<?xml version="1.0" encoding="utf-8" standalone="no"?>
<device schemaVersion="1.1">
  <name>STM32F437xx</name>
  <version>1.0</version>
  <description>STM32F437AIH6,STM32F437IGH6,STM32F437IGT6,STM32F437IIH6,STM32F437IIH7,STM32F437IIT6,STM32F437IIT7,STM32F437VGT6,STM32F437VGT7,STM32F437VIT6,STM32F437VIT7,STM32F437ZGT6,STM32F437ZIT6,STM32F437ZIT7</description>
  <addressUnitBits>8</addressUnitBits>
  <width>32</width>
  <size>0x20</size>
  <resetValue>0</resetValue>
  <resetMask>0xFFFFFFFF</resetMask>
  <peripherals>
    <peripheral>
      <name>TIM2</name>
      <baseAddress>0x40000000</baseAddress>
      <register>
        <name>CR1</name>
        <addressOffset>0x0</addressOffset>
        <size>0x20</size>
        <fields>
          <field>
            <name>CEN</name>
            <bitOffset>0</bitOffset>
            <bitWidth>1</bitWidth>
          </field>
          <field>
            <name>UDIS</name>
            <bitOffset>1</bitOffset>
            <bitWidth>1</bitWidth>
          </field>
          <field>
            <name>URS</name>
            <bitOffset>2</bitOffset>
            <bitWidth>1</bitWidth>
          </field>
          <field>
            <name>OPM</name>
            <bitOffset>3</bitOffset>
            <bitWidth>1</bitWidth>
          </field>
          <field>
            <name>DIR</name>
            <bitOffset>4</bitOffset>
            <bitWidth>1</bitWidth>
          </field>
          <field>
            <name>CMS</name>
            <bitOffset>5</bitOffset>
            <bitWidth>2</bitWidth>
          </field>
          <field>
            <name>ARPE</name>
            <bitOffset>7</bitOffset>
            <bitWidth>1</bitWidth>
          </field>
          <field>
            <name>CKD</name>
            <bitOffset>8</bitOffset>
            <bitWidth>2</bitWidth>
          </field>
        </fields>
      </register>
      <register>
        <name>CR2</name>
        <addressOffset>0x4</addressOffset>
        <size>0x20</size>
        <fields>
          <field>
            <name>CCPC</name>
            <bitOffset>0</bitOffset>
            <bitWidth>1</bitWidth>
          </field>
          <field>
            <name>CCUS</name>
            <bitOffset>2</bitOffset>
            <bitWidth>1</bitWidth>
          </field>
          <field>
            <name>CCDS</name>
            <bitOffset>3</bitOffset>
            <bitWidth>1</bitWidth>
          </field>
          <field>
            <name>MMS</name>
            <bitOffset>4</bitOffset>
            <bitWidth>3</bitWidth>
          </field>
          <field>
            <name>TI1S</name>
            <bitOffset>7</bitOffset>
            <bitWidth>1</bitWidth>
          </field>
          <field>
            <name>OIS1</name>
            <bitOffset>8</bitOffset>
            <bitWidth>1</bitWidth>
          </field>
          <field>
            <name>OIS1N</name>
            <bitOffset>9</bitOffset>
            <bitWidth>1</bitWidth>
          </field>
          <field>
            <name>OIS2</name>
            <bitOffset>10</bitOffset>
            <bitWidth>1</bitWidth>
          </field>
          <field>
            <name>OIS2N</name>
            <bitOffset>11</bitOffset>
            <bitWidth>1</bitWidth>
          </field>
          <field>
            <name>OIS3</name>
            <bitOffset>12</bitOffset>
            <bitWidth>1</bitWidth>
          </field>
          <field>
            <name>OIS3N</name>
            <bitOffset>13</bitOffset>
            <bitWidth>1</bitWidth>
          </field>
          <field>
            <name>OIS4</name>
            <bitOffset>14</bitOffset>
            <bitWidth>1</bitWidth>
          </field>
        </fields>
      </register>
      <register>
        <name>SMCR</name>
        <addressOffset>0x8</addressOffset>
        <size>0x20</size>
        <fields>
          <field>
            <name>SMS</name>
            <bitOffset>0</bitOffset>
            <bitWidth>3</bitWidth>
          </field>
          <field>
            <name>TS</name>
            <bitOffset>4</bitOffset>
            <bitWidth>3</bitWidth>
          </field>
          <field>
            <name>MSM</name>
            <bitOffset>7</bitOffset>
            <bitWidth>1</bitWidth>
          </field>
          <field>
            <name>ETF</name>
            <bitOffset>8</bitOffset>
            <bitWidth>4</bitWidth>
          </field>
          <field>
            <name>ETPS</name>
            <bitOffset>12</bitOffset>
            <bitWidth>2</bitWidth>
          </field>
          <field>
            <name>ECE</name>
            <bitOffset>14</bitOffset>
            <bitWidth>1</bitWidth>
          </field>
          <field>
            <name>ETP</name>
            <bitOffset>15</bitOffset>
            <bitWidth>1</bitWidth>
          </field>
        </fields>
      </register>
      <register>
        <name>DIER</name>
        <addressOffset>0xc</addressOffset>
        <size>0x20</size>
        <fields>
          <field>
            <name>UIE</name>
            <bitOffset>0</bitOffset>
            <bitWidth>1</bitWidth>
          </field>
          <field>
            <name>CC1IE</name>
            <bitOffset>1</bitOffset>
            <bitWidth>1</bitWidth>
          </field>
          <field>
            <name>CC2IE</name>
            <bitOffset>2</bitOffset>
            <bitWidth>1</bitWidth>
          </field>
          <field>
            <name>CC3IE</name>
            <bitOffset>3</bitOffset>
            <bitWidth>1</bitWidth>
          </field>
          <field>
            <name>CC4IE</name>
            <bitOffset>4</bitOffset>
            <bitWidth>1</bitWidth>
          </field>
          <field>
            <name>COMIE</name>
            <bitOffset>5</bitOffset>
            <bitWidth>1</bitWidth>
          </field>
          <field>
            <name>TIE</name>
            <bitOffset>6</bitOffset>
            <bitWidth>1</bitWidth>
          </field>
          <field>
            <name>BIE</name>
            <bitOffset>7</bitOffset>
            <bitWidth>1</bitWidth>
          </field>
          <field>
            <name>UDE</name>
            <bitOffset>8</bitOffset>
            <bitWidth>1</bitWidth>
          </field>
          <field>
            <name>CC1DE</name>
            <bitOffset>9</bitOffset>
            <bitWidth>1</bitWidth>
          </field>
          <field>
            <name>CC2DE</name>
            <bitOffset>10</bitOffset>
            <bitWidth>1</bitWidth>
          </field>
          <field>
            <name>CC3DE</name>
            <bitOffset>11</bitOffset>
            <bitWidth>1</bitWidth>
          </field>
          <field>
            <name>CC4DE</name>
            <bitOffset>12</bitOffset>
            <bitWidth>1</bitWidth>
          </field>
          <field>
            <name>COMDE</name>
            <bitOffset>13</bitOffset>
            <bitWidth>1</bitWidth>
          </field>
          <field>
            <name>TDE</name>
            <bitOffset>14</bitOffset>
            <bitWidth>1</bitWidth>
          </field>
        </fields>
      </register>
      <register>
        <name>SR</name>
        <addressOffset>0x10</addressOffset>
        <size>0x20</size>
        <fields>
          <field>
            <name>UIF</name>
            <bitOffset>0</bitOffset>
            <bitWidth>1</bitWidth>
          </field>
          <field>
            <name>CC1IF</name>
            <bitOffset>1</bitOffset>
            <bitWidth>1</bitWidth>
          </field>
          <field>
            <name>CC2IF</name>
            <bitOffset>2</bitOffset>
            <bitWidth>1</bitWidth>
          </field>
          <field>
            <name>CC3IF</name>
            <bitOffset>3</bitOffset>
            <bitWidth>1</bitWidth>
          </field>
          <field>
            <name>CC4IF</name>
            <bitOffset>4</bitOffset>
            <bitWidth>1</bitWidth>
          </field>
          <field>
            <name>COMIF</name>
            <bitOffset>5</bitOffset>
            <bitWidth>1</bitWidth>
          </field>
          <field>
            <name>TIF</name>
            <bitOffset>6</bitOffset>
            <bitWidth>1</bitWidth>
          </field>
          <field>
            <name>BIF</name>
            <bitOffset>7</bitOffset>
            <bitWidth>1</bitWidth>
          </field>
          <field>
            <name>CC1OF</name>
            <bitOffset>9</bitOffset>
            <bitWidth>1</bitWidth>
          </field>
          <field>
            <name>CC2OF</name>
            <bitOffset>10</bitOffset>
            <bitWidth>1</bitWidth>
          </field>
          <field>
            <name>CC3OF</name>
            <bitOffset>11</bitOffset>
            <bitWidth>1</bitWidth>
          </field>
          <field>
            <name>CC4OF</name>
            <bitOffset>12</bitOffset>
            <bitWidth>1</bitWidth>
          </field>
        </fields>
      </register>
      <register>
        <name>EGR</name>
        <addressOffset>0x14</addressOffset>
        <size>0x20</size>
        <fields>
          <field>
            <name>UG</name>
            <bitOffset>0</bitOffset>
            <bitWidth>1</bitWidth>
          </field>
          <field>
            <name>CC1G</name>
            <bitOffset>1</bitOffset>
            <bitWidth>1</bitWidth>
          </field>
          <field>
            <name>CC2G</name>
            <bitOffset>2</bitOffset>
            <bitWidth>1</bitWidth>
          </field>
          <field>
            <name>CC3G</name>
            <bitOffset>3</bitOffset>
            <bitWidth>1</bitWidth>
          </field>
          <field>
            <name>CC4G</name>
            <bitOffset>4</bitOffset>
            <bitWidth>1</bitWidth>
          </field>
          <field>
            <name>COMG</name>
            <bitOffset>5</bitOffset>
            <bitWidth>1</bitWidth>
          </field>
          <field>
            <name>TG</name>
            <bitOffset>6</bitOffset>
            <bitWidth>1</bitWidth>
          </field>
          <field>
            <name>BG</name>
            <bitOffset>7</bitOffset>
            <bitWidth>1</bitWidth>
          </field>
        </fields>
      </register>
      <register>
        <name>CCMR1</name>
        <addressOffset>0x18</addressOffset>
        <size>0x20</size>
        <fields>
          <field>
            <name>CC1S</name>
            <bitOffset>0</bitOffset>
            <bitWidth>2</bitWidth>
          </field>
          <field>
            <name>OC1FE</name>
            <bitOffset>2</bitOffset>
            <bitWidth>1</bitWidth>
          </field>
          <field>
            <name>OC1PE</name>
            <bitOffset>3</bitOffset>
            <bitWidth>1</bitWidth>
          </field>
          <field>
            <name>OC1M</name>
            <bitOffset>4</bitOffset>
            <bitWidth>3</bitWidth>
          </field>
          <field>
            <name>OC1CE</name>
            <bitOffset>7</bitOffset>
            <bitWidth>1</bitWidth>
          </field>
          <field>
            <name>CC2S</name>
            <bitOffset>8</bitOffset>
            <bitWidth>2</bitWidth>
          </field>
          <field>
            <name>OC2FE</name>
            <bitOffset>10</bitOffset>
            <bitWidth>1</bitWidth>
          </field>
          <field>
            <name>OC2PE</name>
            <bitOffset>11</bitOffset>
            <bitWidth>1</bitWidth>
          </field>
          <field>
            <name>OC2M</name>
            <bitOffset>12</bitOffset>
            <bitWidth>3</bitWidth>
          </field>
          <field>
            <name>OC2CE</name>
            <bitOffset>15</bitOffset>
            <bitWidth>1</bitWidth>
          </field>
        </fields>
      </register>
      <register>
        <name>CCMR2</name>
        <addressOffset>0x1c</addressOffset>
        <size>0x20</size>
        <fields>
          <field>
            <name>CC3S</name>
            <bitOffset>0</bitOffset>
            <bitWidth>2</bitWidth>
          </field>
          <field>
            <name>OC3FE</name>
            <bitOffset>2</bitOffset>
            <bitWidth>1</bitWidth>
          </field>
          <field>
            <name>OC3PE</name>
            <bitOffset>3</bitOffset>
            <bitWidth>1</bitWidth>
          </field>
          <field>
            <name>OC3M</name>
            <bitOffset>4</bitOffset>
            <bitWidth>3</bitWidth>
          </field>
          <field>
            <name>OC3CE</name>
            <bitOffset>7</bitOffset>
            <bitWidth>1</bitWidth>
          </field>
          <field>
            <name>CC4S</name>
            <bitOffset>8</bitOffset>
            <bitWidth>2</bitWidth>
          </field>
          <field>
            <name>OC4FE</name>
            <bitOffset>10</bitOffset>
            <bitWidth>1</bitWidth>
          </field>
          <field>
            <name>OC4PE</name>
            <bitOffset>11</bitOffset>
            <bitWidth>1</bitWidth>
          </field>
          <field>
            <name>OC4M</name>
            <bitOffset>12</bitOffset>
            <bitWidth>3</bitWidth>
          </field>
          <field>
            <name>OC4CE</name>
            <bitOffset>15</bitOffset>
            <bitWidth>1</bitWidth>
          </field>
        </fields>
      </register>
      <register>
        <name>CCER</name>
        <addressOffset>0x20</addressOffset>
        <size>0x20</size>
        <fields>
          <field>
            <name>CC1E</name>
            <bitOffset>0</bitOffset>
            <bitWidth>1</bitWidth>
          </field>
          <field>
            <name>CC1P</name>
            <bitOffset>1</bitOffset>
            <bitWidth>1</bitWidth>
          </field>
          <field>
            <name>CC1NE</name>
            <bitOffset>2</bitOffset>
            <bitWidth>1</bitWidth>
          </field>
          <field>
            <name>CC1NP</name>
            <bitOffset>3</bitOffset>
            <bitWidth>1</bitWidth>
          </field>
          <field>
            <name>CC2E</name>
            <bitOffset>4</bitOffset>
            <bitWidth>1</bitWidth>
          </field>
          <field>
            <name>CC2P</name>
            <bitOffset>5</bitOffset>
            <bitWidth>1</bitWidth>
          </field>
          <field>
            <name>CC2NE</name>
            <bitOffset>6</bitOffset>
            <bitWidth>1</bitWidth>
          </field>
          <field>
            <name>CC2NP</name>
            <bitOffset>7</bitOffset>
            <bitWidth>1</bitWidth>
          </field>
          <field>
            <name>CC3E</name>
            <bitOffset>8</bitOffset>
            <bitWidth>1</bitWidth>
          </field>
          <field>
            <name>CC3P</name>
            <bitOffset>9</bitOffset>
            <bitWidth>1</bitWidth>
          </field>
          <field>
            <name>CC3NE</name>
            <bitOffset>10</bitOffset>
            <bitWidth>1</bitWidth>
          </field>
          <field>
            <name>CC3NP</name>
            <bitOffset>11</bitOffset>
            <bitWidth>1</bitWidth>
          </field>
          <field>
            <name>CC4E</name>
            <bitOffset>12</bitOffset>
            <bitWidth>1</bitWidth>
          </field>
          <field>
            <name>CC4P</name>
            <bitOffset>13</bitOffset>
            <bitWidth>1</bitWidth>
          </field>
          <field>
            <name>CC4NP</name>
            <bitOffset>15</bitOffset>
            <bitWidth>1</bitWidth>
          </field>
        </fields>
      </register>
      <register>
        <name>CNT</name>
        <addressOffset>0x24</addressOffset>
        <size>0x20</size>
        <fields>
          <field>
            <name>CNT</name>
            <bitOffset>0</bitOffset>
            <bitWidth>32</bitWidth>
          </field>
        </fields>
      </register>
      <register>
        <name>PSC</name>
        <addressOffset>0x28</addressOffset>
        <size>0x20</size>
        <fields>
          <field>
            <name>PSC</name>
            <bitOffset>0</bitOffset>
            <bitWidth>16</bitWidth>
          </field>
        </fields>
      </register>
      <register>
        <name>ARR</name>
        <addressOffset>0x2c</addressOffset>
        <size>0x20</size>
        <fields>
          <field>
            <name>ARR</name>
            <bitOffset>0</bitOffset>
            <bitWidth>32</bitWidth>
          </field>
        </fields>
      </register>
      <register>
        <name>RCR</name>
        <addressOffset>0x30</addressOffset>
        <size>0x20</size>
        <fields>
          <field>
            <name>REP</name>
            <bitOffset>0</bitOffset>
            <bitWidth>8</bitWidth>
          </field>
        </fields>
      </register>
      <register>
        <name>CCR1</name>
        <addressOffset>0x34</addressOffset>
        <size>0x20</size>
        <fields>
          <field>
            <name>CCR1</name>
            <bitOffset>0</bitOffset>
            <bitWidth>16</bitWidth>
          </field>
        </fields>
      </register>
      <register>
        <name>CCR2</name>
        <addressOffset>0x38</addressOffset>
        <size>0x20</size>
        <fields>
          <field>
            <name>CCR2</name>
            <bitOffset>0</bitOffset>
            <bitWidth>16</bitWidth>
          </field>
        </fields>
      </register>
      <register>
        <name>CCR3</name>
        <addressOffset>0x3c</addressOffset>
        <size>0x20</size>
        <fields>
          <field>
            <name>CCR3</name>
            <bitOffset>0</bitOffset>
            <bitWidth>16</bitWidth>
          </field>
        </fields>
      </register>
      <register>
        <name>CCR4</name>
        <addressOffset>0x40</addressOffset>
        <size>0x20</size>
        <fields>
          <field>
            <name>CCR4</name>
            <bitOffset>0</bitOffset>
            <bitWidth>16</bitWidth>
          </field>
        </fields>
      </register>
      <register>
        <name>BDTR</name>
        <addressOffset>0x44</addressOffset>
        <size>0x20</size>
        <fields>
          <field>
            <name>DTG</name>
            <bitOffset>0</bitOffset>
            <bitWidth>8</bitWidth>
          </field>
          <field>
            <name>LOCK</name>
            <bitOffset>8</bitOffset>
            <bitWidth>2</bitWidth>
          </field>
          <field>
            <name>OSSI</name>
            <bitOffset>10</bitOffset>
            <bitWidth>1</bitWidth>
          </field>
          <field>
            <name>OSSR</name>
            <bitOffset>11</bitOffset>
            <bitWidth>1</bitWidth>
          </field>
          <field>
            <name>BKE</name>
            <bitOffset>12</bitOffset>
            <bitWidth>1</bitWidth>
          </field>
          <field>
            <name>BKP</name>
            <bitOffset>13</bitOffset>
            <bitWidth>1</bitWidth>
          </field>
          <field>
            <name>AOE</name>
            <bitOffset>14</bitOffset>
            <bitWidth>1</bitWidth>
          </field>
          <field>
            <name>MOE</name>
            <bitOffset>15</bitOffset>
            <bitWidth>1</bitWidth>
          </field>
        </fields>
      </register>
      <register>
        <name>DCR</name>
        <addressOffset>0x48</addressOffset>
        <size>0x20</size>
        <fields>
          <field>
            <name>DBA</name>
            <bitOffset>0</bitOffset>
            <bitWidth>5</bitWidth>
          </field>
          <field>
            <name>DBL</name>
            <bitOffset>8</bitOffset>
            <bitWidth>5</bitWidth>
          </field>
        </fields>
      </register>
      <register>
        <name>DMAR</name>
        <addressOffset>0x4c</addressOffset>
        <size>0x20</size>
        <fields>
          <field>
            <name>DMAB</name>
            <bitOffset>0</bitOffset>
            <bitWidth>16</bitWidth>
          </field>
        </fields>
      </register>
      <register>
        <name>OR</name>
        <addressOffset>0x50</addressOffset>
        <size>0x20</size>
        <fields>
          <field>
            <name>TI1_RMP</name>
            <bitOffset>0</bitOffset>
            <bitWidth>2</bitWidth>
          </field>
          <field>
            <name>TI4_RMP</name>
            <bitOffset>6</bitOffset>
            <bitWidth>2</bitWidth>
          </field>
          <field>
            <name>ITR1_RMP</name>
            <bitOffset>10</bitOffset>
            <bitWidth>2</bitWidth>
          </field>
        </fields>
      </register>
    </peripheral>
    <peripheral>
      <name>TIM3</name>
      <baseAddress>0x40000400</baseAddress>
      <register>
        <name>CR1</name>
        <addressOffset>0x0</addressOffset>
        <size>0x20</size>
        <fields>
          <field>
            <name>CEN</name>
            <bitOffset>0</bitOffset>
            <bitWidth>1</bitWidth>
          </field>
          <field>
            <name>UDIS</name>
            <bitOffset>1</bitOffset>
            <bitWidth>1</bitWidth>
          </field>
          <field>
            <name>URS</name>
            <bitOffset>2</bitOffset>
            <bitWidth>1</bitWidth>
          </field>
          <field>
            <name>OPM</name>
            <bitOffset>3</bitOffset>
            <bitWidth>1</bitWidth>
          </field>
          <field>
            <name>DIR</name>
            <bitOffset>4</bitOffset>
            <bitWidth>1</bitWidth>
          </field>
          <field>
            <name>CMS</name>
            <bitOffset>5</bitOffset>
            <bitWidth>2</bitWidth>
          </field>
          <field>
            <name>ARPE</name>
            <bitOffset>7</bitOffset>
            <bitWidth>1</bitWidth>
          </field>
          <field>
            <name>CKD</name>
            <bitOffset>8</bitOffset>
            <bitWidth>2</bitWidth>
          </field>
        </fields>
      </register>
      <register>
        <name>CR2</name>
        <addressOffset>0x4</addressOffset>
        <size>0x20</size>
        <fields>
          <field>
            <name>CCPC</name>
            <bitOffset>0</bitOffset>
            <bitWidth>1</bitWidth>
          </field>
          <field>
            <name>CCUS</name>
            <bitOffset>2</bitOffset>
            <bitWidth>1</bitWidth>
          </field>
          <field>
            <name>CCDS</name>
            <bitOffset>3</bitOffset>
            <bitWidth>1</bitWidth>
          </field>
          <field>
            <name>MMS</name>
            <bitOffset>4</bitOffset>
            <bitWidth>3</bitWidth>
          </field>
          <field>
            <name>TI1S</name>
            <bitOffset>7</bitOffset>
            <bitWidth>1</bitWidth>
          </field>
          <field>
            <name>OIS1</name>
            <bitOffset>8</bitOffset>
            <bitWidth>1</bitWidth>
          </field>
          <field>
            <name>OIS1N</name>
            <bitOffset>9</bitOffset>
            <bitWidth>1</bitWidth>
          </field>
          <field>
            <name>OIS2</name>
            <bitOffset>10</bitOffset>
            <bitWidth>1</bitWidth>
          </field>
          <field>
            <name>OIS2N</name>
            <bitOffset>11</bitOffset>
            <bitWidth>1</bitWidth>
          </field>
          <field>
            <name>OIS3</name>
            <bitOffset>12</bitOffset>
            <bitWidth>1</bitWidth>
          </field>
          <field>
            <name>OIS3N</name>
            <bitOffset>13</bitOffset>
            <bitWidth>1</bitWidth>
          </field>
          <field>
            <name>OIS4</name>
            <bitOffset>14</bitOffset>
            <bitWidth>1</bitWidth>
          </field>
        </fields>
      </register>
      <register>
        <name>SMCR</name>
        <addressOffset>0x8</addressOffset>
        <size>0x20</size>
        <fields>
          <field>
            <name>SMS</name>
            <bitOffset>0</bitOffset>
            <bitWidth>3</bitWidth>
          </field>
          <field>
            <name>TS</name>
            <bitOffset>4</bitOffset>
            <bitWidth>3</bitWidth>
          </field>
          <field>
            <name>MSM</name>
            <bitOffset>7</bitOffset>
            <bitWidth>1</bitWidth>
          </field>
          <field>
            <name>ETF</name>
            <bitOffset>8</bitOffset>
            <bitWidth>4</bitWidth>
          </field>
          <field>
            <name>ETPS</name>
            <bitOffset>12</bitOffset>
            <bitWidth>2</bitWidth>
          </field>
          <field>
            <name>ECE</name>
            <bitOffset>14</bitOffset>
            <bitWidth>1</bitWidth>
          </field>
          <field>
            <name>ETP</name>
            <bitOffset>15</bitOffset>
            <bitWidth>1</bitWidth>
          </field>
        </fields>
      </register>
      <register>
        <name>DIER</name>
        <addressOffset>0xc</addressOffset>
        <size>0x20</size>
        <fields>
          <field>
            <name>UIE</name>
            <bitOffset>0</bitOffset>
            <bitWidth>1</bitWidth>
          </field>
          <field>
            <name>CC1IE</name>
            <bitOffset>1</bitOffset>
            <bitWidth>1</bitWidth>
          </field>
          <field>
            <name>CC2IE</name>
            <bitOffset>2</bitOffset>
            <bitWidth>1</bitWidth>
          </field>
          <field>
            <name>CC3IE</name>
            <bitOffset>3</bitOffset>
            <bitWidth>1</bitWidth>
          </field>
          <field>
            <name>CC4IE</name>
            <bitOffset>4</bitOffset>
            <bitWidth>1</bitWidth>
          </field>
          <field>
            <name>COMIE</name>
            <bitOffset>5</bitOffset>
            <bitWidth>1</bitWidth>
          </field>
          <field>
            <name>TIE</name>
            <bitOffset>6</bitOffset>
            <bitWidth>1</bitWidth>
          </field>
          <field>
            <name>BIE</name>
            <bitOffset>7</bitOffset>
            <bitWidth>1</bitWidth>
          </field>
          <field>
            <name>UDE</name>
            <bitOffset>8</bitOffset>
            <bitWidth>1</bitWidth>
          </field>
          <field>
            <name>CC1DE</name>
            <bitOffset>9</bitOffset>
            <bitWidth>1</bitWidth>
          </field>
          <field>
            <name>CC2DE</name>
            <bitOffset>10</bitOffset>
            <bitWidth>1</bitWidth>
          </field>
          <field>
            <name>CC3DE</name>
            <bitOffset>11</bitOffset>
            <bitWidth>1</bitWidth>
          </field>
          <field>
            <name>CC4DE</name>
            <bitOffset>12</bitOffset>
            <bitWidth>1</bitWidth>
          </field>
          <field>
            <name>COMDE</name>
            <bitOffset>13</bitOffset>
            <bitWidth>1</bitWidth>
          </field>
          <field>
            <name>TDE</name>
            <bitOffset>14</bitOffset>
            <bitWidth>1</bitWidth>
          </field>
        </fields>
      </register>
      <register>
        <name>SR</name>
        <addressOffset>0x10</addressOffset>
        <size>0x20</size>
        <fields>
          <field>
            <name>UIF</name>
            <bitOffset>0</bitOffset>
            <bitWidth>1</bitWidth>
          </field>
          <field>
            <name>CC1IF</name>
            <bitOffset>1</bitOffset>
            <bitWidth>1</bitWidth>
          </field>
          <field>
            <name>CC2IF</name>
            <bitOffset>2</bitOffset>
            <bitWidth>1</bitWidth>
          </field>
          <field>
            <name>CC3IF</name>
            <bitOffset>3</bitOffset>
            <bitWidth>1</bitWidth>
          </field>
          <field>
            <name>CC4IF</name>
            <bitOffset>4</bitOffset>
            <bitWidth>1</bitWidth>
          </field>
          <field>
            <name>COMIF</name>
            <bitOffset>5</bitOffset>
            <bitWidth>1</bitWidth>
          </field>
          <field>
            <name>TIF</name>
            <bitOffset>6</bitOffset>
            <bitWidth>1</bitWidth>
          </field>
          <field>
            <name>BIF</name>
            <bitOffset>7</bitOffset>
            <bitWidth>1</bitWidth>
          </field>
          <field>
            <name>CC1OF</name>
            <bitOffset>9</bitOffset>
            <bitWidth>1</bitWidth>
          </field>
          <field>
            <name>CC2OF</name>
            <bitOffset>10</bitOffset>
            <bitWidth>1</bitWidth>
          </field>
          <field>
            <name>CC3OF</name>
            <bitOffset>11</bitOffset>
            <bitWidth>1</bitWidth>
          </field>
          <field>
            <name>CC4OF</name>
            <bitOffset>12</bitOffset>
            <bitWidth>1</bitWidth>
          </field>
        </fields>
      </register>
      <register>
        <name>EGR</name>
        <addressOffset>0x14</addressOffset>
        <size>0x20</size>
        <fields>
          <field>
            <name>UG</name>
            <bitOffset>0</bitOffset>
            <bitWidth>1</bitWidth>
          </field>
          <field>
            <name>CC1G</name>
            <bitOffset>1</bitOffset>
            <bitWidth>1</bitWidth>
          </field>
          <field>
            <name>CC2G</name>
            <bitOffset>2</bitOffset>
            <bitWidth>1</bitWidth>
          </field>
          <field>
            <name>CC3G</name>
            <bitOffset>3</bitOffset>
            <bitWidth>1</bitWidth>
          </field>
          <field>
            <name>CC4G</name>
            <bitOffset>4</bitOffset>
            <bitWidth>1</bitWidth>
          </field>
          <field>
            <name>COMG</name>
            <bitOffset>5</bitOffset>
            <bitWidth>1</bitWidth>
          </field>
          <field>
            <name>TG</name>
            <bitOffset>6</bitOffset>
            <bitWidth>1</bitWidth>
          </field>
          <field>
            <name>BG</name>
            <bitOffset>7</bitOffset>
            <bitWidth>1</bitWidth>
          </field>
        </fields>
      </register>
      <register>
        <name>CCMR1</name>
        <addressOffset>0x18</addressOffset>
        <size>0x20</size>
        <fields>
          <field>
            <name>CC1S</name>
            <bitOffset>0</bitOffset>
            <bitWidth>2</bitWidth>
          </field>
          <field>
            <name>OC1FE</name>
            <bitOffset>2</bitOffset>
            <bitWidth>1</bitWidth>
          </field>
          <field>
            <name>OC1PE</name>
            <bitOffset>3</bitOffset>
            <bitWidth>1</bitWidth>
          </field>
          <field>
            <name>OC1M</name>
            <bitOffset>4</bitOffset>
            <bitWidth>3</bitWidth>
          </field>
          <field>
            <name>OC1CE</name>
            <bitOffset>7</bitOffset>
            <bitWidth>1</bitWidth>
          </field>
          <field>
            <name>CC2S</name>
            <bitOffset>8</bitOffset>
            <bitWidth>2</bitWidth>
          </field>
          <field>
            <name>OC2FE</name>
            <bitOffset>10</bitOffset>
            <bitWidth>1</bitWidth>
          </field>
          <field>
            <name>OC2PE</name>
            <bitOffset>11</bitOffset>
            <bitWidth>1</bitWidth>
          </field>
          <field>
            <name>OC2M</name>
            <bitOffset>12</bitOffset>
            <bitWidth>3</bitWidth>
          </field>
          <field>
            <name>OC2CE</name>
            <bitOffset>15</bitOffset>
            <bitWidth>1</bitWidth>
          </field>
        </fields>
      </register>
      <register>
        <name>CCMR2</name>
        <addressOffset>0x1c</addressOffset>
        <size>0x20</size>
        <fields>
          <field>
            <name>CC3S</name>
            <bitOffset>0</bitOffset>
            <bitWidth>2</bitWidth>
          </field>
          <field>
            <name>OC3FE</name>
            <bitOffset>2</bitOffset>
            <bitWidth>1</bitWidth>
          </field>
          <field>
            <name>OC3PE</name>
            <bitOffset>3</bitOffset>
            <bitWidth>1</bitWidth>
          </field>
          <field>
            <name>OC3M</name>
            <bitOffset>4</bitOffset>
            <bitWidth>3</bitWidth>
          </field>
          <field>
            <name>OC3CE</name>
            <bitOffset>7</bitOffset>
            <bitWidth>1</bitWidth>
          </field>
          <field>
            <name>CC4S</name>
            <bitOffset>8</bitOffset>
            <bitWidth>2</bitWidth>
          </field>
          <field>
            <name>OC4FE</name>
            <bitOffset>10</bitOffset>
            <bitWidth>1</bitWidth>
          </field>
          <field>
            <name>OC4PE</name>
            <bitOffset>11</bitOffset>
            <bitWidth>1</bitWidth>
          </field>
          <field>
            <name>OC4M</name>
            <bitOffset>12</bitOffset>
            <bitWidth>3</bitWidth>
          </field>
          <field>
            <name>OC4CE</name>
            <bitOffset>15</bitOffset>
            <bitWidth>1</bitWidth>
          </field>
        </fields>
      </register>
      <register>
        <name>CCER</name>
        <addressOffset>0x20</addressOffset>
        <size>0x20</size>
        <fields>
          <field>
            <name>CC1E</name>
            <bitOffset>0</bitOffset>
            <bitWidth>1</bitWidth>
          </field>
          <field>
            <name>CC1P</name>
            <bitOffset>1</bitOffset>
            <bitWidth>1</bitWidth>
          </field>
          <field>
            <name>CC1NE</name>
            <bitOffset>2</bitOffset>
            <bitWidth>1</bitWidth>
          </field>
          <field>
            <name>CC1NP</name>
            <bitOffset>3</bitOffset>
            <bitWidth>1</bitWidth>
          </field>
          <field>
            <name>CC2E</name>
            <bitOffset>4</bitOffset>
            <bitWidth>1</bitWidth>
          </field>
          <field>
            <name>CC2P</name>
            <bitOffset>5</bitOffset>
            <bitWidth>1</bitWidth>
          </field>
          <field>
            <name>CC2NE</name>
            <bitOffset>6</bitOffset>
            <bitWidth>1</bitWidth>
          </field>
          <field>
            <name>CC2NP</name>
            <bitOffset>7</bitOffset>
            <bitWidth>1</bitWidth>
          </field>
          <field>
            <name>CC3E</name>
            <bitOffset>8</bitOffset>
            <bitWidth>1</bitWidth>
          </field>
          <field>
            <name>CC3P</name>
            <bitOffset>9</bitOffset>
            <bitWidth>1</bitWidth>
          </field>
          <field>
            <name>CC3NE</name>
            <bitOffset>10</bitOffset>
            <bitWidth>1</bitWidth>
          </field>
          <field>
            <name>CC3NP</name>
            <bitOffset>11</bitOffset>
            <bitWidth>1</bitWidth>
          </field>
          <field>
            <name>CC4E</name>
            <bitOffset>12</bitOffset>
            <bitWidth>1</bitWidth>
          </field>
          <field>
            <name>CC4P</name>
            <bitOffset>13</bitOffset>
            <bitWidth>1</bitWidth>
          </field>
          <field>
            <name>CC4NP</name>
            <bitOffset>15</bitOffset>
            <bitWidth>1</bitWidth>
          </field>
        </fields>
      </register>
      <register>
        <name>CNT</name>
        <addressOffset>0x24</addressOffset>
        <size>0x20</size>
        <fields>
          <field>
            <name>CNT</name>
            <bitOffset>0</bitOffset>
            <bitWidth>32</bitWidth>
          </field>
        </fields>
      </register>
      <register>
        <name>PSC</name>
        <addressOffset>0x28</addressOffset>
        <size>0x20</size>
        <fields>
          <field>
            <name>PSC</name>
            <bitOffset>0</bitOffset>
            <bitWidth>16</bitWidth>
          </field>
        </fields>
      </register>
      <register>
        <name>ARR</name>
        <addressOffset>0x2c</addressOffset>
        <size>0x20</size>
        <fields>
          <field>
            <name>ARR</name>
            <bitOffset>0</bitOffset>
            <bitWidth>32</bitWidth>
          </field>
        </fields>
      </register>
      <register>
        <name>RCR</name>
        <addressOffset>0x30</addressOffset>
        <size>0x20</size>
        <fields>
          <field>
            <name>REP</name>
            <bitOffset>0</bitOffset>
            <bitWidth>8</bitWidth>
          </field>
        </fields>
      </register>
      <register>
        <name>CCR1</name>
        <addressOffset>0x34</addressOffset>
        <size>0x20</size>
        <fields>
          <field>
            <name>CCR1</name>
            <bitOffset>0</bitOffset>
            <bitWidth>16</bitWidth>
          </field>
        </fields>
      </register>
      <register>
        <name>CCR2</name>
        <addressOffset>0x38</addressOffset>
        <size>0x20</size>
        <fields>
          <field>
            <name>CCR2</name>
            <bitOffset>0</bitOffset>
            <bitWidth>16</bitWidth>
          </field>
        </fields>
      </register>
      <register>
        <name>CCR3</name>
        <addressOffset>0x3c</addressOffset>
        <size>0x20</size>
        <fields>
          <field>
            <name>CCR3</name>
            <bitOffset>0</bitOffset>
            <bitWidth>16</bitWidth>
          </field>
        </fields>
      </register>
      <register>
        <name>CCR4</name>
        <addressOffset>0x40</addressOffset>
        <size>0x20</size>
        <fields>
          <field>
            <name>CCR4</name>
            <bitOffset>0</bitOffset>
            <bitWidth>16</bitWidth>
          </field>
        </fields>
      </register>
      <register>
        <name>BDTR</name>
        <addressOffset>0x44</addressOffset>
        <size>0x20</size>
        <fields>
          <field>
            <name>DTG</name>
            <bitOffset>0</bitOffset>
            <bitWidth>8</bitWidth>
          </field>
          <field>
            <name>LOCK</name>
            <bitOffset>8</bitOffset>
            <bitWidth>2</bitWidth>
          </field>
          <field>
            <name>OSSI</name>
            <bitOffset>10</bitOffset>
            <bitWidth>1</bitWidth>
          </field>
          <field>
            <name>OSSR</name>
            <bitOffset>11</bitOffset>
            <bitWidth>1</bitWidth>
          </field>
          <field>
            <name>BKE</name>
            <bitOffset>12</bitOffset>
            <bitWidth>1</bitWidth>
          </field>
          <field>
            <name>BKP</name>
            <bitOffset>13</bitOffset>
            <bitWidth>1</bitWidth>
          </field>
          <field>
            <name>AOE</name>
            <bitOffset>14</bitOffset>
            <bitWidth>1</bitWidth>
          </field>
          <field>
            <name>MOE</name>
            <bitOffset>15</bitOffset>
            <bitWidth>1</bitWidth>
          </field>
        </fields>
      </register>
      <register>
        <name>DCR</name>
        <addressOffset>0x48</addressOffset>
        <size>0x20</size>
        <fields>
          <field>
            <name>DBA</name>
            <bitOffset>0</bitOffset>
            <bitWidth>5</bitWidth>
          </field>
          <field>
            <name>DBL</name>
            <bitOffset>8</bitOffset>
            <bitWidth>5</bitWidth>
          </field>
        </fields>
      </register>
      <register>
        <name>DMAR</name>
        <addressOffset>0x4c</addressOffset>
        <size>0x20</size>
        <fields>
          <field>
            <name>DMAB</name>
            <bitOffset>0</bitOffset>
            <bitWidth>16</bitWidth>
          </field>
        </fields>
      </register>
      <register>
        <name>OR</name>
        <addressOffset>0x50</addressOffset>
        <size>0x20</size>
        <fields>
          <field>
            <name>TI1_RMP</name>
            <bitOffset>0</bitOffset>
            <bitWidth>2</bitWidth>
          </field>
          <field>
            <name>TI4_RMP</name>
            <bitOffset>6</bitOffset>
            <bitWidth>2</bitWidth>
          </field>
          <field>
            <name>ITR1_RMP</name>
            <bitOffset>10</bitOffset>
            <bitWidth>2</bitWidth>
          </field>
        </fields>
      </register>
    </peripheral>
    <peripheral>
      <name>TIM4</name>
      <baseAddress>0x40000800</baseAddress>
      <register>
        <name>CR1</name>
        <addressOffset>0x0</addressOffset>
        <size>0x20</size>
        <fields>
          <field>
            <name>CEN</name>
            <bitOffset>0</bitOffset>
            <bitWidth>1</bitWidth>
          </field>
          <field>
            <name>UDIS</name>
            <bitOffset>1</bitOffset>
            <bitWidth>1</bitWidth>
          </field>
          <field>
            <name>URS</name>
            <bitOffset>2</bitOffset>
            <bitWidth>1</bitWidth>
          </field>
          <field>
            <name>OPM</name>
            <bitOffset>3</bitOffset>
            <bitWidth>1</bitWidth>
          </field>
          <field>
            <name>DIR</name>
            <bitOffset>4</bitOffset>
            <bitWidth>1</bitWidth>
          </field>
          <field>
            <name>CMS</name>
            <bitOffset>5</bitOffset>
            <bitWidth>2</bitWidth>
          </field>
          <field>
            <name>ARPE</name>
            <bitOffset>7</bitOffset>
            <bitWidth>1</bitWidth>
          </field>
          <field>
            <name>CKD</name>
            <bitOffset>8</bitOffset>
            <bitWidth>2</bitWidth>
          </field>
        </fields>
      </register>
      <register>
        <name>CR2</name>
        <addressOffset>0x4</addressOffset>
        <size>0x20</size>
        <fields>
          <field>
            <name>CCPC</name>
            <bitOffset>0</bitOffset>
            <bitWidth>1</bitWidth>
          </field>
          <field>
            <name>CCUS</name>
            <bitOffset>2</bitOffset>
            <bitWidth>1</bitWidth>
          </field>
          <field>
            <name>CCDS</name>
            <bitOffset>3</bitOffset>
            <bitWidth>1</bitWidth>
          </field>
          <field>
            <name>MMS</name>
            <bitOffset>4</bitOffset>
            <bitWidth>3</bitWidth>
          </field>
          <field>
            <name>TI1S</name>
            <bitOffset>7</bitOffset>
            <bitWidth>1</bitWidth>
          </field>
          <field>
            <name>OIS1</name>
            <bitOffset>8</bitOffset>
            <bitWidth>1</bitWidth>
          </field>
          <field>
            <name>OIS1N</name>
            <bitOffset>9</bitOffset>
            <bitWidth>1</bitWidth>
          </field>
          <field>
            <name>OIS2</name>
            <bitOffset>10</bitOffset>
            <bitWidth>1</bitWidth>
          </field>
          <field>
            <name>OIS2N</name>
            <bitOffset>11</bitOffset>
            <bitWidth>1</bitWidth>
          </field>
          <field>
            <name>OIS3</name>
            <bitOffset>12</bitOffset>
            <bitWidth>1</bitWidth>
          </field>
          <field>
            <name>OIS3N</name>
            <bitOffset>13</bitOffset>
            <bitWidth>1</bitWidth>
          </field>
          <field>
            <name>OIS4</name>
            <bitOffset>14</bitOffset>
            <bitWidth>1</bitWidth>
          </field>
        </fields>
      </register>
      <register>
        <name>SMCR</name>
        <addressOffset>0x8</addressOffset>
        <size>0x20</size>
        <fields>
          <field>
            <name>SMS</name>
            <bitOffset>0</bitOffset>
            <bitWidth>3</bitWidth>
          </field>
          <field>
            <name>TS</name>
            <bitOffset>4</bitOffset>
            <bitWidth>3</bitWidth>
          </field>
          <field>
            <name>MSM</name>
            <bitOffset>7</bitOffset>
            <bitWidth>1</bitWidth>
          </field>
          <field>
            <name>ETF</name>
            <bitOffset>8</bitOffset>
            <bitWidth>4</bitWidth>
          </field>
          <field>
            <name>ETPS</name>
            <bitOffset>12</bitOffset>
            <bitWidth>2</bitWidth>
          </field>
          <field>
            <name>ECE</name>
            <bitOffset>14</bitOffset>
            <bitWidth>1</bitWidth>
          </field>
          <field>
            <name>ETP</name>
            <bitOffset>15</bitOffset>
            <bitWidth>1</bitWidth>
          </field>
        </fields>
      </register>
      <register>
        <name>DIER</name>
        <addressOffset>0xc</addressOffset>
        <size>0x20</size>
        <fields>
          <field>
            <name>UIE</name>
            <bitOffset>0</bitOffset>
            <bitWidth>1</bitWidth>
          </field>
          <field>
            <name>CC1IE</name>
            <bitOffset>1</bitOffset>
            <bitWidth>1</bitWidth>
          </field>
          <field>
            <name>CC2IE</name>
            <bitOffset>2</bitOffset>
            <bitWidth>1</bitWidth>
          </field>
          <field>
            <name>CC3IE</name>
            <bitOffset>3</bitOffset>
            <bitWidth>1</bitWidth>
          </field>
          <field>
            <name>CC4IE</name>
            <bitOffset>4</bitOffset>
            <bitWidth>1</bitWidth>
          </field>
          <field>
            <name>COMIE</name>
            <bitOffset>5</bitOffset>
            <bitWidth>1</bitWidth>
          </field>
          <field>
            <name>TIE</name>
            <bitOffset>6</bitOffset>
            <bitWidth>1</bitWidth>
          </field>
          <field>
            <name>BIE</name>
            <bitOffset>7</bitOffset>
            <bitWidth>1</bitWidth>
          </field>
          <field>
            <name>UDE</name>
            <bitOffset>8</bitOffset>
            <bitWidth>1</bitWidth>
          </field>
          <field>
            <name>CC1DE</name>
            <bitOffset>9</bitOffset>
            <bitWidth>1</bitWidth>
          </field>
          <field>
            <name>CC2DE</name>
            <bitOffset>10</bitOffset>
            <bitWidth>1</bitWidth>
          </field>
          <field>
            <name>CC3DE</name>
            <bitOffset>11</bitOffset>
            <bitWidth>1</bitWidth>
          </field>
          <field>
            <name>CC4DE</name>
            <bitOffset>12</bitOffset>
            <bitWidth>1</bitWidth>
          </field>
          <field>
            <name>COMDE</name>
            <bitOffset>13</bitOffset>
            <bitWidth>1</bitWidth>
          </field>
          <field>
            <name>TDE</name>
            <bitOffset>14</bitOffset>
            <bitWidth>1</bitWidth>
          </field>
        </fields>
      </register>
      <register>
        <name>SR</name>
        <addressOffset>0x10</addressOffset>
        <size>0x20</size>
        <fields>
          <field>
            <name>UIF</name>
            <bitOffset>0</bitOffset>
            <bitWidth>1</bitWidth>
          </field>
          <field>
            <name>CC1IF</name>
            <bitOffset>1</bitOffset>
            <bitWidth>1</bitWidth>
          </field>
          <field>
            <name>CC2IF</name>
            <bitOffset>2</bitOffset>
            <bitWidth>1</bitWidth>
          </field>
          <field>
            <name>CC3IF</name>
            <bitOffset>3</bitOffset>
            <bitWidth>1</bitWidth>
          </field>
          <field>
            <name>CC4IF</name>
            <bitOffset>4</bitOffset>
            <bitWidth>1</bitWidth>
          </field>
          <field>
            <name>COMIF</name>
            <bitOffset>5</bitOffset>
            <bitWidth>1</bitWidth>
          </field>
          <field>
            <name>TIF</name>
            <bitOffset>6</bitOffset>
            <bitWidth>1</bitWidth>
          </field>
          <field>
            <name>BIF</name>
            <bitOffset>7</bitOffset>
            <bitWidth>1</bitWidth>
          </field>
          <field>
            <name>CC1OF</name>
            <bitOffset>9</bitOffset>
            <bitWidth>1</bitWidth>
          </field>
          <field>
            <name>CC2OF</name>
            <bitOffset>10</bitOffset>
            <bitWidth>1</bitWidth>
          </field>
          <field>
            <name>CC3OF</name>
            <bitOffset>11</bitOffset>
            <bitWidth>1</bitWidth>
          </field>
          <field>
            <name>CC4OF</name>
            <bitOffset>12</bitOffset>
            <bitWidth>1</bitWidth>
          </field>
        </fields>
      </register>
      <register>
        <name>EGR</name>
        <addressOffset>0x14</addressOffset>
        <size>0x20</size>
        <fields>
          <field>
            <name>UG</name>
            <bitOffset>0</bitOffset>
            <bitWidth>1</bitWidth>
          </field>
          <field>
            <name>CC1G</name>
            <bitOffset>1</bitOffset>
            <bitWidth>1</bitWidth>
          </field>
          <field>
            <name>CC2G</name>
            <bitOffset>2</bitOffset>
            <bitWidth>1</bitWidth>
          </field>
          <field>
            <name>CC3G</name>
            <bitOffset>3</bitOffset>
            <bitWidth>1</bitWidth>
          </field>
          <field>
            <name>CC4G</name>
            <bitOffset>4</bitOffset>
            <bitWidth>1</bitWidth>
          </field>
          <field>
            <name>COMG</name>
            <bitOffset>5</bitOffset>
            <bitWidth>1</bitWidth>
          </field>
          <field>
            <name>TG</name>
            <bitOffset>6</bitOffset>
            <bitWidth>1</bitWidth>
          </field>
          <field>
            <name>BG</name>
            <bitOffset>7</bitOffset>
            <bitWidth>1</bitWidth>
          </field>
        </fields>
      </register>
      <register>
        <name>CCMR1</name>
        <addressOffset>0x18</addressOffset>
        <size>0x20</size>
        <fields>
          <field>
            <name>CC1S</name>
            <bitOffset>0</bitOffset>
            <bitWidth>2</bitWidth>
          </field>
          <field>
            <name>OC1FE</name>
            <bitOffset>2</bitOffset>
            <bitWidth>1</bitWidth>
          </field>
          <field>
            <name>OC1PE</name>
            <bitOffset>3</bitOffset>
            <bitWidth>1</bitWidth>
          </field>
          <field>
            <name>OC1M</name>
            <bitOffset>4</bitOffset>
            <bitWidth>3</bitWidth>
          </field>
          <field>
            <name>OC1CE</name>
            <bitOffset>7</bitOffset>
            <bitWidth>1</bitWidth>
          </field>
          <field>
            <name>CC2S</name>
            <bitOffset>8</bitOffset>
            <bitWidth>2</bitWidth>
          </field>
          <field>
            <name>OC2FE</name>
            <bitOffset>10</bitOffset>
            <bitWidth>1</bitWidth>
          </field>
          <field>
            <name>OC2PE</name>
            <bitOffset>11</bitOffset>
            <bitWidth>1</bitWidth>
          </field>
          <field>
            <name>OC2M</name>
            <bitOffset>12</bitOffset>
            <bitWidth>3</bitWidth>
          </field>
          <field>
            <name>OC2CE</name>
            <bitOffset>15</bitOffset>
            <bitWidth>1</bitWidth>
          </field>
        </fields>
      </register>
      <register>
        <name>CCMR2</name>
        <addressOffset>0x1c</addressOffset>
        <size>0x20</size>
        <fields>
          <field>
            <name>CC3S</name>
            <bitOffset>0</bitOffset>
            <bitWidth>2</bitWidth>
          </field>
          <field>
            <name>OC3FE</name>
            <bitOffset>2</bitOffset>
            <bitWidth>1</bitWidth>
          </field>
          <field>
            <name>OC3PE</name>
            <bitOffset>3</bitOffset>
            <bitWidth>1</bitWidth>
          </field>
          <field>
            <name>OC3M</name>
            <bitOffset>4</bitOffset>
            <bitWidth>3</bitWidth>
          </field>
          <field>
            <name>OC3CE</name>
            <bitOffset>7</bitOffset>
            <bitWidth>1</bitWidth>
          </field>
          <field>
            <name>CC4S</name>
            <bitOffset>8</bitOffset>
            <bitWidth>2</bitWidth>
          </field>
          <field>
            <name>OC4FE</name>
            <bitOffset>10</bitOffset>
            <bitWidth>1</bitWidth>
          </field>
          <field>
            <name>OC4PE</name>
            <bitOffset>11</bitOffset>
            <bitWidth>1</bitWidth>
          </field>
          <field>
            <name>OC4M</name>
            <bitOffset>12</bitOffset>
            <bitWidth>3</bitWidth>
          </field>
          <field>
            <name>OC4CE</name>
            <bitOffset>15</bitOffset>
            <bitWidth>1</bitWidth>
          </field>
        </fields>
      </register>
      <register>
        <name>CCER</name>
        <addressOffset>0x20</addressOffset>
        <size>0x20</size>
        <fields>
          <field>
            <name>CC1E</name>
            <bitOffset>0</bitOffset>
            <bitWidth>1</bitWidth>
          </field>
          <field>
            <name>CC1P</name>
            <bitOffset>1</bitOffset>
            <bitWidth>1</bitWidth>
          </field>
          <field>
            <name>CC1NE</name>
            <bitOffset>2</bitOffset>
            <bitWidth>1</bitWidth>
          </field>
          <field>
            <name>CC1NP</name>
            <bitOffset>3</bitOffset>
            <bitWidth>1</bitWidth>
          </field>
          <field>
            <name>CC2E</name>
            <bitOffset>4</bitOffset>
            <bitWidth>1</bitWidth>
          </field>
          <field>
            <name>CC2P</name>
            <bitOffset>5</bitOffset>
            <bitWidth>1</bitWidth>
          </field>
          <field>
            <name>CC2NE</name>
            <bitOffset>6</bitOffset>
            <bitWidth>1</bitWidth>
          </field>
          <field>
            <name>CC2NP</name>
            <bitOffset>7</bitOffset>
            <bitWidth>1</bitWidth>
          </field>
          <field>
            <name>CC3E</name>
            <bitOffset>8</bitOffset>
            <bitWidth>1</bitWidth>
          </field>
          <field>
            <name>CC3P</name>
            <bitOffset>9</bitOffset>
            <bitWidth>1</bitWidth>
          </field>
          <field>
            <name>CC3NE</name>
            <bitOffset>10</bitOffset>
            <bitWidth>1</bitWidth>
          </field>
          <field>
            <name>CC3NP</name>
            <bitOffset>11</bitOffset>
            <bitWidth>1</bitWidth>
          </field>
          <field>
            <name>CC4E</name>
            <bitOffset>12</bitOffset>
            <bitWidth>1</bitWidth>
          </field>
          <field>
            <name>CC4P</name>
            <bitOffset>13</bitOffset>
            <bitWidth>1</bitWidth>
          </field>
          <field>
            <name>CC4NP</name>
            <bitOffset>15</bitOffset>
            <bitWidth>1</bitWidth>
          </field>
        </fields>
      </register>
      <register>
        <name>CNT</name>
        <addressOffset>0x24</addressOffset>
        <size>0x20</size>
        <fields>
          <field>
            <name>CNT</name>
            <bitOffset>0</bitOffset>
            <bitWidth>32</bitWidth>
          </field>
        </fields>
      </register>
      <register>
        <name>PSC</name>
        <addressOffset>0x28</addressOffset>
        <size>0x20</size>
        <fields>
          <field>
            <name>PSC</name>
            <bitOffset>0</bitOffset>
            <bitWidth>16</bitWidth>
          </field>
        </fields>
      </register>
      <register>
        <name>ARR</name>
        <addressOffset>0x2c</addressOffset>
        <size>0x20</size>
        <fields>
          <field>
            <name>ARR</name>
            <bitOffset>0</bitOffset>
            <bitWidth>32</bitWidth>
          </field>
        </fields>
      </register>
      <register>
        <name>RCR</name>
        <addressOffset>0x30</addressOffset>
        <size>0x20</size>
        <fields>
          <field>
            <name>REP</name>
            <bitOffset>0</bitOffset>
            <bitWidth>8</bitWidth>
          </field>
        </fields>
      </register>
      <register>
        <name>CCR1</name>
        <addressOffset>0x34</addressOffset>
        <size>0x20</size>
        <fields>
          <field>
            <name>CCR1</name>
            <bitOffset>0</bitOffset>
            <bitWidth>16</bitWidth>
          </field>
        </fields>
      </register>
      <register>
        <name>CCR2</name>
        <addressOffset>0x38</addressOffset>
        <size>0x20</size>
        <fields>
          <field>
            <name>CCR2</name>
            <bitOffset>0</bitOffset>
            <bitWidth>16</bitWidth>
          </field>
        </fields>
      </register>
      <register>
        <name>CCR3</name>
        <addressOffset>0x3c</addressOffset>
        <size>0x20</size>
        <fields>
          <field>
            <name>CCR3</name>
            <bitOffset>0</bitOffset>
            <bitWidth>16</bitWidth>
          </field>
        </fields>
      </register>
      <register>
        <name>CCR4</name>
        <addressOffset>0x40</addressOffset>
        <size>0x20</size>
        <fields>
          <field>
            <name>CCR4</name>
            <bitOffset>0</bitOffset>
            <bitWidth>16</bitWidth>
          </field>
        </fields>
      </register>
      <register>
        <name>BDTR</name>
        <addressOffset>0x44</addressOffset>
        <size>0x20</size>
        <fields>
          <field>
            <name>DTG</name>
            <bitOffset>0</bitOffset>
            <bitWidth>8</bitWidth>
          </field>
          <field>
            <name>LOCK</name>
            <bitOffset>8</bitOffset>
            <bitWidth>2</bitWidth>
          </field>
          <field>
            <name>OSSI</name>
            <bitOffset>10</bitOffset>
            <bitWidth>1</bitWidth>
          </field>
          <field>
            <name>OSSR</name>
            <bitOffset>11</bitOffset>
            <bitWidth>1</bitWidth>
          </field>
          <field>
            <name>BKE</name>
            <bitOffset>12</bitOffset>
            <bitWidth>1</bitWidth>
          </field>
          <field>
            <name>BKP</name>
            <bitOffset>13</bitOffset>
            <bitWidth>1</bitWidth>
          </field>
          <field>
            <name>AOE</name>
            <bitOffset>14</bitOffset>
            <bitWidth>1</bitWidth>
          </field>
          <field>
            <name>MOE</name>
            <bitOffset>15</bitOffset>
            <bitWidth>1</bitWidth>
          </field>
        </fields>
      </register>
      <register>
        <name>DCR</name>
        <addressOffset>0x48</addressOffset>
        <size>0x20</size>
        <fields>
          <field>
            <name>DBA</name>
            <bitOffset>0</bitOffset>
            <bitWidth>5</bitWidth>
          </field>
          <field>
            <name>DBL</name>
            <bitOffset>8</bitOffset>
            <bitWidth>5</bitWidth>
          </field>
        </fields>
      </register>
      <register>
        <name>DMAR</name>
        <addressOffset>0x4c</addressOffset>
        <size>0x20</size>
        <fields>
          <field>
            <name>DMAB</name>
            <bitOffset>0</bitOffset>
            <bitWidth>16</bitWidth>
          </field>
        </fields>
      </register>
      <register>
        <name>OR</name>
        <addressOffset>0x50</addressOffset>
        <size>0x20</size>
        <fields>
          <field>
            <name>TI1_RMP</name>
            <bitOffset>0</bitOffset>
            <bitWidth>2</bitWidth>
          </field>
          <field>
            <name>TI4_RMP</name>
            <bitOffset>6</bitOffset>
            <bitWidth>2</bitWidth>
          </field>
          <field>
            <name>ITR1_RMP</name>
            <bitOffset>10</bitOffset>
            <bitWidth>2</bitWidth>
          </field>
        </fields>
      </register>
    </peripheral>
    <peripheral>
      <name>TIM5</name>
      <baseAddress>0x40000c00</baseAddress>
      <register>
        <name>CR1</name>
        <addressOffset>0x0</addressOffset>
        <size>0x20</size>
        <fields>
          <field>
            <name>CEN</name>
            <bitOffset>0</bitOffset>
            <bitWidth>1</bitWidth>
          </field>
          <field>
            <name>UDIS</name>
            <bitOffset>1</bitOffset>
            <bitWidth>1</bitWidth>
          </field>
          <field>
            <name>URS</name>
            <bitOffset>2</bitOffset>
            <bitWidth>1</bitWidth>
          </field>
          <field>
            <name>OPM</name>
            <bitOffset>3</bitOffset>
            <bitWidth>1</bitWidth>
          </field>
          <field>
            <name>DIR</name>
            <bitOffset>4</bitOffset>
            <bitWidth>1</bitWidth>
          </field>
          <field>
            <name>CMS</name>
            <bitOffset>5</bitOffset>
            <bitWidth>2</bitWidth>
          </field>
          <field>
            <name>ARPE</name>
            <bitOffset>7</bitOffset>
            <bitWidth>1</bitWidth>
          </field>
          <field>
            <name>CKD</name>
            <bitOffset>8</bitOffset>
            <bitWidth>2</bitWidth>
          </field>
        </fields>
      </register>
      <register>
        <name>CR2</name>
        <addressOffset>0x4</addressOffset>
        <size>0x20</size>
        <fields>
          <field>
            <name>CCPC</name>
            <bitOffset>0</bitOffset>
            <bitWidth>1</bitWidth>
          </field>
          <field>
            <name>CCUS</name>
            <bitOffset>2</bitOffset>
            <bitWidth>1</bitWidth>
          </field>
          <field>
            <name>CCDS</name>
            <bitOffset>3</bitOffset>
            <bitWidth>1</bitWidth>
          </field>
          <field>
            <name>MMS</name>
            <bitOffset>4</bitOffset>
            <bitWidth>3</bitWidth>
          </field>
          <field>
            <name>TI1S</name>
            <bitOffset>7</bitOffset>
            <bitWidth>1</bitWidth>
          </field>
          <field>
            <name>OIS1</name>
            <bitOffset>8</bitOffset>
            <bitWidth>1</bitWidth>
          </field>
          <field>
            <name>OIS1N</name>
            <bitOffset>9</bitOffset>
            <bitWidth>1</bitWidth>
          </field>
          <field>
            <name>OIS2</name>
            <bitOffset>10</bitOffset>
            <bitWidth>1</bitWidth>
          </field>
          <field>
            <name>OIS2N</name>
            <bitOffset>11</bitOffset>
            <bitWidth>1</bitWidth>
          </field>
          <field>
            <name>OIS3</name>
            <bitOffset>12</bitOffset>
            <bitWidth>1</bitWidth>
          </field>
          <field>
            <name>OIS3N</name>
            <bitOffset>13</bitOffset>
            <bitWidth>1</bitWidth>
          </field>
          <field>
            <name>OIS4</name>
            <bitOffset>14</bitOffset>
            <bitWidth>1</bitWidth>
          </field>
        </fields>
      </register>
      <register>
        <name>SMCR</name>
        <addressOffset>0x8</addressOffset>
        <size>0x20</size>
        <fields>
          <field>
            <name>SMS</name>
            <bitOffset>0</bitOffset>
            <bitWidth>3</bitWidth>
          </field>
          <field>
            <name>TS</name>
            <bitOffset>4</bitOffset>
            <bitWidth>3</bitWidth>
          </field>
          <field>
            <name>MSM</name>
            <bitOffset>7</bitOffset>
            <bitWidth>1</bitWidth>
          </field>
          <field>
            <name>ETF</name>
            <bitOffset>8</bitOffset>
            <bitWidth>4</bitWidth>
          </field>
          <field>
            <name>ETPS</name>
            <bitOffset>12</bitOffset>
            <bitWidth>2</bitWidth>
          </field>
          <field>
            <name>ECE</name>
            <bitOffset>14</bitOffset>
            <bitWidth>1</bitWidth>
          </field>
          <field>
            <name>ETP</name>
            <bitOffset>15</bitOffset>
            <bitWidth>1</bitWidth>
          </field>
        </fields>
      </register>
      <register>
        <name>DIER</name>
        <addressOffset>0xc</addressOffset>
        <size>0x20</size>
        <fields>
          <field>
            <name>UIE</name>
            <bitOffset>0</bitOffset>
            <bitWidth>1</bitWidth>
          </field>
          <field>
            <name>CC1IE</name>
            <bitOffset>1</bitOffset>
            <bitWidth>1</bitWidth>
          </field>
          <field>
            <name>CC2IE</name>
            <bitOffset>2</bitOffset>
            <bitWidth>1</bitWidth>
          </field>
          <field>
            <name>CC3IE</name>
            <bitOffset>3</bitOffset>
            <bitWidth>1</bitWidth>
          </field>
          <field>
            <name>CC4IE</name>
            <bitOffset>4</bitOffset>
            <bitWidth>1</bitWidth>
          </field>
          <field>
            <name>COMIE</name>
            <bitOffset>5</bitOffset>
            <bitWidth>1</bitWidth>
          </field>
          <field>
            <name>TIE</name>
            <bitOffset>6</bitOffset>
            <bitWidth>1</bitWidth>
          </field>
          <field>
            <name>BIE</name>
            <bitOffset>7</bitOffset>
            <bitWidth>1</bitWidth>
          </field>
          <field>
            <name>UDE</name>
            <bitOffset>8</bitOffset>
            <bitWidth>1</bitWidth>
          </field>
          <field>
            <name>CC1DE</name>
            <bitOffset>9</bitOffset>
            <bitWidth>1</bitWidth>
          </field>
          <field>
            <name>CC2DE</name>
            <bitOffset>10</bitOffset>
            <bitWidth>1</bitWidth>
          </field>
          <field>
            <name>CC3DE</name>
            <bitOffset>11</bitOffset>
            <bitWidth>1</bitWidth>
          </field>
          <field>
            <name>CC4DE</name>
            <bitOffset>12</bitOffset>
            <bitWidth>1</bitWidth>
          </field>
          <field>
            <name>COMDE</name>
            <bitOffset>13</bitOffset>
            <bitWidth>1</bitWidth>
          </field>
          <field>
            <name>TDE</name>
            <bitOffset>14</bitOffset>
            <bitWidth>1</bitWidth>
          </field>
        </fields>
      </register>
      <register>
        <name>SR</name>
        <addressOffset>0x10</addressOffset>
        <size>0x20</size>
        <fields>
          <field>
            <name>UIF</name>
            <bitOffset>0</bitOffset>
            <bitWidth>1</bitWidth>
          </field>
          <field>
            <name>CC1IF</name>
            <bitOffset>1</bitOffset>
            <bitWidth>1</bitWidth>
          </field>
          <field>
            <name>CC2IF</name>
            <bitOffset>2</bitOffset>
            <bitWidth>1</bitWidth>
          </field>
          <field>
            <name>CC3IF</name>
            <bitOffset>3</bitOffset>
            <bitWidth>1</bitWidth>
          </field>
          <field>
            <name>CC4IF</name>
            <bitOffset>4</bitOffset>
            <bitWidth>1</bitWidth>
          </field>
          <field>
            <name>COMIF</name>
            <bitOffset>5</bitOffset>
            <bitWidth>1</bitWidth>
          </field>
          <field>
            <name>TIF</name>
            <bitOffset>6</bitOffset>
            <bitWidth>1</bitWidth>
          </field>
          <field>
            <name>BIF</name>
            <bitOffset>7</bitOffset>
            <bitWidth>1</bitWidth>
          </field>
          <field>
            <name>CC1OF</name>
            <bitOffset>9</bitOffset>
            <bitWidth>1</bitWidth>
          </field>
          <field>
            <name>CC2OF</name>
            <bitOffset>10</bitOffset>
            <bitWidth>1</bitWidth>
          </field>
          <field>
            <name>CC3OF</name>
            <bitOffset>11</bitOffset>
            <bitWidth>1</bitWidth>
          </field>
          <field>
            <name>CC4OF</name>
            <bitOffset>12</bitOffset>
            <bitWidth>1</bitWidth>
          </field>
        </fields>
      </register>
      <register>
        <name>EGR</name>
        <addressOffset>0x14</addressOffset>
        <size>0x20</size>
        <fields>
          <field>
            <name>UG</name>
            <bitOffset>0</bitOffset>
            <bitWidth>1</bitWidth>
          </field>
          <field>
            <name>CC1G</name>
            <bitOffset>1</bitOffset>
            <bitWidth>1</bitWidth>
          </field>
          <field>
            <name>CC2G</name>
            <bitOffset>2</bitOffset>
            <bitWidth>1</bitWidth>
          </field>
          <field>
            <name>CC3G</name>
            <bitOffset>3</bitOffset>
            <bitWidth>1</bitWidth>
          </field>
          <field>
            <name>CC4G</name>
            <bitOffset>4</bitOffset>
            <bitWidth>1</bitWidth>
          </field>
          <field>
            <name>COMG</name>
            <bitOffset>5</bitOffset>
            <bitWidth>1</bitWidth>
          </field>
          <field>
            <name>TG</name>
            <bitOffset>6</bitOffset>
            <bitWidth>1</bitWidth>
          </field>
          <field>
            <name>BG</name>
            <bitOffset>7</bitOffset>
            <bitWidth>1</bitWidth>
          </field>
        </fields>
      </register>
      <register>
        <name>CCMR1</name>
        <addressOffset>0x18</addressOffset>
        <size>0x20</size>
        <fields>
          <field>
            <name>CC1S</name>
            <bitOffset>0</bitOffset>
            <bitWidth>2</bitWidth>
          </field>
          <field>
            <name>OC1FE</name>
            <bitOffset>2</bitOffset>
            <bitWidth>1</bitWidth>
          </field>
          <field>
            <name>OC1PE</name>
            <bitOffset>3</bitOffset>
            <bitWidth>1</bitWidth>
          </field>
          <field>
            <name>OC1M</name>
            <bitOffset>4</bitOffset>
            <bitWidth>3</bitWidth>
          </field>
          <field>
            <name>OC1CE</name>
            <bitOffset>7</bitOffset>
            <bitWidth>1</bitWidth>
          </field>
          <field>
            <name>CC2S</name>
            <bitOffset>8</bitOffset>
            <bitWidth>2</bitWidth>
          </field>
          <field>
            <name>OC2FE</name>
            <bitOffset>10</bitOffset>
            <bitWidth>1</bitWidth>
          </field>
          <field>
            <name>OC2PE</name>
            <bitOffset>11</bitOffset>
            <bitWidth>1</bitWidth>
          </field>
          <field>
            <name>OC2M</name>
            <bitOffset>12</bitOffset>
            <bitWidth>3</bitWidth>
          </field>
          <field>
            <name>OC2CE</name>
            <bitOffset>15</bitOffset>
            <bitWidth>1</bitWidth>
          </field>
        </fields>
      </register>
      <register>
        <name>CCMR2</name>
        <addressOffset>0x1c</addressOffset>
        <size>0x20</size>
        <fields>
          <field>
            <name>CC3S</name>
            <bitOffset>0</bitOffset>
            <bitWidth>2</bitWidth>
          </field>
          <field>
            <name>OC3FE</name>
            <bitOffset>2</bitOffset>
            <bitWidth>1</bitWidth>
          </field>
          <field>
            <name>OC3PE</name>
            <bitOffset>3</bitOffset>
            <bitWidth>1</bitWidth>
          </field>
          <field>
            <name>OC3M</name>
            <bitOffset>4</bitOffset>
            <bitWidth>3</bitWidth>
          </field>
          <field>
            <name>OC3CE</name>
            <bitOffset>7</bitOffset>
            <bitWidth>1</bitWidth>
          </field>
          <field>
            <name>CC4S</name>
            <bitOffset>8</bitOffset>
            <bitWidth>2</bitWidth>
          </field>
          <field>
            <name>OC4FE</name>
            <bitOffset>10</bitOffset>
            <bitWidth>1</bitWidth>
          </field>
          <field>
            <name>OC4PE</name>
            <bitOffset>11</bitOffset>
            <bitWidth>1</bitWidth>
          </field>
          <field>
            <name>OC4M</name>
            <bitOffset>12</bitOffset>
            <bitWidth>3</bitWidth>
          </field>
          <field>
            <name>OC4CE</name>
            <bitOffset>15</bitOffset>
            <bitWidth>1</bitWidth>
          </field>
        </fields>
      </register>
      <register>
        <name>CCER</name>
        <addressOffset>0x20</addressOffset>
        <size>0x20</size>
        <fields>
          <field>
            <name>CC1E</name>
            <bitOffset>0</bitOffset>
            <bitWidth>1</bitWidth>
          </field>
          <field>
            <name>CC1P</name>
            <bitOffset>1</bitOffset>
            <bitWidth>1</bitWidth>
          </field>
          <field>
            <name>CC1NE</name>
            <bitOffset>2</bitOffset>
            <bitWidth>1</bitWidth>
          </field>
          <field>
            <name>CC1NP</name>
            <bitOffset>3</bitOffset>
            <bitWidth>1</bitWidth>
          </field>
          <field>
            <name>CC2E</name>
            <bitOffset>4</bitOffset>
            <bitWidth>1</bitWidth>
          </field>
          <field>
            <name>CC2P</name>
            <bitOffset>5</bitOffset>
            <bitWidth>1</bitWidth>
          </field>
          <field>
            <name>CC2NE</name>
            <bitOffset>6</bitOffset>
            <bitWidth>1</bitWidth>
          </field>
          <field>
            <name>CC2NP</name>
            <bitOffset>7</bitOffset>
            <bitWidth>1</bitWidth>
          </field>
          <field>
            <name>CC3E</name>
            <bitOffset>8</bitOffset>
            <bitWidth>1</bitWidth>
          </field>
          <field>
            <name>CC3P</name>
            <bitOffset>9</bitOffset>
            <bitWidth>1</bitWidth>
          </field>
          <field>
            <name>CC3NE</name>
            <bitOffset>10</bitOffset>
            <bitWidth>1</bitWidth>
          </field>
          <field>
            <name>CC3NP</name>
            <bitOffset>11</bitOffset>
            <bitWidth>1</bitWidth>
          </field>
          <field>
            <name>CC4E</name>
            <bitOffset>12</bitOffset>
            <bitWidth>1</bitWidth>
          </field>
          <field>
            <name>CC4P</name>
            <bitOffset>13</bitOffset>
            <bitWidth>1</bitWidth>
          </field>
          <field>
            <name>CC4NP</name>
            <bitOffset>15</bitOffset>
            <bitWidth>1</bitWidth>
          </field>
        </fields>
      </register>
      <register>
        <name>CNT</name>
        <addressOffset>0x24</addressOffset>
        <size>0x20</size>
        <fields>
          <field>
            <name>CNT</name>
            <bitOffset>0</bitOffset>
            <bitWidth>32</bitWidth>
          </field>
        </fields>
      </register>
      <register>
        <name>PSC</name>
        <addressOffset>0x28</addressOffset>
        <size>0x20</size>
        <fields>
          <field>
            <name>PSC</name>
            <bitOffset>0</bitOffset>
            <bitWidth>16</bitWidth>
          </field>
        </fields>
      </register>
      <register>
        <name>ARR</name>
        <addressOffset>0x2c</addressOffset>
        <size>0x20</size>
        <fields>
          <field>
            <name>ARR</name>
            <bitOffset>0</bitOffset>
            <bitWidth>32</bitWidth>
          </field>
        </fields>
      </register>
      <register>
        <name>RCR</name>
        <addressOffset>0x30</addressOffset>
        <size>0x20</size>
        <fields>
          <field>
            <name>REP</name>
            <bitOffset>0</bitOffset>
            <bitWidth>8</bitWidth>
          </field>
        </fields>
      </register>
      <register>
        <name>CCR1</name>
        <addressOffset>0x34</addressOffset>
        <size>0x20</size>
        <fields>
          <field>
            <name>CCR1</name>
            <bitOffset>0</bitOffset>
            <bitWidth>16</bitWidth>
          </field>
        </fields>
      </register>
      <register>
        <name>CCR2</name>
        <addressOffset>0x38</addressOffset>
        <size>0x20</size>
        <fields>
          <field>
            <name>CCR2</name>
            <bitOffset>0</bitOffset>
            <bitWidth>16</bitWidth>
          </field>
        </fields>
      </register>
      <register>
        <name>CCR3</name>
        <addressOffset>0x3c</addressOffset>
        <size>0x20</size>
        <fields>
          <field>
            <name>CCR3</name>
            <bitOffset>0</bitOffset>
            <bitWidth>16</bitWidth>
          </field>
        </fields>
      </register>
      <register>
        <name>CCR4</name>
        <addressOffset>0x40</addressOffset>
        <size>0x20</size>
        <fields>
          <field>
            <name>CCR4</name>
            <bitOffset>0</bitOffset>
            <bitWidth>16</bitWidth>
          </field>
        </fields>
      </register>
      <register>
        <name>BDTR</name>
        <addressOffset>0x44</addressOffset>
        <size>0x20</size>
        <fields>
          <field>
            <name>DTG</name>
            <bitOffset>0</bitOffset>
            <bitWidth>8</bitWidth>
          </field>
          <field>
            <name>LOCK</name>
            <bitOffset>8</bitOffset>
            <bitWidth>2</bitWidth>
          </field>
          <field>
            <name>OSSI</name>
            <bitOffset>10</bitOffset>
            <bitWidth>1</bitWidth>
          </field>
          <field>
            <name>OSSR</name>
            <bitOffset>11</bitOffset>
            <bitWidth>1</bitWidth>
          </field>
          <field>
            <name>BKE</name>
            <bitOffset>12</bitOffset>
            <bitWidth>1</bitWidth>
          </field>
          <field>
            <name>BKP</name>
            <bitOffset>13</bitOffset>
            <bitWidth>1</bitWidth>
          </field>
          <field>
            <name>AOE</name>
            <bitOffset>14</bitOffset>
            <bitWidth>1</bitWidth>
          </field>
          <field>
            <name>MOE</name>
            <bitOffset>15</bitOffset>
            <bitWidth>1</bitWidth>
          </field>
        </fields>
      </register>
      <register>
        <name>DCR</name>
        <addressOffset>0x48</addressOffset>
        <size>0x20</size>
        <fields>
          <field>
            <name>DBA</name>
            <bitOffset>0</bitOffset>
            <bitWidth>5</bitWidth>
          </field>
          <field>
            <name>DBL</name>
            <bitOffset>8</bitOffset>
            <bitWidth>5</bitWidth>
          </field>
        </fields>
      </register>
      <register>
        <name>DMAR</name>
        <addressOffset>0x4c</addressOffset>
        <size>0x20</size>
        <fields>
          <field>
            <name>DMAB</name>
            <bitOffset>0</bitOffset>
            <bitWidth>16</bitWidth>
          </field>
        </fields>
      </register>
      <register>
        <name>OR</name>
        <addressOffset>0x50</addressOffset>
        <size>0x20</size>
        <fields>
          <field>
            <name>TI1_RMP</name>
            <bitOffset>0</bitOffset>
            <bitWidth>2</bitWidth>
          </field>
          <field>
            <name>TI4_RMP</name>
            <bitOffset>6</bitOffset>
            <bitWidth>2</bitWidth>
          </field>
          <field>
            <name>ITR1_RMP</name>
            <bitOffset>10</bitOffset>
            <bitWidth>2</bitWidth>
          </field>
        </fields>
      </register>
    </peripheral>
    <peripheral>
      <name>TIM6</name>
      <baseAddress>0x40001000</baseAddress>
      <register>
        <name>CR1</name>
        <addressOffset>0x0</addressOffset>
        <size>0x20</size>
        <fields>
          <field>
            <name>CEN</name>
            <bitOffset>0</bitOffset>
            <bitWidth>1</bitWidth>
          </field>
          <field>
            <name>UDIS</name>
            <bitOffset>1</bitOffset>
            <bitWidth>1</bitWidth>
          </field>
          <field>
            <name>URS</name>
            <bitOffset>2</bitOffset>
            <bitWidth>1</bitWidth>
          </field>
          <field>
            <name>OPM</name>
            <bitOffset>3</bitOffset>
            <bitWidth>1</bitWidth>
          </field>
          <field>
            <name>DIR</name>
            <bitOffset>4</bitOffset>
            <bitWidth>1</bitWidth>
          </field>
          <field>
            <name>CMS</name>
            <bitOffset>5</bitOffset>
            <bitWidth>2</bitWidth>
          </field>
          <field>
            <name>ARPE</name>
            <bitOffset>7</bitOffset>
            <bitWidth>1</bitWidth>
          </field>
          <field>
            <name>CKD</name>
            <bitOffset>8</bitOffset>
            <bitWidth>2</bitWidth>
          </field>
        </fields>
      </register>
      <register>
        <name>CR2</name>
        <addressOffset>0x4</addressOffset>
        <size>0x20</size>
        <fields>
          <field>
            <name>CCPC</name>
            <bitOffset>0</bitOffset>
            <bitWidth>1</bitWidth>
          </field>
          <field>
            <name>CCUS</name>
            <bitOffset>2</bitOffset>
            <bitWidth>1</bitWidth>
          </field>
          <field>
            <name>CCDS</name>
            <bitOffset>3</bitOffset>
            <bitWidth>1</bitWidth>
          </field>
          <field>
            <name>MMS</name>
            <bitOffset>4</bitOffset>
            <bitWidth>3</bitWidth>
          </field>
          <field>
            <name>TI1S</name>
            <bitOffset>7</bitOffset>
            <bitWidth>1</bitWidth>
          </field>
          <field>
            <name>OIS1</name>
            <bitOffset>8</bitOffset>
            <bitWidth>1</bitWidth>
          </field>
          <field>
            <name>OIS1N</name>
            <bitOffset>9</bitOffset>
            <bitWidth>1</bitWidth>
          </field>
          <field>
            <name>OIS2</name>
            <bitOffset>10</bitOffset>
            <bitWidth>1</bitWidth>
          </field>
          <field>
            <name>OIS2N</name>
            <bitOffset>11</bitOffset>
            <bitWidth>1</bitWidth>
          </field>
          <field>
            <name>OIS3</name>
            <bitOffset>12</bitOffset>
            <bitWidth>1</bitWidth>
          </field>
          <field>
            <name>OIS3N</name>
            <bitOffset>13</bitOffset>
            <bitWidth>1</bitWidth>
          </field>
          <field>
            <name>OIS4</name>
            <bitOffset>14</bitOffset>
            <bitWidth>1</bitWidth>
          </field>
        </fields>
      </register>
      <register>
        <name>SMCR</name>
        <addressOffset>0x8</addressOffset>
        <size>0x20</size>
        <fields>
          <field>
            <name>SMS</name>
            <bitOffset>0</bitOffset>
            <bitWidth>3</bitWidth>
          </field>
          <field>
            <name>TS</name>
            <bitOffset>4</bitOffset>
            <bitWidth>3</bitWidth>
          </field>
          <field>
            <name>MSM</name>
            <bitOffset>7</bitOffset>
            <bitWidth>1</bitWidth>
          </field>
          <field>
            <name>ETF</name>
            <bitOffset>8</bitOffset>
            <bitWidth>4</bitWidth>
          </field>
          <field>
            <name>ETPS</name>
            <bitOffset>12</bitOffset>
            <bitWidth>2</bitWidth>
          </field>
          <field>
            <name>ECE</name>
            <bitOffset>14</bitOffset>
            <bitWidth>1</bitWidth>
          </field>
          <field>
            <name>ETP</name>
            <bitOffset>15</bitOffset>
            <bitWidth>1</bitWidth>
          </field>
        </fields>
      </register>
      <register>
        <name>DIER</name>
        <addressOffset>0xc</addressOffset>
        <size>0x20</size>
        <fields>
          <field>
            <name>UIE</name>
            <bitOffset>0</bitOffset>
            <bitWidth>1</bitWidth>
          </field>
          <field>
            <name>CC1IE</name>
            <bitOffset>1</bitOffset>
            <bitWidth>1</bitWidth>
          </field>
          <field>
            <name>CC2IE</name>
            <bitOffset>2</bitOffset>
            <bitWidth>1</bitWidth>
          </field>
          <field>
            <name>CC3IE</name>
            <bitOffset>3</bitOffset>
            <bitWidth>1</bitWidth>
          </field>
          <field>
            <name>CC4IE</name>
            <bitOffset>4</bitOffset>
            <bitWidth>1</bitWidth>
          </field>
          <field>
            <name>COMIE</name>
            <bitOffset>5</bitOffset>
            <bitWidth>1</bitWidth>
          </field>
          <field>
            <name>TIE</name>
            <bitOffset>6</bitOffset>
            <bitWidth>1</bitWidth>
          </field>
          <field>
            <name>BIE</name>
            <bitOffset>7</bitOffset>
            <bitWidth>1</bitWidth>
          </field>
          <field>
            <name>UDE</name>
            <bitOffset>8</bitOffset>
            <bitWidth>1</bitWidth>
          </field>
          <field>
            <name>CC1DE</name>
            <bitOffset>9</bitOffset>
            <bitWidth>1</bitWidth>
          </field>
          <field>
            <name>CC2DE</name>
            <bitOffset>10</bitOffset>
            <bitWidth>1</bitWidth>
          </field>
          <field>
            <name>CC3DE</name>
            <bitOffset>11</bitOffset>
            <bitWidth>1</bitWidth>
          </field>
          <field>
            <name>CC4DE</name>
            <bitOffset>12</bitOffset>
            <bitWidth>1</bitWidth>
          </field>
          <field>
            <name>COMDE</name>
            <bitOffset>13</bitOffset>
            <bitWidth>1</bitWidth>
          </field>
          <field>
            <name>TDE</name>
            <bitOffset>14</bitOffset>
            <bitWidth>1</bitWidth>
          </field>
        </fields>
      </register>
      <register>
        <name>SR</name>
        <addressOffset>0x10</addressOffset>
        <size>0x20</size>
        <fields>
          <field>
            <name>UIF</name>
            <bitOffset>0</bitOffset>
            <bitWidth>1</bitWidth>
          </field>
          <field>
            <name>CC1IF</name>
            <bitOffset>1</bitOffset>
            <bitWidth>1</bitWidth>
          </field>
          <field>
            <name>CC2IF</name>
            <bitOffset>2</bitOffset>
            <bitWidth>1</bitWidth>
          </field>
          <field>
            <name>CC3IF</name>
            <bitOffset>3</bitOffset>
            <bitWidth>1</bitWidth>
          </field>
          <field>
            <name>CC4IF</name>
            <bitOffset>4</bitOffset>
            <bitWidth>1</bitWidth>
          </field>
          <field>
            <name>COMIF</name>
            <bitOffset>5</bitOffset>
            <bitWidth>1</bitWidth>
          </field>
          <field>
            <name>TIF</name>
            <bitOffset>6</bitOffset>
            <bitWidth>1</bitWidth>
          </field>
          <field>
            <name>BIF</name>
            <bitOffset>7</bitOffset>
            <bitWidth>1</bitWidth>
          </field>
          <field>
            <name>CC1OF</name>
            <bitOffset>9</bitOffset>
            <bitWidth>1</bitWidth>
          </field>
          <field>
            <name>CC2OF</name>
            <bitOffset>10</bitOffset>
            <bitWidth>1</bitWidth>
          </field>
          <field>
            <name>CC3OF</name>
            <bitOffset>11</bitOffset>
            <bitWidth>1</bitWidth>
          </field>
          <field>
            <name>CC4OF</name>
            <bitOffset>12</bitOffset>
            <bitWidth>1</bitWidth>
          </field>
        </fields>
      </register>
      <register>
        <name>EGR</name>
        <addressOffset>0x14</addressOffset>
        <size>0x20</size>
        <fields>
          <field>
            <name>UG</name>
            <bitOffset>0</bitOffset>
            <bitWidth>1</bitWidth>
          </field>
          <field>
            <name>CC1G</name>
            <bitOffset>1</bitOffset>
            <bitWidth>1</bitWidth>
          </field>
          <field>
            <name>CC2G</name>
            <bitOffset>2</bitOffset>
            <bitWidth>1</bitWidth>
          </field>
          <field>
            <name>CC3G</name>
            <bitOffset>3</bitOffset>
            <bitWidth>1</bitWidth>
          </field>
          <field>
            <name>CC4G</name>
            <bitOffset>4</bitOffset>
            <bitWidth>1</bitWidth>
          </field>
          <field>
            <name>COMG</name>
            <bitOffset>5</bitOffset>
            <bitWidth>1</bitWidth>
          </field>
          <field>
            <name>TG</name>
            <bitOffset>6</bitOffset>
            <bitWidth>1</bitWidth>
          </field>
          <field>
            <name>BG</name>
            <bitOffset>7</bitOffset>
            <bitWidth>1</bitWidth>
          </field>
        </fields>
      </register>
      <register>
        <name>CCMR1</name>
        <addressOffset>0x18</addressOffset>
        <size>0x20</size>
        <fields>
          <field>
            <name>CC1S</name>
            <bitOffset>0</bitOffset>
            <bitWidth>2</bitWidth>
          </field>
          <field>
            <name>OC1FE</name>
            <bitOffset>2</bitOffset>
            <bitWidth>1</bitWidth>
          </field>
          <field>
            <name>OC1PE</name>
            <bitOffset>3</bitOffset>
            <bitWidth>1</bitWidth>
          </field>
          <field>
            <name>OC1M</name>
            <bitOffset>4</bitOffset>
            <bitWidth>3</bitWidth>
          </field>
          <field>
            <name>OC1CE</name>
            <bitOffset>7</bitOffset>
            <bitWidth>1</bitWidth>
          </field>
          <field>
            <name>CC2S</name>
            <bitOffset>8</bitOffset>
            <bitWidth>2</bitWidth>
          </field>
          <field>
            <name>OC2FE</name>
            <bitOffset>10</bitOffset>
            <bitWidth>1</bitWidth>
          </field>
          <field>
            <name>OC2PE</name>
            <bitOffset>11</bitOffset>
            <bitWidth>1</bitWidth>
          </field>
          <field>
            <name>OC2M</name>
            <bitOffset>12</bitOffset>
            <bitWidth>3</bitWidth>
          </field>
          <field>
            <name>OC2CE</name>
            <bitOffset>15</bitOffset>
            <bitWidth>1</bitWidth>
          </field>
        </fields>
      </register>
      <register>
        <name>CCMR2</name>
        <addressOffset>0x1c</addressOffset>
        <size>0x20</size>
        <fields>
          <field>
            <name>CC3S</name>
            <bitOffset>0</bitOffset>
            <bitWidth>2</bitWidth>
          </field>
          <field>
            <name>OC3FE</name>
            <bitOffset>2</bitOffset>
            <bitWidth>1</bitWidth>
          </field>
          <field>
            <name>OC3PE</name>
            <bitOffset>3</bitOffset>
            <bitWidth>1</bitWidth>
          </field>
          <field>
            <name>OC3M</name>
            <bitOffset>4</bitOffset>
            <bitWidth>3</bitWidth>
          </field>
          <field>
            <name>OC3CE</name>
            <bitOffset>7</bitOffset>
            <bitWidth>1</bitWidth>
          </field>
          <field>
            <name>CC4S</name>
            <bitOffset>8</bitOffset>
            <bitWidth>2</bitWidth>
          </field>
          <field>
            <name>OC4FE</name>
            <bitOffset>10</bitOffset>
            <bitWidth>1</bitWidth>
          </field>
          <field>
            <name>OC4PE</name>
            <bitOffset>11</bitOffset>
            <bitWidth>1</bitWidth>
          </field>
          <field>
            <name>OC4M</name>
            <bitOffset>12</bitOffset>
            <bitWidth>3</bitWidth>
          </field>
          <field>
            <name>OC4CE</name>
            <bitOffset>15</bitOffset>
            <bitWidth>1</bitWidth>
          </field>
        </fields>
      </register>
      <register>
        <name>CCER</name>
        <addressOffset>0x20</addressOffset>
        <size>0x20</size>
        <fields>
          <field>
            <name>CC1E</name>
            <bitOffset>0</bitOffset>
            <bitWidth>1</bitWidth>
          </field>
          <field>
            <name>CC1P</name>
            <bitOffset>1</bitOffset>
            <bitWidth>1</bitWidth>
          </field>
          <field>
            <name>CC1NE</name>
            <bitOffset>2</bitOffset>
            <bitWidth>1</bitWidth>
          </field>
          <field>
            <name>CC1NP</name>
            <bitOffset>3</bitOffset>
            <bitWidth>1</bitWidth>
          </field>
          <field>
            <name>CC2E</name>
            <bitOffset>4</bitOffset>
            <bitWidth>1</bitWidth>
          </field>
          <field>
            <name>CC2P</name>
            <bitOffset>5</bitOffset>
            <bitWidth>1</bitWidth>
          </field>
          <field>
            <name>CC2NE</name>
            <bitOffset>6</bitOffset>
            <bitWidth>1</bitWidth>
          </field>
          <field>
            <name>CC2NP</name>
            <bitOffset>7</bitOffset>
            <bitWidth>1</bitWidth>
          </field>
          <field>
            <name>CC3E</name>
            <bitOffset>8</bitOffset>
            <bitWidth>1</bitWidth>
          </field>
          <field>
            <name>CC3P</name>
            <bitOffset>9</bitOffset>
            <bitWidth>1</bitWidth>
          </field>
          <field>
            <name>CC3NE</name>
            <bitOffset>10</bitOffset>
            <bitWidth>1</bitWidth>
          </field>
          <field>
            <name>CC3NP</name>
            <bitOffset>11</bitOffset>
            <bitWidth>1</bitWidth>
          </field>
          <field>
            <name>CC4E</name>
            <bitOffset>12</bitOffset>
            <bitWidth>1</bitWidth>
          </field>
          <field>
            <name>CC4P</name>
            <bitOffset>13</bitOffset>
            <bitWidth>1</bitWidth>
          </field>
          <field>
            <name>CC4NP</name>
            <bitOffset>15</bitOffset>
            <bitWidth>1</bitWidth>
          </field>
        </fields>
      </register>
      <register>
        <name>CNT</name>
        <addressOffset>0x24</addressOffset>
        <size>0x20</size>
        <fields>
          <field>
            <name>CNT</name>
            <bitOffset>0</bitOffset>
            <bitWidth>32</bitWidth>
          </field>
        </fields>
      </register>
      <register>
        <name>PSC</name>
        <addressOffset>0x28</addressOffset>
        <size>0x20</size>
        <fields>
          <field>
            <name>PSC</name>
            <bitOffset>0</bitOffset>
            <bitWidth>16</bitWidth>
          </field>
        </fields>
      </register>
      <register>
        <name>ARR</name>
        <addressOffset>0x2c</addressOffset>
        <size>0x20</size>
        <fields>
          <field>
            <name>ARR</name>
            <bitOffset>0</bitOffset>
            <bitWidth>32</bitWidth>
          </field>
        </fields>
      </register>
      <register>
        <name>RCR</name>
        <addressOffset>0x30</addressOffset>
        <size>0x20</size>
        <fields>
          <field>
            <name>REP</name>
            <bitOffset>0</bitOffset>
            <bitWidth>8</bitWidth>
          </field>
        </fields>
      </register>
      <register>
        <name>CCR1</name>
        <addressOffset>0x34</addressOffset>
        <size>0x20</size>
        <fields>
          <field>
            <name>CCR1</name>
            <bitOffset>0</bitOffset>
            <bitWidth>16</bitWidth>
          </field>
        </fields>
      </register>
      <register>
        <name>CCR2</name>
        <addressOffset>0x38</addressOffset>
        <size>0x20</size>
        <fields>
          <field>
            <name>CCR2</name>
            <bitOffset>0</bitOffset>
            <bitWidth>16</bitWidth>
          </field>
        </fields>
      </register>
      <register>
        <name>CCR3</name>
        <addressOffset>0x3c</addressOffset>
        <size>0x20</size>
        <fields>
          <field>
            <name>CCR3</name>
            <bitOffset>0</bitOffset>
            <bitWidth>16</bitWidth>
          </field>
        </fields>
      </register>
      <register>
        <name>CCR4</name>
        <addressOffset>0x40</addressOffset>
        <size>0x20</size>
        <fields>
          <field>
            <name>CCR4</name>
            <bitOffset>0</bitOffset>
            <bitWidth>16</bitWidth>
          </field>
        </fields>
      </register>
      <register>
        <name>BDTR</name>
        <addressOffset>0x44</addressOffset>
        <size>0x20</size>
        <fields>
          <field>
            <name>DTG</name>
            <bitOffset>0</bitOffset>
            <bitWidth>8</bitWidth>
          </field>
          <field>
            <name>LOCK</name>
            <bitOffset>8</bitOffset>
            <bitWidth>2</bitWidth>
          </field>
          <field>
            <name>OSSI</name>
            <bitOffset>10</bitOffset>
            <bitWidth>1</bitWidth>
          </field>
          <field>
            <name>OSSR</name>
            <bitOffset>11</bitOffset>
            <bitWidth>1</bitWidth>
          </field>
          <field>
            <name>BKE</name>
            <bitOffset>12</bitOffset>
            <bitWidth>1</bitWidth>
          </field>
          <field>
            <name>BKP</name>
            <bitOffset>13</bitOffset>
            <bitWidth>1</bitWidth>
          </field>
          <field>
            <name>AOE</name>
            <bitOffset>14</bitOffset>
            <bitWidth>1</bitWidth>
          </field>
          <field>
            <name>MOE</name>
            <bitOffset>15</bitOffset>
            <bitWidth>1</bitWidth>
          </field>
        </fields>
      </register>
      <register>
        <name>DCR</name>
        <addressOffset>0x48</addressOffset>
        <size>0x20</size>
        <fields>
          <field>
            <name>DBA</name>
            <bitOffset>0</bitOffset>
            <bitWidth>5</bitWidth>
          </field>
          <field>
            <name>DBL</name>
            <bitOffset>8</bitOffset>
            <bitWidth>5</bitWidth>
          </field>
        </fields>
      </register>
      <register>
        <name>DMAR</name>
        <addressOffset>0x4c</addressOffset>
        <size>0x20</size>
        <fields>
          <field>
            <name>DMAB</name>
            <bitOffset>0</bitOffset>
            <bitWidth>16</bitWidth>
          </field>
        </fields>
      </register>
      <register>
        <name>OR</name>
        <addressOffset>0x50</addressOffset>
        <size>0x20</size>
        <fields>
          <field>
            <name>TI1_RMP</name>
            <bitOffset>0</bitOffset>
            <bitWidth>2</bitWidth>
          </field>
          <field>
            <name>TI4_RMP</name>
            <bitOffset>6</bitOffset>
            <bitWidth>2</bitWidth>
          </field>
          <field>
            <name>ITR1_RMP</name>
            <bitOffset>10</bitOffset>
            <bitWidth>2</bitWidth>
          </field>
        </fields>
      </register>
    </peripheral>
    <peripheral>
      <name>TIM7</name>
      <baseAddress>0x40001400</baseAddress>
      <register>
        <name>CR1</name>
        <addressOffset>0x0</addressOffset>
        <size>0x20</size>
        <fields>
          <field>
            <name>CEN</name>
            <bitOffset>0</bitOffset>
            <bitWidth>1</bitWidth>
          </field>
          <field>
            <name>UDIS</name>
            <bitOffset>1</bitOffset>
            <bitWidth>1</bitWidth>
          </field>
          <field>
            <name>URS</name>
            <bitOffset>2</bitOffset>
            <bitWidth>1</bitWidth>
          </field>
          <field>
            <name>OPM</name>
            <bitOffset>3</bitOffset>
            <bitWidth>1</bitWidth>
          </field>
          <field>
            <name>DIR</name>
            <bitOffset>4</bitOffset>
            <bitWidth>1</bitWidth>
          </field>
          <field>
            <name>CMS</name>
            <bitOffset>5</bitOffset>
            <bitWidth>2</bitWidth>
          </field>
          <field>
            <name>ARPE</name>
            <bitOffset>7</bitOffset>
            <bitWidth>1</bitWidth>
          </field>
          <field>
            <name>CKD</name>
            <bitOffset>8</bitOffset>
            <bitWidth>2</bitWidth>
          </field>
        </fields>
      </register>
      <register>
        <name>CR2</name>
        <addressOffset>0x4</addressOffset>
        <size>0x20</size>
        <fields>
          <field>
            <name>CCPC</name>
            <bitOffset>0</bitOffset>
            <bitWidth>1</bitWidth>
          </field>
          <field>
            <name>CCUS</name>
            <bitOffset>2</bitOffset>
            <bitWidth>1</bitWidth>
          </field>
          <field>
            <name>CCDS</name>
            <bitOffset>3</bitOffset>
            <bitWidth>1</bitWidth>
          </field>
          <field>
            <name>MMS</name>
            <bitOffset>4</bitOffset>
            <bitWidth>3</bitWidth>
          </field>
          <field>
            <name>TI1S</name>
            <bitOffset>7</bitOffset>
            <bitWidth>1</bitWidth>
          </field>
          <field>
            <name>OIS1</name>
            <bitOffset>8</bitOffset>
            <bitWidth>1</bitWidth>
          </field>
          <field>
            <name>OIS1N</name>
            <bitOffset>9</bitOffset>
            <bitWidth>1</bitWidth>
          </field>
          <field>
            <name>OIS2</name>
            <bitOffset>10</bitOffset>
            <bitWidth>1</bitWidth>
          </field>
          <field>
            <name>OIS2N</name>
            <bitOffset>11</bitOffset>
            <bitWidth>1</bitWidth>
          </field>
          <field>
            <name>OIS3</name>
            <bitOffset>12</bitOffset>
            <bitWidth>1</bitWidth>
          </field>
          <field>
            <name>OIS3N</name>
            <bitOffset>13</bitOffset>
            <bitWidth>1</bitWidth>
          </field>
          <field>
            <name>OIS4</name>
            <bitOffset>14</bitOffset>
            <bitWidth>1</bitWidth>
          </field>
        </fields>
      </register>
      <register>
        <name>SMCR</name>
        <addressOffset>0x8</addressOffset>
        <size>0x20</size>
        <fields>
          <field>
            <name>SMS</name>
            <bitOffset>0</bitOffset>
            <bitWidth>3</bitWidth>
          </field>
          <field>
            <name>TS</name>
            <bitOffset>4</bitOffset>
            <bitWidth>3</bitWidth>
          </field>
          <field>
            <name>MSM</name>
            <bitOffset>7</bitOffset>
            <bitWidth>1</bitWidth>
          </field>
          <field>
            <name>ETF</name>
            <bitOffset>8</bitOffset>
            <bitWidth>4</bitWidth>
          </field>
          <field>
            <name>ETPS</name>
            <bitOffset>12</bitOffset>
            <bitWidth>2</bitWidth>
          </field>
          <field>
            <name>ECE</name>
            <bitOffset>14</bitOffset>
            <bitWidth>1</bitWidth>
          </field>
          <field>
            <name>ETP</name>
            <bitOffset>15</bitOffset>
            <bitWidth>1</bitWidth>
          </field>
        </fields>
      </register>
      <register>
        <name>DIER</name>
        <addressOffset>0xc</addressOffset>
        <size>0x20</size>
        <fields>
          <field>
            <name>UIE</name>
            <bitOffset>0</bitOffset>
            <bitWidth>1</bitWidth>
          </field>
          <field>
            <name>CC1IE</name>
            <bitOffset>1</bitOffset>
            <bitWidth>1</bitWidth>
          </field>
          <field>
            <name>CC2IE</name>
            <bitOffset>2</bitOffset>
            <bitWidth>1</bitWidth>
          </field>
          <field>
            <name>CC3IE</name>
            <bitOffset>3</bitOffset>
            <bitWidth>1</bitWidth>
          </field>
          <field>
            <name>CC4IE</name>
            <bitOffset>4</bitOffset>
            <bitWidth>1</bitWidth>
          </field>
          <field>
            <name>COMIE</name>
            <bitOffset>5</bitOffset>
            <bitWidth>1</bitWidth>
          </field>
          <field>
            <name>TIE</name>
            <bitOffset>6</bitOffset>
            <bitWidth>1</bitWidth>
          </field>
          <field>
            <name>BIE</name>
            <bitOffset>7</bitOffset>
            <bitWidth>1</bitWidth>
          </field>
          <field>
            <name>UDE</name>
            <bitOffset>8</bitOffset>
            <bitWidth>1</bitWidth>
          </field>
          <field>
            <name>CC1DE</name>
            <bitOffset>9</bitOffset>
            <bitWidth>1</bitWidth>
          </field>
          <field>
            <name>CC2DE</name>
            <bitOffset>10</bitOffset>
            <bitWidth>1</bitWidth>
          </field>
          <field>
            <name>CC3DE</name>
            <bitOffset>11</bitOffset>
            <bitWidth>1</bitWidth>
          </field>
          <field>
            <name>CC4DE</name>
            <bitOffset>12</bitOffset>
            <bitWidth>1</bitWidth>
          </field>
          <field>
            <name>COMDE</name>
            <bitOffset>13</bitOffset>
            <bitWidth>1</bitWidth>
          </field>
          <field>
            <name>TDE</name>
            <bitOffset>14</bitOffset>
            <bitWidth>1</bitWidth>
          </field>
        </fields>
      </register>
      <register>
        <name>SR</name>
        <addressOffset>0x10</addressOffset>
        <size>0x20</size>
        <fields>
          <field>
            <name>UIF</name>
            <bitOffset>0</bitOffset>
            <bitWidth>1</bitWidth>
          </field>
          <field>
            <name>CC1IF</name>
            <bitOffset>1</bitOffset>
            <bitWidth>1</bitWidth>
          </field>
          <field>
            <name>CC2IF</name>
            <bitOffset>2</bitOffset>
            <bitWidth>1</bitWidth>
          </field>
          <field>
            <name>CC3IF</name>
            <bitOffset>3</bitOffset>
            <bitWidth>1</bitWidth>
          </field>
          <field>
            <name>CC4IF</name>
            <bitOffset>4</bitOffset>
            <bitWidth>1</bitWidth>
          </field>
          <field>
            <name>COMIF</name>
            <bitOffset>5</bitOffset>
            <bitWidth>1</bitWidth>
          </field>
          <field>
            <name>TIF</name>
            <bitOffset>6</bitOffset>
            <bitWidth>1</bitWidth>
          </field>
          <field>
            <name>BIF</name>
            <bitOffset>7</bitOffset>
            <bitWidth>1</bitWidth>
          </field>
          <field>
            <name>CC1OF</name>
            <bitOffset>9</bitOffset>
            <bitWidth>1</bitWidth>
          </field>
          <field>
            <name>CC2OF</name>
            <bitOffset>10</bitOffset>
            <bitWidth>1</bitWidth>
          </field>
          <field>
            <name>CC3OF</name>
            <bitOffset>11</bitOffset>
            <bitWidth>1</bitWidth>
          </field>
          <field>
            <name>CC4OF</name>
            <bitOffset>12</bitOffset>
            <bitWidth>1</bitWidth>
          </field>
        </fields>
      </register>
      <register>
        <name>EGR</name>
        <addressOffset>0x14</addressOffset>
        <size>0x20</size>
        <fields>
          <field>
            <name>UG</name>
            <bitOffset>0</bitOffset>
            <bitWidth>1</bitWidth>
          </field>
          <field>
            <name>CC1G</name>
            <bitOffset>1</bitOffset>
            <bitWidth>1</bitWidth>
          </field>
          <field>
            <name>CC2G</name>
            <bitOffset>2</bitOffset>
            <bitWidth>1</bitWidth>
          </field>
          <field>
            <name>CC3G</name>
            <bitOffset>3</bitOffset>
            <bitWidth>1</bitWidth>
          </field>
          <field>
            <name>CC4G</name>
            <bitOffset>4</bitOffset>
            <bitWidth>1</bitWidth>
          </field>
          <field>
            <name>COMG</name>
            <bitOffset>5</bitOffset>
            <bitWidth>1</bitWidth>
          </field>
          <field>
            <name>TG</name>
            <bitOffset>6</bitOffset>
            <bitWidth>1</bitWidth>
          </field>
          <field>
            <name>BG</name>
            <bitOffset>7</bitOffset>
            <bitWidth>1</bitWidth>
          </field>
        </fields>
      </register>
      <register>
        <name>CCMR1</name>
        <addressOffset>0x18</addressOffset>
        <size>0x20</size>
        <fields>
          <field>
            <name>CC1S</name>
            <bitOffset>0</bitOffset>
            <bitWidth>2</bitWidth>
          </field>
          <field>
            <name>OC1FE</name>
            <bitOffset>2</bitOffset>
            <bitWidth>1</bitWidth>
          </field>
          <field>
            <name>OC1PE</name>
            <bitOffset>3</bitOffset>
            <bitWidth>1</bitWidth>
          </field>
          <field>
            <name>OC1M</name>
            <bitOffset>4</bitOffset>
            <bitWidth>3</bitWidth>
          </field>
          <field>
            <name>OC1CE</name>
            <bitOffset>7</bitOffset>
            <bitWidth>1</bitWidth>
          </field>
          <field>
            <name>CC2S</name>
            <bitOffset>8</bitOffset>
            <bitWidth>2</bitWidth>
          </field>
          <field>
            <name>OC2FE</name>
            <bitOffset>10</bitOffset>
            <bitWidth>1</bitWidth>
          </field>
          <field>
            <name>OC2PE</name>
            <bitOffset>11</bitOffset>
            <bitWidth>1</bitWidth>
          </field>
          <field>
            <name>OC2M</name>
            <bitOffset>12</bitOffset>
            <bitWidth>3</bitWidth>
          </field>
          <field>
            <name>OC2CE</name>
            <bitOffset>15</bitOffset>
            <bitWidth>1</bitWidth>
          </field>
        </fields>
      </register>
      <register>
        <name>CCMR2</name>
        <addressOffset>0x1c</addressOffset>
        <size>0x20</size>
        <fields>
          <field>
            <name>CC3S</name>
            <bitOffset>0</bitOffset>
            <bitWidth>2</bitWidth>
          </field>
          <field>
            <name>OC3FE</name>
            <bitOffset>2</bitOffset>
            <bitWidth>1</bitWidth>
          </field>
          <field>
            <name>OC3PE</name>
            <bitOffset>3</bitOffset>
            <bitWidth>1</bitWidth>
          </field>
          <field>
            <name>OC3M</name>
            <bitOffset>4</bitOffset>
            <bitWidth>3</bitWidth>
          </field>
          <field>
            <name>OC3CE</name>
            <bitOffset>7</bitOffset>
            <bitWidth>1</bitWidth>
          </field>
          <field>
            <name>CC4S</name>
            <bitOffset>8</bitOffset>
            <bitWidth>2</bitWidth>
          </field>
          <field>
            <name>OC4FE</name>
            <bitOffset>10</bitOffset>
            <bitWidth>1</bitWidth>
          </field>
          <field>
            <name>OC4PE</name>
            <bitOffset>11</bitOffset>
            <bitWidth>1</bitWidth>
          </field>
          <field>
            <name>OC4M</name>
            <bitOffset>12</bitOffset>
            <bitWidth>3</bitWidth>
          </field>
          <field>
            <name>OC4CE</name>
            <bitOffset>15</bitOffset>
            <bitWidth>1</bitWidth>
          </field>
        </fields>
      </register>
      <register>
        <name>CCER</name>
        <addressOffset>0x20</addressOffset>
        <size>0x20</size>
        <fields>
          <field>
            <name>CC1E</name>
            <bitOffset>0</bitOffset>
            <bitWidth>1</bitWidth>
          </field>
          <field>
            <name>CC1P</name>
            <bitOffset>1</bitOffset>
            <bitWidth>1</bitWidth>
          </field>
          <field>
            <name>CC1NE</name>
            <bitOffset>2</bitOffset>
            <bitWidth>1</bitWidth>
          </field>
          <field>
            <name>CC1NP</name>
            <bitOffset>3</bitOffset>
            <bitWidth>1</bitWidth>
          </field>
          <field>
            <name>CC2E</name>
            <bitOffset>4</bitOffset>
            <bitWidth>1</bitWidth>
          </field>
          <field>
            <name>CC2P</name>
            <bitOffset>5</bitOffset>
            <bitWidth>1</bitWidth>
          </field>
          <field>
            <name>CC2NE</name>
            <bitOffset>6</bitOffset>
            <bitWidth>1</bitWidth>
          </field>
          <field>
            <name>CC2NP</name>
            <bitOffset>7</bitOffset>
            <bitWidth>1</bitWidth>
          </field>
          <field>
            <name>CC3E</name>
            <bitOffset>8</bitOffset>
            <bitWidth>1</bitWidth>
          </field>
          <field>
            <name>CC3P</name>
            <bitOffset>9</bitOffset>
            <bitWidth>1</bitWidth>
          </field>
          <field>
            <name>CC3NE</name>
            <bitOffset>10</bitOffset>
            <bitWidth>1</bitWidth>
          </field>
          <field>
            <name>CC3NP</name>
            <bitOffset>11</bitOffset>
            <bitWidth>1</bitWidth>
          </field>
          <field>
            <name>CC4E</name>
            <bitOffset>12</bitOffset>
            <bitWidth>1</bitWidth>
          </field>
          <field>
            <name>CC4P</name>
            <bitOffset>13</bitOffset>
            <bitWidth>1</bitWidth>
          </field>
          <field>
            <name>CC4NP</name>
            <bitOffset>15</bitOffset>
            <bitWidth>1</bitWidth>
          </field>
        </fields>
      </register>
      <register>
        <name>CNT</name>
        <addressOffset>0x24</addressOffset>
        <size>0x20</size>
        <fields>
          <field>
            <name>CNT</name>
            <bitOffset>0</bitOffset>
            <bitWidth>32</bitWidth>
          </field>
        </fields>
      </register>
      <register>
        <name>PSC</name>
        <addressOffset>0x28</addressOffset>
        <size>0x20</size>
        <fields>
          <field>
            <name>PSC</name>
            <bitOffset>0</bitOffset>
            <bitWidth>16</bitWidth>
          </field>
        </fields>
      </register>
      <register>
        <name>ARR</name>
        <addressOffset>0x2c</addressOffset>
        <size>0x20</size>
        <fields>
          <field>
            <name>ARR</name>
            <bitOffset>0</bitOffset>
            <bitWidth>32</bitWidth>
          </field>
        </fields>
      </register>
      <register>
        <name>RCR</name>
        <addressOffset>0x30</addressOffset>
        <size>0x20</size>
        <fields>
          <field>
            <name>REP</name>
            <bitOffset>0</bitOffset>
            <bitWidth>8</bitWidth>
          </field>
        </fields>
      </register>
      <register>
        <name>CCR1</name>
        <addressOffset>0x34</addressOffset>
        <size>0x20</size>
        <fields>
          <field>
            <name>CCR1</name>
            <bitOffset>0</bitOffset>
            <bitWidth>16</bitWidth>
          </field>
        </fields>
      </register>
      <register>
        <name>CCR2</name>
        <addressOffset>0x38</addressOffset>
        <size>0x20</size>
        <fields>
          <field>
            <name>CCR2</name>
            <bitOffset>0</bitOffset>
            <bitWidth>16</bitWidth>
          </field>
        </fields>
      </register>
      <register>
        <name>CCR3</name>
        <addressOffset>0x3c</addressOffset>
        <size>0x20</size>
        <fields>
          <field>
            <name>CCR3</name>
            <bitOffset>0</bitOffset>
            <bitWidth>16</bitWidth>
          </field>
        </fields>
      </register>
      <register>
        <name>CCR4</name>
        <addressOffset>0x40</addressOffset>
        <size>0x20</size>
        <fields>
          <field>
            <name>CCR4</name>
            <bitOffset>0</bitOffset>
            <bitWidth>16</bitWidth>
          </field>
        </fields>
      </register>
      <register>
        <name>BDTR</name>
        <addressOffset>0x44</addressOffset>
        <size>0x20</size>
        <fields>
          <field>
            <name>DTG</name>
            <bitOffset>0</bitOffset>
            <bitWidth>8</bitWidth>
          </field>
          <field>
            <name>LOCK</name>
            <bitOffset>8</bitOffset>
            <bitWidth>2</bitWidth>
          </field>
          <field>
            <name>OSSI</name>
            <bitOffset>10</bitOffset>
            <bitWidth>1</bitWidth>
          </field>
          <field>
            <name>OSSR</name>
            <bitOffset>11</bitOffset>
            <bitWidth>1</bitWidth>
          </field>
          <field>
            <name>BKE</name>
            <bitOffset>12</bitOffset>
            <bitWidth>1</bitWidth>
          </field>
          <field>
            <name>BKP</name>
            <bitOffset>13</bitOffset>
            <bitWidth>1</bitWidth>
          </field>
          <field>
            <name>AOE</name>
            <bitOffset>14</bitOffset>
            <bitWidth>1</bitWidth>
          </field>
          <field>
            <name>MOE</name>
            <bitOffset>15</bitOffset>
            <bitWidth>1</bitWidth>
          </field>
        </fields>
      </register>
      <register>
        <name>DCR</name>
        <addressOffset>0x48</addressOffset>
        <size>0x20</size>
        <fields>
          <field>
            <name>DBA</name>
            <bitOffset>0</bitOffset>
            <bitWidth>5</bitWidth>
          </field>
          <field>
            <name>DBL</name>
            <bitOffset>8</bitOffset>
            <bitWidth>5</bitWidth>
          </field>
        </fields>
      </register>
      <register>
        <name>DMAR</name>
        <addressOffset>0x4c</addressOffset>
        <size>0x20</size>
        <fields>
          <field>
            <name>DMAB</name>
            <bitOffset>0</bitOffset>
            <bitWidth>16</bitWidth>
          </field>
        </fields>
      </register>
      <register>
        <name>OR</name>
        <addressOffset>0x50</addressOffset>
        <size>0x20</size>
        <fields>
          <field>
            <name>TI1_RMP</name>
            <bitOffset>0</bitOffset>
            <bitWidth>2</bitWidth>
          </field>
          <field>
            <name>TI4_RMP</name>
            <bitOffset>6</bitOffset>
            <bitWidth>2</bitWidth>
          </field>
          <field>
            <name>ITR1_RMP</name>
            <bitOffset>10</bitOffset>
            <bitWidth>2</bitWidth>
          </field>
        </fields>
      </register>
    </peripheral>
    <peripheral>
      <name>TIM12</name>
      <baseAddress>0x40001800</baseAddress>
      <register>
        <name>CR1</name>
        <addressOffset>0x0</addressOffset>
        <size>0x20</size>
        <fields>
          <field>
            <name>CEN</name>
            <bitOffset>0</bitOffset>
            <bitWidth>1</bitWidth>
          </field>
          <field>
            <name>UDIS</name>
            <bitOffset>1</bitOffset>
            <bitWidth>1</bitWidth>
          </field>
          <field>
            <name>URS</name>
            <bitOffset>2</bitOffset>
            <bitWidth>1</bitWidth>
          </field>
          <field>
            <name>OPM</name>
            <bitOffset>3</bitOffset>
            <bitWidth>1</bitWidth>
          </field>
          <field>
            <name>DIR</name>
            <bitOffset>4</bitOffset>
            <bitWidth>1</bitWidth>
          </field>
          <field>
            <name>CMS</name>
            <bitOffset>5</bitOffset>
            <bitWidth>2</bitWidth>
          </field>
          <field>
            <name>ARPE</name>
            <bitOffset>7</bitOffset>
            <bitWidth>1</bitWidth>
          </field>
          <field>
            <name>CKD</name>
            <bitOffset>8</bitOffset>
            <bitWidth>2</bitWidth>
          </field>
        </fields>
      </register>
      <register>
        <name>CR2</name>
        <addressOffset>0x4</addressOffset>
        <size>0x20</size>
        <fields>
          <field>
            <name>CCPC</name>
            <bitOffset>0</bitOffset>
            <bitWidth>1</bitWidth>
          </field>
          <field>
            <name>CCUS</name>
            <bitOffset>2</bitOffset>
            <bitWidth>1</bitWidth>
          </field>
          <field>
            <name>CCDS</name>
            <bitOffset>3</bitOffset>
            <bitWidth>1</bitWidth>
          </field>
          <field>
            <name>MMS</name>
            <bitOffset>4</bitOffset>
            <bitWidth>3</bitWidth>
          </field>
          <field>
            <name>TI1S</name>
            <bitOffset>7</bitOffset>
            <bitWidth>1</bitWidth>
          </field>
          <field>
            <name>OIS1</name>
            <bitOffset>8</bitOffset>
            <bitWidth>1</bitWidth>
          </field>
          <field>
            <name>OIS1N</name>
            <bitOffset>9</bitOffset>
            <bitWidth>1</bitWidth>
          </field>
          <field>
            <name>OIS2</name>
            <bitOffset>10</bitOffset>
            <bitWidth>1</bitWidth>
          </field>
          <field>
            <name>OIS2N</name>
            <bitOffset>11</bitOffset>
            <bitWidth>1</bitWidth>
          </field>
          <field>
            <name>OIS3</name>
            <bitOffset>12</bitOffset>
            <bitWidth>1</bitWidth>
          </field>
          <field>
            <name>OIS3N</name>
            <bitOffset>13</bitOffset>
            <bitWidth>1</bitWidth>
          </field>
          <field>
            <name>OIS4</name>
            <bitOffset>14</bitOffset>
            <bitWidth>1</bitWidth>
          </field>
        </fields>
      </register>
      <register>
        <name>SMCR</name>
        <addressOffset>0x8</addressOffset>
        <size>0x20</size>
        <fields>
          <field>
            <name>SMS</name>
            <bitOffset>0</bitOffset>
            <bitWidth>3</bitWidth>
          </field>
          <field>
            <name>TS</name>
            <bitOffset>4</bitOffset>
            <bitWidth>3</bitWidth>
          </field>
          <field>
            <name>MSM</name>
            <bitOffset>7</bitOffset>
            <bitWidth>1</bitWidth>
          </field>
          <field>
            <name>ETF</name>
            <bitOffset>8</bitOffset>
            <bitWidth>4</bitWidth>
          </field>
          <field>
            <name>ETPS</name>
            <bitOffset>12</bitOffset>
            <bitWidth>2</bitWidth>
          </field>
          <field>
            <name>ECE</name>
            <bitOffset>14</bitOffset>
            <bitWidth>1</bitWidth>
          </field>
          <field>
            <name>ETP</name>
            <bitOffset>15</bitOffset>
            <bitWidth>1</bitWidth>
          </field>
        </fields>
      </register>
      <register>
        <name>DIER</name>
        <addressOffset>0xc</addressOffset>
        <size>0x20</size>
        <fields>
          <field>
            <name>UIE</name>
            <bitOffset>0</bitOffset>
            <bitWidth>1</bitWidth>
          </field>
          <field>
            <name>CC1IE</name>
            <bitOffset>1</bitOffset>
            <bitWidth>1</bitWidth>
          </field>
          <field>
            <name>CC2IE</name>
            <bitOffset>2</bitOffset>
            <bitWidth>1</bitWidth>
          </field>
          <field>
            <name>CC3IE</name>
            <bitOffset>3</bitOffset>
            <bitWidth>1</bitWidth>
          </field>
          <field>
            <name>CC4IE</name>
            <bitOffset>4</bitOffset>
            <bitWidth>1</bitWidth>
          </field>
          <field>
            <name>COMIE</name>
            <bitOffset>5</bitOffset>
            <bitWidth>1</bitWidth>
          </field>
          <field>
            <name>TIE</name>
            <bitOffset>6</bitOffset>
            <bitWidth>1</bitWidth>
          </field>
          <field>
            <name>BIE</name>
            <bitOffset>7</bitOffset>
            <bitWidth>1</bitWidth>
          </field>
          <field>
            <name>UDE</name>
            <bitOffset>8</bitOffset>
            <bitWidth>1</bitWidth>
          </field>
          <field>
            <name>CC1DE</name>
            <bitOffset>9</bitOffset>
            <bitWidth>1</bitWidth>
          </field>
          <field>
            <name>CC2DE</name>
            <bitOffset>10</bitOffset>
            <bitWidth>1</bitWidth>
          </field>
          <field>
            <name>CC3DE</name>
            <bitOffset>11</bitOffset>
            <bitWidth>1</bitWidth>
          </field>
          <field>
            <name>CC4DE</name>
            <bitOffset>12</bitOffset>
            <bitWidth>1</bitWidth>
          </field>
          <field>
            <name>COMDE</name>
            <bitOffset>13</bitOffset>
            <bitWidth>1</bitWidth>
          </field>
          <field>
            <name>TDE</name>
            <bitOffset>14</bitOffset>
            <bitWidth>1</bitWidth>
          </field>
        </fields>
      </register>
      <register>
        <name>SR</name>
        <addressOffset>0x10</addressOffset>
        <size>0x20</size>
        <fields>
          <field>
            <name>UIF</name>
            <bitOffset>0</bitOffset>
            <bitWidth>1</bitWidth>
          </field>
          <field>
            <name>CC1IF</name>
            <bitOffset>1</bitOffset>
            <bitWidth>1</bitWidth>
          </field>
          <field>
            <name>CC2IF</name>
            <bitOffset>2</bitOffset>
            <bitWidth>1</bitWidth>
          </field>
          <field>
            <name>CC3IF</name>
            <bitOffset>3</bitOffset>
            <bitWidth>1</bitWidth>
          </field>
          <field>
            <name>CC4IF</name>
            <bitOffset>4</bitOffset>
            <bitWidth>1</bitWidth>
          </field>
          <field>
            <name>COMIF</name>
            <bitOffset>5</bitOffset>
            <bitWidth>1</bitWidth>
          </field>
          <field>
            <name>TIF</name>
            <bitOffset>6</bitOffset>
            <bitWidth>1</bitWidth>
          </field>
          <field>
            <name>BIF</name>
            <bitOffset>7</bitOffset>
            <bitWidth>1</bitWidth>
          </field>
          <field>
            <name>CC1OF</name>
            <bitOffset>9</bitOffset>
            <bitWidth>1</bitWidth>
          </field>
          <field>
            <name>CC2OF</name>
            <bitOffset>10</bitOffset>
            <bitWidth>1</bitWidth>
          </field>
          <field>
            <name>CC3OF</name>
            <bitOffset>11</bitOffset>
            <bitWidth>1</bitWidth>
          </field>
          <field>
            <name>CC4OF</name>
            <bitOffset>12</bitOffset>
            <bitWidth>1</bitWidth>
          </field>
        </fields>
      </register>
      <register>
        <name>EGR</name>
        <addressOffset>0x14</addressOffset>
        <size>0x20</size>
        <fields>
          <field>
            <name>UG</name>
            <bitOffset>0</bitOffset>
            <bitWidth>1</bitWidth>
          </field>
          <field>
            <name>CC1G</name>
            <bitOffset>1</bitOffset>
            <bitWidth>1</bitWidth>
          </field>
          <field>
            <name>CC2G</name>
            <bitOffset>2</bitOffset>
            <bitWidth>1</bitWidth>
          </field>
          <field>
            <name>CC3G</name>
            <bitOffset>3</bitOffset>
            <bitWidth>1</bitWidth>
          </field>
          <field>
            <name>CC4G</name>
            <bitOffset>4</bitOffset>
            <bitWidth>1</bitWidth>
          </field>
          <field>
            <name>COMG</name>
            <bitOffset>5</bitOffset>
            <bitWidth>1</bitWidth>
          </field>
          <field>
            <name>TG</name>
            <bitOffset>6</bitOffset>
            <bitWidth>1</bitWidth>
          </field>
          <field>
            <name>BG</name>
            <bitOffset>7</bitOffset>
            <bitWidth>1</bitWidth>
          </field>
        </fields>
      </register>
      <register>
        <name>CCMR1</name>
        <addressOffset>0x18</addressOffset>
        <size>0x20</size>
        <fields>
          <field>
            <name>CC1S</name>
            <bitOffset>0</bitOffset>
            <bitWidth>2</bitWidth>
          </field>
          <field>
            <name>OC1FE</name>
            <bitOffset>2</bitOffset>
            <bitWidth>1</bitWidth>
          </field>
          <field>
            <name>OC1PE</name>
            <bitOffset>3</bitOffset>
            <bitWidth>1</bitWidth>
          </field>
          <field>
            <name>OC1M</name>
            <bitOffset>4</bitOffset>
            <bitWidth>3</bitWidth>
          </field>
          <field>
            <name>OC1CE</name>
            <bitOffset>7</bitOffset>
            <bitWidth>1</bitWidth>
          </field>
          <field>
            <name>CC2S</name>
            <bitOffset>8</bitOffset>
            <bitWidth>2</bitWidth>
          </field>
          <field>
            <name>OC2FE</name>
            <bitOffset>10</bitOffset>
            <bitWidth>1</bitWidth>
          </field>
          <field>
            <name>OC2PE</name>
            <bitOffset>11</bitOffset>
            <bitWidth>1</bitWidth>
          </field>
          <field>
            <name>OC2M</name>
            <bitOffset>12</bitOffset>
            <bitWidth>3</bitWidth>
          </field>
          <field>
            <name>OC2CE</name>
            <bitOffset>15</bitOffset>
            <bitWidth>1</bitWidth>
          </field>
        </fields>
      </register>
      <register>
        <name>CCMR2</name>
        <addressOffset>0x1c</addressOffset>
        <size>0x20</size>
        <fields>
          <field>
            <name>CC3S</name>
            <bitOffset>0</bitOffset>
            <bitWidth>2</bitWidth>
          </field>
          <field>
            <name>OC3FE</name>
            <bitOffset>2</bitOffset>
            <bitWidth>1</bitWidth>
          </field>
          <field>
            <name>OC3PE</name>
            <bitOffset>3</bitOffset>
            <bitWidth>1</bitWidth>
          </field>
          <field>
            <name>OC3M</name>
            <bitOffset>4</bitOffset>
            <bitWidth>3</bitWidth>
          </field>
          <field>
            <name>OC3CE</name>
            <bitOffset>7</bitOffset>
            <bitWidth>1</bitWidth>
          </field>
          <field>
            <name>CC4S</name>
            <bitOffset>8</bitOffset>
            <bitWidth>2</bitWidth>
          </field>
          <field>
            <name>OC4FE</name>
            <bitOffset>10</bitOffset>
            <bitWidth>1</bitWidth>
          </field>
          <field>
            <name>OC4PE</name>
            <bitOffset>11</bitOffset>
            <bitWidth>1</bitWidth>
          </field>
          <field>
            <name>OC4M</name>
            <bitOffset>12</bitOffset>
            <bitWidth>3</bitWidth>
          </field>
          <field>
            <name>OC4CE</name>
            <bitOffset>15</bitOffset>
            <bitWidth>1</bitWidth>
          </field>
        </fields>
      </register>
      <register>
        <name>CCER</name>
        <addressOffset>0x20</addressOffset>
        <size>0x20</size>
        <fields>
          <field>
            <name>CC1E</name>
            <bitOffset>0</bitOffset>
            <bitWidth>1</bitWidth>
          </field>
          <field>
            <name>CC1P</name>
            <bitOffset>1</bitOffset>
            <bitWidth>1</bitWidth>
          </field>
          <field>
            <name>CC1NE</name>
            <bitOffset>2</bitOffset>
            <bitWidth>1</bitWidth>
          </field>
          <field>
            <name>CC1NP</name>
            <bitOffset>3</bitOffset>
            <bitWidth>1</bitWidth>
          </field>
          <field>
            <name>CC2E</name>
            <bitOffset>4</bitOffset>
            <bitWidth>1</bitWidth>
          </field>
          <field>
            <name>CC2P</name>
            <bitOffset>5</bitOffset>
            <bitWidth>1</bitWidth>
          </field>
          <field>
            <name>CC2NE</name>
            <bitOffset>6</bitOffset>
            <bitWidth>1</bitWidth>
          </field>
          <field>
            <name>CC2NP</name>
            <bitOffset>7</bitOffset>
            <bitWidth>1</bitWidth>
          </field>
          <field>
            <name>CC3E</name>
            <bitOffset>8</bitOffset>
            <bitWidth>1</bitWidth>
          </field>
          <field>
            <name>CC3P</name>
            <bitOffset>9</bitOffset>
            <bitWidth>1</bitWidth>
          </field>
          <field>
            <name>CC3NE</name>
            <bitOffset>10</bitOffset>
            <bitWidth>1</bitWidth>
          </field>
          <field>
            <name>CC3NP</name>
            <bitOffset>11</bitOffset>
            <bitWidth>1</bitWidth>
          </field>
          <field>
            <name>CC4E</name>
            <bitOffset>12</bitOffset>
            <bitWidth>1</bitWidth>
          </field>
          <field>
            <name>CC4P</name>
            <bitOffset>13</bitOffset>
            <bitWidth>1</bitWidth>
          </field>
          <field>
            <name>CC4NP</name>
            <bitOffset>15</bitOffset>
            <bitWidth>1</bitWidth>
          </field>
        </fields>
      </register>
      <register>
        <name>CNT</name>
        <addressOffset>0x24</addressOffset>
        <size>0x20</size>
        <fields>
          <field>
            <name>CNT</name>
            <bitOffset>0</bitOffset>
            <bitWidth>32</bitWidth>
          </field>
        </fields>
      </register>
      <register>
        <name>PSC</name>
        <addressOffset>0x28</addressOffset>
        <size>0x20</size>
        <fields>
          <field>
            <name>PSC</name>
            <bitOffset>0</bitOffset>
            <bitWidth>16</bitWidth>
          </field>
        </fields>
      </register>
      <register>
        <name>ARR</name>
        <addressOffset>0x2c</addressOffset>
        <size>0x20</size>
        <fields>
          <field>
            <name>ARR</name>
            <bitOffset>0</bitOffset>
            <bitWidth>32</bitWidth>
          </field>
        </fields>
      </register>
      <register>
        <name>RCR</name>
        <addressOffset>0x30</addressOffset>
        <size>0x20</size>
        <fields>
          <field>
            <name>REP</name>
            <bitOffset>0</bitOffset>
            <bitWidth>8</bitWidth>
          </field>
        </fields>
      </register>
      <register>
        <name>CCR1</name>
        <addressOffset>0x34</addressOffset>
        <size>0x20</size>
        <fields>
          <field>
            <name>CCR1</name>
            <bitOffset>0</bitOffset>
            <bitWidth>16</bitWidth>
          </field>
        </fields>
      </register>
      <register>
        <name>CCR2</name>
        <addressOffset>0x38</addressOffset>
        <size>0x20</size>
        <fields>
          <field>
            <name>CCR2</name>
            <bitOffset>0</bitOffset>
            <bitWidth>16</bitWidth>
          </field>
        </fields>
      </register>
      <register>
        <name>CCR3</name>
        <addressOffset>0x3c</addressOffset>
        <size>0x20</size>
        <fields>
          <field>
            <name>CCR3</name>
            <bitOffset>0</bitOffset>
            <bitWidth>16</bitWidth>
          </field>
        </fields>
      </register>
      <register>
        <name>CCR4</name>
        <addressOffset>0x40</addressOffset>
        <size>0x20</size>
        <fields>
          <field>
            <name>CCR4</name>
            <bitOffset>0</bitOffset>
            <bitWidth>16</bitWidth>
          </field>
        </fields>
      </register>
      <register>
        <name>BDTR</name>
        <addressOffset>0x44</addressOffset>
        <size>0x20</size>
        <fields>
          <field>
            <name>DTG</name>
            <bitOffset>0</bitOffset>
            <bitWidth>8</bitWidth>
          </field>
          <field>
            <name>LOCK</name>
            <bitOffset>8</bitOffset>
            <bitWidth>2</bitWidth>
          </field>
          <field>
            <name>OSSI</name>
            <bitOffset>10</bitOffset>
            <bitWidth>1</bitWidth>
          </field>
          <field>
            <name>OSSR</name>
            <bitOffset>11</bitOffset>
            <bitWidth>1</bitWidth>
          </field>
          <field>
            <name>BKE</name>
            <bitOffset>12</bitOffset>
            <bitWidth>1</bitWidth>
          </field>
          <field>
            <name>BKP</name>
            <bitOffset>13</bitOffset>
            <bitWidth>1</bitWidth>
          </field>
          <field>
            <name>AOE</name>
            <bitOffset>14</bitOffset>
            <bitWidth>1</bitWidth>
          </field>
          <field>
            <name>MOE</name>
            <bitOffset>15</bitOffset>
            <bitWidth>1</bitWidth>
          </field>
        </fields>
      </register>
      <register>
        <name>DCR</name>
        <addressOffset>0x48</addressOffset>
        <size>0x20</size>
        <fields>
          <field>
            <name>DBA</name>
            <bitOffset>0</bitOffset>
            <bitWidth>5</bitWidth>
          </field>
          <field>
            <name>DBL</name>
            <bitOffset>8</bitOffset>
            <bitWidth>5</bitWidth>
          </field>
        </fields>
      </register>
      <register>
        <name>DMAR</name>
        <addressOffset>0x4c</addressOffset>
        <size>0x20</size>
        <fields>
          <field>
            <name>DMAB</name>
            <bitOffset>0</bitOffset>
            <bitWidth>16</bitWidth>
          </field>
        </fields>
      </register>
      <register>
        <name>OR</name>
        <addressOffset>0x50</addressOffset>
        <size>0x20</size>
        <fields>
          <field>
            <name>TI1_RMP</name>
            <bitOffset>0</bitOffset>
            <bitWidth>2</bitWidth>
          </field>
          <field>
            <name>TI4_RMP</name>
            <bitOffset>6</bitOffset>
            <bitWidth>2</bitWidth>
          </field>
          <field>
            <name>ITR1_RMP</name>
            <bitOffset>10</bitOffset>
            <bitWidth>2</bitWidth>
          </field>
        </fields>
      </register>
    </peripheral>
    <peripheral>
      <name>TIM13</name>
      <baseAddress>0x40001c00</baseAddress>
      <register>
        <name>CR1</name>
        <addressOffset>0x0</addressOffset>
        <size>0x20</size>
        <fields>
          <field>
            <name>CEN</name>
            <bitOffset>0</bitOffset>
            <bitWidth>1</bitWidth>
          </field>
          <field>
            <name>UDIS</name>
            <bitOffset>1</bitOffset>
            <bitWidth>1</bitWidth>
          </field>
          <field>
            <name>URS</name>
            <bitOffset>2</bitOffset>
            <bitWidth>1</bitWidth>
          </field>
          <field>
            <name>OPM</name>
            <bitOffset>3</bitOffset>
            <bitWidth>1</bitWidth>
          </field>
          <field>
            <name>DIR</name>
            <bitOffset>4</bitOffset>
            <bitWidth>1</bitWidth>
          </field>
          <field>
            <name>CMS</name>
            <bitOffset>5</bitOffset>
            <bitWidth>2</bitWidth>
          </field>
          <field>
            <name>ARPE</name>
            <bitOffset>7</bitOffset>
            <bitWidth>1</bitWidth>
          </field>
          <field>
            <name>CKD</name>
            <bitOffset>8</bitOffset>
            <bitWidth>2</bitWidth>
          </field>
        </fields>
      </register>
      <register>
        <name>CR2</name>
        <addressOffset>0x4</addressOffset>
        <size>0x20</size>
        <fields>
          <field>
            <name>CCPC</name>
            <bitOffset>0</bitOffset>
            <bitWidth>1</bitWidth>
          </field>
          <field>
            <name>CCUS</name>
            <bitOffset>2</bitOffset>
            <bitWidth>1</bitWidth>
          </field>
          <field>
            <name>CCDS</name>
            <bitOffset>3</bitOffset>
            <bitWidth>1</bitWidth>
          </field>
          <field>
            <name>MMS</name>
            <bitOffset>4</bitOffset>
            <bitWidth>3</bitWidth>
          </field>
          <field>
            <name>TI1S</name>
            <bitOffset>7</bitOffset>
            <bitWidth>1</bitWidth>
          </field>
          <field>
            <name>OIS1</name>
            <bitOffset>8</bitOffset>
            <bitWidth>1</bitWidth>
          </field>
          <field>
            <name>OIS1N</name>
            <bitOffset>9</bitOffset>
            <bitWidth>1</bitWidth>
          </field>
          <field>
            <name>OIS2</name>
            <bitOffset>10</bitOffset>
            <bitWidth>1</bitWidth>
          </field>
          <field>
            <name>OIS2N</name>
            <bitOffset>11</bitOffset>
            <bitWidth>1</bitWidth>
          </field>
          <field>
            <name>OIS3</name>
            <bitOffset>12</bitOffset>
            <bitWidth>1</bitWidth>
          </field>
          <field>
            <name>OIS3N</name>
            <bitOffset>13</bitOffset>
            <bitWidth>1</bitWidth>
          </field>
          <field>
            <name>OIS4</name>
            <bitOffset>14</bitOffset>
            <bitWidth>1</bitWidth>
          </field>
        </fields>
      </register>
      <register>
        <name>SMCR</name>
        <addressOffset>0x8</addressOffset>
        <size>0x20</size>
        <fields>
          <field>
            <name>SMS</name>
            <bitOffset>0</bitOffset>
            <bitWidth>3</bitWidth>
          </field>
          <field>
            <name>TS</name>
            <bitOffset>4</bitOffset>
            <bitWidth>3</bitWidth>
          </field>
          <field>
            <name>MSM</name>
            <bitOffset>7</bitOffset>
            <bitWidth>1</bitWidth>
          </field>
          <field>
            <name>ETF</name>
            <bitOffset>8</bitOffset>
            <bitWidth>4</bitWidth>
          </field>
          <field>
            <name>ETPS</name>
            <bitOffset>12</bitOffset>
            <bitWidth>2</bitWidth>
          </field>
          <field>
            <name>ECE</name>
            <bitOffset>14</bitOffset>
            <bitWidth>1</bitWidth>
          </field>
          <field>
            <name>ETP</name>
            <bitOffset>15</bitOffset>
            <bitWidth>1</bitWidth>
          </field>
        </fields>
      </register>
      <register>
        <name>DIER</name>
        <addressOffset>0xc</addressOffset>
        <size>0x20</size>
        <fields>
          <field>
            <name>UIE</name>
            <bitOffset>0</bitOffset>
            <bitWidth>1</bitWidth>
          </field>
          <field>
            <name>CC1IE</name>
            <bitOffset>1</bitOffset>
            <bitWidth>1</bitWidth>
          </field>
          <field>
            <name>CC2IE</name>
            <bitOffset>2</bitOffset>
            <bitWidth>1</bitWidth>
          </field>
          <field>
            <name>CC3IE</name>
            <bitOffset>3</bitOffset>
            <bitWidth>1</bitWidth>
          </field>
          <field>
            <name>CC4IE</name>
            <bitOffset>4</bitOffset>
            <bitWidth>1</bitWidth>
          </field>
          <field>
            <name>COMIE</name>
            <bitOffset>5</bitOffset>
            <bitWidth>1</bitWidth>
          </field>
          <field>
            <name>TIE</name>
            <bitOffset>6</bitOffset>
            <bitWidth>1</bitWidth>
          </field>
          <field>
            <name>BIE</name>
            <bitOffset>7</bitOffset>
            <bitWidth>1</bitWidth>
          </field>
          <field>
            <name>UDE</name>
            <bitOffset>8</bitOffset>
            <bitWidth>1</bitWidth>
          </field>
          <field>
            <name>CC1DE</name>
            <bitOffset>9</bitOffset>
            <bitWidth>1</bitWidth>
          </field>
          <field>
            <name>CC2DE</name>
            <bitOffset>10</bitOffset>
            <bitWidth>1</bitWidth>
          </field>
          <field>
            <name>CC3DE</name>
            <bitOffset>11</bitOffset>
            <bitWidth>1</bitWidth>
          </field>
          <field>
            <name>CC4DE</name>
            <bitOffset>12</bitOffset>
            <bitWidth>1</bitWidth>
          </field>
          <field>
            <name>COMDE</name>
            <bitOffset>13</bitOffset>
            <bitWidth>1</bitWidth>
          </field>
          <field>
            <name>TDE</name>
            <bitOffset>14</bitOffset>
            <bitWidth>1</bitWidth>
          </field>
        </fields>
      </register>
      <register>
        <name>SR</name>
        <addressOffset>0x10</addressOffset>
        <size>0x20</size>
        <fields>
          <field>
            <name>UIF</name>
            <bitOffset>0</bitOffset>
            <bitWidth>1</bitWidth>
          </field>
          <field>
            <name>CC1IF</name>
            <bitOffset>1</bitOffset>
            <bitWidth>1</bitWidth>
          </field>
          <field>
            <name>CC2IF</name>
            <bitOffset>2</bitOffset>
            <bitWidth>1</bitWidth>
          </field>
          <field>
            <name>CC3IF</name>
            <bitOffset>3</bitOffset>
            <bitWidth>1</bitWidth>
          </field>
          <field>
            <name>CC4IF</name>
            <bitOffset>4</bitOffset>
            <bitWidth>1</bitWidth>
          </field>
          <field>
            <name>COMIF</name>
            <bitOffset>5</bitOffset>
            <bitWidth>1</bitWidth>
          </field>
          <field>
            <name>TIF</name>
            <bitOffset>6</bitOffset>
            <bitWidth>1</bitWidth>
          </field>
          <field>
            <name>BIF</name>
            <bitOffset>7</bitOffset>
            <bitWidth>1</bitWidth>
          </field>
          <field>
            <name>CC1OF</name>
            <bitOffset>9</bitOffset>
            <bitWidth>1</bitWidth>
          </field>
          <field>
            <name>CC2OF</name>
            <bitOffset>10</bitOffset>
            <bitWidth>1</bitWidth>
          </field>
          <field>
            <name>CC3OF</name>
            <bitOffset>11</bitOffset>
            <bitWidth>1</bitWidth>
          </field>
          <field>
            <name>CC4OF</name>
            <bitOffset>12</bitOffset>
            <bitWidth>1</bitWidth>
          </field>
        </fields>
      </register>
      <register>
        <name>EGR</name>
        <addressOffset>0x14</addressOffset>
        <size>0x20</size>
        <fields>
          <field>
            <name>UG</name>
            <bitOffset>0</bitOffset>
            <bitWidth>1</bitWidth>
          </field>
          <field>
            <name>CC1G</name>
            <bitOffset>1</bitOffset>
            <bitWidth>1</bitWidth>
          </field>
          <field>
            <name>CC2G</name>
            <bitOffset>2</bitOffset>
            <bitWidth>1</bitWidth>
          </field>
          <field>
            <name>CC3G</name>
            <bitOffset>3</bitOffset>
            <bitWidth>1</bitWidth>
          </field>
          <field>
            <name>CC4G</name>
            <bitOffset>4</bitOffset>
            <bitWidth>1</bitWidth>
          </field>
          <field>
            <name>COMG</name>
            <bitOffset>5</bitOffset>
            <bitWidth>1</bitWidth>
          </field>
          <field>
            <name>TG</name>
            <bitOffset>6</bitOffset>
            <bitWidth>1</bitWidth>
          </field>
          <field>
            <name>BG</name>
            <bitOffset>7</bitOffset>
            <bitWidth>1</bitWidth>
          </field>
        </fields>
      </register>
      <register>
        <name>CCMR1</name>
        <addressOffset>0x18</addressOffset>
        <size>0x20</size>
        <fields>
          <field>
            <name>CC1S</name>
            <bitOffset>0</bitOffset>
            <bitWidth>2</bitWidth>
          </field>
          <field>
            <name>OC1FE</name>
            <bitOffset>2</bitOffset>
            <bitWidth>1</bitWidth>
          </field>
          <field>
            <name>OC1PE</name>
            <bitOffset>3</bitOffset>
            <bitWidth>1</bitWidth>
          </field>
          <field>
            <name>OC1M</name>
            <bitOffset>4</bitOffset>
            <bitWidth>3</bitWidth>
          </field>
          <field>
            <name>OC1CE</name>
            <bitOffset>7</bitOffset>
            <bitWidth>1</bitWidth>
          </field>
          <field>
            <name>CC2S</name>
            <bitOffset>8</bitOffset>
            <bitWidth>2</bitWidth>
          </field>
          <field>
            <name>OC2FE</name>
            <bitOffset>10</bitOffset>
            <bitWidth>1</bitWidth>
          </field>
          <field>
            <name>OC2PE</name>
            <bitOffset>11</bitOffset>
            <bitWidth>1</bitWidth>
          </field>
          <field>
            <name>OC2M</name>
            <bitOffset>12</bitOffset>
            <bitWidth>3</bitWidth>
          </field>
          <field>
            <name>OC2CE</name>
            <bitOffset>15</bitOffset>
            <bitWidth>1</bitWidth>
          </field>
        </fields>
      </register>
      <register>
        <name>CCMR2</name>
        <addressOffset>0x1c</addressOffset>
        <size>0x20</size>
        <fields>
          <field>
            <name>CC3S</name>
            <bitOffset>0</bitOffset>
            <bitWidth>2</bitWidth>
          </field>
          <field>
            <name>OC3FE</name>
            <bitOffset>2</bitOffset>
            <bitWidth>1</bitWidth>
          </field>
          <field>
            <name>OC3PE</name>
            <bitOffset>3</bitOffset>
            <bitWidth>1</bitWidth>
          </field>
          <field>
            <name>OC3M</name>
            <bitOffset>4</bitOffset>
            <bitWidth>3</bitWidth>
          </field>
          <field>
            <name>OC3CE</name>
            <bitOffset>7</bitOffset>
            <bitWidth>1</bitWidth>
          </field>
          <field>
            <name>CC4S</name>
            <bitOffset>8</bitOffset>
            <bitWidth>2</bitWidth>
          </field>
          <field>
            <name>OC4FE</name>
            <bitOffset>10</bitOffset>
            <bitWidth>1</bitWidth>
          </field>
          <field>
            <name>OC4PE</name>
            <bitOffset>11</bitOffset>
            <bitWidth>1</bitWidth>
          </field>
          <field>
            <name>OC4M</name>
            <bitOffset>12</bitOffset>
            <bitWidth>3</bitWidth>
          </field>
          <field>
            <name>OC4CE</name>
            <bitOffset>15</bitOffset>
            <bitWidth>1</bitWidth>
          </field>
        </fields>
      </register>
      <register>
        <name>CCER</name>
        <addressOffset>0x20</addressOffset>
        <size>0x20</size>
        <fields>
          <field>
            <name>CC1E</name>
            <bitOffset>0</bitOffset>
            <bitWidth>1</bitWidth>
          </field>
          <field>
            <name>CC1P</name>
            <bitOffset>1</bitOffset>
            <bitWidth>1</bitWidth>
          </field>
          <field>
            <name>CC1NE</name>
            <bitOffset>2</bitOffset>
            <bitWidth>1</bitWidth>
          </field>
          <field>
            <name>CC1NP</name>
            <bitOffset>3</bitOffset>
            <bitWidth>1</bitWidth>
          </field>
          <field>
            <name>CC2E</name>
            <bitOffset>4</bitOffset>
            <bitWidth>1</bitWidth>
          </field>
          <field>
            <name>CC2P</name>
            <bitOffset>5</bitOffset>
            <bitWidth>1</bitWidth>
          </field>
          <field>
            <name>CC2NE</name>
            <bitOffset>6</bitOffset>
            <bitWidth>1</bitWidth>
          </field>
          <field>
            <name>CC2NP</name>
            <bitOffset>7</bitOffset>
            <bitWidth>1</bitWidth>
          </field>
          <field>
            <name>CC3E</name>
            <bitOffset>8</bitOffset>
            <bitWidth>1</bitWidth>
          </field>
          <field>
            <name>CC3P</name>
            <bitOffset>9</bitOffset>
            <bitWidth>1</bitWidth>
          </field>
          <field>
            <name>CC3NE</name>
            <bitOffset>10</bitOffset>
            <bitWidth>1</bitWidth>
          </field>
          <field>
            <name>CC3NP</name>
            <bitOffset>11</bitOffset>
            <bitWidth>1</bitWidth>
          </field>
          <field>
            <name>CC4E</name>
            <bitOffset>12</bitOffset>
            <bitWidth>1</bitWidth>
          </field>
          <field>
            <name>CC4P</name>
            <bitOffset>13</bitOffset>
            <bitWidth>1</bitWidth>
          </field>
          <field>
            <name>CC4NP</name>
            <bitOffset>15</bitOffset>
            <bitWidth>1</bitWidth>
          </field>
        </fields>
      </register>
      <register>
        <name>CNT</name>
        <addressOffset>0x24</addressOffset>
        <size>0x20</size>
        <fields>
          <field>
            <name>CNT</name>
            <bitOffset>0</bitOffset>
            <bitWidth>32</bitWidth>
          </field>
        </fields>
      </register>
      <register>
        <name>PSC</name>
        <addressOffset>0x28</addressOffset>
        <size>0x20</size>
        <fields>
          <field>
            <name>PSC</name>
            <bitOffset>0</bitOffset>
            <bitWidth>16</bitWidth>
          </field>
        </fields>
      </register>
      <register>
        <name>ARR</name>
        <addressOffset>0x2c</addressOffset>
        <size>0x20</size>
        <fields>
          <field>
            <name>ARR</name>
            <bitOffset>0</bitOffset>
            <bitWidth>32</bitWidth>
          </field>
        </fields>
      </register>
      <register>
        <name>RCR</name>
        <addressOffset>0x30</addressOffset>
        <size>0x20</size>
        <fields>
          <field>
            <name>REP</name>
            <bitOffset>0</bitOffset>
            <bitWidth>8</bitWidth>
          </field>
        </fields>
      </register>
      <register>
        <name>CCR1</name>
        <addressOffset>0x34</addressOffset>
        <size>0x20</size>
        <fields>
          <field>
            <name>CCR1</name>
            <bitOffset>0</bitOffset>
            <bitWidth>16</bitWidth>
          </field>
        </fields>
      </register>
      <register>
        <name>CCR2</name>
        <addressOffset>0x38</addressOffset>
        <size>0x20</size>
        <fields>
          <field>
            <name>CCR2</name>
            <bitOffset>0</bitOffset>
            <bitWidth>16</bitWidth>
          </field>
        </fields>
      </register>
      <register>
        <name>CCR3</name>
        <addressOffset>0x3c</addressOffset>
        <size>0x20</size>
        <fields>
          <field>
            <name>CCR3</name>
            <bitOffset>0</bitOffset>
            <bitWidth>16</bitWidth>
          </field>
        </fields>
      </register>
      <register>
        <name>CCR4</name>
        <addressOffset>0x40</addressOffset>
        <size>0x20</size>
        <fields>
          <field>
            <name>CCR4</name>
            <bitOffset>0</bitOffset>
            <bitWidth>16</bitWidth>
          </field>
        </fields>
      </register>
      <register>
        <name>BDTR</name>
        <addressOffset>0x44</addressOffset>
        <size>0x20</size>
        <fields>
          <field>
            <name>DTG</name>
            <bitOffset>0</bitOffset>
            <bitWidth>8</bitWidth>
          </field>
          <field>
            <name>LOCK</name>
            <bitOffset>8</bitOffset>
            <bitWidth>2</bitWidth>
          </field>
          <field>
            <name>OSSI</name>
            <bitOffset>10</bitOffset>
            <bitWidth>1</bitWidth>
          </field>
          <field>
            <name>OSSR</name>
            <bitOffset>11</bitOffset>
            <bitWidth>1</bitWidth>
          </field>
          <field>
            <name>BKE</name>
            <bitOffset>12</bitOffset>
            <bitWidth>1</bitWidth>
          </field>
          <field>
            <name>BKP</name>
            <bitOffset>13</bitOffset>
            <bitWidth>1</bitWidth>
          </field>
          <field>
            <name>AOE</name>
            <bitOffset>14</bitOffset>
            <bitWidth>1</bitWidth>
          </field>
          <field>
            <name>MOE</name>
            <bitOffset>15</bitOffset>
            <bitWidth>1</bitWidth>
          </field>
        </fields>
      </register>
      <register>
        <name>DCR</name>
        <addressOffset>0x48</addressOffset>
        <size>0x20</size>
        <fields>
          <field>
            <name>DBA</name>
            <bitOffset>0</bitOffset>
            <bitWidth>5</bitWidth>
          </field>
          <field>
            <name>DBL</name>
            <bitOffset>8</bitOffset>
            <bitWidth>5</bitWidth>
          </field>
        </fields>
      </register>
      <register>
        <name>DMAR</name>
        <addressOffset>0x4c</addressOffset>
        <size>0x20</size>
        <fields>
          <field>
            <name>DMAB</name>
            <bitOffset>0</bitOffset>
            <bitWidth>16</bitWidth>
          </field>
        </fields>
      </register>
      <register>
        <name>OR</name>
        <addressOffset>0x50</addressOffset>
        <size>0x20</size>
        <fields>
          <field>
            <name>TI1_RMP</name>
            <bitOffset>0</bitOffset>
            <bitWidth>2</bitWidth>
          </field>
          <field>
            <name>TI4_RMP</name>
            <bitOffset>6</bitOffset>
            <bitWidth>2</bitWidth>
          </field>
          <field>
            <name>ITR1_RMP</name>
            <bitOffset>10</bitOffset>
            <bitWidth>2</bitWidth>
          </field>
        </fields>
      </register>
    </peripheral>
    <peripheral>
      <name>TIM14</name>
      <baseAddress>0x40002000</baseAddress>
      <register>
        <name>CR1</name>
        <addressOffset>0x0</addressOffset>
        <size>0x20</size>
        <fields>
          <field>
            <name>CEN</name>
            <bitOffset>0</bitOffset>
            <bitWidth>1</bitWidth>
          </field>
          <field>
            <name>UDIS</name>
            <bitOffset>1</bitOffset>
            <bitWidth>1</bitWidth>
          </field>
          <field>
            <name>URS</name>
            <bitOffset>2</bitOffset>
            <bitWidth>1</bitWidth>
          </field>
          <field>
            <name>OPM</name>
            <bitOffset>3</bitOffset>
            <bitWidth>1</bitWidth>
          </field>
          <field>
            <name>DIR</name>
            <bitOffset>4</bitOffset>
            <bitWidth>1</bitWidth>
          </field>
          <field>
            <name>CMS</name>
            <bitOffset>5</bitOffset>
            <bitWidth>2</bitWidth>
          </field>
          <field>
            <name>ARPE</name>
            <bitOffset>7</bitOffset>
            <bitWidth>1</bitWidth>
          </field>
          <field>
            <name>CKD</name>
            <bitOffset>8</bitOffset>
            <bitWidth>2</bitWidth>
          </field>
        </fields>
      </register>
      <register>
        <name>CR2</name>
        <addressOffset>0x4</addressOffset>
        <size>0x20</size>
        <fields>
          <field>
            <name>CCPC</name>
            <bitOffset>0</bitOffset>
            <bitWidth>1</bitWidth>
          </field>
          <field>
            <name>CCUS</name>
            <bitOffset>2</bitOffset>
            <bitWidth>1</bitWidth>
          </field>
          <field>
            <name>CCDS</name>
            <bitOffset>3</bitOffset>
            <bitWidth>1</bitWidth>
          </field>
          <field>
            <name>MMS</name>
            <bitOffset>4</bitOffset>
            <bitWidth>3</bitWidth>
          </field>
          <field>
            <name>TI1S</name>
            <bitOffset>7</bitOffset>
            <bitWidth>1</bitWidth>
          </field>
          <field>
            <name>OIS1</name>
            <bitOffset>8</bitOffset>
            <bitWidth>1</bitWidth>
          </field>
          <field>
            <name>OIS1N</name>
            <bitOffset>9</bitOffset>
            <bitWidth>1</bitWidth>
          </field>
          <field>
            <name>OIS2</name>
            <bitOffset>10</bitOffset>
            <bitWidth>1</bitWidth>
          </field>
          <field>
            <name>OIS2N</name>
            <bitOffset>11</bitOffset>
            <bitWidth>1</bitWidth>
          </field>
          <field>
            <name>OIS3</name>
            <bitOffset>12</bitOffset>
            <bitWidth>1</bitWidth>
          </field>
          <field>
            <name>OIS3N</name>
            <bitOffset>13</bitOffset>
            <bitWidth>1</bitWidth>
          </field>
          <field>
            <name>OIS4</name>
            <bitOffset>14</bitOffset>
            <bitWidth>1</bitWidth>
          </field>
        </fields>
      </register>
      <register>
        <name>SMCR</name>
        <addressOffset>0x8</addressOffset>
        <size>0x20</size>
        <fields>
          <field>
            <name>SMS</name>
            <bitOffset>0</bitOffset>
            <bitWidth>3</bitWidth>
          </field>
          <field>
            <name>TS</name>
            <bitOffset>4</bitOffset>
            <bitWidth>3</bitWidth>
          </field>
          <field>
            <name>MSM</name>
            <bitOffset>7</bitOffset>
            <bitWidth>1</bitWidth>
          </field>
          <field>
            <name>ETF</name>
            <bitOffset>8</bitOffset>
            <bitWidth>4</bitWidth>
          </field>
          <field>
            <name>ETPS</name>
            <bitOffset>12</bitOffset>
            <bitWidth>2</bitWidth>
          </field>
          <field>
            <name>ECE</name>
            <bitOffset>14</bitOffset>
            <bitWidth>1</bitWidth>
          </field>
          <field>
            <name>ETP</name>
            <bitOffset>15</bitOffset>
            <bitWidth>1</bitWidth>
          </field>
        </fields>
      </register>
      <register>
        <name>DIER</name>
        <addressOffset>0xc</addressOffset>
        <size>0x20</size>
        <fields>
          <field>
            <name>UIE</name>
            <bitOffset>0</bitOffset>
            <bitWidth>1</bitWidth>
          </field>
          <field>
            <name>CC1IE</name>
            <bitOffset>1</bitOffset>
            <bitWidth>1</bitWidth>
          </field>
          <field>
            <name>CC2IE</name>
            <bitOffset>2</bitOffset>
            <bitWidth>1</bitWidth>
          </field>
          <field>
            <name>CC3IE</name>
            <bitOffset>3</bitOffset>
            <bitWidth>1</bitWidth>
          </field>
          <field>
            <name>CC4IE</name>
            <bitOffset>4</bitOffset>
            <bitWidth>1</bitWidth>
          </field>
          <field>
            <name>COMIE</name>
            <bitOffset>5</bitOffset>
            <bitWidth>1</bitWidth>
          </field>
          <field>
            <name>TIE</name>
            <bitOffset>6</bitOffset>
            <bitWidth>1</bitWidth>
          </field>
          <field>
            <name>BIE</name>
            <bitOffset>7</bitOffset>
            <bitWidth>1</bitWidth>
          </field>
          <field>
            <name>UDE</name>
            <bitOffset>8</bitOffset>
            <bitWidth>1</bitWidth>
          </field>
          <field>
            <name>CC1DE</name>
            <bitOffset>9</bitOffset>
            <bitWidth>1</bitWidth>
          </field>
          <field>
            <name>CC2DE</name>
            <bitOffset>10</bitOffset>
            <bitWidth>1</bitWidth>
          </field>
          <field>
            <name>CC3DE</name>
            <bitOffset>11</bitOffset>
            <bitWidth>1</bitWidth>
          </field>
          <field>
            <name>CC4DE</name>
            <bitOffset>12</bitOffset>
            <bitWidth>1</bitWidth>
          </field>
          <field>
            <name>COMDE</name>
            <bitOffset>13</bitOffset>
            <bitWidth>1</bitWidth>
          </field>
          <field>
            <name>TDE</name>
            <bitOffset>14</bitOffset>
            <bitWidth>1</bitWidth>
          </field>
        </fields>
      </register>
      <register>
        <name>SR</name>
        <addressOffset>0x10</addressOffset>
        <size>0x20</size>
        <fields>
          <field>
            <name>UIF</name>
            <bitOffset>0</bitOffset>
            <bitWidth>1</bitWidth>
          </field>
          <field>
            <name>CC1IF</name>
            <bitOffset>1</bitOffset>
            <bitWidth>1</bitWidth>
          </field>
          <field>
            <name>CC2IF</name>
            <bitOffset>2</bitOffset>
            <bitWidth>1</bitWidth>
          </field>
          <field>
            <name>CC3IF</name>
            <bitOffset>3</bitOffset>
            <bitWidth>1</bitWidth>
          </field>
          <field>
            <name>CC4IF</name>
            <bitOffset>4</bitOffset>
            <bitWidth>1</bitWidth>
          </field>
          <field>
            <name>COMIF</name>
            <bitOffset>5</bitOffset>
            <bitWidth>1</bitWidth>
          </field>
          <field>
            <name>TIF</name>
            <bitOffset>6</bitOffset>
            <bitWidth>1</bitWidth>
          </field>
          <field>
            <name>BIF</name>
            <bitOffset>7</bitOffset>
            <bitWidth>1</bitWidth>
          </field>
          <field>
            <name>CC1OF</name>
            <bitOffset>9</bitOffset>
            <bitWidth>1</bitWidth>
          </field>
          <field>
            <name>CC2OF</name>
            <bitOffset>10</bitOffset>
            <bitWidth>1</bitWidth>
          </field>
          <field>
            <name>CC3OF</name>
            <bitOffset>11</bitOffset>
            <bitWidth>1</bitWidth>
          </field>
          <field>
            <name>CC4OF</name>
            <bitOffset>12</bitOffset>
            <bitWidth>1</bitWidth>
          </field>
        </fields>
      </register>
      <register>
        <name>EGR</name>
        <addressOffset>0x14</addressOffset>
        <size>0x20</size>
        <fields>
          <field>
            <name>UG</name>
            <bitOffset>0</bitOffset>
            <bitWidth>1</bitWidth>
          </field>
          <field>
            <name>CC1G</name>
            <bitOffset>1</bitOffset>
            <bitWidth>1</bitWidth>
          </field>
          <field>
            <name>CC2G</name>
            <bitOffset>2</bitOffset>
            <bitWidth>1</bitWidth>
          </field>
          <field>
            <name>CC3G</name>
            <bitOffset>3</bitOffset>
            <bitWidth>1</bitWidth>
          </field>
          <field>
            <name>CC4G</name>
            <bitOffset>4</bitOffset>
            <bitWidth>1</bitWidth>
          </field>
          <field>
            <name>COMG</name>
            <bitOffset>5</bitOffset>
            <bitWidth>1</bitWidth>
          </field>
          <field>
            <name>TG</name>
            <bitOffset>6</bitOffset>
            <bitWidth>1</bitWidth>
          </field>
          <field>
            <name>BG</name>
            <bitOffset>7</bitOffset>
            <bitWidth>1</bitWidth>
          </field>
        </fields>
      </register>
      <register>
        <name>CCMR1</name>
        <addressOffset>0x18</addressOffset>
        <size>0x20</size>
        <fields>
          <field>
            <name>CC1S</name>
            <bitOffset>0</bitOffset>
            <bitWidth>2</bitWidth>
          </field>
          <field>
            <name>OC1FE</name>
            <bitOffset>2</bitOffset>
            <bitWidth>1</bitWidth>
          </field>
          <field>
            <name>OC1PE</name>
            <bitOffset>3</bitOffset>
            <bitWidth>1</bitWidth>
          </field>
          <field>
            <name>OC1M</name>
            <bitOffset>4</bitOffset>
            <bitWidth>3</bitWidth>
          </field>
          <field>
            <name>OC1CE</name>
            <bitOffset>7</bitOffset>
            <bitWidth>1</bitWidth>
          </field>
          <field>
            <name>CC2S</name>
            <bitOffset>8</bitOffset>
            <bitWidth>2</bitWidth>
          </field>
          <field>
            <name>OC2FE</name>
            <bitOffset>10</bitOffset>
            <bitWidth>1</bitWidth>
          </field>
          <field>
            <name>OC2PE</name>
            <bitOffset>11</bitOffset>
            <bitWidth>1</bitWidth>
          </field>
          <field>
            <name>OC2M</name>
            <bitOffset>12</bitOffset>
            <bitWidth>3</bitWidth>
          </field>
          <field>
            <name>OC2CE</name>
            <bitOffset>15</bitOffset>
            <bitWidth>1</bitWidth>
          </field>
        </fields>
      </register>
      <register>
        <name>CCMR2</name>
        <addressOffset>0x1c</addressOffset>
        <size>0x20</size>
        <fields>
          <field>
            <name>CC3S</name>
            <bitOffset>0</bitOffset>
            <bitWidth>2</bitWidth>
          </field>
          <field>
            <name>OC3FE</name>
            <bitOffset>2</bitOffset>
            <bitWidth>1</bitWidth>
          </field>
          <field>
            <name>OC3PE</name>
            <bitOffset>3</bitOffset>
            <bitWidth>1</bitWidth>
          </field>
          <field>
            <name>OC3M</name>
            <bitOffset>4</bitOffset>
            <bitWidth>3</bitWidth>
          </field>
          <field>
            <name>OC3CE</name>
            <bitOffset>7</bitOffset>
            <bitWidth>1</bitWidth>
          </field>
          <field>
            <name>CC4S</name>
            <bitOffset>8</bitOffset>
            <bitWidth>2</bitWidth>
          </field>
          <field>
            <name>OC4FE</name>
            <bitOffset>10</bitOffset>
            <bitWidth>1</bitWidth>
          </field>
          <field>
            <name>OC4PE</name>
            <bitOffset>11</bitOffset>
            <bitWidth>1</bitWidth>
          </field>
          <field>
            <name>OC4M</name>
            <bitOffset>12</bitOffset>
            <bitWidth>3</bitWidth>
          </field>
          <field>
            <name>OC4CE</name>
            <bitOffset>15</bitOffset>
            <bitWidth>1</bitWidth>
          </field>
        </fields>
      </register>
      <register>
        <name>CCER</name>
        <addressOffset>0x20</addressOffset>
        <size>0x20</size>
        <fields>
          <field>
            <name>CC1E</name>
            <bitOffset>0</bitOffset>
            <bitWidth>1</bitWidth>
          </field>
          <field>
            <name>CC1P</name>
            <bitOffset>1</bitOffset>
            <bitWidth>1</bitWidth>
          </field>
          <field>
            <name>CC1NE</name>
            <bitOffset>2</bitOffset>
            <bitWidth>1</bitWidth>
          </field>
          <field>
            <name>CC1NP</name>
            <bitOffset>3</bitOffset>
            <bitWidth>1</bitWidth>
          </field>
          <field>
            <name>CC2E</name>
            <bitOffset>4</bitOffset>
            <bitWidth>1</bitWidth>
          </field>
          <field>
            <name>CC2P</name>
            <bitOffset>5</bitOffset>
            <bitWidth>1</bitWidth>
          </field>
          <field>
            <name>CC2NE</name>
            <bitOffset>6</bitOffset>
            <bitWidth>1</bitWidth>
          </field>
          <field>
            <name>CC2NP</name>
            <bitOffset>7</bitOffset>
            <bitWidth>1</bitWidth>
          </field>
          <field>
            <name>CC3E</name>
            <bitOffset>8</bitOffset>
            <bitWidth>1</bitWidth>
          </field>
          <field>
            <name>CC3P</name>
            <bitOffset>9</bitOffset>
            <bitWidth>1</bitWidth>
          </field>
          <field>
            <name>CC3NE</name>
            <bitOffset>10</bitOffset>
            <bitWidth>1</bitWidth>
          </field>
          <field>
            <name>CC3NP</name>
            <bitOffset>11</bitOffset>
            <bitWidth>1</bitWidth>
          </field>
          <field>
            <name>CC4E</name>
            <bitOffset>12</bitOffset>
            <bitWidth>1</bitWidth>
          </field>
          <field>
            <name>CC4P</name>
            <bitOffset>13</bitOffset>
            <bitWidth>1</bitWidth>
          </field>
          <field>
            <name>CC4NP</name>
            <bitOffset>15</bitOffset>
            <bitWidth>1</bitWidth>
          </field>
        </fields>
      </register>
      <register>
        <name>CNT</name>
        <addressOffset>0x24</addressOffset>
        <size>0x20</size>
        <fields>
          <field>
            <name>CNT</name>
            <bitOffset>0</bitOffset>
            <bitWidth>32</bitWidth>
          </field>
        </fields>
      </register>
      <register>
        <name>PSC</name>
        <addressOffset>0x28</addressOffset>
        <size>0x20</size>
        <fields>
          <field>
            <name>PSC</name>
            <bitOffset>0</bitOffset>
            <bitWidth>16</bitWidth>
          </field>
        </fields>
      </register>
      <register>
        <name>ARR</name>
        <addressOffset>0x2c</addressOffset>
        <size>0x20</size>
        <fields>
          <field>
            <name>ARR</name>
            <bitOffset>0</bitOffset>
            <bitWidth>32</bitWidth>
          </field>
        </fields>
      </register>
      <register>
        <name>RCR</name>
        <addressOffset>0x30</addressOffset>
        <size>0x20</size>
        <fields>
          <field>
            <name>REP</name>
            <bitOffset>0</bitOffset>
            <bitWidth>8</bitWidth>
          </field>
        </fields>
      </register>
      <register>
        <name>CCR1</name>
        <addressOffset>0x34</addressOffset>
        <size>0x20</size>
        <fields>
          <field>
            <name>CCR1</name>
            <bitOffset>0</bitOffset>
            <bitWidth>16</bitWidth>
          </field>
        </fields>
      </register>
      <register>
        <name>CCR2</name>
        <addressOffset>0x38</addressOffset>
        <size>0x20</size>
        <fields>
          <field>
            <name>CCR2</name>
            <bitOffset>0</bitOffset>
            <bitWidth>16</bitWidth>
          </field>
        </fields>
      </register>
      <register>
        <name>CCR3</name>
        <addressOffset>0x3c</addressOffset>
        <size>0x20</size>
        <fields>
          <field>
            <name>CCR3</name>
            <bitOffset>0</bitOffset>
            <bitWidth>16</bitWidth>
          </field>
        </fields>
      </register>
      <register>
        <name>CCR4</name>
        <addressOffset>0x40</addressOffset>
        <size>0x20</size>
        <fields>
          <field>
            <name>CCR4</name>
            <bitOffset>0</bitOffset>
            <bitWidth>16</bitWidth>
          </field>
        </fields>
      </register>
      <register>
        <name>BDTR</name>
        <addressOffset>0x44</addressOffset>
        <size>0x20</size>
        <fields>
          <field>
            <name>DTG</name>
            <bitOffset>0</bitOffset>
            <bitWidth>8</bitWidth>
          </field>
          <field>
            <name>LOCK</name>
            <bitOffset>8</bitOffset>
            <bitWidth>2</bitWidth>
          </field>
          <field>
            <name>OSSI</name>
            <bitOffset>10</bitOffset>
            <bitWidth>1</bitWidth>
          </field>
          <field>
            <name>OSSR</name>
            <bitOffset>11</bitOffset>
            <bitWidth>1</bitWidth>
          </field>
          <field>
            <name>BKE</name>
            <bitOffset>12</bitOffset>
            <bitWidth>1</bitWidth>
          </field>
          <field>
            <name>BKP</name>
            <bitOffset>13</bitOffset>
            <bitWidth>1</bitWidth>
          </field>
          <field>
            <name>AOE</name>
            <bitOffset>14</bitOffset>
            <bitWidth>1</bitWidth>
          </field>
          <field>
            <name>MOE</name>
            <bitOffset>15</bitOffset>
            <bitWidth>1</bitWidth>
          </field>
        </fields>
      </register>
      <register>
        <name>DCR</name>
        <addressOffset>0x48</addressOffset>
        <size>0x20</size>
        <fields>
          <field>
            <name>DBA</name>
            <bitOffset>0</bitOffset>
            <bitWidth>5</bitWidth>
          </field>
          <field>
            <name>DBL</name>
            <bitOffset>8</bitOffset>
            <bitWidth>5</bitWidth>
          </field>
        </fields>
      </register>
      <register>
        <name>DMAR</name>
        <addressOffset>0x4c</addressOffset>
        <size>0x20</size>
        <fields>
          <field>
            <name>DMAB</name>
            <bitOffset>0</bitOffset>
            <bitWidth>16</bitWidth>
          </field>
        </fields>
      </register>
      <register>
        <name>OR</name>
        <addressOffset>0x50</addressOffset>
        <size>0x20</size>
        <fields>
          <field>
            <name>TI1_RMP</name>
            <bitOffset>0</bitOffset>
            <bitWidth>2</bitWidth>
          </field>
          <field>
            <name>TI4_RMP</name>
            <bitOffset>6</bitOffset>
            <bitWidth>2</bitWidth>
          </field>
          <field>
            <name>ITR1_RMP</name>
            <bitOffset>10</bitOffset>
            <bitWidth>2</bitWidth>
          </field>
        </fields>
      </register>
    </peripheral>
    <peripheral>
      <name>RTC</name>
      <baseAddress>0x40002800</baseAddress>
      <register>
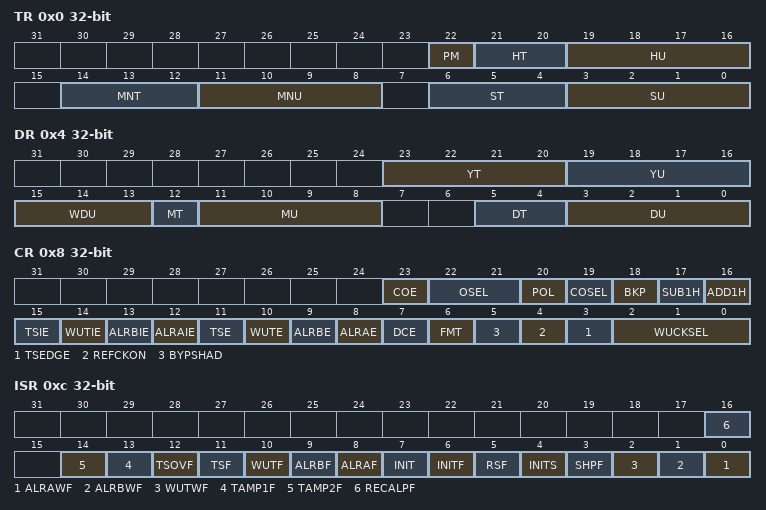
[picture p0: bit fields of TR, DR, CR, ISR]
        <name>TR</name>
        <addressOffset>0x0</addressOffset>
        <size>0x20</size>
        <fields>
          <field>
            <name>SU</name>
            <bitOffset>0</bitOffset>
            <bitWidth>4</bitWidth>
          </field>
          <field>
            <name>ST</name>
            <bitOffset>4</bitOffset>
            <bitWidth>3</bitWidth>
          </field>
          <field>
            <name>MNU</name>
            <bitOffset>8</bitOffset>
            <bitWidth>4</bitWidth>
          </field>
          <field>
            <name>MNT</name>
            <bitOffset>12</bitOffset>
            <bitWidth>3</bitWidth>
          </field>
          <field>
            <name>HU</name>
            <bitOffset>16</bitOffset>
            <bitWidth>4</bitWidth>
          </field>
          <field>
            <name>HT</name>
            <bitOffset>20</bitOffset>
            <bitWidth>2</bitWidth>
          </field>
          <field>
            <name>PM</name>
            <bitOffset>22</bitOffset>
            <bitWidth>1</bitWidth>
          </field>
        </fields>
      </register>
      <register>
        <name>DR</name>
        <addressOffset>0x4</addressOffset>
        <size>0x20</size>
        <fields>
          <field>
            <name>DU</name>
            <bitOffset>0</bitOffset>
            <bitWidth>4</bitWidth>
          </field>
          <field>
            <name>DT</name>
            <bitOffset>4</bitOffset>
            <bitWidth>2</bitWidth>
          </field>
          <field>
            <name>MU</name>
            <bitOffset>8</bitOffset>
            <bitWidth>4</bitWidth>
          </field>
          <field>
            <name>MT</name>
            <bitOffset>12</bitOffset>
            <bitWidth>1</bitWidth>
          </field>
          <field>
            <name>WDU</name>
            <bitOffset>13</bitOffset>
            <bitWidth>3</bitWidth>
          </field>
          <field>
            <name>YU</name>
            <bitOffset>16</bitOffset>
            <bitWidth>4</bitWidth>
          </field>
          <field>
            <name>YT</name>
            <bitOffset>20</bitOffset>
            <bitWidth>4</bitWidth>
          </field>
        </fields>
      </register>
      <register>
        <name>CR</name>
        <addressOffset>0x8</addressOffset>
        <size>0x20</size>
        <fields>
          <field>
            <name>WUCKSEL</name>
            <bitOffset>0</bitOffset>
            <bitWidth>3</bitWidth>
          </field>
          <field>
            <name>TSEDGE</name>
            <bitOffset>3</bitOffset>
            <bitWidth>1</bitWidth>
          </field>
          <field>
            <name>REFCKON</name>
            <bitOffset>4</bitOffset>
            <bitWidth>1</bitWidth>
          </field>
          <field>
            <name>BYPSHAD</name>
            <bitOffset>5</bitOffset>
            <bitWidth>1</bitWidth>
          </field>
          <field>
            <name>FMT</name>
            <bitOffset>6</bitOffset>
            <bitWidth>1</bitWidth>
          </field>
          <field>
            <name>DCE</name>
            <bitOffset>7</bitOffset>
            <bitWidth>1</bitWidth>
          </field>
          <field>
            <name>ALRAE</name>
            <bitOffset>8</bitOffset>
            <bitWidth>1</bitWidth>
          </field>
          <field>
            <name>ALRBE</name>
            <bitOffset>9</bitOffset>
            <bitWidth>1</bitWidth>
          </field>
          <field>
            <name>WUTE</name>
            <bitOffset>10</bitOffset>
            <bitWidth>1</bitWidth>
          </field>
          <field>
            <name>TSE</name>
            <bitOffset>11</bitOffset>
            <bitWidth>1</bitWidth>
          </field>
          <field>
            <name>ALRAIE</name>
            <bitOffset>12</bitOffset>
            <bitWidth>1</bitWidth>
          </field>
          <field>
            <name>ALRBIE</name>
            <bitOffset>13</bitOffset>
            <bitWidth>1</bitWidth>
          </field>
          <field>
            <name>WUTIE</name>
            <bitOffset>14</bitOffset>
            <bitWidth>1</bitWidth>
          </field>
          <field>
            <name>TSIE</name>
            <bitOffset>15</bitOffset>
            <bitWidth>1</bitWidth>
          </field>
          <field>
            <name>ADD1H</name>
            <bitOffset>16</bitOffset>
            <bitWidth>1</bitWidth>
          </field>
          <field>
            <name>SUB1H</name>
            <bitOffset>17</bitOffset>
            <bitWidth>1</bitWidth>
          </field>
          <field>
            <name>BKP</name>
            <bitOffset>18</bitOffset>
            <bitWidth>1</bitWidth>
          </field>
          <field>
            <name>COSEL</name>
            <bitOffset>19</bitOffset>
            <bitWidth>1</bitWidth>
          </field>
          <field>
            <name>POL</name>
            <bitOffset>20</bitOffset>
            <bitWidth>1</bitWidth>
          </field>
          <field>
            <name>OSEL</name>
            <bitOffset>21</bitOffset>
            <bitWidth>2</bitWidth>
          </field>
          <field>
            <name>COE</name>
            <bitOffset>23</bitOffset>
            <bitWidth>1</bitWidth>
          </field>
        </fields>
      </register>
      <register>
        <name>ISR</name>
        <addressOffset>0xc</addressOffset>
        <size>0x20</size>
        <fields>
          <field>
            <name>ALRAWF</name>
            <bitOffset>0</bitOffset>
            <bitWidth>1</bitWidth>
          </field>
          <field>
            <name>ALRBWF</name>
            <bitOffset>1</bitOffset>
            <bitWidth>1</bitWidth>
          </field>
          <field>
            <name>WUTWF</name>
            <bitOffset>2</bitOffset>
            <bitWidth>1</bitWidth>
          </field>
          <field>
            <name>SHPF</name>
            <bitOffset>3</bitOffset>
            <bitWidth>1</bitWidth>
          </field>
          <field>
            <name>INITS</name>
            <bitOffset>4</bitOffset>
            <bitWidth>1</bitWidth>
          </field>
          <field>
            <name>RSF</name>
            <bitOffset>5</bitOffset>
            <bitWidth>1</bitWidth>
          </field>
          <field>
            <name>INITF</name>
            <bitOffset>6</bitOffset>
            <bitWidth>1</bitWidth>
          </field>
          <field>
            <name>INIT</name>
            <bitOffset>7</bitOffset>
            <bitWidth>1</bitWidth>
          </field>
          <field>
            <name>ALRAF</name>
            <bitOffset>8</bitOffset>
            <bitWidth>1</bitWidth>
          </field>
          <field>
            <name>ALRBF</name>
            <bitOffset>9</bitOffset>
            <bitWidth>1</bitWidth>
          </field>
          <field>
            <name>WUTF</name>
            <bitOffset>10</bitOffset>
            <bitWidth>1</bitWidth>
          </field>
          <field>
            <name>TSF</name>
            <bitOffset>11</bitOffset>
            <bitWidth>1</bitWidth>
          </field>
          <field>
            <name>TSOVF</name>
            <bitOffset>12</bitOffset>
            <bitWidth>1</bitWidth>
          </field>
          <field>
            <name>TAMP1F</name>
            <bitOffset>13</bitOffset>
            <bitWidth>1</bitWidth>
          </field>
          <field>
            <name>TAMP2F</name>
            <bitOffset>14</bitOffset>
            <bitWidth>1</bitWidth>
          </field>
          <field>
            <name>RECALPF</name>
            <bitOffset>16</bitOffset>
            <bitWidth>1</bitWidth>
          </field>
        </fields>
      </register>
      <register>
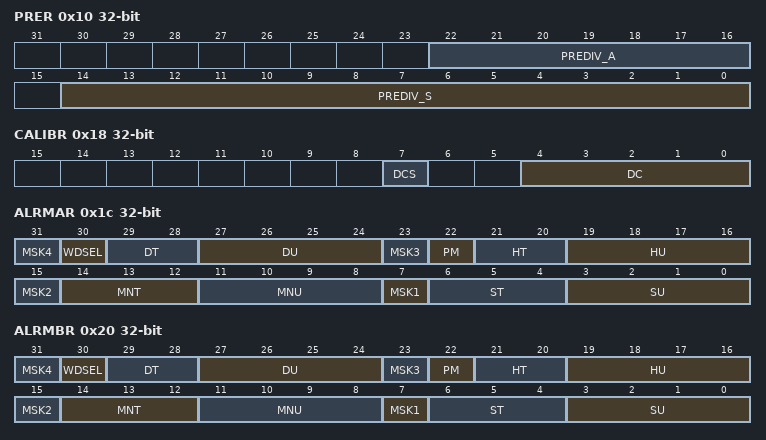
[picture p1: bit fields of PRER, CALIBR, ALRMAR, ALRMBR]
        <name>PRER</name>
        <addressOffset>0x10</addressOffset>
        <size>0x20</size>
        <fields>
          <field>
            <name>PREDIV_S</name>
            <bitOffset>0</bitOffset>
            <bitWidth>15</bitWidth>
          </field>
          <field>
            <name>PREDIV_A</name>
            <bitOffset>16</bitOffset>
            <bitWidth>7</bitWidth>
          </field>
        </fields>
      </register>
      <register>
        <name>WUTR</name>
        <addressOffset>0x14</addressOffset>
        <size>0x20</size>
        <fields>
          <field>
            <name>WUT</name>
            <bitOffset>0</bitOffset>
            <bitWidth>16</bitWidth>
          </field>
        </fields>
      </register>
      <register>
        <name>CALIBR</name>
        <addressOffset>0x18</addressOffset>
        <size>0x20</size>
        <fields>
          <field>
            <name>DC</name>
            <bitOffset>0</bitOffset>
            <bitWidth>5</bitWidth>
          </field>
          <field>
            <name>DCS</name>
            <bitOffset>7</bitOffset>
            <bitWidth>1</bitWidth>
          </field>
        </fields>
      </register>
      <register>
        <name>ALRMAR</name>
        <addressOffset>0x1c</addressOffset>
        <size>0x20</size>
        <fields>
          <field>
            <name>SU</name>
            <bitOffset>0</bitOffset>
            <bitWidth>4</bitWidth>
          </field>
          <field>
            <name>ST</name>
            <bitOffset>4</bitOffset>
            <bitWidth>3</bitWidth>
          </field>
          <field>
            <name>MSK1</name>
            <bitOffset>7</bitOffset>
            <bitWidth>1</bitWidth>
          </field>
          <field>
            <name>MNU</name>
            <bitOffset>8</bitOffset>
            <bitWidth>4</bitWidth>
          </field>
          <field>
            <name>MNT</name>
            <bitOffset>12</bitOffset>
            <bitWidth>3</bitWidth>
          </field>
          <field>
            <name>MSK2</name>
            <bitOffset>15</bitOffset>
            <bitWidth>1</bitWidth>
          </field>
          <field>
            <name>HU</name>
            <bitOffset>16</bitOffset>
            <bitWidth>4</bitWidth>
          </field>
          <field>
            <name>HT</name>
            <bitOffset>20</bitOffset>
            <bitWidth>2</bitWidth>
          </field>
          <field>
            <name>PM</name>
            <bitOffset>22</bitOffset>
            <bitWidth>1</bitWidth>
          </field>
          <field>
            <name>MSK3</name>
            <bitOffset>23</bitOffset>
            <bitWidth>1</bitWidth>
          </field>
          <field>
            <name>DU</name>
            <bitOffset>24</bitOffset>
            <bitWidth>4</bitWidth>
          </field>
          <field>
            <name>DT</name>
            <bitOffset>28</bitOffset>
            <bitWidth>2</bitWidth>
          </field>
          <field>
            <name>WDSEL</name>
            <bitOffset>30</bitOffset>
            <bitWidth>1</bitWidth>
          </field>
          <field>
            <name>MSK4</name>
            <bitOffset>31</bitOffset>
            <bitWidth>1</bitWidth>
          </field>
        </fields>
      </register>
      <register>
        <name>ALRMBR</name>
        <addressOffset>0x20</addressOffset>
        <size>0x20</size>
        <fields>
          <field>
            <name>SU</name>
            <bitOffset>0</bitOffset>
            <bitWidth>4</bitWidth>
          </field>
          <field>
            <name>ST</name>
            <bitOffset>4</bitOffset>
            <bitWidth>3</bitWidth>
          </field>
          <field>
            <name>MSK1</name>
            <bitOffset>7</bitOffset>
            <bitWidth>1</bitWidth>
          </field>
          <field>
            <name>MNU</name>
            <bitOffset>8</bitOffset>
            <bitWidth>4</bitWidth>
          </field>
          <field>
            <name>MNT</name>
            <bitOffset>12</bitOffset>
            <bitWidth>3</bitWidth>
          </field>
          <field>
            <name>MSK2</name>
            <bitOffset>15</bitOffset>
            <bitWidth>1</bitWidth>
          </field>
          <field>
            <name>HU</name>
            <bitOffset>16</bitOffset>
            <bitWidth>4</bitWidth>
          </field>
          <field>
            <name>HT</name>
            <bitOffset>20</bitOffset>
            <bitWidth>2</bitWidth>
          </field>
          <field>
            <name>PM</name>
            <bitOffset>22</bitOffset>
            <bitWidth>1</bitWidth>
          </field>
          <field>
            <name>MSK3</name>
            <bitOffset>23</bitOffset>
            <bitWidth>1</bitWidth>
          </field>
          <field>
            <name>DU</name>
            <bitOffset>24</bitOffset>
            <bitWidth>4</bitWidth>
          </field>
          <field>
            <name>DT</name>
            <bitOffset>28</bitOffset>
            <bitWidth>2</bitWidth>
          </field>
          <field>
            <name>WDSEL</name>
            <bitOffset>30</bitOffset>
            <bitWidth>1</bitWidth>
          </field>
          <field>
            <name>MSK4</name>
            <bitOffset>31</bitOffset>
            <bitWidth>1</bitWidth>
          </field>
        </fields>
      </register>
      <register>
        <name>WPR</name>
        <addressOffset>0x24</addressOffset>
        <size>0x20</size>
        <fields>
          <field>
            <name>KEY</name>
            <bitOffset>0</bitOffset>
            <bitWidth>8</bitWidth>
          </field>
        </fields>
      </register>
      <register>
        <name>SSR</name>
        <addressOffset>0x28</addressOffset>
        <size>0x20</size>
        <fields>
          <field>
            <name>SS</name>
            <bitOffset>0</bitOffset>
            <bitWidth>16</bitWidth>
          </field>
        </fields>
      </register>
      <register>
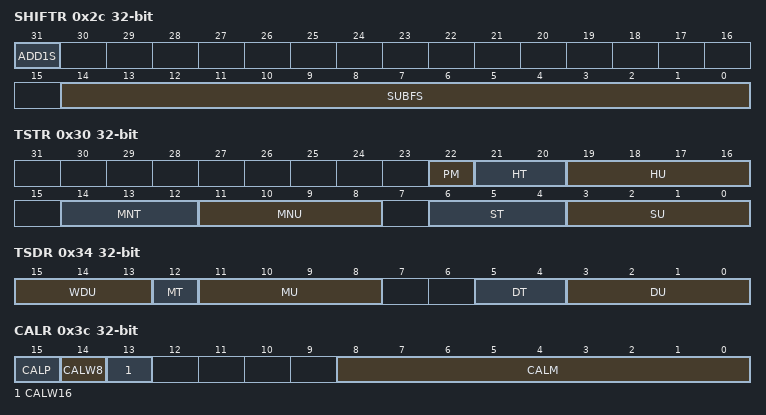
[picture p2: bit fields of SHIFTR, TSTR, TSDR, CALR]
        <name>SHIFTR</name>
        <addressOffset>0x2c</addressOffset>
        <size>0x20</size>
        <fields>
          <field>
            <name>SUBFS</name>
            <bitOffset>0</bitOffset>
            <bitWidth>15</bitWidth>
          </field>
          <field>
            <name>ADD1S</name>
            <bitOffset>31</bitOffset>
            <bitWidth>1</bitWidth>
          </field>
        </fields>
      </register>
      <register>
        <name>TSTR</name>
        <addressOffset>0x30</addressOffset>
        <size>0x20</size>
        <fields>
          <field>
            <name>SU</name>
            <bitOffset>0</bitOffset>
            <bitWidth>4</bitWidth>
          </field>
          <field>
            <name>ST</name>
            <bitOffset>4</bitOffset>
            <bitWidth>3</bitWidth>
          </field>
          <field>
            <name>MNU</name>
            <bitOffset>8</bitOffset>
            <bitWidth>4</bitWidth>
          </field>
          <field>
            <name>MNT</name>
            <bitOffset>12</bitOffset>
            <bitWidth>3</bitWidth>
          </field>
          <field>
            <name>HU</name>
            <bitOffset>16</bitOffset>
            <bitWidth>4</bitWidth>
          </field>
          <field>
            <name>HT</name>
            <bitOffset>20</bitOffset>
            <bitWidth>2</bitWidth>
          </field>
          <field>
            <name>PM</name>
            <bitOffset>22</bitOffset>
            <bitWidth>1</bitWidth>
          </field>
        </fields>
      </register>
      <register>
        <name>TSDR</name>
        <addressOffset>0x34</addressOffset>
        <size>0x20</size>
        <fields>
          <field>
            <name>DU</name>
            <bitOffset>0</bitOffset>
            <bitWidth>4</bitWidth>
          </field>
          <field>
            <name>DT</name>
            <bitOffset>4</bitOffset>
            <bitWidth>2</bitWidth>
          </field>
          <field>
            <name>MU</name>
            <bitOffset>8</bitOffset>
            <bitWidth>4</bitWidth>
          </field>
          <field>
            <name>MT</name>
            <bitOffset>12</bitOffset>
            <bitWidth>1</bitWidth>
          </field>
          <field>
            <name>WDU</name>
            <bitOffset>13</bitOffset>
            <bitWidth>3</bitWidth>
          </field>
        </fields>
      </register>
      <register>
        <name>TSSSR</name>
        <addressOffset>0x38</addressOffset>
        <size>0x20</size>
        <fields>
          <field>
            <name>SS</name>
            <bitOffset>0</bitOffset>
            <bitWidth>16</bitWidth>
          </field>
        </fields>
      </register>
      <register>
        <name>CALR</name>
        <addressOffset>0x3c</addressOffset>
        <size>0x20</size>
        <fields>
          <field>
            <name>CALM</name>
            <bitOffset>0</bitOffset>
            <bitWidth>9</bitWidth>
          </field>
          <field>
            <name>CALW16</name>
            <bitOffset>13</bitOffset>
            <bitWidth>1</bitWidth>
          </field>
          <field>
            <name>CALW8</name>
            <bitOffset>14</bitOffset>
            <bitWidth>1</bitWidth>
          </field>
          <field>
            <name>CALP</name>
            <bitOffset>15</bitOffset>
            <bitWidth>1</bitWidth>
          </field>
        </fields>
      </register>
      <register>
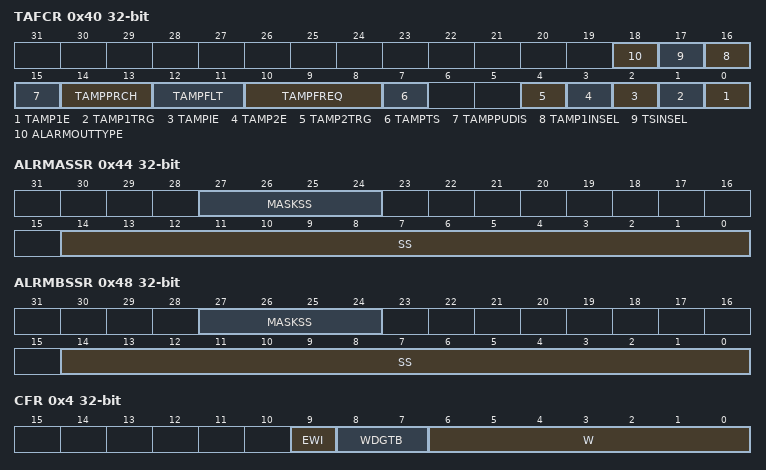
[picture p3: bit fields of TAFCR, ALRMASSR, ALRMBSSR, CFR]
        <name>TAFCR</name>
        <addressOffset>0x40</addressOffset>
        <size>0x20</size>
        <fields>
          <field>
            <name>TAMP1E</name>
            <bitOffset>0</bitOffset>
            <bitWidth>1</bitWidth>
          </field>
          <field>
            <name>TAMP1TRG</name>
            <bitOffset>1</bitOffset>
            <bitWidth>1</bitWidth>
          </field>
          <field>
            <name>TAMPIE</name>
            <bitOffset>2</bitOffset>
            <bitWidth>1</bitWidth>
          </field>
          <field>
            <name>TAMP2E</name>
            <bitOffset>3</bitOffset>
            <bitWidth>1</bitWidth>
          </field>
          <field>
            <name>TAMP2TRG</name>
            <bitOffset>4</bitOffset>
            <bitWidth>1</bitWidth>
          </field>
          <field>
            <name>TAMPTS</name>
            <bitOffset>7</bitOffset>
            <bitWidth>1</bitWidth>
          </field>
          <field>
            <name>TAMPFREQ</name>
            <bitOffset>8</bitOffset>
            <bitWidth>3</bitWidth>
          </field>
          <field>
            <name>TAMPFLT</name>
            <bitOffset>11</bitOffset>
            <bitWidth>2</bitWidth>
          </field>
          <field>
            <name>TAMPPRCH</name>
            <bitOffset>13</bitOffset>
            <bitWidth>2</bitWidth>
          </field>
          <field>
            <name>TAMPPUDIS</name>
            <bitOffset>15</bitOffset>
            <bitWidth>1</bitWidth>
          </field>
          <field>
            <name>TAMP1INSEL</name>
            <bitOffset>16</bitOffset>
            <bitWidth>1</bitWidth>
          </field>
          <field>
            <name>TSINSEL</name>
            <bitOffset>17</bitOffset>
            <bitWidth>1</bitWidth>
          </field>
          <field>
            <name>ALARMOUTTYPE</name>
            <bitOffset>18</bitOffset>
            <bitWidth>1</bitWidth>
          </field>
        </fields>
      </register>
      <register>
        <name>ALRMASSR</name>
        <addressOffset>0x44</addressOffset>
        <size>0x20</size>
        <fields>
          <field>
            <name>SS</name>
            <bitOffset>0</bitOffset>
            <bitWidth>15</bitWidth>
          </field>
          <field>
            <name>MASKSS</name>
            <bitOffset>24</bitOffset>
            <bitWidth>4</bitWidth>
          </field>
        </fields>
      </register>
      <register>
        <name>ALRMBSSR</name>
        <addressOffset>0x48</addressOffset>
        <size>0x20</size>
        <fields>
          <field>
            <name>SS</name>
            <bitOffset>0</bitOffset>
            <bitWidth>15</bitWidth>
          </field>
          <field>
            <name>MASKSS</name>
            <bitOffset>24</bitOffset>
            <bitWidth>4</bitWidth>
          </field>
        </fields>
      </register>
      <register>
        <name>BKP0R</name>
        <addressOffset>0x50</addressOffset>
        <size>0x20</size>
      </register>
      <register>
        <name>BKP1R</name>
        <addressOffset>0x54</addressOffset>
        <size>0x20</size>
      </register>
      <register>
        <name>BKP2R</name>
        <addressOffset>0x58</addressOffset>
        <size>0x20</size>
      </register>
      <register>
        <name>BKP3R</name>
        <addressOffset>0x5c</addressOffset>
        <size>0x20</size>
      </register>
      <register>
        <name>BKP4R</name>
        <addressOffset>0x60</addressOffset>
        <size>0x20</size>
      </register>
      <register>
        <name>BKP5R</name>
        <addressOffset>0x64</addressOffset>
        <size>0x20</size>
      </register>
      <register>
        <name>BKP6R</name>
        <addressOffset>0x68</addressOffset>
        <size>0x20</size>
      </register>
      <register>
        <name>BKP7R</name>
        <addressOffset>0x6c</addressOffset>
        <size>0x20</size>
      </register>
      <register>
        <name>BKP8R</name>
        <addressOffset>0x70</addressOffset>
        <size>0x20</size>
      </register>
      <register>
        <name>BKP9R</name>
        <addressOffset>0x74</addressOffset>
        <size>0x20</size>
      </register>
      <register>
        <name>BKP10R</name>
        <addressOffset>0x78</addressOffset>
        <size>0x20</size>
      </register>
      <register>
        <name>BKP11R</name>
        <addressOffset>0x7c</addressOffset>
        <size>0x20</size>
      </register>
      <register>
        <name>BKP12R</name>
        <addressOffset>0x80</addressOffset>
        <size>0x20</size>
      </register>
      <register>
        <name>BKP13R</name>
        <addressOffset>0x84</addressOffset>
        <size>0x20</size>
      </register>
      <register>
        <name>BKP14R</name>
        <addressOffset>0x88</addressOffset>
        <size>0x20</size>
      </register>
      <register>
        <name>BKP15R</name>
        <addressOffset>0x8c</addressOffset>
        <size>0x20</size>
      </register>
      <register>
        <name>BKP16R</name>
        <addressOffset>0x90</addressOffset>
        <size>0x20</size>
      </register>
      <register>
        <name>BKP17R</name>
        <addressOffset>0x94</addressOffset>
        <size>0x20</size>
      </register>
      <register>
        <name>BKP18R</name>
        <addressOffset>0x98</addressOffset>
        <size>0x20</size>
      </register>
      <register>
        <name>BKP19R</name>
        <addressOffset>0x9c</addressOffset>
        <size>0x20</size>
      </register>
    </peripheral>
    <peripheral>
      <name>WWDG</name>
      <baseAddress>0x40002c00</baseAddress>
      <register>
        <name>CR</name>
        <addressOffset>0x0</addressOffset>
        <size>0x20</size>
        <fields>
          <field>
            <name>T</name>
            <bitOffset>0</bitOffset>
            <bitWidth>7</bitWidth>
          </field>
          <field>
            <name>WDGA</name>
            <bitOffset>7</bitOffset>
            <bitWidth>1</bitWidth>
          </field>
        </fields>
      </register>
      <register>
        <name>CFR</name>
        <addressOffset>0x4</addressOffset>
        <size>0x20</size>
        <fields>
          <field>
            <name>W</name>
            <bitOffset>0</bitOffset>
            <bitWidth>7</bitWidth>
          </field>
          <field>
            <name>WDGTB</name>
            <bitOffset>7</bitOffset>
            <bitWidth>2</bitWidth>
          </field>
          <field>
            <name>EWI</name>
            <bitOffset>9</bitOffset>
            <bitWidth>1</bitWidth>
          </field>
        </fields>
      </register>
      <register>
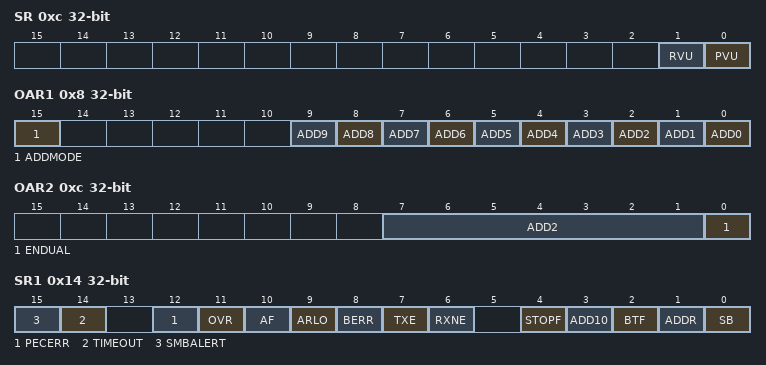
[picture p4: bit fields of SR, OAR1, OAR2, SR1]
        <name>SR</name>
        <addressOffset>0x8</addressOffset>
        <size>0x20</size>
        <fields>
          <field>
            <name>EWIF</name>
            <bitOffset>0</bitOffset>
            <bitWidth>1</bitWidth>
          </field>
        </fields>
      </register>
    </peripheral>
    <peripheral>
      <name>IWDG</name>
      <baseAddress>0x40003000</baseAddress>
      <register>
        <name>KR</name>
        <addressOffset>0x0</addressOffset>
        <size>0x20</size>
        <fields>
          <field>
            <name>KEY</name>
            <bitOffset>0</bitOffset>
            <bitWidth>16</bitWidth>
          </field>
        </fields>
      </register>
      <register>
        <name>PR</name>
        <addressOffset>0x4</addressOffset>
        <size>0x20</size>
        <fields>
          <field>
            <name>PR</name>
            <bitOffset>0</bitOffset>
            <bitWidth>3</bitWidth>
          </field>
        </fields>
      </register>
      <register>
        <name>RLR</name>
        <addressOffset>0x8</addressOffset>
        <size>0x20</size>
        <fields>
          <field>
            <name>RL</name>
            <bitOffset>0</bitOffset>
            <bitWidth>12</bitWidth>
          </field>
        </fields>
      </register>
      <register>
        <name>SR</name>
        <addressOffset>0xc</addressOffset>
        <size>0x20</size>
        <fields>
          <field>
            <name>PVU</name>
            <bitOffset>0</bitOffset>
            <bitWidth>1</bitWidth>
          </field>
          <field>
            <name>RVU</name>
            <bitOffset>1</bitOffset>
            <bitWidth>1</bitWidth>
          </field>
        </fields>
      </register>
    </peripheral>
    <peripheral>
      <name>I2S2ext</name>
      <baseAddress>0x40003400</baseAddress>
      <register>
        <name>CR1</name>
        <addressOffset>0x0</addressOffset>
        <size>0x20</size>
        <fields>
          <field>
            <name>CPHA</name>
            <bitOffset>0</bitOffset>
            <bitWidth>1</bitWidth>
          </field>
          <field>
            <name>CPOL</name>
            <bitOffset>1</bitOffset>
            <bitWidth>1</bitWidth>
          </field>
          <field>
            <name>MSTR</name>
            <bitOffset>2</bitOffset>
            <bitWidth>1</bitWidth>
          </field>
          <field>
            <name>BR</name>
            <bitOffset>3</bitOffset>
            <bitWidth>3</bitWidth>
          </field>
          <field>
            <name>SPE</name>
            <bitOffset>6</bitOffset>
            <bitWidth>1</bitWidth>
          </field>
          <field>
            <name>LSBFIRST</name>
            <bitOffset>7</bitOffset>
            <bitWidth>1</bitWidth>
          </field>
          <field>
            <name>SSI</name>
            <bitOffset>8</bitOffset>
            <bitWidth>1</bitWidth>
          </field>
          <field>
            <name>SSM</name>
            <bitOffset>9</bitOffset>
            <bitWidth>1</bitWidth>
          </field>
          <field>
            <name>RXONLY</name>
            <bitOffset>10</bitOffset>
            <bitWidth>1</bitWidth>
          </field>
          <field>
            <name>DFF</name>
            <bitOffset>11</bitOffset>
            <bitWidth>1</bitWidth>
          </field>
          <field>
            <name>CRCNEXT</name>
            <bitOffset>12</bitOffset>
            <bitWidth>1</bitWidth>
          </field>
          <field>
            <name>CRCEN</name>
            <bitOffset>13</bitOffset>
            <bitWidth>1</bitWidth>
          </field>
          <field>
            <name>BIDIOE</name>
            <bitOffset>14</bitOffset>
            <bitWidth>1</bitWidth>
          </field>
          <field>
            <name>BIDIMODE</name>
            <bitOffset>15</bitOffset>
            <bitWidth>1</bitWidth>
          </field>
        </fields>
      </register>
      <register>
        <name>CR2</name>
        <addressOffset>0x4</addressOffset>
        <size>0x20</size>
        <fields>
          <field>
            <name>RXDMAEN</name>
            <bitOffset>0</bitOffset>
            <bitWidth>1</bitWidth>
          </field>
          <field>
            <name>TXDMAEN</name>
            <bitOffset>1</bitOffset>
            <bitWidth>1</bitWidth>
          </field>
          <field>
            <name>SSOE</name>
            <bitOffset>2</bitOffset>
            <bitWidth>1</bitWidth>
          </field>
          <field>
            <name>FRF</name>
            <bitOffset>4</bitOffset>
            <bitWidth>1</bitWidth>
          </field>
          <field>
            <name>ERRIE</name>
            <bitOffset>5</bitOffset>
            <bitWidth>1</bitWidth>
          </field>
          <field>
            <name>RXNEIE</name>
            <bitOffset>6</bitOffset>
            <bitWidth>1</bitWidth>
          </field>
          <field>
            <name>TXEIE</name>
            <bitOffset>7</bitOffset>
            <bitWidth>1</bitWidth>
          </field>
        </fields>
      </register>
      <register>
        <name>SR</name>
        <addressOffset>0x8</addressOffset>
        <size>0x20</size>
        <fields>
          <field>
            <name>RXNE</name>
            <bitOffset>0</bitOffset>
            <bitWidth>1</bitWidth>
          </field>
          <field>
            <name>TXE</name>
            <bitOffset>1</bitOffset>
            <bitWidth>1</bitWidth>
          </field>
          <field>
            <name>CHSIDE</name>
            <bitOffset>2</bitOffset>
            <bitWidth>1</bitWidth>
          </field>
          <field>
            <name>UDR</name>
            <bitOffset>3</bitOffset>
            <bitWidth>1</bitWidth>
          </field>
          <field>
            <name>CRCERR</name>
            <bitOffset>4</bitOffset>
            <bitWidth>1</bitWidth>
          </field>
          <field>
            <name>MODF</name>
            <bitOffset>5</bitOffset>
            <bitWidth>1</bitWidth>
          </field>
          <field>
            <name>OVR</name>
            <bitOffset>6</bitOffset>
            <bitWidth>1</bitWidth>
          </field>
          <field>
            <name>BSY</name>
            <bitOffset>7</bitOffset>
            <bitWidth>1</bitWidth>
          </field>
          <field>
            <name>FRE</name>
            <bitOffset>8</bitOffset>
            <bitWidth>1</bitWidth>
          </field>
        </fields>
      </register>
      <register>
        <name>DR</name>
        <addressOffset>0xc</addressOffset>
        <size>0x20</size>
        <fields>
          <field>
            <name>DR</name>
            <bitOffset>0</bitOffset>
            <bitWidth>16</bitWidth>
          </field>
        </fields>
      </register>
      <register>
        <name>CRCPR</name>
        <addressOffset>0x10</addressOffset>
        <size>0x20</size>
        <fields>
          <field>
            <name>CRCPOLY</name>
            <bitOffset>0</bitOffset>
            <bitWidth>16</bitWidth>
          </field>
        </fields>
      </register>
      <register>
        <name>RXCRCR</name>
        <addressOffset>0x14</addressOffset>
        <size>0x20</size>
        <fields>
          <field>
            <name>RXCRC</name>
            <bitOffset>0</bitOffset>
            <bitWidth>16</bitWidth>
          </field>
        </fields>
      </register>
      <register>
        <name>TXCRCR</name>
        <addressOffset>0x18</addressOffset>
        <size>0x20</size>
        <fields>
          <field>
            <name>TXCRC</name>
            <bitOffset>0</bitOffset>
            <bitWidth>16</bitWidth>
          </field>
        </fields>
      </register>
      <register>
        <name>I2SCFGR</name>
        <addressOffset>0x1c</addressOffset>
        <size>0x20</size>
        <fields>
          <field>
            <name>CHLEN</name>
            <bitOffset>0</bitOffset>
            <bitWidth>1</bitWidth>
          </field>
          <field>
            <name>DATLEN</name>
            <bitOffset>1</bitOffset>
            <bitWidth>2</bitWidth>
          </field>
          <field>
            <name>CKPOL</name>
            <bitOffset>3</bitOffset>
            <bitWidth>1</bitWidth>
          </field>
          <field>
            <name>I2SSTD</name>
            <bitOffset>4</bitOffset>
            <bitWidth>2</bitWidth>
          </field>
          <field>
            <name>PCMSYNC</name>
            <bitOffset>7</bitOffset>
            <bitWidth>1</bitWidth>
          </field>
          <field>
            <name>I2SCFG</name>
            <bitOffset>8</bitOffset>
            <bitWidth>2</bitWidth>
          </field>
          <field>
            <name>I2SE</name>
            <bitOffset>10</bitOffset>
            <bitWidth>1</bitWidth>
          </field>
          <field>
            <name>I2SMOD</name>
            <bitOffset>11</bitOffset>
            <bitWidth>1</bitWidth>
          </field>
        </fields>
      </register>
      <register>
        <name>I2SPR</name>
        <addressOffset>0x20</addressOffset>
        <size>0x20</size>
        <fields>
          <field>
            <name>I2SDIV</name>
            <bitOffset>0</bitOffset>
            <bitWidth>8</bitWidth>
          </field>
          <field>
            <name>ODD</name>
            <bitOffset>8</bitOffset>
            <bitWidth>1</bitWidth>
          </field>
          <field>
            <name>MCKOE</name>
            <bitOffset>9</bitOffset>
            <bitWidth>1</bitWidth>
          </field>
        </fields>
      </register>
    </peripheral>
    <peripheral>
      <name>SPI2</name>
      <baseAddress>0x40003800</baseAddress>
      <register>
        <name>CR1</name>
        <addressOffset>0x0</addressOffset>
        <size>0x20</size>
        <fields>
          <field>
            <name>CPHA</name>
            <bitOffset>0</bitOffset>
            <bitWidth>1</bitWidth>
          </field>
          <field>
            <name>CPOL</name>
            <bitOffset>1</bitOffset>
            <bitWidth>1</bitWidth>
          </field>
          <field>
            <name>MSTR</name>
            <bitOffset>2</bitOffset>
            <bitWidth>1</bitWidth>
          </field>
          <field>
            <name>BR</name>
            <bitOffset>3</bitOffset>
            <bitWidth>3</bitWidth>
          </field>
          <field>
            <name>SPE</name>
            <bitOffset>6</bitOffset>
            <bitWidth>1</bitWidth>
          </field>
          <field>
            <name>LSBFIRST</name>
            <bitOffset>7</bitOffset>
            <bitWidth>1</bitWidth>
          </field>
          <field>
            <name>SSI</name>
            <bitOffset>8</bitOffset>
            <bitWidth>1</bitWidth>
          </field>
          <field>
            <name>SSM</name>
            <bitOffset>9</bitOffset>
            <bitWidth>1</bitWidth>
          </field>
          <field>
            <name>RXONLY</name>
            <bitOffset>10</bitOffset>
            <bitWidth>1</bitWidth>
          </field>
          <field>
            <name>DFF</name>
            <bitOffset>11</bitOffset>
            <bitWidth>1</bitWidth>
          </field>
          <field>
            <name>CRCNEXT</name>
            <bitOffset>12</bitOffset>
            <bitWidth>1</bitWidth>
          </field>
          <field>
            <name>CRCEN</name>
            <bitOffset>13</bitOffset>
            <bitWidth>1</bitWidth>
          </field>
          <field>
            <name>BIDIOE</name>
            <bitOffset>14</bitOffset>
            <bitWidth>1</bitWidth>
          </field>
          <field>
            <name>BIDIMODE</name>
            <bitOffset>15</bitOffset>
            <bitWidth>1</bitWidth>
          </field>
        </fields>
      </register>
      <register>
        <name>CR2</name>
        <addressOffset>0x4</addressOffset>
        <size>0x20</size>
        <fields>
          <field>
            <name>RXDMAEN</name>
            <bitOffset>0</bitOffset>
            <bitWidth>1</bitWidth>
          </field>
          <field>
            <name>TXDMAEN</name>
            <bitOffset>1</bitOffset>
            <bitWidth>1</bitWidth>
          </field>
          <field>
            <name>SSOE</name>
            <bitOffset>2</bitOffset>
            <bitWidth>1</bitWidth>
          </field>
          <field>
            <name>FRF</name>
            <bitOffset>4</bitOffset>
            <bitWidth>1</bitWidth>
          </field>
          <field>
            <name>ERRIE</name>
            <bitOffset>5</bitOffset>
            <bitWidth>1</bitWidth>
          </field>
          <field>
            <name>RXNEIE</name>
            <bitOffset>6</bitOffset>
            <bitWidth>1</bitWidth>
          </field>
          <field>
            <name>TXEIE</name>
            <bitOffset>7</bitOffset>
            <bitWidth>1</bitWidth>
          </field>
        </fields>
      </register>
      <register>
        <name>SR</name>
        <addressOffset>0x8</addressOffset>
        <size>0x20</size>
        <fields>
          <field>
            <name>RXNE</name>
            <bitOffset>0</bitOffset>
            <bitWidth>1</bitWidth>
          </field>
          <field>
            <name>TXE</name>
            <bitOffset>1</bitOffset>
            <bitWidth>1</bitWidth>
          </field>
          <field>
            <name>CHSIDE</name>
            <bitOffset>2</bitOffset>
            <bitWidth>1</bitWidth>
          </field>
          <field>
            <name>UDR</name>
            <bitOffset>3</bitOffset>
            <bitWidth>1</bitWidth>
          </field>
          <field>
            <name>CRCERR</name>
            <bitOffset>4</bitOffset>
            <bitWidth>1</bitWidth>
          </field>
          <field>
            <name>MODF</name>
            <bitOffset>5</bitOffset>
            <bitWidth>1</bitWidth>
          </field>
          <field>
            <name>OVR</name>
            <bitOffset>6</bitOffset>
            <bitWidth>1</bitWidth>
          </field>
          <field>
            <name>BSY</name>
            <bitOffset>7</bitOffset>
            <bitWidth>1</bitWidth>
          </field>
          <field>
            <name>FRE</name>
            <bitOffset>8</bitOffset>
            <bitWidth>1</bitWidth>
          </field>
        </fields>
      </register>
      <register>
        <name>DR</name>
        <addressOffset>0xc</addressOffset>
        <size>0x20</size>
        <fields>
          <field>
            <name>DR</name>
            <bitOffset>0</bitOffset>
            <bitWidth>16</bitWidth>
          </field>
        </fields>
      </register>
      <register>
        <name>CRCPR</name>
        <addressOffset>0x10</addressOffset>
        <size>0x20</size>
        <fields>
          <field>
            <name>CRCPOLY</name>
            <bitOffset>0</bitOffset>
            <bitWidth>16</bitWidth>
          </field>
        </fields>
      </register>
      <register>
        <name>RXCRCR</name>
        <addressOffset>0x14</addressOffset>
        <size>0x20</size>
        <fields>
          <field>
            <name>RXCRC</name>
            <bitOffset>0</bitOffset>
            <bitWidth>16</bitWidth>
          </field>
        </fields>
      </register>
      <register>
        <name>TXCRCR</name>
        <addressOffset>0x18</addressOffset>
        <size>0x20</size>
        <fields>
          <field>
            <name>TXCRC</name>
            <bitOffset>0</bitOffset>
            <bitWidth>16</bitWidth>
          </field>
        </fields>
      </register>
      <register>
        <name>I2SCFGR</name>
        <addressOffset>0x1c</addressOffset>
        <size>0x20</size>
        <fields>
          <field>
            <name>CHLEN</name>
            <bitOffset>0</bitOffset>
            <bitWidth>1</bitWidth>
          </field>
          <field>
            <name>DATLEN</name>
            <bitOffset>1</bitOffset>
            <bitWidth>2</bitWidth>
          </field>
          <field>
            <name>CKPOL</name>
            <bitOffset>3</bitOffset>
            <bitWidth>1</bitWidth>
          </field>
          <field>
            <name>I2SSTD</name>
            <bitOffset>4</bitOffset>
            <bitWidth>2</bitWidth>
          </field>
          <field>
            <name>PCMSYNC</name>
            <bitOffset>7</bitOffset>
            <bitWidth>1</bitWidth>
          </field>
          <field>
            <name>I2SCFG</name>
            <bitOffset>8</bitOffset>
            <bitWidth>2</bitWidth>
          </field>
          <field>
            <name>I2SE</name>
            <bitOffset>10</bitOffset>
            <bitWidth>1</bitWidth>
          </field>
          <field>
            <name>I2SMOD</name>
            <bitOffset>11</bitOffset>
            <bitWidth>1</bitWidth>
          </field>
        </fields>
      </register>
      <register>
        <name>I2SPR</name>
        <addressOffset>0x20</addressOffset>
        <size>0x20</size>
        <fields>
          <field>
            <name>I2SDIV</name>
            <bitOffset>0</bitOffset>
            <bitWidth>8</bitWidth>
          </field>
          <field>
            <name>ODD</name>
            <bitOffset>8</bitOffset>
            <bitWidth>1</bitWidth>
          </field>
          <field>
            <name>MCKOE</name>
            <bitOffset>9</bitOffset>
            <bitWidth>1</bitWidth>
          </field>
        </fields>
      </register>
    </peripheral>
    <peripheral>
      <name>SPI3</name>
      <baseAddress>0x40003c00</baseAddress>
      <register>
        <name>CR1</name>
        <addressOffset>0x0</addressOffset>
        <size>0x20</size>
        <fields>
          <field>
            <name>CPHA</name>
            <bitOffset>0</bitOffset>
            <bitWidth>1</bitWidth>
          </field>
          <field>
            <name>CPOL</name>
            <bitOffset>1</bitOffset>
            <bitWidth>1</bitWidth>
          </field>
          <field>
            <name>MSTR</name>
            <bitOffset>2</bitOffset>
            <bitWidth>1</bitWidth>
          </field>
          <field>
            <name>BR</name>
            <bitOffset>3</bitOffset>
            <bitWidth>3</bitWidth>
          </field>
          <field>
            <name>SPE</name>
            <bitOffset>6</bitOffset>
            <bitWidth>1</bitWidth>
          </field>
          <field>
            <name>LSBFIRST</name>
            <bitOffset>7</bitOffset>
            <bitWidth>1</bitWidth>
          </field>
          <field>
            <name>SSI</name>
            <bitOffset>8</bitOffset>
            <bitWidth>1</bitWidth>
          </field>
          <field>
            <name>SSM</name>
            <bitOffset>9</bitOffset>
            <bitWidth>1</bitWidth>
          </field>
          <field>
            <name>RXONLY</name>
            <bitOffset>10</bitOffset>
            <bitWidth>1</bitWidth>
          </field>
          <field>
            <name>DFF</name>
            <bitOffset>11</bitOffset>
            <bitWidth>1</bitWidth>
          </field>
          <field>
            <name>CRCNEXT</name>
            <bitOffset>12</bitOffset>
            <bitWidth>1</bitWidth>
          </field>
          <field>
            <name>CRCEN</name>
            <bitOffset>13</bitOffset>
            <bitWidth>1</bitWidth>
          </field>
          <field>
            <name>BIDIOE</name>
            <bitOffset>14</bitOffset>
            <bitWidth>1</bitWidth>
          </field>
          <field>
            <name>BIDIMODE</name>
            <bitOffset>15</bitOffset>
            <bitWidth>1</bitWidth>
          </field>
        </fields>
      </register>
      <register>
        <name>CR2</name>
        <addressOffset>0x4</addressOffset>
        <size>0x20</size>
        <fields>
          <field>
            <name>RXDMAEN</name>
            <bitOffset>0</bitOffset>
            <bitWidth>1</bitWidth>
          </field>
          <field>
            <name>TXDMAEN</name>
            <bitOffset>1</bitOffset>
            <bitWidth>1</bitWidth>
          </field>
          <field>
            <name>SSOE</name>
            <bitOffset>2</bitOffset>
            <bitWidth>1</bitWidth>
          </field>
          <field>
            <name>FRF</name>
            <bitOffset>4</bitOffset>
            <bitWidth>1</bitWidth>
          </field>
          <field>
            <name>ERRIE</name>
            <bitOffset>5</bitOffset>
            <bitWidth>1</bitWidth>
          </field>
          <field>
            <name>RXNEIE</name>
            <bitOffset>6</bitOffset>
            <bitWidth>1</bitWidth>
          </field>
          <field>
            <name>TXEIE</name>
            <bitOffset>7</bitOffset>
            <bitWidth>1</bitWidth>
          </field>
        </fields>
      </register>
      <register>
        <name>SR</name>
        <addressOffset>0x8</addressOffset>
        <size>0x20</size>
        <fields>
          <field>
            <name>RXNE</name>
            <bitOffset>0</bitOffset>
            <bitWidth>1</bitWidth>
          </field>
          <field>
            <name>TXE</name>
            <bitOffset>1</bitOffset>
            <bitWidth>1</bitWidth>
          </field>
          <field>
            <name>CHSIDE</name>
            <bitOffset>2</bitOffset>
            <bitWidth>1</bitWidth>
          </field>
          <field>
            <name>UDR</name>
            <bitOffset>3</bitOffset>
            <bitWidth>1</bitWidth>
          </field>
          <field>
            <name>CRCERR</name>
            <bitOffset>4</bitOffset>
            <bitWidth>1</bitWidth>
          </field>
          <field>
            <name>MODF</name>
            <bitOffset>5</bitOffset>
            <bitWidth>1</bitWidth>
          </field>
          <field>
            <name>OVR</name>
            <bitOffset>6</bitOffset>
            <bitWidth>1</bitWidth>
          </field>
          <field>
            <name>BSY</name>
            <bitOffset>7</bitOffset>
            <bitWidth>1</bitWidth>
          </field>
          <field>
            <name>FRE</name>
            <bitOffset>8</bitOffset>
            <bitWidth>1</bitWidth>
          </field>
        </fields>
      </register>
      <register>
        <name>DR</name>
        <addressOffset>0xc</addressOffset>
        <size>0x20</size>
        <fields>
          <field>
            <name>DR</name>
            <bitOffset>0</bitOffset>
            <bitWidth>16</bitWidth>
          </field>
        </fields>
      </register>
      <register>
        <name>CRCPR</name>
        <addressOffset>0x10</addressOffset>
        <size>0x20</size>
        <fields>
          <field>
            <name>CRCPOLY</name>
            <bitOffset>0</bitOffset>
            <bitWidth>16</bitWidth>
          </field>
        </fields>
      </register>
      <register>
        <name>RXCRCR</name>
        <addressOffset>0x14</addressOffset>
        <size>0x20</size>
        <fields>
          <field>
            <name>RXCRC</name>
            <bitOffset>0</bitOffset>
            <bitWidth>16</bitWidth>
          </field>
        </fields>
      </register>
      <register>
        <name>TXCRCR</name>
        <addressOffset>0x18</addressOffset>
        <size>0x20</size>
        <fields>
          <field>
            <name>TXCRC</name>
            <bitOffset>0</bitOffset>
            <bitWidth>16</bitWidth>
          </field>
        </fields>
      </register>
      <register>
        <name>I2SCFGR</name>
        <addressOffset>0x1c</addressOffset>
        <size>0x20</size>
        <fields>
          <field>
            <name>CHLEN</name>
            <bitOffset>0</bitOffset>
            <bitWidth>1</bitWidth>
          </field>
          <field>
            <name>DATLEN</name>
            <bitOffset>1</bitOffset>
            <bitWidth>2</bitWidth>
          </field>
          <field>
            <name>CKPOL</name>
            <bitOffset>3</bitOffset>
            <bitWidth>1</bitWidth>
          </field>
          <field>
            <name>I2SSTD</name>
            <bitOffset>4</bitOffset>
            <bitWidth>2</bitWidth>
          </field>
          <field>
            <name>PCMSYNC</name>
            <bitOffset>7</bitOffset>
            <bitWidth>1</bitWidth>
          </field>
          <field>
            <name>I2SCFG</name>
            <bitOffset>8</bitOffset>
            <bitWidth>2</bitWidth>
          </field>
          <field>
            <name>I2SE</name>
            <bitOffset>10</bitOffset>
            <bitWidth>1</bitWidth>
          </field>
          <field>
            <name>I2SMOD</name>
            <bitOffset>11</bitOffset>
            <bitWidth>1</bitWidth>
          </field>
        </fields>
      </register>
      <register>
        <name>I2SPR</name>
        <addressOffset>0x20</addressOffset>
        <size>0x20</size>
        <fields>
          <field>
            <name>I2SDIV</name>
            <bitOffset>0</bitOffset>
            <bitWidth>8</bitWidth>
          </field>
          <field>
            <name>ODD</name>
            <bitOffset>8</bitOffset>
            <bitWidth>1</bitWidth>
          </field>
          <field>
            <name>MCKOE</name>
            <bitOffset>9</bitOffset>
            <bitWidth>1</bitWidth>
          </field>
        </fields>
      </register>
    </peripheral>
    <peripheral>
      <name>I2S3ext</name>
      <baseAddress>0x40004000</baseAddress>
      <register>
        <name>CR1</name>
        <addressOffset>0x0</addressOffset>
        <size>0x20</size>
        <fields>
          <field>
            <name>CPHA</name>
            <bitOffset>0</bitOffset>
            <bitWidth>1</bitWidth>
          </field>
          <field>
            <name>CPOL</name>
            <bitOffset>1</bitOffset>
            <bitWidth>1</bitWidth>
          </field>
          <field>
            <name>MSTR</name>
            <bitOffset>2</bitOffset>
            <bitWidth>1</bitWidth>
          </field>
          <field>
            <name>BR</name>
            <bitOffset>3</bitOffset>
            <bitWidth>3</bitWidth>
          </field>
          <field>
            <name>SPE</name>
            <bitOffset>6</bitOffset>
            <bitWidth>1</bitWidth>
          </field>
          <field>
            <name>LSBFIRST</name>
            <bitOffset>7</bitOffset>
            <bitWidth>1</bitWidth>
          </field>
          <field>
            <name>SSI</name>
            <bitOffset>8</bitOffset>
            <bitWidth>1</bitWidth>
          </field>
          <field>
            <name>SSM</name>
            <bitOffset>9</bitOffset>
            <bitWidth>1</bitWidth>
          </field>
          <field>
            <name>RXONLY</name>
            <bitOffset>10</bitOffset>
            <bitWidth>1</bitWidth>
          </field>
          <field>
            <name>DFF</name>
            <bitOffset>11</bitOffset>
            <bitWidth>1</bitWidth>
          </field>
          <field>
            <name>CRCNEXT</name>
            <bitOffset>12</bitOffset>
            <bitWidth>1</bitWidth>
          </field>
          <field>
            <name>CRCEN</name>
            <bitOffset>13</bitOffset>
            <bitWidth>1</bitWidth>
          </field>
          <field>
            <name>BIDIOE</name>
            <bitOffset>14</bitOffset>
            <bitWidth>1</bitWidth>
          </field>
          <field>
            <name>BIDIMODE</name>
            <bitOffset>15</bitOffset>
            <bitWidth>1</bitWidth>
          </field>
        </fields>
      </register>
      <register>
        <name>CR2</name>
        <addressOffset>0x4</addressOffset>
        <size>0x20</size>
        <fields>
          <field>
            <name>RXDMAEN</name>
            <bitOffset>0</bitOffset>
            <bitWidth>1</bitWidth>
          </field>
          <field>
            <name>TXDMAEN</name>
            <bitOffset>1</bitOffset>
            <bitWidth>1</bitWidth>
          </field>
          <field>
            <name>SSOE</name>
            <bitOffset>2</bitOffset>
            <bitWidth>1</bitWidth>
          </field>
          <field>
            <name>FRF</name>
            <bitOffset>4</bitOffset>
            <bitWidth>1</bitWidth>
          </field>
          <field>
            <name>ERRIE</name>
            <bitOffset>5</bitOffset>
            <bitWidth>1</bitWidth>
          </field>
          <field>
            <name>RXNEIE</name>
            <bitOffset>6</bitOffset>
            <bitWidth>1</bitWidth>
          </field>
          <field>
            <name>TXEIE</name>
            <bitOffset>7</bitOffset>
            <bitWidth>1</bitWidth>
          </field>
        </fields>
      </register>
      <register>
        <name>SR</name>
        <addressOffset>0x8</addressOffset>
        <size>0x20</size>
        <fields>
          <field>
            <name>RXNE</name>
            <bitOffset>0</bitOffset>
            <bitWidth>1</bitWidth>
          </field>
          <field>
            <name>TXE</name>
            <bitOffset>1</bitOffset>
            <bitWidth>1</bitWidth>
          </field>
          <field>
            <name>CHSIDE</name>
            <bitOffset>2</bitOffset>
            <bitWidth>1</bitWidth>
          </field>
          <field>
            <name>UDR</name>
            <bitOffset>3</bitOffset>
            <bitWidth>1</bitWidth>
          </field>
          <field>
            <name>CRCERR</name>
            <bitOffset>4</bitOffset>
            <bitWidth>1</bitWidth>
          </field>
          <field>
            <name>MODF</name>
            <bitOffset>5</bitOffset>
            <bitWidth>1</bitWidth>
          </field>
          <field>
            <name>OVR</name>
            <bitOffset>6</bitOffset>
            <bitWidth>1</bitWidth>
          </field>
          <field>
            <name>BSY</name>
            <bitOffset>7</bitOffset>
            <bitWidth>1</bitWidth>
          </field>
          <field>
            <name>FRE</name>
            <bitOffset>8</bitOffset>
            <bitWidth>1</bitWidth>
          </field>
        </fields>
      </register>
      <register>
        <name>DR</name>
        <addressOffset>0xc</addressOffset>
        <size>0x20</size>
        <fields>
          <field>
            <name>DR</name>
            <bitOffset>0</bitOffset>
            <bitWidth>16</bitWidth>
          </field>
        </fields>
      </register>
      <register>
        <name>CRCPR</name>
        <addressOffset>0x10</addressOffset>
        <size>0x20</size>
        <fields>
          <field>
            <name>CRCPOLY</name>
            <bitOffset>0</bitOffset>
            <bitWidth>16</bitWidth>
          </field>
        </fields>
      </register>
      <register>
        <name>RXCRCR</name>
        <addressOffset>0x14</addressOffset>
        <size>0x20</size>
        <fields>
          <field>
            <name>RXCRC</name>
            <bitOffset>0</bitOffset>
            <bitWidth>16</bitWidth>
          </field>
        </fields>
      </register>
      <register>
        <name>TXCRCR</name>
        <addressOffset>0x18</addressOffset>
        <size>0x20</size>
        <fields>
          <field>
            <name>TXCRC</name>
            <bitOffset>0</bitOffset>
            <bitWidth>16</bitWidth>
          </field>
        </fields>
      </register>
      <register>
        <name>I2SCFGR</name>
        <addressOffset>0x1c</addressOffset>
        <size>0x20</size>
        <fields>
          <field>
            <name>CHLEN</name>
            <bitOffset>0</bitOffset>
            <bitWidth>1</bitWidth>
          </field>
          <field>
            <name>DATLEN</name>
            <bitOffset>1</bitOffset>
            <bitWidth>2</bitWidth>
          </field>
          <field>
            <name>CKPOL</name>
            <bitOffset>3</bitOffset>
            <bitWidth>1</bitWidth>
          </field>
          <field>
            <name>I2SSTD</name>
            <bitOffset>4</bitOffset>
            <bitWidth>2</bitWidth>
          </field>
          <field>
            <name>PCMSYNC</name>
            <bitOffset>7</bitOffset>
            <bitWidth>1</bitWidth>
          </field>
          <field>
            <name>I2SCFG</name>
            <bitOffset>8</bitOffset>
            <bitWidth>2</bitWidth>
          </field>
          <field>
            <name>I2SE</name>
            <bitOffset>10</bitOffset>
            <bitWidth>1</bitWidth>
          </field>
          <field>
            <name>I2SMOD</name>
            <bitOffset>11</bitOffset>
            <bitWidth>1</bitWidth>
          </field>
        </fields>
      </register>
      <register>
        <name>I2SPR</name>
        <addressOffset>0x20</addressOffset>
        <size>0x20</size>
        <fields>
          <field>
            <name>I2SDIV</name>
            <bitOffset>0</bitOffset>
            <bitWidth>8</bitWidth>
          </field>
          <field>
            <name>ODD</name>
            <bitOffset>8</bitOffset>
            <bitWidth>1</bitWidth>
          </field>
          <field>
            <name>MCKOE</name>
            <bitOffset>9</bitOffset>
            <bitWidth>1</bitWidth>
          </field>
        </fields>
      </register>
    </peripheral>
    <peripheral>
      <name>USART2</name>
      <baseAddress>0x40004400</baseAddress>
      <register>
        <name>SR</name>
        <addressOffset>0x0</addressOffset>
        <size>0x20</size>
        <fields>
          <field>
            <name>PE</name>
            <bitOffset>0</bitOffset>
            <bitWidth>1</bitWidth>
          </field>
          <field>
            <name>FE</name>
            <bitOffset>1</bitOffset>
            <bitWidth>1</bitWidth>
          </field>
          <field>
            <name>NE</name>
            <bitOffset>2</bitOffset>
            <bitWidth>1</bitWidth>
          </field>
          <field>
            <name>ORE</name>
            <bitOffset>3</bitOffset>
            <bitWidth>1</bitWidth>
          </field>
          <field>
            <name>IDLE</name>
            <bitOffset>4</bitOffset>
            <bitWidth>1</bitWidth>
          </field>
          <field>
            <name>RXNE</name>
            <bitOffset>5</bitOffset>
            <bitWidth>1</bitWidth>
          </field>
          <field>
            <name>TC</name>
            <bitOffset>6</bitOffset>
            <bitWidth>1</bitWidth>
          </field>
          <field>
            <name>TXE</name>
            <bitOffset>7</bitOffset>
            <bitWidth>1</bitWidth>
          </field>
          <field>
            <name>LBD</name>
            <bitOffset>8</bitOffset>
            <bitWidth>1</bitWidth>
          </field>
          <field>
            <name>CTS</name>
            <bitOffset>9</bitOffset>
            <bitWidth>1</bitWidth>
          </field>
        </fields>
      </register>
      <register>
        <name>DR</name>
        <addressOffset>0x4</addressOffset>
        <size>0x20</size>
        <fields>
          <field>
            <name>DR</name>
            <bitOffset>0</bitOffset>
            <bitWidth>9</bitWidth>
          </field>
        </fields>
      </register>
      <register>
        <name>BRR</name>
        <addressOffset>0x8</addressOffset>
        <size>0x20</size>
        <fields>
          <field>
            <name>DIV_Fraction</name>
            <bitOffset>0</bitOffset>
            <bitWidth>4</bitWidth>
          </field>
          <field>
            <name>DIV_Mantissa</name>
            <bitOffset>4</bitOffset>
            <bitWidth>12</bitWidth>
          </field>
        </fields>
      </register>
      <register>
        <name>CR1</name>
        <addressOffset>0xc</addressOffset>
        <size>0x20</size>
        <fields>
          <field>
            <name>SBK</name>
            <bitOffset>0</bitOffset>
            <bitWidth>1</bitWidth>
          </field>
          <field>
            <name>RWU</name>
            <bitOffset>1</bitOffset>
            <bitWidth>1</bitWidth>
          </field>
          <field>
            <name>RE</name>
            <bitOffset>2</bitOffset>
            <bitWidth>1</bitWidth>
          </field>
          <field>
            <name>TE</name>
            <bitOffset>3</bitOffset>
            <bitWidth>1</bitWidth>
          </field>
          <field>
            <name>IDLEIE</name>
            <bitOffset>4</bitOffset>
            <bitWidth>1</bitWidth>
          </field>
          <field>
            <name>RXNEIE</name>
            <bitOffset>5</bitOffset>
            <bitWidth>1</bitWidth>
          </field>
          <field>
            <name>TCIE</name>
            <bitOffset>6</bitOffset>
            <bitWidth>1</bitWidth>
          </field>
          <field>
            <name>TXEIE</name>
            <bitOffset>7</bitOffset>
            <bitWidth>1</bitWidth>
          </field>
          <field>
            <name>PEIE</name>
            <bitOffset>8</bitOffset>
            <bitWidth>1</bitWidth>
          </field>
          <field>
            <name>PS</name>
            <bitOffset>9</bitOffset>
            <bitWidth>1</bitWidth>
          </field>
          <field>
            <name>PCE</name>
            <bitOffset>10</bitOffset>
            <bitWidth>1</bitWidth>
          </field>
          <field>
            <name>WAKE</name>
            <bitOffset>11</bitOffset>
            <bitWidth>1</bitWidth>
          </field>
          <field>
            <name>M</name>
            <bitOffset>12</bitOffset>
            <bitWidth>1</bitWidth>
          </field>
          <field>
            <name>UE</name>
            <bitOffset>13</bitOffset>
            <bitWidth>1</bitWidth>
          </field>
          <field>
            <name>OVER8</name>
            <bitOffset>15</bitOffset>
            <bitWidth>1</bitWidth>
          </field>
        </fields>
      </register>
      <register>
        <name>CR2</name>
        <addressOffset>0x10</addressOffset>
        <size>0x20</size>
        <fields>
          <field>
            <name>ADD</name>
            <bitOffset>0</bitOffset>
            <bitWidth>4</bitWidth>
          </field>
          <field>
            <name>LBDL</name>
            <bitOffset>5</bitOffset>
            <bitWidth>1</bitWidth>
          </field>
          <field>
            <name>LBDIE</name>
            <bitOffset>6</bitOffset>
            <bitWidth>1</bitWidth>
          </field>
          <field>
            <name>LBCL</name>
            <bitOffset>8</bitOffset>
            <bitWidth>1</bitWidth>
          </field>
          <field>
            <name>CPHA</name>
            <bitOffset>9</bitOffset>
            <bitWidth>1</bitWidth>
          </field>
          <field>
            <name>CPOL</name>
            <bitOffset>10</bitOffset>
            <bitWidth>1</bitWidth>
          </field>
          <field>
            <name>CLKEN</name>
            <bitOffset>11</bitOffset>
            <bitWidth>1</bitWidth>
          </field>
          <field>
            <name>STOP</name>
            <bitOffset>12</bitOffset>
            <bitWidth>2</bitWidth>
          </field>
          <field>
            <name>LINEN</name>
            <bitOffset>14</bitOffset>
            <bitWidth>1</bitWidth>
          </field>
        </fields>
      </register>
      <register>
        <name>CR3</name>
        <addressOffset>0x14</addressOffset>
        <size>0x20</size>
        <fields>
          <field>
            <name>EIE</name>
            <bitOffset>0</bitOffset>
            <bitWidth>1</bitWidth>
          </field>
          <field>
            <name>IREN</name>
            <bitOffset>1</bitOffset>
            <bitWidth>1</bitWidth>
          </field>
          <field>
            <name>IRLP</name>
            <bitOffset>2</bitOffset>
            <bitWidth>1</bitWidth>
          </field>
          <field>
            <name>HDSEL</name>
            <bitOffset>3</bitOffset>
            <bitWidth>1</bitWidth>
          </field>
          <field>
            <name>NACK</name>
            <bitOffset>4</bitOffset>
            <bitWidth>1</bitWidth>
          </field>
          <field>
            <name>SCEN</name>
            <bitOffset>5</bitOffset>
            <bitWidth>1</bitWidth>
          </field>
          <field>
            <name>DMAR</name>
            <bitOffset>6</bitOffset>
            <bitWidth>1</bitWidth>
          </field>
          <field>
            <name>DMAT</name>
            <bitOffset>7</bitOffset>
            <bitWidth>1</bitWidth>
          </field>
          <field>
            <name>RTSE</name>
            <bitOffset>8</bitOffset>
            <bitWidth>1</bitWidth>
          </field>
          <field>
            <name>CTSE</name>
            <bitOffset>9</bitOffset>
            <bitWidth>1</bitWidth>
          </field>
          <field>
            <name>CTSIE</name>
            <bitOffset>10</bitOffset>
            <bitWidth>1</bitWidth>
          </field>
          <field>
            <name>ONEBIT</name>
            <bitOffset>11</bitOffset>
            <bitWidth>1</bitWidth>
          </field>
        </fields>
      </register>
      <register>
        <name>GTPR</name>
        <addressOffset>0x18</addressOffset>
        <size>0x20</size>
        <fields>
          <field>
            <name>PSC</name>
            <bitOffset>0</bitOffset>
            <bitWidth>8</bitWidth>
          </field>
          <field>
            <name>GT</name>
            <bitOffset>8</bitOffset>
            <bitWidth>8</bitWidth>
          </field>
        </fields>
      </register>
    </peripheral>
    <peripheral>
      <name>USART3</name>
      <baseAddress>0x40004800</baseAddress>
      <register>
        <name>SR</name>
        <addressOffset>0x0</addressOffset>
        <size>0x20</size>
        <fields>
          <field>
            <name>PE</name>
            <bitOffset>0</bitOffset>
            <bitWidth>1</bitWidth>
          </field>
          <field>
            <name>FE</name>
            <bitOffset>1</bitOffset>
            <bitWidth>1</bitWidth>
          </field>
          <field>
            <name>NE</name>
            <bitOffset>2</bitOffset>
            <bitWidth>1</bitWidth>
          </field>
          <field>
            <name>ORE</name>
            <bitOffset>3</bitOffset>
            <bitWidth>1</bitWidth>
          </field>
          <field>
            <name>IDLE</name>
            <bitOffset>4</bitOffset>
            <bitWidth>1</bitWidth>
          </field>
          <field>
            <name>RXNE</name>
            <bitOffset>5</bitOffset>
            <bitWidth>1</bitWidth>
          </field>
          <field>
            <name>TC</name>
            <bitOffset>6</bitOffset>
            <bitWidth>1</bitWidth>
          </field>
          <field>
            <name>TXE</name>
            <bitOffset>7</bitOffset>
            <bitWidth>1</bitWidth>
          </field>
          <field>
            <name>LBD</name>
            <bitOffset>8</bitOffset>
            <bitWidth>1</bitWidth>
          </field>
          <field>
            <name>CTS</name>
            <bitOffset>9</bitOffset>
            <bitWidth>1</bitWidth>
          </field>
        </fields>
      </register>
      <register>
        <name>DR</name>
        <addressOffset>0x4</addressOffset>
        <size>0x20</size>
        <fields>
          <field>
            <name>DR</name>
            <bitOffset>0</bitOffset>
            <bitWidth>9</bitWidth>
          </field>
        </fields>
      </register>
      <register>
        <name>BRR</name>
        <addressOffset>0x8</addressOffset>
        <size>0x20</size>
        <fields>
          <field>
            <name>DIV_Fraction</name>
            <bitOffset>0</bitOffset>
            <bitWidth>4</bitWidth>
          </field>
          <field>
            <name>DIV_Mantissa</name>
            <bitOffset>4</bitOffset>
            <bitWidth>12</bitWidth>
          </field>
        </fields>
      </register>
      <register>
        <name>CR1</name>
        <addressOffset>0xc</addressOffset>
        <size>0x20</size>
        <fields>
          <field>
            <name>SBK</name>
            <bitOffset>0</bitOffset>
            <bitWidth>1</bitWidth>
          </field>
          <field>
            <name>RWU</name>
            <bitOffset>1</bitOffset>
            <bitWidth>1</bitWidth>
          </field>
          <field>
            <name>RE</name>
            <bitOffset>2</bitOffset>
            <bitWidth>1</bitWidth>
          </field>
          <field>
            <name>TE</name>
            <bitOffset>3</bitOffset>
            <bitWidth>1</bitWidth>
          </field>
          <field>
            <name>IDLEIE</name>
            <bitOffset>4</bitOffset>
            <bitWidth>1</bitWidth>
          </field>
          <field>
            <name>RXNEIE</name>
            <bitOffset>5</bitOffset>
            <bitWidth>1</bitWidth>
          </field>
          <field>
            <name>TCIE</name>
            <bitOffset>6</bitOffset>
            <bitWidth>1</bitWidth>
          </field>
          <field>
            <name>TXEIE</name>
            <bitOffset>7</bitOffset>
            <bitWidth>1</bitWidth>
          </field>
          <field>
            <name>PEIE</name>
            <bitOffset>8</bitOffset>
            <bitWidth>1</bitWidth>
          </field>
          <field>
            <name>PS</name>
            <bitOffset>9</bitOffset>
            <bitWidth>1</bitWidth>
          </field>
          <field>
            <name>PCE</name>
            <bitOffset>10</bitOffset>
            <bitWidth>1</bitWidth>
          </field>
          <field>
            <name>WAKE</name>
            <bitOffset>11</bitOffset>
            <bitWidth>1</bitWidth>
          </field>
          <field>
            <name>M</name>
            <bitOffset>12</bitOffset>
            <bitWidth>1</bitWidth>
          </field>
          <field>
            <name>UE</name>
            <bitOffset>13</bitOffset>
            <bitWidth>1</bitWidth>
          </field>
          <field>
            <name>OVER8</name>
            <bitOffset>15</bitOffset>
            <bitWidth>1</bitWidth>
          </field>
        </fields>
      </register>
      <register>
        <name>CR2</name>
        <addressOffset>0x10</addressOffset>
        <size>0x20</size>
        <fields>
          <field>
            <name>ADD</name>
            <bitOffset>0</bitOffset>
            <bitWidth>4</bitWidth>
          </field>
          <field>
            <name>LBDL</name>
            <bitOffset>5</bitOffset>
            <bitWidth>1</bitWidth>
          </field>
          <field>
            <name>LBDIE</name>
            <bitOffset>6</bitOffset>
            <bitWidth>1</bitWidth>
          </field>
          <field>
            <name>LBCL</name>
            <bitOffset>8</bitOffset>
            <bitWidth>1</bitWidth>
          </field>
          <field>
            <name>CPHA</name>
            <bitOffset>9</bitOffset>
            <bitWidth>1</bitWidth>
          </field>
          <field>
            <name>CPOL</name>
            <bitOffset>10</bitOffset>
            <bitWidth>1</bitWidth>
          </field>
          <field>
            <name>CLKEN</name>
            <bitOffset>11</bitOffset>
            <bitWidth>1</bitWidth>
          </field>
          <field>
            <name>STOP</name>
            <bitOffset>12</bitOffset>
            <bitWidth>2</bitWidth>
          </field>
          <field>
            <name>LINEN</name>
            <bitOffset>14</bitOffset>
            <bitWidth>1</bitWidth>
          </field>
        </fields>
      </register>
      <register>
        <name>CR3</name>
        <addressOffset>0x14</addressOffset>
        <size>0x20</size>
        <fields>
          <field>
            <name>EIE</name>
            <bitOffset>0</bitOffset>
            <bitWidth>1</bitWidth>
          </field>
          <field>
            <name>IREN</name>
            <bitOffset>1</bitOffset>
            <bitWidth>1</bitWidth>
          </field>
          <field>
            <name>IRLP</name>
            <bitOffset>2</bitOffset>
            <bitWidth>1</bitWidth>
          </field>
          <field>
            <name>HDSEL</name>
            <bitOffset>3</bitOffset>
            <bitWidth>1</bitWidth>
          </field>
          <field>
            <name>NACK</name>
            <bitOffset>4</bitOffset>
            <bitWidth>1</bitWidth>
          </field>
          <field>
            <name>SCEN</name>
            <bitOffset>5</bitOffset>
            <bitWidth>1</bitWidth>
          </field>
          <field>
            <name>DMAR</name>
            <bitOffset>6</bitOffset>
            <bitWidth>1</bitWidth>
          </field>
          <field>
            <name>DMAT</name>
            <bitOffset>7</bitOffset>
            <bitWidth>1</bitWidth>
          </field>
          <field>
            <name>RTSE</name>
            <bitOffset>8</bitOffset>
            <bitWidth>1</bitWidth>
          </field>
          <field>
            <name>CTSE</name>
            <bitOffset>9</bitOffset>
            <bitWidth>1</bitWidth>
          </field>
          <field>
            <name>CTSIE</name>
            <bitOffset>10</bitOffset>
            <bitWidth>1</bitWidth>
          </field>
          <field>
            <name>ONEBIT</name>
            <bitOffset>11</bitOffset>
            <bitWidth>1</bitWidth>
          </field>
        </fields>
      </register>
      <register>
        <name>GTPR</name>
        <addressOffset>0x18</addressOffset>
        <size>0x20</size>
        <fields>
          <field>
            <name>PSC</name>
            <bitOffset>0</bitOffset>
            <bitWidth>8</bitWidth>
          </field>
          <field>
            <name>GT</name>
            <bitOffset>8</bitOffset>
            <bitWidth>8</bitWidth>
          </field>
        </fields>
      </register>
    </peripheral>
    <peripheral>
      <name>UART4</name>
      <baseAddress>0x40004c00</baseAddress>
      <register>
        <name>SR</name>
        <addressOffset>0x0</addressOffset>
        <size>0x20</size>
        <fields>
          <field>
            <name>PE</name>
            <bitOffset>0</bitOffset>
            <bitWidth>1</bitWidth>
          </field>
          <field>
            <name>FE</name>
            <bitOffset>1</bitOffset>
            <bitWidth>1</bitWidth>
          </field>
          <field>
            <name>NE</name>
            <bitOffset>2</bitOffset>
            <bitWidth>1</bitWidth>
          </field>
          <field>
            <name>ORE</name>
            <bitOffset>3</bitOffset>
            <bitWidth>1</bitWidth>
          </field>
          <field>
            <name>IDLE</name>
            <bitOffset>4</bitOffset>
            <bitWidth>1</bitWidth>
          </field>
          <field>
            <name>RXNE</name>
            <bitOffset>5</bitOffset>
            <bitWidth>1</bitWidth>
          </field>
          <field>
            <name>TC</name>
            <bitOffset>6</bitOffset>
            <bitWidth>1</bitWidth>
          </field>
          <field>
            <name>TXE</name>
            <bitOffset>7</bitOffset>
            <bitWidth>1</bitWidth>
          </field>
          <field>
            <name>LBD</name>
            <bitOffset>8</bitOffset>
            <bitWidth>1</bitWidth>
          </field>
          <field>
            <name>CTS</name>
            <bitOffset>9</bitOffset>
            <bitWidth>1</bitWidth>
          </field>
        </fields>
      </register>
      <register>
        <name>DR</name>
        <addressOffset>0x4</addressOffset>
        <size>0x20</size>
        <fields>
          <field>
            <name>DR</name>
            <bitOffset>0</bitOffset>
            <bitWidth>9</bitWidth>
          </field>
        </fields>
      </register>
      <register>
        <name>BRR</name>
        <addressOffset>0x8</addressOffset>
        <size>0x20</size>
        <fields>
          <field>
            <name>DIV_Fraction</name>
            <bitOffset>0</bitOffset>
            <bitWidth>4</bitWidth>
          </field>
          <field>
            <name>DIV_Mantissa</name>
            <bitOffset>4</bitOffset>
            <bitWidth>12</bitWidth>
          </field>
        </fields>
      </register>
      <register>
        <name>CR1</name>
        <addressOffset>0xc</addressOffset>
        <size>0x20</size>
        <fields>
          <field>
            <name>SBK</name>
            <bitOffset>0</bitOffset>
            <bitWidth>1</bitWidth>
          </field>
          <field>
            <name>RWU</name>
            <bitOffset>1</bitOffset>
            <bitWidth>1</bitWidth>
          </field>
          <field>
            <name>RE</name>
            <bitOffset>2</bitOffset>
            <bitWidth>1</bitWidth>
          </field>
          <field>
            <name>TE</name>
            <bitOffset>3</bitOffset>
            <bitWidth>1</bitWidth>
          </field>
          <field>
            <name>IDLEIE</name>
            <bitOffset>4</bitOffset>
            <bitWidth>1</bitWidth>
          </field>
          <field>
            <name>RXNEIE</name>
            <bitOffset>5</bitOffset>
            <bitWidth>1</bitWidth>
          </field>
          <field>
            <name>TCIE</name>
            <bitOffset>6</bitOffset>
            <bitWidth>1</bitWidth>
          </field>
          <field>
            <name>TXEIE</name>
            <bitOffset>7</bitOffset>
            <bitWidth>1</bitWidth>
          </field>
          <field>
            <name>PEIE</name>
            <bitOffset>8</bitOffset>
            <bitWidth>1</bitWidth>
          </field>
          <field>
            <name>PS</name>
            <bitOffset>9</bitOffset>
            <bitWidth>1</bitWidth>
          </field>
          <field>
            <name>PCE</name>
            <bitOffset>10</bitOffset>
            <bitWidth>1</bitWidth>
          </field>
          <field>
            <name>WAKE</name>
            <bitOffset>11</bitOffset>
            <bitWidth>1</bitWidth>
          </field>
          <field>
            <name>M</name>
            <bitOffset>12</bitOffset>
            <bitWidth>1</bitWidth>
          </field>
          <field>
            <name>UE</name>
            <bitOffset>13</bitOffset>
            <bitWidth>1</bitWidth>
          </field>
          <field>
            <name>OVER8</name>
            <bitOffset>15</bitOffset>
            <bitWidth>1</bitWidth>
          </field>
        </fields>
      </register>
      <register>
        <name>CR2</name>
        <addressOffset>0x10</addressOffset>
        <size>0x20</size>
        <fields>
          <field>
            <name>ADD</name>
            <bitOffset>0</bitOffset>
            <bitWidth>4</bitWidth>
          </field>
          <field>
            <name>LBDL</name>
            <bitOffset>5</bitOffset>
            <bitWidth>1</bitWidth>
          </field>
          <field>
            <name>LBDIE</name>
            <bitOffset>6</bitOffset>
            <bitWidth>1</bitWidth>
          </field>
          <field>
            <name>LBCL</name>
            <bitOffset>8</bitOffset>
            <bitWidth>1</bitWidth>
          </field>
          <field>
            <name>CPHA</name>
            <bitOffset>9</bitOffset>
            <bitWidth>1</bitWidth>
          </field>
          <field>
            <name>CPOL</name>
            <bitOffset>10</bitOffset>
            <bitWidth>1</bitWidth>
          </field>
          <field>
            <name>CLKEN</name>
            <bitOffset>11</bitOffset>
            <bitWidth>1</bitWidth>
          </field>
          <field>
            <name>STOP</name>
            <bitOffset>12</bitOffset>
            <bitWidth>2</bitWidth>
          </field>
          <field>
            <name>LINEN</name>
            <bitOffset>14</bitOffset>
            <bitWidth>1</bitWidth>
          </field>
        </fields>
      </register>
      <register>
        <name>CR3</name>
        <addressOffset>0x14</addressOffset>
        <size>0x20</size>
        <fields>
          <field>
            <name>EIE</name>
            <bitOffset>0</bitOffset>
            <bitWidth>1</bitWidth>
          </field>
          <field>
            <name>IREN</name>
            <bitOffset>1</bitOffset>
            <bitWidth>1</bitWidth>
          </field>
          <field>
            <name>IRLP</name>
            <bitOffset>2</bitOffset>
            <bitWidth>1</bitWidth>
          </field>
          <field>
            <name>HDSEL</name>
            <bitOffset>3</bitOffset>
            <bitWidth>1</bitWidth>
          </field>
          <field>
            <name>NACK</name>
            <bitOffset>4</bitOffset>
            <bitWidth>1</bitWidth>
          </field>
          <field>
            <name>SCEN</name>
            <bitOffset>5</bitOffset>
            <bitWidth>1</bitWidth>
          </field>
          <field>
            <name>DMAR</name>
            <bitOffset>6</bitOffset>
            <bitWidth>1</bitWidth>
          </field>
          <field>
            <name>DMAT</name>
            <bitOffset>7</bitOffset>
            <bitWidth>1</bitWidth>
          </field>
          <field>
            <name>RTSE</name>
            <bitOffset>8</bitOffset>
            <bitWidth>1</bitWidth>
          </field>
          <field>
            <name>CTSE</name>
            <bitOffset>9</bitOffset>
            <bitWidth>1</bitWidth>
          </field>
          <field>
            <name>CTSIE</name>
            <bitOffset>10</bitOffset>
            <bitWidth>1</bitWidth>
          </field>
          <field>
            <name>ONEBIT</name>
            <bitOffset>11</bitOffset>
            <bitWidth>1</bitWidth>
          </field>
        </fields>
      </register>
      <register>
        <name>GTPR</name>
        <addressOffset>0x18</addressOffset>
        <size>0x20</size>
        <fields>
          <field>
            <name>PSC</name>
            <bitOffset>0</bitOffset>
            <bitWidth>8</bitWidth>
          </field>
          <field>
            <name>GT</name>
            <bitOffset>8</bitOffset>
            <bitWidth>8</bitWidth>
          </field>
        </fields>
      </register>
    </peripheral>
    <peripheral>
      <name>UART5</name>
      <baseAddress>0x40005000</baseAddress>
      <register>
        <name>SR</name>
        <addressOffset>0x0</addressOffset>
        <size>0x20</size>
        <fields>
          <field>
            <name>PE</name>
            <bitOffset>0</bitOffset>
            <bitWidth>1</bitWidth>
          </field>
          <field>
            <name>FE</name>
            <bitOffset>1</bitOffset>
            <bitWidth>1</bitWidth>
          </field>
          <field>
            <name>NE</name>
            <bitOffset>2</bitOffset>
            <bitWidth>1</bitWidth>
          </field>
          <field>
            <name>ORE</name>
            <bitOffset>3</bitOffset>
            <bitWidth>1</bitWidth>
          </field>
          <field>
            <name>IDLE</name>
            <bitOffset>4</bitOffset>
            <bitWidth>1</bitWidth>
          </field>
          <field>
            <name>RXNE</name>
            <bitOffset>5</bitOffset>
            <bitWidth>1</bitWidth>
          </field>
          <field>
            <name>TC</name>
            <bitOffset>6</bitOffset>
            <bitWidth>1</bitWidth>
          </field>
          <field>
            <name>TXE</name>
            <bitOffset>7</bitOffset>
            <bitWidth>1</bitWidth>
          </field>
          <field>
            <name>LBD</name>
            <bitOffset>8</bitOffset>
            <bitWidth>1</bitWidth>
          </field>
          <field>
            <name>CTS</name>
            <bitOffset>9</bitOffset>
            <bitWidth>1</bitWidth>
          </field>
        </fields>
      </register>
      <register>
        <name>DR</name>
        <addressOffset>0x4</addressOffset>
        <size>0x20</size>
        <fields>
          <field>
            <name>DR</name>
            <bitOffset>0</bitOffset>
            <bitWidth>9</bitWidth>
          </field>
        </fields>
      </register>
      <register>
        <name>BRR</name>
        <addressOffset>0x8</addressOffset>
        <size>0x20</size>
        <fields>
          <field>
            <name>DIV_Fraction</name>
            <bitOffset>0</bitOffset>
            <bitWidth>4</bitWidth>
          </field>
          <field>
            <name>DIV_Mantissa</name>
            <bitOffset>4</bitOffset>
            <bitWidth>12</bitWidth>
          </field>
        </fields>
      </register>
      <register>
        <name>CR1</name>
        <addressOffset>0xc</addressOffset>
        <size>0x20</size>
        <fields>
          <field>
            <name>SBK</name>
            <bitOffset>0</bitOffset>
            <bitWidth>1</bitWidth>
          </field>
          <field>
            <name>RWU</name>
            <bitOffset>1</bitOffset>
            <bitWidth>1</bitWidth>
          </field>
          <field>
            <name>RE</name>
            <bitOffset>2</bitOffset>
            <bitWidth>1</bitWidth>
          </field>
          <field>
            <name>TE</name>
            <bitOffset>3</bitOffset>
            <bitWidth>1</bitWidth>
          </field>
          <field>
            <name>IDLEIE</name>
            <bitOffset>4</bitOffset>
            <bitWidth>1</bitWidth>
          </field>
          <field>
            <name>RXNEIE</name>
            <bitOffset>5</bitOffset>
            <bitWidth>1</bitWidth>
          </field>
          <field>
            <name>TCIE</name>
            <bitOffset>6</bitOffset>
            <bitWidth>1</bitWidth>
          </field>
          <field>
            <name>TXEIE</name>
            <bitOffset>7</bitOffset>
            <bitWidth>1</bitWidth>
          </field>
          <field>
            <name>PEIE</name>
            <bitOffset>8</bitOffset>
            <bitWidth>1</bitWidth>
          </field>
          <field>
            <name>PS</name>
            <bitOffset>9</bitOffset>
            <bitWidth>1</bitWidth>
          </field>
          <field>
            <name>PCE</name>
            <bitOffset>10</bitOffset>
            <bitWidth>1</bitWidth>
          </field>
          <field>
            <name>WAKE</name>
            <bitOffset>11</bitOffset>
            <bitWidth>1</bitWidth>
          </field>
          <field>
            <name>M</name>
            <bitOffset>12</bitOffset>
            <bitWidth>1</bitWidth>
          </field>
          <field>
            <name>UE</name>
            <bitOffset>13</bitOffset>
            <bitWidth>1</bitWidth>
          </field>
          <field>
            <name>OVER8</name>
            <bitOffset>15</bitOffset>
            <bitWidth>1</bitWidth>
          </field>
        </fields>
      </register>
      <register>
        <name>CR2</name>
        <addressOffset>0x10</addressOffset>
        <size>0x20</size>
        <fields>
          <field>
            <name>ADD</name>
            <bitOffset>0</bitOffset>
            <bitWidth>4</bitWidth>
          </field>
          <field>
            <name>LBDL</name>
            <bitOffset>5</bitOffset>
            <bitWidth>1</bitWidth>
          </field>
          <field>
            <name>LBDIE</name>
            <bitOffset>6</bitOffset>
            <bitWidth>1</bitWidth>
          </field>
          <field>
            <name>LBCL</name>
            <bitOffset>8</bitOffset>
            <bitWidth>1</bitWidth>
          </field>
          <field>
            <name>CPHA</name>
            <bitOffset>9</bitOffset>
            <bitWidth>1</bitWidth>
          </field>
          <field>
            <name>CPOL</name>
            <bitOffset>10</bitOffset>
            <bitWidth>1</bitWidth>
          </field>
          <field>
            <name>CLKEN</name>
            <bitOffset>11</bitOffset>
            <bitWidth>1</bitWidth>
          </field>
          <field>
            <name>STOP</name>
            <bitOffset>12</bitOffset>
            <bitWidth>2</bitWidth>
          </field>
          <field>
            <name>LINEN</name>
            <bitOffset>14</bitOffset>
            <bitWidth>1</bitWidth>
          </field>
        </fields>
      </register>
      <register>
        <name>CR3</name>
        <addressOffset>0x14</addressOffset>
        <size>0x20</size>
        <fields>
          <field>
            <name>EIE</name>
            <bitOffset>0</bitOffset>
            <bitWidth>1</bitWidth>
          </field>
          <field>
            <name>IREN</name>
            <bitOffset>1</bitOffset>
            <bitWidth>1</bitWidth>
          </field>
          <field>
            <name>IRLP</name>
            <bitOffset>2</bitOffset>
            <bitWidth>1</bitWidth>
          </field>
          <field>
            <name>HDSEL</name>
            <bitOffset>3</bitOffset>
            <bitWidth>1</bitWidth>
          </field>
          <field>
            <name>NACK</name>
            <bitOffset>4</bitOffset>
            <bitWidth>1</bitWidth>
          </field>
          <field>
            <name>SCEN</name>
            <bitOffset>5</bitOffset>
            <bitWidth>1</bitWidth>
          </field>
          <field>
            <name>DMAR</name>
            <bitOffset>6</bitOffset>
            <bitWidth>1</bitWidth>
          </field>
          <field>
            <name>DMAT</name>
            <bitOffset>7</bitOffset>
            <bitWidth>1</bitWidth>
          </field>
          <field>
            <name>RTSE</name>
            <bitOffset>8</bitOffset>
            <bitWidth>1</bitWidth>
          </field>
          <field>
            <name>CTSE</name>
            <bitOffset>9</bitOffset>
            <bitWidth>1</bitWidth>
          </field>
          <field>
            <name>CTSIE</name>
            <bitOffset>10</bitOffset>
            <bitWidth>1</bitWidth>
          </field>
          <field>
            <name>ONEBIT</name>
            <bitOffset>11</bitOffset>
            <bitWidth>1</bitWidth>
          </field>
        </fields>
      </register>
      <register>
        <name>GTPR</name>
        <addressOffset>0x18</addressOffset>
        <size>0x20</size>
        <fields>
          <field>
            <name>PSC</name>
            <bitOffset>0</bitOffset>
            <bitWidth>8</bitWidth>
          </field>
          <field>
            <name>GT</name>
            <bitOffset>8</bitOffset>
            <bitWidth>8</bitWidth>
          </field>
        </fields>
      </register>
    </peripheral>
    <peripheral>
      <name>I2C1</name>
      <baseAddress>0x40005400</baseAddress>
      <register>
        <name>CR1</name>
        <addressOffset>0x0</addressOffset>
        <size>0x20</size>
        <fields>
          <field>
            <name>PE</name>
            <bitOffset>0</bitOffset>
            <bitWidth>1</bitWidth>
          </field>
          <field>
            <name>SMBUS</name>
            <bitOffset>1</bitOffset>
            <bitWidth>1</bitWidth>
          </field>
          <field>
            <name>SMBTYPE</name>
            <bitOffset>3</bitOffset>
            <bitWidth>1</bitWidth>
          </field>
          <field>
            <name>ENARP</name>
            <bitOffset>4</bitOffset>
            <bitWidth>1</bitWidth>
          </field>
          <field>
            <name>ENPEC</name>
            <bitOffset>5</bitOffset>
            <bitWidth>1</bitWidth>
          </field>
          <field>
            <name>ENGC</name>
            <bitOffset>6</bitOffset>
            <bitWidth>1</bitWidth>
          </field>
          <field>
            <name>NOSTRETCH</name>
            <bitOffset>7</bitOffset>
            <bitWidth>1</bitWidth>
          </field>
          <field>
            <name>START</name>
            <bitOffset>8</bitOffset>
            <bitWidth>1</bitWidth>
          </field>
          <field>
            <name>STOP</name>
            <bitOffset>9</bitOffset>
            <bitWidth>1</bitWidth>
          </field>
          <field>
            <name>ACK</name>
            <bitOffset>10</bitOffset>
            <bitWidth>1</bitWidth>
          </field>
          <field>
            <name>POS</name>
            <bitOffset>11</bitOffset>
            <bitWidth>1</bitWidth>
          </field>
          <field>
            <name>PEC</name>
            <bitOffset>12</bitOffset>
            <bitWidth>1</bitWidth>
          </field>
          <field>
            <name>ALERT</name>
            <bitOffset>13</bitOffset>
            <bitWidth>1</bitWidth>
          </field>
          <field>
            <name>SWRST</name>
            <bitOffset>15</bitOffset>
            <bitWidth>1</bitWidth>
          </field>
        </fields>
      </register>
      <register>
        <name>CR2</name>
        <addressOffset>0x4</addressOffset>
        <size>0x20</size>
        <fields>
          <field>
            <name>FREQ</name>
            <bitOffset>0</bitOffset>
            <bitWidth>6</bitWidth>
          </field>
          <field>
            <name>ITERREN</name>
            <bitOffset>8</bitOffset>
            <bitWidth>1</bitWidth>
          </field>
          <field>
            <name>ITEVTEN</name>
            <bitOffset>9</bitOffset>
            <bitWidth>1</bitWidth>
          </field>
          <field>
            <name>ITBUFEN</name>
            <bitOffset>10</bitOffset>
            <bitWidth>1</bitWidth>
          </field>
          <field>
            <name>DMAEN</name>
            <bitOffset>11</bitOffset>
            <bitWidth>1</bitWidth>
          </field>
          <field>
            <name>LAST</name>
            <bitOffset>12</bitOffset>
            <bitWidth>1</bitWidth>
          </field>
        </fields>
      </register>
      <register>
        <name>OAR1</name>
        <addressOffset>0x8</addressOffset>
        <size>0x20</size>
        <fields>
          <field>
            <name>ADD0</name>
            <bitOffset>0</bitOffset>
            <bitWidth>1</bitWidth>
          </field>
          <field>
            <name>ADD1</name>
            <bitOffset>1</bitOffset>
            <bitWidth>1</bitWidth>
          </field>
          <field>
            <name>ADD2</name>
            <bitOffset>2</bitOffset>
            <bitWidth>1</bitWidth>
          </field>
          <field>
            <name>ADD3</name>
            <bitOffset>3</bitOffset>
            <bitWidth>1</bitWidth>
          </field>
          <field>
            <name>ADD4</name>
            <bitOffset>4</bitOffset>
            <bitWidth>1</bitWidth>
          </field>
          <field>
            <name>ADD5</name>
            <bitOffset>5</bitOffset>
            <bitWidth>1</bitWidth>
          </field>
          <field>
            <name>ADD6</name>
            <bitOffset>6</bitOffset>
            <bitWidth>1</bitWidth>
          </field>
          <field>
            <name>ADD7</name>
            <bitOffset>7</bitOffset>
            <bitWidth>1</bitWidth>
          </field>
          <field>
            <name>ADD8</name>
            <bitOffset>8</bitOffset>
            <bitWidth>1</bitWidth>
          </field>
          <field>
            <name>ADD9</name>
            <bitOffset>9</bitOffset>
            <bitWidth>1</bitWidth>
          </field>
          <field>
            <name>ADDMODE</name>
            <bitOffset>15</bitOffset>
            <bitWidth>1</bitWidth>
          </field>
        </fields>
      </register>
      <register>
        <name>OAR2</name>
        <addressOffset>0xc</addressOffset>
        <size>0x20</size>
        <fields>
          <field>
            <name>ENDUAL</name>
            <bitOffset>0</bitOffset>
            <bitWidth>1</bitWidth>
          </field>
          <field>
            <name>ADD2</name>
            <bitOffset>1</bitOffset>
            <bitWidth>7</bitWidth>
          </field>
        </fields>
      </register>
      <register>
        <name>DR</name>
        <addressOffset>0x10</addressOffset>
        <size>0x20</size>
        <fields>
          <field>
            <name>DR</name>
            <bitOffset>0</bitOffset>
            <bitWidth>8</bitWidth>
          </field>
        </fields>
      </register>
      <register>
        <name>SR1</name>
        <addressOffset>0x14</addressOffset>
        <size>0x20</size>
        <fields>
          <field>
            <name>SB</name>
            <bitOffset>0</bitOffset>
            <bitWidth>1</bitWidth>
          </field>
          <field>
            <name>ADDR</name>
            <bitOffset>1</bitOffset>
            <bitWidth>1</bitWidth>
          </field>
          <field>
            <name>BTF</name>
            <bitOffset>2</bitOffset>
            <bitWidth>1</bitWidth>
          </field>
          <field>
            <name>ADD10</name>
            <bitOffset>3</bitOffset>
            <bitWidth>1</bitWidth>
          </field>
          <field>
            <name>STOPF</name>
            <bitOffset>4</bitOffset>
            <bitWidth>1</bitWidth>
          </field>
          <field>
            <name>RXNE</name>
            <bitOffset>6</bitOffset>
            <bitWidth>1</bitWidth>
          </field>
          <field>
            <name>TXE</name>
            <bitOffset>7</bitOffset>
            <bitWidth>1</bitWidth>
          </field>
          <field>
            <name>BERR</name>
            <bitOffset>8</bitOffset>
            <bitWidth>1</bitWidth>
          </field>
          <field>
            <name>ARLO</name>
            <bitOffset>9</bitOffset>
            <bitWidth>1</bitWidth>
          </field>
          <field>
            <name>AF</name>
            <bitOffset>10</bitOffset>
            <bitWidth>1</bitWidth>
          </field>
          <field>
            <name>OVR</name>
            <bitOffset>11</bitOffset>
            <bitWidth>1</bitWidth>
          </field>
          <field>
            <name>PECERR</name>
            <bitOffset>12</bitOffset>
            <bitWidth>1</bitWidth>
          </field>
          <field>
            <name>TIMEOUT</name>
            <bitOffset>14</bitOffset>
            <bitWidth>1</bitWidth>
          </field>
          <field>
            <name>SMBALERT</name>
            <bitOffset>15</bitOffset>
            <bitWidth>1</bitWidth>
          </field>
        </fields>
      </register>
      <register>
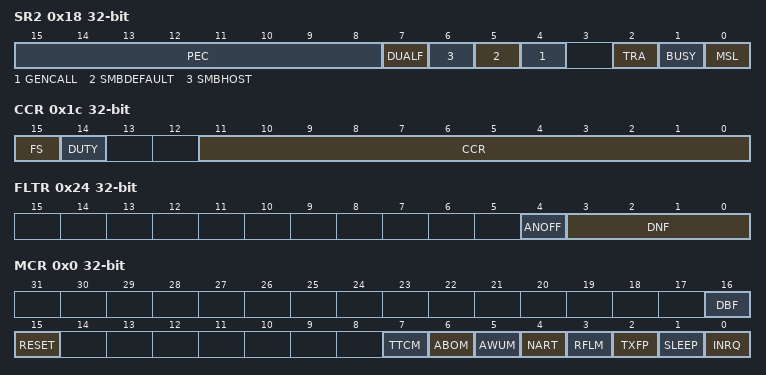
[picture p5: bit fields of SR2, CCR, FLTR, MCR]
        <name>SR2</name>
        <addressOffset>0x18</addressOffset>
        <size>0x20</size>
        <fields>
          <field>
            <name>MSL</name>
            <bitOffset>0</bitOffset>
            <bitWidth>1</bitWidth>
          </field>
          <field>
            <name>BUSY</name>
            <bitOffset>1</bitOffset>
            <bitWidth>1</bitWidth>
          </field>
          <field>
            <name>TRA</name>
            <bitOffset>2</bitOffset>
            <bitWidth>1</bitWidth>
          </field>
          <field>
            <name>GENCALL</name>
            <bitOffset>4</bitOffset>
            <bitWidth>1</bitWidth>
          </field>
          <field>
            <name>SMBDEFAULT</name>
            <bitOffset>5</bitOffset>
            <bitWidth>1</bitWidth>
          </field>
          <field>
            <name>SMBHOST</name>
            <bitOffset>6</bitOffset>
            <bitWidth>1</bitWidth>
          </field>
          <field>
            <name>DUALF</name>
            <bitOffset>7</bitOffset>
            <bitWidth>1</bitWidth>
          </field>
          <field>
            <name>PEC</name>
            <bitOffset>8</bitOffset>
            <bitWidth>8</bitWidth>
          </field>
        </fields>
      </register>
      <register>
        <name>CCR</name>
        <addressOffset>0x1c</addressOffset>
        <size>0x20</size>
        <fields>
          <field>
            <name>CCR</name>
            <bitOffset>0</bitOffset>
            <bitWidth>12</bitWidth>
          </field>
          <field>
            <name>DUTY</name>
            <bitOffset>14</bitOffset>
            <bitWidth>1</bitWidth>
          </field>
          <field>
            <name>FS</name>
            <bitOffset>15</bitOffset>
            <bitWidth>1</bitWidth>
          </field>
        </fields>
      </register>
      <register>
        <name>TRISE</name>
        <addressOffset>0x20</addressOffset>
        <size>0x20</size>
        <fields>
          <field>
            <name>TRISE</name>
            <bitOffset>0</bitOffset>
            <bitWidth>6</bitWidth>
          </field>
        </fields>
      </register>
      <register>
        <name>FLTR</name>
        <addressOffset>0x24</addressOffset>
        <size>0x20</size>
        <fields>
          <field>
            <name>DNF</name>
            <bitOffset>0</bitOffset>
            <bitWidth>4</bitWidth>
          </field>
          <field>
            <name>ANOFF</name>
            <bitOffset>4</bitOffset>
            <bitWidth>1</bitWidth>
          </field>
        </fields>
      </register>
    </peripheral>
    <peripheral>
      <name>I2C2</name>
      <baseAddress>0x40005800</baseAddress>
      <register>
        <name>CR1</name>
        <addressOffset>0x0</addressOffset>
        <size>0x20</size>
        <fields>
          <field>
            <name>PE</name>
            <bitOffset>0</bitOffset>
            <bitWidth>1</bitWidth>
          </field>
          <field>
            <name>SMBUS</name>
            <bitOffset>1</bitOffset>
            <bitWidth>1</bitWidth>
          </field>
          <field>
            <name>SMBTYPE</name>
            <bitOffset>3</bitOffset>
            <bitWidth>1</bitWidth>
          </field>
          <field>
            <name>ENARP</name>
            <bitOffset>4</bitOffset>
            <bitWidth>1</bitWidth>
          </field>
          <field>
            <name>ENPEC</name>
            <bitOffset>5</bitOffset>
            <bitWidth>1</bitWidth>
          </field>
          <field>
            <name>ENGC</name>
            <bitOffset>6</bitOffset>
            <bitWidth>1</bitWidth>
          </field>
          <field>
            <name>NOSTRETCH</name>
            <bitOffset>7</bitOffset>
            <bitWidth>1</bitWidth>
          </field>
          <field>
            <name>START</name>
            <bitOffset>8</bitOffset>
            <bitWidth>1</bitWidth>
          </field>
          <field>
            <name>STOP</name>
            <bitOffset>9</bitOffset>
            <bitWidth>1</bitWidth>
          </field>
          <field>
            <name>ACK</name>
            <bitOffset>10</bitOffset>
            <bitWidth>1</bitWidth>
          </field>
          <field>
            <name>POS</name>
            <bitOffset>11</bitOffset>
            <bitWidth>1</bitWidth>
          </field>
          <field>
            <name>PEC</name>
            <bitOffset>12</bitOffset>
            <bitWidth>1</bitWidth>
          </field>
          <field>
            <name>ALERT</name>
            <bitOffset>13</bitOffset>
            <bitWidth>1</bitWidth>
          </field>
          <field>
            <name>SWRST</name>
            <bitOffset>15</bitOffset>
            <bitWidth>1</bitWidth>
          </field>
        </fields>
      </register>
      <register>
        <name>CR2</name>
        <addressOffset>0x4</addressOffset>
        <size>0x20</size>
        <fields>
          <field>
            <name>FREQ</name>
            <bitOffset>0</bitOffset>
            <bitWidth>6</bitWidth>
          </field>
          <field>
            <name>ITERREN</name>
            <bitOffset>8</bitOffset>
            <bitWidth>1</bitWidth>
          </field>
          <field>
            <name>ITEVTEN</name>
            <bitOffset>9</bitOffset>
            <bitWidth>1</bitWidth>
          </field>
          <field>
            <name>ITBUFEN</name>
            <bitOffset>10</bitOffset>
            <bitWidth>1</bitWidth>
          </field>
          <field>
            <name>DMAEN</name>
            <bitOffset>11</bitOffset>
            <bitWidth>1</bitWidth>
          </field>
          <field>
            <name>LAST</name>
            <bitOffset>12</bitOffset>
            <bitWidth>1</bitWidth>
          </field>
        </fields>
      </register>
      <register>
        <name>OAR1</name>
        <addressOffset>0x8</addressOffset>
        <size>0x20</size>
        <fields>
          <field>
            <name>ADD0</name>
            <bitOffset>0</bitOffset>
            <bitWidth>1</bitWidth>
          </field>
          <field>
            <name>ADD1</name>
            <bitOffset>1</bitOffset>
            <bitWidth>1</bitWidth>
          </field>
          <field>
            <name>ADD2</name>
            <bitOffset>2</bitOffset>
            <bitWidth>1</bitWidth>
          </field>
          <field>
            <name>ADD3</name>
            <bitOffset>3</bitOffset>
            <bitWidth>1</bitWidth>
          </field>
          <field>
            <name>ADD4</name>
            <bitOffset>4</bitOffset>
            <bitWidth>1</bitWidth>
          </field>
          <field>
            <name>ADD5</name>
            <bitOffset>5</bitOffset>
            <bitWidth>1</bitWidth>
          </field>
          <field>
            <name>ADD6</name>
            <bitOffset>6</bitOffset>
            <bitWidth>1</bitWidth>
          </field>
          <field>
            <name>ADD7</name>
            <bitOffset>7</bitOffset>
            <bitWidth>1</bitWidth>
          </field>
          <field>
            <name>ADD8</name>
            <bitOffset>8</bitOffset>
            <bitWidth>1</bitWidth>
          </field>
          <field>
            <name>ADD9</name>
            <bitOffset>9</bitOffset>
            <bitWidth>1</bitWidth>
          </field>
          <field>
            <name>ADDMODE</name>
            <bitOffset>15</bitOffset>
            <bitWidth>1</bitWidth>
          </field>
        </fields>
      </register>
      <register>
        <name>OAR2</name>
        <addressOffset>0xc</addressOffset>
        <size>0x20</size>
        <fields>
          <field>
            <name>ENDUAL</name>
            <bitOffset>0</bitOffset>
            <bitWidth>1</bitWidth>
          </field>
          <field>
            <name>ADD2</name>
            <bitOffset>1</bitOffset>
            <bitWidth>7</bitWidth>
          </field>
        </fields>
      </register>
      <register>
        <name>DR</name>
        <addressOffset>0x10</addressOffset>
        <size>0x20</size>
        <fields>
          <field>
            <name>DR</name>
            <bitOffset>0</bitOffset>
            <bitWidth>8</bitWidth>
          </field>
        </fields>
      </register>
      <register>
        <name>SR1</name>
        <addressOffset>0x14</addressOffset>
        <size>0x20</size>
        <fields>
          <field>
            <name>SB</name>
            <bitOffset>0</bitOffset>
            <bitWidth>1</bitWidth>
          </field>
          <field>
            <name>ADDR</name>
            <bitOffset>1</bitOffset>
            <bitWidth>1</bitWidth>
          </field>
          <field>
            <name>BTF</name>
            <bitOffset>2</bitOffset>
            <bitWidth>1</bitWidth>
          </field>
          <field>
            <name>ADD10</name>
            <bitOffset>3</bitOffset>
            <bitWidth>1</bitWidth>
          </field>
          <field>
            <name>STOPF</name>
            <bitOffset>4</bitOffset>
            <bitWidth>1</bitWidth>
          </field>
          <field>
            <name>RXNE</name>
            <bitOffset>6</bitOffset>
            <bitWidth>1</bitWidth>
          </field>
          <field>
            <name>TXE</name>
            <bitOffset>7</bitOffset>
            <bitWidth>1</bitWidth>
          </field>
          <field>
            <name>BERR</name>
            <bitOffset>8</bitOffset>
            <bitWidth>1</bitWidth>
          </field>
          <field>
            <name>ARLO</name>
            <bitOffset>9</bitOffset>
            <bitWidth>1</bitWidth>
          </field>
          <field>
            <name>AF</name>
            <bitOffset>10</bitOffset>
            <bitWidth>1</bitWidth>
          </field>
          <field>
            <name>OVR</name>
            <bitOffset>11</bitOffset>
            <bitWidth>1</bitWidth>
          </field>
          <field>
            <name>PECERR</name>
            <bitOffset>12</bitOffset>
            <bitWidth>1</bitWidth>
          </field>
          <field>
            <name>TIMEOUT</name>
            <bitOffset>14</bitOffset>
            <bitWidth>1</bitWidth>
          </field>
          <field>
            <name>SMBALERT</name>
            <bitOffset>15</bitOffset>
            <bitWidth>1</bitWidth>
          </field>
        </fields>
      </register>
      <register>
        <name>SR2</name>
        <addressOffset>0x18</addressOffset>
        <size>0x20</size>
        <fields>
          <field>
            <name>MSL</name>
            <bitOffset>0</bitOffset>
            <bitWidth>1</bitWidth>
          </field>
          <field>
            <name>BUSY</name>
            <bitOffset>1</bitOffset>
            <bitWidth>1</bitWidth>
          </field>
          <field>
            <name>TRA</name>
            <bitOffset>2</bitOffset>
            <bitWidth>1</bitWidth>
          </field>
          <field>
            <name>GENCALL</name>
            <bitOffset>4</bitOffset>
            <bitWidth>1</bitWidth>
          </field>
          <field>
            <name>SMBDEFAULT</name>
            <bitOffset>5</bitOffset>
            <bitWidth>1</bitWidth>
          </field>
          <field>
            <name>SMBHOST</name>
            <bitOffset>6</bitOffset>
            <bitWidth>1</bitWidth>
          </field>
          <field>
            <name>DUALF</name>
            <bitOffset>7</bitOffset>
            <bitWidth>1</bitWidth>
          </field>
          <field>
            <name>PEC</name>
            <bitOffset>8</bitOffset>
            <bitWidth>8</bitWidth>
          </field>
        </fields>
      </register>
      <register>
        <name>CCR</name>
        <addressOffset>0x1c</addressOffset>
        <size>0x20</size>
        <fields>
          <field>
            <name>CCR</name>
            <bitOffset>0</bitOffset>
            <bitWidth>12</bitWidth>
          </field>
          <field>
            <name>DUTY</name>
            <bitOffset>14</bitOffset>
            <bitWidth>1</bitWidth>
          </field>
          <field>
            <name>FS</name>
            <bitOffset>15</bitOffset>
            <bitWidth>1</bitWidth>
          </field>
        </fields>
      </register>
      <register>
        <name>TRISE</name>
        <addressOffset>0x20</addressOffset>
        <size>0x20</size>
        <fields>
          <field>
            <name>TRISE</name>
            <bitOffset>0</bitOffset>
            <bitWidth>6</bitWidth>
          </field>
        </fields>
      </register>
      <register>
        <name>FLTR</name>
        <addressOffset>0x24</addressOffset>
        <size>0x20</size>
        <fields>
          <field>
            <name>DNF</name>
            <bitOffset>0</bitOffset>
            <bitWidth>4</bitWidth>
          </field>
          <field>
            <name>ANOFF</name>
            <bitOffset>4</bitOffset>
            <bitWidth>1</bitWidth>
          </field>
        </fields>
      </register>
    </peripheral>
    <peripheral>
      <name>I2C3</name>
      <baseAddress>0x40005c00</baseAddress>
      <register>
        <name>CR1</name>
        <addressOffset>0x0</addressOffset>
        <size>0x20</size>
        <fields>
          <field>
            <name>PE</name>
            <bitOffset>0</bitOffset>
            <bitWidth>1</bitWidth>
          </field>
          <field>
            <name>SMBUS</name>
            <bitOffset>1</bitOffset>
            <bitWidth>1</bitWidth>
          </field>
          <field>
            <name>SMBTYPE</name>
            <bitOffset>3</bitOffset>
            <bitWidth>1</bitWidth>
          </field>
          <field>
            <name>ENARP</name>
            <bitOffset>4</bitOffset>
            <bitWidth>1</bitWidth>
          </field>
          <field>
            <name>ENPEC</name>
            <bitOffset>5</bitOffset>
            <bitWidth>1</bitWidth>
          </field>
          <field>
            <name>ENGC</name>
            <bitOffset>6</bitOffset>
            <bitWidth>1</bitWidth>
          </field>
          <field>
            <name>NOSTRETCH</name>
            <bitOffset>7</bitOffset>
            <bitWidth>1</bitWidth>
          </field>
          <field>
            <name>START</name>
            <bitOffset>8</bitOffset>
            <bitWidth>1</bitWidth>
          </field>
          <field>
            <name>STOP</name>
            <bitOffset>9</bitOffset>
            <bitWidth>1</bitWidth>
          </field>
          <field>
            <name>ACK</name>
            <bitOffset>10</bitOffset>
            <bitWidth>1</bitWidth>
          </field>
          <field>
            <name>POS</name>
            <bitOffset>11</bitOffset>
            <bitWidth>1</bitWidth>
          </field>
          <field>
            <name>PEC</name>
            <bitOffset>12</bitOffset>
            <bitWidth>1</bitWidth>
          </field>
          <field>
            <name>ALERT</name>
            <bitOffset>13</bitOffset>
            <bitWidth>1</bitWidth>
          </field>
          <field>
            <name>SWRST</name>
            <bitOffset>15</bitOffset>
            <bitWidth>1</bitWidth>
          </field>
        </fields>
      </register>
      <register>
        <name>CR2</name>
        <addressOffset>0x4</addressOffset>
        <size>0x20</size>
        <fields>
          <field>
            <name>FREQ</name>
            <bitOffset>0</bitOffset>
            <bitWidth>6</bitWidth>
          </field>
          <field>
            <name>ITERREN</name>
            <bitOffset>8</bitOffset>
            <bitWidth>1</bitWidth>
          </field>
          <field>
            <name>ITEVTEN</name>
            <bitOffset>9</bitOffset>
            <bitWidth>1</bitWidth>
          </field>
          <field>
            <name>ITBUFEN</name>
            <bitOffset>10</bitOffset>
            <bitWidth>1</bitWidth>
          </field>
          <field>
            <name>DMAEN</name>
            <bitOffset>11</bitOffset>
            <bitWidth>1</bitWidth>
          </field>
          <field>
            <name>LAST</name>
            <bitOffset>12</bitOffset>
            <bitWidth>1</bitWidth>
          </field>
        </fields>
      </register>
      <register>
        <name>OAR1</name>
        <addressOffset>0x8</addressOffset>
        <size>0x20</size>
        <fields>
          <field>
            <name>ADD0</name>
            <bitOffset>0</bitOffset>
            <bitWidth>1</bitWidth>
          </field>
          <field>
            <name>ADD1</name>
            <bitOffset>1</bitOffset>
            <bitWidth>1</bitWidth>
          </field>
          <field>
            <name>ADD2</name>
            <bitOffset>2</bitOffset>
            <bitWidth>1</bitWidth>
          </field>
          <field>
            <name>ADD3</name>
            <bitOffset>3</bitOffset>
            <bitWidth>1</bitWidth>
          </field>
          <field>
            <name>ADD4</name>
            <bitOffset>4</bitOffset>
            <bitWidth>1</bitWidth>
          </field>
          <field>
            <name>ADD5</name>
            <bitOffset>5</bitOffset>
            <bitWidth>1</bitWidth>
          </field>
          <field>
            <name>ADD6</name>
            <bitOffset>6</bitOffset>
            <bitWidth>1</bitWidth>
          </field>
          <field>
            <name>ADD7</name>
            <bitOffset>7</bitOffset>
            <bitWidth>1</bitWidth>
          </field>
          <field>
            <name>ADD8</name>
            <bitOffset>8</bitOffset>
            <bitWidth>1</bitWidth>
          </field>
          <field>
            <name>ADD9</name>
            <bitOffset>9</bitOffset>
            <bitWidth>1</bitWidth>
          </field>
          <field>
            <name>ADDMODE</name>
            <bitOffset>15</bitOffset>
            <bitWidth>1</bitWidth>
          </field>
        </fields>
      </register>
      <register>
        <name>OAR2</name>
        <addressOffset>0xc</addressOffset>
        <size>0x20</size>
        <fields>
          <field>
            <name>ENDUAL</name>
            <bitOffset>0</bitOffset>
            <bitWidth>1</bitWidth>
          </field>
          <field>
            <name>ADD2</name>
            <bitOffset>1</bitOffset>
            <bitWidth>7</bitWidth>
          </field>
        </fields>
      </register>
      <register>
        <name>DR</name>
        <addressOffset>0x10</addressOffset>
        <size>0x20</size>
        <fields>
          <field>
            <name>DR</name>
            <bitOffset>0</bitOffset>
            <bitWidth>8</bitWidth>
          </field>
        </fields>
      </register>
      <register>
        <name>SR1</name>
        <addressOffset>0x14</addressOffset>
        <size>0x20</size>
        <fields>
          <field>
            <name>SB</name>
            <bitOffset>0</bitOffset>
            <bitWidth>1</bitWidth>
          </field>
          <field>
            <name>ADDR</name>
            <bitOffset>1</bitOffset>
            <bitWidth>1</bitWidth>
          </field>
          <field>
            <name>BTF</name>
            <bitOffset>2</bitOffset>
            <bitWidth>1</bitWidth>
          </field>
          <field>
            <name>ADD10</name>
            <bitOffset>3</bitOffset>
            <bitWidth>1</bitWidth>
          </field>
          <field>
            <name>STOPF</name>
            <bitOffset>4</bitOffset>
            <bitWidth>1</bitWidth>
          </field>
          <field>
            <name>RXNE</name>
            <bitOffset>6</bitOffset>
            <bitWidth>1</bitWidth>
          </field>
          <field>
            <name>TXE</name>
            <bitOffset>7</bitOffset>
            <bitWidth>1</bitWidth>
          </field>
          <field>
            <name>BERR</name>
            <bitOffset>8</bitOffset>
            <bitWidth>1</bitWidth>
          </field>
          <field>
            <name>ARLO</name>
            <bitOffset>9</bitOffset>
            <bitWidth>1</bitWidth>
          </field>
          <field>
            <name>AF</name>
            <bitOffset>10</bitOffset>
            <bitWidth>1</bitWidth>
          </field>
          <field>
            <name>OVR</name>
            <bitOffset>11</bitOffset>
            <bitWidth>1</bitWidth>
          </field>
          <field>
            <name>PECERR</name>
            <bitOffset>12</bitOffset>
            <bitWidth>1</bitWidth>
          </field>
          <field>
            <name>TIMEOUT</name>
            <bitOffset>14</bitOffset>
            <bitWidth>1</bitWidth>
          </field>
          <field>
            <name>SMBALERT</name>
            <bitOffset>15</bitOffset>
            <bitWidth>1</bitWidth>
          </field>
        </fields>
      </register>
      <register>
        <name>SR2</name>
        <addressOffset>0x18</addressOffset>
        <size>0x20</size>
        <fields>
          <field>
            <name>MSL</name>
            <bitOffset>0</bitOffset>
            <bitWidth>1</bitWidth>
          </field>
          <field>
            <name>BUSY</name>
            <bitOffset>1</bitOffset>
            <bitWidth>1</bitWidth>
          </field>
          <field>
            <name>TRA</name>
            <bitOffset>2</bitOffset>
            <bitWidth>1</bitWidth>
          </field>
          <field>
            <name>GENCALL</name>
            <bitOffset>4</bitOffset>
            <bitWidth>1</bitWidth>
          </field>
          <field>
            <name>SMBDEFAULT</name>
            <bitOffset>5</bitOffset>
            <bitWidth>1</bitWidth>
          </field>
          <field>
            <name>SMBHOST</name>
            <bitOffset>6</bitOffset>
            <bitWidth>1</bitWidth>
          </field>
          <field>
            <name>DUALF</name>
            <bitOffset>7</bitOffset>
            <bitWidth>1</bitWidth>
          </field>
          <field>
            <name>PEC</name>
            <bitOffset>8</bitOffset>
            <bitWidth>8</bitWidth>
          </field>
        </fields>
      </register>
      <register>
        <name>CCR</name>
        <addressOffset>0x1c</addressOffset>
        <size>0x20</size>
        <fields>
          <field>
            <name>CCR</name>
            <bitOffset>0</bitOffset>
            <bitWidth>12</bitWidth>
          </field>
          <field>
            <name>DUTY</name>
            <bitOffset>14</bitOffset>
            <bitWidth>1</bitWidth>
          </field>
          <field>
            <name>FS</name>
            <bitOffset>15</bitOffset>
            <bitWidth>1</bitWidth>
          </field>
        </fields>
      </register>
      <register>
        <name>TRISE</name>
        <addressOffset>0x20</addressOffset>
        <size>0x20</size>
        <fields>
          <field>
            <name>TRISE</name>
            <bitOffset>0</bitOffset>
            <bitWidth>6</bitWidth>
          </field>
        </fields>
      </register>
      <register>
        <name>FLTR</name>
        <addressOffset>0x24</addressOffset>
        <size>0x20</size>
        <fields>
          <field>
            <name>DNF</name>
            <bitOffset>0</bitOffset>
            <bitWidth>4</bitWidth>
          </field>
          <field>
            <name>ANOFF</name>
            <bitOffset>4</bitOffset>
            <bitWidth>1</bitWidth>
          </field>
        </fields>
      </register>
    </peripheral>
    <peripheral>
      <name>CAN1</name>
      <baseAddress>0x40006400</baseAddress>
      <register>
        <name>MCR</name>
        <addressOffset>0x0</addressOffset>
        <size>0x20</size>
        <fields>
          <field>
            <name>INRQ</name>
            <bitOffset>0</bitOffset>
            <bitWidth>1</bitWidth>
          </field>
          <field>
            <name>SLEEP</name>
            <bitOffset>1</bitOffset>
            <bitWidth>1</bitWidth>
          </field>
          <field>
            <name>TXFP</name>
            <bitOffset>2</bitOffset>
            <bitWidth>1</bitWidth>
          </field>
          <field>
            <name>RFLM</name>
            <bitOffset>3</bitOffset>
            <bitWidth>1</bitWidth>
          </field>
          <field>
            <name>NART</name>
            <bitOffset>4</bitOffset>
            <bitWidth>1</bitWidth>
          </field>
          <field>
            <name>AWUM</name>
            <bitOffset>5</bitOffset>
            <bitWidth>1</bitWidth>
          </field>
          <field>
            <name>ABOM</name>
            <bitOffset>6</bitOffset>
            <bitWidth>1</bitWidth>
          </field>
          <field>
            <name>TTCM</name>
            <bitOffset>7</bitOffset>
            <bitWidth>1</bitWidth>
          </field>
          <field>
            <name>RESET</name>
            <bitOffset>15</bitOffset>
            <bitWidth>1</bitWidth>
          </field>
          <field>
            <name>DBF</name>
            <bitOffset>16</bitOffset>
            <bitWidth>1</bitWidth>
          </field>
        </fields>
      </register>
      <register>
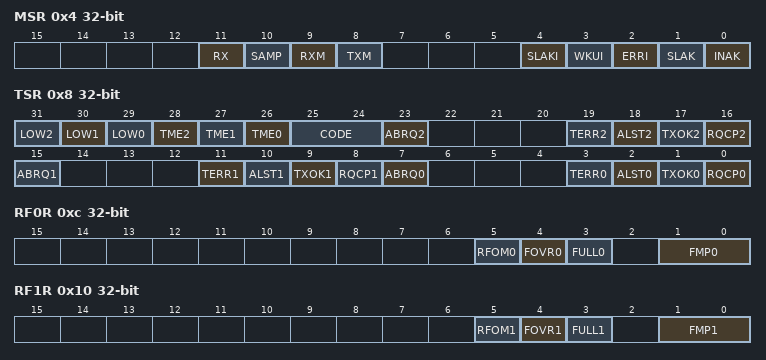
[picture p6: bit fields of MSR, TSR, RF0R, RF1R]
        <name>MSR</name>
        <addressOffset>0x4</addressOffset>
        <size>0x20</size>
        <fields>
          <field>
            <name>INAK</name>
            <bitOffset>0</bitOffset>
            <bitWidth>1</bitWidth>
          </field>
          <field>
            <name>SLAK</name>
            <bitOffset>1</bitOffset>
            <bitWidth>1</bitWidth>
          </field>
          <field>
            <name>ERRI</name>
            <bitOffset>2</bitOffset>
            <bitWidth>1</bitWidth>
          </field>
          <field>
            <name>WKUI</name>
            <bitOffset>3</bitOffset>
            <bitWidth>1</bitWidth>
          </field>
          <field>
            <name>SLAKI</name>
            <bitOffset>4</bitOffset>
            <bitWidth>1</bitWidth>
          </field>
          <field>
            <name>TXM</name>
            <bitOffset>8</bitOffset>
            <bitWidth>1</bitWidth>
          </field>
          <field>
            <name>RXM</name>
            <bitOffset>9</bitOffset>
            <bitWidth>1</bitWidth>
          </field>
          <field>
            <name>SAMP</name>
            <bitOffset>10</bitOffset>
            <bitWidth>1</bitWidth>
          </field>
          <field>
            <name>RX</name>
            <bitOffset>11</bitOffset>
            <bitWidth>1</bitWidth>
          </field>
        </fields>
      </register>
      <register>
        <name>TSR</name>
        <addressOffset>0x8</addressOffset>
        <size>0x20</size>
        <fields>
          <field>
            <name>RQCP0</name>
            <bitOffset>0</bitOffset>
            <bitWidth>1</bitWidth>
          </field>
          <field>
            <name>TXOK0</name>
            <bitOffset>1</bitOffset>
            <bitWidth>1</bitWidth>
          </field>
          <field>
            <name>ALST0</name>
            <bitOffset>2</bitOffset>
            <bitWidth>1</bitWidth>
          </field>
          <field>
            <name>TERR0</name>
            <bitOffset>3</bitOffset>
            <bitWidth>1</bitWidth>
          </field>
          <field>
            <name>ABRQ0</name>
            <bitOffset>7</bitOffset>
            <bitWidth>1</bitWidth>
          </field>
          <field>
            <name>RQCP1</name>
            <bitOffset>8</bitOffset>
            <bitWidth>1</bitWidth>
          </field>
          <field>
            <name>TXOK1</name>
            <bitOffset>9</bitOffset>
            <bitWidth>1</bitWidth>
          </field>
          <field>
            <name>ALST1</name>
            <bitOffset>10</bitOffset>
            <bitWidth>1</bitWidth>
          </field>
          <field>
            <name>TERR1</name>
            <bitOffset>11</bitOffset>
            <bitWidth>1</bitWidth>
          </field>
          <field>
            <name>ABRQ1</name>
            <bitOffset>15</bitOffset>
            <bitWidth>1</bitWidth>
          </field>
          <field>
            <name>RQCP2</name>
            <bitOffset>16</bitOffset>
            <bitWidth>1</bitWidth>
          </field>
          <field>
            <name>TXOK2</name>
            <bitOffset>17</bitOffset>
            <bitWidth>1</bitWidth>
          </field>
          <field>
            <name>ALST2</name>
            <bitOffset>18</bitOffset>
            <bitWidth>1</bitWidth>
          </field>
          <field>
            <name>TERR2</name>
            <bitOffset>19</bitOffset>
            <bitWidth>1</bitWidth>
          </field>
          <field>
            <name>ABRQ2</name>
            <bitOffset>23</bitOffset>
            <bitWidth>1</bitWidth>
          </field>
          <field>
            <name>CODE</name>
            <bitOffset>24</bitOffset>
            <bitWidth>2</bitWidth>
          </field>
          <field>
            <name>TME0</name>
            <bitOffset>26</bitOffset>
            <bitWidth>1</bitWidth>
          </field>
          <field>
            <name>TME1</name>
            <bitOffset>27</bitOffset>
            <bitWidth>1</bitWidth>
          </field>
          <field>
            <name>TME2</name>
            <bitOffset>28</bitOffset>
            <bitWidth>1</bitWidth>
          </field>
          <field>
            <name>LOW0</name>
            <bitOffset>29</bitOffset>
            <bitWidth>1</bitWidth>
          </field>
          <field>
            <name>LOW1</name>
            <bitOffset>30</bitOffset>
            <bitWidth>1</bitWidth>
          </field>
          <field>
            <name>LOW2</name>
            <bitOffset>31</bitOffset>
            <bitWidth>1</bitWidth>
          </field>
        </fields>
      </register>
      <register>
        <name>RF0R</name>
        <addressOffset>0xc</addressOffset>
        <size>0x20</size>
        <fields>
          <field>
            <name>FMP0</name>
            <bitOffset>0</bitOffset>
            <bitWidth>2</bitWidth>
          </field>
          <field>
            <name>FULL0</name>
            <bitOffset>3</bitOffset>
            <bitWidth>1</bitWidth>
          </field>
          <field>
            <name>FOVR0</name>
            <bitOffset>4</bitOffset>
            <bitWidth>1</bitWidth>
          </field>
          <field>
            <name>RFOM0</name>
            <bitOffset>5</bitOffset>
            <bitWidth>1</bitWidth>
          </field>
        </fields>
      </register>
      <register>
        <name>RF1R</name>
        <addressOffset>0x10</addressOffset>
        <size>0x20</size>
        <fields>
          <field>
            <name>FMP1</name>
            <bitOffset>0</bitOffset>
            <bitWidth>2</bitWidth>
          </field>
          <field>
            <name>FULL1</name>
            <bitOffset>3</bitOffset>
            <bitWidth>1</bitWidth>
          </field>
          <field>
            <name>FOVR1</name>
            <bitOffset>4</bitOffset>
            <bitWidth>1</bitWidth>
          </field>
          <field>
            <name>RFOM1</name>
            <bitOffset>5</bitOffset>
            <bitWidth>1</bitWidth>
          </field>
        </fields>
      </register>
      <register>
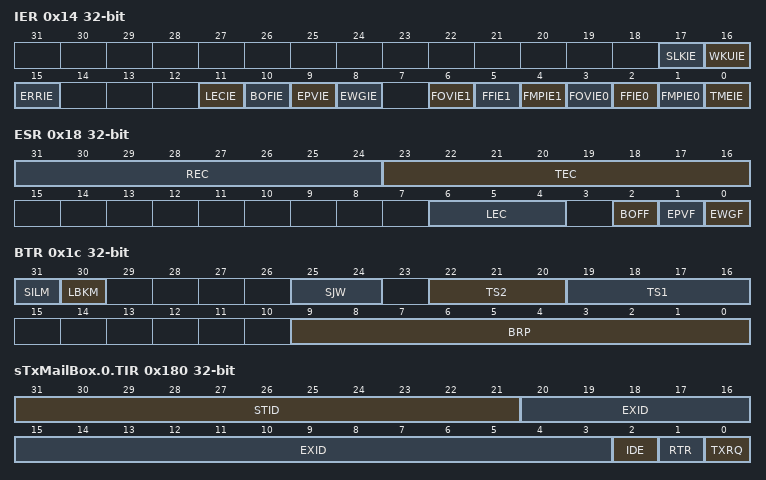
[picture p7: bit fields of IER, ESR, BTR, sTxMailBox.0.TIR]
        <name>IER</name>
        <addressOffset>0x14</addressOffset>
        <size>0x20</size>
        <fields>
          <field>
            <name>TMEIE</name>
            <bitOffset>0</bitOffset>
            <bitWidth>1</bitWidth>
          </field>
          <field>
            <name>FMPIE0</name>
            <bitOffset>1</bitOffset>
            <bitWidth>1</bitWidth>
          </field>
          <field>
            <name>FFIE0</name>
            <bitOffset>2</bitOffset>
            <bitWidth>1</bitWidth>
          </field>
          <field>
            <name>FOVIE0</name>
            <bitOffset>3</bitOffset>
            <bitWidth>1</bitWidth>
          </field>
          <field>
            <name>FMPIE1</name>
            <bitOffset>4</bitOffset>
            <bitWidth>1</bitWidth>
          </field>
          <field>
            <name>FFIE1</name>
            <bitOffset>5</bitOffset>
            <bitWidth>1</bitWidth>
          </field>
          <field>
            <name>FOVIE1</name>
            <bitOffset>6</bitOffset>
            <bitWidth>1</bitWidth>
          </field>
          <field>
            <name>EWGIE</name>
            <bitOffset>8</bitOffset>
            <bitWidth>1</bitWidth>
          </field>
          <field>
            <name>EPVIE</name>
            <bitOffset>9</bitOffset>
            <bitWidth>1</bitWidth>
          </field>
          <field>
            <name>BOFIE</name>
            <bitOffset>10</bitOffset>
            <bitWidth>1</bitWidth>
          </field>
          <field>
            <name>LECIE</name>
            <bitOffset>11</bitOffset>
            <bitWidth>1</bitWidth>
          </field>
          <field>
            <name>ERRIE</name>
            <bitOffset>15</bitOffset>
            <bitWidth>1</bitWidth>
          </field>
          <field>
            <name>WKUIE</name>
            <bitOffset>16</bitOffset>
            <bitWidth>1</bitWidth>
          </field>
          <field>
            <name>SLKIE</name>
            <bitOffset>17</bitOffset>
            <bitWidth>1</bitWidth>
          </field>
        </fields>
      </register>
      <register>
        <name>ESR</name>
        <addressOffset>0x18</addressOffset>
        <size>0x20</size>
        <fields>
          <field>
            <name>EWGF</name>
            <bitOffset>0</bitOffset>
            <bitWidth>1</bitWidth>
          </field>
          <field>
            <name>EPVF</name>
            <bitOffset>1</bitOffset>
            <bitWidth>1</bitWidth>
          </field>
          <field>
            <name>BOFF</name>
            <bitOffset>2</bitOffset>
            <bitWidth>1</bitWidth>
          </field>
          <field>
            <name>LEC</name>
            <bitOffset>4</bitOffset>
            <bitWidth>3</bitWidth>
          </field>
          <field>
            <name>TEC</name>
            <bitOffset>16</bitOffset>
            <bitWidth>8</bitWidth>
          </field>
          <field>
            <name>REC</name>
            <bitOffset>24</bitOffset>
            <bitWidth>8</bitWidth>
          </field>
        </fields>
      </register>
      <register>
        <name>BTR</name>
        <addressOffset>0x1c</addressOffset>
        <size>0x20</size>
        <fields>
          <field>
            <name>BRP</name>
            <bitOffset>0</bitOffset>
            <bitWidth>10</bitWidth>
          </field>
          <field>
            <name>TS1</name>
            <bitOffset>16</bitOffset>
            <bitWidth>4</bitWidth>
          </field>
          <field>
            <name>TS2</name>
            <bitOffset>20</bitOffset>
            <bitWidth>3</bitWidth>
          </field>
          <field>
            <name>SJW</name>
            <bitOffset>24</bitOffset>
            <bitWidth>2</bitWidth>
          </field>
          <field>
            <name>LBKM</name>
            <bitOffset>30</bitOffset>
            <bitWidth>1</bitWidth>
          </field>
          <field>
            <name>SILM</name>
            <bitOffset>31</bitOffset>
            <bitWidth>1</bitWidth>
          </field>
        </fields>
      </register>
      <register>
        <name>sTxMailBox.0.TIR</name>
        <addressOffset>0x180</addressOffset>
        <size>0x20</size>
        <fields>
          <field>
            <name>TXRQ</name>
            <bitOffset>0</bitOffset>
            <bitWidth>1</bitWidth>
          </field>
          <field>
            <name>RTR</name>
            <bitOffset>1</bitOffset>
            <bitWidth>1</bitWidth>
          </field>
          <field>
            <name>IDE</name>
            <bitOffset>2</bitOffset>
            <bitWidth>1</bitWidth>
          </field>
          <field>
            <name>EXID</name>
            <bitOffset>3</bitOffset>
            <bitWidth>18</bitWidth>
          </field>
          <field>
            <name>STID</name>
            <bitOffset>21</bitOffset>
            <bitWidth>11</bitWidth>
          </field>
        </fields>
      </register>
      <register>
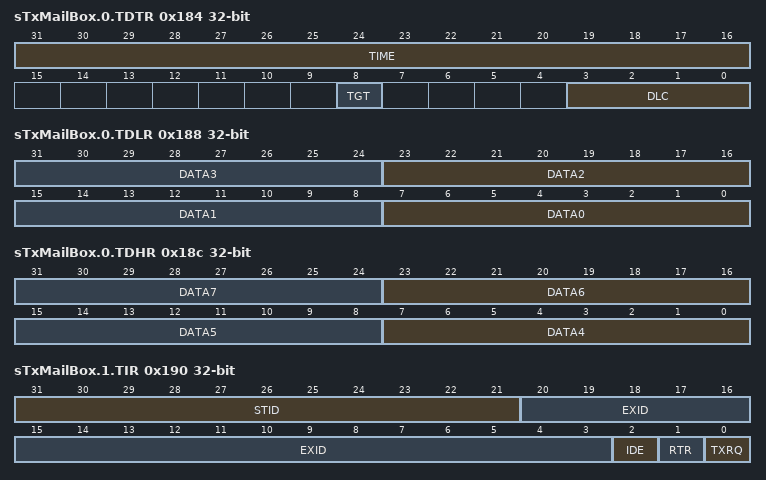
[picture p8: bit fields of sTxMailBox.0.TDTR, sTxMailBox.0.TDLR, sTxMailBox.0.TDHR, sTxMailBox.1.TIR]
        <name>sTxMailBox.0.TDTR</name>
        <addressOffset>0x184</addressOffset>
        <size>0x20</size>
        <fields>
          <field>
            <name>DLC</name>
            <bitOffset>0</bitOffset>
            <bitWidth>4</bitWidth>
          </field>
          <field>
            <name>TGT</name>
            <bitOffset>8</bitOffset>
            <bitWidth>1</bitWidth>
          </field>
          <field>
            <name>TIME</name>
            <bitOffset>16</bitOffset>
            <bitWidth>16</bitWidth>
          </field>
        </fields>
      </register>
      <register>
        <name>sTxMailBox.0.TDLR</name>
        <addressOffset>0x188</addressOffset>
        <size>0x20</size>
        <fields>
          <field>
            <name>DATA0</name>
            <bitOffset>0</bitOffset>
            <bitWidth>8</bitWidth>
          </field>
          <field>
            <name>DATA1</name>
            <bitOffset>8</bitOffset>
            <bitWidth>8</bitWidth>
          </field>
          <field>
            <name>DATA2</name>
            <bitOffset>16</bitOffset>
            <bitWidth>8</bitWidth>
          </field>
          <field>
            <name>DATA3</name>
            <bitOffset>24</bitOffset>
            <bitWidth>8</bitWidth>
          </field>
        </fields>
      </register>
      <register>
        <name>sTxMailBox.0.TDHR</name>
        <addressOffset>0x18c</addressOffset>
        <size>0x20</size>
        <fields>
          <field>
            <name>DATA4</name>
            <bitOffset>0</bitOffset>
            <bitWidth>8</bitWidth>
          </field>
          <field>
            <name>DATA5</name>
            <bitOffset>8</bitOffset>
            <bitWidth>8</bitWidth>
          </field>
          <field>
            <name>DATA6</name>
            <bitOffset>16</bitOffset>
            <bitWidth>8</bitWidth>
          </field>
          <field>
            <name>DATA7</name>
            <bitOffset>24</bitOffset>
            <bitWidth>8</bitWidth>
          </field>
        </fields>
      </register>
      <register>
        <name>sTxMailBox.1.TIR</name>
        <addressOffset>0x190</addressOffset>
        <size>0x20</size>
        <fields>
          <field>
            <name>TXRQ</name>
            <bitOffset>0</bitOffset>
            <bitWidth>1</bitWidth>
          </field>
          <field>
            <name>RTR</name>
            <bitOffset>1</bitOffset>
            <bitWidth>1</bitWidth>
          </field>
          <field>
            <name>IDE</name>
            <bitOffset>2</bitOffset>
            <bitWidth>1</bitWidth>
          </field>
          <field>
            <name>EXID</name>
            <bitOffset>3</bitOffset>
            <bitWidth>18</bitWidth>
          </field>
          <field>
            <name>STID</name>
            <bitOffset>21</bitOffset>
            <bitWidth>11</bitWidth>
          </field>
        </fields>
      </register>
      <register>
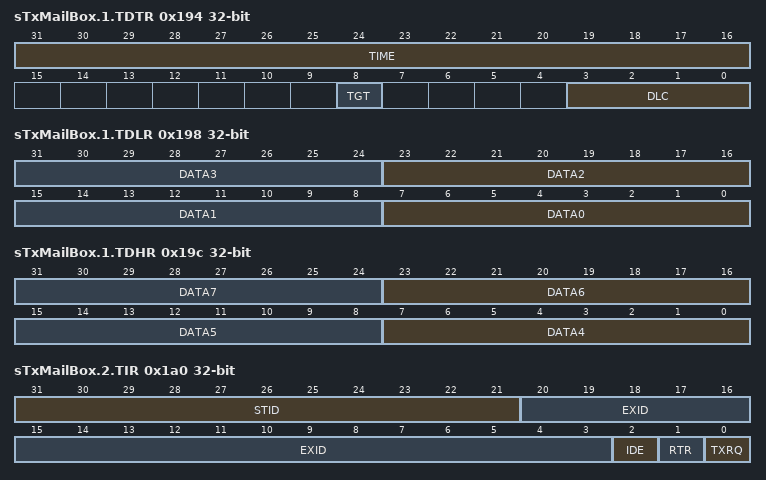
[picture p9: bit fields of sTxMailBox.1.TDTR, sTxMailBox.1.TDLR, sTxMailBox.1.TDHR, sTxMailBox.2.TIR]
        <name>sTxMailBox.1.TDTR</name>
        <addressOffset>0x194</addressOffset>
        <size>0x20</size>
        <fields>
          <field>
            <name>DLC</name>
            <bitOffset>0</bitOffset>
            <bitWidth>4</bitWidth>
          </field>
          <field>
            <name>TGT</name>
            <bitOffset>8</bitOffset>
            <bitWidth>1</bitWidth>
          </field>
          <field>
            <name>TIME</name>
            <bitOffset>16</bitOffset>
            <bitWidth>16</bitWidth>
          </field>
        </fields>
      </register>
      <register>
        <name>sTxMailBox.1.TDLR</name>
        <addressOffset>0x198</addressOffset>
        <size>0x20</size>
        <fields>
          <field>
            <name>DATA0</name>
            <bitOffset>0</bitOffset>
            <bitWidth>8</bitWidth>
          </field>
          <field>
            <name>DATA1</name>
            <bitOffset>8</bitOffset>
            <bitWidth>8</bitWidth>
          </field>
          <field>
            <name>DATA2</name>
            <bitOffset>16</bitOffset>
            <bitWidth>8</bitWidth>
          </field>
          <field>
            <name>DATA3</name>
            <bitOffset>24</bitOffset>
            <bitWidth>8</bitWidth>
          </field>
        </fields>
      </register>
      <register>
        <name>sTxMailBox.1.TDHR</name>
        <addressOffset>0x19c</addressOffset>
        <size>0x20</size>
        <fields>
          <field>
            <name>DATA4</name>
            <bitOffset>0</bitOffset>
            <bitWidth>8</bitWidth>
          </field>
          <field>
            <name>DATA5</name>
            <bitOffset>8</bitOffset>
            <bitWidth>8</bitWidth>
          </field>
          <field>
            <name>DATA6</name>
            <bitOffset>16</bitOffset>
            <bitWidth>8</bitWidth>
          </field>
          <field>
            <name>DATA7</name>
            <bitOffset>24</bitOffset>
            <bitWidth>8</bitWidth>
          </field>
        </fields>
      </register>
      <register>
        <name>sTxMailBox.2.TIR</name>
        <addressOffset>0x1a0</addressOffset>
        <size>0x20</size>
        <fields>
          <field>
            <name>TXRQ</name>
            <bitOffset>0</bitOffset>
            <bitWidth>1</bitWidth>
          </field>
          <field>
            <name>RTR</name>
            <bitOffset>1</bitOffset>
            <bitWidth>1</bitWidth>
          </field>
          <field>
            <name>IDE</name>
            <bitOffset>2</bitOffset>
            <bitWidth>1</bitWidth>
          </field>
          <field>
            <name>EXID</name>
            <bitOffset>3</bitOffset>
            <bitWidth>18</bitWidth>
          </field>
          <field>
            <name>STID</name>
            <bitOffset>21</bitOffset>
            <bitWidth>11</bitWidth>
          </field>
        </fields>
      </register>
      <register>
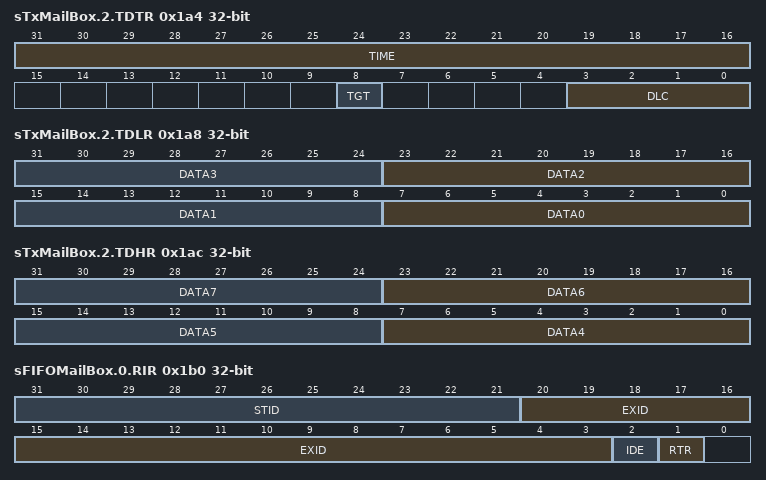
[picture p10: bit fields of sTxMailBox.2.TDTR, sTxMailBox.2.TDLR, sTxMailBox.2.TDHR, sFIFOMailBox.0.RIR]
        <name>sTxMailBox.2.TDTR</name>
        <addressOffset>0x1a4</addressOffset>
        <size>0x20</size>
        <fields>
          <field>
            <name>DLC</name>
            <bitOffset>0</bitOffset>
            <bitWidth>4</bitWidth>
          </field>
          <field>
            <name>TGT</name>
            <bitOffset>8</bitOffset>
            <bitWidth>1</bitWidth>
          </field>
          <field>
            <name>TIME</name>
            <bitOffset>16</bitOffset>
            <bitWidth>16</bitWidth>
          </field>
        </fields>
      </register>
      <register>
        <name>sTxMailBox.2.TDLR</name>
        <addressOffset>0x1a8</addressOffset>
        <size>0x20</size>
        <fields>
          <field>
            <name>DATA0</name>
            <bitOffset>0</bitOffset>
            <bitWidth>8</bitWidth>
          </field>
          <field>
            <name>DATA1</name>
            <bitOffset>8</bitOffset>
            <bitWidth>8</bitWidth>
          </field>
          <field>
            <name>DATA2</name>
            <bitOffset>16</bitOffset>
            <bitWidth>8</bitWidth>
          </field>
          <field>
            <name>DATA3</name>
            <bitOffset>24</bitOffset>
            <bitWidth>8</bitWidth>
          </field>
        </fields>
      </register>
      <register>
        <name>sTxMailBox.2.TDHR</name>
        <addressOffset>0x1ac</addressOffset>
        <size>0x20</size>
        <fields>
          <field>
            <name>DATA4</name>
            <bitOffset>0</bitOffset>
            <bitWidth>8</bitWidth>
          </field>
          <field>
            <name>DATA5</name>
            <bitOffset>8</bitOffset>
            <bitWidth>8</bitWidth>
          </field>
          <field>
            <name>DATA6</name>
            <bitOffset>16</bitOffset>
            <bitWidth>8</bitWidth>
          </field>
          <field>
            <name>DATA7</name>
            <bitOffset>24</bitOffset>
            <bitWidth>8</bitWidth>
          </field>
        </fields>
      </register>
      <register>
        <name>sFIFOMailBox.0.RIR</name>
        <addressOffset>0x1b0</addressOffset>
        <size>0x20</size>
        <fields>
          <field>
            <name>RTR</name>
            <bitOffset>1</bitOffset>
            <bitWidth>1</bitWidth>
          </field>
          <field>
            <name>IDE</name>
            <bitOffset>2</bitOffset>
            <bitWidth>1</bitWidth>
          </field>
          <field>
            <name>EXID</name>
            <bitOffset>3</bitOffset>
            <bitWidth>18</bitWidth>
          </field>
          <field>
            <name>STID</name>
            <bitOffset>21</bitOffset>
            <bitWidth>11</bitWidth>
          </field>
        </fields>
      </register>
      <register>
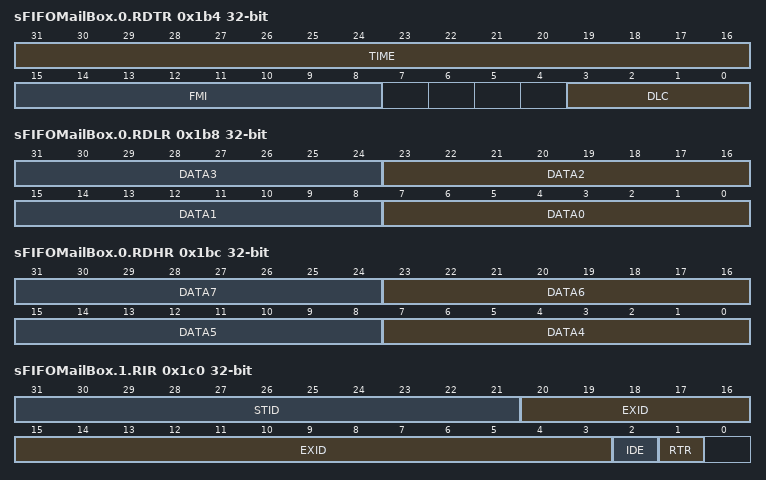
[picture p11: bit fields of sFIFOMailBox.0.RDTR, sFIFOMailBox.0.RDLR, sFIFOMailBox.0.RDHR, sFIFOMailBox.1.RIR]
        <name>sFIFOMailBox.0.RDTR</name>
        <addressOffset>0x1b4</addressOffset>
        <size>0x20</size>
        <fields>
          <field>
            <name>DLC</name>
            <bitOffset>0</bitOffset>
            <bitWidth>4</bitWidth>
          </field>
          <field>
            <name>FMI</name>
            <bitOffset>8</bitOffset>
            <bitWidth>8</bitWidth>
          </field>
          <field>
            <name>TIME</name>
            <bitOffset>16</bitOffset>
            <bitWidth>16</bitWidth>
          </field>
        </fields>
      </register>
      <register>
        <name>sFIFOMailBox.0.RDLR</name>
        <addressOffset>0x1b8</addressOffset>
        <size>0x20</size>
        <fields>
          <field>
            <name>DATA0</name>
            <bitOffset>0</bitOffset>
            <bitWidth>8</bitWidth>
          </field>
          <field>
            <name>DATA1</name>
            <bitOffset>8</bitOffset>
            <bitWidth>8</bitWidth>
          </field>
          <field>
            <name>DATA2</name>
            <bitOffset>16</bitOffset>
            <bitWidth>8</bitWidth>
          </field>
          <field>
            <name>DATA3</name>
            <bitOffset>24</bitOffset>
            <bitWidth>8</bitWidth>
          </field>
        </fields>
      </register>
      <register>
        <name>sFIFOMailBox.0.RDHR</name>
        <addressOffset>0x1bc</addressOffset>
        <size>0x20</size>
        <fields>
          <field>
            <name>DATA4</name>
            <bitOffset>0</bitOffset>
            <bitWidth>8</bitWidth>
          </field>
          <field>
            <name>DATA5</name>
            <bitOffset>8</bitOffset>
            <bitWidth>8</bitWidth>
          </field>
          <field>
            <name>DATA6</name>
            <bitOffset>16</bitOffset>
            <bitWidth>8</bitWidth>
          </field>
          <field>
            <name>DATA7</name>
            <bitOffset>24</bitOffset>
            <bitWidth>8</bitWidth>
          </field>
        </fields>
      </register>
      <register>
        <name>sFIFOMailBox.1.RIR</name>
        <addressOffset>0x1c0</addressOffset>
        <size>0x20</size>
        <fields>
          <field>
            <name>RTR</name>
            <bitOffset>1</bitOffset>
            <bitWidth>1</bitWidth>
          </field>
          <field>
            <name>IDE</name>
            <bitOffset>2</bitOffset>
            <bitWidth>1</bitWidth>
          </field>
          <field>
            <name>EXID</name>
            <bitOffset>3</bitOffset>
            <bitWidth>18</bitWidth>
          </field>
          <field>
            <name>STID</name>
            <bitOffset>21</bitOffset>
            <bitWidth>11</bitWidth>
          </field>
        </fields>
      </register>
      <register>
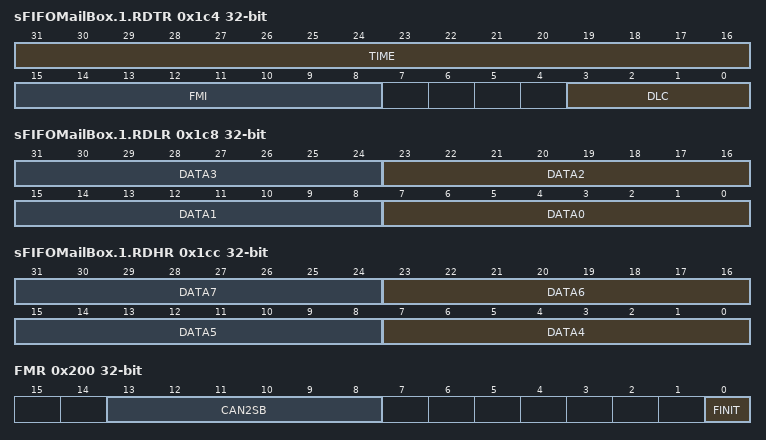
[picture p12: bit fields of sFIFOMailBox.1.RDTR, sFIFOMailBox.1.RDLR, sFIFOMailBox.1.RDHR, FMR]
        <name>sFIFOMailBox.1.RDTR</name>
        <addressOffset>0x1c4</addressOffset>
        <size>0x20</size>
        <fields>
          <field>
            <name>DLC</name>
            <bitOffset>0</bitOffset>
            <bitWidth>4</bitWidth>
          </field>
          <field>
            <name>FMI</name>
            <bitOffset>8</bitOffset>
            <bitWidth>8</bitWidth>
          </field>
          <field>
            <name>TIME</name>
            <bitOffset>16</bitOffset>
            <bitWidth>16</bitWidth>
          </field>
        </fields>
      </register>
      <register>
        <name>sFIFOMailBox.1.RDLR</name>
        <addressOffset>0x1c8</addressOffset>
        <size>0x20</size>
        <fields>
          <field>
            <name>DATA0</name>
            <bitOffset>0</bitOffset>
            <bitWidth>8</bitWidth>
          </field>
          <field>
            <name>DATA1</name>
            <bitOffset>8</bitOffset>
            <bitWidth>8</bitWidth>
          </field>
          <field>
            <name>DATA2</name>
            <bitOffset>16</bitOffset>
            <bitWidth>8</bitWidth>
          </field>
          <field>
            <name>DATA3</name>
            <bitOffset>24</bitOffset>
            <bitWidth>8</bitWidth>
          </field>
        </fields>
      </register>
      <register>
        <name>sFIFOMailBox.1.RDHR</name>
        <addressOffset>0x1cc</addressOffset>
        <size>0x20</size>
        <fields>
          <field>
            <name>DATA4</name>
            <bitOffset>0</bitOffset>
            <bitWidth>8</bitWidth>
          </field>
          <field>
            <name>DATA5</name>
            <bitOffset>8</bitOffset>
            <bitWidth>8</bitWidth>
          </field>
          <field>
            <name>DATA6</name>
            <bitOffset>16</bitOffset>
            <bitWidth>8</bitWidth>
          </field>
          <field>
            <name>DATA7</name>
            <bitOffset>24</bitOffset>
            <bitWidth>8</bitWidth>
          </field>
        </fields>
      </register>
      <register>
        <name>FMR</name>
        <addressOffset>0x200</addressOffset>
        <size>0x20</size>
        <fields>
          <field>
            <name>FINIT</name>
            <bitOffset>0</bitOffset>
            <bitWidth>1</bitWidth>
          </field>
          <field>
            <name>CAN2SB</name>
            <bitOffset>8</bitOffset>
            <bitWidth>6</bitWidth>
          </field>
        </fields>
      </register>
      <register>
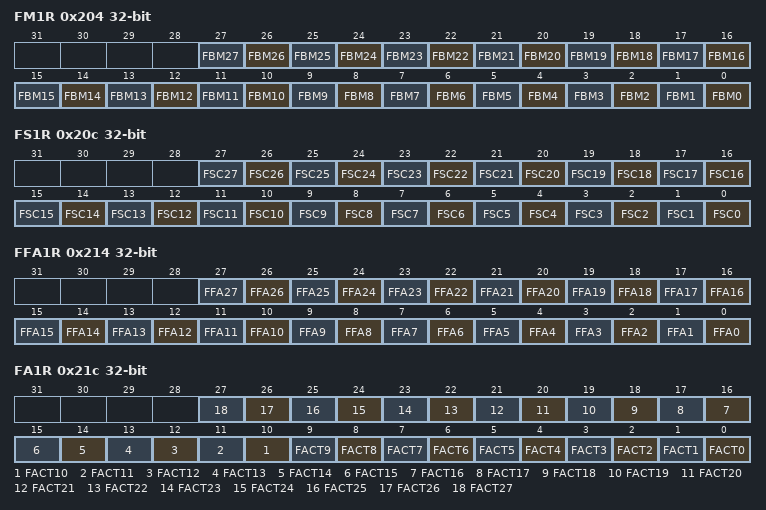
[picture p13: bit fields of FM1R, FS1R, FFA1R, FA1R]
        <name>FM1R</name>
        <addressOffset>0x204</addressOffset>
        <size>0x20</size>
        <fields>
          <field>
            <name>FBM0</name>
            <bitOffset>0</bitOffset>
            <bitWidth>1</bitWidth>
          </field>
          <field>
            <name>FBM1</name>
            <bitOffset>1</bitOffset>
            <bitWidth>1</bitWidth>
          </field>
          <field>
            <name>FBM2</name>
            <bitOffset>2</bitOffset>
            <bitWidth>1</bitWidth>
          </field>
          <field>
            <name>FBM3</name>
            <bitOffset>3</bitOffset>
            <bitWidth>1</bitWidth>
          </field>
          <field>
            <name>FBM4</name>
            <bitOffset>4</bitOffset>
            <bitWidth>1</bitWidth>
          </field>
          <field>
            <name>FBM5</name>
            <bitOffset>5</bitOffset>
            <bitWidth>1</bitWidth>
          </field>
          <field>
            <name>FBM6</name>
            <bitOffset>6</bitOffset>
            <bitWidth>1</bitWidth>
          </field>
          <field>
            <name>FBM7</name>
            <bitOffset>7</bitOffset>
            <bitWidth>1</bitWidth>
          </field>
          <field>
            <name>FBM8</name>
            <bitOffset>8</bitOffset>
            <bitWidth>1</bitWidth>
          </field>
          <field>
            <name>FBM9</name>
            <bitOffset>9</bitOffset>
            <bitWidth>1</bitWidth>
          </field>
          <field>
            <name>FBM10</name>
            <bitOffset>10</bitOffset>
            <bitWidth>1</bitWidth>
          </field>
          <field>
            <name>FBM11</name>
            <bitOffset>11</bitOffset>
            <bitWidth>1</bitWidth>
          </field>
          <field>
            <name>FBM12</name>
            <bitOffset>12</bitOffset>
            <bitWidth>1</bitWidth>
          </field>
          <field>
            <name>FBM13</name>
            <bitOffset>13</bitOffset>
            <bitWidth>1</bitWidth>
          </field>
          <field>
            <name>FBM14</name>
            <bitOffset>14</bitOffset>
            <bitWidth>1</bitWidth>
          </field>
          <field>
            <name>FBM15</name>
            <bitOffset>15</bitOffset>
            <bitWidth>1</bitWidth>
          </field>
          <field>
            <name>FBM16</name>
            <bitOffset>16</bitOffset>
            <bitWidth>1</bitWidth>
          </field>
          <field>
            <name>FBM17</name>
            <bitOffset>17</bitOffset>
            <bitWidth>1</bitWidth>
          </field>
          <field>
            <name>FBM18</name>
            <bitOffset>18</bitOffset>
            <bitWidth>1</bitWidth>
          </field>
          <field>
            <name>FBM19</name>
            <bitOffset>19</bitOffset>
            <bitWidth>1</bitWidth>
          </field>
          <field>
            <name>FBM20</name>
            <bitOffset>20</bitOffset>
            <bitWidth>1</bitWidth>
          </field>
          <field>
            <name>FBM21</name>
            <bitOffset>21</bitOffset>
            <bitWidth>1</bitWidth>
          </field>
          <field>
            <name>FBM22</name>
            <bitOffset>22</bitOffset>
            <bitWidth>1</bitWidth>
          </field>
          <field>
            <name>FBM23</name>
            <bitOffset>23</bitOffset>
            <bitWidth>1</bitWidth>
          </field>
          <field>
            <name>FBM24</name>
            <bitOffset>24</bitOffset>
            <bitWidth>1</bitWidth>
          </field>
          <field>
            <name>FBM25</name>
            <bitOffset>25</bitOffset>
            <bitWidth>1</bitWidth>
          </field>
          <field>
            <name>FBM26</name>
            <bitOffset>26</bitOffset>
            <bitWidth>1</bitWidth>
          </field>
          <field>
            <name>FBM27</name>
            <bitOffset>27</bitOffset>
            <bitWidth>1</bitWidth>
          </field>
        </fields>
      </register>
      <register>
        <name>FS1R</name>
        <addressOffset>0x20c</addressOffset>
        <size>0x20</size>
        <fields>
          <field>
            <name>FSC0</name>
            <bitOffset>0</bitOffset>
            <bitWidth>1</bitWidth>
          </field>
          <field>
            <name>FSC1</name>
            <bitOffset>1</bitOffset>
            <bitWidth>1</bitWidth>
          </field>
          <field>
            <name>FSC2</name>
            <bitOffset>2</bitOffset>
            <bitWidth>1</bitWidth>
          </field>
          <field>
            <name>FSC3</name>
            <bitOffset>3</bitOffset>
            <bitWidth>1</bitWidth>
          </field>
          <field>
            <name>FSC4</name>
            <bitOffset>4</bitOffset>
            <bitWidth>1</bitWidth>
          </field>
          <field>
            <name>FSC5</name>
            <bitOffset>5</bitOffset>
            <bitWidth>1</bitWidth>
          </field>
          <field>
            <name>FSC6</name>
            <bitOffset>6</bitOffset>
            <bitWidth>1</bitWidth>
          </field>
          <field>
            <name>FSC7</name>
            <bitOffset>7</bitOffset>
            <bitWidth>1</bitWidth>
          </field>
          <field>
            <name>FSC8</name>
            <bitOffset>8</bitOffset>
            <bitWidth>1</bitWidth>
          </field>
          <field>
            <name>FSC9</name>
            <bitOffset>9</bitOffset>
            <bitWidth>1</bitWidth>
          </field>
          <field>
            <name>FSC10</name>
            <bitOffset>10</bitOffset>
            <bitWidth>1</bitWidth>
          </field>
          <field>
            <name>FSC11</name>
            <bitOffset>11</bitOffset>
            <bitWidth>1</bitWidth>
          </field>
          <field>
            <name>FSC12</name>
            <bitOffset>12</bitOffset>
            <bitWidth>1</bitWidth>
          </field>
          <field>
            <name>FSC13</name>
            <bitOffset>13</bitOffset>
            <bitWidth>1</bitWidth>
          </field>
          <field>
            <name>FSC14</name>
            <bitOffset>14</bitOffset>
            <bitWidth>1</bitWidth>
          </field>
          <field>
            <name>FSC15</name>
            <bitOffset>15</bitOffset>
            <bitWidth>1</bitWidth>
          </field>
          <field>
            <name>FSC16</name>
            <bitOffset>16</bitOffset>
            <bitWidth>1</bitWidth>
          </field>
          <field>
            <name>FSC17</name>
            <bitOffset>17</bitOffset>
            <bitWidth>1</bitWidth>
          </field>
          <field>
            <name>FSC18</name>
            <bitOffset>18</bitOffset>
            <bitWidth>1</bitWidth>
          </field>
          <field>
            <name>FSC19</name>
            <bitOffset>19</bitOffset>
            <bitWidth>1</bitWidth>
          </field>
          <field>
            <name>FSC20</name>
            <bitOffset>20</bitOffset>
            <bitWidth>1</bitWidth>
          </field>
          <field>
            <name>FSC21</name>
            <bitOffset>21</bitOffset>
            <bitWidth>1</bitWidth>
          </field>
          <field>
            <name>FSC22</name>
            <bitOffset>22</bitOffset>
            <bitWidth>1</bitWidth>
          </field>
          <field>
            <name>FSC23</name>
            <bitOffset>23</bitOffset>
            <bitWidth>1</bitWidth>
          </field>
          <field>
            <name>FSC24</name>
            <bitOffset>24</bitOffset>
            <bitWidth>1</bitWidth>
          </field>
          <field>
            <name>FSC25</name>
            <bitOffset>25</bitOffset>
            <bitWidth>1</bitWidth>
          </field>
          <field>
            <name>FSC26</name>
            <bitOffset>26</bitOffset>
            <bitWidth>1</bitWidth>
          </field>
          <field>
            <name>FSC27</name>
            <bitOffset>27</bitOffset>
            <bitWidth>1</bitWidth>
          </field>
        </fields>
      </register>
      <register>
        <name>FFA1R</name>
        <addressOffset>0x214</addressOffset>
        <size>0x20</size>
        <fields>
          <field>
            <name>FFA0</name>
            <bitOffset>0</bitOffset>
            <bitWidth>1</bitWidth>
          </field>
          <field>
            <name>FFA1</name>
            <bitOffset>1</bitOffset>
            <bitWidth>1</bitWidth>
          </field>
          <field>
            <name>FFA2</name>
            <bitOffset>2</bitOffset>
            <bitWidth>1</bitWidth>
          </field>
          <field>
            <name>FFA3</name>
            <bitOffset>3</bitOffset>
            <bitWidth>1</bitWidth>
          </field>
          <field>
            <name>FFA4</name>
            <bitOffset>4</bitOffset>
            <bitWidth>1</bitWidth>
          </field>
          <field>
            <name>FFA5</name>
            <bitOffset>5</bitOffset>
            <bitWidth>1</bitWidth>
          </field>
          <field>
            <name>FFA6</name>
            <bitOffset>6</bitOffset>
            <bitWidth>1</bitWidth>
          </field>
          <field>
            <name>FFA7</name>
            <bitOffset>7</bitOffset>
            <bitWidth>1</bitWidth>
          </field>
          <field>
            <name>FFA8</name>
            <bitOffset>8</bitOffset>
            <bitWidth>1</bitWidth>
          </field>
          <field>
            <name>FFA9</name>
            <bitOffset>9</bitOffset>
            <bitWidth>1</bitWidth>
          </field>
          <field>
            <name>FFA10</name>
            <bitOffset>10</bitOffset>
            <bitWidth>1</bitWidth>
          </field>
          <field>
            <name>FFA11</name>
            <bitOffset>11</bitOffset>
            <bitWidth>1</bitWidth>
          </field>
          <field>
            <name>FFA12</name>
            <bitOffset>12</bitOffset>
            <bitWidth>1</bitWidth>
          </field>
          <field>
            <name>FFA13</name>
            <bitOffset>13</bitOffset>
            <bitWidth>1</bitWidth>
          </field>
          <field>
            <name>FFA14</name>
            <bitOffset>14</bitOffset>
            <bitWidth>1</bitWidth>
          </field>
          <field>
            <name>FFA15</name>
            <bitOffset>15</bitOffset>
            <bitWidth>1</bitWidth>
          </field>
          <field>
            <name>FFA16</name>
            <bitOffset>16</bitOffset>
            <bitWidth>1</bitWidth>
          </field>
          <field>
            <name>FFA17</name>
            <bitOffset>17</bitOffset>
            <bitWidth>1</bitWidth>
          </field>
          <field>
            <name>FFA18</name>
            <bitOffset>18</bitOffset>
            <bitWidth>1</bitWidth>
          </field>
          <field>
            <name>FFA19</name>
            <bitOffset>19</bitOffset>
            <bitWidth>1</bitWidth>
          </field>
          <field>
            <name>FFA20</name>
            <bitOffset>20</bitOffset>
            <bitWidth>1</bitWidth>
          </field>
          <field>
            <name>FFA21</name>
            <bitOffset>21</bitOffset>
            <bitWidth>1</bitWidth>
          </field>
          <field>
            <name>FFA22</name>
            <bitOffset>22</bitOffset>
            <bitWidth>1</bitWidth>
          </field>
          <field>
            <name>FFA23</name>
            <bitOffset>23</bitOffset>
            <bitWidth>1</bitWidth>
          </field>
          <field>
            <name>FFA24</name>
            <bitOffset>24</bitOffset>
            <bitWidth>1</bitWidth>
          </field>
          <field>
            <name>FFA25</name>
            <bitOffset>25</bitOffset>
            <bitWidth>1</bitWidth>
          </field>
          <field>
            <name>FFA26</name>
            <bitOffset>26</bitOffset>
            <bitWidth>1</bitWidth>
          </field>
          <field>
            <name>FFA27</name>
            <bitOffset>27</bitOffset>
            <bitWidth>1</bitWidth>
          </field>
        </fields>
      </register>
      <register>
        <name>FA1R</name>
        <addressOffset>0x21c</addressOffset>
        <size>0x20</size>
        <fields>
          <field>
            <name>FACT0</name>
            <bitOffset>0</bitOffset>
            <bitWidth>1</bitWidth>
          </field>
          <field>
            <name>FACT1</name>
            <bitOffset>1</bitOffset>
            <bitWidth>1</bitWidth>
          </field>
          <field>
            <name>FACT2</name>
            <bitOffset>2</bitOffset>
            <bitWidth>1</bitWidth>
          </field>
          <field>
            <name>FACT3</name>
            <bitOffset>3</bitOffset>
            <bitWidth>1</bitWidth>
          </field>
          <field>
            <name>FACT4</name>
            <bitOffset>4</bitOffset>
            <bitWidth>1</bitWidth>
          </field>
          <field>
            <name>FACT5</name>
            <bitOffset>5</bitOffset>
            <bitWidth>1</bitWidth>
          </field>
          <field>
            <name>FACT6</name>
            <bitOffset>6</bitOffset>
            <bitWidth>1</bitWidth>
          </field>
          <field>
            <name>FACT7</name>
            <bitOffset>7</bitOffset>
            <bitWidth>1</bitWidth>
          </field>
          <field>
            <name>FACT8</name>
            <bitOffset>8</bitOffset>
            <bitWidth>1</bitWidth>
          </field>
          <field>
            <name>FACT9</name>
            <bitOffset>9</bitOffset>
            <bitWidth>1</bitWidth>
          </field>
          <field>
            <name>FACT10</name>
            <bitOffset>10</bitOffset>
            <bitWidth>1</bitWidth>
          </field>
          <field>
            <name>FACT11</name>
            <bitOffset>11</bitOffset>
            <bitWidth>1</bitWidth>
          </field>
          <field>
            <name>FACT12</name>
            <bitOffset>12</bitOffset>
            <bitWidth>1</bitWidth>
          </field>
          <field>
            <name>FACT13</name>
            <bitOffset>13</bitOffset>
            <bitWidth>1</bitWidth>
          </field>
          <field>
            <name>FACT14</name>
            <bitOffset>14</bitOffset>
            <bitWidth>1</bitWidth>
          </field>
          <field>
            <name>FACT15</name>
            <bitOffset>15</bitOffset>
            <bitWidth>1</bitWidth>
          </field>
          <field>
            <name>FACT16</name>
            <bitOffset>16</bitOffset>
            <bitWidth>1</bitWidth>
          </field>
          <field>
            <name>FACT17</name>
            <bitOffset>17</bitOffset>
            <bitWidth>1</bitWidth>
          </field>
          <field>
            <name>FACT18</name>
            <bitOffset>18</bitOffset>
            <bitWidth>1</bitWidth>
          </field>
          <field>
            <name>FACT19</name>
            <bitOffset>19</bitOffset>
            <bitWidth>1</bitWidth>
          </field>
          <field>
            <name>FACT20</name>
            <bitOffset>20</bitOffset>
            <bitWidth>1</bitWidth>
          </field>
          <field>
            <name>FACT21</name>
            <bitOffset>21</bitOffset>
            <bitWidth>1</bitWidth>
          </field>
          <field>
            <name>FACT22</name>
            <bitOffset>22</bitOffset>
            <bitWidth>1</bitWidth>
          </field>
          <field>
            <name>FACT23</name>
            <bitOffset>23</bitOffset>
            <bitWidth>1</bitWidth>
          </field>
          <field>
            <name>FACT24</name>
            <bitOffset>24</bitOffset>
            <bitWidth>1</bitWidth>
          </field>
          <field>
            <name>FACT25</name>
            <bitOffset>25</bitOffset>
            <bitWidth>1</bitWidth>
          </field>
          <field>
            <name>FACT26</name>
            <bitOffset>26</bitOffset>
            <bitWidth>1</bitWidth>
          </field>
          <field>
            <name>FACT27</name>
            <bitOffset>27</bitOffset>
            <bitWidth>1</bitWidth>
          </field>
        </fields>
      </register>
      <register>
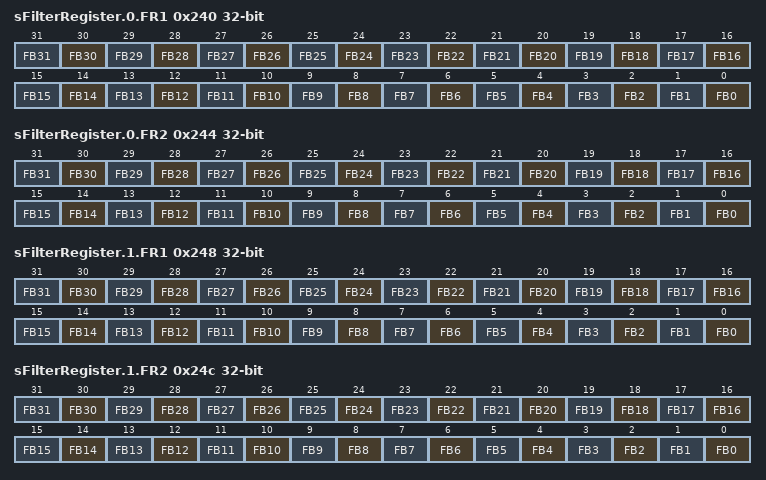
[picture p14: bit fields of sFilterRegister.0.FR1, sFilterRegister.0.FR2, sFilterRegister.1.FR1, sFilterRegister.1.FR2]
        <name>sFilterRegister.0.FR1</name>
        <addressOffset>0x240</addressOffset>
        <size>0x20</size>
        <fields>
          <field>
            <name>FB0</name>
            <bitOffset>0</bitOffset>
            <bitWidth>1</bitWidth>
          </field>
          <field>
            <name>FB1</name>
            <bitOffset>1</bitOffset>
            <bitWidth>1</bitWidth>
          </field>
          <field>
            <name>FB2</name>
            <bitOffset>2</bitOffset>
            <bitWidth>1</bitWidth>
          </field>
          <field>
            <name>FB3</name>
            <bitOffset>3</bitOffset>
            <bitWidth>1</bitWidth>
          </field>
          <field>
            <name>FB4</name>
            <bitOffset>4</bitOffset>
            <bitWidth>1</bitWidth>
          </field>
          <field>
            <name>FB5</name>
            <bitOffset>5</bitOffset>
            <bitWidth>1</bitWidth>
          </field>
          <field>
            <name>FB6</name>
            <bitOffset>6</bitOffset>
            <bitWidth>1</bitWidth>
          </field>
          <field>
            <name>FB7</name>
            <bitOffset>7</bitOffset>
            <bitWidth>1</bitWidth>
          </field>
          <field>
            <name>FB8</name>
            <bitOffset>8</bitOffset>
            <bitWidth>1</bitWidth>
          </field>
          <field>
            <name>FB9</name>
            <bitOffset>9</bitOffset>
            <bitWidth>1</bitWidth>
          </field>
          <field>
            <name>FB10</name>
            <bitOffset>10</bitOffset>
            <bitWidth>1</bitWidth>
          </field>
          <field>
            <name>FB11</name>
            <bitOffset>11</bitOffset>
            <bitWidth>1</bitWidth>
          </field>
          <field>
            <name>FB12</name>
            <bitOffset>12</bitOffset>
            <bitWidth>1</bitWidth>
          </field>
          <field>
            <name>FB13</name>
            <bitOffset>13</bitOffset>
            <bitWidth>1</bitWidth>
          </field>
          <field>
            <name>FB14</name>
            <bitOffset>14</bitOffset>
            <bitWidth>1</bitWidth>
          </field>
          <field>
            <name>FB15</name>
            <bitOffset>15</bitOffset>
            <bitWidth>1</bitWidth>
          </field>
          <field>
            <name>FB16</name>
            <bitOffset>16</bitOffset>
            <bitWidth>1</bitWidth>
          </field>
          <field>
            <name>FB17</name>
            <bitOffset>17</bitOffset>
            <bitWidth>1</bitWidth>
          </field>
          <field>
            <name>FB18</name>
            <bitOffset>18</bitOffset>
            <bitWidth>1</bitWidth>
          </field>
          <field>
            <name>FB19</name>
            <bitOffset>19</bitOffset>
            <bitWidth>1</bitWidth>
          </field>
          <field>
            <name>FB20</name>
            <bitOffset>20</bitOffset>
            <bitWidth>1</bitWidth>
          </field>
          <field>
            <name>FB21</name>
            <bitOffset>21</bitOffset>
            <bitWidth>1</bitWidth>
          </field>
          <field>
            <name>FB22</name>
            <bitOffset>22</bitOffset>
            <bitWidth>1</bitWidth>
          </field>
          <field>
            <name>FB23</name>
            <bitOffset>23</bitOffset>
            <bitWidth>1</bitWidth>
          </field>
          <field>
            <name>FB24</name>
            <bitOffset>24</bitOffset>
            <bitWidth>1</bitWidth>
          </field>
          <field>
            <name>FB25</name>
            <bitOffset>25</bitOffset>
            <bitWidth>1</bitWidth>
          </field>
          <field>
            <name>FB26</name>
            <bitOffset>26</bitOffset>
            <bitWidth>1</bitWidth>
          </field>
          <field>
            <name>FB27</name>
            <bitOffset>27</bitOffset>
            <bitWidth>1</bitWidth>
          </field>
          <field>
            <name>FB28</name>
            <bitOffset>28</bitOffset>
            <bitWidth>1</bitWidth>
          </field>
          <field>
            <name>FB29</name>
            <bitOffset>29</bitOffset>
            <bitWidth>1</bitWidth>
          </field>
          <field>
            <name>FB30</name>
            <bitOffset>30</bitOffset>
            <bitWidth>1</bitWidth>
          </field>
          <field>
            <name>FB31</name>
            <bitOffset>31</bitOffset>
            <bitWidth>1</bitWidth>
          </field>
        </fields>
      </register>
      <register>
        <name>sFilterRegister.0.FR2</name>
        <addressOffset>0x244</addressOffset>
        <size>0x20</size>
        <fields>
          <field>
            <name>FB0</name>
            <bitOffset>0</bitOffset>
            <bitWidth>1</bitWidth>
          </field>
          <field>
            <name>FB1</name>
            <bitOffset>1</bitOffset>
            <bitWidth>1</bitWidth>
          </field>
          <field>
            <name>FB2</name>
            <bitOffset>2</bitOffset>
            <bitWidth>1</bitWidth>
          </field>
          <field>
            <name>FB3</name>
            <bitOffset>3</bitOffset>
            <bitWidth>1</bitWidth>
          </field>
          <field>
            <name>FB4</name>
            <bitOffset>4</bitOffset>
            <bitWidth>1</bitWidth>
          </field>
          <field>
            <name>FB5</name>
            <bitOffset>5</bitOffset>
            <bitWidth>1</bitWidth>
          </field>
          <field>
            <name>FB6</name>
            <bitOffset>6</bitOffset>
            <bitWidth>1</bitWidth>
          </field>
          <field>
            <name>FB7</name>
            <bitOffset>7</bitOffset>
            <bitWidth>1</bitWidth>
          </field>
          <field>
            <name>FB8</name>
            <bitOffset>8</bitOffset>
            <bitWidth>1</bitWidth>
          </field>
          <field>
            <name>FB9</name>
            <bitOffset>9</bitOffset>
            <bitWidth>1</bitWidth>
          </field>
          <field>
            <name>FB10</name>
            <bitOffset>10</bitOffset>
            <bitWidth>1</bitWidth>
          </field>
          <field>
            <name>FB11</name>
            <bitOffset>11</bitOffset>
            <bitWidth>1</bitWidth>
          </field>
          <field>
            <name>FB12</name>
            <bitOffset>12</bitOffset>
            <bitWidth>1</bitWidth>
          </field>
          <field>
            <name>FB13</name>
            <bitOffset>13</bitOffset>
            <bitWidth>1</bitWidth>
          </field>
          <field>
            <name>FB14</name>
            <bitOffset>14</bitOffset>
            <bitWidth>1</bitWidth>
          </field>
          <field>
            <name>FB15</name>
            <bitOffset>15</bitOffset>
            <bitWidth>1</bitWidth>
          </field>
          <field>
            <name>FB16</name>
            <bitOffset>16</bitOffset>
            <bitWidth>1</bitWidth>
          </field>
          <field>
            <name>FB17</name>
            <bitOffset>17</bitOffset>
            <bitWidth>1</bitWidth>
          </field>
          <field>
            <name>FB18</name>
            <bitOffset>18</bitOffset>
            <bitWidth>1</bitWidth>
          </field>
          <field>
            <name>FB19</name>
            <bitOffset>19</bitOffset>
            <bitWidth>1</bitWidth>
          </field>
          <field>
            <name>FB20</name>
            <bitOffset>20</bitOffset>
            <bitWidth>1</bitWidth>
          </field>
          <field>
            <name>FB21</name>
            <bitOffset>21</bitOffset>
            <bitWidth>1</bitWidth>
          </field>
          <field>
            <name>FB22</name>
            <bitOffset>22</bitOffset>
            <bitWidth>1</bitWidth>
          </field>
          <field>
            <name>FB23</name>
            <bitOffset>23</bitOffset>
            <bitWidth>1</bitWidth>
          </field>
          <field>
            <name>FB24</name>
            <bitOffset>24</bitOffset>
            <bitWidth>1</bitWidth>
          </field>
          <field>
            <name>FB25</name>
            <bitOffset>25</bitOffset>
            <bitWidth>1</bitWidth>
          </field>
          <field>
            <name>FB26</name>
            <bitOffset>26</bitOffset>
            <bitWidth>1</bitWidth>
          </field>
          <field>
            <name>FB27</name>
            <bitOffset>27</bitOffset>
            <bitWidth>1</bitWidth>
          </field>
          <field>
            <name>FB28</name>
            <bitOffset>28</bitOffset>
            <bitWidth>1</bitWidth>
          </field>
          <field>
            <name>FB29</name>
            <bitOffset>29</bitOffset>
            <bitWidth>1</bitWidth>
          </field>
          <field>
            <name>FB30</name>
            <bitOffset>30</bitOffset>
            <bitWidth>1</bitWidth>
          </field>
          <field>
            <name>FB31</name>
            <bitOffset>31</bitOffset>
            <bitWidth>1</bitWidth>
          </field>
        </fields>
      </register>
      <register>
        <name>sFilterRegister.1.FR1</name>
        <addressOffset>0x248</addressOffset>
        <size>0x20</size>
        <fields>
          <field>
            <name>FB0</name>
            <bitOffset>0</bitOffset>
            <bitWidth>1</bitWidth>
          </field>
          <field>
            <name>FB1</name>
            <bitOffset>1</bitOffset>
            <bitWidth>1</bitWidth>
          </field>
          <field>
            <name>FB2</name>
            <bitOffset>2</bitOffset>
            <bitWidth>1</bitWidth>
          </field>
          <field>
            <name>FB3</name>
            <bitOffset>3</bitOffset>
            <bitWidth>1</bitWidth>
          </field>
          <field>
            <name>FB4</name>
            <bitOffset>4</bitOffset>
            <bitWidth>1</bitWidth>
          </field>
          <field>
            <name>FB5</name>
            <bitOffset>5</bitOffset>
            <bitWidth>1</bitWidth>
          </field>
          <field>
            <name>FB6</name>
            <bitOffset>6</bitOffset>
            <bitWidth>1</bitWidth>
          </field>
          <field>
            <name>FB7</name>
            <bitOffset>7</bitOffset>
            <bitWidth>1</bitWidth>
          </field>
          <field>
            <name>FB8</name>
            <bitOffset>8</bitOffset>
            <bitWidth>1</bitWidth>
          </field>
          <field>
            <name>FB9</name>
            <bitOffset>9</bitOffset>
            <bitWidth>1</bitWidth>
          </field>
          <field>
            <name>FB10</name>
            <bitOffset>10</bitOffset>
            <bitWidth>1</bitWidth>
          </field>
          <field>
            <name>FB11</name>
            <bitOffset>11</bitOffset>
            <bitWidth>1</bitWidth>
          </field>
          <field>
            <name>FB12</name>
            <bitOffset>12</bitOffset>
            <bitWidth>1</bitWidth>
          </field>
          <field>
            <name>FB13</name>
            <bitOffset>13</bitOffset>
            <bitWidth>1</bitWidth>
          </field>
          <field>
            <name>FB14</name>
            <bitOffset>14</bitOffset>
            <bitWidth>1</bitWidth>
          </field>
          <field>
            <name>FB15</name>
            <bitOffset>15</bitOffset>
            <bitWidth>1</bitWidth>
          </field>
          <field>
            <name>FB16</name>
            <bitOffset>16</bitOffset>
            <bitWidth>1</bitWidth>
          </field>
          <field>
            <name>FB17</name>
            <bitOffset>17</bitOffset>
            <bitWidth>1</bitWidth>
          </field>
          <field>
            <name>FB18</name>
            <bitOffset>18</bitOffset>
            <bitWidth>1</bitWidth>
          </field>
          <field>
            <name>FB19</name>
            <bitOffset>19</bitOffset>
            <bitWidth>1</bitWidth>
          </field>
          <field>
            <name>FB20</name>
            <bitOffset>20</bitOffset>
            <bitWidth>1</bitWidth>
          </field>
          <field>
            <name>FB21</name>
            <bitOffset>21</bitOffset>
            <bitWidth>1</bitWidth>
          </field>
          <field>
            <name>FB22</name>
            <bitOffset>22</bitOffset>
            <bitWidth>1</bitWidth>
          </field>
          <field>
            <name>FB23</name>
            <bitOffset>23</bitOffset>
            <bitWidth>1</bitWidth>
          </field>
          <field>
            <name>FB24</name>
            <bitOffset>24</bitOffset>
            <bitWidth>1</bitWidth>
          </field>
          <field>
            <name>FB25</name>
            <bitOffset>25</bitOffset>
            <bitWidth>1</bitWidth>
          </field>
          <field>
            <name>FB26</name>
            <bitOffset>26</bitOffset>
            <bitWidth>1</bitWidth>
          </field>
          <field>
            <name>FB27</name>
            <bitOffset>27</bitOffset>
            <bitWidth>1</bitWidth>
          </field>
          <field>
            <name>FB28</name>
            <bitOffset>28</bitOffset>
            <bitWidth>1</bitWidth>
          </field>
          <field>
            <name>FB29</name>
            <bitOffset>29</bitOffset>
            <bitWidth>1</bitWidth>
          </field>
          <field>
            <name>FB30</name>
            <bitOffset>30</bitOffset>
            <bitWidth>1</bitWidth>
          </field>
          <field>
            <name>FB31</name>
            <bitOffset>31</bitOffset>
            <bitWidth>1</bitWidth>
          </field>
        </fields>
      </register>
      <register>
        <name>sFilterRegister.1.FR2</name>
        <addressOffset>0x24c</addressOffset>
        <size>0x20</size>
        <fields>
          <field>
            <name>FB0</name>
            <bitOffset>0</bitOffset>
            <bitWidth>1</bitWidth>
          </field>
          <field>
            <name>FB1</name>
            <bitOffset>1</bitOffset>
            <bitWidth>1</bitWidth>
          </field>
          <field>
            <name>FB2</name>
            <bitOffset>2</bitOffset>
            <bitWidth>1</bitWidth>
          </field>
          <field>
            <name>FB3</name>
            <bitOffset>3</bitOffset>
            <bitWidth>1</bitWidth>
          </field>
          <field>
            <name>FB4</name>
            <bitOffset>4</bitOffset>
            <bitWidth>1</bitWidth>
          </field>
          <field>
            <name>FB5</name>
            <bitOffset>5</bitOffset>
            <bitWidth>1</bitWidth>
          </field>
          <field>
            <name>FB6</name>
            <bitOffset>6</bitOffset>
            <bitWidth>1</bitWidth>
          </field>
          <field>
            <name>FB7</name>
            <bitOffset>7</bitOffset>
            <bitWidth>1</bitWidth>
          </field>
          <field>
            <name>FB8</name>
            <bitOffset>8</bitOffset>
            <bitWidth>1</bitWidth>
          </field>
          <field>
            <name>FB9</name>
            <bitOffset>9</bitOffset>
            <bitWidth>1</bitWidth>
          </field>
          <field>
            <name>FB10</name>
            <bitOffset>10</bitOffset>
            <bitWidth>1</bitWidth>
          </field>
          <field>
            <name>FB11</name>
            <bitOffset>11</bitOffset>
            <bitWidth>1</bitWidth>
          </field>
          <field>
            <name>FB12</name>
            <bitOffset>12</bitOffset>
            <bitWidth>1</bitWidth>
          </field>
          <field>
            <name>FB13</name>
            <bitOffset>13</bitOffset>
            <bitWidth>1</bitWidth>
          </field>
          <field>
            <name>FB14</name>
            <bitOffset>14</bitOffset>
            <bitWidth>1</bitWidth>
          </field>
          <field>
            <name>FB15</name>
            <bitOffset>15</bitOffset>
            <bitWidth>1</bitWidth>
          </field>
          <field>
            <name>FB16</name>
            <bitOffset>16</bitOffset>
            <bitWidth>1</bitWidth>
          </field>
          <field>
            <name>FB17</name>
            <bitOffset>17</bitOffset>
            <bitWidth>1</bitWidth>
          </field>
          <field>
            <name>FB18</name>
            <bitOffset>18</bitOffset>
            <bitWidth>1</bitWidth>
          </field>
          <field>
            <name>FB19</name>
            <bitOffset>19</bitOffset>
            <bitWidth>1</bitWidth>
          </field>
          <field>
            <name>FB20</name>
            <bitOffset>20</bitOffset>
            <bitWidth>1</bitWidth>
          </field>
          <field>
            <name>FB21</name>
            <bitOffset>21</bitOffset>
            <bitWidth>1</bitWidth>
          </field>
          <field>
            <name>FB22</name>
            <bitOffset>22</bitOffset>
            <bitWidth>1</bitWidth>
          </field>
          <field>
            <name>FB23</name>
            <bitOffset>23</bitOffset>
            <bitWidth>1</bitWidth>
          </field>
          <field>
            <name>FB24</name>
            <bitOffset>24</bitOffset>
            <bitWidth>1</bitWidth>
          </field>
          <field>
            <name>FB25</name>
            <bitOffset>25</bitOffset>
            <bitWidth>1</bitWidth>
          </field>
          <field>
            <name>FB26</name>
            <bitOffset>26</bitOffset>
            <bitWidth>1</bitWidth>
          </field>
          <field>
            <name>FB27</name>
            <bitOffset>27</bitOffset>
            <bitWidth>1</bitWidth>
          </field>
          <field>
            <name>FB28</name>
            <bitOffset>28</bitOffset>
            <bitWidth>1</bitWidth>
          </field>
          <field>
            <name>FB29</name>
            <bitOffset>29</bitOffset>
            <bitWidth>1</bitWidth>
          </field>
          <field>
            <name>FB30</name>
            <bitOffset>30</bitOffset>
            <bitWidth>1</bitWidth>
          </field>
          <field>
            <name>FB31</name>
            <bitOffset>31</bitOffset>
            <bitWidth>1</bitWidth>
          </field>
        </fields>
      </register>
      <register>
        <name>sFilterRegister.2.FR1</name>
        <addressOffset>0x250</addressOffset>
        <size>0x20</size>
        <fields>
          <field>
            <name>FB0</name>
            <bitOffset>0</bitOffset>
            <bitWidth>1</bitWidth>
          </field>
          <field>
            <name>FB1</name>
            <bitOffset>1</bitOffset>
            <bitWidth>1</bitWidth>
          </field>
          <field>
            <name>FB2</name>
            <bitOffset>2</bitOffset>
            <bitWidth>1</bitWidth>
          </field>
          <field>
            <name>FB3</name>
            <bitOffset>3</bitOffset>
            <bitWidth>1</bitWidth>
          </field>
          <field>
            <name>FB4</name>
            <bitOffset>4</bitOffset>
            <bitWidth>1</bitWidth>
          </field>
          <field>
            <name>FB5</name>
            <bitOffset>5</bitOffset>
            <bitWidth>1</bitWidth>
          </field>
          <field>
            <name>FB6</name>
            <bitOffset>6</bitOffset>
            <bitWidth>1</bitWidth>
          </field>
          <field>
            <name>FB7</name>
            <bitOffset>7</bitOffset>
            <bitWidth>1</bitWidth>
          </field>
          <field>
            <name>FB8</name>
            <bitOffset>8</bitOffset>
            <bitWidth>1</bitWidth>
          </field>
          <field>
            <name>FB9</name>
            <bitOffset>9</bitOffset>
            <bitWidth>1</bitWidth>
          </field>
          <field>
            <name>FB10</name>
            <bitOffset>10</bitOffset>
            <bitWidth>1</bitWidth>
          </field>
          <field>
            <name>FB11</name>
            <bitOffset>11</bitOffset>
            <bitWidth>1</bitWidth>
          </field>
          <field>
            <name>FB12</name>
            <bitOffset>12</bitOffset>
            <bitWidth>1</bitWidth>
          </field>
          <field>
            <name>FB13</name>
            <bitOffset>13</bitOffset>
            <bitWidth>1</bitWidth>
          </field>
          <field>
            <name>FB14</name>
            <bitOffset>14</bitOffset>
            <bitWidth>1</bitWidth>
          </field>
          <field>
            <name>FB15</name>
            <bitOffset>15</bitOffset>
            <bitWidth>1</bitWidth>
          </field>
          <field>
            <name>FB16</name>
            <bitOffset>16</bitOffset>
            <bitWidth>1</bitWidth>
          </field>
          <field>
            <name>FB17</name>
            <bitOffset>17</bitOffset>
            <bitWidth>1</bitWidth>
          </field>
          <field>
            <name>FB18</name>
            <bitOffset>18</bitOffset>
            <bitWidth>1</bitWidth>
          </field>
          <field>
            <name>FB19</name>
            <bitOffset>19</bitOffset>
            <bitWidth>1</bitWidth>
          </field>
          <field>
            <name>FB20</name>
            <bitOffset>20</bitOffset>
            <bitWidth>1</bitWidth>
          </field>
          <field>
            <name>FB21</name>
            <bitOffset>21</bitOffset>
            <bitWidth>1</bitWidth>
          </field>
          <field>
            <name>FB22</name>
            <bitOffset>22</bitOffset>
            <bitWidth>1</bitWidth>
          </field>
          <field>
            <name>FB23</name>
            <bitOffset>23</bitOffset>
            <bitWidth>1</bitWidth>
          </field>
          <field>
            <name>FB24</name>
            <bitOffset>24</bitOffset>
            <bitWidth>1</bitWidth>
          </field>
          <field>
            <name>FB25</name>
            <bitOffset>25</bitOffset>
            <bitWidth>1</bitWidth>
          </field>
          <field>
            <name>FB26</name>
            <bitOffset>26</bitOffset>
            <bitWidth>1</bitWidth>
          </field>
          <field>
            <name>FB27</name>
            <bitOffset>27</bitOffset>
            <bitWidth>1</bitWidth>
          </field>
          <field>
            <name>FB28</name>
            <bitOffset>28</bitOffset>
            <bitWidth>1</bitWidth>
          </field>
          <field>
            <name>FB29</name>
            <bitOffset>29</bitOffset>
            <bitWidth>1</bitWidth>
          </field>
          <field>
            <name>FB30</name>
            <bitOffset>30</bitOffset>
            <bitWidth>1</bitWidth>
          </field>
          <field>
            <name>FB31</name>
            <bitOffset>31</bitOffset>
            <bitWidth>1</bitWidth>
          </field>
        </fields>
      </register>
      <register>
        <name>sFilterRegister.2.FR2</name>
        <addressOffset>0x254</addressOffset>
        <size>0x20</size>
        <fields>
          <field>
            <name>FB0</name>
            <bitOffset>0</bitOffset>
            <bitWidth>1</bitWidth>
          </field>
          <field>
            <name>FB1</name>
            <bitOffset>1</bitOffset>
            <bitWidth>1</bitWidth>
          </field>
          <field>
            <name>FB2</name>
            <bitOffset>2</bitOffset>
            <bitWidth>1</bitWidth>
          </field>
          <field>
            <name>FB3</name>
            <bitOffset>3</bitOffset>
            <bitWidth>1</bitWidth>
          </field>
          <field>
            <name>FB4</name>
            <bitOffset>4</bitOffset>
            <bitWidth>1</bitWidth>
          </field>
          <field>
            <name>FB5</name>
            <bitOffset>5</bitOffset>
            <bitWidth>1</bitWidth>
          </field>
          <field>
            <name>FB6</name>
            <bitOffset>6</bitOffset>
            <bitWidth>1</bitWidth>
          </field>
          <field>
            <name>FB7</name>
            <bitOffset>7</bitOffset>
            <bitWidth>1</bitWidth>
          </field>
          <field>
            <name>FB8</name>
            <bitOffset>8</bitOffset>
            <bitWidth>1</bitWidth>
          </field>
          <field>
            <name>FB9</name>
            <bitOffset>9</bitOffset>
            <bitWidth>1</bitWidth>
          </field>
          <field>
            <name>FB10</name>
            <bitOffset>10</bitOffset>
            <bitWidth>1</bitWidth>
          </field>
          <field>
            <name>FB11</name>
            <bitOffset>11</bitOffset>
            <bitWidth>1</bitWidth>
          </field>
          <field>
            <name>FB12</name>
            <bitOffset>12</bitOffset>
            <bitWidth>1</bitWidth>
          </field>
          <field>
            <name>FB13</name>
            <bitOffset>13</bitOffset>
            <bitWidth>1</bitWidth>
          </field>
          <field>
            <name>FB14</name>
            <bitOffset>14</bitOffset>
            <bitWidth>1</bitWidth>
          </field>
          <field>
            <name>FB15</name>
            <bitOffset>15</bitOffset>
            <bitWidth>1</bitWidth>
          </field>
          <field>
            <name>FB16</name>
            <bitOffset>16</bitOffset>
            <bitWidth>1</bitWidth>
          </field>
          <field>
            <name>FB17</name>
            <bitOffset>17</bitOffset>
            <bitWidth>1</bitWidth>
          </field>
          <field>
            <name>FB18</name>
            <bitOffset>18</bitOffset>
            <bitWidth>1</bitWidth>
          </field>
          <field>
            <name>FB19</name>
            <bitOffset>19</bitOffset>
            <bitWidth>1</bitWidth>
          </field>
          <field>
            <name>FB20</name>
            <bitOffset>20</bitOffset>
            <bitWidth>1</bitWidth>
          </field>
          <field>
            <name>FB21</name>
            <bitOffset>21</bitOffset>
            <bitWidth>1</bitWidth>
          </field>
          <field>
            <name>FB22</name>
            <bitOffset>22</bitOffset>
            <bitWidth>1</bitWidth>
          </field>
          <field>
            <name>FB23</name>
            <bitOffset>23</bitOffset>
            <bitWidth>1</bitWidth>
          </field>
          <field>
            <name>FB24</name>
            <bitOffset>24</bitOffset>
            <bitWidth>1</bitWidth>
          </field>
          <field>
            <name>FB25</name>
            <bitOffset>25</bitOffset>
            <bitWidth>1</bitWidth>
          </field>
          <field>
            <name>FB26</name>
            <bitOffset>26</bitOffset>
            <bitWidth>1</bitWidth>
          </field>
          <field>
            <name>FB27</name>
            <bitOffset>27</bitOffset>
            <bitWidth>1</bitWidth>
          </field>
          <field>
            <name>FB28</name>
            <bitOffset>28</bitOffset>
            <bitWidth>1</bitWidth>
          </field>
          <field>
            <name>FB29</name>
            <bitOffset>29</bitOffset>
            <bitWidth>1</bitWidth>
          </field>
          <field>
            <name>FB30</name>
            <bitOffset>30</bitOffset>
            <bitWidth>1</bitWidth>
          </field>
          <field>
            <name>FB31</name>
            <bitOffset>31</bitOffset>
            <bitWidth>1</bitWidth>
          </field>
        </fields>
      </register>
      <register>
        <name>sFilterRegister.3.FR1</name>
        <addressOffset>0x258</addressOffset>
        <size>0x20</size>
        <fields>
          <field>
            <name>FB0</name>
            <bitOffset>0</bitOffset>
            <bitWidth>1</bitWidth>
          </field>
          <field>
            <name>FB1</name>
            <bitOffset>1</bitOffset>
            <bitWidth>1</bitWidth>
          </field>
          <field>
            <name>FB2</name>
            <bitOffset>2</bitOffset>
            <bitWidth>1</bitWidth>
          </field>
          <field>
            <name>FB3</name>
            <bitOffset>3</bitOffset>
            <bitWidth>1</bitWidth>
          </field>
          <field>
            <name>FB4</name>
            <bitOffset>4</bitOffset>
            <bitWidth>1</bitWidth>
          </field>
          <field>
            <name>FB5</name>
            <bitOffset>5</bitOffset>
            <bitWidth>1</bitWidth>
          </field>
          <field>
            <name>FB6</name>
            <bitOffset>6</bitOffset>
            <bitWidth>1</bitWidth>
          </field>
          <field>
            <name>FB7</name>
            <bitOffset>7</bitOffset>
            <bitWidth>1</bitWidth>
          </field>
          <field>
            <name>FB8</name>
            <bitOffset>8</bitOffset>
            <bitWidth>1</bitWidth>
          </field>
          <field>
            <name>FB9</name>
            <bitOffset>9</bitOffset>
            <bitWidth>1</bitWidth>
          </field>
          <field>
            <name>FB10</name>
            <bitOffset>10</bitOffset>
            <bitWidth>1</bitWidth>
          </field>
          <field>
            <name>FB11</name>
            <bitOffset>11</bitOffset>
            <bitWidth>1</bitWidth>
          </field>
          <field>
            <name>FB12</name>
            <bitOffset>12</bitOffset>
            <bitWidth>1</bitWidth>
          </field>
          <field>
            <name>FB13</name>
            <bitOffset>13</bitOffset>
            <bitWidth>1</bitWidth>
          </field>
          <field>
            <name>FB14</name>
            <bitOffset>14</bitOffset>
            <bitWidth>1</bitWidth>
          </field>
          <field>
            <name>FB15</name>
            <bitOffset>15</bitOffset>
            <bitWidth>1</bitWidth>
          </field>
          <field>
            <name>FB16</name>
            <bitOffset>16</bitOffset>
            <bitWidth>1</bitWidth>
          </field>
          <field>
            <name>FB17</name>
            <bitOffset>17</bitOffset>
            <bitWidth>1</bitWidth>
          </field>
          <field>
            <name>FB18</name>
            <bitOffset>18</bitOffset>
            <bitWidth>1</bitWidth>
          </field>
          <field>
            <name>FB19</name>
            <bitOffset>19</bitOffset>
            <bitWidth>1</bitWidth>
          </field>
          <field>
            <name>FB20</name>
            <bitOffset>20</bitOffset>
            <bitWidth>1</bitWidth>
          </field>
          <field>
            <name>FB21</name>
            <bitOffset>21</bitOffset>
            <bitWidth>1</bitWidth>
          </field>
          <field>
            <name>FB22</name>
            <bitOffset>22</bitOffset>
            <bitWidth>1</bitWidth>
          </field>
          <field>
            <name>FB23</name>
            <bitOffset>23</bitOffset>
            <bitWidth>1</bitWidth>
          </field>
          <field>
            <name>FB24</name>
            <bitOffset>24</bitOffset>
            <bitWidth>1</bitWidth>
          </field>
          <field>
            <name>FB25</name>
            <bitOffset>25</bitOffset>
            <bitWidth>1</bitWidth>
          </field>
          <field>
            <name>FB26</name>
            <bitOffset>26</bitOffset>
            <bitWidth>1</bitWidth>
          </field>
          <field>
            <name>FB27</name>
            <bitOffset>27</bitOffset>
            <bitWidth>1</bitWidth>
          </field>
          <field>
            <name>FB28</name>
            <bitOffset>28</bitOffset>
            <bitWidth>1</bitWidth>
          </field>
          <field>
            <name>FB29</name>
            <bitOffset>29</bitOffset>
            <bitWidth>1</bitWidth>
          </field>
          <field>
            <name>FB30</name>
            <bitOffset>30</bitOffset>
            <bitWidth>1</bitWidth>
          </field>
          <field>
            <name>FB31</name>
            <bitOffset>31</bitOffset>
            <bitWidth>1</bitWidth>
          </field>
        </fields>
      </register>
      <register>
        <name>sFilterRegister.3.FR2</name>
        <addressOffset>0x25c</addressOffset>
        <size>0x20</size>
        <fields>
          <field>
            <name>FB0</name>
            <bitOffset>0</bitOffset>
            <bitWidth>1</bitWidth>
          </field>
          <field>
            <name>FB1</name>
            <bitOffset>1</bitOffset>
            <bitWidth>1</bitWidth>
          </field>
          <field>
            <name>FB2</name>
            <bitOffset>2</bitOffset>
            <bitWidth>1</bitWidth>
          </field>
          <field>
            <name>FB3</name>
            <bitOffset>3</bitOffset>
            <bitWidth>1</bitWidth>
          </field>
          <field>
            <name>FB4</name>
            <bitOffset>4</bitOffset>
            <bitWidth>1</bitWidth>
          </field>
          <field>
            <name>FB5</name>
            <bitOffset>5</bitOffset>
            <bitWidth>1</bitWidth>
          </field>
          <field>
            <name>FB6</name>
            <bitOffset>6</bitOffset>
            <bitWidth>1</bitWidth>
          </field>
          <field>
            <name>FB7</name>
            <bitOffset>7</bitOffset>
            <bitWidth>1</bitWidth>
          </field>
          <field>
            <name>FB8</name>
            <bitOffset>8</bitOffset>
            <bitWidth>1</bitWidth>
          </field>
          <field>
            <name>FB9</name>
            <bitOffset>9</bitOffset>
            <bitWidth>1</bitWidth>
          </field>
          <field>
            <name>FB10</name>
            <bitOffset>10</bitOffset>
            <bitWidth>1</bitWidth>
          </field>
          <field>
            <name>FB11</name>
            <bitOffset>11</bitOffset>
            <bitWidth>1</bitWidth>
          </field>
          <field>
            <name>FB12</name>
            <bitOffset>12</bitOffset>
            <bitWidth>1</bitWidth>
          </field>
          <field>
            <name>FB13</name>
            <bitOffset>13</bitOffset>
            <bitWidth>1</bitWidth>
          </field>
          <field>
            <name>FB14</name>
            <bitOffset>14</bitOffset>
            <bitWidth>1</bitWidth>
          </field>
          <field>
            <name>FB15</name>
            <bitOffset>15</bitOffset>
            <bitWidth>1</bitWidth>
          </field>
          <field>
            <name>FB16</name>
            <bitOffset>16</bitOffset>
            <bitWidth>1</bitWidth>
          </field>
          <field>
            <name>FB17</name>
            <bitOffset>17</bitOffset>
            <bitWidth>1</bitWidth>
          </field>
          <field>
            <name>FB18</name>
            <bitOffset>18</bitOffset>
            <bitWidth>1</bitWidth>
          </field>
          <field>
            <name>FB19</name>
            <bitOffset>19</bitOffset>
            <bitWidth>1</bitWidth>
          </field>
          <field>
            <name>FB20</name>
            <bitOffset>20</bitOffset>
            <bitWidth>1</bitWidth>
          </field>
          <field>
            <name>FB21</name>
            <bitOffset>21</bitOffset>
            <bitWidth>1</bitWidth>
          </field>
          <field>
            <name>FB22</name>
            <bitOffset>22</bitOffset>
            <bitWidth>1</bitWidth>
          </field>
          <field>
            <name>FB23</name>
            <bitOffset>23</bitOffset>
            <bitWidth>1</bitWidth>
          </field>
          <field>
            <name>FB24</name>
            <bitOffset>24</bitOffset>
            <bitWidth>1</bitWidth>
          </field>
          <field>
            <name>FB25</name>
            <bitOffset>25</bitOffset>
            <bitWidth>1</bitWidth>
          </field>
          <field>
            <name>FB26</name>
            <bitOffset>26</bitOffset>
            <bitWidth>1</bitWidth>
          </field>
          <field>
            <name>FB27</name>
            <bitOffset>27</bitOffset>
            <bitWidth>1</bitWidth>
          </field>
          <field>
            <name>FB28</name>
            <bitOffset>28</bitOffset>
            <bitWidth>1</bitWidth>
          </field>
          <field>
            <name>FB29</name>
            <bitOffset>29</bitOffset>
            <bitWidth>1</bitWidth>
          </field>
          <field>
            <name>FB30</name>
            <bitOffset>30</bitOffset>
            <bitWidth>1</bitWidth>
          </field>
          <field>
            <name>FB31</name>
            <bitOffset>31</bitOffset>
            <bitWidth>1</bitWidth>
          </field>
        </fields>
      </register>
      <register>
        <name>sFilterRegister.4.FR1</name>
        <addressOffset>0x260</addressOffset>
        <size>0x20</size>
        <fields>
          <field>
            <name>FB0</name>
            <bitOffset>0</bitOffset>
            <bitWidth>1</bitWidth>
          </field>
          <field>
            <name>FB1</name>
            <bitOffset>1</bitOffset>
            <bitWidth>1</bitWidth>
          </field>
          <field>
            <name>FB2</name>
            <bitOffset>2</bitOffset>
            <bitWidth>1</bitWidth>
          </field>
          <field>
            <name>FB3</name>
            <bitOffset>3</bitOffset>
            <bitWidth>1</bitWidth>
          </field>
          <field>
            <name>FB4</name>
            <bitOffset>4</bitOffset>
            <bitWidth>1</bitWidth>
          </field>
          <field>
            <name>FB5</name>
            <bitOffset>5</bitOffset>
            <bitWidth>1</bitWidth>
          </field>
          <field>
            <name>FB6</name>
            <bitOffset>6</bitOffset>
            <bitWidth>1</bitWidth>
          </field>
          <field>
            <name>FB7</name>
            <bitOffset>7</bitOffset>
            <bitWidth>1</bitWidth>
          </field>
          <field>
            <name>FB8</name>
            <bitOffset>8</bitOffset>
            <bitWidth>1</bitWidth>
          </field>
          <field>
            <name>FB9</name>
            <bitOffset>9</bitOffset>
            <bitWidth>1</bitWidth>
          </field>
          <field>
            <name>FB10</name>
            <bitOffset>10</bitOffset>
            <bitWidth>1</bitWidth>
          </field>
          <field>
            <name>FB11</name>
            <bitOffset>11</bitOffset>
            <bitWidth>1</bitWidth>
          </field>
          <field>
            <name>FB12</name>
            <bitOffset>12</bitOffset>
            <bitWidth>1</bitWidth>
          </field>
          <field>
            <name>FB13</name>
            <bitOffset>13</bitOffset>
            <bitWidth>1</bitWidth>
          </field>
          <field>
            <name>FB14</name>
            <bitOffset>14</bitOffset>
            <bitWidth>1</bitWidth>
          </field>
          <field>
            <name>FB15</name>
            <bitOffset>15</bitOffset>
            <bitWidth>1</bitWidth>
          </field>
          <field>
            <name>FB16</name>
            <bitOffset>16</bitOffset>
            <bitWidth>1</bitWidth>
          </field>
          <field>
            <name>FB17</name>
            <bitOffset>17</bitOffset>
            <bitWidth>1</bitWidth>
          </field>
          <field>
            <name>FB18</name>
            <bitOffset>18</bitOffset>
            <bitWidth>1</bitWidth>
          </field>
          <field>
            <name>FB19</name>
            <bitOffset>19</bitOffset>
            <bitWidth>1</bitWidth>
          </field>
          <field>
            <name>FB20</name>
            <bitOffset>20</bitOffset>
            <bitWidth>1</bitWidth>
          </field>
          <field>
            <name>FB21</name>
            <bitOffset>21</bitOffset>
            <bitWidth>1</bitWidth>
          </field>
          <field>
            <name>FB22</name>
            <bitOffset>22</bitOffset>
            <bitWidth>1</bitWidth>
          </field>
          <field>
            <name>FB23</name>
            <bitOffset>23</bitOffset>
            <bitWidth>1</bitWidth>
          </field>
          <field>
            <name>FB24</name>
            <bitOffset>24</bitOffset>
            <bitWidth>1</bitWidth>
          </field>
          <field>
            <name>FB25</name>
            <bitOffset>25</bitOffset>
            <bitWidth>1</bitWidth>
          </field>
          <field>
            <name>FB26</name>
            <bitOffset>26</bitOffset>
            <bitWidth>1</bitWidth>
          </field>
          <field>
            <name>FB27</name>
            <bitOffset>27</bitOffset>
            <bitWidth>1</bitWidth>
          </field>
          <field>
            <name>FB28</name>
            <bitOffset>28</bitOffset>
            <bitWidth>1</bitWidth>
          </field>
          <field>
            <name>FB29</name>
            <bitOffset>29</bitOffset>
            <bitWidth>1</bitWidth>
          </field>
          <field>
            <name>FB30</name>
            <bitOffset>30</bitOffset>
            <bitWidth>1</bitWidth>
          </field>
          <field>
            <name>FB31</name>
            <bitOffset>31</bitOffset>
            <bitWidth>1</bitWidth>
          </field>
        </fields>
      </register>
      <register>
        <name>sFilterRegister.4.FR2</name>
        <addressOffset>0x264</addressOffset>
        <size>0x20</size>
        <fields>
          <field>
            <name>FB0</name>
            <bitOffset>0</bitOffset>
            <bitWidth>1</bitWidth>
          </field>
          <field>
            <name>FB1</name>
            <bitOffset>1</bitOffset>
            <bitWidth>1</bitWidth>
          </field>
          <field>
            <name>FB2</name>
            <bitOffset>2</bitOffset>
            <bitWidth>1</bitWidth>
          </field>
          <field>
            <name>FB3</name>
            <bitOffset>3</bitOffset>
            <bitWidth>1</bitWidth>
          </field>
          <field>
            <name>FB4</name>
            <bitOffset>4</bitOffset>
            <bitWidth>1</bitWidth>
          </field>
          <field>
            <name>FB5</name>
            <bitOffset>5</bitOffset>
            <bitWidth>1</bitWidth>
          </field>
          <field>
            <name>FB6</name>
            <bitOffset>6</bitOffset>
            <bitWidth>1</bitWidth>
          </field>
          <field>
            <name>FB7</name>
            <bitOffset>7</bitOffset>
            <bitWidth>1</bitWidth>
          </field>
          <field>
            <name>FB8</name>
            <bitOffset>8</bitOffset>
            <bitWidth>1</bitWidth>
          </field>
          <field>
            <name>FB9</name>
            <bitOffset>9</bitOffset>
            <bitWidth>1</bitWidth>
          </field>
          <field>
            <name>FB10</name>
            <bitOffset>10</bitOffset>
            <bitWidth>1</bitWidth>
          </field>
          <field>
            <name>FB11</name>
            <bitOffset>11</bitOffset>
            <bitWidth>1</bitWidth>
          </field>
          <field>
            <name>FB12</name>
            <bitOffset>12</bitOffset>
            <bitWidth>1</bitWidth>
          </field>
          <field>
            <name>FB13</name>
            <bitOffset>13</bitOffset>
            <bitWidth>1</bitWidth>
          </field>
          <field>
            <name>FB14</name>
            <bitOffset>14</bitOffset>
            <bitWidth>1</bitWidth>
          </field>
          <field>
            <name>FB15</name>
            <bitOffset>15</bitOffset>
            <bitWidth>1</bitWidth>
          </field>
          <field>
            <name>FB16</name>
            <bitOffset>16</bitOffset>
            <bitWidth>1</bitWidth>
          </field>
          <field>
            <name>FB17</name>
            <bitOffset>17</bitOffset>
            <bitWidth>1</bitWidth>
          </field>
          <field>
            <name>FB18</name>
            <bitOffset>18</bitOffset>
            <bitWidth>1</bitWidth>
          </field>
          <field>
            <name>FB19</name>
            <bitOffset>19</bitOffset>
            <bitWidth>1</bitWidth>
          </field>
          <field>
            <name>FB20</name>
            <bitOffset>20</bitOffset>
            <bitWidth>1</bitWidth>
          </field>
          <field>
            <name>FB21</name>
            <bitOffset>21</bitOffset>
            <bitWidth>1</bitWidth>
          </field>
          <field>
            <name>FB22</name>
            <bitOffset>22</bitOffset>
            <bitWidth>1</bitWidth>
          </field>
          <field>
            <name>FB23</name>
            <bitOffset>23</bitOffset>
            <bitWidth>1</bitWidth>
          </field>
          <field>
            <name>FB24</name>
            <bitOffset>24</bitOffset>
            <bitWidth>1</bitWidth>
          </field>
          <field>
            <name>FB25</name>
            <bitOffset>25</bitOffset>
            <bitWidth>1</bitWidth>
          </field>
          <field>
            <name>FB26</name>
            <bitOffset>26</bitOffset>
            <bitWidth>1</bitWidth>
          </field>
          <field>
            <name>FB27</name>
            <bitOffset>27</bitOffset>
            <bitWidth>1</bitWidth>
          </field>
          <field>
            <name>FB28</name>
            <bitOffset>28</bitOffset>
            <bitWidth>1</bitWidth>
          </field>
          <field>
            <name>FB29</name>
            <bitOffset>29</bitOffset>
            <bitWidth>1</bitWidth>
          </field>
          <field>
            <name>FB30</name>
            <bitOffset>30</bitOffset>
            <bitWidth>1</bitWidth>
          </field>
          <field>
            <name>FB31</name>
            <bitOffset>31</bitOffset>
            <bitWidth>1</bitWidth>
          </field>
        </fields>
      </register>
      <register>
        <name>sFilterRegister.5.FR1</name>
        <addressOffset>0x268</addressOffset>
        <size>0x20</size>
        <fields>
          <field>
            <name>FB0</name>
            <bitOffset>0</bitOffset>
            <bitWidth>1</bitWidth>
          </field>
          <field>
            <name>FB1</name>
            <bitOffset>1</bitOffset>
            <bitWidth>1</bitWidth>
          </field>
          <field>
            <name>FB2</name>
            <bitOffset>2</bitOffset>
            <bitWidth>1</bitWidth>
          </field>
          <field>
            <name>FB3</name>
            <bitOffset>3</bitOffset>
            <bitWidth>1</bitWidth>
          </field>
          <field>
            <name>FB4</name>
            <bitOffset>4</bitOffset>
            <bitWidth>1</bitWidth>
          </field>
          <field>
            <name>FB5</name>
            <bitOffset>5</bitOffset>
            <bitWidth>1</bitWidth>
          </field>
          <field>
            <name>FB6</name>
            <bitOffset>6</bitOffset>
            <bitWidth>1</bitWidth>
          </field>
          <field>
            <name>FB7</name>
            <bitOffset>7</bitOffset>
            <bitWidth>1</bitWidth>
          </field>
          <field>
            <name>FB8</name>
            <bitOffset>8</bitOffset>
            <bitWidth>1</bitWidth>
          </field>
          <field>
            <name>FB9</name>
            <bitOffset>9</bitOffset>
            <bitWidth>1</bitWidth>
          </field>
          <field>
            <name>FB10</name>
            <bitOffset>10</bitOffset>
            <bitWidth>1</bitWidth>
          </field>
          <field>
            <name>FB11</name>
            <bitOffset>11</bitOffset>
            <bitWidth>1</bitWidth>
          </field>
          <field>
            <name>FB12</name>
            <bitOffset>12</bitOffset>
            <bitWidth>1</bitWidth>
          </field>
          <field>
            <name>FB13</name>
            <bitOffset>13</bitOffset>
            <bitWidth>1</bitWidth>
          </field>
          <field>
            <name>FB14</name>
            <bitOffset>14</bitOffset>
            <bitWidth>1</bitWidth>
          </field>
          <field>
            <name>FB15</name>
            <bitOffset>15</bitOffset>
            <bitWidth>1</bitWidth>
          </field>
          <field>
            <name>FB16</name>
            <bitOffset>16</bitOffset>
            <bitWidth>1</bitWidth>
          </field>
          <field>
            <name>FB17</name>
            <bitOffset>17</bitOffset>
            <bitWidth>1</bitWidth>
          </field>
          <field>
            <name>FB18</name>
            <bitOffset>18</bitOffset>
            <bitWidth>1</bitWidth>
          </field>
          <field>
            <name>FB19</name>
            <bitOffset>19</bitOffset>
            <bitWidth>1</bitWidth>
          </field>
          <field>
            <name>FB20</name>
            <bitOffset>20</bitOffset>
            <bitWidth>1</bitWidth>
          </field>
          <field>
            <name>FB21</name>
            <bitOffset>21</bitOffset>
            <bitWidth>1</bitWidth>
          </field>
          <field>
            <name>FB22</name>
            <bitOffset>22</bitOffset>
            <bitWidth>1</bitWidth>
          </field>
          <field>
            <name>FB23</name>
            <bitOffset>23</bitOffset>
            <bitWidth>1</bitWidth>
          </field>
          <field>
            <name>FB24</name>
            <bitOffset>24</bitOffset>
            <bitWidth>1</bitWidth>
          </field>
          <field>
            <name>FB25</name>
            <bitOffset>25</bitOffset>
            <bitWidth>1</bitWidth>
          </field>
          <field>
            <name>FB26</name>
            <bitOffset>26</bitOffset>
            <bitWidth>1</bitWidth>
          </field>
          <field>
            <name>FB27</name>
            <bitOffset>27</bitOffset>
            <bitWidth>1</bitWidth>
          </field>
          <field>
            <name>FB28</name>
            <bitOffset>28</bitOffset>
            <bitWidth>1</bitWidth>
          </field>
          <field>
            <name>FB29</name>
            <bitOffset>29</bitOffset>
            <bitWidth>1</bitWidth>
          </field>
          <field>
            <name>FB30</name>
            <bitOffset>30</bitOffset>
            <bitWidth>1</bitWidth>
          </field>
          <field>
            <name>FB31</name>
            <bitOffset>31</bitOffset>
            <bitWidth>1</bitWidth>
          </field>
        </fields>
      </register>
      <register>
        <name>sFilterRegister.5.FR2</name>
        <addressOffset>0x26c</addressOffset>
        <size>0x20</size>
        <fields>
          <field>
            <name>FB0</name>
            <bitOffset>0</bitOffset>
            <bitWidth>1</bitWidth>
          </field>
          <field>
            <name>FB1</name>
            <bitOffset>1</bitOffset>
            <bitWidth>1</bitWidth>
          </field>
          <field>
            <name>FB2</name>
            <bitOffset>2</bitOffset>
            <bitWidth>1</bitWidth>
          </field>
          <field>
            <name>FB3</name>
            <bitOffset>3</bitOffset>
            <bitWidth>1</bitWidth>
          </field>
          <field>
            <name>FB4</name>
            <bitOffset>4</bitOffset>
            <bitWidth>1</bitWidth>
          </field>
          <field>
            <name>FB5</name>
            <bitOffset>5</bitOffset>
            <bitWidth>1</bitWidth>
          </field>
          <field>
            <name>FB6</name>
            <bitOffset>6</bitOffset>
            <bitWidth>1</bitWidth>
          </field>
          <field>
            <name>FB7</name>
            <bitOffset>7</bitOffset>
            <bitWidth>1</bitWidth>
          </field>
          <field>
            <name>FB8</name>
            <bitOffset>8</bitOffset>
            <bitWidth>1</bitWidth>
          </field>
          <field>
            <name>FB9</name>
            <bitOffset>9</bitOffset>
            <bitWidth>1</bitWidth>
          </field>
          <field>
            <name>FB10</name>
            <bitOffset>10</bitOffset>
            <bitWidth>1</bitWidth>
          </field>
          <field>
            <name>FB11</name>
            <bitOffset>11</bitOffset>
            <bitWidth>1</bitWidth>
          </field>
          <field>
            <name>FB12</name>
            <bitOffset>12</bitOffset>
            <bitWidth>1</bitWidth>
          </field>
          <field>
            <name>FB13</name>
            <bitOffset>13</bitOffset>
            <bitWidth>1</bitWidth>
          </field>
          <field>
            <name>FB14</name>
            <bitOffset>14</bitOffset>
            <bitWidth>1</bitWidth>
          </field>
          <field>
            <name>FB15</name>
            <bitOffset>15</bitOffset>
            <bitWidth>1</bitWidth>
          </field>
          <field>
            <name>FB16</name>
            <bitOffset>16</bitOffset>
            <bitWidth>1</bitWidth>
          </field>
          <field>
            <name>FB17</name>
            <bitOffset>17</bitOffset>
            <bitWidth>1</bitWidth>
          </field>
          <field>
            <name>FB18</name>
            <bitOffset>18</bitOffset>
            <bitWidth>1</bitWidth>
          </field>
          <field>
            <name>FB19</name>
            <bitOffset>19</bitOffset>
            <bitWidth>1</bitWidth>
          </field>
          <field>
            <name>FB20</name>
            <bitOffset>20</bitOffset>
            <bitWidth>1</bitWidth>
          </field>
          <field>
            <name>FB21</name>
            <bitOffset>21</bitOffset>
            <bitWidth>1</bitWidth>
          </field>
          <field>
            <name>FB22</name>
            <bitOffset>22</bitOffset>
            <bitWidth>1</bitWidth>
          </field>
          <field>
            <name>FB23</name>
            <bitOffset>23</bitOffset>
            <bitWidth>1</bitWidth>
          </field>
          <field>
            <name>FB24</name>
            <bitOffset>24</bitOffset>
            <bitWidth>1</bitWidth>
          </field>
          <field>
            <name>FB25</name>
            <bitOffset>25</bitOffset>
            <bitWidth>1</bitWidth>
          </field>
          <field>
            <name>FB26</name>
            <bitOffset>26</bitOffset>
            <bitWidth>1</bitWidth>
          </field>
          <field>
            <name>FB27</name>
            <bitOffset>27</bitOffset>
            <bitWidth>1</bitWidth>
          </field>
          <field>
            <name>FB28</name>
            <bitOffset>28</bitOffset>
            <bitWidth>1</bitWidth>
          </field>
          <field>
            <name>FB29</name>
            <bitOffset>29</bitOffset>
            <bitWidth>1</bitWidth>
          </field>
          <field>
            <name>FB30</name>
            <bitOffset>30</bitOffset>
            <bitWidth>1</bitWidth>
          </field>
          <field>
            <name>FB31</name>
            <bitOffset>31</bitOffset>
            <bitWidth>1</bitWidth>
          </field>
        </fields>
      </register>
      <register>
        <name>sFilterRegister.6.FR1</name>
        <addressOffset>0x270</addressOffset>
        <size>0x20</size>
        <fields>
          <field>
            <name>FB0</name>
            <bitOffset>0</bitOffset>
            <bitWidth>1</bitWidth>
          </field>
          <field>
            <name>FB1</name>
            <bitOffset>1</bitOffset>
            <bitWidth>1</bitWidth>
          </field>
          <field>
            <name>FB2</name>
            <bitOffset>2</bitOffset>
            <bitWidth>1</bitWidth>
          </field>
          <field>
            <name>FB3</name>
            <bitOffset>3</bitOffset>
            <bitWidth>1</bitWidth>
          </field>
          <field>
            <name>FB4</name>
            <bitOffset>4</bitOffset>
            <bitWidth>1</bitWidth>
          </field>
          <field>
            <name>FB5</name>
            <bitOffset>5</bitOffset>
            <bitWidth>1</bitWidth>
          </field>
          <field>
            <name>FB6</name>
            <bitOffset>6</bitOffset>
            <bitWidth>1</bitWidth>
          </field>
          <field>
            <name>FB7</name>
            <bitOffset>7</bitOffset>
            <bitWidth>1</bitWidth>
          </field>
          <field>
            <name>FB8</name>
            <bitOffset>8</bitOffset>
            <bitWidth>1</bitWidth>
          </field>
          <field>
            <name>FB9</name>
            <bitOffset>9</bitOffset>
            <bitWidth>1</bitWidth>
          </field>
          <field>
            <name>FB10</name>
            <bitOffset>10</bitOffset>
            <bitWidth>1</bitWidth>
          </field>
          <field>
            <name>FB11</name>
            <bitOffset>11</bitOffset>
            <bitWidth>1</bitWidth>
          </field>
          <field>
            <name>FB12</name>
            <bitOffset>12</bitOffset>
            <bitWidth>1</bitWidth>
          </field>
          <field>
            <name>FB13</name>
            <bitOffset>13</bitOffset>
            <bitWidth>1</bitWidth>
          </field>
          <field>
            <name>FB14</name>
            <bitOffset>14</bitOffset>
            <bitWidth>1</bitWidth>
          </field>
          <field>
            <name>FB15</name>
            <bitOffset>15</bitOffset>
            <bitWidth>1</bitWidth>
          </field>
          <field>
            <name>FB16</name>
            <bitOffset>16</bitOffset>
            <bitWidth>1</bitWidth>
          </field>
          <field>
            <name>FB17</name>
            <bitOffset>17</bitOffset>
            <bitWidth>1</bitWidth>
          </field>
          <field>
            <name>FB18</name>
            <bitOffset>18</bitOffset>
            <bitWidth>1</bitWidth>
          </field>
          <field>
            <name>FB19</name>
            <bitOffset>19</bitOffset>
            <bitWidth>1</bitWidth>
          </field>
          <field>
            <name>FB20</name>
            <bitOffset>20</bitOffset>
            <bitWidth>1</bitWidth>
          </field>
          <field>
            <name>FB21</name>
            <bitOffset>21</bitOffset>
            <bitWidth>1</bitWidth>
          </field>
          <field>
            <name>FB22</name>
            <bitOffset>22</bitOffset>
            <bitWidth>1</bitWidth>
          </field>
          <field>
            <name>FB23</name>
            <bitOffset>23</bitOffset>
            <bitWidth>1</bitWidth>
          </field>
          <field>
            <name>FB24</name>
            <bitOffset>24</bitOffset>
            <bitWidth>1</bitWidth>
          </field>
          <field>
            <name>FB25</name>
            <bitOffset>25</bitOffset>
            <bitWidth>1</bitWidth>
          </field>
          <field>
            <name>FB26</name>
            <bitOffset>26</bitOffset>
            <bitWidth>1</bitWidth>
          </field>
          <field>
            <name>FB27</name>
            <bitOffset>27</bitOffset>
            <bitWidth>1</bitWidth>
          </field>
          <field>
            <name>FB28</name>
            <bitOffset>28</bitOffset>
            <bitWidth>1</bitWidth>
          </field>
          <field>
            <name>FB29</name>
            <bitOffset>29</bitOffset>
            <bitWidth>1</bitWidth>
          </field>
          <field>
            <name>FB30</name>
            <bitOffset>30</bitOffset>
            <bitWidth>1</bitWidth>
          </field>
          <field>
            <name>FB31</name>
            <bitOffset>31</bitOffset>
            <bitWidth>1</bitWidth>
          </field>
        </fields>
      </register>
      <register>
        <name>sFilterRegister.6.FR2</name>
        <addressOffset>0x274</addressOffset>
        <size>0x20</size>
        <fields>
          <field>
            <name>FB0</name>
            <bitOffset>0</bitOffset>
            <bitWidth>1</bitWidth>
          </field>
          <field>
            <name>FB1</name>
            <bitOffset>1</bitOffset>
            <bitWidth>1</bitWidth>
          </field>
          <field>
            <name>FB2</name>
            <bitOffset>2</bitOffset>
            <bitWidth>1</bitWidth>
          </field>
          <field>
            <name>FB3</name>
            <bitOffset>3</bitOffset>
            <bitWidth>1</bitWidth>
          </field>
          <field>
            <name>FB4</name>
            <bitOffset>4</bitOffset>
            <bitWidth>1</bitWidth>
          </field>
          <field>
            <name>FB5</name>
            <bitOffset>5</bitOffset>
            <bitWidth>1</bitWidth>
          </field>
          <field>
            <name>FB6</name>
            <bitOffset>6</bitOffset>
            <bitWidth>1</bitWidth>
          </field>
          <field>
            <name>FB7</name>
            <bitOffset>7</bitOffset>
            <bitWidth>1</bitWidth>
          </field>
          <field>
            <name>FB8</name>
            <bitOffset>8</bitOffset>
            <bitWidth>1</bitWidth>
          </field>
          <field>
            <name>FB9</name>
            <bitOffset>9</bitOffset>
            <bitWidth>1</bitWidth>
          </field>
          <field>
            <name>FB10</name>
            <bitOffset>10</bitOffset>
            <bitWidth>1</bitWidth>
          </field>
          <field>
            <name>FB11</name>
            <bitOffset>11</bitOffset>
            <bitWidth>1</bitWidth>
          </field>
          <field>
            <name>FB12</name>
            <bitOffset>12</bitOffset>
            <bitWidth>1</bitWidth>
          </field>
          <field>
            <name>FB13</name>
            <bitOffset>13</bitOffset>
            <bitWidth>1</bitWidth>
          </field>
          <field>
            <name>FB14</name>
            <bitOffset>14</bitOffset>
            <bitWidth>1</bitWidth>
          </field>
          <field>
            <name>FB15</name>
            <bitOffset>15</bitOffset>
            <bitWidth>1</bitWidth>
          </field>
          <field>
            <name>FB16</name>
            <bitOffset>16</bitOffset>
            <bitWidth>1</bitWidth>
          </field>
          <field>
            <name>FB17</name>
            <bitOffset>17</bitOffset>
            <bitWidth>1</bitWidth>
          </field>
          <field>
            <name>FB18</name>
            <bitOffset>18</bitOffset>
            <bitWidth>1</bitWidth>
          </field>
          <field>
            <name>FB19</name>
            <bitOffset>19</bitOffset>
            <bitWidth>1</bitWidth>
          </field>
          <field>
            <name>FB20</name>
            <bitOffset>20</bitOffset>
            <bitWidth>1</bitWidth>
          </field>
          <field>
            <name>FB21</name>
            <bitOffset>21</bitOffset>
            <bitWidth>1</bitWidth>
          </field>
          <field>
            <name>FB22</name>
            <bitOffset>22</bitOffset>
            <bitWidth>1</bitWidth>
          </field>
          <field>
            <name>FB23</name>
            <bitOffset>23</bitOffset>
            <bitWidth>1</bitWidth>
          </field>
          <field>
            <name>FB24</name>
            <bitOffset>24</bitOffset>
            <bitWidth>1</bitWidth>
          </field>
          <field>
            <name>FB25</name>
            <bitOffset>25</bitOffset>
            <bitWidth>1</bitWidth>
          </field>
          <field>
            <name>FB26</name>
            <bitOffset>26</bitOffset>
            <bitWidth>1</bitWidth>
          </field>
          <field>
            <name>FB27</name>
            <bitOffset>27</bitOffset>
            <bitWidth>1</bitWidth>
          </field>
          <field>
            <name>FB28</name>
            <bitOffset>28</bitOffset>
            <bitWidth>1</bitWidth>
          </field>
          <field>
            <name>FB29</name>
            <bitOffset>29</bitOffset>
            <bitWidth>1</bitWidth>
          </field>
          <field>
            <name>FB30</name>
            <bitOffset>30</bitOffset>
            <bitWidth>1</bitWidth>
          </field>
          <field>
            <name>FB31</name>
            <bitOffset>31</bitOffset>
            <bitWidth>1</bitWidth>
          </field>
        </fields>
      </register>
      <register>
        <name>sFilterRegister.7.FR1</name>
        <addressOffset>0x278</addressOffset>
        <size>0x20</size>
        <fields>
          <field>
            <name>FB0</name>
            <bitOffset>0</bitOffset>
            <bitWidth>1</bitWidth>
          </field>
          <field>
            <name>FB1</name>
            <bitOffset>1</bitOffset>
            <bitWidth>1</bitWidth>
          </field>
          <field>
            <name>FB2</name>
            <bitOffset>2</bitOffset>
            <bitWidth>1</bitWidth>
          </field>
          <field>
            <name>FB3</name>
            <bitOffset>3</bitOffset>
            <bitWidth>1</bitWidth>
          </field>
          <field>
            <name>FB4</name>
            <bitOffset>4</bitOffset>
            <bitWidth>1</bitWidth>
          </field>
          <field>
            <name>FB5</name>
            <bitOffset>5</bitOffset>
            <bitWidth>1</bitWidth>
          </field>
          <field>
            <name>FB6</name>
            <bitOffset>6</bitOffset>
            <bitWidth>1</bitWidth>
          </field>
          <field>
            <name>FB7</name>
            <bitOffset>7</bitOffset>
            <bitWidth>1</bitWidth>
          </field>
          <field>
            <name>FB8</name>
            <bitOffset>8</bitOffset>
            <bitWidth>1</bitWidth>
          </field>
          <field>
            <name>FB9</name>
            <bitOffset>9</bitOffset>
            <bitWidth>1</bitWidth>
          </field>
          <field>
            <name>FB10</name>
            <bitOffset>10</bitOffset>
            <bitWidth>1</bitWidth>
          </field>
          <field>
            <name>FB11</name>
            <bitOffset>11</bitOffset>
            <bitWidth>1</bitWidth>
          </field>
          <field>
            <name>FB12</name>
            <bitOffset>12</bitOffset>
            <bitWidth>1</bitWidth>
          </field>
          <field>
            <name>FB13</name>
            <bitOffset>13</bitOffset>
            <bitWidth>1</bitWidth>
          </field>
          <field>
            <name>FB14</name>
            <bitOffset>14</bitOffset>
            <bitWidth>1</bitWidth>
          </field>
          <field>
            <name>FB15</name>
            <bitOffset>15</bitOffset>
            <bitWidth>1</bitWidth>
          </field>
          <field>
            <name>FB16</name>
            <bitOffset>16</bitOffset>
            <bitWidth>1</bitWidth>
          </field>
          <field>
            <name>FB17</name>
            <bitOffset>17</bitOffset>
            <bitWidth>1</bitWidth>
          </field>
          <field>
            <name>FB18</name>
            <bitOffset>18</bitOffset>
            <bitWidth>1</bitWidth>
          </field>
          <field>
            <name>FB19</name>
            <bitOffset>19</bitOffset>
            <bitWidth>1</bitWidth>
          </field>
          <field>
            <name>FB20</name>
            <bitOffset>20</bitOffset>
            <bitWidth>1</bitWidth>
          </field>
          <field>
            <name>FB21</name>
            <bitOffset>21</bitOffset>
            <bitWidth>1</bitWidth>
          </field>
          <field>
            <name>FB22</name>
            <bitOffset>22</bitOffset>
            <bitWidth>1</bitWidth>
          </field>
          <field>
            <name>FB23</name>
            <bitOffset>23</bitOffset>
            <bitWidth>1</bitWidth>
          </field>
          <field>
            <name>FB24</name>
            <bitOffset>24</bitOffset>
            <bitWidth>1</bitWidth>
          </field>
          <field>
            <name>FB25</name>
            <bitOffset>25</bitOffset>
            <bitWidth>1</bitWidth>
          </field>
          <field>
            <name>FB26</name>
            <bitOffset>26</bitOffset>
            <bitWidth>1</bitWidth>
          </field>
          <field>
            <name>FB27</name>
            <bitOffset>27</bitOffset>
            <bitWidth>1</bitWidth>
          </field>
          <field>
            <name>FB28</name>
            <bitOffset>28</bitOffset>
            <bitWidth>1</bitWidth>
          </field>
          <field>
            <name>FB29</name>
            <bitOffset>29</bitOffset>
            <bitWidth>1</bitWidth>
          </field>
          <field>
            <name>FB30</name>
            <bitOffset>30</bitOffset>
            <bitWidth>1</bitWidth>
          </field>
          <field>
            <name>FB31</name>
            <bitOffset>31</bitOffset>
            <bitWidth>1</bitWidth>
          </field>
        </fields>
      </register>
      <register>
        <name>sFilterRegister.7.FR2</name>
        <addressOffset>0x27c</addressOffset>
        <size>0x20</size>
        <fields>
          <field>
            <name>FB0</name>
            <bitOffset>0</bitOffset>
            <bitWidth>1</bitWidth>
          </field>
          <field>
            <name>FB1</name>
            <bitOffset>1</bitOffset>
            <bitWidth>1</bitWidth>
          </field>
          <field>
            <name>FB2</name>
            <bitOffset>2</bitOffset>
            <bitWidth>1</bitWidth>
          </field>
          <field>
            <name>FB3</name>
            <bitOffset>3</bitOffset>
            <bitWidth>1</bitWidth>
          </field>
          <field>
            <name>FB4</name>
            <bitOffset>4</bitOffset>
            <bitWidth>1</bitWidth>
          </field>
          <field>
            <name>FB5</name>
            <bitOffset>5</bitOffset>
            <bitWidth>1</bitWidth>
          </field>
          <field>
            <name>FB6</name>
            <bitOffset>6</bitOffset>
            <bitWidth>1</bitWidth>
          </field>
          <field>
            <name>FB7</name>
            <bitOffset>7</bitOffset>
            <bitWidth>1</bitWidth>
          </field>
          <field>
            <name>FB8</name>
            <bitOffset>8</bitOffset>
            <bitWidth>1</bitWidth>
          </field>
          <field>
            <name>FB9</name>
            <bitOffset>9</bitOffset>
            <bitWidth>1</bitWidth>
          </field>
          <field>
            <name>FB10</name>
            <bitOffset>10</bitOffset>
            <bitWidth>1</bitWidth>
          </field>
          <field>
            <name>FB11</name>
            <bitOffset>11</bitOffset>
            <bitWidth>1</bitWidth>
          </field>
          <field>
            <name>FB12</name>
            <bitOffset>12</bitOffset>
            <bitWidth>1</bitWidth>
          </field>
          <field>
            <name>FB13</name>
            <bitOffset>13</bitOffset>
            <bitWidth>1</bitWidth>
          </field>
          <field>
            <name>FB14</name>
            <bitOffset>14</bitOffset>
            <bitWidth>1</bitWidth>
          </field>
          <field>
            <name>FB15</name>
            <bitOffset>15</bitOffset>
            <bitWidth>1</bitWidth>
          </field>
          <field>
            <name>FB16</name>
            <bitOffset>16</bitOffset>
            <bitWidth>1</bitWidth>
          </field>
          <field>
            <name>FB17</name>
            <bitOffset>17</bitOffset>
            <bitWidth>1</bitWidth>
          </field>
          <field>
            <name>FB18</name>
            <bitOffset>18</bitOffset>
            <bitWidth>1</bitWidth>
          </field>
          <field>
            <name>FB19</name>
            <bitOffset>19</bitOffset>
            <bitWidth>1</bitWidth>
          </field>
          <field>
            <name>FB20</name>
            <bitOffset>20</bitOffset>
            <bitWidth>1</bitWidth>
          </field>
          <field>
            <name>FB21</name>
            <bitOffset>21</bitOffset>
            <bitWidth>1</bitWidth>
          </field>
          <field>
            <name>FB22</name>
            <bitOffset>22</bitOffset>
            <bitWidth>1</bitWidth>
          </field>
          <field>
            <name>FB23</name>
            <bitOffset>23</bitOffset>
            <bitWidth>1</bitWidth>
          </field>
          <field>
            <name>FB24</name>
            <bitOffset>24</bitOffset>
            <bitWidth>1</bitWidth>
          </field>
          <field>
            <name>FB25</name>
            <bitOffset>25</bitOffset>
            <bitWidth>1</bitWidth>
          </field>
          <field>
            <name>FB26</name>
            <bitOffset>26</bitOffset>
            <bitWidth>1</bitWidth>
          </field>
          <field>
            <name>FB27</name>
            <bitOffset>27</bitOffset>
            <bitWidth>1</bitWidth>
          </field>
          <field>
            <name>FB28</name>
            <bitOffset>28</bitOffset>
            <bitWidth>1</bitWidth>
          </field>
          <field>
            <name>FB29</name>
            <bitOffset>29</bitOffset>
            <bitWidth>1</bitWidth>
          </field>
          <field>
            <name>FB30</name>
            <bitOffset>30</bitOffset>
            <bitWidth>1</bitWidth>
          </field>
          <field>
            <name>FB31</name>
            <bitOffset>31</bitOffset>
            <bitWidth>1</bitWidth>
          </field>
        </fields>
      </register>
      <register>
        <name>sFilterRegister.8.FR1</name>
        <addressOffset>0x280</addressOffset>
        <size>0x20</size>
        <fields>
          <field>
            <name>FB0</name>
            <bitOffset>0</bitOffset>
            <bitWidth>1</bitWidth>
          </field>
          <field>
            <name>FB1</name>
            <bitOffset>1</bitOffset>
            <bitWidth>1</bitWidth>
          </field>
          <field>
            <name>FB2</name>
            <bitOffset>2</bitOffset>
            <bitWidth>1</bitWidth>
          </field>
          <field>
            <name>FB3</name>
            <bitOffset>3</bitOffset>
            <bitWidth>1</bitWidth>
          </field>
          <field>
            <name>FB4</name>
            <bitOffset>4</bitOffset>
            <bitWidth>1</bitWidth>
          </field>
          <field>
            <name>FB5</name>
            <bitOffset>5</bitOffset>
            <bitWidth>1</bitWidth>
          </field>
          <field>
            <name>FB6</name>
            <bitOffset>6</bitOffset>
            <bitWidth>1</bitWidth>
          </field>
          <field>
            <name>FB7</name>
            <bitOffset>7</bitOffset>
            <bitWidth>1</bitWidth>
          </field>
          <field>
            <name>FB8</name>
            <bitOffset>8</bitOffset>
            <bitWidth>1</bitWidth>
          </field>
          <field>
            <name>FB9</name>
            <bitOffset>9</bitOffset>
            <bitWidth>1</bitWidth>
          </field>
          <field>
            <name>FB10</name>
            <bitOffset>10</bitOffset>
            <bitWidth>1</bitWidth>
          </field>
          <field>
            <name>FB11</name>
            <bitOffset>11</bitOffset>
            <bitWidth>1</bitWidth>
          </field>
          <field>
            <name>FB12</name>
            <bitOffset>12</bitOffset>
            <bitWidth>1</bitWidth>
          </field>
          <field>
            <name>FB13</name>
            <bitOffset>13</bitOffset>
            <bitWidth>1</bitWidth>
          </field>
          <field>
            <name>FB14</name>
            <bitOffset>14</bitOffset>
            <bitWidth>1</bitWidth>
          </field>
          <field>
            <name>FB15</name>
            <bitOffset>15</bitOffset>
            <bitWidth>1</bitWidth>
          </field>
          <field>
            <name>FB16</name>
            <bitOffset>16</bitOffset>
            <bitWidth>1</bitWidth>
          </field>
          <field>
            <name>FB17</name>
            <bitOffset>17</bitOffset>
            <bitWidth>1</bitWidth>
          </field>
          <field>
            <name>FB18</name>
            <bitOffset>18</bitOffset>
            <bitWidth>1</bitWidth>
          </field>
          <field>
            <name>FB19</name>
            <bitOffset>19</bitOffset>
            <bitWidth>1</bitWidth>
          </field>
          <field>
            <name>FB20</name>
            <bitOffset>20</bitOffset>
            <bitWidth>1</bitWidth>
          </field>
          <field>
            <name>FB21</name>
            <bitOffset>21</bitOffset>
            <bitWidth>1</bitWidth>
          </field>
          <field>
            <name>FB22</name>
            <bitOffset>22</bitOffset>
            <bitWidth>1</bitWidth>
          </field>
          <field>
            <name>FB23</name>
            <bitOffset>23</bitOffset>
            <bitWidth>1</bitWidth>
          </field>
          <field>
            <name>FB24</name>
            <bitOffset>24</bitOffset>
            <bitWidth>1</bitWidth>
          </field>
          <field>
            <name>FB25</name>
            <bitOffset>25</bitOffset>
            <bitWidth>1</bitWidth>
          </field>
          <field>
            <name>FB26</name>
            <bitOffset>26</bitOffset>
            <bitWidth>1</bitWidth>
          </field>
          <field>
            <name>FB27</name>
            <bitOffset>27</bitOffset>
            <bitWidth>1</bitWidth>
          </field>
          <field>
            <name>FB28</name>
            <bitOffset>28</bitOffset>
            <bitWidth>1</bitWidth>
          </field>
          <field>
            <name>FB29</name>
            <bitOffset>29</bitOffset>
            <bitWidth>1</bitWidth>
          </field>
          <field>
            <name>FB30</name>
            <bitOffset>30</bitOffset>
            <bitWidth>1</bitWidth>
          </field>
          <field>
            <name>FB31</name>
            <bitOffset>31</bitOffset>
            <bitWidth>1</bitWidth>
          </field>
        </fields>
      </register>
      <register>
        <name>sFilterRegister.8.FR2</name>
        <addressOffset>0x284</addressOffset>
        <size>0x20</size>
        <fields>
          <field>
            <name>FB0</name>
            <bitOffset>0</bitOffset>
            <bitWidth>1</bitWidth>
          </field>
          <field>
            <name>FB1</name>
            <bitOffset>1</bitOffset>
            <bitWidth>1</bitWidth>
          </field>
          <field>
            <name>FB2</name>
            <bitOffset>2</bitOffset>
            <bitWidth>1</bitWidth>
          </field>
          <field>
            <name>FB3</name>
            <bitOffset>3</bitOffset>
            <bitWidth>1</bitWidth>
          </field>
          <field>
            <name>FB4</name>
            <bitOffset>4</bitOffset>
            <bitWidth>1</bitWidth>
          </field>
          <field>
            <name>FB5</name>
            <bitOffset>5</bitOffset>
            <bitWidth>1</bitWidth>
          </field>
          <field>
            <name>FB6</name>
            <bitOffset>6</bitOffset>
            <bitWidth>1</bitWidth>
          </field>
          <field>
            <name>FB7</name>
            <bitOffset>7</bitOffset>
            <bitWidth>1</bitWidth>
          </field>
          <field>
            <name>FB8</name>
            <bitOffset>8</bitOffset>
            <bitWidth>1</bitWidth>
          </field>
          <field>
            <name>FB9</name>
            <bitOffset>9</bitOffset>
            <bitWidth>1</bitWidth>
          </field>
          <field>
            <name>FB10</name>
            <bitOffset>10</bitOffset>
            <bitWidth>1</bitWidth>
          </field>
          <field>
            <name>FB11</name>
            <bitOffset>11</bitOffset>
            <bitWidth>1</bitWidth>
          </field>
          <field>
            <name>FB12</name>
            <bitOffset>12</bitOffset>
            <bitWidth>1</bitWidth>
          </field>
          <field>
            <name>FB13</name>
            <bitOffset>13</bitOffset>
            <bitWidth>1</bitWidth>
          </field>
          <field>
            <name>FB14</name>
            <bitOffset>14</bitOffset>
            <bitWidth>1</bitWidth>
          </field>
          <field>
            <name>FB15</name>
            <bitOffset>15</bitOffset>
            <bitWidth>1</bitWidth>
          </field>
          <field>
            <name>FB16</name>
            <bitOffset>16</bitOffset>
            <bitWidth>1</bitWidth>
          </field>
          <field>
            <name>FB17</name>
            <bitOffset>17</bitOffset>
            <bitWidth>1</bitWidth>
          </field>
          <field>
            <name>FB18</name>
            <bitOffset>18</bitOffset>
            <bitWidth>1</bitWidth>
          </field>
          <field>
            <name>FB19</name>
            <bitOffset>19</bitOffset>
            <bitWidth>1</bitWidth>
          </field>
          <field>
            <name>FB20</name>
            <bitOffset>20</bitOffset>
            <bitWidth>1</bitWidth>
          </field>
          <field>
            <name>FB21</name>
            <bitOffset>21</bitOffset>
            <bitWidth>1</bitWidth>
          </field>
          <field>
            <name>FB22</name>
            <bitOffset>22</bitOffset>
            <bitWidth>1</bitWidth>
          </field>
          <field>
            <name>FB23</name>
            <bitOffset>23</bitOffset>
            <bitWidth>1</bitWidth>
          </field>
          <field>
            <name>FB24</name>
            <bitOffset>24</bitOffset>
            <bitWidth>1</bitWidth>
          </field>
          <field>
            <name>FB25</name>
            <bitOffset>25</bitOffset>
            <bitWidth>1</bitWidth>
          </field>
          <field>
            <name>FB26</name>
            <bitOffset>26</bitOffset>
            <bitWidth>1</bitWidth>
          </field>
          <field>
            <name>FB27</name>
            <bitOffset>27</bitOffset>
            <bitWidth>1</bitWidth>
          </field>
          <field>
            <name>FB28</name>
            <bitOffset>28</bitOffset>
            <bitWidth>1</bitWidth>
          </field>
          <field>
            <name>FB29</name>
            <bitOffset>29</bitOffset>
            <bitWidth>1</bitWidth>
          </field>
          <field>
            <name>FB30</name>
            <bitOffset>30</bitOffset>
            <bitWidth>1</bitWidth>
          </field>
          <field>
            <name>FB31</name>
            <bitOffset>31</bitOffset>
            <bitWidth>1</bitWidth>
          </field>
        </fields>
      </register>
      <register>
        <name>sFilterRegister.9.FR1</name>
        <addressOffset>0x288</addressOffset>
        <size>0x20</size>
        <fields>
          <field>
            <name>FB0</name>
            <bitOffset>0</bitOffset>
            <bitWidth>1</bitWidth>
          </field>
          <field>
            <name>FB1</name>
            <bitOffset>1</bitOffset>
            <bitWidth>1</bitWidth>
          </field>
          <field>
            <name>FB2</name>
            <bitOffset>2</bitOffset>
            <bitWidth>1</bitWidth>
          </field>
          <field>
            <name>FB3</name>
            <bitOffset>3</bitOffset>
            <bitWidth>1</bitWidth>
          </field>
          <field>
            <name>FB4</name>
            <bitOffset>4</bitOffset>
            <bitWidth>1</bitWidth>
          </field>
          <field>
            <name>FB5</name>
            <bitOffset>5</bitOffset>
            <bitWidth>1</bitWidth>
          </field>
          <field>
            <name>FB6</name>
            <bitOffset>6</bitOffset>
            <bitWidth>1</bitWidth>
          </field>
          <field>
            <name>FB7</name>
            <bitOffset>7</bitOffset>
            <bitWidth>1</bitWidth>
          </field>
          <field>
            <name>FB8</name>
            <bitOffset>8</bitOffset>
            <bitWidth>1</bitWidth>
          </field>
          <field>
            <name>FB9</name>
            <bitOffset>9</bitOffset>
            <bitWidth>1</bitWidth>
          </field>
          <field>
            <name>FB10</name>
            <bitOffset>10</bitOffset>
            <bitWidth>1</bitWidth>
          </field>
          <field>
            <name>FB11</name>
            <bitOffset>11</bitOffset>
            <bitWidth>1</bitWidth>
          </field>
          <field>
            <name>FB12</name>
            <bitOffset>12</bitOffset>
            <bitWidth>1</bitWidth>
          </field>
          <field>
            <name>FB13</name>
            <bitOffset>13</bitOffset>
            <bitWidth>1</bitWidth>
          </field>
          <field>
            <name>FB14</name>
            <bitOffset>14</bitOffset>
            <bitWidth>1</bitWidth>
          </field>
          <field>
            <name>FB15</name>
            <bitOffset>15</bitOffset>
            <bitWidth>1</bitWidth>
          </field>
          <field>
            <name>FB16</name>
            <bitOffset>16</bitOffset>
            <bitWidth>1</bitWidth>
          </field>
          <field>
            <name>FB17</name>
            <bitOffset>17</bitOffset>
            <bitWidth>1</bitWidth>
          </field>
          <field>
            <name>FB18</name>
            <bitOffset>18</bitOffset>
            <bitWidth>1</bitWidth>
          </field>
          <field>
            <name>FB19</name>
            <bitOffset>19</bitOffset>
            <bitWidth>1</bitWidth>
          </field>
          <field>
            <name>FB20</name>
            <bitOffset>20</bitOffset>
            <bitWidth>1</bitWidth>
          </field>
          <field>
            <name>FB21</name>
            <bitOffset>21</bitOffset>
            <bitWidth>1</bitWidth>
          </field>
          <field>
            <name>FB22</name>
            <bitOffset>22</bitOffset>
            <bitWidth>1</bitWidth>
          </field>
          <field>
            <name>FB23</name>
            <bitOffset>23</bitOffset>
            <bitWidth>1</bitWidth>
          </field>
          <field>
            <name>FB24</name>
            <bitOffset>24</bitOffset>
            <bitWidth>1</bitWidth>
          </field>
          <field>
            <name>FB25</name>
            <bitOffset>25</bitOffset>
            <bitWidth>1</bitWidth>
          </field>
          <field>
            <name>FB26</name>
            <bitOffset>26</bitOffset>
            <bitWidth>1</bitWidth>
          </field>
          <field>
            <name>FB27</name>
            <bitOffset>27</bitOffset>
            <bitWidth>1</bitWidth>
          </field>
          <field>
            <name>FB28</name>
            <bitOffset>28</bitOffset>
            <bitWidth>1</bitWidth>
          </field>
          <field>
            <name>FB29</name>
            <bitOffset>29</bitOffset>
            <bitWidth>1</bitWidth>
          </field>
          <field>
            <name>FB30</name>
            <bitOffset>30</bitOffset>
            <bitWidth>1</bitWidth>
          </field>
          <field>
            <name>FB31</name>
            <bitOffset>31</bitOffset>
            <bitWidth>1</bitWidth>
          </field>
        </fields>
      </register>
      <register>
        <name>sFilterRegister.9.FR2</name>
        <addressOffset>0x28c</addressOffset>
        <size>0x20</size>
        <fields>
          <field>
            <name>FB0</name>
            <bitOffset>0</bitOffset>
            <bitWidth>1</bitWidth>
          </field>
          <field>
            <name>FB1</name>
            <bitOffset>1</bitOffset>
            <bitWidth>1</bitWidth>
          </field>
          <field>
            <name>FB2</name>
            <bitOffset>2</bitOffset>
            <bitWidth>1</bitWidth>
          </field>
          <field>
            <name>FB3</name>
            <bitOffset>3</bitOffset>
            <bitWidth>1</bitWidth>
          </field>
          <field>
            <name>FB4</name>
            <bitOffset>4</bitOffset>
            <bitWidth>1</bitWidth>
          </field>
          <field>
            <name>FB5</name>
            <bitOffset>5</bitOffset>
            <bitWidth>1</bitWidth>
          </field>
          <field>
            <name>FB6</name>
            <bitOffset>6</bitOffset>
            <bitWidth>1</bitWidth>
          </field>
          <field>
            <name>FB7</name>
            <bitOffset>7</bitOffset>
            <bitWidth>1</bitWidth>
          </field>
          <field>
            <name>FB8</name>
            <bitOffset>8</bitOffset>
            <bitWidth>1</bitWidth>
          </field>
          <field>
            <name>FB9</name>
            <bitOffset>9</bitOffset>
            <bitWidth>1</bitWidth>
          </field>
          <field>
            <name>FB10</name>
            <bitOffset>10</bitOffset>
            <bitWidth>1</bitWidth>
          </field>
          <field>
            <name>FB11</name>
            <bitOffset>11</bitOffset>
            <bitWidth>1</bitWidth>
          </field>
          <field>
            <name>FB12</name>
            <bitOffset>12</bitOffset>
            <bitWidth>1</bitWidth>
          </field>
          <field>
            <name>FB13</name>
            <bitOffset>13</bitOffset>
            <bitWidth>1</bitWidth>
          </field>
          <field>
            <name>FB14</name>
            <bitOffset>14</bitOffset>
            <bitWidth>1</bitWidth>
          </field>
          <field>
            <name>FB15</name>
            <bitOffset>15</bitOffset>
            <bitWidth>1</bitWidth>
          </field>
          <field>
            <name>FB16</name>
            <bitOffset>16</bitOffset>
            <bitWidth>1</bitWidth>
          </field>
          <field>
            <name>FB17</name>
            <bitOffset>17</bitOffset>
            <bitWidth>1</bitWidth>
          </field>
          <field>
            <name>FB18</name>
            <bitOffset>18</bitOffset>
            <bitWidth>1</bitWidth>
          </field>
          <field>
            <name>FB19</name>
            <bitOffset>19</bitOffset>
            <bitWidth>1</bitWidth>
          </field>
          <field>
            <name>FB20</name>
            <bitOffset>20</bitOffset>
            <bitWidth>1</bitWidth>
          </field>
          <field>
            <name>FB21</name>
            <bitOffset>21</bitOffset>
            <bitWidth>1</bitWidth>
          </field>
          <field>
            <name>FB22</name>
            <bitOffset>22</bitOffset>
            <bitWidth>1</bitWidth>
          </field>
          <field>
            <name>FB23</name>
            <bitOffset>23</bitOffset>
            <bitWidth>1</bitWidth>
          </field>
          <field>
            <name>FB24</name>
            <bitOffset>24</bitOffset>
            <bitWidth>1</bitWidth>
          </field>
          <field>
            <name>FB25</name>
            <bitOffset>25</bitOffset>
            <bitWidth>1</bitWidth>
          </field>
          <field>
            <name>FB26</name>
            <bitOffset>26</bitOffset>
            <bitWidth>1</bitWidth>
          </field>
          <field>
            <name>FB27</name>
            <bitOffset>27</bitOffset>
            <bitWidth>1</bitWidth>
          </field>
          <field>
            <name>FB28</name>
            <bitOffset>28</bitOffset>
            <bitWidth>1</bitWidth>
          </field>
          <field>
            <name>FB29</name>
            <bitOffset>29</bitOffset>
            <bitWidth>1</bitWidth>
          </field>
          <field>
            <name>FB30</name>
            <bitOffset>30</bitOffset>
            <bitWidth>1</bitWidth>
          </field>
          <field>
            <name>FB31</name>
            <bitOffset>31</bitOffset>
            <bitWidth>1</bitWidth>
          </field>
        </fields>
      </register>
      <register>
        <name>sFilterRegister.10.FR1</name>
        <addressOffset>0x290</addressOffset>
        <size>0x20</size>
        <fields>
          <field>
            <name>FB0</name>
            <bitOffset>0</bitOffset>
            <bitWidth>1</bitWidth>
          </field>
          <field>
            <name>FB1</name>
            <bitOffset>1</bitOffset>
            <bitWidth>1</bitWidth>
          </field>
          <field>
            <name>FB2</name>
            <bitOffset>2</bitOffset>
            <bitWidth>1</bitWidth>
          </field>
          <field>
            <name>FB3</name>
            <bitOffset>3</bitOffset>
            <bitWidth>1</bitWidth>
          </field>
          <field>
            <name>FB4</name>
            <bitOffset>4</bitOffset>
            <bitWidth>1</bitWidth>
          </field>
          <field>
            <name>FB5</name>
            <bitOffset>5</bitOffset>
            <bitWidth>1</bitWidth>
          </field>
          <field>
            <name>FB6</name>
            <bitOffset>6</bitOffset>
            <bitWidth>1</bitWidth>
          </field>
          <field>
            <name>FB7</name>
            <bitOffset>7</bitOffset>
            <bitWidth>1</bitWidth>
          </field>
          <field>
            <name>FB8</name>
            <bitOffset>8</bitOffset>
            <bitWidth>1</bitWidth>
          </field>
          <field>
            <name>FB9</name>
            <bitOffset>9</bitOffset>
            <bitWidth>1</bitWidth>
          </field>
          <field>
            <name>FB10</name>
            <bitOffset>10</bitOffset>
            <bitWidth>1</bitWidth>
          </field>
          <field>
            <name>FB11</name>
            <bitOffset>11</bitOffset>
            <bitWidth>1</bitWidth>
          </field>
          <field>
            <name>FB12</name>
            <bitOffset>12</bitOffset>
            <bitWidth>1</bitWidth>
          </field>
          <field>
            <name>FB13</name>
            <bitOffset>13</bitOffset>
            <bitWidth>1</bitWidth>
          </field>
          <field>
            <name>FB14</name>
            <bitOffset>14</bitOffset>
            <bitWidth>1</bitWidth>
          </field>
          <field>
            <name>FB15</name>
            <bitOffset>15</bitOffset>
            <bitWidth>1</bitWidth>
          </field>
          <field>
            <name>FB16</name>
            <bitOffset>16</bitOffset>
            <bitWidth>1</bitWidth>
          </field>
          <field>
            <name>FB17</name>
            <bitOffset>17</bitOffset>
            <bitWidth>1</bitWidth>
          </field>
          <field>
            <name>FB18</name>
            <bitOffset>18</bitOffset>
            <bitWidth>1</bitWidth>
          </field>
          <field>
            <name>FB19</name>
            <bitOffset>19</bitOffset>
            <bitWidth>1</bitWidth>
          </field>
          <field>
            <name>FB20</name>
            <bitOffset>20</bitOffset>
            <bitWidth>1</bitWidth>
          </field>
          <field>
            <name>FB21</name>
            <bitOffset>21</bitOffset>
            <bitWidth>1</bitWidth>
          </field>
          <field>
            <name>FB22</name>
            <bitOffset>22</bitOffset>
            <bitWidth>1</bitWidth>
          </field>
          <field>
            <name>FB23</name>
            <bitOffset>23</bitOffset>
            <bitWidth>1</bitWidth>
          </field>
          <field>
            <name>FB24</name>
            <bitOffset>24</bitOffset>
            <bitWidth>1</bitWidth>
          </field>
          <field>
            <name>FB25</name>
            <bitOffset>25</bitOffset>
            <bitWidth>1</bitWidth>
          </field>
          <field>
            <name>FB26</name>
            <bitOffset>26</bitOffset>
            <bitWidth>1</bitWidth>
          </field>
          <field>
            <name>FB27</name>
            <bitOffset>27</bitOffset>
            <bitWidth>1</bitWidth>
          </field>
          <field>
            <name>FB28</name>
            <bitOffset>28</bitOffset>
            <bitWidth>1</bitWidth>
          </field>
          <field>
            <name>FB29</name>
            <bitOffset>29</bitOffset>
            <bitWidth>1</bitWidth>
          </field>
          <field>
            <name>FB30</name>
            <bitOffset>30</bitOffset>
            <bitWidth>1</bitWidth>
          </field>
          <field>
            <name>FB31</name>
            <bitOffset>31</bitOffset>
            <bitWidth>1</bitWidth>
          </field>
        </fields>
      </register>
      <register>
        <name>sFilterRegister.10.FR2</name>
        <addressOffset>0x294</addressOffset>
        <size>0x20</size>
        <fields>
          <field>
            <name>FB0</name>
            <bitOffset>0</bitOffset>
            <bitWidth>1</bitWidth>
          </field>
          <field>
            <name>FB1</name>
            <bitOffset>1</bitOffset>
            <bitWidth>1</bitWidth>
          </field>
          <field>
            <name>FB2</name>
            <bitOffset>2</bitOffset>
            <bitWidth>1</bitWidth>
          </field>
          <field>
            <name>FB3</name>
            <bitOffset>3</bitOffset>
            <bitWidth>1</bitWidth>
          </field>
          <field>
            <name>FB4</name>
            <bitOffset>4</bitOffset>
            <bitWidth>1</bitWidth>
          </field>
          <field>
            <name>FB5</name>
            <bitOffset>5</bitOffset>
            <bitWidth>1</bitWidth>
          </field>
          <field>
            <name>FB6</name>
            <bitOffset>6</bitOffset>
            <bitWidth>1</bitWidth>
          </field>
          <field>
            <name>FB7</name>
            <bitOffset>7</bitOffset>
            <bitWidth>1</bitWidth>
          </field>
          <field>
            <name>FB8</name>
            <bitOffset>8</bitOffset>
            <bitWidth>1</bitWidth>
          </field>
          <field>
            <name>FB9</name>
            <bitOffset>9</bitOffset>
            <bitWidth>1</bitWidth>
          </field>
          <field>
            <name>FB10</name>
            <bitOffset>10</bitOffset>
            <bitWidth>1</bitWidth>
          </field>
          <field>
            <name>FB11</name>
            <bitOffset>11</bitOffset>
            <bitWidth>1</bitWidth>
          </field>
          <field>
            <name>FB12</name>
            <bitOffset>12</bitOffset>
            <bitWidth>1</bitWidth>
          </field>
          <field>
            <name>FB13</name>
            <bitOffset>13</bitOffset>
            <bitWidth>1</bitWidth>
          </field>
          <field>
            <name>FB14</name>
            <bitOffset>14</bitOffset>
            <bitWidth>1</bitWidth>
          </field>
          <field>
            <name>FB15</name>
            <bitOffset>15</bitOffset>
            <bitWidth>1</bitWidth>
          </field>
          <field>
            <name>FB16</name>
            <bitOffset>16</bitOffset>
            <bitWidth>1</bitWidth>
          </field>
          <field>
            <name>FB17</name>
            <bitOffset>17</bitOffset>
            <bitWidth>1</bitWidth>
          </field>
          <field>
            <name>FB18</name>
            <bitOffset>18</bitOffset>
            <bitWidth>1</bitWidth>
          </field>
          <field>
            <name>FB19</name>
            <bitOffset>19</bitOffset>
            <bitWidth>1</bitWidth>
          </field>
          <field>
            <name>FB20</name>
            <bitOffset>20</bitOffset>
            <bitWidth>1</bitWidth>
          </field>
          <field>
            <name>FB21</name>
            <bitOffset>21</bitOffset>
            <bitWidth>1</bitWidth>
          </field>
          <field>
            <name>FB22</name>
            <bitOffset>22</bitOffset>
            <bitWidth>1</bitWidth>
          </field>
          <field>
            <name>FB23</name>
            <bitOffset>23</bitOffset>
            <bitWidth>1</bitWidth>
          </field>
          <field>
            <name>FB24</name>
            <bitOffset>24</bitOffset>
            <bitWidth>1</bitWidth>
          </field>
          <field>
            <name>FB25</name>
            <bitOffset>25</bitOffset>
            <bitWidth>1</bitWidth>
          </field>
          <field>
            <name>FB26</name>
            <bitOffset>26</bitOffset>
            <bitWidth>1</bitWidth>
          </field>
          <field>
            <name>FB27</name>
            <bitOffset>27</bitOffset>
            <bitWidth>1</bitWidth>
          </field>
          <field>
            <name>FB28</name>
            <bitOffset>28</bitOffset>
            <bitWidth>1</bitWidth>
          </field>
          <field>
            <name>FB29</name>
            <bitOffset>29</bitOffset>
            <bitWidth>1</bitWidth>
          </field>
          <field>
            <name>FB30</name>
            <bitOffset>30</bitOffset>
            <bitWidth>1</bitWidth>
          </field>
          <field>
            <name>FB31</name>
            <bitOffset>31</bitOffset>
            <bitWidth>1</bitWidth>
          </field>
        </fields>
      </register>
      <register>
        <name>sFilterRegister.11.FR1</name>
        <addressOffset>0x298</addressOffset>
        <size>0x20</size>
        <fields>
          <field>
            <name>FB0</name>
            <bitOffset>0</bitOffset>
            <bitWidth>1</bitWidth>
          </field>
          <field>
            <name>FB1</name>
            <bitOffset>1</bitOffset>
            <bitWidth>1</bitWidth>
          </field>
          <field>
            <name>FB2</name>
            <bitOffset>2</bitOffset>
            <bitWidth>1</bitWidth>
          </field>
          <field>
            <name>FB3</name>
            <bitOffset>3</bitOffset>
            <bitWidth>1</bitWidth>
          </field>
          <field>
            <name>FB4</name>
            <bitOffset>4</bitOffset>
            <bitWidth>1</bitWidth>
          </field>
          <field>
            <name>FB5</name>
            <bitOffset>5</bitOffset>
            <bitWidth>1</bitWidth>
          </field>
          <field>
            <name>FB6</name>
            <bitOffset>6</bitOffset>
            <bitWidth>1</bitWidth>
          </field>
          <field>
            <name>FB7</name>
            <bitOffset>7</bitOffset>
            <bitWidth>1</bitWidth>
          </field>
          <field>
            <name>FB8</name>
            <bitOffset>8</bitOffset>
            <bitWidth>1</bitWidth>
          </field>
          <field>
            <name>FB9</name>
            <bitOffset>9</bitOffset>
            <bitWidth>1</bitWidth>
          </field>
          <field>
            <name>FB10</name>
            <bitOffset>10</bitOffset>
            <bitWidth>1</bitWidth>
          </field>
          <field>
            <name>FB11</name>
            <bitOffset>11</bitOffset>
            <bitWidth>1</bitWidth>
          </field>
          <field>
            <name>FB12</name>
            <bitOffset>12</bitOffset>
            <bitWidth>1</bitWidth>
          </field>
          <field>
            <name>FB13</name>
            <bitOffset>13</bitOffset>
            <bitWidth>1</bitWidth>
          </field>
          <field>
            <name>FB14</name>
            <bitOffset>14</bitOffset>
            <bitWidth>1</bitWidth>
          </field>
          <field>
            <name>FB15</name>
            <bitOffset>15</bitOffset>
            <bitWidth>1</bitWidth>
          </field>
          <field>
            <name>FB16</name>
            <bitOffset>16</bitOffset>
            <bitWidth>1</bitWidth>
          </field>
          <field>
            <name>FB17</name>
            <bitOffset>17</bitOffset>
            <bitWidth>1</bitWidth>
          </field>
          <field>
            <name>FB18</name>
            <bitOffset>18</bitOffset>
            <bitWidth>1</bitWidth>
          </field>
          <field>
            <name>FB19</name>
            <bitOffset>19</bitOffset>
            <bitWidth>1</bitWidth>
          </field>
          <field>
            <name>FB20</name>
            <bitOffset>20</bitOffset>
            <bitWidth>1</bitWidth>
          </field>
          <field>
            <name>FB21</name>
            <bitOffset>21</bitOffset>
            <bitWidth>1</bitWidth>
          </field>
          <field>
            <name>FB22</name>
            <bitOffset>22</bitOffset>
            <bitWidth>1</bitWidth>
          </field>
          <field>
            <name>FB23</name>
            <bitOffset>23</bitOffset>
            <bitWidth>1</bitWidth>
          </field>
          <field>
            <name>FB24</name>
            <bitOffset>24</bitOffset>
            <bitWidth>1</bitWidth>
          </field>
          <field>
            <name>FB25</name>
            <bitOffset>25</bitOffset>
            <bitWidth>1</bitWidth>
          </field>
          <field>
            <name>FB26</name>
            <bitOffset>26</bitOffset>
            <bitWidth>1</bitWidth>
          </field>
          <field>
            <name>FB27</name>
            <bitOffset>27</bitOffset>
            <bitWidth>1</bitWidth>
          </field>
          <field>
            <name>FB28</name>
            <bitOffset>28</bitOffset>
            <bitWidth>1</bitWidth>
          </field>
          <field>
            <name>FB29</name>
            <bitOffset>29</bitOffset>
            <bitWidth>1</bitWidth>
          </field>
          <field>
            <name>FB30</name>
            <bitOffset>30</bitOffset>
            <bitWidth>1</bitWidth>
          </field>
          <field>
            <name>FB31</name>
            <bitOffset>31</bitOffset>
            <bitWidth>1</bitWidth>
          </field>
        </fields>
      </register>
      <register>
        <name>sFilterRegister.11.FR2</name>
        <addressOffset>0x29c</addressOffset>
        <size>0x20</size>
        <fields>
          <field>
            <name>FB0</name>
            <bitOffset>0</bitOffset>
            <bitWidth>1</bitWidth>
          </field>
          <field>
            <name>FB1</name>
            <bitOffset>1</bitOffset>
            <bitWidth>1</bitWidth>
          </field>
          <field>
            <name>FB2</name>
            <bitOffset>2</bitOffset>
            <bitWidth>1</bitWidth>
          </field>
          <field>
            <name>FB3</name>
            <bitOffset>3</bitOffset>
            <bitWidth>1</bitWidth>
          </field>
          <field>
            <name>FB4</name>
            <bitOffset>4</bitOffset>
            <bitWidth>1</bitWidth>
          </field>
          <field>
            <name>FB5</name>
            <bitOffset>5</bitOffset>
            <bitWidth>1</bitWidth>
          </field>
          <field>
            <name>FB6</name>
            <bitOffset>6</bitOffset>
            <bitWidth>1</bitWidth>
          </field>
          <field>
            <name>FB7</name>
            <bitOffset>7</bitOffset>
            <bitWidth>1</bitWidth>
          </field>
          <field>
            <name>FB8</name>
            <bitOffset>8</bitOffset>
            <bitWidth>1</bitWidth>
          </field>
          <field>
            <name>FB9</name>
            <bitOffset>9</bitOffset>
            <bitWidth>1</bitWidth>
          </field>
          <field>
            <name>FB10</name>
            <bitOffset>10</bitOffset>
            <bitWidth>1</bitWidth>
          </field>
          <field>
            <name>FB11</name>
            <bitOffset>11</bitOffset>
            <bitWidth>1</bitWidth>
          </field>
          <field>
            <name>FB12</name>
            <bitOffset>12</bitOffset>
            <bitWidth>1</bitWidth>
          </field>
          <field>
            <name>FB13</name>
            <bitOffset>13</bitOffset>
            <bitWidth>1</bitWidth>
          </field>
          <field>
            <name>FB14</name>
            <bitOffset>14</bitOffset>
            <bitWidth>1</bitWidth>
          </field>
          <field>
            <name>FB15</name>
            <bitOffset>15</bitOffset>
            <bitWidth>1</bitWidth>
          </field>
          <field>
            <name>FB16</name>
            <bitOffset>16</bitOffset>
            <bitWidth>1</bitWidth>
          </field>
          <field>
            <name>FB17</name>
            <bitOffset>17</bitOffset>
            <bitWidth>1</bitWidth>
          </field>
          <field>
            <name>FB18</name>
            <bitOffset>18</bitOffset>
            <bitWidth>1</bitWidth>
          </field>
          <field>
            <name>FB19</name>
            <bitOffset>19</bitOffset>
            <bitWidth>1</bitWidth>
          </field>
          <field>
            <name>FB20</name>
            <bitOffset>20</bitOffset>
            <bitWidth>1</bitWidth>
          </field>
          <field>
            <name>FB21</name>
            <bitOffset>21</bitOffset>
            <bitWidth>1</bitWidth>
          </field>
          <field>
            <name>FB22</name>
            <bitOffset>22</bitOffset>
            <bitWidth>1</bitWidth>
          </field>
          <field>
            <name>FB23</name>
            <bitOffset>23</bitOffset>
            <bitWidth>1</bitWidth>
          </field>
          <field>
            <name>FB24</name>
            <bitOffset>24</bitOffset>
            <bitWidth>1</bitWidth>
          </field>
          <field>
            <name>FB25</name>
            <bitOffset>25</bitOffset>
            <bitWidth>1</bitWidth>
          </field>
          <field>
            <name>FB26</name>
            <bitOffset>26</bitOffset>
            <bitWidth>1</bitWidth>
          </field>
          <field>
            <name>FB27</name>
            <bitOffset>27</bitOffset>
            <bitWidth>1</bitWidth>
          </field>
          <field>
            <name>FB28</name>
            <bitOffset>28</bitOffset>
            <bitWidth>1</bitWidth>
          </field>
          <field>
            <name>FB29</name>
            <bitOffset>29</bitOffset>
            <bitWidth>1</bitWidth>
          </field>
          <field>
            <name>FB30</name>
            <bitOffset>30</bitOffset>
            <bitWidth>1</bitWidth>
          </field>
          <field>
            <name>FB31</name>
            <bitOffset>31</bitOffset>
            <bitWidth>1</bitWidth>
          </field>
        </fields>
      </register>
      <register>
        <name>sFilterRegister.12.FR1</name>
        <addressOffset>0x2a0</addressOffset>
        <size>0x20</size>
        <fields>
          <field>
            <name>FB0</name>
            <bitOffset>0</bitOffset>
            <bitWidth>1</bitWidth>
          </field>
          <field>
            <name>FB1</name>
            <bitOffset>1</bitOffset>
            <bitWidth>1</bitWidth>
          </field>
          <field>
            <name>FB2</name>
            <bitOffset>2</bitOffset>
            <bitWidth>1</bitWidth>
          </field>
          <field>
            <name>FB3</name>
            <bitOffset>3</bitOffset>
            <bitWidth>1</bitWidth>
          </field>
          <field>
            <name>FB4</name>
            <bitOffset>4</bitOffset>
            <bitWidth>1</bitWidth>
          </field>
          <field>
            <name>FB5</name>
            <bitOffset>5</bitOffset>
            <bitWidth>1</bitWidth>
          </field>
          <field>
            <name>FB6</name>
            <bitOffset>6</bitOffset>
            <bitWidth>1</bitWidth>
          </field>
          <field>
            <name>FB7</name>
            <bitOffset>7</bitOffset>
            <bitWidth>1</bitWidth>
          </field>
          <field>
            <name>FB8</name>
            <bitOffset>8</bitOffset>
            <bitWidth>1</bitWidth>
          </field>
          <field>
            <name>FB9</name>
            <bitOffset>9</bitOffset>
            <bitWidth>1</bitWidth>
          </field>
          <field>
            <name>FB10</name>
            <bitOffset>10</bitOffset>
            <bitWidth>1</bitWidth>
          </field>
          <field>
            <name>FB11</name>
            <bitOffset>11</bitOffset>
            <bitWidth>1</bitWidth>
          </field>
          <field>
            <name>FB12</name>
            <bitOffset>12</bitOffset>
            <bitWidth>1</bitWidth>
          </field>
          <field>
            <name>FB13</name>
            <bitOffset>13</bitOffset>
            <bitWidth>1</bitWidth>
          </field>
          <field>
            <name>FB14</name>
            <bitOffset>14</bitOffset>
            <bitWidth>1</bitWidth>
          </field>
          <field>
            <name>FB15</name>
            <bitOffset>15</bitOffset>
            <bitWidth>1</bitWidth>
          </field>
          <field>
            <name>FB16</name>
            <bitOffset>16</bitOffset>
            <bitWidth>1</bitWidth>
          </field>
          <field>
            <name>FB17</name>
            <bitOffset>17</bitOffset>
            <bitWidth>1</bitWidth>
          </field>
          <field>
            <name>FB18</name>
            <bitOffset>18</bitOffset>
            <bitWidth>1</bitWidth>
          </field>
          <field>
            <name>FB19</name>
            <bitOffset>19</bitOffset>
            <bitWidth>1</bitWidth>
          </field>
          <field>
            <name>FB20</name>
            <bitOffset>20</bitOffset>
            <bitWidth>1</bitWidth>
          </field>
          <field>
            <name>FB21</name>
            <bitOffset>21</bitOffset>
            <bitWidth>1</bitWidth>
          </field>
          <field>
            <name>FB22</name>
            <bitOffset>22</bitOffset>
            <bitWidth>1</bitWidth>
          </field>
          <field>
            <name>FB23</name>
            <bitOffset>23</bitOffset>
            <bitWidth>1</bitWidth>
          </field>
          <field>
            <name>FB24</name>
            <bitOffset>24</bitOffset>
            <bitWidth>1</bitWidth>
          </field>
          <field>
            <name>FB25</name>
            <bitOffset>25</bitOffset>
            <bitWidth>1</bitWidth>
          </field>
          <field>
            <name>FB26</name>
            <bitOffset>26</bitOffset>
            <bitWidth>1</bitWidth>
          </field>
          <field>
            <name>FB27</name>
            <bitOffset>27</bitOffset>
            <bitWidth>1</bitWidth>
          </field>
          <field>
            <name>FB28</name>
            <bitOffset>28</bitOffset>
            <bitWidth>1</bitWidth>
          </field>
          <field>
            <name>FB29</name>
            <bitOffset>29</bitOffset>
            <bitWidth>1</bitWidth>
          </field>
          <field>
            <name>FB30</name>
            <bitOffset>30</bitOffset>
            <bitWidth>1</bitWidth>
          </field>
          <field>
            <name>FB31</name>
            <bitOffset>31</bitOffset>
            <bitWidth>1</bitWidth>
          </field>
        </fields>
      </register>
      <register>
        <name>sFilterRegister.12.FR2</name>
        <addressOffset>0x2a4</addressOffset>
        <size>0x20</size>
        <fields>
          <field>
            <name>FB0</name>
            <bitOffset>0</bitOffset>
            <bitWidth>1</bitWidth>
          </field>
          <field>
            <name>FB1</name>
            <bitOffset>1</bitOffset>
            <bitWidth>1</bitWidth>
          </field>
          <field>
            <name>FB2</name>
            <bitOffset>2</bitOffset>
            <bitWidth>1</bitWidth>
          </field>
          <field>
            <name>FB3</name>
            <bitOffset>3</bitOffset>
            <bitWidth>1</bitWidth>
          </field>
          <field>
            <name>FB4</name>
            <bitOffset>4</bitOffset>
            <bitWidth>1</bitWidth>
          </field>
          <field>
            <name>FB5</name>
            <bitOffset>5</bitOffset>
            <bitWidth>1</bitWidth>
          </field>
          <field>
            <name>FB6</name>
            <bitOffset>6</bitOffset>
            <bitWidth>1</bitWidth>
          </field>
          <field>
            <name>FB7</name>
            <bitOffset>7</bitOffset>
            <bitWidth>1</bitWidth>
          </field>
          <field>
            <name>FB8</name>
            <bitOffset>8</bitOffset>
            <bitWidth>1</bitWidth>
          </field>
          <field>
            <name>FB9</name>
            <bitOffset>9</bitOffset>
            <bitWidth>1</bitWidth>
          </field>
          <field>
            <name>FB10</name>
            <bitOffset>10</bitOffset>
            <bitWidth>1</bitWidth>
          </field>
          <field>
            <name>FB11</name>
            <bitOffset>11</bitOffset>
            <bitWidth>1</bitWidth>
          </field>
          <field>
            <name>FB12</name>
            <bitOffset>12</bitOffset>
            <bitWidth>1</bitWidth>
          </field>
          <field>
            <name>FB13</name>
            <bitOffset>13</bitOffset>
            <bitWidth>1</bitWidth>
          </field>
          <field>
            <name>FB14</name>
            <bitOffset>14</bitOffset>
            <bitWidth>1</bitWidth>
          </field>
          <field>
            <name>FB15</name>
            <bitOffset>15</bitOffset>
            <bitWidth>1</bitWidth>
          </field>
          <field>
            <name>FB16</name>
            <bitOffset>16</bitOffset>
            <bitWidth>1</bitWidth>
          </field>
          <field>
            <name>FB17</name>
            <bitOffset>17</bitOffset>
            <bitWidth>1</bitWidth>
          </field>
          <field>
            <name>FB18</name>
            <bitOffset>18</bitOffset>
            <bitWidth>1</bitWidth>
          </field>
          <field>
            <name>FB19</name>
            <bitOffset>19</bitOffset>
            <bitWidth>1</bitWidth>
          </field>
          <field>
            <name>FB20</name>
            <bitOffset>20</bitOffset>
            <bitWidth>1</bitWidth>
          </field>
          <field>
            <name>FB21</name>
            <bitOffset>21</bitOffset>
            <bitWidth>1</bitWidth>
          </field>
          <field>
            <name>FB22</name>
            <bitOffset>22</bitOffset>
            <bitWidth>1</bitWidth>
          </field>
          <field>
            <name>FB23</name>
            <bitOffset>23</bitOffset>
            <bitWidth>1</bitWidth>
          </field>
          <field>
            <name>FB24</name>
            <bitOffset>24</bitOffset>
            <bitWidth>1</bitWidth>
          </field>
          <field>
            <name>FB25</name>
            <bitOffset>25</bitOffset>
            <bitWidth>1</bitWidth>
          </field>
          <field>
            <name>FB26</name>
            <bitOffset>26</bitOffset>
            <bitWidth>1</bitWidth>
          </field>
          <field>
            <name>FB27</name>
            <bitOffset>27</bitOffset>
            <bitWidth>1</bitWidth>
          </field>
          <field>
            <name>FB28</name>
            <bitOffset>28</bitOffset>
            <bitWidth>1</bitWidth>
          </field>
          <field>
            <name>FB29</name>
            <bitOffset>29</bitOffset>
            <bitWidth>1</bitWidth>
          </field>
          <field>
            <name>FB30</name>
            <bitOffset>30</bitOffset>
            <bitWidth>1</bitWidth>
          </field>
          <field>
            <name>FB31</name>
            <bitOffset>31</bitOffset>
            <bitWidth>1</bitWidth>
          </field>
        </fields>
      </register>
      <register>
        <name>sFilterRegister.13.FR1</name>
        <addressOffset>0x2a8</addressOffset>
        <size>0x20</size>
        <fields>
          <field>
            <name>FB0</name>
            <bitOffset>0</bitOffset>
            <bitWidth>1</bitWidth>
          </field>
          <field>
            <name>FB1</name>
            <bitOffset>1</bitOffset>
            <bitWidth>1</bitWidth>
          </field>
          <field>
            <name>FB2</name>
            <bitOffset>2</bitOffset>
            <bitWidth>1</bitWidth>
          </field>
          <field>
            <name>FB3</name>
            <bitOffset>3</bitOffset>
            <bitWidth>1</bitWidth>
          </field>
          <field>
            <name>FB4</name>
            <bitOffset>4</bitOffset>
            <bitWidth>1</bitWidth>
          </field>
          <field>
            <name>FB5</name>
            <bitOffset>5</bitOffset>
            <bitWidth>1</bitWidth>
          </field>
          <field>
            <name>FB6</name>
            <bitOffset>6</bitOffset>
            <bitWidth>1</bitWidth>
          </field>
          <field>
            <name>FB7</name>
            <bitOffset>7</bitOffset>
            <bitWidth>1</bitWidth>
          </field>
          <field>
            <name>FB8</name>
            <bitOffset>8</bitOffset>
            <bitWidth>1</bitWidth>
          </field>
          <field>
            <name>FB9</name>
            <bitOffset>9</bitOffset>
            <bitWidth>1</bitWidth>
          </field>
          <field>
            <name>FB10</name>
            <bitOffset>10</bitOffset>
            <bitWidth>1</bitWidth>
          </field>
          <field>
            <name>FB11</name>
            <bitOffset>11</bitOffset>
            <bitWidth>1</bitWidth>
          </field>
          <field>
            <name>FB12</name>
            <bitOffset>12</bitOffset>
            <bitWidth>1</bitWidth>
          </field>
          <field>
            <name>FB13</name>
            <bitOffset>13</bitOffset>
            <bitWidth>1</bitWidth>
          </field>
          <field>
            <name>FB14</name>
            <bitOffset>14</bitOffset>
            <bitWidth>1</bitWidth>
          </field>
          <field>
            <name>FB15</name>
            <bitOffset>15</bitOffset>
            <bitWidth>1</bitWidth>
          </field>
          <field>
            <name>FB16</name>
            <bitOffset>16</bitOffset>
            <bitWidth>1</bitWidth>
          </field>
          <field>
            <name>FB17</name>
            <bitOffset>17</bitOffset>
            <bitWidth>1</bitWidth>
          </field>
          <field>
            <name>FB18</name>
            <bitOffset>18</bitOffset>
            <bitWidth>1</bitWidth>
          </field>
          <field>
            <name>FB19</name>
            <bitOffset>19</bitOffset>
            <bitWidth>1</bitWidth>
          </field>
          <field>
            <name>FB20</name>
            <bitOffset>20</bitOffset>
            <bitWidth>1</bitWidth>
          </field>
          <field>
            <name>FB21</name>
            <bitOffset>21</bitOffset>
            <bitWidth>1</bitWidth>
          </field>
          <field>
            <name>FB22</name>
            <bitOffset>22</bitOffset>
            <bitWidth>1</bitWidth>
          </field>
          <field>
            <name>FB23</name>
            <bitOffset>23</bitOffset>
            <bitWidth>1</bitWidth>
          </field>
          <field>
            <name>FB24</name>
            <bitOffset>24</bitOffset>
            <bitWidth>1</bitWidth>
          </field>
          <field>
            <name>FB25</name>
            <bitOffset>25</bitOffset>
            <bitWidth>1</bitWidth>
          </field>
          <field>
            <name>FB26</name>
            <bitOffset>26</bitOffset>
            <bitWidth>1</bitWidth>
          </field>
          <field>
            <name>FB27</name>
            <bitOffset>27</bitOffset>
            <bitWidth>1</bitWidth>
          </field>
          <field>
            <name>FB28</name>
            <bitOffset>28</bitOffset>
            <bitWidth>1</bitWidth>
          </field>
          <field>
            <name>FB29</name>
            <bitOffset>29</bitOffset>
            <bitWidth>1</bitWidth>
          </field>
          <field>
            <name>FB30</name>
            <bitOffset>30</bitOffset>
            <bitWidth>1</bitWidth>
          </field>
          <field>
            <name>FB31</name>
            <bitOffset>31</bitOffset>
            <bitWidth>1</bitWidth>
          </field>
        </fields>
      </register>
      <register>
        <name>sFilterRegister.13.FR2</name>
        <addressOffset>0x2ac</addressOffset>
        <size>0x20</size>
        <fields>
          <field>
            <name>FB0</name>
            <bitOffset>0</bitOffset>
            <bitWidth>1</bitWidth>
          </field>
          <field>
            <name>FB1</name>
            <bitOffset>1</bitOffset>
            <bitWidth>1</bitWidth>
          </field>
          <field>
            <name>FB2</name>
            <bitOffset>2</bitOffset>
            <bitWidth>1</bitWidth>
          </field>
          <field>
            <name>FB3</name>
            <bitOffset>3</bitOffset>
            <bitWidth>1</bitWidth>
          </field>
          <field>
            <name>FB4</name>
            <bitOffset>4</bitOffset>
            <bitWidth>1</bitWidth>
          </field>
          <field>
            <name>FB5</name>
            <bitOffset>5</bitOffset>
            <bitWidth>1</bitWidth>
          </field>
          <field>
            <name>FB6</name>
            <bitOffset>6</bitOffset>
            <bitWidth>1</bitWidth>
          </field>
          <field>
            <name>FB7</name>
            <bitOffset>7</bitOffset>
            <bitWidth>1</bitWidth>
          </field>
          <field>
            <name>FB8</name>
            <bitOffset>8</bitOffset>
            <bitWidth>1</bitWidth>
          </field>
          <field>
            <name>FB9</name>
            <bitOffset>9</bitOffset>
            <bitWidth>1</bitWidth>
          </field>
          <field>
            <name>FB10</name>
            <bitOffset>10</bitOffset>
            <bitWidth>1</bitWidth>
          </field>
          <field>
            <name>FB11</name>
            <bitOffset>11</bitOffset>
            <bitWidth>1</bitWidth>
          </field>
          <field>
            <name>FB12</name>
            <bitOffset>12</bitOffset>
            <bitWidth>1</bitWidth>
          </field>
          <field>
            <name>FB13</name>
            <bitOffset>13</bitOffset>
            <bitWidth>1</bitWidth>
          </field>
          <field>
            <name>FB14</name>
            <bitOffset>14</bitOffset>
            <bitWidth>1</bitWidth>
          </field>
          <field>
            <name>FB15</name>
            <bitOffset>15</bitOffset>
            <bitWidth>1</bitWidth>
          </field>
          <field>
            <name>FB16</name>
            <bitOffset>16</bitOffset>
            <bitWidth>1</bitWidth>
          </field>
          <field>
            <name>FB17</name>
            <bitOffset>17</bitOffset>
            <bitWidth>1</bitWidth>
          </field>
          <field>
            <name>FB18</name>
            <bitOffset>18</bitOffset>
            <bitWidth>1</bitWidth>
          </field>
          <field>
            <name>FB19</name>
            <bitOffset>19</bitOffset>
            <bitWidth>1</bitWidth>
          </field>
          <field>
            <name>FB20</name>
            <bitOffset>20</bitOffset>
            <bitWidth>1</bitWidth>
          </field>
          <field>
            <name>FB21</name>
            <bitOffset>21</bitOffset>
            <bitWidth>1</bitWidth>
          </field>
          <field>
            <name>FB22</name>
            <bitOffset>22</bitOffset>
            <bitWidth>1</bitWidth>
          </field>
          <field>
            <name>FB23</name>
            <bitOffset>23</bitOffset>
            <bitWidth>1</bitWidth>
          </field>
          <field>
            <name>FB24</name>
            <bitOffset>24</bitOffset>
            <bitWidth>1</bitWidth>
          </field>
          <field>
            <name>FB25</name>
            <bitOffset>25</bitOffset>
            <bitWidth>1</bitWidth>
          </field>
          <field>
            <name>FB26</name>
            <bitOffset>26</bitOffset>
            <bitWidth>1</bitWidth>
          </field>
          <field>
            <name>FB27</name>
            <bitOffset>27</bitOffset>
            <bitWidth>1</bitWidth>
          </field>
          <field>
            <name>FB28</name>
            <bitOffset>28</bitOffset>
            <bitWidth>1</bitWidth>
          </field>
          <field>
            <name>FB29</name>
            <bitOffset>29</bitOffset>
            <bitWidth>1</bitWidth>
          </field>
          <field>
            <name>FB30</name>
            <bitOffset>30</bitOffset>
            <bitWidth>1</bitWidth>
          </field>
          <field>
            <name>FB31</name>
            <bitOffset>31</bitOffset>
            <bitWidth>1</bitWidth>
          </field>
        </fields>
      </register>
      <register>
        <name>sFilterRegister.14.FR1</name>
        <addressOffset>0x2b0</addressOffset>
        <size>0x20</size>
      </register>
      <register>
        <name>sFilterRegister.14.FR2</name>
        <addressOffset>0x2b4</addressOffset>
        <size>0x20</size>
      </register>
      <register>
        <name>sFilterRegister.15.FR1</name>
        <addressOffset>0x2b8</addressOffset>
        <size>0x20</size>
      </register>
      <register>
        <name>sFilterRegister.15.FR2</name>
        <addressOffset>0x2bc</addressOffset>
        <size>0x20</size>
      </register>
      <register>
        <name>sFilterRegister.16.FR1</name>
        <addressOffset>0x2c0</addressOffset>
        <size>0x20</size>
      </register>
      <register>
        <name>sFilterRegister.16.FR2</name>
        <addressOffset>0x2c4</addressOffset>
        <size>0x20</size>
      </register>
      <register>
        <name>sFilterRegister.17.FR1</name>
        <addressOffset>0x2c8</addressOffset>
        <size>0x20</size>
      </register>
      <register>
        <name>sFilterRegister.17.FR2</name>
        <addressOffset>0x2cc</addressOffset>
        <size>0x20</size>
      </register>
      <register>
        <name>sFilterRegister.18.FR1</name>
        <addressOffset>0x2d0</addressOffset>
        <size>0x20</size>
      </register>
      <register>
        <name>sFilterRegister.18.FR2</name>
        <addressOffset>0x2d4</addressOffset>
        <size>0x20</size>
      </register>
      <register>
        <name>sFilterRegister.19.FR1</name>
        <addressOffset>0x2d8</addressOffset>
        <size>0x20</size>
      </register>
      <register>
        <name>sFilterRegister.19.FR2</name>
        <addressOffset>0x2dc</addressOffset>
        <size>0x20</size>
      </register>
      <register>
        <name>sFilterRegister.20.FR1</name>
        <addressOffset>0x2e0</addressOffset>
        <size>0x20</size>
      </register>
      <register>
        <name>sFilterRegister.20.FR2</name>
        <addressOffset>0x2e4</addressOffset>
        <size>0x20</size>
      </register>
      <register>
        <name>sFilterRegister.21.FR1</name>
        <addressOffset>0x2e8</addressOffset>
        <size>0x20</size>
      </register>
      <register>
        <name>sFilterRegister.21.FR2</name>
        <addressOffset>0x2ec</addressOffset>
        <size>0x20</size>
      </register>
      <register>
        <name>sFilterRegister.22.FR1</name>
        <addressOffset>0x2f0</addressOffset>
        <size>0x20</size>
      </register>
      <register>
        <name>sFilterRegister.22.FR2</name>
        <addressOffset>0x2f4</addressOffset>
        <size>0x20</size>
      </register>
      <register>
        <name>sFilterRegister.23.FR1</name>
        <addressOffset>0x2f8</addressOffset>
        <size>0x20</size>
      </register>
      <register>
        <name>sFilterRegister.23.FR2</name>
        <addressOffset>0x2fc</addressOffset>
        <size>0x20</size>
      </register>
      <register>
        <name>sFilterRegister.24.FR1</name>
        <addressOffset>0x300</addressOffset>
        <size>0x20</size>
      </register>
      <register>
        <name>sFilterRegister.24.FR2</name>
        <addressOffset>0x304</addressOffset>
        <size>0x20</size>
      </register>
      <register>
        <name>sFilterRegister.25.FR1</name>
        <addressOffset>0x308</addressOffset>
        <size>0x20</size>
      </register>
      <register>
        <name>sFilterRegister.25.FR2</name>
        <addressOffset>0x30c</addressOffset>
        <size>0x20</size>
      </register>
      <register>
        <name>sFilterRegister.26.FR1</name>
        <addressOffset>0x310</addressOffset>
        <size>0x20</size>
      </register>
      <register>
        <name>sFilterRegister.26.FR2</name>
        <addressOffset>0x314</addressOffset>
        <size>0x20</size>
      </register>
      <register>
        <name>sFilterRegister.27.FR1</name>
        <addressOffset>0x318</addressOffset>
        <size>0x20</size>
      </register>
      <register>
        <name>sFilterRegister.27.FR2</name>
        <addressOffset>0x31c</addressOffset>
        <size>0x20</size>
      </register>
    </peripheral>
    <peripheral>
      <name>CAN2</name>
      <baseAddress>0x40006800</baseAddress>
      <register>
        <name>MCR</name>
        <addressOffset>0x0</addressOffset>
        <size>0x20</size>
        <fields>
          <field>
            <name>INRQ</name>
            <bitOffset>0</bitOffset>
            <bitWidth>1</bitWidth>
          </field>
          <field>
            <name>SLEEP</name>
            <bitOffset>1</bitOffset>
            <bitWidth>1</bitWidth>
          </field>
          <field>
            <name>TXFP</name>
            <bitOffset>2</bitOffset>
            <bitWidth>1</bitWidth>
          </field>
          <field>
            <name>RFLM</name>
            <bitOffset>3</bitOffset>
            <bitWidth>1</bitWidth>
          </field>
          <field>
            <name>NART</name>
            <bitOffset>4</bitOffset>
            <bitWidth>1</bitWidth>
          </field>
          <field>
            <name>AWUM</name>
            <bitOffset>5</bitOffset>
            <bitWidth>1</bitWidth>
          </field>
          <field>
            <name>ABOM</name>
            <bitOffset>6</bitOffset>
            <bitWidth>1</bitWidth>
          </field>
          <field>
            <name>TTCM</name>
            <bitOffset>7</bitOffset>
            <bitWidth>1</bitWidth>
          </field>
          <field>
            <name>RESET</name>
            <bitOffset>15</bitOffset>
            <bitWidth>1</bitWidth>
          </field>
          <field>
            <name>DBF</name>
            <bitOffset>16</bitOffset>
            <bitWidth>1</bitWidth>
          </field>
        </fields>
      </register>
      <register>
        <name>MSR</name>
        <addressOffset>0x4</addressOffset>
        <size>0x20</size>
        <fields>
          <field>
            <name>INAK</name>
            <bitOffset>0</bitOffset>
            <bitWidth>1</bitWidth>
          </field>
          <field>
            <name>SLAK</name>
            <bitOffset>1</bitOffset>
            <bitWidth>1</bitWidth>
          </field>
          <field>
            <name>ERRI</name>
            <bitOffset>2</bitOffset>
            <bitWidth>1</bitWidth>
          </field>
          <field>
            <name>WKUI</name>
            <bitOffset>3</bitOffset>
            <bitWidth>1</bitWidth>
          </field>
          <field>
            <name>SLAKI</name>
            <bitOffset>4</bitOffset>
            <bitWidth>1</bitWidth>
          </field>
          <field>
            <name>TXM</name>
            <bitOffset>8</bitOffset>
            <bitWidth>1</bitWidth>
          </field>
          <field>
            <name>RXM</name>
            <bitOffset>9</bitOffset>
            <bitWidth>1</bitWidth>
          </field>
          <field>
            <name>SAMP</name>
            <bitOffset>10</bitOffset>
            <bitWidth>1</bitWidth>
          </field>
          <field>
            <name>RX</name>
            <bitOffset>11</bitOffset>
            <bitWidth>1</bitWidth>
          </field>
        </fields>
      </register>
      <register>
        <name>TSR</name>
        <addressOffset>0x8</addressOffset>
        <size>0x20</size>
        <fields>
          <field>
            <name>RQCP0</name>
            <bitOffset>0</bitOffset>
            <bitWidth>1</bitWidth>
          </field>
          <field>
            <name>TXOK0</name>
            <bitOffset>1</bitOffset>
            <bitWidth>1</bitWidth>
          </field>
          <field>
            <name>ALST0</name>
            <bitOffset>2</bitOffset>
            <bitWidth>1</bitWidth>
          </field>
          <field>
            <name>TERR0</name>
            <bitOffset>3</bitOffset>
            <bitWidth>1</bitWidth>
          </field>
          <field>
            <name>ABRQ0</name>
            <bitOffset>7</bitOffset>
            <bitWidth>1</bitWidth>
          </field>
          <field>
            <name>RQCP1</name>
            <bitOffset>8</bitOffset>
            <bitWidth>1</bitWidth>
          </field>
          <field>
            <name>TXOK1</name>
            <bitOffset>9</bitOffset>
            <bitWidth>1</bitWidth>
          </field>
          <field>
            <name>ALST1</name>
            <bitOffset>10</bitOffset>
            <bitWidth>1</bitWidth>
          </field>
          <field>
            <name>TERR1</name>
            <bitOffset>11</bitOffset>
            <bitWidth>1</bitWidth>
          </field>
          <field>
            <name>ABRQ1</name>
            <bitOffset>15</bitOffset>
            <bitWidth>1</bitWidth>
          </field>
          <field>
            <name>RQCP2</name>
            <bitOffset>16</bitOffset>
            <bitWidth>1</bitWidth>
          </field>
          <field>
            <name>TXOK2</name>
            <bitOffset>17</bitOffset>
            <bitWidth>1</bitWidth>
          </field>
          <field>
            <name>ALST2</name>
            <bitOffset>18</bitOffset>
            <bitWidth>1</bitWidth>
          </field>
          <field>
            <name>TERR2</name>
            <bitOffset>19</bitOffset>
            <bitWidth>1</bitWidth>
          </field>
          <field>
            <name>ABRQ2</name>
            <bitOffset>23</bitOffset>
            <bitWidth>1</bitWidth>
          </field>
          <field>
            <name>CODE</name>
            <bitOffset>24</bitOffset>
            <bitWidth>2</bitWidth>
          </field>
          <field>
            <name>TME0</name>
            <bitOffset>26</bitOffset>
            <bitWidth>1</bitWidth>
          </field>
          <field>
            <name>TME1</name>
            <bitOffset>27</bitOffset>
            <bitWidth>1</bitWidth>
          </field>
          <field>
            <name>TME2</name>
            <bitOffset>28</bitOffset>
            <bitWidth>1</bitWidth>
          </field>
          <field>
            <name>LOW0</name>
            <bitOffset>29</bitOffset>
            <bitWidth>1</bitWidth>
          </field>
          <field>
            <name>LOW1</name>
            <bitOffset>30</bitOffset>
            <bitWidth>1</bitWidth>
          </field>
          <field>
            <name>LOW2</name>
            <bitOffset>31</bitOffset>
            <bitWidth>1</bitWidth>
          </field>
        </fields>
      </register>
      <register>
        <name>RF0R</name>
        <addressOffset>0xc</addressOffset>
        <size>0x20</size>
        <fields>
          <field>
            <name>FMP0</name>
            <bitOffset>0</bitOffset>
            <bitWidth>2</bitWidth>
          </field>
          <field>
            <name>FULL0</name>
            <bitOffset>3</bitOffset>
            <bitWidth>1</bitWidth>
          </field>
          <field>
            <name>FOVR0</name>
            <bitOffset>4</bitOffset>
            <bitWidth>1</bitWidth>
          </field>
          <field>
            <name>RFOM0</name>
            <bitOffset>5</bitOffset>
            <bitWidth>1</bitWidth>
          </field>
        </fields>
      </register>
      <register>
        <name>RF1R</name>
        <addressOffset>0x10</addressOffset>
        <size>0x20</size>
        <fields>
          <field>
            <name>FMP1</name>
            <bitOffset>0</bitOffset>
            <bitWidth>2</bitWidth>
          </field>
          <field>
            <name>FULL1</name>
            <bitOffset>3</bitOffset>
            <bitWidth>1</bitWidth>
          </field>
          <field>
            <name>FOVR1</name>
            <bitOffset>4</bitOffset>
            <bitWidth>1</bitWidth>
          </field>
          <field>
            <name>RFOM1</name>
            <bitOffset>5</bitOffset>
            <bitWidth>1</bitWidth>
          </field>
        </fields>
      </register>
      <register>
        <name>IER</name>
        <addressOffset>0x14</addressOffset>
        <size>0x20</size>
        <fields>
          <field>
            <name>TMEIE</name>
            <bitOffset>0</bitOffset>
            <bitWidth>1</bitWidth>
          </field>
          <field>
            <name>FMPIE0</name>
            <bitOffset>1</bitOffset>
            <bitWidth>1</bitWidth>
          </field>
          <field>
            <name>FFIE0</name>
            <bitOffset>2</bitOffset>
            <bitWidth>1</bitWidth>
          </field>
          <field>
            <name>FOVIE0</name>
            <bitOffset>3</bitOffset>
            <bitWidth>1</bitWidth>
          </field>
          <field>
            <name>FMPIE1</name>
            <bitOffset>4</bitOffset>
            <bitWidth>1</bitWidth>
          </field>
          <field>
            <name>FFIE1</name>
            <bitOffset>5</bitOffset>
            <bitWidth>1</bitWidth>
          </field>
          <field>
            <name>FOVIE1</name>
            <bitOffset>6</bitOffset>
            <bitWidth>1</bitWidth>
          </field>
          <field>
            <name>EWGIE</name>
            <bitOffset>8</bitOffset>
            <bitWidth>1</bitWidth>
          </field>
          <field>
            <name>EPVIE</name>
            <bitOffset>9</bitOffset>
            <bitWidth>1</bitWidth>
          </field>
          <field>
            <name>BOFIE</name>
            <bitOffset>10</bitOffset>
            <bitWidth>1</bitWidth>
          </field>
          <field>
            <name>LECIE</name>
            <bitOffset>11</bitOffset>
            <bitWidth>1</bitWidth>
          </field>
          <field>
            <name>ERRIE</name>
            <bitOffset>15</bitOffset>
            <bitWidth>1</bitWidth>
          </field>
          <field>
            <name>WKUIE</name>
            <bitOffset>16</bitOffset>
            <bitWidth>1</bitWidth>
          </field>
          <field>
            <name>SLKIE</name>
            <bitOffset>17</bitOffset>
            <bitWidth>1</bitWidth>
          </field>
        </fields>
      </register>
      <register>
        <name>ESR</name>
        <addressOffset>0x18</addressOffset>
        <size>0x20</size>
        <fields>
          <field>
            <name>EWGF</name>
            <bitOffset>0</bitOffset>
            <bitWidth>1</bitWidth>
          </field>
          <field>
            <name>EPVF</name>
            <bitOffset>1</bitOffset>
            <bitWidth>1</bitWidth>
          </field>
          <field>
            <name>BOFF</name>
            <bitOffset>2</bitOffset>
            <bitWidth>1</bitWidth>
          </field>
          <field>
            <name>LEC</name>
            <bitOffset>4</bitOffset>
            <bitWidth>3</bitWidth>
          </field>
          <field>
            <name>TEC</name>
            <bitOffset>16</bitOffset>
            <bitWidth>8</bitWidth>
          </field>
          <field>
            <name>REC</name>
            <bitOffset>24</bitOffset>
            <bitWidth>8</bitWidth>
          </field>
        </fields>
      </register>
      <register>
        <name>BTR</name>
        <addressOffset>0x1c</addressOffset>
        <size>0x20</size>
        <fields>
          <field>
            <name>BRP</name>
            <bitOffset>0</bitOffset>
            <bitWidth>10</bitWidth>
          </field>
          <field>
            <name>TS1</name>
            <bitOffset>16</bitOffset>
            <bitWidth>4</bitWidth>
          </field>
          <field>
            <name>TS2</name>
            <bitOffset>20</bitOffset>
            <bitWidth>3</bitWidth>
          </field>
          <field>
            <name>SJW</name>
            <bitOffset>24</bitOffset>
            <bitWidth>2</bitWidth>
          </field>
          <field>
            <name>LBKM</name>
            <bitOffset>30</bitOffset>
            <bitWidth>1</bitWidth>
          </field>
          <field>
            <name>SILM</name>
            <bitOffset>31</bitOffset>
            <bitWidth>1</bitWidth>
          </field>
        </fields>
      </register>
      <register>
        <name>sTxMailBox.0.TIR</name>
        <addressOffset>0x180</addressOffset>
        <size>0x20</size>
        <fields>
          <field>
            <name>TXRQ</name>
            <bitOffset>0</bitOffset>
            <bitWidth>1</bitWidth>
          </field>
          <field>
            <name>RTR</name>
            <bitOffset>1</bitOffset>
            <bitWidth>1</bitWidth>
          </field>
          <field>
            <name>IDE</name>
            <bitOffset>2</bitOffset>
            <bitWidth>1</bitWidth>
          </field>
          <field>
            <name>EXID</name>
            <bitOffset>3</bitOffset>
            <bitWidth>18</bitWidth>
          </field>
          <field>
            <name>STID</name>
            <bitOffset>21</bitOffset>
            <bitWidth>11</bitWidth>
          </field>
        </fields>
      </register>
      <register>
        <name>sTxMailBox.0.TDTR</name>
        <addressOffset>0x184</addressOffset>
        <size>0x20</size>
        <fields>
          <field>
            <name>DLC</name>
            <bitOffset>0</bitOffset>
            <bitWidth>4</bitWidth>
          </field>
          <field>
            <name>TGT</name>
            <bitOffset>8</bitOffset>
            <bitWidth>1</bitWidth>
          </field>
          <field>
            <name>TIME</name>
            <bitOffset>16</bitOffset>
            <bitWidth>16</bitWidth>
          </field>
        </fields>
      </register>
      <register>
        <name>sTxMailBox.0.TDLR</name>
        <addressOffset>0x188</addressOffset>
        <size>0x20</size>
        <fields>
          <field>
            <name>DATA0</name>
            <bitOffset>0</bitOffset>
            <bitWidth>8</bitWidth>
          </field>
          <field>
            <name>DATA1</name>
            <bitOffset>8</bitOffset>
            <bitWidth>8</bitWidth>
          </field>
          <field>
            <name>DATA2</name>
            <bitOffset>16</bitOffset>
            <bitWidth>8</bitWidth>
          </field>
          <field>
            <name>DATA3</name>
            <bitOffset>24</bitOffset>
            <bitWidth>8</bitWidth>
          </field>
        </fields>
      </register>
      <register>
        <name>sTxMailBox.0.TDHR</name>
        <addressOffset>0x18c</addressOffset>
        <size>0x20</size>
        <fields>
          <field>
            <name>DATA4</name>
            <bitOffset>0</bitOffset>
            <bitWidth>8</bitWidth>
          </field>
          <field>
            <name>DATA5</name>
            <bitOffset>8</bitOffset>
            <bitWidth>8</bitWidth>
          </field>
          <field>
            <name>DATA6</name>
            <bitOffset>16</bitOffset>
            <bitWidth>8</bitWidth>
          </field>
          <field>
            <name>DATA7</name>
            <bitOffset>24</bitOffset>
            <bitWidth>8</bitWidth>
          </field>
        </fields>
      </register>
      <register>
        <name>sTxMailBox.1.TIR</name>
        <addressOffset>0x190</addressOffset>
        <size>0x20</size>
        <fields>
          <field>
            <name>TXRQ</name>
            <bitOffset>0</bitOffset>
            <bitWidth>1</bitWidth>
          </field>
          <field>
            <name>RTR</name>
            <bitOffset>1</bitOffset>
            <bitWidth>1</bitWidth>
          </field>
          <field>
            <name>IDE</name>
            <bitOffset>2</bitOffset>
            <bitWidth>1</bitWidth>
          </field>
          <field>
            <name>EXID</name>
            <bitOffset>3</bitOffset>
            <bitWidth>18</bitWidth>
          </field>
          <field>
            <name>STID</name>
            <bitOffset>21</bitOffset>
            <bitWidth>11</bitWidth>
          </field>
        </fields>
      </register>
      <register>
        <name>sTxMailBox.1.TDTR</name>
        <addressOffset>0x194</addressOffset>
        <size>0x20</size>
        <fields>
          <field>
            <name>DLC</name>
            <bitOffset>0</bitOffset>
            <bitWidth>4</bitWidth>
          </field>
          <field>
            <name>TGT</name>
            <bitOffset>8</bitOffset>
            <bitWidth>1</bitWidth>
          </field>
          <field>
            <name>TIME</name>
            <bitOffset>16</bitOffset>
            <bitWidth>16</bitWidth>
          </field>
        </fields>
      </register>
      <register>
        <name>sTxMailBox.1.TDLR</name>
        <addressOffset>0x198</addressOffset>
        <size>0x20</size>
        <fields>
          <field>
            <name>DATA0</name>
            <bitOffset>0</bitOffset>
            <bitWidth>8</bitWidth>
          </field>
          <field>
            <name>DATA1</name>
            <bitOffset>8</bitOffset>
            <bitWidth>8</bitWidth>
          </field>
          <field>
            <name>DATA2</name>
            <bitOffset>16</bitOffset>
            <bitWidth>8</bitWidth>
          </field>
          <field>
            <name>DATA3</name>
            <bitOffset>24</bitOffset>
            <bitWidth>8</bitWidth>
          </field>
        </fields>
      </register>
      <register>
        <name>sTxMailBox.1.TDHR</name>
        <addressOffset>0x19c</addressOffset>
        <size>0x20</size>
        <fields>
          <field>
            <name>DATA4</name>
            <bitOffset>0</bitOffset>
            <bitWidth>8</bitWidth>
          </field>
          <field>
            <name>DATA5</name>
            <bitOffset>8</bitOffset>
            <bitWidth>8</bitWidth>
          </field>
          <field>
            <name>DATA6</name>
            <bitOffset>16</bitOffset>
            <bitWidth>8</bitWidth>
          </field>
          <field>
            <name>DATA7</name>
            <bitOffset>24</bitOffset>
            <bitWidth>8</bitWidth>
          </field>
        </fields>
      </register>
      <register>
        <name>sTxMailBox.2.TIR</name>
        <addressOffset>0x1a0</addressOffset>
        <size>0x20</size>
        <fields>
          <field>
            <name>TXRQ</name>
            <bitOffset>0</bitOffset>
            <bitWidth>1</bitWidth>
          </field>
          <field>
            <name>RTR</name>
            <bitOffset>1</bitOffset>
            <bitWidth>1</bitWidth>
          </field>
          <field>
            <name>IDE</name>
            <bitOffset>2</bitOffset>
            <bitWidth>1</bitWidth>
          </field>
          <field>
            <name>EXID</name>
            <bitOffset>3</bitOffset>
            <bitWidth>18</bitWidth>
          </field>
          <field>
            <name>STID</name>
            <bitOffset>21</bitOffset>
            <bitWidth>11</bitWidth>
          </field>
        </fields>
      </register>
      <register>
        <name>sTxMailBox.2.TDTR</name>
        <addressOffset>0x1a4</addressOffset>
        <size>0x20</size>
        <fields>
          <field>
            <name>DLC</name>
            <bitOffset>0</bitOffset>
            <bitWidth>4</bitWidth>
          </field>
          <field>
            <name>TGT</name>
            <bitOffset>8</bitOffset>
            <bitWidth>1</bitWidth>
          </field>
          <field>
            <name>TIME</name>
            <bitOffset>16</bitOffset>
            <bitWidth>16</bitWidth>
          </field>
        </fields>
      </register>
      <register>
        <name>sTxMailBox.2.TDLR</name>
        <addressOffset>0x1a8</addressOffset>
        <size>0x20</size>
        <fields>
          <field>
            <name>DATA0</name>
            <bitOffset>0</bitOffset>
            <bitWidth>8</bitWidth>
          </field>
          <field>
            <name>DATA1</name>
            <bitOffset>8</bitOffset>
            <bitWidth>8</bitWidth>
          </field>
          <field>
            <name>DATA2</name>
            <bitOffset>16</bitOffset>
            <bitWidth>8</bitWidth>
          </field>
          <field>
            <name>DATA3</name>
            <bitOffset>24</bitOffset>
            <bitWidth>8</bitWidth>
          </field>
        </fields>
      </register>
      <register>
        <name>sTxMailBox.2.TDHR</name>
        <addressOffset>0x1ac</addressOffset>
        <size>0x20</size>
        <fields>
          <field>
            <name>DATA4</name>
            <bitOffset>0</bitOffset>
            <bitWidth>8</bitWidth>
          </field>
          <field>
            <name>DATA5</name>
            <bitOffset>8</bitOffset>
            <bitWidth>8</bitWidth>
          </field>
          <field>
            <name>DATA6</name>
            <bitOffset>16</bitOffset>
            <bitWidth>8</bitWidth>
          </field>
          <field>
            <name>DATA7</name>
            <bitOffset>24</bitOffset>
            <bitWidth>8</bitWidth>
          </field>
        </fields>
      </register>
      <register>
        <name>sFIFOMailBox.0.RIR</name>
        <addressOffset>0x1b0</addressOffset>
        <size>0x20</size>
        <fields>
          <field>
            <name>RTR</name>
            <bitOffset>1</bitOffset>
            <bitWidth>1</bitWidth>
          </field>
          <field>
            <name>IDE</name>
            <bitOffset>2</bitOffset>
            <bitWidth>1</bitWidth>
          </field>
          <field>
            <name>EXID</name>
            <bitOffset>3</bitOffset>
            <bitWidth>18</bitWidth>
          </field>
          <field>
            <name>STID</name>
            <bitOffset>21</bitOffset>
            <bitWidth>11</bitWidth>
          </field>
        </fields>
      </register>
      <register>
        <name>sFIFOMailBox.0.RDTR</name>
        <addressOffset>0x1b4</addressOffset>
        <size>0x20</size>
        <fields>
          <field>
            <name>DLC</name>
            <bitOffset>0</bitOffset>
            <bitWidth>4</bitWidth>
          </field>
          <field>
            <name>FMI</name>
            <bitOffset>8</bitOffset>
            <bitWidth>8</bitWidth>
          </field>
          <field>
            <name>TIME</name>
            <bitOffset>16</bitOffset>
            <bitWidth>16</bitWidth>
          </field>
        </fields>
      </register>
      <register>
        <name>sFIFOMailBox.0.RDLR</name>
        <addressOffset>0x1b8</addressOffset>
        <size>0x20</size>
        <fields>
          <field>
            <name>DATA0</name>
            <bitOffset>0</bitOffset>
            <bitWidth>8</bitWidth>
          </field>
          <field>
            <name>DATA1</name>
            <bitOffset>8</bitOffset>
            <bitWidth>8</bitWidth>
          </field>
          <field>
            <name>DATA2</name>
            <bitOffset>16</bitOffset>
            <bitWidth>8</bitWidth>
          </field>
          <field>
            <name>DATA3</name>
            <bitOffset>24</bitOffset>
            <bitWidth>8</bitWidth>
          </field>
        </fields>
      </register>
      <register>
        <name>sFIFOMailBox.0.RDHR</name>
        <addressOffset>0x1bc</addressOffset>
        <size>0x20</size>
        <fields>
          <field>
            <name>DATA4</name>
            <bitOffset>0</bitOffset>
            <bitWidth>8</bitWidth>
          </field>
          <field>
            <name>DATA5</name>
            <bitOffset>8</bitOffset>
            <bitWidth>8</bitWidth>
          </field>
          <field>
            <name>DATA6</name>
            <bitOffset>16</bitOffset>
            <bitWidth>8</bitWidth>
          </field>
          <field>
            <name>DATA7</name>
            <bitOffset>24</bitOffset>
            <bitWidth>8</bitWidth>
          </field>
        </fields>
      </register>
      <register>
        <name>sFIFOMailBox.1.RIR</name>
        <addressOffset>0x1c0</addressOffset>
        <size>0x20</size>
        <fields>
          <field>
            <name>RTR</name>
            <bitOffset>1</bitOffset>
            <bitWidth>1</bitWidth>
          </field>
          <field>
            <name>IDE</name>
            <bitOffset>2</bitOffset>
            <bitWidth>1</bitWidth>
          </field>
          <field>
            <name>EXID</name>
            <bitOffset>3</bitOffset>
            <bitWidth>18</bitWidth>
          </field>
          <field>
            <name>STID</name>
            <bitOffset>21</bitOffset>
            <bitWidth>11</bitWidth>
          </field>
        </fields>
      </register>
      <register>
        <name>sFIFOMailBox.1.RDTR</name>
        <addressOffset>0x1c4</addressOffset>
        <size>0x20</size>
        <fields>
          <field>
            <name>DLC</name>
            <bitOffset>0</bitOffset>
            <bitWidth>4</bitWidth>
          </field>
          <field>
            <name>FMI</name>
            <bitOffset>8</bitOffset>
            <bitWidth>8</bitWidth>
          </field>
          <field>
            <name>TIME</name>
            <bitOffset>16</bitOffset>
            <bitWidth>16</bitWidth>
          </field>
        </fields>
      </register>
      <register>
        <name>sFIFOMailBox.1.RDLR</name>
        <addressOffset>0x1c8</addressOffset>
        <size>0x20</size>
        <fields>
          <field>
            <name>DATA0</name>
            <bitOffset>0</bitOffset>
            <bitWidth>8</bitWidth>
          </field>
          <field>
            <name>DATA1</name>
            <bitOffset>8</bitOffset>
            <bitWidth>8</bitWidth>
          </field>
          <field>
            <name>DATA2</name>
            <bitOffset>16</bitOffset>
            <bitWidth>8</bitWidth>
          </field>
          <field>
            <name>DATA3</name>
            <bitOffset>24</bitOffset>
            <bitWidth>8</bitWidth>
          </field>
        </fields>
      </register>
      <register>
        <name>sFIFOMailBox.1.RDHR</name>
        <addressOffset>0x1cc</addressOffset>
        <size>0x20</size>
        <fields>
          <field>
            <name>DATA4</name>
            <bitOffset>0</bitOffset>
            <bitWidth>8</bitWidth>
          </field>
          <field>
            <name>DATA5</name>
            <bitOffset>8</bitOffset>
            <bitWidth>8</bitWidth>
          </field>
          <field>
            <name>DATA6</name>
            <bitOffset>16</bitOffset>
            <bitWidth>8</bitWidth>
          </field>
          <field>
            <name>DATA7</name>
            <bitOffset>24</bitOffset>
            <bitWidth>8</bitWidth>
          </field>
        </fields>
      </register>
      <register>
        <name>FMR</name>
        <addressOffset>0x200</addressOffset>
        <size>0x20</size>
        <fields>
          <field>
            <name>FINIT</name>
            <bitOffset>0</bitOffset>
            <bitWidth>1</bitWidth>
          </field>
          <field>
            <name>CAN2SB</name>
            <bitOffset>8</bitOffset>
            <bitWidth>6</bitWidth>
          </field>
        </fields>
      </register>
      <register>
        <name>FM1R</name>
        <addressOffset>0x204</addressOffset>
        <size>0x20</size>
        <fields>
          <field>
            <name>FBM0</name>
            <bitOffset>0</bitOffset>
            <bitWidth>1</bitWidth>
          </field>
          <field>
            <name>FBM1</name>
            <bitOffset>1</bitOffset>
            <bitWidth>1</bitWidth>
          </field>
          <field>
            <name>FBM2</name>
            <bitOffset>2</bitOffset>
            <bitWidth>1</bitWidth>
          </field>
          <field>
            <name>FBM3</name>
            <bitOffset>3</bitOffset>
            <bitWidth>1</bitWidth>
          </field>
          <field>
            <name>FBM4</name>
            <bitOffset>4</bitOffset>
            <bitWidth>1</bitWidth>
          </field>
          <field>
            <name>FBM5</name>
            <bitOffset>5</bitOffset>
            <bitWidth>1</bitWidth>
          </field>
          <field>
            <name>FBM6</name>
            <bitOffset>6</bitOffset>
            <bitWidth>1</bitWidth>
          </field>
          <field>
            <name>FBM7</name>
            <bitOffset>7</bitOffset>
            <bitWidth>1</bitWidth>
          </field>
          <field>
            <name>FBM8</name>
            <bitOffset>8</bitOffset>
            <bitWidth>1</bitWidth>
          </field>
          <field>
            <name>FBM9</name>
            <bitOffset>9</bitOffset>
            <bitWidth>1</bitWidth>
          </field>
          <field>
            <name>FBM10</name>
            <bitOffset>10</bitOffset>
            <bitWidth>1</bitWidth>
          </field>
          <field>
            <name>FBM11</name>
            <bitOffset>11</bitOffset>
            <bitWidth>1</bitWidth>
          </field>
          <field>
            <name>FBM12</name>
            <bitOffset>12</bitOffset>
            <bitWidth>1</bitWidth>
          </field>
          <field>
            <name>FBM13</name>
            <bitOffset>13</bitOffset>
            <bitWidth>1</bitWidth>
          </field>
          <field>
            <name>FBM14</name>
            <bitOffset>14</bitOffset>
            <bitWidth>1</bitWidth>
          </field>
          <field>
            <name>FBM15</name>
            <bitOffset>15</bitOffset>
            <bitWidth>1</bitWidth>
          </field>
          <field>
            <name>FBM16</name>
            <bitOffset>16</bitOffset>
            <bitWidth>1</bitWidth>
          </field>
          <field>
            <name>FBM17</name>
            <bitOffset>17</bitOffset>
            <bitWidth>1</bitWidth>
          </field>
          <field>
            <name>FBM18</name>
            <bitOffset>18</bitOffset>
            <bitWidth>1</bitWidth>
          </field>
          <field>
            <name>FBM19</name>
            <bitOffset>19</bitOffset>
            <bitWidth>1</bitWidth>
          </field>
          <field>
            <name>FBM20</name>
            <bitOffset>20</bitOffset>
            <bitWidth>1</bitWidth>
          </field>
          <field>
            <name>FBM21</name>
            <bitOffset>21</bitOffset>
            <bitWidth>1</bitWidth>
          </field>
          <field>
            <name>FBM22</name>
            <bitOffset>22</bitOffset>
            <bitWidth>1</bitWidth>
          </field>
          <field>
            <name>FBM23</name>
            <bitOffset>23</bitOffset>
            <bitWidth>1</bitWidth>
          </field>
          <field>
            <name>FBM24</name>
            <bitOffset>24</bitOffset>
            <bitWidth>1</bitWidth>
          </field>
          <field>
            <name>FBM25</name>
            <bitOffset>25</bitOffset>
            <bitWidth>1</bitWidth>
          </field>
          <field>
            <name>FBM26</name>
            <bitOffset>26</bitOffset>
            <bitWidth>1</bitWidth>
          </field>
          <field>
            <name>FBM27</name>
            <bitOffset>27</bitOffset>
            <bitWidth>1</bitWidth>
          </field>
        </fields>
      </register>
      <register>
        <name>FS1R</name>
        <addressOffset>0x20c</addressOffset>
        <size>0x20</size>
        <fields>
          <field>
            <name>FSC0</name>
            <bitOffset>0</bitOffset>
            <bitWidth>1</bitWidth>
          </field>
          <field>
            <name>FSC1</name>
            <bitOffset>1</bitOffset>
            <bitWidth>1</bitWidth>
          </field>
          <field>
            <name>FSC2</name>
            <bitOffset>2</bitOffset>
            <bitWidth>1</bitWidth>
          </field>
          <field>
            <name>FSC3</name>
            <bitOffset>3</bitOffset>
            <bitWidth>1</bitWidth>
          </field>
          <field>
            <name>FSC4</name>
            <bitOffset>4</bitOffset>
            <bitWidth>1</bitWidth>
          </field>
          <field>
            <name>FSC5</name>
            <bitOffset>5</bitOffset>
            <bitWidth>1</bitWidth>
          </field>
          <field>
            <name>FSC6</name>
            <bitOffset>6</bitOffset>
            <bitWidth>1</bitWidth>
          </field>
          <field>
            <name>FSC7</name>
            <bitOffset>7</bitOffset>
            <bitWidth>1</bitWidth>
          </field>
          <field>
            <name>FSC8</name>
            <bitOffset>8</bitOffset>
            <bitWidth>1</bitWidth>
          </field>
          <field>
            <name>FSC9</name>
            <bitOffset>9</bitOffset>
            <bitWidth>1</bitWidth>
          </field>
          <field>
            <name>FSC10</name>
            <bitOffset>10</bitOffset>
            <bitWidth>1</bitWidth>
          </field>
          <field>
            <name>FSC11</name>
            <bitOffset>11</bitOffset>
            <bitWidth>1</bitWidth>
          </field>
          <field>
            <name>FSC12</name>
            <bitOffset>12</bitOffset>
            <bitWidth>1</bitWidth>
          </field>
          <field>
            <name>FSC13</name>
            <bitOffset>13</bitOffset>
            <bitWidth>1</bitWidth>
          </field>
          <field>
            <name>FSC14</name>
            <bitOffset>14</bitOffset>
            <bitWidth>1</bitWidth>
          </field>
          <field>
            <name>FSC15</name>
            <bitOffset>15</bitOffset>
            <bitWidth>1</bitWidth>
          </field>
          <field>
            <name>FSC16</name>
            <bitOffset>16</bitOffset>
            <bitWidth>1</bitWidth>
          </field>
          <field>
            <name>FSC17</name>
            <bitOffset>17</bitOffset>
            <bitWidth>1</bitWidth>
          </field>
          <field>
            <name>FSC18</name>
            <bitOffset>18</bitOffset>
            <bitWidth>1</bitWidth>
          </field>
          <field>
            <name>FSC19</name>
            <bitOffset>19</bitOffset>
            <bitWidth>1</bitWidth>
          </field>
          <field>
            <name>FSC20</name>
            <bitOffset>20</bitOffset>
            <bitWidth>1</bitWidth>
          </field>
          <field>
            <name>FSC21</name>
            <bitOffset>21</bitOffset>
            <bitWidth>1</bitWidth>
          </field>
          <field>
            <name>FSC22</name>
            <bitOffset>22</bitOffset>
            <bitWidth>1</bitWidth>
          </field>
          <field>
            <name>FSC23</name>
            <bitOffset>23</bitOffset>
            <bitWidth>1</bitWidth>
          </field>
          <field>
            <name>FSC24</name>
            <bitOffset>24</bitOffset>
            <bitWidth>1</bitWidth>
          </field>
          <field>
            <name>FSC25</name>
            <bitOffset>25</bitOffset>
            <bitWidth>1</bitWidth>
          </field>
          <field>
            <name>FSC26</name>
            <bitOffset>26</bitOffset>
            <bitWidth>1</bitWidth>
          </field>
          <field>
            <name>FSC27</name>
            <bitOffset>27</bitOffset>
            <bitWidth>1</bitWidth>
          </field>
        </fields>
      </register>
      <register>
        <name>FFA1R</name>
        <addressOffset>0x214</addressOffset>
        <size>0x20</size>
        <fields>
          <field>
            <name>FFA0</name>
            <bitOffset>0</bitOffset>
            <bitWidth>1</bitWidth>
          </field>
          <field>
            <name>FFA1</name>
            <bitOffset>1</bitOffset>
            <bitWidth>1</bitWidth>
          </field>
          <field>
            <name>FFA2</name>
            <bitOffset>2</bitOffset>
            <bitWidth>1</bitWidth>
          </field>
          <field>
            <name>FFA3</name>
            <bitOffset>3</bitOffset>
            <bitWidth>1</bitWidth>
          </field>
          <field>
            <name>FFA4</name>
            <bitOffset>4</bitOffset>
            <bitWidth>1</bitWidth>
          </field>
          <field>
            <name>FFA5</name>
            <bitOffset>5</bitOffset>
            <bitWidth>1</bitWidth>
          </field>
          <field>
            <name>FFA6</name>
            <bitOffset>6</bitOffset>
            <bitWidth>1</bitWidth>
          </field>
          <field>
            <name>FFA7</name>
            <bitOffset>7</bitOffset>
            <bitWidth>1</bitWidth>
          </field>
          <field>
            <name>FFA8</name>
            <bitOffset>8</bitOffset>
            <bitWidth>1</bitWidth>
          </field>
          <field>
            <name>FFA9</name>
            <bitOffset>9</bitOffset>
            <bitWidth>1</bitWidth>
          </field>
          <field>
            <name>FFA10</name>
            <bitOffset>10</bitOffset>
            <bitWidth>1</bitWidth>
          </field>
          <field>
            <name>FFA11</name>
            <bitOffset>11</bitOffset>
            <bitWidth>1</bitWidth>
          </field>
          <field>
            <name>FFA12</name>
            <bitOffset>12</bitOffset>
            <bitWidth>1</bitWidth>
          </field>
          <field>
            <name>FFA13</name>
            <bitOffset>13</bitOffset>
            <bitWidth>1</bitWidth>
          </field>
          <field>
            <name>FFA14</name>
            <bitOffset>14</bitOffset>
            <bitWidth>1</bitWidth>
          </field>
          <field>
            <name>FFA15</name>
            <bitOffset>15</bitOffset>
            <bitWidth>1</bitWidth>
          </field>
          <field>
            <name>FFA16</name>
            <bitOffset>16</bitOffset>
            <bitWidth>1</bitWidth>
          </field>
          <field>
            <name>FFA17</name>
            <bitOffset>17</bitOffset>
            <bitWidth>1</bitWidth>
          </field>
          <field>
            <name>FFA18</name>
            <bitOffset>18</bitOffset>
            <bitWidth>1</bitWidth>
          </field>
          <field>
            <name>FFA19</name>
            <bitOffset>19</bitOffset>
            <bitWidth>1</bitWidth>
          </field>
          <field>
            <name>FFA20</name>
            <bitOffset>20</bitOffset>
            <bitWidth>1</bitWidth>
          </field>
          <field>
            <name>FFA21</name>
            <bitOffset>21</bitOffset>
            <bitWidth>1</bitWidth>
          </field>
          <field>
            <name>FFA22</name>
            <bitOffset>22</bitOffset>
            <bitWidth>1</bitWidth>
          </field>
          <field>
            <name>FFA23</name>
            <bitOffset>23</bitOffset>
            <bitWidth>1</bitWidth>
          </field>
          <field>
            <name>FFA24</name>
            <bitOffset>24</bitOffset>
            <bitWidth>1</bitWidth>
          </field>
          <field>
            <name>FFA25</name>
            <bitOffset>25</bitOffset>
            <bitWidth>1</bitWidth>
          </field>
          <field>
            <name>FFA26</name>
            <bitOffset>26</bitOffset>
            <bitWidth>1</bitWidth>
          </field>
          <field>
            <name>FFA27</name>
            <bitOffset>27</bitOffset>
            <bitWidth>1</bitWidth>
          </field>
        </fields>
      </register>
      <register>
        <name>FA1R</name>
        <addressOffset>0x21c</addressOffset>
        <size>0x20</size>
        <fields>
          <field>
            <name>FACT0</name>
            <bitOffset>0</bitOffset>
            <bitWidth>1</bitWidth>
          </field>
          <field>
            <name>FACT1</name>
            <bitOffset>1</bitOffset>
            <bitWidth>1</bitWidth>
          </field>
          <field>
            <name>FACT2</name>
            <bitOffset>2</bitOffset>
            <bitWidth>1</bitWidth>
          </field>
          <field>
            <name>FACT3</name>
            <bitOffset>3</bitOffset>
            <bitWidth>1</bitWidth>
          </field>
          <field>
            <name>FACT4</name>
            <bitOffset>4</bitOffset>
            <bitWidth>1</bitWidth>
          </field>
          <field>
            <name>FACT5</name>
            <bitOffset>5</bitOffset>
            <bitWidth>1</bitWidth>
          </field>
          <field>
            <name>FACT6</name>
            <bitOffset>6</bitOffset>
            <bitWidth>1</bitWidth>
          </field>
          <field>
            <name>FACT7</name>
            <bitOffset>7</bitOffset>
            <bitWidth>1</bitWidth>
          </field>
          <field>
            <name>FACT8</name>
            <bitOffset>8</bitOffset>
            <bitWidth>1</bitWidth>
          </field>
          <field>
            <name>FACT9</name>
            <bitOffset>9</bitOffset>
            <bitWidth>1</bitWidth>
          </field>
          <field>
            <name>FACT10</name>
            <bitOffset>10</bitOffset>
            <bitWidth>1</bitWidth>
          </field>
          <field>
            <name>FACT11</name>
            <bitOffset>11</bitOffset>
            <bitWidth>1</bitWidth>
          </field>
          <field>
            <name>FACT12</name>
            <bitOffset>12</bitOffset>
            <bitWidth>1</bitWidth>
          </field>
          <field>
            <name>FACT13</name>
            <bitOffset>13</bitOffset>
            <bitWidth>1</bitWidth>
          </field>
          <field>
            <name>FACT14</name>
            <bitOffset>14</bitOffset>
            <bitWidth>1</bitWidth>
          </field>
          <field>
            <name>FACT15</name>
            <bitOffset>15</bitOffset>
            <bitWidth>1</bitWidth>
          </field>
          <field>
            <name>FACT16</name>
            <bitOffset>16</bitOffset>
            <bitWidth>1</bitWidth>
          </field>
          <field>
            <name>FACT17</name>
            <bitOffset>17</bitOffset>
            <bitWidth>1</bitWidth>
          </field>
          <field>
            <name>FACT18</name>
            <bitOffset>18</bitOffset>
            <bitWidth>1</bitWidth>
          </field>
          <field>
            <name>FACT19</name>
            <bitOffset>19</bitOffset>
            <bitWidth>1</bitWidth>
          </field>
          <field>
            <name>FACT20</name>
            <bitOffset>20</bitOffset>
            <bitWidth>1</bitWidth>
          </field>
          <field>
            <name>FACT21</name>
            <bitOffset>21</bitOffset>
            <bitWidth>1</bitWidth>
          </field>
          <field>
            <name>FACT22</name>
            <bitOffset>22</bitOffset>
            <bitWidth>1</bitWidth>
          </field>
          <field>
            <name>FACT23</name>
            <bitOffset>23</bitOffset>
            <bitWidth>1</bitWidth>
          </field>
          <field>
            <name>FACT24</name>
            <bitOffset>24</bitOffset>
            <bitWidth>1</bitWidth>
          </field>
          <field>
            <name>FACT25</name>
            <bitOffset>25</bitOffset>
            <bitWidth>1</bitWidth>
          </field>
          <field>
            <name>FACT26</name>
            <bitOffset>26</bitOffset>
            <bitWidth>1</bitWidth>
          </field>
          <field>
            <name>FACT27</name>
            <bitOffset>27</bitOffset>
            <bitWidth>1</bitWidth>
          </field>
        </fields>
      </register>
      <register>
        <name>sFilterRegister.0.FR1</name>
        <addressOffset>0x240</addressOffset>
        <size>0x20</size>
        <fields>
          <field>
            <name>FB0</name>
            <bitOffset>0</bitOffset>
            <bitWidth>1</bitWidth>
          </field>
          <field>
            <name>FB1</name>
            <bitOffset>1</bitOffset>
            <bitWidth>1</bitWidth>
          </field>
          <field>
            <name>FB2</name>
            <bitOffset>2</bitOffset>
            <bitWidth>1</bitWidth>
          </field>
          <field>
            <name>FB3</name>
            <bitOffset>3</bitOffset>
            <bitWidth>1</bitWidth>
          </field>
          <field>
            <name>FB4</name>
            <bitOffset>4</bitOffset>
            <bitWidth>1</bitWidth>
          </field>
          <field>
            <name>FB5</name>
            <bitOffset>5</bitOffset>
            <bitWidth>1</bitWidth>
          </field>
          <field>
            <name>FB6</name>
            <bitOffset>6</bitOffset>
            <bitWidth>1</bitWidth>
          </field>
          <field>
            <name>FB7</name>
            <bitOffset>7</bitOffset>
            <bitWidth>1</bitWidth>
          </field>
          <field>
            <name>FB8</name>
            <bitOffset>8</bitOffset>
            <bitWidth>1</bitWidth>
          </field>
          <field>
            <name>FB9</name>
            <bitOffset>9</bitOffset>
            <bitWidth>1</bitWidth>
          </field>
          <field>
            <name>FB10</name>
            <bitOffset>10</bitOffset>
            <bitWidth>1</bitWidth>
          </field>
          <field>
            <name>FB11</name>
            <bitOffset>11</bitOffset>
            <bitWidth>1</bitWidth>
          </field>
          <field>
            <name>FB12</name>
            <bitOffset>12</bitOffset>
            <bitWidth>1</bitWidth>
          </field>
          <field>
            <name>FB13</name>
            <bitOffset>13</bitOffset>
            <bitWidth>1</bitWidth>
          </field>
          <field>
            <name>FB14</name>
            <bitOffset>14</bitOffset>
            <bitWidth>1</bitWidth>
          </field>
          <field>
            <name>FB15</name>
            <bitOffset>15</bitOffset>
            <bitWidth>1</bitWidth>
          </field>
          <field>
            <name>FB16</name>
            <bitOffset>16</bitOffset>
            <bitWidth>1</bitWidth>
          </field>
          <field>
            <name>FB17</name>
            <bitOffset>17</bitOffset>
            <bitWidth>1</bitWidth>
          </field>
          <field>
            <name>FB18</name>
            <bitOffset>18</bitOffset>
            <bitWidth>1</bitWidth>
          </field>
          <field>
            <name>FB19</name>
            <bitOffset>19</bitOffset>
            <bitWidth>1</bitWidth>
          </field>
          <field>
            <name>FB20</name>
            <bitOffset>20</bitOffset>
            <bitWidth>1</bitWidth>
          </field>
          <field>
            <name>FB21</name>
            <bitOffset>21</bitOffset>
            <bitWidth>1</bitWidth>
          </field>
          <field>
            <name>FB22</name>
            <bitOffset>22</bitOffset>
            <bitWidth>1</bitWidth>
          </field>
          <field>
            <name>FB23</name>
            <bitOffset>23</bitOffset>
            <bitWidth>1</bitWidth>
          </field>
          <field>
            <name>FB24</name>
            <bitOffset>24</bitOffset>
            <bitWidth>1</bitWidth>
          </field>
          <field>
            <name>FB25</name>
            <bitOffset>25</bitOffset>
            <bitWidth>1</bitWidth>
          </field>
          <field>
            <name>FB26</name>
            <bitOffset>26</bitOffset>
            <bitWidth>1</bitWidth>
          </field>
          <field>
            <name>FB27</name>
            <bitOffset>27</bitOffset>
            <bitWidth>1</bitWidth>
          </field>
          <field>
            <name>FB28</name>
            <bitOffset>28</bitOffset>
            <bitWidth>1</bitWidth>
          </field>
          <field>
            <name>FB29</name>
            <bitOffset>29</bitOffset>
            <bitWidth>1</bitWidth>
          </field>
          <field>
            <name>FB30</name>
            <bitOffset>30</bitOffset>
            <bitWidth>1</bitWidth>
          </field>
          <field>
            <name>FB31</name>
            <bitOffset>31</bitOffset>
            <bitWidth>1</bitWidth>
          </field>
        </fields>
      </register>
      <register>
        <name>sFilterRegister.0.FR2</name>
        <addressOffset>0x244</addressOffset>
        <size>0x20</size>
        <fields>
          <field>
            <name>FB0</name>
            <bitOffset>0</bitOffset>
            <bitWidth>1</bitWidth>
          </field>
          <field>
            <name>FB1</name>
            <bitOffset>1</bitOffset>
            <bitWidth>1</bitWidth>
          </field>
          <field>
            <name>FB2</name>
            <bitOffset>2</bitOffset>
            <bitWidth>1</bitWidth>
          </field>
          <field>
            <name>FB3</name>
            <bitOffset>3</bitOffset>
            <bitWidth>1</bitWidth>
          </field>
          <field>
            <name>FB4</name>
            <bitOffset>4</bitOffset>
            <bitWidth>1</bitWidth>
          </field>
          <field>
            <name>FB5</name>
            <bitOffset>5</bitOffset>
            <bitWidth>1</bitWidth>
          </field>
          <field>
            <name>FB6</name>
            <bitOffset>6</bitOffset>
            <bitWidth>1</bitWidth>
          </field>
          <field>
            <name>FB7</name>
            <bitOffset>7</bitOffset>
            <bitWidth>1</bitWidth>
          </field>
          <field>
            <name>FB8</name>
            <bitOffset>8</bitOffset>
            <bitWidth>1</bitWidth>
          </field>
          <field>
            <name>FB9</name>
            <bitOffset>9</bitOffset>
            <bitWidth>1</bitWidth>
          </field>
          <field>
            <name>FB10</name>
            <bitOffset>10</bitOffset>
            <bitWidth>1</bitWidth>
          </field>
          <field>
            <name>FB11</name>
            <bitOffset>11</bitOffset>
            <bitWidth>1</bitWidth>
          </field>
          <field>
            <name>FB12</name>
            <bitOffset>12</bitOffset>
            <bitWidth>1</bitWidth>
          </field>
          <field>
            <name>FB13</name>
            <bitOffset>13</bitOffset>
            <bitWidth>1</bitWidth>
          </field>
          <field>
            <name>FB14</name>
            <bitOffset>14</bitOffset>
            <bitWidth>1</bitWidth>
          </field>
          <field>
            <name>FB15</name>
            <bitOffset>15</bitOffset>
            <bitWidth>1</bitWidth>
          </field>
          <field>
            <name>FB16</name>
            <bitOffset>16</bitOffset>
            <bitWidth>1</bitWidth>
          </field>
          <field>
            <name>FB17</name>
            <bitOffset>17</bitOffset>
            <bitWidth>1</bitWidth>
          </field>
          <field>
            <name>FB18</name>
            <bitOffset>18</bitOffset>
            <bitWidth>1</bitWidth>
          </field>
          <field>
            <name>FB19</name>
            <bitOffset>19</bitOffset>
            <bitWidth>1</bitWidth>
          </field>
          <field>
            <name>FB20</name>
            <bitOffset>20</bitOffset>
            <bitWidth>1</bitWidth>
          </field>
          <field>
            <name>FB21</name>
            <bitOffset>21</bitOffset>
            <bitWidth>1</bitWidth>
          </field>
          <field>
            <name>FB22</name>
            <bitOffset>22</bitOffset>
            <bitWidth>1</bitWidth>
          </field>
          <field>
            <name>FB23</name>
            <bitOffset>23</bitOffset>
            <bitWidth>1</bitWidth>
          </field>
          <field>
            <name>FB24</name>
            <bitOffset>24</bitOffset>
            <bitWidth>1</bitWidth>
          </field>
          <field>
            <name>FB25</name>
            <bitOffset>25</bitOffset>
            <bitWidth>1</bitWidth>
          </field>
          <field>
            <name>FB26</name>
            <bitOffset>26</bitOffset>
            <bitWidth>1</bitWidth>
          </field>
          <field>
            <name>FB27</name>
            <bitOffset>27</bitOffset>
            <bitWidth>1</bitWidth>
          </field>
          <field>
            <name>FB28</name>
            <bitOffset>28</bitOffset>
            <bitWidth>1</bitWidth>
          </field>
          <field>
            <name>FB29</name>
            <bitOffset>29</bitOffset>
            <bitWidth>1</bitWidth>
          </field>
          <field>
            <name>FB30</name>
            <bitOffset>30</bitOffset>
            <bitWidth>1</bitWidth>
          </field>
          <field>
            <name>FB31</name>
            <bitOffset>31</bitOffset>
            <bitWidth>1</bitWidth>
          </field>
        </fields>
      </register>
      <register>
        <name>sFilterRegister.1.FR1</name>
        <addressOffset>0x248</addressOffset>
        <size>0x20</size>
        <fields>
          <field>
            <name>FB0</name>
            <bitOffset>0</bitOffset>
            <bitWidth>1</bitWidth>
          </field>
          <field>
            <name>FB1</name>
            <bitOffset>1</bitOffset>
            <bitWidth>1</bitWidth>
          </field>
          <field>
            <name>FB2</name>
            <bitOffset>2</bitOffset>
            <bitWidth>1</bitWidth>
          </field>
          <field>
            <name>FB3</name>
            <bitOffset>3</bitOffset>
            <bitWidth>1</bitWidth>
          </field>
          <field>
            <name>FB4</name>
            <bitOffset>4</bitOffset>
            <bitWidth>1</bitWidth>
          </field>
          <field>
            <name>FB5</name>
            <bitOffset>5</bitOffset>
            <bitWidth>1</bitWidth>
          </field>
          <field>
            <name>FB6</name>
            <bitOffset>6</bitOffset>
            <bitWidth>1</bitWidth>
          </field>
          <field>
            <name>FB7</name>
            <bitOffset>7</bitOffset>
            <bitWidth>1</bitWidth>
          </field>
          <field>
            <name>FB8</name>
            <bitOffset>8</bitOffset>
            <bitWidth>1</bitWidth>
          </field>
          <field>
            <name>FB9</name>
            <bitOffset>9</bitOffset>
            <bitWidth>1</bitWidth>
          </field>
          <field>
            <name>FB10</name>
            <bitOffset>10</bitOffset>
            <bitWidth>1</bitWidth>
          </field>
          <field>
            <name>FB11</name>
            <bitOffset>11</bitOffset>
            <bitWidth>1</bitWidth>
          </field>
          <field>
            <name>FB12</name>
            <bitOffset>12</bitOffset>
            <bitWidth>1</bitWidth>
          </field>
          <field>
            <name>FB13</name>
            <bitOffset>13</bitOffset>
            <bitWidth>1</bitWidth>
          </field>
          <field>
            <name>FB14</name>
            <bitOffset>14</bitOffset>
            <bitWidth>1</bitWidth>
          </field>
          <field>
            <name>FB15</name>
            <bitOffset>15</bitOffset>
            <bitWidth>1</bitWidth>
          </field>
          <field>
            <name>FB16</name>
            <bitOffset>16</bitOffset>
            <bitWidth>1</bitWidth>
          </field>
          <field>
            <name>FB17</name>
            <bitOffset>17</bitOffset>
            <bitWidth>1</bitWidth>
          </field>
          <field>
            <name>FB18</name>
            <bitOffset>18</bitOffset>
            <bitWidth>1</bitWidth>
          </field>
          <field>
            <name>FB19</name>
            <bitOffset>19</bitOffset>
            <bitWidth>1</bitWidth>
          </field>
          <field>
            <name>FB20</name>
            <bitOffset>20</bitOffset>
            <bitWidth>1</bitWidth>
          </field>
          <field>
            <name>FB21</name>
            <bitOffset>21</bitOffset>
            <bitWidth>1</bitWidth>
          </field>
          <field>
            <name>FB22</name>
            <bitOffset>22</bitOffset>
            <bitWidth>1</bitWidth>
          </field>
          <field>
            <name>FB23</name>
            <bitOffset>23</bitOffset>
            <bitWidth>1</bitWidth>
          </field>
          <field>
            <name>FB24</name>
            <bitOffset>24</bitOffset>
            <bitWidth>1</bitWidth>
          </field>
          <field>
            <name>FB25</name>
            <bitOffset>25</bitOffset>
            <bitWidth>1</bitWidth>
          </field>
          <field>
            <name>FB26</name>
            <bitOffset>26</bitOffset>
            <bitWidth>1</bitWidth>
          </field>
          <field>
            <name>FB27</name>
            <bitOffset>27</bitOffset>
            <bitWidth>1</bitWidth>
          </field>
          <field>
            <name>FB28</name>
            <bitOffset>28</bitOffset>
            <bitWidth>1</bitWidth>
          </field>
          <field>
            <name>FB29</name>
            <bitOffset>29</bitOffset>
            <bitWidth>1</bitWidth>
          </field>
          <field>
            <name>FB30</name>
            <bitOffset>30</bitOffset>
            <bitWidth>1</bitWidth>
          </field>
          <field>
            <name>FB31</name>
            <bitOffset>31</bitOffset>
            <bitWidth>1</bitWidth>
          </field>
        </fields>
      </register>
      <register>
        <name>sFilterRegister.1.FR2</name>
        <addressOffset>0x24c</addressOffset>
        <size>0x20</size>
        <fields>
          <field>
            <name>FB0</name>
            <bitOffset>0</bitOffset>
            <bitWidth>1</bitWidth>
          </field>
          <field>
            <name>FB1</name>
            <bitOffset>1</bitOffset>
            <bitWidth>1</bitWidth>
          </field>
          <field>
            <name>FB2</name>
            <bitOffset>2</bitOffset>
            <bitWidth>1</bitWidth>
          </field>
          <field>
            <name>FB3</name>
            <bitOffset>3</bitOffset>
            <bitWidth>1</bitWidth>
          </field>
          <field>
            <name>FB4</name>
            <bitOffset>4</bitOffset>
            <bitWidth>1</bitWidth>
          </field>
          <field>
            <name>FB5</name>
            <bitOffset>5</bitOffset>
            <bitWidth>1</bitWidth>
          </field>
          <field>
            <name>FB6</name>
            <bitOffset>6</bitOffset>
            <bitWidth>1</bitWidth>
          </field>
          <field>
            <name>FB7</name>
            <bitOffset>7</bitOffset>
            <bitWidth>1</bitWidth>
          </field>
          <field>
            <name>FB8</name>
            <bitOffset>8</bitOffset>
            <bitWidth>1</bitWidth>
          </field>
          <field>
            <name>FB9</name>
            <bitOffset>9</bitOffset>
            <bitWidth>1</bitWidth>
          </field>
          <field>
            <name>FB10</name>
            <bitOffset>10</bitOffset>
            <bitWidth>1</bitWidth>
          </field>
          <field>
            <name>FB11</name>
            <bitOffset>11</bitOffset>
            <bitWidth>1</bitWidth>
          </field>
          <field>
            <name>FB12</name>
            <bitOffset>12</bitOffset>
            <bitWidth>1</bitWidth>
          </field>
          <field>
            <name>FB13</name>
            <bitOffset>13</bitOffset>
            <bitWidth>1</bitWidth>
          </field>
          <field>
            <name>FB14</name>
            <bitOffset>14</bitOffset>
            <bitWidth>1</bitWidth>
          </field>
          <field>
            <name>FB15</name>
            <bitOffset>15</bitOffset>
            <bitWidth>1</bitWidth>
          </field>
          <field>
            <name>FB16</name>
            <bitOffset>16</bitOffset>
            <bitWidth>1</bitWidth>
          </field>
          <field>
            <name>FB17</name>
            <bitOffset>17</bitOffset>
            <bitWidth>1</bitWidth>
          </field>
          <field>
            <name>FB18</name>
            <bitOffset>18</bitOffset>
            <bitWidth>1</bitWidth>
          </field>
          <field>
            <name>FB19</name>
            <bitOffset>19</bitOffset>
            <bitWidth>1</bitWidth>
          </field>
          <field>
            <name>FB20</name>
            <bitOffset>20</bitOffset>
            <bitWidth>1</bitWidth>
          </field>
          <field>
            <name>FB21</name>
            <bitOffset>21</bitOffset>
            <bitWidth>1</bitWidth>
          </field>
          <field>
            <name>FB22</name>
            <bitOffset>22</bitOffset>
            <bitWidth>1</bitWidth>
          </field>
          <field>
            <name>FB23</name>
            <bitOffset>23</bitOffset>
            <bitWidth>1</bitWidth>
          </field>
          <field>
            <name>FB24</name>
            <bitOffset>24</bitOffset>
            <bitWidth>1</bitWidth>
          </field>
          <field>
            <name>FB25</name>
            <bitOffset>25</bitOffset>
            <bitWidth>1</bitWidth>
          </field>
          <field>
            <name>FB26</name>
            <bitOffset>26</bitOffset>
            <bitWidth>1</bitWidth>
          </field>
          <field>
            <name>FB27</name>
            <bitOffset>27</bitOffset>
            <bitWidth>1</bitWidth>
          </field>
          <field>
            <name>FB28</name>
            <bitOffset>28</bitOffset>
            <bitWidth>1</bitWidth>
          </field>
          <field>
            <name>FB29</name>
            <bitOffset>29</bitOffset>
            <bitWidth>1</bitWidth>
          </field>
          <field>
            <name>FB30</name>
            <bitOffset>30</bitOffset>
            <bitWidth>1</bitWidth>
          </field>
          <field>
            <name>FB31</name>
            <bitOffset>31</bitOffset>
            <bitWidth>1</bitWidth>
          </field>
        </fields>
      </register>
      <register>
        <name>sFilterRegister.2.FR1</name>
        <addressOffset>0x250</addressOffset>
        <size>0x20</size>
        <fields>
          <field>
            <name>FB0</name>
            <bitOffset>0</bitOffset>
            <bitWidth>1</bitWidth>
          </field>
          <field>
            <name>FB1</name>
            <bitOffset>1</bitOffset>
            <bitWidth>1</bitWidth>
          </field>
          <field>
            <name>FB2</name>
            <bitOffset>2</bitOffset>
            <bitWidth>1</bitWidth>
          </field>
          <field>
            <name>FB3</name>
            <bitOffset>3</bitOffset>
            <bitWidth>1</bitWidth>
          </field>
          <field>
            <name>FB4</name>
            <bitOffset>4</bitOffset>
            <bitWidth>1</bitWidth>
          </field>
          <field>
            <name>FB5</name>
            <bitOffset>5</bitOffset>
            <bitWidth>1</bitWidth>
          </field>
          <field>
            <name>FB6</name>
            <bitOffset>6</bitOffset>
            <bitWidth>1</bitWidth>
          </field>
          <field>
            <name>FB7</name>
            <bitOffset>7</bitOffset>
            <bitWidth>1</bitWidth>
          </field>
          <field>
            <name>FB8</name>
            <bitOffset>8</bitOffset>
            <bitWidth>1</bitWidth>
          </field>
          <field>
            <name>FB9</name>
            <bitOffset>9</bitOffset>
            <bitWidth>1</bitWidth>
          </field>
          <field>
            <name>FB10</name>
            <bitOffset>10</bitOffset>
            <bitWidth>1</bitWidth>
          </field>
          <field>
            <name>FB11</name>
            <bitOffset>11</bitOffset>
            <bitWidth>1</bitWidth>
          </field>
          <field>
            <name>FB12</name>
            <bitOffset>12</bitOffset>
            <bitWidth>1</bitWidth>
          </field>
          <field>
            <name>FB13</name>
            <bitOffset>13</bitOffset>
            <bitWidth>1</bitWidth>
          </field>
          <field>
            <name>FB14</name>
            <bitOffset>14</bitOffset>
            <bitWidth>1</bitWidth>
          </field>
          <field>
            <name>FB15</name>
            <bitOffset>15</bitOffset>
            <bitWidth>1</bitWidth>
          </field>
          <field>
            <name>FB16</name>
            <bitOffset>16</bitOffset>
            <bitWidth>1</bitWidth>
          </field>
          <field>
            <name>FB17</name>
            <bitOffset>17</bitOffset>
            <bitWidth>1</bitWidth>
          </field>
          <field>
            <name>FB18</name>
            <bitOffset>18</bitOffset>
            <bitWidth>1</bitWidth>
          </field>
          <field>
            <name>FB19</name>
            <bitOffset>19</bitOffset>
            <bitWidth>1</bitWidth>
          </field>
          <field>
            <name>FB20</name>
            <bitOffset>20</bitOffset>
            <bitWidth>1</bitWidth>
          </field>
          <field>
            <name>FB21</name>
            <bitOffset>21</bitOffset>
            <bitWidth>1</bitWidth>
          </field>
          <field>
            <name>FB22</name>
            <bitOffset>22</bitOffset>
            <bitWidth>1</bitWidth>
          </field>
          <field>
            <name>FB23</name>
            <bitOffset>23</bitOffset>
            <bitWidth>1</bitWidth>
          </field>
          <field>
            <name>FB24</name>
            <bitOffset>24</bitOffset>
            <bitWidth>1</bitWidth>
          </field>
          <field>
            <name>FB25</name>
            <bitOffset>25</bitOffset>
            <bitWidth>1</bitWidth>
          </field>
          <field>
            <name>FB26</name>
            <bitOffset>26</bitOffset>
            <bitWidth>1</bitWidth>
          </field>
          <field>
            <name>FB27</name>
            <bitOffset>27</bitOffset>
            <bitWidth>1</bitWidth>
          </field>
          <field>
            <name>FB28</name>
            <bitOffset>28</bitOffset>
            <bitWidth>1</bitWidth>
          </field>
          <field>
            <name>FB29</name>
            <bitOffset>29</bitOffset>
            <bitWidth>1</bitWidth>
          </field>
          <field>
            <name>FB30</name>
            <bitOffset>30</bitOffset>
            <bitWidth>1</bitWidth>
          </field>
          <field>
            <name>FB31</name>
            <bitOffset>31</bitOffset>
            <bitWidth>1</bitWidth>
          </field>
        </fields>
      </register>
      <register>
        <name>sFilterRegister.2.FR2</name>
        <addressOffset>0x254</addressOffset>
        <size>0x20</size>
        <fields>
          <field>
            <name>FB0</name>
            <bitOffset>0</bitOffset>
            <bitWidth>1</bitWidth>
          </field>
          <field>
            <name>FB1</name>
            <bitOffset>1</bitOffset>
            <bitWidth>1</bitWidth>
          </field>
          <field>
            <name>FB2</name>
            <bitOffset>2</bitOffset>
            <bitWidth>1</bitWidth>
          </field>
          <field>
            <name>FB3</name>
            <bitOffset>3</bitOffset>
            <bitWidth>1</bitWidth>
          </field>
          <field>
            <name>FB4</name>
            <bitOffset>4</bitOffset>
            <bitWidth>1</bitWidth>
          </field>
          <field>
            <name>FB5</name>
            <bitOffset>5</bitOffset>
            <bitWidth>1</bitWidth>
          </field>
          <field>
            <name>FB6</name>
            <bitOffset>6</bitOffset>
            <bitWidth>1</bitWidth>
          </field>
          <field>
            <name>FB7</name>
            <bitOffset>7</bitOffset>
            <bitWidth>1</bitWidth>
          </field>
          <field>
            <name>FB8</name>
            <bitOffset>8</bitOffset>
            <bitWidth>1</bitWidth>
          </field>
          <field>
            <name>FB9</name>
            <bitOffset>9</bitOffset>
            <bitWidth>1</bitWidth>
          </field>
          <field>
            <name>FB10</name>
            <bitOffset>10</bitOffset>
            <bitWidth>1</bitWidth>
          </field>
          <field>
            <name>FB11</name>
            <bitOffset>11</bitOffset>
            <bitWidth>1</bitWidth>
          </field>
          <field>
            <name>FB12</name>
            <bitOffset>12</bitOffset>
            <bitWidth>1</bitWidth>
          </field>
          <field>
            <name>FB13</name>
            <bitOffset>13</bitOffset>
            <bitWidth>1</bitWidth>
          </field>
          <field>
            <name>FB14</name>
            <bitOffset>14</bitOffset>
            <bitWidth>1</bitWidth>
          </field>
          <field>
            <name>FB15</name>
            <bitOffset>15</bitOffset>
            <bitWidth>1</bitWidth>
          </field>
          <field>
            <name>FB16</name>
            <bitOffset>16</bitOffset>
            <bitWidth>1</bitWidth>
          </field>
          <field>
            <name>FB17</name>
            <bitOffset>17</bitOffset>
            <bitWidth>1</bitWidth>
          </field>
          <field>
            <name>FB18</name>
            <bitOffset>18</bitOffset>
            <bitWidth>1</bitWidth>
          </field>
          <field>
            <name>FB19</name>
            <bitOffset>19</bitOffset>
            <bitWidth>1</bitWidth>
          </field>
          <field>
            <name>FB20</name>
            <bitOffset>20</bitOffset>
            <bitWidth>1</bitWidth>
          </field>
          <field>
            <name>FB21</name>
            <bitOffset>21</bitOffset>
            <bitWidth>1</bitWidth>
          </field>
          <field>
            <name>FB22</name>
            <bitOffset>22</bitOffset>
            <bitWidth>1</bitWidth>
          </field>
          <field>
            <name>FB23</name>
            <bitOffset>23</bitOffset>
            <bitWidth>1</bitWidth>
          </field>
          <field>
            <name>FB24</name>
            <bitOffset>24</bitOffset>
            <bitWidth>1</bitWidth>
          </field>
          <field>
            <name>FB25</name>
            <bitOffset>25</bitOffset>
            <bitWidth>1</bitWidth>
          </field>
          <field>
            <name>FB26</name>
            <bitOffset>26</bitOffset>
            <bitWidth>1</bitWidth>
          </field>
          <field>
            <name>FB27</name>
            <bitOffset>27</bitOffset>
            <bitWidth>1</bitWidth>
          </field>
          <field>
            <name>FB28</name>
            <bitOffset>28</bitOffset>
            <bitWidth>1</bitWidth>
          </field>
          <field>
            <name>FB29</name>
            <bitOffset>29</bitOffset>
            <bitWidth>1</bitWidth>
          </field>
          <field>
            <name>FB30</name>
            <bitOffset>30</bitOffset>
            <bitWidth>1</bitWidth>
          </field>
          <field>
            <name>FB31</name>
            <bitOffset>31</bitOffset>
            <bitWidth>1</bitWidth>
          </field>
        </fields>
      </register>
      <register>
        <name>sFilterRegister.3.FR1</name>
        <addressOffset>0x258</addressOffset>
        <size>0x20</size>
        <fields>
          <field>
            <name>FB0</name>
            <bitOffset>0</bitOffset>
            <bitWidth>1</bitWidth>
          </field>
          <field>
            <name>FB1</name>
            <bitOffset>1</bitOffset>
            <bitWidth>1</bitWidth>
          </field>
          <field>
            <name>FB2</name>
            <bitOffset>2</bitOffset>
            <bitWidth>1</bitWidth>
          </field>
          <field>
            <name>FB3</name>
            <bitOffset>3</bitOffset>
            <bitWidth>1</bitWidth>
          </field>
          <field>
            <name>FB4</name>
            <bitOffset>4</bitOffset>
            <bitWidth>1</bitWidth>
          </field>
          <field>
            <name>FB5</name>
            <bitOffset>5</bitOffset>
            <bitWidth>1</bitWidth>
          </field>
          <field>
            <name>FB6</name>
            <bitOffset>6</bitOffset>
            <bitWidth>1</bitWidth>
          </field>
          <field>
            <name>FB7</name>
            <bitOffset>7</bitOffset>
            <bitWidth>1</bitWidth>
          </field>
          <field>
            <name>FB8</name>
            <bitOffset>8</bitOffset>
            <bitWidth>1</bitWidth>
          </field>
          <field>
            <name>FB9</name>
            <bitOffset>9</bitOffset>
            <bitWidth>1</bitWidth>
          </field>
          <field>
            <name>FB10</name>
            <bitOffset>10</bitOffset>
            <bitWidth>1</bitWidth>
          </field>
          <field>
            <name>FB11</name>
            <bitOffset>11</bitOffset>
            <bitWidth>1</bitWidth>
          </field>
          <field>
            <name>FB12</name>
            <bitOffset>12</bitOffset>
            <bitWidth>1</bitWidth>
          </field>
          <field>
            <name>FB13</name>
            <bitOffset>13</bitOffset>
            <bitWidth>1</bitWidth>
          </field>
          <field>
            <name>FB14</name>
            <bitOffset>14</bitOffset>
            <bitWidth>1</bitWidth>
          </field>
          <field>
            <name>FB15</name>
            <bitOffset>15</bitOffset>
            <bitWidth>1</bitWidth>
          </field>
          <field>
            <name>FB16</name>
            <bitOffset>16</bitOffset>
            <bitWidth>1</bitWidth>
          </field>
          <field>
            <name>FB17</name>
            <bitOffset>17</bitOffset>
            <bitWidth>1</bitWidth>
          </field>
          <field>
            <name>FB18</name>
            <bitOffset>18</bitOffset>
            <bitWidth>1</bitWidth>
          </field>
          <field>
            <name>FB19</name>
            <bitOffset>19</bitOffset>
            <bitWidth>1</bitWidth>
          </field>
          <field>
            <name>FB20</name>
            <bitOffset>20</bitOffset>
            <bitWidth>1</bitWidth>
          </field>
          <field>
            <name>FB21</name>
            <bitOffset>21</bitOffset>
            <bitWidth>1</bitWidth>
          </field>
          <field>
            <name>FB22</name>
            <bitOffset>22</bitOffset>
            <bitWidth>1</bitWidth>
          </field>
          <field>
            <name>FB23</name>
            <bitOffset>23</bitOffset>
            <bitWidth>1</bitWidth>
          </field>
          <field>
            <name>FB24</name>
            <bitOffset>24</bitOffset>
            <bitWidth>1</bitWidth>
          </field>
          <field>
            <name>FB25</name>
            <bitOffset>25</bitOffset>
            <bitWidth>1</bitWidth>
          </field>
          <field>
            <name>FB26</name>
            <bitOffset>26</bitOffset>
            <bitWidth>1</bitWidth>
          </field>
          <field>
            <name>FB27</name>
            <bitOffset>27</bitOffset>
            <bitWidth>1</bitWidth>
          </field>
          <field>
            <name>FB28</name>
            <bitOffset>28</bitOffset>
            <bitWidth>1</bitWidth>
          </field>
          <field>
            <name>FB29</name>
            <bitOffset>29</bitOffset>
            <bitWidth>1</bitWidth>
          </field>
          <field>
            <name>FB30</name>
            <bitOffset>30</bitOffset>
            <bitWidth>1</bitWidth>
          </field>
          <field>
            <name>FB31</name>
            <bitOffset>31</bitOffset>
            <bitWidth>1</bitWidth>
          </field>
        </fields>
      </register>
      <register>
        <name>sFilterRegister.3.FR2</name>
        <addressOffset>0x25c</addressOffset>
        <size>0x20</size>
        <fields>
          <field>
            <name>FB0</name>
            <bitOffset>0</bitOffset>
            <bitWidth>1</bitWidth>
          </field>
          <field>
            <name>FB1</name>
            <bitOffset>1</bitOffset>
            <bitWidth>1</bitWidth>
          </field>
          <field>
            <name>FB2</name>
            <bitOffset>2</bitOffset>
            <bitWidth>1</bitWidth>
          </field>
          <field>
            <name>FB3</name>
            <bitOffset>3</bitOffset>
            <bitWidth>1</bitWidth>
          </field>
          <field>
            <name>FB4</name>
            <bitOffset>4</bitOffset>
            <bitWidth>1</bitWidth>
          </field>
          <field>
            <name>FB5</name>
            <bitOffset>5</bitOffset>
            <bitWidth>1</bitWidth>
          </field>
          <field>
            <name>FB6</name>
            <bitOffset>6</bitOffset>
            <bitWidth>1</bitWidth>
          </field>
          <field>
            <name>FB7</name>
            <bitOffset>7</bitOffset>
            <bitWidth>1</bitWidth>
          </field>
          <field>
            <name>FB8</name>
            <bitOffset>8</bitOffset>
            <bitWidth>1</bitWidth>
          </field>
          <field>
            <name>FB9</name>
            <bitOffset>9</bitOffset>
            <bitWidth>1</bitWidth>
          </field>
          <field>
            <name>FB10</name>
            <bitOffset>10</bitOffset>
            <bitWidth>1</bitWidth>
          </field>
          <field>
            <name>FB11</name>
            <bitOffset>11</bitOffset>
            <bitWidth>1</bitWidth>
          </field>
          <field>
            <name>FB12</name>
            <bitOffset>12</bitOffset>
            <bitWidth>1</bitWidth>
          </field>
          <field>
            <name>FB13</name>
            <bitOffset>13</bitOffset>
            <bitWidth>1</bitWidth>
          </field>
          <field>
            <name>FB14</name>
            <bitOffset>14</bitOffset>
            <bitWidth>1</bitWidth>
          </field>
          <field>
            <name>FB15</name>
            <bitOffset>15</bitOffset>
            <bitWidth>1</bitWidth>
          </field>
          <field>
            <name>FB16</name>
            <bitOffset>16</bitOffset>
            <bitWidth>1</bitWidth>
          </field>
          <field>
            <name>FB17</name>
            <bitOffset>17</bitOffset>
            <bitWidth>1</bitWidth>
          </field>
          <field>
            <name>FB18</name>
            <bitOffset>18</bitOffset>
            <bitWidth>1</bitWidth>
          </field>
          <field>
            <name>FB19</name>
            <bitOffset>19</bitOffset>
            <bitWidth>1</bitWidth>
          </field>
          <field>
            <name>FB20</name>
            <bitOffset>20</bitOffset>
            <bitWidth>1</bitWidth>
          </field>
          <field>
            <name>FB21</name>
            <bitOffset>21</bitOffset>
            <bitWidth>1</bitWidth>
          </field>
          <field>
            <name>FB22</name>
            <bitOffset>22</bitOffset>
            <bitWidth>1</bitWidth>
          </field>
          <field>
            <name>FB23</name>
            <bitOffset>23</bitOffset>
            <bitWidth>1</bitWidth>
          </field>
          <field>
            <name>FB24</name>
            <bitOffset>24</bitOffset>
            <bitWidth>1</bitWidth>
          </field>
          <field>
            <name>FB25</name>
            <bitOffset>25</bitOffset>
            <bitWidth>1</bitWidth>
          </field>
          <field>
            <name>FB26</name>
            <bitOffset>26</bitOffset>
            <bitWidth>1</bitWidth>
          </field>
          <field>
            <name>FB27</name>
            <bitOffset>27</bitOffset>
            <bitWidth>1</bitWidth>
          </field>
          <field>
            <name>FB28</name>
            <bitOffset>28</bitOffset>
            <bitWidth>1</bitWidth>
          </field>
          <field>
            <name>FB29</name>
            <bitOffset>29</bitOffset>
            <bitWidth>1</bitWidth>
          </field>
          <field>
            <name>FB30</name>
            <bitOffset>30</bitOffset>
            <bitWidth>1</bitWidth>
          </field>
          <field>
            <name>FB31</name>
            <bitOffset>31</bitOffset>
            <bitWidth>1</bitWidth>
          </field>
        </fields>
      </register>
      <register>
        <name>sFilterRegister.4.FR1</name>
        <addressOffset>0x260</addressOffset>
        <size>0x20</size>
        <fields>
          <field>
            <name>FB0</name>
            <bitOffset>0</bitOffset>
            <bitWidth>1</bitWidth>
          </field>
          <field>
            <name>FB1</name>
            <bitOffset>1</bitOffset>
            <bitWidth>1</bitWidth>
          </field>
          <field>
            <name>FB2</name>
            <bitOffset>2</bitOffset>
            <bitWidth>1</bitWidth>
          </field>
          <field>
            <name>FB3</name>
            <bitOffset>3</bitOffset>
            <bitWidth>1</bitWidth>
          </field>
          <field>
            <name>FB4</name>
            <bitOffset>4</bitOffset>
            <bitWidth>1</bitWidth>
          </field>
          <field>
            <name>FB5</name>
            <bitOffset>5</bitOffset>
            <bitWidth>1</bitWidth>
          </field>
          <field>
            <name>FB6</name>
            <bitOffset>6</bitOffset>
            <bitWidth>1</bitWidth>
          </field>
          <field>
            <name>FB7</name>
            <bitOffset>7</bitOffset>
            <bitWidth>1</bitWidth>
          </field>
          <field>
            <name>FB8</name>
            <bitOffset>8</bitOffset>
            <bitWidth>1</bitWidth>
          </field>
          <field>
            <name>FB9</name>
            <bitOffset>9</bitOffset>
            <bitWidth>1</bitWidth>
          </field>
          <field>
            <name>FB10</name>
            <bitOffset>10</bitOffset>
            <bitWidth>1</bitWidth>
          </field>
          <field>
            <name>FB11</name>
            <bitOffset>11</bitOffset>
            <bitWidth>1</bitWidth>
          </field>
          <field>
            <name>FB12</name>
            <bitOffset>12</bitOffset>
            <bitWidth>1</bitWidth>
          </field>
          <field>
            <name>FB13</name>
            <bitOffset>13</bitOffset>
            <bitWidth>1</bitWidth>
          </field>
          <field>
            <name>FB14</name>
            <bitOffset>14</bitOffset>
            <bitWidth>1</bitWidth>
          </field>
          <field>
            <name>FB15</name>
            <bitOffset>15</bitOffset>
            <bitWidth>1</bitWidth>
          </field>
          <field>
            <name>FB16</name>
            <bitOffset>16</bitOffset>
            <bitWidth>1</bitWidth>
          </field>
          <field>
            <name>FB17</name>
            <bitOffset>17</bitOffset>
            <bitWidth>1</bitWidth>
          </field>
          <field>
            <name>FB18</name>
            <bitOffset>18</bitOffset>
            <bitWidth>1</bitWidth>
          </field>
          <field>
            <name>FB19</name>
            <bitOffset>19</bitOffset>
            <bitWidth>1</bitWidth>
          </field>
          <field>
            <name>FB20</name>
            <bitOffset>20</bitOffset>
            <bitWidth>1</bitWidth>
          </field>
          <field>
            <name>FB21</name>
            <bitOffset>21</bitOffset>
            <bitWidth>1</bitWidth>
          </field>
          <field>
            <name>FB22</name>
            <bitOffset>22</bitOffset>
            <bitWidth>1</bitWidth>
          </field>
          <field>
            <name>FB23</name>
            <bitOffset>23</bitOffset>
            <bitWidth>1</bitWidth>
          </field>
          <field>
            <name>FB24</name>
            <bitOffset>24</bitOffset>
            <bitWidth>1</bitWidth>
          </field>
          <field>
            <name>FB25</name>
            <bitOffset>25</bitOffset>
            <bitWidth>1</bitWidth>
          </field>
          <field>
            <name>FB26</name>
            <bitOffset>26</bitOffset>
            <bitWidth>1</bitWidth>
          </field>
          <field>
            <name>FB27</name>
            <bitOffset>27</bitOffset>
            <bitWidth>1</bitWidth>
          </field>
          <field>
            <name>FB28</name>
            <bitOffset>28</bitOffset>
            <bitWidth>1</bitWidth>
          </field>
          <field>
            <name>FB29</name>
            <bitOffset>29</bitOffset>
            <bitWidth>1</bitWidth>
          </field>
          <field>
            <name>FB30</name>
            <bitOffset>30</bitOffset>
            <bitWidth>1</bitWidth>
          </field>
          <field>
            <name>FB31</name>
            <bitOffset>31</bitOffset>
            <bitWidth>1</bitWidth>
          </field>
        </fields>
      </register>
      <register>
        <name>sFilterRegister.4.FR2</name>
        <addressOffset>0x264</addressOffset>
        <size>0x20</size>
        <fields>
          <field>
            <name>FB0</name>
            <bitOffset>0</bitOffset>
            <bitWidth>1</bitWidth>
          </field>
          <field>
            <name>FB1</name>
            <bitOffset>1</bitOffset>
            <bitWidth>1</bitWidth>
          </field>
          <field>
            <name>FB2</name>
            <bitOffset>2</bitOffset>
            <bitWidth>1</bitWidth>
          </field>
          <field>
            <name>FB3</name>
            <bitOffset>3</bitOffset>
            <bitWidth>1</bitWidth>
          </field>
          <field>
            <name>FB4</name>
            <bitOffset>4</bitOffset>
            <bitWidth>1</bitWidth>
          </field>
          <field>
            <name>FB5</name>
            <bitOffset>5</bitOffset>
            <bitWidth>1</bitWidth>
          </field>
          <field>
            <name>FB6</name>
            <bitOffset>6</bitOffset>
            <bitWidth>1</bitWidth>
          </field>
          <field>
            <name>FB7</name>
            <bitOffset>7</bitOffset>
            <bitWidth>1</bitWidth>
          </field>
          <field>
            <name>FB8</name>
            <bitOffset>8</bitOffset>
            <bitWidth>1</bitWidth>
          </field>
          <field>
            <name>FB9</name>
            <bitOffset>9</bitOffset>
            <bitWidth>1</bitWidth>
          </field>
          <field>
            <name>FB10</name>
            <bitOffset>10</bitOffset>
            <bitWidth>1</bitWidth>
          </field>
          <field>
            <name>FB11</name>
            <bitOffset>11</bitOffset>
            <bitWidth>1</bitWidth>
          </field>
          <field>
            <name>FB12</name>
            <bitOffset>12</bitOffset>
            <bitWidth>1</bitWidth>
          </field>
          <field>
            <name>FB13</name>
            <bitOffset>13</bitOffset>
            <bitWidth>1</bitWidth>
          </field>
          <field>
            <name>FB14</name>
            <bitOffset>14</bitOffset>
            <bitWidth>1</bitWidth>
          </field>
          <field>
            <name>FB15</name>
            <bitOffset>15</bitOffset>
            <bitWidth>1</bitWidth>
          </field>
          <field>
            <name>FB16</name>
            <bitOffset>16</bitOffset>
            <bitWidth>1</bitWidth>
          </field>
          <field>
            <name>FB17</name>
            <bitOffset>17</bitOffset>
            <bitWidth>1</bitWidth>
          </field>
          <field>
            <name>FB18</name>
            <bitOffset>18</bitOffset>
            <bitWidth>1</bitWidth>
          </field>
          <field>
            <name>FB19</name>
            <bitOffset>19</bitOffset>
            <bitWidth>1</bitWidth>
          </field>
          <field>
            <name>FB20</name>
            <bitOffset>20</bitOffset>
            <bitWidth>1</bitWidth>
          </field>
          <field>
            <name>FB21</name>
            <bitOffset>21</bitOffset>
            <bitWidth>1</bitWidth>
          </field>
          <field>
            <name>FB22</name>
            <bitOffset>22</bitOffset>
            <bitWidth>1</bitWidth>
          </field>
          <field>
            <name>FB23</name>
            <bitOffset>23</bitOffset>
            <bitWidth>1</bitWidth>
          </field>
          <field>
            <name>FB24</name>
            <bitOffset>24</bitOffset>
            <bitWidth>1</bitWidth>
          </field>
          <field>
            <name>FB25</name>
            <bitOffset>25</bitOffset>
            <bitWidth>1</bitWidth>
          </field>
          <field>
            <name>FB26</name>
            <bitOffset>26</bitOffset>
            <bitWidth>1</bitWidth>
          </field>
          <field>
            <name>FB27</name>
            <bitOffset>27</bitOffset>
            <bitWidth>1</bitWidth>
          </field>
          <field>
            <name>FB28</name>
            <bitOffset>28</bitOffset>
            <bitWidth>1</bitWidth>
          </field>
          <field>
            <name>FB29</name>
            <bitOffset>29</bitOffset>
            <bitWidth>1</bitWidth>
          </field>
          <field>
            <name>FB30</name>
            <bitOffset>30</bitOffset>
            <bitWidth>1</bitWidth>
          </field>
          <field>
            <name>FB31</name>
            <bitOffset>31</bitOffset>
            <bitWidth>1</bitWidth>
          </field>
        </fields>
      </register>
      <register>
        <name>sFilterRegister.5.FR1</name>
        <addressOffset>0x268</addressOffset>
        <size>0x20</size>
        <fields>
          <field>
            <name>FB0</name>
            <bitOffset>0</bitOffset>
            <bitWidth>1</bitWidth>
          </field>
          <field>
            <name>FB1</name>
            <bitOffset>1</bitOffset>
            <bitWidth>1</bitWidth>
          </field>
          <field>
            <name>FB2</name>
            <bitOffset>2</bitOffset>
            <bitWidth>1</bitWidth>
          </field>
          <field>
            <name>FB3</name>
            <bitOffset>3</bitOffset>
            <bitWidth>1</bitWidth>
          </field>
          <field>
            <name>FB4</name>
            <bitOffset>4</bitOffset>
            <bitWidth>1</bitWidth>
          </field>
          <field>
            <name>FB5</name>
            <bitOffset>5</bitOffset>
            <bitWidth>1</bitWidth>
          </field>
          <field>
            <name>FB6</name>
            <bitOffset>6</bitOffset>
            <bitWidth>1</bitWidth>
          </field>
          <field>
            <name>FB7</name>
            <bitOffset>7</bitOffset>
            <bitWidth>1</bitWidth>
          </field>
          <field>
            <name>FB8</name>
            <bitOffset>8</bitOffset>
            <bitWidth>1</bitWidth>
          </field>
          <field>
            <name>FB9</name>
            <bitOffset>9</bitOffset>
            <bitWidth>1</bitWidth>
          </field>
          <field>
            <name>FB10</name>
            <bitOffset>10</bitOffset>
            <bitWidth>1</bitWidth>
          </field>
          <field>
            <name>FB11</name>
            <bitOffset>11</bitOffset>
            <bitWidth>1</bitWidth>
          </field>
          <field>
            <name>FB12</name>
            <bitOffset>12</bitOffset>
            <bitWidth>1</bitWidth>
          </field>
          <field>
            <name>FB13</name>
            <bitOffset>13</bitOffset>
            <bitWidth>1</bitWidth>
          </field>
          <field>
            <name>FB14</name>
            <bitOffset>14</bitOffset>
            <bitWidth>1</bitWidth>
          </field>
          <field>
            <name>FB15</name>
            <bitOffset>15</bitOffset>
            <bitWidth>1</bitWidth>
          </field>
          <field>
            <name>FB16</name>
            <bitOffset>16</bitOffset>
            <bitWidth>1</bitWidth>
          </field>
          <field>
            <name>FB17</name>
            <bitOffset>17</bitOffset>
            <bitWidth>1</bitWidth>
          </field>
          <field>
            <name>FB18</name>
            <bitOffset>18</bitOffset>
            <bitWidth>1</bitWidth>
          </field>
          <field>
            <name>FB19</name>
            <bitOffset>19</bitOffset>
            <bitWidth>1</bitWidth>
          </field>
          <field>
            <name>FB20</name>
            <bitOffset>20</bitOffset>
            <bitWidth>1</bitWidth>
          </field>
          <field>
            <name>FB21</name>
            <bitOffset>21</bitOffset>
            <bitWidth>1</bitWidth>
          </field>
          <field>
            <name>FB22</name>
            <bitOffset>22</bitOffset>
            <bitWidth>1</bitWidth>
          </field>
          <field>
            <name>FB23</name>
            <bitOffset>23</bitOffset>
            <bitWidth>1</bitWidth>
          </field>
          <field>
            <name>FB24</name>
            <bitOffset>24</bitOffset>
            <bitWidth>1</bitWidth>
          </field>
          <field>
            <name>FB25</name>
            <bitOffset>25</bitOffset>
            <bitWidth>1</bitWidth>
          </field>
          <field>
            <name>FB26</name>
            <bitOffset>26</bitOffset>
            <bitWidth>1</bitWidth>
          </field>
          <field>
            <name>FB27</name>
            <bitOffset>27</bitOffset>
            <bitWidth>1</bitWidth>
          </field>
          <field>
            <name>FB28</name>
            <bitOffset>28</bitOffset>
            <bitWidth>1</bitWidth>
          </field>
          <field>
            <name>FB29</name>
            <bitOffset>29</bitOffset>
            <bitWidth>1</bitWidth>
          </field>
          <field>
            <name>FB30</name>
            <bitOffset>30</bitOffset>
            <bitWidth>1</bitWidth>
          </field>
          <field>
            <name>FB31</name>
            <bitOffset>31</bitOffset>
            <bitWidth>1</bitWidth>
          </field>
        </fields>
      </register>
      <register>
        <name>sFilterRegister.5.FR2</name>
        <addressOffset>0x26c</addressOffset>
        <size>0x20</size>
        <fields>
          <field>
            <name>FB0</name>
            <bitOffset>0</bitOffset>
            <bitWidth>1</bitWidth>
          </field>
          <field>
            <name>FB1</name>
            <bitOffset>1</bitOffset>
            <bitWidth>1</bitWidth>
          </field>
          <field>
            <name>FB2</name>
            <bitOffset>2</bitOffset>
            <bitWidth>1</bitWidth>
          </field>
          <field>
            <name>FB3</name>
            <bitOffset>3</bitOffset>
            <bitWidth>1</bitWidth>
          </field>
          <field>
            <name>FB4</name>
            <bitOffset>4</bitOffset>
            <bitWidth>1</bitWidth>
          </field>
          <field>
            <name>FB5</name>
            <bitOffset>5</bitOffset>
            <bitWidth>1</bitWidth>
          </field>
          <field>
            <name>FB6</name>
            <bitOffset>6</bitOffset>
            <bitWidth>1</bitWidth>
          </field>
          <field>
            <name>FB7</name>
            <bitOffset>7</bitOffset>
            <bitWidth>1</bitWidth>
          </field>
          <field>
            <name>FB8</name>
            <bitOffset>8</bitOffset>
            <bitWidth>1</bitWidth>
          </field>
          <field>
            <name>FB9</name>
            <bitOffset>9</bitOffset>
            <bitWidth>1</bitWidth>
          </field>
          <field>
            <name>FB10</name>
            <bitOffset>10</bitOffset>
            <bitWidth>1</bitWidth>
          </field>
          <field>
            <name>FB11</name>
            <bitOffset>11</bitOffset>
            <bitWidth>1</bitWidth>
          </field>
          <field>
            <name>FB12</name>
            <bitOffset>12</bitOffset>
            <bitWidth>1</bitWidth>
          </field>
          <field>
            <name>FB13</name>
            <bitOffset>13</bitOffset>
            <bitWidth>1</bitWidth>
          </field>
          <field>
            <name>FB14</name>
            <bitOffset>14</bitOffset>
            <bitWidth>1</bitWidth>
          </field>
          <field>
            <name>FB15</name>
            <bitOffset>15</bitOffset>
            <bitWidth>1</bitWidth>
          </field>
          <field>
            <name>FB16</name>
            <bitOffset>16</bitOffset>
            <bitWidth>1</bitWidth>
          </field>
          <field>
            <name>FB17</name>
            <bitOffset>17</bitOffset>
            <bitWidth>1</bitWidth>
          </field>
          <field>
            <name>FB18</name>
            <bitOffset>18</bitOffset>
            <bitWidth>1</bitWidth>
          </field>
          <field>
            <name>FB19</name>
            <bitOffset>19</bitOffset>
            <bitWidth>1</bitWidth>
          </field>
          <field>
            <name>FB20</name>
            <bitOffset>20</bitOffset>
            <bitWidth>1</bitWidth>
          </field>
          <field>
            <name>FB21</name>
            <bitOffset>21</bitOffset>
            <bitWidth>1</bitWidth>
          </field>
          <field>
            <name>FB22</name>
            <bitOffset>22</bitOffset>
            <bitWidth>1</bitWidth>
          </field>
          <field>
            <name>FB23</name>
            <bitOffset>23</bitOffset>
            <bitWidth>1</bitWidth>
          </field>
          <field>
            <name>FB24</name>
            <bitOffset>24</bitOffset>
            <bitWidth>1</bitWidth>
          </field>
          <field>
            <name>FB25</name>
            <bitOffset>25</bitOffset>
            <bitWidth>1</bitWidth>
          </field>
          <field>
            <name>FB26</name>
            <bitOffset>26</bitOffset>
            <bitWidth>1</bitWidth>
          </field>
          <field>
            <name>FB27</name>
            <bitOffset>27</bitOffset>
            <bitWidth>1</bitWidth>
          </field>
          <field>
            <name>FB28</name>
            <bitOffset>28</bitOffset>
            <bitWidth>1</bitWidth>
          </field>
          <field>
            <name>FB29</name>
            <bitOffset>29</bitOffset>
            <bitWidth>1</bitWidth>
          </field>
          <field>
            <name>FB30</name>
            <bitOffset>30</bitOffset>
            <bitWidth>1</bitWidth>
          </field>
          <field>
            <name>FB31</name>
            <bitOffset>31</bitOffset>
            <bitWidth>1</bitWidth>
          </field>
        </fields>
      </register>
      <register>
        <name>sFilterRegister.6.FR1</name>
        <addressOffset>0x270</addressOffset>
        <size>0x20</size>
        <fields>
          <field>
            <name>FB0</name>
            <bitOffset>0</bitOffset>
            <bitWidth>1</bitWidth>
          </field>
          <field>
            <name>FB1</name>
            <bitOffset>1</bitOffset>
            <bitWidth>1</bitWidth>
          </field>
          <field>
            <name>FB2</name>
            <bitOffset>2</bitOffset>
            <bitWidth>1</bitWidth>
          </field>
          <field>
            <name>FB3</name>
            <bitOffset>3</bitOffset>
            <bitWidth>1</bitWidth>
          </field>
          <field>
            <name>FB4</name>
            <bitOffset>4</bitOffset>
            <bitWidth>1</bitWidth>
          </field>
          <field>
            <name>FB5</name>
            <bitOffset>5</bitOffset>
            <bitWidth>1</bitWidth>
          </field>
          <field>
            <name>FB6</name>
            <bitOffset>6</bitOffset>
            <bitWidth>1</bitWidth>
          </field>
          <field>
            <name>FB7</name>
            <bitOffset>7</bitOffset>
            <bitWidth>1</bitWidth>
          </field>
          <field>
            <name>FB8</name>
            <bitOffset>8</bitOffset>
            <bitWidth>1</bitWidth>
          </field>
          <field>
            <name>FB9</name>
            <bitOffset>9</bitOffset>
            <bitWidth>1</bitWidth>
          </field>
          <field>
            <name>FB10</name>
            <bitOffset>10</bitOffset>
            <bitWidth>1</bitWidth>
          </field>
          <field>
            <name>FB11</name>
            <bitOffset>11</bitOffset>
            <bitWidth>1</bitWidth>
          </field>
          <field>
            <name>FB12</name>
            <bitOffset>12</bitOffset>
            <bitWidth>1</bitWidth>
          </field>
          <field>
            <name>FB13</name>
            <bitOffset>13</bitOffset>
            <bitWidth>1</bitWidth>
          </field>
          <field>
            <name>FB14</name>
            <bitOffset>14</bitOffset>
            <bitWidth>1</bitWidth>
          </field>
          <field>
            <name>FB15</name>
            <bitOffset>15</bitOffset>
            <bitWidth>1</bitWidth>
          </field>
          <field>
            <name>FB16</name>
            <bitOffset>16</bitOffset>
            <bitWidth>1</bitWidth>
          </field>
          <field>
            <name>FB17</name>
            <bitOffset>17</bitOffset>
            <bitWidth>1</bitWidth>
          </field>
          <field>
            <name>FB18</name>
            <bitOffset>18</bitOffset>
            <bitWidth>1</bitWidth>
          </field>
          <field>
            <name>FB19</name>
            <bitOffset>19</bitOffset>
            <bitWidth>1</bitWidth>
          </field>
          <field>
            <name>FB20</name>
            <bitOffset>20</bitOffset>
            <bitWidth>1</bitWidth>
          </field>
          <field>
            <name>FB21</name>
            <bitOffset>21</bitOffset>
            <bitWidth>1</bitWidth>
          </field>
          <field>
            <name>FB22</name>
            <bitOffset>22</bitOffset>
            <bitWidth>1</bitWidth>
          </field>
          <field>
            <name>FB23</name>
            <bitOffset>23</bitOffset>
            <bitWidth>1</bitWidth>
          </field>
          <field>
            <name>FB24</name>
            <bitOffset>24</bitOffset>
            <bitWidth>1</bitWidth>
          </field>
          <field>
            <name>FB25</name>
            <bitOffset>25</bitOffset>
            <bitWidth>1</bitWidth>
          </field>
          <field>
            <name>FB26</name>
            <bitOffset>26</bitOffset>
            <bitWidth>1</bitWidth>
          </field>
          <field>
            <name>FB27</name>
            <bitOffset>27</bitOffset>
            <bitWidth>1</bitWidth>
          </field>
          <field>
            <name>FB28</name>
            <bitOffset>28</bitOffset>
            <bitWidth>1</bitWidth>
          </field>
          <field>
            <name>FB29</name>
            <bitOffset>29</bitOffset>
            <bitWidth>1</bitWidth>
          </field>
          <field>
            <name>FB30</name>
            <bitOffset>30</bitOffset>
            <bitWidth>1</bitWidth>
          </field>
          <field>
            <name>FB31</name>
            <bitOffset>31</bitOffset>
            <bitWidth>1</bitWidth>
          </field>
        </fields>
      </register>
      <register>
        <name>sFilterRegister.6.FR2</name>
        <addressOffset>0x274</addressOffset>
        <size>0x20</size>
        <fields>
          <field>
            <name>FB0</name>
            <bitOffset>0</bitOffset>
            <bitWidth>1</bitWidth>
          </field>
          <field>
            <name>FB1</name>
            <bitOffset>1</bitOffset>
            <bitWidth>1</bitWidth>
          </field>
          <field>
            <name>FB2</name>
            <bitOffset>2</bitOffset>
            <bitWidth>1</bitWidth>
          </field>
          <field>
            <name>FB3</name>
            <bitOffset>3</bitOffset>
            <bitWidth>1</bitWidth>
          </field>
          <field>
            <name>FB4</name>
            <bitOffset>4</bitOffset>
            <bitWidth>1</bitWidth>
          </field>
          <field>
            <name>FB5</name>
            <bitOffset>5</bitOffset>
            <bitWidth>1</bitWidth>
          </field>
          <field>
            <name>FB6</name>
            <bitOffset>6</bitOffset>
            <bitWidth>1</bitWidth>
          </field>
          <field>
            <name>FB7</name>
            <bitOffset>7</bitOffset>
            <bitWidth>1</bitWidth>
          </field>
          <field>
            <name>FB8</name>
            <bitOffset>8</bitOffset>
            <bitWidth>1</bitWidth>
          </field>
          <field>
            <name>FB9</name>
            <bitOffset>9</bitOffset>
            <bitWidth>1</bitWidth>
          </field>
          <field>
            <name>FB10</name>
            <bitOffset>10</bitOffset>
            <bitWidth>1</bitWidth>
          </field>
          <field>
            <name>FB11</name>
            <bitOffset>11</bitOffset>
            <bitWidth>1</bitWidth>
          </field>
          <field>
            <name>FB12</name>
            <bitOffset>12</bitOffset>
            <bitWidth>1</bitWidth>
          </field>
          <field>
            <name>FB13</name>
            <bitOffset>13</bitOffset>
            <bitWidth>1</bitWidth>
          </field>
          <field>
            <name>FB14</name>
            <bitOffset>14</bitOffset>
            <bitWidth>1</bitWidth>
          </field>
          <field>
            <name>FB15</name>
            <bitOffset>15</bitOffset>
            <bitWidth>1</bitWidth>
          </field>
          <field>
            <name>FB16</name>
            <bitOffset>16</bitOffset>
            <bitWidth>1</bitWidth>
          </field>
          <field>
            <name>FB17</name>
            <bitOffset>17</bitOffset>
            <bitWidth>1</bitWidth>
          </field>
          <field>
            <name>FB18</name>
            <bitOffset>18</bitOffset>
            <bitWidth>1</bitWidth>
          </field>
          <field>
            <name>FB19</name>
            <bitOffset>19</bitOffset>
            <bitWidth>1</bitWidth>
          </field>
          <field>
            <name>FB20</name>
            <bitOffset>20</bitOffset>
            <bitWidth>1</bitWidth>
          </field>
          <field>
            <name>FB21</name>
            <bitOffset>21</bitOffset>
            <bitWidth>1</bitWidth>
          </field>
          <field>
            <name>FB22</name>
            <bitOffset>22</bitOffset>
            <bitWidth>1</bitWidth>
          </field>
          <field>
            <name>FB23</name>
            <bitOffset>23</bitOffset>
            <bitWidth>1</bitWidth>
          </field>
          <field>
            <name>FB24</name>
            <bitOffset>24</bitOffset>
            <bitWidth>1</bitWidth>
          </field>
          <field>
            <name>FB25</name>
            <bitOffset>25</bitOffset>
            <bitWidth>1</bitWidth>
          </field>
          <field>
            <name>FB26</name>
            <bitOffset>26</bitOffset>
            <bitWidth>1</bitWidth>
          </field>
          <field>
            <name>FB27</name>
            <bitOffset>27</bitOffset>
            <bitWidth>1</bitWidth>
          </field>
          <field>
            <name>FB28</name>
            <bitOffset>28</bitOffset>
            <bitWidth>1</bitWidth>
          </field>
          <field>
            <name>FB29</name>
            <bitOffset>29</bitOffset>
            <bitWidth>1</bitWidth>
          </field>
          <field>
            <name>FB30</name>
            <bitOffset>30</bitOffset>
            <bitWidth>1</bitWidth>
          </field>
          <field>
            <name>FB31</name>
            <bitOffset>31</bitOffset>
            <bitWidth>1</bitWidth>
          </field>
        </fields>
      </register>
      <register>
        <name>sFilterRegister.7.FR1</name>
        <addressOffset>0x278</addressOffset>
        <size>0x20</size>
        <fields>
          <field>
            <name>FB0</name>
            <bitOffset>0</bitOffset>
            <bitWidth>1</bitWidth>
          </field>
          <field>
            <name>FB1</name>
            <bitOffset>1</bitOffset>
            <bitWidth>1</bitWidth>
          </field>
          <field>
            <name>FB2</name>
            <bitOffset>2</bitOffset>
            <bitWidth>1</bitWidth>
          </field>
          <field>
            <name>FB3</name>
            <bitOffset>3</bitOffset>
            <bitWidth>1</bitWidth>
          </field>
          <field>
            <name>FB4</name>
            <bitOffset>4</bitOffset>
            <bitWidth>1</bitWidth>
          </field>
          <field>
            <name>FB5</name>
            <bitOffset>5</bitOffset>
            <bitWidth>1</bitWidth>
          </field>
          <field>
            <name>FB6</name>
            <bitOffset>6</bitOffset>
            <bitWidth>1</bitWidth>
          </field>
          <field>
            <name>FB7</name>
            <bitOffset>7</bitOffset>
            <bitWidth>1</bitWidth>
          </field>
          <field>
            <name>FB8</name>
            <bitOffset>8</bitOffset>
            <bitWidth>1</bitWidth>
          </field>
          <field>
            <name>FB9</name>
            <bitOffset>9</bitOffset>
            <bitWidth>1</bitWidth>
          </field>
          <field>
            <name>FB10</name>
            <bitOffset>10</bitOffset>
            <bitWidth>1</bitWidth>
          </field>
          <field>
            <name>FB11</name>
            <bitOffset>11</bitOffset>
            <bitWidth>1</bitWidth>
          </field>
          <field>
            <name>FB12</name>
            <bitOffset>12</bitOffset>
            <bitWidth>1</bitWidth>
          </field>
          <field>
            <name>FB13</name>
            <bitOffset>13</bitOffset>
            <bitWidth>1</bitWidth>
          </field>
          <field>
            <name>FB14</name>
            <bitOffset>14</bitOffset>
            <bitWidth>1</bitWidth>
          </field>
          <field>
            <name>FB15</name>
            <bitOffset>15</bitOffset>
            <bitWidth>1</bitWidth>
          </field>
          <field>
            <name>FB16</name>
            <bitOffset>16</bitOffset>
            <bitWidth>1</bitWidth>
          </field>
          <field>
            <name>FB17</name>
            <bitOffset>17</bitOffset>
            <bitWidth>1</bitWidth>
          </field>
          <field>
            <name>FB18</name>
            <bitOffset>18</bitOffset>
            <bitWidth>1</bitWidth>
          </field>
          <field>
            <name>FB19</name>
            <bitOffset>19</bitOffset>
            <bitWidth>1</bitWidth>
          </field>
          <field>
            <name>FB20</name>
            <bitOffset>20</bitOffset>
            <bitWidth>1</bitWidth>
          </field>
          <field>
            <name>FB21</name>
            <bitOffset>21</bitOffset>
            <bitWidth>1</bitWidth>
          </field>
          <field>
            <name>FB22</name>
            <bitOffset>22</bitOffset>
            <bitWidth>1</bitWidth>
          </field>
          <field>
            <name>FB23</name>
            <bitOffset>23</bitOffset>
            <bitWidth>1</bitWidth>
          </field>
          <field>
            <name>FB24</name>
            <bitOffset>24</bitOffset>
            <bitWidth>1</bitWidth>
          </field>
          <field>
            <name>FB25</name>
            <bitOffset>25</bitOffset>
            <bitWidth>1</bitWidth>
          </field>
          <field>
            <name>FB26</name>
            <bitOffset>26</bitOffset>
            <bitWidth>1</bitWidth>
          </field>
          <field>
            <name>FB27</name>
            <bitOffset>27</bitOffset>
            <bitWidth>1</bitWidth>
          </field>
          <field>
            <name>FB28</name>
            <bitOffset>28</bitOffset>
            <bitWidth>1</bitWidth>
          </field>
          <field>
            <name>FB29</name>
            <bitOffset>29</bitOffset>
            <bitWidth>1</bitWidth>
          </field>
          <field>
            <name>FB30</name>
            <bitOffset>30</bitOffset>
            <bitWidth>1</bitWidth>
          </field>
          <field>
            <name>FB31</name>
            <bitOffset>31</bitOffset>
            <bitWidth>1</bitWidth>
          </field>
        </fields>
      </register>
      <register>
        <name>sFilterRegister.7.FR2</name>
        <addressOffset>0x27c</addressOffset>
        <size>0x20</size>
        <fields>
          <field>
            <name>FB0</name>
            <bitOffset>0</bitOffset>
            <bitWidth>1</bitWidth>
          </field>
          <field>
            <name>FB1</name>
            <bitOffset>1</bitOffset>
            <bitWidth>1</bitWidth>
          </field>
          <field>
            <name>FB2</name>
            <bitOffset>2</bitOffset>
            <bitWidth>1</bitWidth>
          </field>
          <field>
            <name>FB3</name>
            <bitOffset>3</bitOffset>
            <bitWidth>1</bitWidth>
          </field>
          <field>
            <name>FB4</name>
            <bitOffset>4</bitOffset>
            <bitWidth>1</bitWidth>
          </field>
          <field>
            <name>FB5</name>
            <bitOffset>5</bitOffset>
            <bitWidth>1</bitWidth>
          </field>
          <field>
            <name>FB6</name>
            <bitOffset>6</bitOffset>
            <bitWidth>1</bitWidth>
          </field>
          <field>
            <name>FB7</name>
            <bitOffset>7</bitOffset>
            <bitWidth>1</bitWidth>
          </field>
          <field>
            <name>FB8</name>
            <bitOffset>8</bitOffset>
            <bitWidth>1</bitWidth>
          </field>
          <field>
            <name>FB9</name>
            <bitOffset>9</bitOffset>
            <bitWidth>1</bitWidth>
          </field>
          <field>
            <name>FB10</name>
            <bitOffset>10</bitOffset>
            <bitWidth>1</bitWidth>
          </field>
          <field>
            <name>FB11</name>
            <bitOffset>11</bitOffset>
            <bitWidth>1</bitWidth>
          </field>
          <field>
            <name>FB12</name>
            <bitOffset>12</bitOffset>
            <bitWidth>1</bitWidth>
          </field>
          <field>
            <name>FB13</name>
            <bitOffset>13</bitOffset>
            <bitWidth>1</bitWidth>
          </field>
          <field>
            <name>FB14</name>
            <bitOffset>14</bitOffset>
            <bitWidth>1</bitWidth>
          </field>
          <field>
            <name>FB15</name>
            <bitOffset>15</bitOffset>
            <bitWidth>1</bitWidth>
          </field>
          <field>
            <name>FB16</name>
            <bitOffset>16</bitOffset>
            <bitWidth>1</bitWidth>
          </field>
          <field>
            <name>FB17</name>
            <bitOffset>17</bitOffset>
            <bitWidth>1</bitWidth>
          </field>
          <field>
            <name>FB18</name>
            <bitOffset>18</bitOffset>
            <bitWidth>1</bitWidth>
          </field>
          <field>
            <name>FB19</name>
            <bitOffset>19</bitOffset>
            <bitWidth>1</bitWidth>
          </field>
          <field>
            <name>FB20</name>
            <bitOffset>20</bitOffset>
            <bitWidth>1</bitWidth>
          </field>
          <field>
            <name>FB21</name>
            <bitOffset>21</bitOffset>
            <bitWidth>1</bitWidth>
          </field>
          <field>
            <name>FB22</name>
            <bitOffset>22</bitOffset>
            <bitWidth>1</bitWidth>
          </field>
          <field>
            <name>FB23</name>
            <bitOffset>23</bitOffset>
            <bitWidth>1</bitWidth>
          </field>
          <field>
            <name>FB24</name>
            <bitOffset>24</bitOffset>
            <bitWidth>1</bitWidth>
          </field>
          <field>
            <name>FB25</name>
            <bitOffset>25</bitOffset>
            <bitWidth>1</bitWidth>
          </field>
          <field>
            <name>FB26</name>
            <bitOffset>26</bitOffset>
            <bitWidth>1</bitWidth>
          </field>
          <field>
            <name>FB27</name>
            <bitOffset>27</bitOffset>
            <bitWidth>1</bitWidth>
          </field>
          <field>
            <name>FB28</name>
            <bitOffset>28</bitOffset>
            <bitWidth>1</bitWidth>
          </field>
          <field>
            <name>FB29</name>
            <bitOffset>29</bitOffset>
            <bitWidth>1</bitWidth>
          </field>
          <field>
            <name>FB30</name>
            <bitOffset>30</bitOffset>
            <bitWidth>1</bitWidth>
          </field>
          <field>
            <name>FB31</name>
            <bitOffset>31</bitOffset>
            <bitWidth>1</bitWidth>
          </field>
        </fields>
      </register>
      <register>
        <name>sFilterRegister.8.FR1</name>
        <addressOffset>0x280</addressOffset>
        <size>0x20</size>
        <fields>
          <field>
            <name>FB0</name>
            <bitOffset>0</bitOffset>
            <bitWidth>1</bitWidth>
          </field>
          <field>
            <name>FB1</name>
            <bitOffset>1</bitOffset>
            <bitWidth>1</bitWidth>
          </field>
          <field>
            <name>FB2</name>
            <bitOffset>2</bitOffset>
            <bitWidth>1</bitWidth>
          </field>
          <field>
            <name>FB3</name>
            <bitOffset>3</bitOffset>
            <bitWidth>1</bitWidth>
          </field>
          <field>
            <name>FB4</name>
            <bitOffset>4</bitOffset>
            <bitWidth>1</bitWidth>
          </field>
          <field>
            <name>FB5</name>
            <bitOffset>5</bitOffset>
            <bitWidth>1</bitWidth>
          </field>
          <field>
            <name>FB6</name>
            <bitOffset>6</bitOffset>
            <bitWidth>1</bitWidth>
          </field>
          <field>
            <name>FB7</name>
            <bitOffset>7</bitOffset>
            <bitWidth>1</bitWidth>
          </field>
          <field>
            <name>FB8</name>
            <bitOffset>8</bitOffset>
            <bitWidth>1</bitWidth>
          </field>
          <field>
            <name>FB9</name>
            <bitOffset>9</bitOffset>
            <bitWidth>1</bitWidth>
          </field>
          <field>
            <name>FB10</name>
            <bitOffset>10</bitOffset>
            <bitWidth>1</bitWidth>
          </field>
          <field>
            <name>FB11</name>
            <bitOffset>11</bitOffset>
            <bitWidth>1</bitWidth>
          </field>
          <field>
            <name>FB12</name>
            <bitOffset>12</bitOffset>
            <bitWidth>1</bitWidth>
          </field>
          <field>
            <name>FB13</name>
            <bitOffset>13</bitOffset>
            <bitWidth>1</bitWidth>
          </field>
          <field>
            <name>FB14</name>
            <bitOffset>14</bitOffset>
            <bitWidth>1</bitWidth>
          </field>
          <field>
            <name>FB15</name>
            <bitOffset>15</bitOffset>
            <bitWidth>1</bitWidth>
          </field>
          <field>
            <name>FB16</name>
            <bitOffset>16</bitOffset>
            <bitWidth>1</bitWidth>
          </field>
          <field>
            <name>FB17</name>
            <bitOffset>17</bitOffset>
            <bitWidth>1</bitWidth>
          </field>
          <field>
            <name>FB18</name>
            <bitOffset>18</bitOffset>
            <bitWidth>1</bitWidth>
          </field>
          <field>
            <name>FB19</name>
            <bitOffset>19</bitOffset>
            <bitWidth>1</bitWidth>
          </field>
          <field>
            <name>FB20</name>
            <bitOffset>20</bitOffset>
            <bitWidth>1</bitWidth>
          </field>
          <field>
            <name>FB21</name>
            <bitOffset>21</bitOffset>
            <bitWidth>1</bitWidth>
          </field>
          <field>
            <name>FB22</name>
            <bitOffset>22</bitOffset>
            <bitWidth>1</bitWidth>
          </field>
          <field>
            <name>FB23</name>
            <bitOffset>23</bitOffset>
            <bitWidth>1</bitWidth>
          </field>
          <field>
            <name>FB24</name>
            <bitOffset>24</bitOffset>
            <bitWidth>1</bitWidth>
          </field>
          <field>
            <name>FB25</name>
            <bitOffset>25</bitOffset>
            <bitWidth>1</bitWidth>
          </field>
          <field>
            <name>FB26</name>
            <bitOffset>26</bitOffset>
            <bitWidth>1</bitWidth>
          </field>
          <field>
            <name>FB27</name>
            <bitOffset>27</bitOffset>
            <bitWidth>1</bitWidth>
          </field>
          <field>
            <name>FB28</name>
            <bitOffset>28</bitOffset>
            <bitWidth>1</bitWidth>
          </field>
          <field>
            <name>FB29</name>
            <bitOffset>29</bitOffset>
            <bitWidth>1</bitWidth>
          </field>
          <field>
            <name>FB30</name>
            <bitOffset>30</bitOffset>
            <bitWidth>1</bitWidth>
          </field>
          <field>
            <name>FB31</name>
            <bitOffset>31</bitOffset>
            <bitWidth>1</bitWidth>
          </field>
        </fields>
      </register>
      <register>
        <name>sFilterRegister.8.FR2</name>
        <addressOffset>0x284</addressOffset>
        <size>0x20</size>
        <fields>
          <field>
            <name>FB0</name>
            <bitOffset>0</bitOffset>
            <bitWidth>1</bitWidth>
          </field>
          <field>
            <name>FB1</name>
            <bitOffset>1</bitOffset>
            <bitWidth>1</bitWidth>
          </field>
          <field>
            <name>FB2</name>
            <bitOffset>2</bitOffset>
            <bitWidth>1</bitWidth>
          </field>
          <field>
            <name>FB3</name>
            <bitOffset>3</bitOffset>
            <bitWidth>1</bitWidth>
          </field>
          <field>
            <name>FB4</name>
            <bitOffset>4</bitOffset>
            <bitWidth>1</bitWidth>
          </field>
          <field>
            <name>FB5</name>
            <bitOffset>5</bitOffset>
            <bitWidth>1</bitWidth>
          </field>
          <field>
            <name>FB6</name>
            <bitOffset>6</bitOffset>
            <bitWidth>1</bitWidth>
          </field>
          <field>
            <name>FB7</name>
            <bitOffset>7</bitOffset>
            <bitWidth>1</bitWidth>
          </field>
          <field>
            <name>FB8</name>
            <bitOffset>8</bitOffset>
            <bitWidth>1</bitWidth>
          </field>
          <field>
            <name>FB9</name>
            <bitOffset>9</bitOffset>
            <bitWidth>1</bitWidth>
          </field>
          <field>
            <name>FB10</name>
            <bitOffset>10</bitOffset>
            <bitWidth>1</bitWidth>
          </field>
          <field>
            <name>FB11</name>
            <bitOffset>11</bitOffset>
            <bitWidth>1</bitWidth>
          </field>
          <field>
            <name>FB12</name>
            <bitOffset>12</bitOffset>
            <bitWidth>1</bitWidth>
          </field>
          <field>
            <name>FB13</name>
            <bitOffset>13</bitOffset>
            <bitWidth>1</bitWidth>
          </field>
          <field>
            <name>FB14</name>
            <bitOffset>14</bitOffset>
            <bitWidth>1</bitWidth>
          </field>
          <field>
            <name>FB15</name>
            <bitOffset>15</bitOffset>
            <bitWidth>1</bitWidth>
          </field>
          <field>
            <name>FB16</name>
            <bitOffset>16</bitOffset>
            <bitWidth>1</bitWidth>
          </field>
          <field>
            <name>FB17</name>
            <bitOffset>17</bitOffset>
            <bitWidth>1</bitWidth>
          </field>
          <field>
            <name>FB18</name>
            <bitOffset>18</bitOffset>
            <bitWidth>1</bitWidth>
          </field>
          <field>
            <name>FB19</name>
            <bitOffset>19</bitOffset>
            <bitWidth>1</bitWidth>
          </field>
          <field>
            <name>FB20</name>
            <bitOffset>20</bitOffset>
            <bitWidth>1</bitWidth>
          </field>
          <field>
            <name>FB21</name>
            <bitOffset>21</bitOffset>
            <bitWidth>1</bitWidth>
          </field>
          <field>
            <name>FB22</name>
            <bitOffset>22</bitOffset>
            <bitWidth>1</bitWidth>
          </field>
          <field>
            <name>FB23</name>
            <bitOffset>23</bitOffset>
            <bitWidth>1</bitWidth>
          </field>
          <field>
            <name>FB24</name>
            <bitOffset>24</bitOffset>
            <bitWidth>1</bitWidth>
          </field>
          <field>
            <name>FB25</name>
            <bitOffset>25</bitOffset>
            <bitWidth>1</bitWidth>
          </field>
          <field>
            <name>FB26</name>
            <bitOffset>26</bitOffset>
            <bitWidth>1</bitWidth>
          </field>
          <field>
            <name>FB27</name>
            <bitOffset>27</bitOffset>
            <bitWidth>1</bitWidth>
          </field>
          <field>
            <name>FB28</name>
            <bitOffset>28</bitOffset>
            <bitWidth>1</bitWidth>
          </field>
          <field>
            <name>FB29</name>
            <bitOffset>29</bitOffset>
            <bitWidth>1</bitWidth>
          </field>
          <field>
            <name>FB30</name>
            <bitOffset>30</bitOffset>
            <bitWidth>1</bitWidth>
          </field>
          <field>
            <name>FB31</name>
            <bitOffset>31</bitOffset>
            <bitWidth>1</bitWidth>
          </field>
        </fields>
      </register>
      <register>
        <name>sFilterRegister.9.FR1</name>
        <addressOffset>0x288</addressOffset>
        <size>0x20</size>
        <fields>
          <field>
            <name>FB0</name>
            <bitOffset>0</bitOffset>
            <bitWidth>1</bitWidth>
          </field>
          <field>
            <name>FB1</name>
            <bitOffset>1</bitOffset>
            <bitWidth>1</bitWidth>
          </field>
          <field>
            <name>FB2</name>
            <bitOffset>2</bitOffset>
            <bitWidth>1</bitWidth>
          </field>
          <field>
            <name>FB3</name>
            <bitOffset>3</bitOffset>
            <bitWidth>1</bitWidth>
          </field>
          <field>
            <name>FB4</name>
            <bitOffset>4</bitOffset>
            <bitWidth>1</bitWidth>
          </field>
          <field>
            <name>FB5</name>
            <bitOffset>5</bitOffset>
            <bitWidth>1</bitWidth>
          </field>
          <field>
            <name>FB6</name>
            <bitOffset>6</bitOffset>
            <bitWidth>1</bitWidth>
          </field>
          <field>
            <name>FB7</name>
            <bitOffset>7</bitOffset>
            <bitWidth>1</bitWidth>
          </field>
          <field>
            <name>FB8</name>
            <bitOffset>8</bitOffset>
            <bitWidth>1</bitWidth>
          </field>
          <field>
            <name>FB9</name>
            <bitOffset>9</bitOffset>
            <bitWidth>1</bitWidth>
          </field>
          <field>
            <name>FB10</name>
            <bitOffset>10</bitOffset>
            <bitWidth>1</bitWidth>
          </field>
          <field>
            <name>FB11</name>
            <bitOffset>11</bitOffset>
            <bitWidth>1</bitWidth>
          </field>
          <field>
            <name>FB12</name>
            <bitOffset>12</bitOffset>
            <bitWidth>1</bitWidth>
          </field>
          <field>
            <name>FB13</name>
            <bitOffset>13</bitOffset>
            <bitWidth>1</bitWidth>
          </field>
          <field>
            <name>FB14</name>
            <bitOffset>14</bitOffset>
            <bitWidth>1</bitWidth>
          </field>
          <field>
            <name>FB15</name>
            <bitOffset>15</bitOffset>
            <bitWidth>1</bitWidth>
          </field>
          <field>
            <name>FB16</name>
            <bitOffset>16</bitOffset>
            <bitWidth>1</bitWidth>
          </field>
          <field>
            <name>FB17</name>
            <bitOffset>17</bitOffset>
            <bitWidth>1</bitWidth>
          </field>
          <field>
            <name>FB18</name>
            <bitOffset>18</bitOffset>
            <bitWidth>1</bitWidth>
          </field>
          <field>
            <name>FB19</name>
            <bitOffset>19</bitOffset>
            <bitWidth>1</bitWidth>
          </field>
          <field>
            <name>FB20</name>
            <bitOffset>20</bitOffset>
            <bitWidth>1</bitWidth>
          </field>
          <field>
            <name>FB21</name>
            <bitOffset>21</bitOffset>
            <bitWidth>1</bitWidth>
          </field>
          <field>
            <name>FB22</name>
            <bitOffset>22</bitOffset>
            <bitWidth>1</bitWidth>
          </field>
          <field>
            <name>FB23</name>
            <bitOffset>23</bitOffset>
            <bitWidth>1</bitWidth>
          </field>
          <field>
            <name>FB24</name>
            <bitOffset>24</bitOffset>
            <bitWidth>1</bitWidth>
          </field>
          <field>
            <name>FB25</name>
            <bitOffset>25</bitOffset>
            <bitWidth>1</bitWidth>
          </field>
          <field>
            <name>FB26</name>
            <bitOffset>26</bitOffset>
            <bitWidth>1</bitWidth>
          </field>
          <field>
            <name>FB27</name>
            <bitOffset>27</bitOffset>
            <bitWidth>1</bitWidth>
          </field>
          <field>
            <name>FB28</name>
            <bitOffset>28</bitOffset>
            <bitWidth>1</bitWidth>
          </field>
          <field>
            <name>FB29</name>
            <bitOffset>29</bitOffset>
            <bitWidth>1</bitWidth>
          </field>
          <field>
            <name>FB30</name>
            <bitOffset>30</bitOffset>
            <bitWidth>1</bitWidth>
          </field>
          <field>
            <name>FB31</name>
            <bitOffset>31</bitOffset>
            <bitWidth>1</bitWidth>
          </field>
        </fields>
      </register>
      <register>
        <name>sFilterRegister.9.FR2</name>
        <addressOffset>0x28c</addressOffset>
        <size>0x20</size>
        <fields>
          <field>
            <name>FB0</name>
            <bitOffset>0</bitOffset>
            <bitWidth>1</bitWidth>
          </field>
          <field>
            <name>FB1</name>
            <bitOffset>1</bitOffset>
            <bitWidth>1</bitWidth>
          </field>
          <field>
            <name>FB2</name>
            <bitOffset>2</bitOffset>
            <bitWidth>1</bitWidth>
          </field>
          <field>
            <name>FB3</name>
            <bitOffset>3</bitOffset>
            <bitWidth>1</bitWidth>
          </field>
          <field>
            <name>FB4</name>
            <bitOffset>4</bitOffset>
            <bitWidth>1</bitWidth>
          </field>
          <field>
            <name>FB5</name>
            <bitOffset>5</bitOffset>
            <bitWidth>1</bitWidth>
          </field>
          <field>
            <name>FB6</name>
            <bitOffset>6</bitOffset>
            <bitWidth>1</bitWidth>
          </field>
          <field>
            <name>FB7</name>
            <bitOffset>7</bitOffset>
            <bitWidth>1</bitWidth>
          </field>
          <field>
            <name>FB8</name>
            <bitOffset>8</bitOffset>
            <bitWidth>1</bitWidth>
          </field>
          <field>
            <name>FB9</name>
            <bitOffset>9</bitOffset>
            <bitWidth>1</bitWidth>
          </field>
          <field>
            <name>FB10</name>
            <bitOffset>10</bitOffset>
            <bitWidth>1</bitWidth>
          </field>
          <field>
            <name>FB11</name>
            <bitOffset>11</bitOffset>
            <bitWidth>1</bitWidth>
          </field>
          <field>
            <name>FB12</name>
            <bitOffset>12</bitOffset>
            <bitWidth>1</bitWidth>
          </field>
          <field>
            <name>FB13</name>
            <bitOffset>13</bitOffset>
            <bitWidth>1</bitWidth>
          </field>
          <field>
            <name>FB14</name>
            <bitOffset>14</bitOffset>
            <bitWidth>1</bitWidth>
          </field>
          <field>
            <name>FB15</name>
            <bitOffset>15</bitOffset>
            <bitWidth>1</bitWidth>
          </field>
          <field>
            <name>FB16</name>
            <bitOffset>16</bitOffset>
            <bitWidth>1</bitWidth>
          </field>
          <field>
            <name>FB17</name>
            <bitOffset>17</bitOffset>
            <bitWidth>1</bitWidth>
          </field>
          <field>
            <name>FB18</name>
            <bitOffset>18</bitOffset>
            <bitWidth>1</bitWidth>
          </field>
          <field>
            <name>FB19</name>
            <bitOffset>19</bitOffset>
            <bitWidth>1</bitWidth>
          </field>
          <field>
            <name>FB20</name>
            <bitOffset>20</bitOffset>
            <bitWidth>1</bitWidth>
          </field>
          <field>
            <name>FB21</name>
            <bitOffset>21</bitOffset>
            <bitWidth>1</bitWidth>
          </field>
          <field>
            <name>FB22</name>
            <bitOffset>22</bitOffset>
            <bitWidth>1</bitWidth>
          </field>
          <field>
            <name>FB23</name>
            <bitOffset>23</bitOffset>
            <bitWidth>1</bitWidth>
          </field>
          <field>
            <name>FB24</name>
            <bitOffset>24</bitOffset>
            <bitWidth>1</bitWidth>
          </field>
          <field>
            <name>FB25</name>
            <bitOffset>25</bitOffset>
            <bitWidth>1</bitWidth>
          </field>
          <field>
            <name>FB26</name>
            <bitOffset>26</bitOffset>
            <bitWidth>1</bitWidth>
          </field>
          <field>
            <name>FB27</name>
            <bitOffset>27</bitOffset>
            <bitWidth>1</bitWidth>
          </field>
          <field>
            <name>FB28</name>
            <bitOffset>28</bitOffset>
            <bitWidth>1</bitWidth>
          </field>
          <field>
            <name>FB29</name>
            <bitOffset>29</bitOffset>
            <bitWidth>1</bitWidth>
          </field>
          <field>
            <name>FB30</name>
            <bitOffset>30</bitOffset>
            <bitWidth>1</bitWidth>
          </field>
          <field>
            <name>FB31</name>
            <bitOffset>31</bitOffset>
            <bitWidth>1</bitWidth>
          </field>
        </fields>
      </register>
      <register>
        <name>sFilterRegister.10.FR1</name>
        <addressOffset>0x290</addressOffset>
        <size>0x20</size>
        <fields>
          <field>
            <name>FB0</name>
            <bitOffset>0</bitOffset>
            <bitWidth>1</bitWidth>
          </field>
          <field>
            <name>FB1</name>
            <bitOffset>1</bitOffset>
            <bitWidth>1</bitWidth>
          </field>
          <field>
            <name>FB2</name>
            <bitOffset>2</bitOffset>
            <bitWidth>1</bitWidth>
          </field>
          <field>
            <name>FB3</name>
            <bitOffset>3</bitOffset>
            <bitWidth>1</bitWidth>
          </field>
          <field>
            <name>FB4</name>
            <bitOffset>4</bitOffset>
            <bitWidth>1</bitWidth>
          </field>
          <field>
            <name>FB5</name>
            <bitOffset>5</bitOffset>
            <bitWidth>1</bitWidth>
          </field>
          <field>
            <name>FB6</name>
            <bitOffset>6</bitOffset>
            <bitWidth>1</bitWidth>
          </field>
          <field>
            <name>FB7</name>
            <bitOffset>7</bitOffset>
            <bitWidth>1</bitWidth>
          </field>
          <field>
            <name>FB8</name>
            <bitOffset>8</bitOffset>
            <bitWidth>1</bitWidth>
          </field>
          <field>
            <name>FB9</name>
            <bitOffset>9</bitOffset>
            <bitWidth>1</bitWidth>
          </field>
          <field>
            <name>FB10</name>
            <bitOffset>10</bitOffset>
            <bitWidth>1</bitWidth>
          </field>
          <field>
            <name>FB11</name>
            <bitOffset>11</bitOffset>
            <bitWidth>1</bitWidth>
          </field>
          <field>
            <name>FB12</name>
            <bitOffset>12</bitOffset>
            <bitWidth>1</bitWidth>
          </field>
          <field>
            <name>FB13</name>
            <bitOffset>13</bitOffset>
            <bitWidth>1</bitWidth>
          </field>
          <field>
            <name>FB14</name>
            <bitOffset>14</bitOffset>
            <bitWidth>1</bitWidth>
          </field>
          <field>
            <name>FB15</name>
            <bitOffset>15</bitOffset>
            <bitWidth>1</bitWidth>
          </field>
          <field>
            <name>FB16</name>
            <bitOffset>16</bitOffset>
            <bitWidth>1</bitWidth>
          </field>
          <field>
            <name>FB17</name>
            <bitOffset>17</bitOffset>
            <bitWidth>1</bitWidth>
          </field>
          <field>
            <name>FB18</name>
            <bitOffset>18</bitOffset>
            <bitWidth>1</bitWidth>
          </field>
          <field>
            <name>FB19</name>
            <bitOffset>19</bitOffset>
            <bitWidth>1</bitWidth>
          </field>
          <field>
            <name>FB20</name>
            <bitOffset>20</bitOffset>
            <bitWidth>1</bitWidth>
          </field>
          <field>
            <name>FB21</name>
            <bitOffset>21</bitOffset>
            <bitWidth>1</bitWidth>
          </field>
          <field>
            <name>FB22</name>
            <bitOffset>22</bitOffset>
            <bitWidth>1</bitWidth>
          </field>
          <field>
            <name>FB23</name>
            <bitOffset>23</bitOffset>
            <bitWidth>1</bitWidth>
          </field>
          <field>
            <name>FB24</name>
            <bitOffset>24</bitOffset>
            <bitWidth>1</bitWidth>
          </field>
          <field>
            <name>FB25</name>
            <bitOffset>25</bitOffset>
            <bitWidth>1</bitWidth>
          </field>
          <field>
            <name>FB26</name>
            <bitOffset>26</bitOffset>
            <bitWidth>1</bitWidth>
          </field>
          <field>
            <name>FB27</name>
            <bitOffset>27</bitOffset>
            <bitWidth>1</bitWidth>
          </field>
          <field>
            <name>FB28</name>
            <bitOffset>28</bitOffset>
            <bitWidth>1</bitWidth>
          </field>
          <field>
            <name>FB29</name>
            <bitOffset>29</bitOffset>
            <bitWidth>1</bitWidth>
          </field>
          <field>
            <name>FB30</name>
            <bitOffset>30</bitOffset>
            <bitWidth>1</bitWidth>
          </field>
          <field>
            <name>FB31</name>
            <bitOffset>31</bitOffset>
            <bitWidth>1</bitWidth>
          </field>
        </fields>
      </register>
      <register>
        <name>sFilterRegister.10.FR2</name>
        <addressOffset>0x294</addressOffset>
        <size>0x20</size>
        <fields>
          <field>
            <name>FB0</name>
            <bitOffset>0</bitOffset>
            <bitWidth>1</bitWidth>
          </field>
          <field>
            <name>FB1</name>
            <bitOffset>1</bitOffset>
            <bitWidth>1</bitWidth>
          </field>
          <field>
            <name>FB2</name>
            <bitOffset>2</bitOffset>
            <bitWidth>1</bitWidth>
          </field>
          <field>
            <name>FB3</name>
            <bitOffset>3</bitOffset>
            <bitWidth>1</bitWidth>
          </field>
          <field>
            <name>FB4</name>
            <bitOffset>4</bitOffset>
            <bitWidth>1</bitWidth>
          </field>
          <field>
            <name>FB5</name>
            <bitOffset>5</bitOffset>
            <bitWidth>1</bitWidth>
          </field>
          <field>
            <name>FB6</name>
            <bitOffset>6</bitOffset>
            <bitWidth>1</bitWidth>
          </field>
          <field>
            <name>FB7</name>
            <bitOffset>7</bitOffset>
            <bitWidth>1</bitWidth>
          </field>
          <field>
            <name>FB8</name>
            <bitOffset>8</bitOffset>
            <bitWidth>1</bitWidth>
          </field>
          <field>
            <name>FB9</name>
            <bitOffset>9</bitOffset>
            <bitWidth>1</bitWidth>
          </field>
          <field>
            <name>FB10</name>
            <bitOffset>10</bitOffset>
            <bitWidth>1</bitWidth>
          </field>
          <field>
            <name>FB11</name>
            <bitOffset>11</bitOffset>
            <bitWidth>1</bitWidth>
          </field>
          <field>
            <name>FB12</name>
            <bitOffset>12</bitOffset>
            <bitWidth>1</bitWidth>
          </field>
          <field>
            <name>FB13</name>
            <bitOffset>13</bitOffset>
            <bitWidth>1</bitWidth>
          </field>
          <field>
            <name>FB14</name>
            <bitOffset>14</bitOffset>
            <bitWidth>1</bitWidth>
          </field>
          <field>
            <name>FB15</name>
            <bitOffset>15</bitOffset>
            <bitWidth>1</bitWidth>
          </field>
          <field>
            <name>FB16</name>
            <bitOffset>16</bitOffset>
            <bitWidth>1</bitWidth>
          </field>
          <field>
            <name>FB17</name>
            <bitOffset>17</bitOffset>
            <bitWidth>1</bitWidth>
          </field>
          <field>
            <name>FB18</name>
            <bitOffset>18</bitOffset>
            <bitWidth>1</bitWidth>
          </field>
          <field>
            <name>FB19</name>
            <bitOffset>19</bitOffset>
            <bitWidth>1</bitWidth>
          </field>
          <field>
            <name>FB20</name>
            <bitOffset>20</bitOffset>
            <bitWidth>1</bitWidth>
          </field>
          <field>
            <name>FB21</name>
            <bitOffset>21</bitOffset>
            <bitWidth>1</bitWidth>
          </field>
          <field>
            <name>FB22</name>
            <bitOffset>22</bitOffset>
            <bitWidth>1</bitWidth>
          </field>
          <field>
            <name>FB23</name>
            <bitOffset>23</bitOffset>
            <bitWidth>1</bitWidth>
          </field>
          <field>
            <name>FB24</name>
            <bitOffset>24</bitOffset>
            <bitWidth>1</bitWidth>
          </field>
          <field>
            <name>FB25</name>
            <bitOffset>25</bitOffset>
            <bitWidth>1</bitWidth>
          </field>
          <field>
            <name>FB26</name>
            <bitOffset>26</bitOffset>
            <bitWidth>1</bitWidth>
          </field>
          <field>
            <name>FB27</name>
            <bitOffset>27</bitOffset>
            <bitWidth>1</bitWidth>
          </field>
          <field>
            <name>FB28</name>
            <bitOffset>28</bitOffset>
            <bitWidth>1</bitWidth>
          </field>
          <field>
            <name>FB29</name>
            <bitOffset>29</bitOffset>
            <bitWidth>1</bitWidth>
          </field>
          <field>
            <name>FB30</name>
            <bitOffset>30</bitOffset>
            <bitWidth>1</bitWidth>
          </field>
          <field>
            <name>FB31</name>
            <bitOffset>31</bitOffset>
            <bitWidth>1</bitWidth>
          </field>
        </fields>
      </register>
      <register>
        <name>sFilterRegister.11.FR1</name>
        <addressOffset>0x298</addressOffset>
        <size>0x20</size>
        <fields>
          <field>
            <name>FB0</name>
            <bitOffset>0</bitOffset>
            <bitWidth>1</bitWidth>
          </field>
          <field>
            <name>FB1</name>
            <bitOffset>1</bitOffset>
            <bitWidth>1</bitWidth>
          </field>
          <field>
            <name>FB2</name>
            <bitOffset>2</bitOffset>
            <bitWidth>1</bitWidth>
          </field>
          <field>
            <name>FB3</name>
            <bitOffset>3</bitOffset>
            <bitWidth>1</bitWidth>
          </field>
          <field>
            <name>FB4</name>
            <bitOffset>4</bitOffset>
            <bitWidth>1</bitWidth>
          </field>
          <field>
            <name>FB5</name>
            <bitOffset>5</bitOffset>
            <bitWidth>1</bitWidth>
          </field>
          <field>
            <name>FB6</name>
            <bitOffset>6</bitOffset>
            <bitWidth>1</bitWidth>
          </field>
          <field>
            <name>FB7</name>
            <bitOffset>7</bitOffset>
            <bitWidth>1</bitWidth>
          </field>
          <field>
            <name>FB8</name>
            <bitOffset>8</bitOffset>
            <bitWidth>1</bitWidth>
          </field>
          <field>
            <name>FB9</name>
            <bitOffset>9</bitOffset>
            <bitWidth>1</bitWidth>
          </field>
          <field>
            <name>FB10</name>
            <bitOffset>10</bitOffset>
            <bitWidth>1</bitWidth>
          </field>
          <field>
            <name>FB11</name>
            <bitOffset>11</bitOffset>
            <bitWidth>1</bitWidth>
          </field>
          <field>
            <name>FB12</name>
            <bitOffset>12</bitOffset>
            <bitWidth>1</bitWidth>
          </field>
          <field>
            <name>FB13</name>
            <bitOffset>13</bitOffset>
            <bitWidth>1</bitWidth>
          </field>
          <field>
            <name>FB14</name>
            <bitOffset>14</bitOffset>
            <bitWidth>1</bitWidth>
          </field>
          <field>
            <name>FB15</name>
            <bitOffset>15</bitOffset>
            <bitWidth>1</bitWidth>
          </field>
          <field>
            <name>FB16</name>
            <bitOffset>16</bitOffset>
            <bitWidth>1</bitWidth>
          </field>
          <field>
            <name>FB17</name>
            <bitOffset>17</bitOffset>
            <bitWidth>1</bitWidth>
          </field>
          <field>
            <name>FB18</name>
            <bitOffset>18</bitOffset>
            <bitWidth>1</bitWidth>
          </field>
          <field>
            <name>FB19</name>
            <bitOffset>19</bitOffset>
            <bitWidth>1</bitWidth>
          </field>
          <field>
            <name>FB20</name>
            <bitOffset>20</bitOffset>
            <bitWidth>1</bitWidth>
          </field>
          <field>
            <name>FB21</name>
            <bitOffset>21</bitOffset>
            <bitWidth>1</bitWidth>
          </field>
          <field>
            <name>FB22</name>
            <bitOffset>22</bitOffset>
            <bitWidth>1</bitWidth>
          </field>
          <field>
            <name>FB23</name>
            <bitOffset>23</bitOffset>
            <bitWidth>1</bitWidth>
          </field>
          <field>
            <name>FB24</name>
            <bitOffset>24</bitOffset>
            <bitWidth>1</bitWidth>
          </field>
          <field>
            <name>FB25</name>
            <bitOffset>25</bitOffset>
            <bitWidth>1</bitWidth>
          </field>
          <field>
            <name>FB26</name>
            <bitOffset>26</bitOffset>
            <bitWidth>1</bitWidth>
          </field>
          <field>
            <name>FB27</name>
            <bitOffset>27</bitOffset>
            <bitWidth>1</bitWidth>
          </field>
          <field>
            <name>FB28</name>
            <bitOffset>28</bitOffset>
            <bitWidth>1</bitWidth>
          </field>
          <field>
            <name>FB29</name>
            <bitOffset>29</bitOffset>
            <bitWidth>1</bitWidth>
          </field>
          <field>
            <name>FB30</name>
            <bitOffset>30</bitOffset>
            <bitWidth>1</bitWidth>
          </field>
          <field>
            <name>FB31</name>
            <bitOffset>31</bitOffset>
            <bitWidth>1</bitWidth>
          </field>
        </fields>
      </register>
      <register>
        <name>sFilterRegister.11.FR2</name>
        <addressOffset>0x29c</addressOffset>
        <size>0x20</size>
        <fields>
          <field>
            <name>FB0</name>
            <bitOffset>0</bitOffset>
            <bitWidth>1</bitWidth>
          </field>
          <field>
            <name>FB1</name>
            <bitOffset>1</bitOffset>
            <bitWidth>1</bitWidth>
          </field>
          <field>
            <name>FB2</name>
            <bitOffset>2</bitOffset>
            <bitWidth>1</bitWidth>
          </field>
          <field>
            <name>FB3</name>
            <bitOffset>3</bitOffset>
            <bitWidth>1</bitWidth>
          </field>
          <field>
            <name>FB4</name>
            <bitOffset>4</bitOffset>
            <bitWidth>1</bitWidth>
          </field>
          <field>
            <name>FB5</name>
            <bitOffset>5</bitOffset>
            <bitWidth>1</bitWidth>
          </field>
          <field>
            <name>FB6</name>
            <bitOffset>6</bitOffset>
            <bitWidth>1</bitWidth>
          </field>
          <field>
            <name>FB7</name>
            <bitOffset>7</bitOffset>
            <bitWidth>1</bitWidth>
          </field>
          <field>
            <name>FB8</name>
            <bitOffset>8</bitOffset>
            <bitWidth>1</bitWidth>
          </field>
          <field>
            <name>FB9</name>
            <bitOffset>9</bitOffset>
            <bitWidth>1</bitWidth>
          </field>
          <field>
            <name>FB10</name>
            <bitOffset>10</bitOffset>
            <bitWidth>1</bitWidth>
          </field>
          <field>
            <name>FB11</name>
            <bitOffset>11</bitOffset>
            <bitWidth>1</bitWidth>
          </field>
          <field>
            <name>FB12</name>
            <bitOffset>12</bitOffset>
            <bitWidth>1</bitWidth>
          </field>
          <field>
            <name>FB13</name>
            <bitOffset>13</bitOffset>
            <bitWidth>1</bitWidth>
          </field>
          <field>
            <name>FB14</name>
            <bitOffset>14</bitOffset>
            <bitWidth>1</bitWidth>
          </field>
          <field>
            <name>FB15</name>
            <bitOffset>15</bitOffset>
            <bitWidth>1</bitWidth>
          </field>
          <field>
            <name>FB16</name>
            <bitOffset>16</bitOffset>
            <bitWidth>1</bitWidth>
          </field>
          <field>
            <name>FB17</name>
            <bitOffset>17</bitOffset>
            <bitWidth>1</bitWidth>
          </field>
          <field>
            <name>FB18</name>
            <bitOffset>18</bitOffset>
            <bitWidth>1</bitWidth>
          </field>
          <field>
            <name>FB19</name>
            <bitOffset>19</bitOffset>
            <bitWidth>1</bitWidth>
          </field>
          <field>
            <name>FB20</name>
            <bitOffset>20</bitOffset>
            <bitWidth>1</bitWidth>
          </field>
          <field>
            <name>FB21</name>
            <bitOffset>21</bitOffset>
            <bitWidth>1</bitWidth>
          </field>
          <field>
            <name>FB22</name>
            <bitOffset>22</bitOffset>
            <bitWidth>1</bitWidth>
          </field>
          <field>
            <name>FB23</name>
            <bitOffset>23</bitOffset>
            <bitWidth>1</bitWidth>
          </field>
          <field>
            <name>FB24</name>
            <bitOffset>24</bitOffset>
            <bitWidth>1</bitWidth>
          </field>
          <field>
            <name>FB25</name>
            <bitOffset>25</bitOffset>
            <bitWidth>1</bitWidth>
          </field>
          <field>
            <name>FB26</name>
            <bitOffset>26</bitOffset>
            <bitWidth>1</bitWidth>
          </field>
          <field>
            <name>FB27</name>
            <bitOffset>27</bitOffset>
            <bitWidth>1</bitWidth>
          </field>
          <field>
            <name>FB28</name>
            <bitOffset>28</bitOffset>
            <bitWidth>1</bitWidth>
          </field>
          <field>
            <name>FB29</name>
            <bitOffset>29</bitOffset>
            <bitWidth>1</bitWidth>
          </field>
          <field>
            <name>FB30</name>
            <bitOffset>30</bitOffset>
            <bitWidth>1</bitWidth>
          </field>
          <field>
            <name>FB31</name>
            <bitOffset>31</bitOffset>
            <bitWidth>1</bitWidth>
          </field>
        </fields>
      </register>
      <register>
        <name>sFilterRegister.12.FR1</name>
        <addressOffset>0x2a0</addressOffset>
        <size>0x20</size>
        <fields>
          <field>
            <name>FB0</name>
            <bitOffset>0</bitOffset>
            <bitWidth>1</bitWidth>
          </field>
          <field>
            <name>FB1</name>
            <bitOffset>1</bitOffset>
            <bitWidth>1</bitWidth>
          </field>
          <field>
            <name>FB2</name>
            <bitOffset>2</bitOffset>
            <bitWidth>1</bitWidth>
          </field>
          <field>
            <name>FB3</name>
            <bitOffset>3</bitOffset>
            <bitWidth>1</bitWidth>
          </field>
          <field>
            <name>FB4</name>
            <bitOffset>4</bitOffset>
            <bitWidth>1</bitWidth>
          </field>
          <field>
            <name>FB5</name>
            <bitOffset>5</bitOffset>
            <bitWidth>1</bitWidth>
          </field>
          <field>
            <name>FB6</name>
            <bitOffset>6</bitOffset>
            <bitWidth>1</bitWidth>
          </field>
          <field>
            <name>FB7</name>
            <bitOffset>7</bitOffset>
            <bitWidth>1</bitWidth>
          </field>
          <field>
            <name>FB8</name>
            <bitOffset>8</bitOffset>
            <bitWidth>1</bitWidth>
          </field>
          <field>
            <name>FB9</name>
            <bitOffset>9</bitOffset>
            <bitWidth>1</bitWidth>
          </field>
          <field>
            <name>FB10</name>
            <bitOffset>10</bitOffset>
            <bitWidth>1</bitWidth>
          </field>
          <field>
            <name>FB11</name>
            <bitOffset>11</bitOffset>
            <bitWidth>1</bitWidth>
          </field>
          <field>
            <name>FB12</name>
            <bitOffset>12</bitOffset>
            <bitWidth>1</bitWidth>
          </field>
          <field>
            <name>FB13</name>
            <bitOffset>13</bitOffset>
            <bitWidth>1</bitWidth>
          </field>
          <field>
            <name>FB14</name>
            <bitOffset>14</bitOffset>
            <bitWidth>1</bitWidth>
          </field>
          <field>
            <name>FB15</name>
            <bitOffset>15</bitOffset>
            <bitWidth>1</bitWidth>
          </field>
          <field>
            <name>FB16</name>
            <bitOffset>16</bitOffset>
            <bitWidth>1</bitWidth>
          </field>
          <field>
            <name>FB17</name>
            <bitOffset>17</bitOffset>
            <bitWidth>1</bitWidth>
          </field>
          <field>
            <name>FB18</name>
            <bitOffset>18</bitOffset>
            <bitWidth>1</bitWidth>
          </field>
          <field>
            <name>FB19</name>
            <bitOffset>19</bitOffset>
            <bitWidth>1</bitWidth>
          </field>
          <field>
            <name>FB20</name>
            <bitOffset>20</bitOffset>
            <bitWidth>1</bitWidth>
          </field>
          <field>
            <name>FB21</name>
            <bitOffset>21</bitOffset>
            <bitWidth>1</bitWidth>
          </field>
          <field>
            <name>FB22</name>
            <bitOffset>22</bitOffset>
            <bitWidth>1</bitWidth>
          </field>
          <field>
            <name>FB23</name>
            <bitOffset>23</bitOffset>
            <bitWidth>1</bitWidth>
          </field>
          <field>
            <name>FB24</name>
            <bitOffset>24</bitOffset>
            <bitWidth>1</bitWidth>
          </field>
          <field>
            <name>FB25</name>
            <bitOffset>25</bitOffset>
            <bitWidth>1</bitWidth>
          </field>
          <field>
            <name>FB26</name>
            <bitOffset>26</bitOffset>
            <bitWidth>1</bitWidth>
          </field>
          <field>
            <name>FB27</name>
            <bitOffset>27</bitOffset>
            <bitWidth>1</bitWidth>
          </field>
          <field>
            <name>FB28</name>
            <bitOffset>28</bitOffset>
            <bitWidth>1</bitWidth>
          </field>
          <field>
            <name>FB29</name>
            <bitOffset>29</bitOffset>
            <bitWidth>1</bitWidth>
          </field>
          <field>
            <name>FB30</name>
            <bitOffset>30</bitOffset>
            <bitWidth>1</bitWidth>
          </field>
          <field>
            <name>FB31</name>
            <bitOffset>31</bitOffset>
            <bitWidth>1</bitWidth>
          </field>
        </fields>
      </register>
      <register>
        <name>sFilterRegister.12.FR2</name>
        <addressOffset>0x2a4</addressOffset>
        <size>0x20</size>
        <fields>
          <field>
            <name>FB0</name>
            <bitOffset>0</bitOffset>
            <bitWidth>1</bitWidth>
          </field>
          <field>
            <name>FB1</name>
            <bitOffset>1</bitOffset>
            <bitWidth>1</bitWidth>
          </field>
          <field>
            <name>FB2</name>
            <bitOffset>2</bitOffset>
            <bitWidth>1</bitWidth>
          </field>
          <field>
            <name>FB3</name>
            <bitOffset>3</bitOffset>
            <bitWidth>1</bitWidth>
          </field>
          <field>
            <name>FB4</name>
            <bitOffset>4</bitOffset>
            <bitWidth>1</bitWidth>
          </field>
          <field>
            <name>FB5</name>
            <bitOffset>5</bitOffset>
            <bitWidth>1</bitWidth>
          </field>
          <field>
            <name>FB6</name>
            <bitOffset>6</bitOffset>
            <bitWidth>1</bitWidth>
          </field>
          <field>
            <name>FB7</name>
            <bitOffset>7</bitOffset>
            <bitWidth>1</bitWidth>
          </field>
          <field>
            <name>FB8</name>
            <bitOffset>8</bitOffset>
            <bitWidth>1</bitWidth>
          </field>
          <field>
            <name>FB9</name>
            <bitOffset>9</bitOffset>
            <bitWidth>1</bitWidth>
          </field>
          <field>
            <name>FB10</name>
            <bitOffset>10</bitOffset>
            <bitWidth>1</bitWidth>
          </field>
          <field>
            <name>FB11</name>
            <bitOffset>11</bitOffset>
            <bitWidth>1</bitWidth>
          </field>
          <field>
            <name>FB12</name>
            <bitOffset>12</bitOffset>
            <bitWidth>1</bitWidth>
          </field>
          <field>
            <name>FB13</name>
            <bitOffset>13</bitOffset>
            <bitWidth>1</bitWidth>
          </field>
          <field>
            <name>FB14</name>
            <bitOffset>14</bitOffset>
            <bitWidth>1</bitWidth>
          </field>
          <field>
            <name>FB15</name>
            <bitOffset>15</bitOffset>
            <bitWidth>1</bitWidth>
          </field>
          <field>
            <name>FB16</name>
            <bitOffset>16</bitOffset>
            <bitWidth>1</bitWidth>
          </field>
          <field>
            <name>FB17</name>
            <bitOffset>17</bitOffset>
            <bitWidth>1</bitWidth>
          </field>
          <field>
            <name>FB18</name>
            <bitOffset>18</bitOffset>
            <bitWidth>1</bitWidth>
          </field>
          <field>
            <name>FB19</name>
            <bitOffset>19</bitOffset>
            <bitWidth>1</bitWidth>
          </field>
          <field>
            <name>FB20</name>
            <bitOffset>20</bitOffset>
            <bitWidth>1</bitWidth>
          </field>
          <field>
            <name>FB21</name>
            <bitOffset>21</bitOffset>
            <bitWidth>1</bitWidth>
          </field>
          <field>
            <name>FB22</name>
            <bitOffset>22</bitOffset>
            <bitWidth>1</bitWidth>
          </field>
          <field>
            <name>FB23</name>
            <bitOffset>23</bitOffset>
            <bitWidth>1</bitWidth>
          </field>
          <field>
            <name>FB24</name>
            <bitOffset>24</bitOffset>
            <bitWidth>1</bitWidth>
          </field>
          <field>
            <name>FB25</name>
            <bitOffset>25</bitOffset>
            <bitWidth>1</bitWidth>
          </field>
          <field>
            <name>FB26</name>
            <bitOffset>26</bitOffset>
            <bitWidth>1</bitWidth>
          </field>
          <field>
            <name>FB27</name>
            <bitOffset>27</bitOffset>
            <bitWidth>1</bitWidth>
          </field>
          <field>
            <name>FB28</name>
            <bitOffset>28</bitOffset>
            <bitWidth>1</bitWidth>
          </field>
          <field>
            <name>FB29</name>
            <bitOffset>29</bitOffset>
            <bitWidth>1</bitWidth>
          </field>
          <field>
            <name>FB30</name>
            <bitOffset>30</bitOffset>
            <bitWidth>1</bitWidth>
          </field>
          <field>
            <name>FB31</name>
            <bitOffset>31</bitOffset>
            <bitWidth>1</bitWidth>
          </field>
        </fields>
      </register>
      <register>
        <name>sFilterRegister.13.FR1</name>
        <addressOffset>0x2a8</addressOffset>
        <size>0x20</size>
        <fields>
          <field>
            <name>FB0</name>
            <bitOffset>0</bitOffset>
            <bitWidth>1</bitWidth>
          </field>
          <field>
            <name>FB1</name>
            <bitOffset>1</bitOffset>
            <bitWidth>1</bitWidth>
          </field>
          <field>
            <name>FB2</name>
            <bitOffset>2</bitOffset>
            <bitWidth>1</bitWidth>
          </field>
          <field>
            <name>FB3</name>
            <bitOffset>3</bitOffset>
            <bitWidth>1</bitWidth>
          </field>
          <field>
            <name>FB4</name>
            <bitOffset>4</bitOffset>
            <bitWidth>1</bitWidth>
          </field>
          <field>
            <name>FB5</name>
            <bitOffset>5</bitOffset>
            <bitWidth>1</bitWidth>
          </field>
          <field>
            <name>FB6</name>
            <bitOffset>6</bitOffset>
            <bitWidth>1</bitWidth>
          </field>
          <field>
            <name>FB7</name>
            <bitOffset>7</bitOffset>
            <bitWidth>1</bitWidth>
          </field>
          <field>
            <name>FB8</name>
            <bitOffset>8</bitOffset>
            <bitWidth>1</bitWidth>
          </field>
          <field>
            <name>FB9</name>
            <bitOffset>9</bitOffset>
            <bitWidth>1</bitWidth>
          </field>
          <field>
            <name>FB10</name>
            <bitOffset>10</bitOffset>
            <bitWidth>1</bitWidth>
          </field>
          <field>
            <name>FB11</name>
            <bitOffset>11</bitOffset>
            <bitWidth>1</bitWidth>
          </field>
          <field>
            <name>FB12</name>
            <bitOffset>12</bitOffset>
            <bitWidth>1</bitWidth>
          </field>
          <field>
            <name>FB13</name>
            <bitOffset>13</bitOffset>
            <bitWidth>1</bitWidth>
          </field>
          <field>
            <name>FB14</name>
            <bitOffset>14</bitOffset>
            <bitWidth>1</bitWidth>
          </field>
          <field>
            <name>FB15</name>
            <bitOffset>15</bitOffset>
            <bitWidth>1</bitWidth>
          </field>
          <field>
            <name>FB16</name>
            <bitOffset>16</bitOffset>
            <bitWidth>1</bitWidth>
          </field>
          <field>
            <name>FB17</name>
            <bitOffset>17</bitOffset>
            <bitWidth>1</bitWidth>
          </field>
          <field>
            <name>FB18</name>
            <bitOffset>18</bitOffset>
            <bitWidth>1</bitWidth>
          </field>
          <field>
            <name>FB19</name>
            <bitOffset>19</bitOffset>
            <bitWidth>1</bitWidth>
          </field>
          <field>
            <name>FB20</name>
            <bitOffset>20</bitOffset>
            <bitWidth>1</bitWidth>
          </field>
          <field>
            <name>FB21</name>
            <bitOffset>21</bitOffset>
            <bitWidth>1</bitWidth>
          </field>
          <field>
            <name>FB22</name>
            <bitOffset>22</bitOffset>
            <bitWidth>1</bitWidth>
          </field>
          <field>
            <name>FB23</name>
            <bitOffset>23</bitOffset>
            <bitWidth>1</bitWidth>
          </field>
          <field>
            <name>FB24</name>
            <bitOffset>24</bitOffset>
            <bitWidth>1</bitWidth>
          </field>
          <field>
            <name>FB25</name>
            <bitOffset>25</bitOffset>
            <bitWidth>1</bitWidth>
          </field>
          <field>
            <name>FB26</name>
            <bitOffset>26</bitOffset>
            <bitWidth>1</bitWidth>
          </field>
          <field>
            <name>FB27</name>
            <bitOffset>27</bitOffset>
            <bitWidth>1</bitWidth>
          </field>
          <field>
            <name>FB28</name>
            <bitOffset>28</bitOffset>
            <bitWidth>1</bitWidth>
          </field>
          <field>
            <name>FB29</name>
            <bitOffset>29</bitOffset>
            <bitWidth>1</bitWidth>
          </field>
          <field>
            <name>FB30</name>
            <bitOffset>30</bitOffset>
            <bitWidth>1</bitWidth>
          </field>
          <field>
            <name>FB31</name>
            <bitOffset>31</bitOffset>
            <bitWidth>1</bitWidth>
          </field>
        </fields>
      </register>
      <register>
        <name>sFilterRegister.13.FR2</name>
        <addressOffset>0x2ac</addressOffset>
        <size>0x20</size>
        <fields>
          <field>
            <name>FB0</name>
            <bitOffset>0</bitOffset>
            <bitWidth>1</bitWidth>
          </field>
          <field>
            <name>FB1</name>
            <bitOffset>1</bitOffset>
            <bitWidth>1</bitWidth>
          </field>
          <field>
            <name>FB2</name>
            <bitOffset>2</bitOffset>
            <bitWidth>1</bitWidth>
          </field>
          <field>
            <name>FB3</name>
            <bitOffset>3</bitOffset>
            <bitWidth>1</bitWidth>
          </field>
          <field>
            <name>FB4</name>
            <bitOffset>4</bitOffset>
            <bitWidth>1</bitWidth>
          </field>
          <field>
            <name>FB5</name>
            <bitOffset>5</bitOffset>
            <bitWidth>1</bitWidth>
          </field>
          <field>
            <name>FB6</name>
            <bitOffset>6</bitOffset>
            <bitWidth>1</bitWidth>
          </field>
          <field>
            <name>FB7</name>
            <bitOffset>7</bitOffset>
            <bitWidth>1</bitWidth>
          </field>
          <field>
            <name>FB8</name>
            <bitOffset>8</bitOffset>
            <bitWidth>1</bitWidth>
          </field>
          <field>
            <name>FB9</name>
            <bitOffset>9</bitOffset>
            <bitWidth>1</bitWidth>
          </field>
          <field>
            <name>FB10</name>
            <bitOffset>10</bitOffset>
            <bitWidth>1</bitWidth>
          </field>
          <field>
            <name>FB11</name>
            <bitOffset>11</bitOffset>
            <bitWidth>1</bitWidth>
          </field>
          <field>
            <name>FB12</name>
            <bitOffset>12</bitOffset>
            <bitWidth>1</bitWidth>
          </field>
          <field>
            <name>FB13</name>
            <bitOffset>13</bitOffset>
            <bitWidth>1</bitWidth>
          </field>
          <field>
            <name>FB14</name>
            <bitOffset>14</bitOffset>
            <bitWidth>1</bitWidth>
          </field>
          <field>
            <name>FB15</name>
            <bitOffset>15</bitOffset>
            <bitWidth>1</bitWidth>
          </field>
          <field>
            <name>FB16</name>
            <bitOffset>16</bitOffset>
            <bitWidth>1</bitWidth>
          </field>
          <field>
            <name>FB17</name>
            <bitOffset>17</bitOffset>
            <bitWidth>1</bitWidth>
          </field>
          <field>
            <name>FB18</name>
            <bitOffset>18</bitOffset>
            <bitWidth>1</bitWidth>
          </field>
          <field>
            <name>FB19</name>
            <bitOffset>19</bitOffset>
            <bitWidth>1</bitWidth>
          </field>
          <field>
            <name>FB20</name>
            <bitOffset>20</bitOffset>
            <bitWidth>1</bitWidth>
          </field>
          <field>
            <name>FB21</name>
            <bitOffset>21</bitOffset>
            <bitWidth>1</bitWidth>
          </field>
          <field>
            <name>FB22</name>
            <bitOffset>22</bitOffset>
            <bitWidth>1</bitWidth>
          </field>
          <field>
            <name>FB23</name>
            <bitOffset>23</bitOffset>
            <bitWidth>1</bitWidth>
          </field>
          <field>
            <name>FB24</name>
            <bitOffset>24</bitOffset>
            <bitWidth>1</bitWidth>
          </field>
          <field>
            <name>FB25</name>
            <bitOffset>25</bitOffset>
            <bitWidth>1</bitWidth>
          </field>
          <field>
            <name>FB26</name>
            <bitOffset>26</bitOffset>
            <bitWidth>1</bitWidth>
          </field>
          <field>
            <name>FB27</name>
            <bitOffset>27</bitOffset>
            <bitWidth>1</bitWidth>
          </field>
          <field>
            <name>FB28</name>
            <bitOffset>28</bitOffset>
            <bitWidth>1</bitWidth>
          </field>
          <field>
            <name>FB29</name>
            <bitOffset>29</bitOffset>
            <bitWidth>1</bitWidth>
          </field>
          <field>
            <name>FB30</name>
            <bitOffset>30</bitOffset>
            <bitWidth>1</bitWidth>
          </field>
          <field>
            <name>FB31</name>
            <bitOffset>31</bitOffset>
            <bitWidth>1</bitWidth>
          </field>
        </fields>
      </register>
      <register>
        <name>sFilterRegister.14.FR1</name>
        <addressOffset>0x2b0</addressOffset>
        <size>0x20</size>
      </register>
      <register>
        <name>sFilterRegister.14.FR2</name>
        <addressOffset>0x2b4</addressOffset>
        <size>0x20</size>
      </register>
      <register>
        <name>sFilterRegister.15.FR1</name>
        <addressOffset>0x2b8</addressOffset>
        <size>0x20</size>
      </register>
      <register>
        <name>sFilterRegister.15.FR2</name>
        <addressOffset>0x2bc</addressOffset>
        <size>0x20</size>
      </register>
      <register>
        <name>sFilterRegister.16.FR1</name>
        <addressOffset>0x2c0</addressOffset>
        <size>0x20</size>
      </register>
      <register>
        <name>sFilterRegister.16.FR2</name>
        <addressOffset>0x2c4</addressOffset>
        <size>0x20</size>
      </register>
      <register>
        <name>sFilterRegister.17.FR1</name>
        <addressOffset>0x2c8</addressOffset>
        <size>0x20</size>
      </register>
      <register>
        <name>sFilterRegister.17.FR2</name>
        <addressOffset>0x2cc</addressOffset>
        <size>0x20</size>
      </register>
      <register>
        <name>sFilterRegister.18.FR1</name>
        <addressOffset>0x2d0</addressOffset>
        <size>0x20</size>
      </register>
      <register>
        <name>sFilterRegister.18.FR2</name>
        <addressOffset>0x2d4</addressOffset>
        <size>0x20</size>
      </register>
      <register>
        <name>sFilterRegister.19.FR1</name>
        <addressOffset>0x2d8</addressOffset>
        <size>0x20</size>
      </register>
      <register>
        <name>sFilterRegister.19.FR2</name>
        <addressOffset>0x2dc</addressOffset>
        <size>0x20</size>
      </register>
      <register>
        <name>sFilterRegister.20.FR1</name>
        <addressOffset>0x2e0</addressOffset>
        <size>0x20</size>
      </register>
      <register>
        <name>sFilterRegister.20.FR2</name>
        <addressOffset>0x2e4</addressOffset>
        <size>0x20</size>
      </register>
      <register>
        <name>sFilterRegister.21.FR1</name>
        <addressOffset>0x2e8</addressOffset>
        <size>0x20</size>
      </register>
      <register>
        <name>sFilterRegister.21.FR2</name>
        <addressOffset>0x2ec</addressOffset>
        <size>0x20</size>
      </register>
      <register>
        <name>sFilterRegister.22.FR1</name>
        <addressOffset>0x2f0</addressOffset>
        <size>0x20</size>
      </register>
      <register>
        <name>sFilterRegister.22.FR2</name>
        <addressOffset>0x2f4</addressOffset>
        <size>0x20</size>
      </register>
      <register>
        <name>sFilterRegister.23.FR1</name>
        <addressOffset>0x2f8</addressOffset>
        <size>0x20</size>
      </register>
      <register>
        <name>sFilterRegister.23.FR2</name>
        <addressOffset>0x2fc</addressOffset>
        <size>0x20</size>
      </register>
      <register>
        <name>sFilterRegister.24.FR1</name>
        <addressOffset>0x300</addressOffset>
        <size>0x20</size>
      </register>
      <register>
        <name>sFilterRegister.24.FR2</name>
        <addressOffset>0x304</addressOffset>
        <size>0x20</size>
      </register>
      <register>
        <name>sFilterRegister.25.FR1</name>
        <addressOffset>0x308</addressOffset>
        <size>0x20</size>
      </register>
      <register>
        <name>sFilterRegister.25.FR2</name>
        <addressOffset>0x30c</addressOffset>
        <size>0x20</size>
      </register>
      <register>
        <name>sFilterRegister.26.FR1</name>
        <addressOffset>0x310</addressOffset>
        <size>0x20</size>
      </register>
      <register>
        <name>sFilterRegister.26.FR2</name>
        <addressOffset>0x314</addressOffset>
        <size>0x20</size>
      </register>
      <register>
        <name>sFilterRegister.27.FR1</name>
        <addressOffset>0x318</addressOffset>
        <size>0x20</size>
      </register>
      <register>
        <name>sFilterRegister.27.FR2</name>
        <addressOffset>0x31c</addressOffset>
        <size>0x20</size>
      </register>
    </peripheral>
    <peripheral>
      <name>PWR</name>
      <baseAddress>0x40007000</baseAddress>
      <register>
        <name>CR</name>
        <addressOffset>0x0</addressOffset>
        <size>0x20</size>
        <fields>
          <field>
            <name>LPDS</name>
            <bitOffset>0</bitOffset>
            <bitWidth>1</bitWidth>
          </field>
          <field>
            <name>PDDS</name>
            <bitOffset>1</bitOffset>
            <bitWidth>1</bitWidth>
          </field>
          <field>
            <name>CWUF</name>
            <bitOffset>2</bitOffset>
            <bitWidth>1</bitWidth>
          </field>
          <field>
            <name>CSBF</name>
            <bitOffset>3</bitOffset>
            <bitWidth>1</bitWidth>
          </field>
          <field>
            <name>PVDE</name>
            <bitOffset>4</bitOffset>
            <bitWidth>1</bitWidth>
          </field>
          <field>
            <name>PLS</name>
            <bitOffset>5</bitOffset>
            <bitWidth>3</bitWidth>
          </field>
          <field>
            <name>DBP</name>
            <bitOffset>8</bitOffset>
            <bitWidth>1</bitWidth>
          </field>
          <field>
            <name>FPDS</name>
            <bitOffset>9</bitOffset>
            <bitWidth>1</bitWidth>
          </field>
          <field>
            <name>LPLVDS</name>
            <bitOffset>10</bitOffset>
            <bitWidth>1</bitWidth>
          </field>
          <field>
            <name>MRLVDS</name>
            <bitOffset>11</bitOffset>
            <bitWidth>1</bitWidth>
          </field>
          <field>
            <name>ADCDC1</name>
            <bitOffset>13</bitOffset>
            <bitWidth>1</bitWidth>
          </field>
          <field>
            <name>VOS</name>
            <bitOffset>14</bitOffset>
            <bitWidth>2</bitWidth>
          </field>
          <field>
            <name>ODEN</name>
            <bitOffset>16</bitOffset>
            <bitWidth>1</bitWidth>
          </field>
          <field>
            <name>ODSWEN</name>
            <bitOffset>17</bitOffset>
            <bitWidth>1</bitWidth>
          </field>
          <field>
            <name>UDEN</name>
            <bitOffset>18</bitOffset>
            <bitWidth>2</bitWidth>
          </field>
        </fields>
      </register>
      <register>
        <name>CSR</name>
        <addressOffset>0x4</addressOffset>
        <size>0x20</size>
        <fields>
          <field>
            <name>WUF</name>
            <bitOffset>0</bitOffset>
            <bitWidth>1</bitWidth>
          </field>
          <field>
            <name>SBF</name>
            <bitOffset>1</bitOffset>
            <bitWidth>1</bitWidth>
          </field>
          <field>
            <name>PVDO</name>
            <bitOffset>2</bitOffset>
            <bitWidth>1</bitWidth>
          </field>
          <field>
            <name>BRR</name>
            <bitOffset>3</bitOffset>
            <bitWidth>1</bitWidth>
          </field>
          <field>
            <name>EWUP</name>
            <bitOffset>8</bitOffset>
            <bitWidth>1</bitWidth>
          </field>
          <field>
            <name>BRE</name>
            <bitOffset>9</bitOffset>
            <bitWidth>1</bitWidth>
          </field>
          <field>
            <name>VOSRDY</name>
            <bitOffset>14</bitOffset>
            <bitWidth>1</bitWidth>
          </field>
          <field>
            <name>ODRDY</name>
            <bitOffset>16</bitOffset>
            <bitWidth>1</bitWidth>
          </field>
          <field>
            <name>ODSWRDY</name>
            <bitOffset>17</bitOffset>
            <bitWidth>1</bitWidth>
          </field>
          <field>
            <name>UDRDY</name>
            <bitOffset>18</bitOffset>
            <bitWidth>2</bitWidth>
          </field>
        </fields>
      </register>
    </peripheral>
    <peripheral>
      <name>DAC1</name>
      <baseAddress>0x40007400</baseAddress>
      <register>
        <name>CR</name>
        <addressOffset>0x0</addressOffset>
        <size>0x20</size>
        <fields>
          <field>
            <name>EN1</name>
            <bitOffset>0</bitOffset>
            <bitWidth>1</bitWidth>
          </field>
          <field>
            <name>BOFF1</name>
            <bitOffset>1</bitOffset>
            <bitWidth>1</bitWidth>
          </field>
          <field>
            <name>TEN1</name>
            <bitOffset>2</bitOffset>
            <bitWidth>1</bitWidth>
          </field>
          <field>
            <name>TSEL1</name>
            <bitOffset>3</bitOffset>
            <bitWidth>3</bitWidth>
          </field>
          <field>
            <name>WAVE1</name>
            <bitOffset>6</bitOffset>
            <bitWidth>2</bitWidth>
          </field>
          <field>
            <name>MAMP1</name>
            <bitOffset>8</bitOffset>
            <bitWidth>4</bitWidth>
          </field>
          <field>
            <name>DMAEN1</name>
            <bitOffset>12</bitOffset>
            <bitWidth>1</bitWidth>
          </field>
          <field>
            <name>DMAUDRIE1</name>
            <bitOffset>13</bitOffset>
            <bitWidth>1</bitWidth>
          </field>
          <field>
            <name>EN2</name>
            <bitOffset>16</bitOffset>
            <bitWidth>1</bitWidth>
          </field>
          <field>
            <name>BOFF2</name>
            <bitOffset>17</bitOffset>
            <bitWidth>1</bitWidth>
          </field>
          <field>
            <name>TEN2</name>
            <bitOffset>18</bitOffset>
            <bitWidth>1</bitWidth>
          </field>
          <field>
            <name>TSEL2</name>
            <bitOffset>19</bitOffset>
            <bitWidth>3</bitWidth>
          </field>
          <field>
            <name>WAVE2</name>
            <bitOffset>22</bitOffset>
            <bitWidth>2</bitWidth>
          </field>
          <field>
            <name>MAMP2</name>
            <bitOffset>24</bitOffset>
            <bitWidth>4</bitWidth>
          </field>
          <field>
            <name>DMAEN2</name>
            <bitOffset>28</bitOffset>
            <bitWidth>1</bitWidth>
          </field>
          <field>
            <name>DMAUDRIE2</name>
            <bitOffset>29</bitOffset>
            <bitWidth>1</bitWidth>
          </field>
        </fields>
      </register>
      <register>
        <name>SWTRIGR</name>
        <addressOffset>0x4</addressOffset>
        <size>0x20</size>
        <fields>
          <field>
            <name>SWTRIG1</name>
            <bitOffset>0</bitOffset>
            <bitWidth>1</bitWidth>
          </field>
          <field>
            <name>SWTRIG2</name>
            <bitOffset>1</bitOffset>
            <bitWidth>1</bitWidth>
          </field>
        </fields>
      </register>
      <register>
        <name>DHR12R1</name>
        <addressOffset>0x8</addressOffset>
        <size>0x20</size>
        <fields>
          <field>
            <name>DACC1DHR</name>
            <bitOffset>0</bitOffset>
            <bitWidth>12</bitWidth>
          </field>
        </fields>
      </register>
      <register>
        <name>DHR12L1</name>
        <addressOffset>0xc</addressOffset>
        <size>0x20</size>
        <fields>
          <field>
            <name>DACC1DHR</name>
            <bitOffset>4</bitOffset>
            <bitWidth>12</bitWidth>
          </field>
        </fields>
      </register>
      <register>
        <name>DHR8R1</name>
        <addressOffset>0x10</addressOffset>
        <size>0x20</size>
        <fields>
          <field>
            <name>DACC1DHR</name>
            <bitOffset>0</bitOffset>
            <bitWidth>8</bitWidth>
          </field>
        </fields>
      </register>
      <register>
        <name>DHR12R2</name>
        <addressOffset>0x14</addressOffset>
        <size>0x20</size>
        <fields>
          <field>
            <name>DACC2DHR</name>
            <bitOffset>0</bitOffset>
            <bitWidth>12</bitWidth>
          </field>
        </fields>
      </register>
      <register>
        <name>DHR12L2</name>
        <addressOffset>0x18</addressOffset>
        <size>0x20</size>
        <fields>
          <field>
            <name>DACC2DHR</name>
            <bitOffset>4</bitOffset>
            <bitWidth>12</bitWidth>
          </field>
        </fields>
      </register>
      <register>
        <name>DHR8R2</name>
        <addressOffset>0x1c</addressOffset>
        <size>0x20</size>
        <fields>
          <field>
            <name>DACC2DHR</name>
            <bitOffset>0</bitOffset>
            <bitWidth>8</bitWidth>
          </field>
        </fields>
      </register>
      <register>
        <name>DHR12RD</name>
        <addressOffset>0x20</addressOffset>
        <size>0x20</size>
        <fields>
          <field>
            <name>DACC1DHR</name>
            <bitOffset>0</bitOffset>
            <bitWidth>12</bitWidth>
          </field>
          <field>
            <name>DACC2DHR</name>
            <bitOffset>16</bitOffset>
            <bitWidth>12</bitWidth>
          </field>
        </fields>
      </register>
      <register>
        <name>DHR12LD</name>
        <addressOffset>0x24</addressOffset>
        <size>0x20</size>
        <fields>
          <field>
            <name>DACC1DHR</name>
            <bitOffset>4</bitOffset>
            <bitWidth>12</bitWidth>
          </field>
          <field>
            <name>DACC2DHR</name>
            <bitOffset>20</bitOffset>
            <bitWidth>12</bitWidth>
          </field>
        </fields>
      </register>
      <register>
        <name>DHR8RD</name>
        <addressOffset>0x28</addressOffset>
        <size>0x20</size>
        <fields>
          <field>
            <name>DACC1DHR</name>
            <bitOffset>0</bitOffset>
            <bitWidth>8</bitWidth>
          </field>
          <field>
            <name>DACC2DHR</name>
            <bitOffset>8</bitOffset>
            <bitWidth>8</bitWidth>
          </field>
        </fields>
      </register>
      <register>
        <name>DOR1</name>
        <addressOffset>0x2c</addressOffset>
        <size>0x20</size>
        <fields>
          <field>
            <name>DACC1DOR</name>
            <bitOffset>0</bitOffset>
            <bitWidth>12</bitWidth>
          </field>
        </fields>
      </register>
      <register>
        <name>DOR2</name>
        <addressOffset>0x30</addressOffset>
        <size>0x20</size>
        <fields>
          <field>
            <name>DACC2DOR</name>
            <bitOffset>0</bitOffset>
            <bitWidth>12</bitWidth>
          </field>
        </fields>
      </register>
      <register>
        <name>SR</name>
        <addressOffset>0x34</addressOffset>
        <size>0x20</size>
        <fields>
          <field>
            <name>DMAUDR1</name>
            <bitOffset>13</bitOffset>
            <bitWidth>1</bitWidth>
          </field>
          <field>
            <name>DMAUDR2</name>
            <bitOffset>29</bitOffset>
            <bitWidth>1</bitWidth>
          </field>
        </fields>
      </register>
    </peripheral>
    <peripheral>
      <name>UART7</name>
      <baseAddress>0x40007800</baseAddress>
      <register>
        <name>SR</name>
        <addressOffset>0x0</addressOffset>
        <size>0x20</size>
        <fields>
          <field>
            <name>PE</name>
            <bitOffset>0</bitOffset>
            <bitWidth>1</bitWidth>
          </field>
          <field>
            <name>FE</name>
            <bitOffset>1</bitOffset>
            <bitWidth>1</bitWidth>
          </field>
          <field>
            <name>NE</name>
            <bitOffset>2</bitOffset>
            <bitWidth>1</bitWidth>
          </field>
          <field>
            <name>ORE</name>
            <bitOffset>3</bitOffset>
            <bitWidth>1</bitWidth>
          </field>
          <field>
            <name>IDLE</name>
            <bitOffset>4</bitOffset>
            <bitWidth>1</bitWidth>
          </field>
          <field>
            <name>RXNE</name>
            <bitOffset>5</bitOffset>
            <bitWidth>1</bitWidth>
          </field>
          <field>
            <name>TC</name>
            <bitOffset>6</bitOffset>
            <bitWidth>1</bitWidth>
          </field>
          <field>
            <name>TXE</name>
            <bitOffset>7</bitOffset>
            <bitWidth>1</bitWidth>
          </field>
          <field>
            <name>LBD</name>
            <bitOffset>8</bitOffset>
            <bitWidth>1</bitWidth>
          </field>
          <field>
            <name>CTS</name>
            <bitOffset>9</bitOffset>
            <bitWidth>1</bitWidth>
          </field>
        </fields>
      </register>
      <register>
        <name>DR</name>
        <addressOffset>0x4</addressOffset>
        <size>0x20</size>
        <fields>
          <field>
            <name>DR</name>
            <bitOffset>0</bitOffset>
            <bitWidth>9</bitWidth>
          </field>
        </fields>
      </register>
      <register>
        <name>BRR</name>
        <addressOffset>0x8</addressOffset>
        <size>0x20</size>
        <fields>
          <field>
            <name>DIV_Fraction</name>
            <bitOffset>0</bitOffset>
            <bitWidth>4</bitWidth>
          </field>
          <field>
            <name>DIV_Mantissa</name>
            <bitOffset>4</bitOffset>
            <bitWidth>12</bitWidth>
          </field>
        </fields>
      </register>
      <register>
        <name>CR1</name>
        <addressOffset>0xc</addressOffset>
        <size>0x20</size>
        <fields>
          <field>
            <name>SBK</name>
            <bitOffset>0</bitOffset>
            <bitWidth>1</bitWidth>
          </field>
          <field>
            <name>RWU</name>
            <bitOffset>1</bitOffset>
            <bitWidth>1</bitWidth>
          </field>
          <field>
            <name>RE</name>
            <bitOffset>2</bitOffset>
            <bitWidth>1</bitWidth>
          </field>
          <field>
            <name>TE</name>
            <bitOffset>3</bitOffset>
            <bitWidth>1</bitWidth>
          </field>
          <field>
            <name>IDLEIE</name>
            <bitOffset>4</bitOffset>
            <bitWidth>1</bitWidth>
          </field>
          <field>
            <name>RXNEIE</name>
            <bitOffset>5</bitOffset>
            <bitWidth>1</bitWidth>
          </field>
          <field>
            <name>TCIE</name>
            <bitOffset>6</bitOffset>
            <bitWidth>1</bitWidth>
          </field>
          <field>
            <name>TXEIE</name>
            <bitOffset>7</bitOffset>
            <bitWidth>1</bitWidth>
          </field>
          <field>
            <name>PEIE</name>
            <bitOffset>8</bitOffset>
            <bitWidth>1</bitWidth>
          </field>
          <field>
            <name>PS</name>
            <bitOffset>9</bitOffset>
            <bitWidth>1</bitWidth>
          </field>
          <field>
            <name>PCE</name>
            <bitOffset>10</bitOffset>
            <bitWidth>1</bitWidth>
          </field>
          <field>
            <name>WAKE</name>
            <bitOffset>11</bitOffset>
            <bitWidth>1</bitWidth>
          </field>
          <field>
            <name>M</name>
            <bitOffset>12</bitOffset>
            <bitWidth>1</bitWidth>
          </field>
          <field>
            <name>UE</name>
            <bitOffset>13</bitOffset>
            <bitWidth>1</bitWidth>
          </field>
          <field>
            <name>OVER8</name>
            <bitOffset>15</bitOffset>
            <bitWidth>1</bitWidth>
          </field>
        </fields>
      </register>
      <register>
        <name>CR2</name>
        <addressOffset>0x10</addressOffset>
        <size>0x20</size>
        <fields>
          <field>
            <name>ADD</name>
            <bitOffset>0</bitOffset>
            <bitWidth>4</bitWidth>
          </field>
          <field>
            <name>LBDL</name>
            <bitOffset>5</bitOffset>
            <bitWidth>1</bitWidth>
          </field>
          <field>
            <name>LBDIE</name>
            <bitOffset>6</bitOffset>
            <bitWidth>1</bitWidth>
          </field>
          <field>
            <name>LBCL</name>
            <bitOffset>8</bitOffset>
            <bitWidth>1</bitWidth>
          </field>
          <field>
            <name>CPHA</name>
            <bitOffset>9</bitOffset>
            <bitWidth>1</bitWidth>
          </field>
          <field>
            <name>CPOL</name>
            <bitOffset>10</bitOffset>
            <bitWidth>1</bitWidth>
          </field>
          <field>
            <name>CLKEN</name>
            <bitOffset>11</bitOffset>
            <bitWidth>1</bitWidth>
          </field>
          <field>
            <name>STOP</name>
            <bitOffset>12</bitOffset>
            <bitWidth>2</bitWidth>
          </field>
          <field>
            <name>LINEN</name>
            <bitOffset>14</bitOffset>
            <bitWidth>1</bitWidth>
          </field>
        </fields>
      </register>
      <register>
        <name>CR3</name>
        <addressOffset>0x14</addressOffset>
        <size>0x20</size>
        <fields>
          <field>
            <name>EIE</name>
            <bitOffset>0</bitOffset>
            <bitWidth>1</bitWidth>
          </field>
          <field>
            <name>IREN</name>
            <bitOffset>1</bitOffset>
            <bitWidth>1</bitWidth>
          </field>
          <field>
            <name>IRLP</name>
            <bitOffset>2</bitOffset>
            <bitWidth>1</bitWidth>
          </field>
          <field>
            <name>HDSEL</name>
            <bitOffset>3</bitOffset>
            <bitWidth>1</bitWidth>
          </field>
          <field>
            <name>NACK</name>
            <bitOffset>4</bitOffset>
            <bitWidth>1</bitWidth>
          </field>
          <field>
            <name>SCEN</name>
            <bitOffset>5</bitOffset>
            <bitWidth>1</bitWidth>
          </field>
          <field>
            <name>DMAR</name>
            <bitOffset>6</bitOffset>
            <bitWidth>1</bitWidth>
          </field>
          <field>
            <name>DMAT</name>
            <bitOffset>7</bitOffset>
            <bitWidth>1</bitWidth>
          </field>
          <field>
            <name>RTSE</name>
            <bitOffset>8</bitOffset>
            <bitWidth>1</bitWidth>
          </field>
          <field>
            <name>CTSE</name>
            <bitOffset>9</bitOffset>
            <bitWidth>1</bitWidth>
          </field>
          <field>
            <name>CTSIE</name>
            <bitOffset>10</bitOffset>
            <bitWidth>1</bitWidth>
          </field>
          <field>
            <name>ONEBIT</name>
            <bitOffset>11</bitOffset>
            <bitWidth>1</bitWidth>
          </field>
        </fields>
      </register>
      <register>
        <name>GTPR</name>
        <addressOffset>0x18</addressOffset>
        <size>0x20</size>
        <fields>
          <field>
            <name>PSC</name>
            <bitOffset>0</bitOffset>
            <bitWidth>8</bitWidth>
          </field>
          <field>
            <name>GT</name>
            <bitOffset>8</bitOffset>
            <bitWidth>8</bitWidth>
          </field>
        </fields>
      </register>
    </peripheral>
    <peripheral>
      <name>UART8</name>
      <baseAddress>0x40007c00</baseAddress>
      <register>
        <name>SR</name>
        <addressOffset>0x0</addressOffset>
        <size>0x20</size>
        <fields>
          <field>
            <name>PE</name>
            <bitOffset>0</bitOffset>
            <bitWidth>1</bitWidth>
          </field>
          <field>
            <name>FE</name>
            <bitOffset>1</bitOffset>
            <bitWidth>1</bitWidth>
          </field>
          <field>
            <name>NE</name>
            <bitOffset>2</bitOffset>
            <bitWidth>1</bitWidth>
          </field>
          <field>
            <name>ORE</name>
            <bitOffset>3</bitOffset>
            <bitWidth>1</bitWidth>
          </field>
          <field>
            <name>IDLE</name>
            <bitOffset>4</bitOffset>
            <bitWidth>1</bitWidth>
          </field>
          <field>
            <name>RXNE</name>
            <bitOffset>5</bitOffset>
            <bitWidth>1</bitWidth>
          </field>
          <field>
            <name>TC</name>
            <bitOffset>6</bitOffset>
            <bitWidth>1</bitWidth>
          </field>
          <field>
            <name>TXE</name>
            <bitOffset>7</bitOffset>
            <bitWidth>1</bitWidth>
          </field>
          <field>
            <name>LBD</name>
            <bitOffset>8</bitOffset>
            <bitWidth>1</bitWidth>
          </field>
          <field>
            <name>CTS</name>
            <bitOffset>9</bitOffset>
            <bitWidth>1</bitWidth>
          </field>
        </fields>
      </register>
      <register>
        <name>DR</name>
        <addressOffset>0x4</addressOffset>
        <size>0x20</size>
        <fields>
          <field>
            <name>DR</name>
            <bitOffset>0</bitOffset>
            <bitWidth>9</bitWidth>
          </field>
        </fields>
      </register>
      <register>
        <name>BRR</name>
        <addressOffset>0x8</addressOffset>
        <size>0x20</size>
        <fields>
          <field>
            <name>DIV_Fraction</name>
            <bitOffset>0</bitOffset>
            <bitWidth>4</bitWidth>
          </field>
          <field>
            <name>DIV_Mantissa</name>
            <bitOffset>4</bitOffset>
            <bitWidth>12</bitWidth>
          </field>
        </fields>
      </register>
      <register>
        <name>CR1</name>
        <addressOffset>0xc</addressOffset>
        <size>0x20</size>
        <fields>
          <field>
            <name>SBK</name>
            <bitOffset>0</bitOffset>
            <bitWidth>1</bitWidth>
          </field>
          <field>
            <name>RWU</name>
            <bitOffset>1</bitOffset>
            <bitWidth>1</bitWidth>
          </field>
          <field>
            <name>RE</name>
            <bitOffset>2</bitOffset>
            <bitWidth>1</bitWidth>
          </field>
          <field>
            <name>TE</name>
            <bitOffset>3</bitOffset>
            <bitWidth>1</bitWidth>
          </field>
          <field>
            <name>IDLEIE</name>
            <bitOffset>4</bitOffset>
            <bitWidth>1</bitWidth>
          </field>
          <field>
            <name>RXNEIE</name>
            <bitOffset>5</bitOffset>
            <bitWidth>1</bitWidth>
          </field>
          <field>
            <name>TCIE</name>
            <bitOffset>6</bitOffset>
            <bitWidth>1</bitWidth>
          </field>
          <field>
            <name>TXEIE</name>
            <bitOffset>7</bitOffset>
            <bitWidth>1</bitWidth>
          </field>
          <field>
            <name>PEIE</name>
            <bitOffset>8</bitOffset>
            <bitWidth>1</bitWidth>
          </field>
          <field>
            <name>PS</name>
            <bitOffset>9</bitOffset>
            <bitWidth>1</bitWidth>
          </field>
          <field>
            <name>PCE</name>
            <bitOffset>10</bitOffset>
            <bitWidth>1</bitWidth>
          </field>
          <field>
            <name>WAKE</name>
            <bitOffset>11</bitOffset>
            <bitWidth>1</bitWidth>
          </field>
          <field>
            <name>M</name>
            <bitOffset>12</bitOffset>
            <bitWidth>1</bitWidth>
          </field>
          <field>
            <name>UE</name>
            <bitOffset>13</bitOffset>
            <bitWidth>1</bitWidth>
          </field>
          <field>
            <name>OVER8</name>
            <bitOffset>15</bitOffset>
            <bitWidth>1</bitWidth>
          </field>
        </fields>
      </register>
      <register>
        <name>CR2</name>
        <addressOffset>0x10</addressOffset>
        <size>0x20</size>
        <fields>
          <field>
            <name>ADD</name>
            <bitOffset>0</bitOffset>
            <bitWidth>4</bitWidth>
          </field>
          <field>
            <name>LBDL</name>
            <bitOffset>5</bitOffset>
            <bitWidth>1</bitWidth>
          </field>
          <field>
            <name>LBDIE</name>
            <bitOffset>6</bitOffset>
            <bitWidth>1</bitWidth>
          </field>
          <field>
            <name>LBCL</name>
            <bitOffset>8</bitOffset>
            <bitWidth>1</bitWidth>
          </field>
          <field>
            <name>CPHA</name>
            <bitOffset>9</bitOffset>
            <bitWidth>1</bitWidth>
          </field>
          <field>
            <name>CPOL</name>
            <bitOffset>10</bitOffset>
            <bitWidth>1</bitWidth>
          </field>
          <field>
            <name>CLKEN</name>
            <bitOffset>11</bitOffset>
            <bitWidth>1</bitWidth>
          </field>
          <field>
            <name>STOP</name>
            <bitOffset>12</bitOffset>
            <bitWidth>2</bitWidth>
          </field>
          <field>
            <name>LINEN</name>
            <bitOffset>14</bitOffset>
            <bitWidth>1</bitWidth>
          </field>
        </fields>
      </register>
      <register>
        <name>CR3</name>
        <addressOffset>0x14</addressOffset>
        <size>0x20</size>
        <fields>
          <field>
            <name>EIE</name>
            <bitOffset>0</bitOffset>
            <bitWidth>1</bitWidth>
          </field>
          <field>
            <name>IREN</name>
            <bitOffset>1</bitOffset>
            <bitWidth>1</bitWidth>
          </field>
          <field>
            <name>IRLP</name>
            <bitOffset>2</bitOffset>
            <bitWidth>1</bitWidth>
          </field>
          <field>
            <name>HDSEL</name>
            <bitOffset>3</bitOffset>
            <bitWidth>1</bitWidth>
          </field>
          <field>
            <name>NACK</name>
            <bitOffset>4</bitOffset>
            <bitWidth>1</bitWidth>
          </field>
          <field>
            <name>SCEN</name>
            <bitOffset>5</bitOffset>
            <bitWidth>1</bitWidth>
          </field>
          <field>
            <name>DMAR</name>
            <bitOffset>6</bitOffset>
            <bitWidth>1</bitWidth>
          </field>
          <field>
            <name>DMAT</name>
            <bitOffset>7</bitOffset>
            <bitWidth>1</bitWidth>
          </field>
          <field>
            <name>RTSE</name>
            <bitOffset>8</bitOffset>
            <bitWidth>1</bitWidth>
          </field>
          <field>
            <name>CTSE</name>
            <bitOffset>9</bitOffset>
            <bitWidth>1</bitWidth>
          </field>
          <field>
            <name>CTSIE</name>
            <bitOffset>10</bitOffset>
            <bitWidth>1</bitWidth>
          </field>
          <field>
            <name>ONEBIT</name>
            <bitOffset>11</bitOffset>
            <bitWidth>1</bitWidth>
          </field>
        </fields>
      </register>
      <register>
        <name>GTPR</name>
        <addressOffset>0x18</addressOffset>
        <size>0x20</size>
        <fields>
          <field>
            <name>PSC</name>
            <bitOffset>0</bitOffset>
            <bitWidth>8</bitWidth>
          </field>
          <field>
            <name>GT</name>
            <bitOffset>8</bitOffset>
            <bitWidth>8</bitWidth>
          </field>
        </fields>
      </register>
    </peripheral>
    <peripheral>
      <name>TIM1</name>
      <baseAddress>0x40010000</baseAddress>
      <register>
        <name>CR1</name>
        <addressOffset>0x0</addressOffset>
        <size>0x20</size>
        <fields>
          <field>
            <name>CEN</name>
            <bitOffset>0</bitOffset>
            <bitWidth>1</bitWidth>
          </field>
          <field>
            <name>UDIS</name>
            <bitOffset>1</bitOffset>
            <bitWidth>1</bitWidth>
          </field>
          <field>
            <name>URS</name>
            <bitOffset>2</bitOffset>
            <bitWidth>1</bitWidth>
          </field>
          <field>
            <name>OPM</name>
            <bitOffset>3</bitOffset>
            <bitWidth>1</bitWidth>
          </field>
          <field>
            <name>DIR</name>
            <bitOffset>4</bitOffset>
            <bitWidth>1</bitWidth>
          </field>
          <field>
            <name>CMS</name>
            <bitOffset>5</bitOffset>
            <bitWidth>2</bitWidth>
          </field>
          <field>
            <name>ARPE</name>
            <bitOffset>7</bitOffset>
            <bitWidth>1</bitWidth>
          </field>
          <field>
            <name>CKD</name>
            <bitOffset>8</bitOffset>
            <bitWidth>2</bitWidth>
          </field>
        </fields>
      </register>
      <register>
        <name>CR2</name>
        <addressOffset>0x4</addressOffset>
        <size>0x20</size>
        <fields>
          <field>
            <name>CCPC</name>
            <bitOffset>0</bitOffset>
            <bitWidth>1</bitWidth>
          </field>
          <field>
            <name>CCUS</name>
            <bitOffset>2</bitOffset>
            <bitWidth>1</bitWidth>
          </field>
          <field>
            <name>CCDS</name>
            <bitOffset>3</bitOffset>
            <bitWidth>1</bitWidth>
          </field>
          <field>
            <name>MMS</name>
            <bitOffset>4</bitOffset>
            <bitWidth>3</bitWidth>
          </field>
          <field>
            <name>TI1S</name>
            <bitOffset>7</bitOffset>
            <bitWidth>1</bitWidth>
          </field>
          <field>
            <name>OIS1</name>
            <bitOffset>8</bitOffset>
            <bitWidth>1</bitWidth>
          </field>
          <field>
            <name>OIS1N</name>
            <bitOffset>9</bitOffset>
            <bitWidth>1</bitWidth>
          </field>
          <field>
            <name>OIS2</name>
            <bitOffset>10</bitOffset>
            <bitWidth>1</bitWidth>
          </field>
          <field>
            <name>OIS2N</name>
            <bitOffset>11</bitOffset>
            <bitWidth>1</bitWidth>
          </field>
          <field>
            <name>OIS3</name>
            <bitOffset>12</bitOffset>
            <bitWidth>1</bitWidth>
          </field>
          <field>
            <name>OIS3N</name>
            <bitOffset>13</bitOffset>
            <bitWidth>1</bitWidth>
          </field>
          <field>
            <name>OIS4</name>
            <bitOffset>14</bitOffset>
            <bitWidth>1</bitWidth>
          </field>
        </fields>
      </register>
      <register>
        <name>SMCR</name>
        <addressOffset>0x8</addressOffset>
        <size>0x20</size>
        <fields>
          <field>
            <name>SMS</name>
            <bitOffset>0</bitOffset>
            <bitWidth>3</bitWidth>
          </field>
          <field>
            <name>TS</name>
            <bitOffset>4</bitOffset>
            <bitWidth>3</bitWidth>
          </field>
          <field>
            <name>MSM</name>
            <bitOffset>7</bitOffset>
            <bitWidth>1</bitWidth>
          </field>
          <field>
            <name>ETF</name>
            <bitOffset>8</bitOffset>
            <bitWidth>4</bitWidth>
          </field>
          <field>
            <name>ETPS</name>
            <bitOffset>12</bitOffset>
            <bitWidth>2</bitWidth>
          </field>
          <field>
            <name>ECE</name>
            <bitOffset>14</bitOffset>
            <bitWidth>1</bitWidth>
          </field>
          <field>
            <name>ETP</name>
            <bitOffset>15</bitOffset>
            <bitWidth>1</bitWidth>
          </field>
        </fields>
      </register>
      <register>
        <name>DIER</name>
        <addressOffset>0xc</addressOffset>
        <size>0x20</size>
        <fields>
          <field>
            <name>UIE</name>
            <bitOffset>0</bitOffset>
            <bitWidth>1</bitWidth>
          </field>
          <field>
            <name>CC1IE</name>
            <bitOffset>1</bitOffset>
            <bitWidth>1</bitWidth>
          </field>
          <field>
            <name>CC2IE</name>
            <bitOffset>2</bitOffset>
            <bitWidth>1</bitWidth>
          </field>
          <field>
            <name>CC3IE</name>
            <bitOffset>3</bitOffset>
            <bitWidth>1</bitWidth>
          </field>
          <field>
            <name>CC4IE</name>
            <bitOffset>4</bitOffset>
            <bitWidth>1</bitWidth>
          </field>
          <field>
            <name>COMIE</name>
            <bitOffset>5</bitOffset>
            <bitWidth>1</bitWidth>
          </field>
          <field>
            <name>TIE</name>
            <bitOffset>6</bitOffset>
            <bitWidth>1</bitWidth>
          </field>
          <field>
            <name>BIE</name>
            <bitOffset>7</bitOffset>
            <bitWidth>1</bitWidth>
          </field>
          <field>
            <name>UDE</name>
            <bitOffset>8</bitOffset>
            <bitWidth>1</bitWidth>
          </field>
          <field>
            <name>CC1DE</name>
            <bitOffset>9</bitOffset>
            <bitWidth>1</bitWidth>
          </field>
          <field>
            <name>CC2DE</name>
            <bitOffset>10</bitOffset>
            <bitWidth>1</bitWidth>
          </field>
          <field>
            <name>CC3DE</name>
            <bitOffset>11</bitOffset>
            <bitWidth>1</bitWidth>
          </field>
          <field>
            <name>CC4DE</name>
            <bitOffset>12</bitOffset>
            <bitWidth>1</bitWidth>
          </field>
          <field>
            <name>COMDE</name>
            <bitOffset>13</bitOffset>
            <bitWidth>1</bitWidth>
          </field>
          <field>
            <name>TDE</name>
            <bitOffset>14</bitOffset>
            <bitWidth>1</bitWidth>
          </field>
        </fields>
      </register>
      <register>
        <name>SR</name>
        <addressOffset>0x10</addressOffset>
        <size>0x20</size>
        <fields>
          <field>
            <name>UIF</name>
            <bitOffset>0</bitOffset>
            <bitWidth>1</bitWidth>
          </field>
          <field>
            <name>CC1IF</name>
            <bitOffset>1</bitOffset>
            <bitWidth>1</bitWidth>
          </field>
          <field>
            <name>CC2IF</name>
            <bitOffset>2</bitOffset>
            <bitWidth>1</bitWidth>
          </field>
          <field>
            <name>CC3IF</name>
            <bitOffset>3</bitOffset>
            <bitWidth>1</bitWidth>
          </field>
          <field>
            <name>CC4IF</name>
            <bitOffset>4</bitOffset>
            <bitWidth>1</bitWidth>
          </field>
          <field>
            <name>COMIF</name>
            <bitOffset>5</bitOffset>
            <bitWidth>1</bitWidth>
          </field>
          <field>
            <name>TIF</name>
            <bitOffset>6</bitOffset>
            <bitWidth>1</bitWidth>
          </field>
          <field>
            <name>BIF</name>
            <bitOffset>7</bitOffset>
            <bitWidth>1</bitWidth>
          </field>
          <field>
            <name>CC1OF</name>
            <bitOffset>9</bitOffset>
            <bitWidth>1</bitWidth>
          </field>
          <field>
            <name>CC2OF</name>
            <bitOffset>10</bitOffset>
            <bitWidth>1</bitWidth>
          </field>
          <field>
            <name>CC3OF</name>
            <bitOffset>11</bitOffset>
            <bitWidth>1</bitWidth>
          </field>
          <field>
            <name>CC4OF</name>
            <bitOffset>12</bitOffset>
            <bitWidth>1</bitWidth>
          </field>
        </fields>
      </register>
      <register>
        <name>EGR</name>
        <addressOffset>0x14</addressOffset>
        <size>0x20</size>
        <fields>
          <field>
            <name>UG</name>
            <bitOffset>0</bitOffset>
            <bitWidth>1</bitWidth>
          </field>
          <field>
            <name>CC1G</name>
            <bitOffset>1</bitOffset>
            <bitWidth>1</bitWidth>
          </field>
          <field>
            <name>CC2G</name>
            <bitOffset>2</bitOffset>
            <bitWidth>1</bitWidth>
          </field>
          <field>
            <name>CC3G</name>
            <bitOffset>3</bitOffset>
            <bitWidth>1</bitWidth>
          </field>
          <field>
            <name>CC4G</name>
            <bitOffset>4</bitOffset>
            <bitWidth>1</bitWidth>
          </field>
          <field>
            <name>COMG</name>
            <bitOffset>5</bitOffset>
            <bitWidth>1</bitWidth>
          </field>
          <field>
            <name>TG</name>
            <bitOffset>6</bitOffset>
            <bitWidth>1</bitWidth>
          </field>
          <field>
            <name>BG</name>
            <bitOffset>7</bitOffset>
            <bitWidth>1</bitWidth>
          </field>
        </fields>
      </register>
      <register>
        <name>CCMR1</name>
        <addressOffset>0x18</addressOffset>
        <size>0x20</size>
        <fields>
          <field>
            <name>CC1S</name>
            <bitOffset>0</bitOffset>
            <bitWidth>2</bitWidth>
          </field>
          <field>
            <name>OC1FE</name>
            <bitOffset>2</bitOffset>
            <bitWidth>1</bitWidth>
          </field>
          <field>
            <name>OC1PE</name>
            <bitOffset>3</bitOffset>
            <bitWidth>1</bitWidth>
          </field>
          <field>
            <name>OC1M</name>
            <bitOffset>4</bitOffset>
            <bitWidth>3</bitWidth>
          </field>
          <field>
            <name>OC1CE</name>
            <bitOffset>7</bitOffset>
            <bitWidth>1</bitWidth>
          </field>
          <field>
            <name>CC2S</name>
            <bitOffset>8</bitOffset>
            <bitWidth>2</bitWidth>
          </field>
          <field>
            <name>OC2FE</name>
            <bitOffset>10</bitOffset>
            <bitWidth>1</bitWidth>
          </field>
          <field>
            <name>OC2PE</name>
            <bitOffset>11</bitOffset>
            <bitWidth>1</bitWidth>
          </field>
          <field>
            <name>OC2M</name>
            <bitOffset>12</bitOffset>
            <bitWidth>3</bitWidth>
          </field>
          <field>
            <name>OC2CE</name>
            <bitOffset>15</bitOffset>
            <bitWidth>1</bitWidth>
          </field>
        </fields>
      </register>
      <register>
        <name>CCMR2</name>
        <addressOffset>0x1c</addressOffset>
        <size>0x20</size>
        <fields>
          <field>
            <name>CC3S</name>
            <bitOffset>0</bitOffset>
            <bitWidth>2</bitWidth>
          </field>
          <field>
            <name>OC3FE</name>
            <bitOffset>2</bitOffset>
            <bitWidth>1</bitWidth>
          </field>
          <field>
            <name>OC3PE</name>
            <bitOffset>3</bitOffset>
            <bitWidth>1</bitWidth>
          </field>
          <field>
            <name>OC3M</name>
            <bitOffset>4</bitOffset>
            <bitWidth>3</bitWidth>
          </field>
          <field>
            <name>OC3CE</name>
            <bitOffset>7</bitOffset>
            <bitWidth>1</bitWidth>
          </field>
          <field>
            <name>CC4S</name>
            <bitOffset>8</bitOffset>
            <bitWidth>2</bitWidth>
          </field>
          <field>
            <name>OC4FE</name>
            <bitOffset>10</bitOffset>
            <bitWidth>1</bitWidth>
          </field>
          <field>
            <name>OC4PE</name>
            <bitOffset>11</bitOffset>
            <bitWidth>1</bitWidth>
          </field>
          <field>
            <name>OC4M</name>
            <bitOffset>12</bitOffset>
            <bitWidth>3</bitWidth>
          </field>
          <field>
            <name>OC4CE</name>
            <bitOffset>15</bitOffset>
            <bitWidth>1</bitWidth>
          </field>
        </fields>
      </register>
      <register>
        <name>CCER</name>
        <addressOffset>0x20</addressOffset>
        <size>0x20</size>
        <fields>
          <field>
            <name>CC1E</name>
            <bitOffset>0</bitOffset>
            <bitWidth>1</bitWidth>
          </field>
          <field>
            <name>CC1P</name>
            <bitOffset>1</bitOffset>
            <bitWidth>1</bitWidth>
          </field>
          <field>
            <name>CC1NE</name>
            <bitOffset>2</bitOffset>
            <bitWidth>1</bitWidth>
          </field>
          <field>
            <name>CC1NP</name>
            <bitOffset>3</bitOffset>
            <bitWidth>1</bitWidth>
          </field>
          <field>
            <name>CC2E</name>
            <bitOffset>4</bitOffset>
            <bitWidth>1</bitWidth>
          </field>
          <field>
            <name>CC2P</name>
            <bitOffset>5</bitOffset>
            <bitWidth>1</bitWidth>
          </field>
          <field>
            <name>CC2NE</name>
            <bitOffset>6</bitOffset>
            <bitWidth>1</bitWidth>
          </field>
          <field>
            <name>CC2NP</name>
            <bitOffset>7</bitOffset>
            <bitWidth>1</bitWidth>
          </field>
          <field>
            <name>CC3E</name>
            <bitOffset>8</bitOffset>
            <bitWidth>1</bitWidth>
          </field>
          <field>
            <name>CC3P</name>
            <bitOffset>9</bitOffset>
            <bitWidth>1</bitWidth>
          </field>
          <field>
            <name>CC3NE</name>
            <bitOffset>10</bitOffset>
            <bitWidth>1</bitWidth>
          </field>
          <field>
            <name>CC3NP</name>
            <bitOffset>11</bitOffset>
            <bitWidth>1</bitWidth>
          </field>
          <field>
            <name>CC4E</name>
            <bitOffset>12</bitOffset>
            <bitWidth>1</bitWidth>
          </field>
          <field>
            <name>CC4P</name>
            <bitOffset>13</bitOffset>
            <bitWidth>1</bitWidth>
          </field>
          <field>
            <name>CC4NP</name>
            <bitOffset>15</bitOffset>
            <bitWidth>1</bitWidth>
          </field>
        </fields>
      </register>
      <register>
        <name>CNT</name>
        <addressOffset>0x24</addressOffset>
        <size>0x20</size>
        <fields>
          <field>
            <name>CNT</name>
            <bitOffset>0</bitOffset>
            <bitWidth>32</bitWidth>
          </field>
        </fields>
      </register>
      <register>
        <name>PSC</name>
        <addressOffset>0x28</addressOffset>
        <size>0x20</size>
        <fields>
          <field>
            <name>PSC</name>
            <bitOffset>0</bitOffset>
            <bitWidth>16</bitWidth>
          </field>
        </fields>
      </register>
      <register>
        <name>ARR</name>
        <addressOffset>0x2c</addressOffset>
        <size>0x20</size>
        <fields>
          <field>
            <name>ARR</name>
            <bitOffset>0</bitOffset>
            <bitWidth>32</bitWidth>
          </field>
        </fields>
      </register>
      <register>
        <name>RCR</name>
        <addressOffset>0x30</addressOffset>
        <size>0x20</size>
        <fields>
          <field>
            <name>REP</name>
            <bitOffset>0</bitOffset>
            <bitWidth>8</bitWidth>
          </field>
        </fields>
      </register>
      <register>
        <name>CCR1</name>
        <addressOffset>0x34</addressOffset>
        <size>0x20</size>
        <fields>
          <field>
            <name>CCR1</name>
            <bitOffset>0</bitOffset>
            <bitWidth>16</bitWidth>
          </field>
        </fields>
      </register>
      <register>
        <name>CCR2</name>
        <addressOffset>0x38</addressOffset>
        <size>0x20</size>
        <fields>
          <field>
            <name>CCR2</name>
            <bitOffset>0</bitOffset>
            <bitWidth>16</bitWidth>
          </field>
        </fields>
      </register>
      <register>
        <name>CCR3</name>
        <addressOffset>0x3c</addressOffset>
        <size>0x20</size>
        <fields>
          <field>
            <name>CCR3</name>
            <bitOffset>0</bitOffset>
            <bitWidth>16</bitWidth>
          </field>
        </fields>
      </register>
      <register>
        <name>CCR4</name>
        <addressOffset>0x40</addressOffset>
        <size>0x20</size>
        <fields>
          <field>
            <name>CCR4</name>
            <bitOffset>0</bitOffset>
            <bitWidth>16</bitWidth>
          </field>
        </fields>
      </register>
      <register>
        <name>BDTR</name>
        <addressOffset>0x44</addressOffset>
        <size>0x20</size>
        <fields>
          <field>
            <name>DTG</name>
            <bitOffset>0</bitOffset>
            <bitWidth>8</bitWidth>
          </field>
          <field>
            <name>LOCK</name>
            <bitOffset>8</bitOffset>
            <bitWidth>2</bitWidth>
          </field>
          <field>
            <name>OSSI</name>
            <bitOffset>10</bitOffset>
            <bitWidth>1</bitWidth>
          </field>
          <field>
            <name>OSSR</name>
            <bitOffset>11</bitOffset>
            <bitWidth>1</bitWidth>
          </field>
          <field>
            <name>BKE</name>
            <bitOffset>12</bitOffset>
            <bitWidth>1</bitWidth>
          </field>
          <field>
            <name>BKP</name>
            <bitOffset>13</bitOffset>
            <bitWidth>1</bitWidth>
          </field>
          <field>
            <name>AOE</name>
            <bitOffset>14</bitOffset>
            <bitWidth>1</bitWidth>
          </field>
          <field>
            <name>MOE</name>
            <bitOffset>15</bitOffset>
            <bitWidth>1</bitWidth>
          </field>
        </fields>
      </register>
      <register>
        <name>DCR</name>
        <addressOffset>0x48</addressOffset>
        <size>0x20</size>
        <fields>
          <field>
            <name>DBA</name>
            <bitOffset>0</bitOffset>
            <bitWidth>5</bitWidth>
          </field>
          <field>
            <name>DBL</name>
            <bitOffset>8</bitOffset>
            <bitWidth>5</bitWidth>
          </field>
        </fields>
      </register>
      <register>
        <name>DMAR</name>
        <addressOffset>0x4c</addressOffset>
        <size>0x20</size>
        <fields>
          <field>
            <name>DMAB</name>
            <bitOffset>0</bitOffset>
            <bitWidth>16</bitWidth>
          </field>
        </fields>
      </register>
      <register>
        <name>OR</name>
        <addressOffset>0x50</addressOffset>
        <size>0x20</size>
        <fields>
          <field>
            <name>TI1_RMP</name>
            <bitOffset>0</bitOffset>
            <bitWidth>2</bitWidth>
          </field>
          <field>
            <name>TI4_RMP</name>
            <bitOffset>6</bitOffset>
            <bitWidth>2</bitWidth>
          </field>
          <field>
            <name>ITR1_RMP</name>
            <bitOffset>10</bitOffset>
            <bitWidth>2</bitWidth>
          </field>
        </fields>
      </register>
    </peripheral>
    <peripheral>
      <name>TIM8</name>
      <baseAddress>0x40010400</baseAddress>
      <register>
        <name>CR1</name>
        <addressOffset>0x0</addressOffset>
        <size>0x20</size>
        <fields>
          <field>
            <name>CEN</name>
            <bitOffset>0</bitOffset>
            <bitWidth>1</bitWidth>
          </field>
          <field>
            <name>UDIS</name>
            <bitOffset>1</bitOffset>
            <bitWidth>1</bitWidth>
          </field>
          <field>
            <name>URS</name>
            <bitOffset>2</bitOffset>
            <bitWidth>1</bitWidth>
          </field>
          <field>
            <name>OPM</name>
            <bitOffset>3</bitOffset>
            <bitWidth>1</bitWidth>
          </field>
          <field>
            <name>DIR</name>
            <bitOffset>4</bitOffset>
            <bitWidth>1</bitWidth>
          </field>
          <field>
            <name>CMS</name>
            <bitOffset>5</bitOffset>
            <bitWidth>2</bitWidth>
          </field>
          <field>
            <name>ARPE</name>
            <bitOffset>7</bitOffset>
            <bitWidth>1</bitWidth>
          </field>
          <field>
            <name>CKD</name>
            <bitOffset>8</bitOffset>
            <bitWidth>2</bitWidth>
          </field>
        </fields>
      </register>
      <register>
        <name>CR2</name>
        <addressOffset>0x4</addressOffset>
        <size>0x20</size>
        <fields>
          <field>
            <name>CCPC</name>
            <bitOffset>0</bitOffset>
            <bitWidth>1</bitWidth>
          </field>
          <field>
            <name>CCUS</name>
            <bitOffset>2</bitOffset>
            <bitWidth>1</bitWidth>
          </field>
          <field>
            <name>CCDS</name>
            <bitOffset>3</bitOffset>
            <bitWidth>1</bitWidth>
          </field>
          <field>
            <name>MMS</name>
            <bitOffset>4</bitOffset>
            <bitWidth>3</bitWidth>
          </field>
          <field>
            <name>TI1S</name>
            <bitOffset>7</bitOffset>
            <bitWidth>1</bitWidth>
          </field>
          <field>
            <name>OIS1</name>
            <bitOffset>8</bitOffset>
            <bitWidth>1</bitWidth>
          </field>
          <field>
            <name>OIS1N</name>
            <bitOffset>9</bitOffset>
            <bitWidth>1</bitWidth>
          </field>
          <field>
            <name>OIS2</name>
            <bitOffset>10</bitOffset>
            <bitWidth>1</bitWidth>
          </field>
          <field>
            <name>OIS2N</name>
            <bitOffset>11</bitOffset>
            <bitWidth>1</bitWidth>
          </field>
          <field>
            <name>OIS3</name>
            <bitOffset>12</bitOffset>
            <bitWidth>1</bitWidth>
          </field>
          <field>
            <name>OIS3N</name>
            <bitOffset>13</bitOffset>
            <bitWidth>1</bitWidth>
          </field>
          <field>
            <name>OIS4</name>
            <bitOffset>14</bitOffset>
            <bitWidth>1</bitWidth>
          </field>
        </fields>
      </register>
      <register>
        <name>SMCR</name>
        <addressOffset>0x8</addressOffset>
        <size>0x20</size>
        <fields>
          <field>
            <name>SMS</name>
            <bitOffset>0</bitOffset>
            <bitWidth>3</bitWidth>
          </field>
          <field>
            <name>TS</name>
            <bitOffset>4</bitOffset>
            <bitWidth>3</bitWidth>
          </field>
          <field>
            <name>MSM</name>
            <bitOffset>7</bitOffset>
            <bitWidth>1</bitWidth>
          </field>
          <field>
            <name>ETF</name>
            <bitOffset>8</bitOffset>
            <bitWidth>4</bitWidth>
          </field>
          <field>
            <name>ETPS</name>
            <bitOffset>12</bitOffset>
            <bitWidth>2</bitWidth>
          </field>
          <field>
            <name>ECE</name>
            <bitOffset>14</bitOffset>
            <bitWidth>1</bitWidth>
          </field>
          <field>
            <name>ETP</name>
            <bitOffset>15</bitOffset>
            <bitWidth>1</bitWidth>
          </field>
        </fields>
      </register>
      <register>
        <name>DIER</name>
        <addressOffset>0xc</addressOffset>
        <size>0x20</size>
        <fields>
          <field>
            <name>UIE</name>
            <bitOffset>0</bitOffset>
            <bitWidth>1</bitWidth>
          </field>
          <field>
            <name>CC1IE</name>
            <bitOffset>1</bitOffset>
            <bitWidth>1</bitWidth>
          </field>
          <field>
            <name>CC2IE</name>
            <bitOffset>2</bitOffset>
            <bitWidth>1</bitWidth>
          </field>
          <field>
            <name>CC3IE</name>
            <bitOffset>3</bitOffset>
            <bitWidth>1</bitWidth>
          </field>
          <field>
            <name>CC4IE</name>
            <bitOffset>4</bitOffset>
            <bitWidth>1</bitWidth>
          </field>
          <field>
            <name>COMIE</name>
            <bitOffset>5</bitOffset>
            <bitWidth>1</bitWidth>
          </field>
          <field>
            <name>TIE</name>
            <bitOffset>6</bitOffset>
            <bitWidth>1</bitWidth>
          </field>
          <field>
            <name>BIE</name>
            <bitOffset>7</bitOffset>
            <bitWidth>1</bitWidth>
          </field>
          <field>
            <name>UDE</name>
            <bitOffset>8</bitOffset>
            <bitWidth>1</bitWidth>
          </field>
          <field>
            <name>CC1DE</name>
            <bitOffset>9</bitOffset>
            <bitWidth>1</bitWidth>
          </field>
          <field>
            <name>CC2DE</name>
            <bitOffset>10</bitOffset>
            <bitWidth>1</bitWidth>
          </field>
          <field>
            <name>CC3DE</name>
            <bitOffset>11</bitOffset>
            <bitWidth>1</bitWidth>
          </field>
          <field>
            <name>CC4DE</name>
            <bitOffset>12</bitOffset>
            <bitWidth>1</bitWidth>
          </field>
          <field>
            <name>COMDE</name>
            <bitOffset>13</bitOffset>
            <bitWidth>1</bitWidth>
          </field>
          <field>
            <name>TDE</name>
            <bitOffset>14</bitOffset>
            <bitWidth>1</bitWidth>
          </field>
        </fields>
      </register>
      <register>
        <name>SR</name>
        <addressOffset>0x10</addressOffset>
        <size>0x20</size>
        <fields>
          <field>
            <name>UIF</name>
            <bitOffset>0</bitOffset>
            <bitWidth>1</bitWidth>
          </field>
          <field>
            <name>CC1IF</name>
            <bitOffset>1</bitOffset>
            <bitWidth>1</bitWidth>
          </field>
          <field>
            <name>CC2IF</name>
            <bitOffset>2</bitOffset>
            <bitWidth>1</bitWidth>
          </field>
          <field>
            <name>CC3IF</name>
            <bitOffset>3</bitOffset>
            <bitWidth>1</bitWidth>
          </field>
          <field>
            <name>CC4IF</name>
            <bitOffset>4</bitOffset>
            <bitWidth>1</bitWidth>
          </field>
          <field>
            <name>COMIF</name>
            <bitOffset>5</bitOffset>
            <bitWidth>1</bitWidth>
          </field>
          <field>
            <name>TIF</name>
            <bitOffset>6</bitOffset>
            <bitWidth>1</bitWidth>
          </field>
          <field>
            <name>BIF</name>
            <bitOffset>7</bitOffset>
            <bitWidth>1</bitWidth>
          </field>
          <field>
            <name>CC1OF</name>
            <bitOffset>9</bitOffset>
            <bitWidth>1</bitWidth>
          </field>
          <field>
            <name>CC2OF</name>
            <bitOffset>10</bitOffset>
            <bitWidth>1</bitWidth>
          </field>
          <field>
            <name>CC3OF</name>
            <bitOffset>11</bitOffset>
            <bitWidth>1</bitWidth>
          </field>
          <field>
            <name>CC4OF</name>
            <bitOffset>12</bitOffset>
            <bitWidth>1</bitWidth>
          </field>
        </fields>
      </register>
      <register>
        <name>EGR</name>
        <addressOffset>0x14</addressOffset>
        <size>0x20</size>
        <fields>
          <field>
            <name>UG</name>
            <bitOffset>0</bitOffset>
            <bitWidth>1</bitWidth>
          </field>
          <field>
            <name>CC1G</name>
            <bitOffset>1</bitOffset>
            <bitWidth>1</bitWidth>
          </field>
          <field>
            <name>CC2G</name>
            <bitOffset>2</bitOffset>
            <bitWidth>1</bitWidth>
          </field>
          <field>
            <name>CC3G</name>
            <bitOffset>3</bitOffset>
            <bitWidth>1</bitWidth>
          </field>
          <field>
            <name>CC4G</name>
            <bitOffset>4</bitOffset>
            <bitWidth>1</bitWidth>
          </field>
          <field>
            <name>COMG</name>
            <bitOffset>5</bitOffset>
            <bitWidth>1</bitWidth>
          </field>
          <field>
            <name>TG</name>
            <bitOffset>6</bitOffset>
            <bitWidth>1</bitWidth>
          </field>
          <field>
            <name>BG</name>
            <bitOffset>7</bitOffset>
            <bitWidth>1</bitWidth>
          </field>
        </fields>
      </register>
      <register>
        <name>CCMR1</name>
        <addressOffset>0x18</addressOffset>
        <size>0x20</size>
        <fields>
          <field>
            <name>CC1S</name>
            <bitOffset>0</bitOffset>
            <bitWidth>2</bitWidth>
          </field>
          <field>
            <name>OC1FE</name>
            <bitOffset>2</bitOffset>
            <bitWidth>1</bitWidth>
          </field>
          <field>
            <name>OC1PE</name>
            <bitOffset>3</bitOffset>
            <bitWidth>1</bitWidth>
          </field>
          <field>
            <name>OC1M</name>
            <bitOffset>4</bitOffset>
            <bitWidth>3</bitWidth>
          </field>
          <field>
            <name>OC1CE</name>
            <bitOffset>7</bitOffset>
            <bitWidth>1</bitWidth>
          </field>
          <field>
            <name>CC2S</name>
            <bitOffset>8</bitOffset>
            <bitWidth>2</bitWidth>
          </field>
          <field>
            <name>OC2FE</name>
            <bitOffset>10</bitOffset>
            <bitWidth>1</bitWidth>
          </field>
          <field>
            <name>OC2PE</name>
            <bitOffset>11</bitOffset>
            <bitWidth>1</bitWidth>
          </field>
          <field>
            <name>OC2M</name>
            <bitOffset>12</bitOffset>
            <bitWidth>3</bitWidth>
          </field>
          <field>
            <name>OC2CE</name>
            <bitOffset>15</bitOffset>
            <bitWidth>1</bitWidth>
          </field>
        </fields>
      </register>
      <register>
        <name>CCMR2</name>
        <addressOffset>0x1c</addressOffset>
        <size>0x20</size>
        <fields>
          <field>
            <name>CC3S</name>
            <bitOffset>0</bitOffset>
            <bitWidth>2</bitWidth>
          </field>
          <field>
            <name>OC3FE</name>
            <bitOffset>2</bitOffset>
            <bitWidth>1</bitWidth>
          </field>
          <field>
            <name>OC3PE</name>
            <bitOffset>3</bitOffset>
            <bitWidth>1</bitWidth>
          </field>
          <field>
            <name>OC3M</name>
            <bitOffset>4</bitOffset>
            <bitWidth>3</bitWidth>
          </field>
          <field>
            <name>OC3CE</name>
            <bitOffset>7</bitOffset>
            <bitWidth>1</bitWidth>
          </field>
          <field>
            <name>CC4S</name>
            <bitOffset>8</bitOffset>
            <bitWidth>2</bitWidth>
          </field>
          <field>
            <name>OC4FE</name>
            <bitOffset>10</bitOffset>
            <bitWidth>1</bitWidth>
          </field>
          <field>
            <name>OC4PE</name>
            <bitOffset>11</bitOffset>
            <bitWidth>1</bitWidth>
          </field>
          <field>
            <name>OC4M</name>
            <bitOffset>12</bitOffset>
            <bitWidth>3</bitWidth>
          </field>
          <field>
            <name>OC4CE</name>
            <bitOffset>15</bitOffset>
            <bitWidth>1</bitWidth>
          </field>
        </fields>
      </register>
      <register>
        <name>CCER</name>
        <addressOffset>0x20</addressOffset>
        <size>0x20</size>
        <fields>
          <field>
            <name>CC1E</name>
            <bitOffset>0</bitOffset>
            <bitWidth>1</bitWidth>
          </field>
          <field>
            <name>CC1P</name>
            <bitOffset>1</bitOffset>
            <bitWidth>1</bitWidth>
          </field>
          <field>
            <name>CC1NE</name>
            <bitOffset>2</bitOffset>
            <bitWidth>1</bitWidth>
          </field>
          <field>
            <name>CC1NP</name>
            <bitOffset>3</bitOffset>
            <bitWidth>1</bitWidth>
          </field>
          <field>
            <name>CC2E</name>
            <bitOffset>4</bitOffset>
            <bitWidth>1</bitWidth>
          </field>
          <field>
            <name>CC2P</name>
            <bitOffset>5</bitOffset>
            <bitWidth>1</bitWidth>
          </field>
          <field>
            <name>CC2NE</name>
            <bitOffset>6</bitOffset>
            <bitWidth>1</bitWidth>
          </field>
          <field>
            <name>CC2NP</name>
            <bitOffset>7</bitOffset>
            <bitWidth>1</bitWidth>
          </field>
          <field>
            <name>CC3E</name>
            <bitOffset>8</bitOffset>
            <bitWidth>1</bitWidth>
          </field>
          <field>
            <name>CC3P</name>
            <bitOffset>9</bitOffset>
            <bitWidth>1</bitWidth>
          </field>
          <field>
            <name>CC3NE</name>
            <bitOffset>10</bitOffset>
            <bitWidth>1</bitWidth>
          </field>
          <field>
            <name>CC3NP</name>
            <bitOffset>11</bitOffset>
            <bitWidth>1</bitWidth>
          </field>
          <field>
            <name>CC4E</name>
            <bitOffset>12</bitOffset>
            <bitWidth>1</bitWidth>
          </field>
          <field>
            <name>CC4P</name>
            <bitOffset>13</bitOffset>
            <bitWidth>1</bitWidth>
          </field>
          <field>
            <name>CC4NP</name>
            <bitOffset>15</bitOffset>
            <bitWidth>1</bitWidth>
          </field>
        </fields>
      </register>
      <register>
        <name>CNT</name>
        <addressOffset>0x24</addressOffset>
        <size>0x20</size>
        <fields>
          <field>
            <name>CNT</name>
            <bitOffset>0</bitOffset>
            <bitWidth>32</bitWidth>
          </field>
        </fields>
      </register>
      <register>
        <name>PSC</name>
        <addressOffset>0x28</addressOffset>
        <size>0x20</size>
        <fields>
          <field>
            <name>PSC</name>
            <bitOffset>0</bitOffset>
            <bitWidth>16</bitWidth>
          </field>
        </fields>
      </register>
      <register>
        <name>ARR</name>
        <addressOffset>0x2c</addressOffset>
        <size>0x20</size>
        <fields>
          <field>
            <name>ARR</name>
            <bitOffset>0</bitOffset>
            <bitWidth>32</bitWidth>
          </field>
        </fields>
      </register>
      <register>
        <name>RCR</name>
        <addressOffset>0x30</addressOffset>
        <size>0x20</size>
        <fields>
          <field>
            <name>REP</name>
            <bitOffset>0</bitOffset>
            <bitWidth>8</bitWidth>
          </field>
        </fields>
      </register>
      <register>
        <name>CCR1</name>
        <addressOffset>0x34</addressOffset>
        <size>0x20</size>
        <fields>
          <field>
            <name>CCR1</name>
            <bitOffset>0</bitOffset>
            <bitWidth>16</bitWidth>
          </field>
        </fields>
      </register>
      <register>
        <name>CCR2</name>
        <addressOffset>0x38</addressOffset>
        <size>0x20</size>
        <fields>
          <field>
            <name>CCR2</name>
            <bitOffset>0</bitOffset>
            <bitWidth>16</bitWidth>
          </field>
        </fields>
      </register>
      <register>
        <name>CCR3</name>
        <addressOffset>0x3c</addressOffset>
        <size>0x20</size>
        <fields>
          <field>
            <name>CCR3</name>
            <bitOffset>0</bitOffset>
            <bitWidth>16</bitWidth>
          </field>
        </fields>
      </register>
      <register>
        <name>CCR4</name>
        <addressOffset>0x40</addressOffset>
        <size>0x20</size>
        <fields>
          <field>
            <name>CCR4</name>
            <bitOffset>0</bitOffset>
            <bitWidth>16</bitWidth>
          </field>
        </fields>
      </register>
      <register>
        <name>BDTR</name>
        <addressOffset>0x44</addressOffset>
        <size>0x20</size>
        <fields>
          <field>
            <name>DTG</name>
            <bitOffset>0</bitOffset>
            <bitWidth>8</bitWidth>
          </field>
          <field>
            <name>LOCK</name>
            <bitOffset>8</bitOffset>
            <bitWidth>2</bitWidth>
          </field>
          <field>
            <name>OSSI</name>
            <bitOffset>10</bitOffset>
            <bitWidth>1</bitWidth>
          </field>
          <field>
            <name>OSSR</name>
            <bitOffset>11</bitOffset>
            <bitWidth>1</bitWidth>
          </field>
          <field>
            <name>BKE</name>
            <bitOffset>12</bitOffset>
            <bitWidth>1</bitWidth>
          </field>
          <field>
            <name>BKP</name>
            <bitOffset>13</bitOffset>
            <bitWidth>1</bitWidth>
          </field>
          <field>
            <name>AOE</name>
            <bitOffset>14</bitOffset>
            <bitWidth>1</bitWidth>
          </field>
          <field>
            <name>MOE</name>
            <bitOffset>15</bitOffset>
            <bitWidth>1</bitWidth>
          </field>
        </fields>
      </register>
      <register>
        <name>DCR</name>
        <addressOffset>0x48</addressOffset>
        <size>0x20</size>
        <fields>
          <field>
            <name>DBA</name>
            <bitOffset>0</bitOffset>
            <bitWidth>5</bitWidth>
          </field>
          <field>
            <name>DBL</name>
            <bitOffset>8</bitOffset>
            <bitWidth>5</bitWidth>
          </field>
        </fields>
      </register>
      <register>
        <name>DMAR</name>
        <addressOffset>0x4c</addressOffset>
        <size>0x20</size>
        <fields>
          <field>
            <name>DMAB</name>
            <bitOffset>0</bitOffset>
            <bitWidth>16</bitWidth>
          </field>
        </fields>
      </register>
      <register>
        <name>OR</name>
        <addressOffset>0x50</addressOffset>
        <size>0x20</size>
        <fields>
          <field>
            <name>TI1_RMP</name>
            <bitOffset>0</bitOffset>
            <bitWidth>2</bitWidth>
          </field>
          <field>
            <name>TI4_RMP</name>
            <bitOffset>6</bitOffset>
            <bitWidth>2</bitWidth>
          </field>
          <field>
            <name>ITR1_RMP</name>
            <bitOffset>10</bitOffset>
            <bitWidth>2</bitWidth>
          </field>
        </fields>
      </register>
    </peripheral>
    <peripheral>
      <name>USART1</name>
      <baseAddress>0x40011000</baseAddress>
      <register>
        <name>SR</name>
        <addressOffset>0x0</addressOffset>
        <size>0x20</size>
        <fields>
          <field>
            <name>PE</name>
            <bitOffset>0</bitOffset>
            <bitWidth>1</bitWidth>
          </field>
          <field>
            <name>FE</name>
            <bitOffset>1</bitOffset>
            <bitWidth>1</bitWidth>
          </field>
          <field>
            <name>NE</name>
            <bitOffset>2</bitOffset>
            <bitWidth>1</bitWidth>
          </field>
          <field>
            <name>ORE</name>
            <bitOffset>3</bitOffset>
            <bitWidth>1</bitWidth>
          </field>
          <field>
            <name>IDLE</name>
            <bitOffset>4</bitOffset>
            <bitWidth>1</bitWidth>
          </field>
          <field>
            <name>RXNE</name>
            <bitOffset>5</bitOffset>
            <bitWidth>1</bitWidth>
          </field>
          <field>
            <name>TC</name>
            <bitOffset>6</bitOffset>
            <bitWidth>1</bitWidth>
          </field>
          <field>
            <name>TXE</name>
            <bitOffset>7</bitOffset>
            <bitWidth>1</bitWidth>
          </field>
          <field>
            <name>LBD</name>
            <bitOffset>8</bitOffset>
            <bitWidth>1</bitWidth>
          </field>
          <field>
            <name>CTS</name>
            <bitOffset>9</bitOffset>
            <bitWidth>1</bitWidth>
          </field>
        </fields>
      </register>
      <register>
        <name>DR</name>
        <addressOffset>0x4</addressOffset>
        <size>0x20</size>
        <fields>
          <field>
            <name>DR</name>
            <bitOffset>0</bitOffset>
            <bitWidth>9</bitWidth>
          </field>
        </fields>
      </register>
      <register>
        <name>BRR</name>
        <addressOffset>0x8</addressOffset>
        <size>0x20</size>
        <fields>
          <field>
            <name>DIV_Fraction</name>
            <bitOffset>0</bitOffset>
            <bitWidth>4</bitWidth>
          </field>
          <field>
            <name>DIV_Mantissa</name>
            <bitOffset>4</bitOffset>
            <bitWidth>12</bitWidth>
          </field>
        </fields>
      </register>
      <register>
        <name>CR1</name>
        <addressOffset>0xc</addressOffset>
        <size>0x20</size>
        <fields>
          <field>
            <name>SBK</name>
            <bitOffset>0</bitOffset>
            <bitWidth>1</bitWidth>
          </field>
          <field>
            <name>RWU</name>
            <bitOffset>1</bitOffset>
            <bitWidth>1</bitWidth>
          </field>
          <field>
            <name>RE</name>
            <bitOffset>2</bitOffset>
            <bitWidth>1</bitWidth>
          </field>
          <field>
            <name>TE</name>
            <bitOffset>3</bitOffset>
            <bitWidth>1</bitWidth>
          </field>
          <field>
            <name>IDLEIE</name>
            <bitOffset>4</bitOffset>
            <bitWidth>1</bitWidth>
          </field>
          <field>
            <name>RXNEIE</name>
            <bitOffset>5</bitOffset>
            <bitWidth>1</bitWidth>
          </field>
          <field>
            <name>TCIE</name>
            <bitOffset>6</bitOffset>
            <bitWidth>1</bitWidth>
          </field>
          <field>
            <name>TXEIE</name>
            <bitOffset>7</bitOffset>
            <bitWidth>1</bitWidth>
          </field>
          <field>
            <name>PEIE</name>
            <bitOffset>8</bitOffset>
            <bitWidth>1</bitWidth>
          </field>
          <field>
            <name>PS</name>
            <bitOffset>9</bitOffset>
            <bitWidth>1</bitWidth>
          </field>
          <field>
            <name>PCE</name>
            <bitOffset>10</bitOffset>
            <bitWidth>1</bitWidth>
          </field>
          <field>
            <name>WAKE</name>
            <bitOffset>11</bitOffset>
            <bitWidth>1</bitWidth>
          </field>
          <field>
            <name>M</name>
            <bitOffset>12</bitOffset>
            <bitWidth>1</bitWidth>
          </field>
          <field>
            <name>UE</name>
            <bitOffset>13</bitOffset>
            <bitWidth>1</bitWidth>
          </field>
          <field>
            <name>OVER8</name>
            <bitOffset>15</bitOffset>
            <bitWidth>1</bitWidth>
          </field>
        </fields>
      </register>
      <register>
        <name>CR2</name>
        <addressOffset>0x10</addressOffset>
        <size>0x20</size>
        <fields>
          <field>
            <name>ADD</name>
            <bitOffset>0</bitOffset>
            <bitWidth>4</bitWidth>
          </field>
          <field>
            <name>LBDL</name>
            <bitOffset>5</bitOffset>
            <bitWidth>1</bitWidth>
          </field>
          <field>
            <name>LBDIE</name>
            <bitOffset>6</bitOffset>
            <bitWidth>1</bitWidth>
          </field>
          <field>
            <name>LBCL</name>
            <bitOffset>8</bitOffset>
            <bitWidth>1</bitWidth>
          </field>
          <field>
            <name>CPHA</name>
            <bitOffset>9</bitOffset>
            <bitWidth>1</bitWidth>
          </field>
          <field>
            <name>CPOL</name>
            <bitOffset>10</bitOffset>
            <bitWidth>1</bitWidth>
          </field>
          <field>
            <name>CLKEN</name>
            <bitOffset>11</bitOffset>
            <bitWidth>1</bitWidth>
          </field>
          <field>
            <name>STOP</name>
            <bitOffset>12</bitOffset>
            <bitWidth>2</bitWidth>
          </field>
          <field>
            <name>LINEN</name>
            <bitOffset>14</bitOffset>
            <bitWidth>1</bitWidth>
          </field>
        </fields>
      </register>
      <register>
        <name>CR3</name>
        <addressOffset>0x14</addressOffset>
        <size>0x20</size>
        <fields>
          <field>
            <name>EIE</name>
            <bitOffset>0</bitOffset>
            <bitWidth>1</bitWidth>
          </field>
          <field>
            <name>IREN</name>
            <bitOffset>1</bitOffset>
            <bitWidth>1</bitWidth>
          </field>
          <field>
            <name>IRLP</name>
            <bitOffset>2</bitOffset>
            <bitWidth>1</bitWidth>
          </field>
          <field>
            <name>HDSEL</name>
            <bitOffset>3</bitOffset>
            <bitWidth>1</bitWidth>
          </field>
          <field>
            <name>NACK</name>
            <bitOffset>4</bitOffset>
            <bitWidth>1</bitWidth>
          </field>
          <field>
            <name>SCEN</name>
            <bitOffset>5</bitOffset>
            <bitWidth>1</bitWidth>
          </field>
          <field>
            <name>DMAR</name>
            <bitOffset>6</bitOffset>
            <bitWidth>1</bitWidth>
          </field>
          <field>
            <name>DMAT</name>
            <bitOffset>7</bitOffset>
            <bitWidth>1</bitWidth>
          </field>
          <field>
            <name>RTSE</name>
            <bitOffset>8</bitOffset>
            <bitWidth>1</bitWidth>
          </field>
          <field>
            <name>CTSE</name>
            <bitOffset>9</bitOffset>
            <bitWidth>1</bitWidth>
          </field>
          <field>
            <name>CTSIE</name>
            <bitOffset>10</bitOffset>
            <bitWidth>1</bitWidth>
          </field>
          <field>
            <name>ONEBIT</name>
            <bitOffset>11</bitOffset>
            <bitWidth>1</bitWidth>
          </field>
        </fields>
      </register>
      <register>
        <name>GTPR</name>
        <addressOffset>0x18</addressOffset>
        <size>0x20</size>
        <fields>
          <field>
            <name>PSC</name>
            <bitOffset>0</bitOffset>
            <bitWidth>8</bitWidth>
          </field>
          <field>
            <name>GT</name>
            <bitOffset>8</bitOffset>
            <bitWidth>8</bitWidth>
          </field>
        </fields>
      </register>
    </peripheral>
    <peripheral>
      <name>USART6</name>
      <baseAddress>0x40011400</baseAddress>
      <register>
        <name>SR</name>
        <addressOffset>0x0</addressOffset>
        <size>0x20</size>
        <fields>
          <field>
            <name>PE</name>
            <bitOffset>0</bitOffset>
            <bitWidth>1</bitWidth>
          </field>
          <field>
            <name>FE</name>
            <bitOffset>1</bitOffset>
            <bitWidth>1</bitWidth>
          </field>
          <field>
            <name>NE</name>
            <bitOffset>2</bitOffset>
            <bitWidth>1</bitWidth>
          </field>
          <field>
            <name>ORE</name>
            <bitOffset>3</bitOffset>
            <bitWidth>1</bitWidth>
          </field>
          <field>
            <name>IDLE</name>
            <bitOffset>4</bitOffset>
            <bitWidth>1</bitWidth>
          </field>
          <field>
            <name>RXNE</name>
            <bitOffset>5</bitOffset>
            <bitWidth>1</bitWidth>
          </field>
          <field>
            <name>TC</name>
            <bitOffset>6</bitOffset>
            <bitWidth>1</bitWidth>
          </field>
          <field>
            <name>TXE</name>
            <bitOffset>7</bitOffset>
            <bitWidth>1</bitWidth>
          </field>
          <field>
            <name>LBD</name>
            <bitOffset>8</bitOffset>
            <bitWidth>1</bitWidth>
          </field>
          <field>
            <name>CTS</name>
            <bitOffset>9</bitOffset>
            <bitWidth>1</bitWidth>
          </field>
        </fields>
      </register>
      <register>
        <name>DR</name>
        <addressOffset>0x4</addressOffset>
        <size>0x20</size>
        <fields>
          <field>
            <name>DR</name>
            <bitOffset>0</bitOffset>
            <bitWidth>9</bitWidth>
          </field>
        </fields>
      </register>
      <register>
        <name>BRR</name>
        <addressOffset>0x8</addressOffset>
        <size>0x20</size>
        <fields>
          <field>
            <name>DIV_Fraction</name>
            <bitOffset>0</bitOffset>
            <bitWidth>4</bitWidth>
          </field>
          <field>
            <name>DIV_Mantissa</name>
            <bitOffset>4</bitOffset>
            <bitWidth>12</bitWidth>
          </field>
        </fields>
      </register>
      <register>
        <name>CR1</name>
        <addressOffset>0xc</addressOffset>
        <size>0x20</size>
        <fields>
          <field>
            <name>SBK</name>
            <bitOffset>0</bitOffset>
            <bitWidth>1</bitWidth>
          </field>
          <field>
            <name>RWU</name>
            <bitOffset>1</bitOffset>
            <bitWidth>1</bitWidth>
          </field>
          <field>
            <name>RE</name>
            <bitOffset>2</bitOffset>
            <bitWidth>1</bitWidth>
          </field>
          <field>
            <name>TE</name>
            <bitOffset>3</bitOffset>
            <bitWidth>1</bitWidth>
          </field>
          <field>
            <name>IDLEIE</name>
            <bitOffset>4</bitOffset>
            <bitWidth>1</bitWidth>
          </field>
          <field>
            <name>RXNEIE</name>
            <bitOffset>5</bitOffset>
            <bitWidth>1</bitWidth>
          </field>
          <field>
            <name>TCIE</name>
            <bitOffset>6</bitOffset>
            <bitWidth>1</bitWidth>
          </field>
          <field>
            <name>TXEIE</name>
            <bitOffset>7</bitOffset>
            <bitWidth>1</bitWidth>
          </field>
          <field>
            <name>PEIE</name>
            <bitOffset>8</bitOffset>
            <bitWidth>1</bitWidth>
          </field>
          <field>
            <name>PS</name>
            <bitOffset>9</bitOffset>
            <bitWidth>1</bitWidth>
          </field>
          <field>
            <name>PCE</name>
            <bitOffset>10</bitOffset>
            <bitWidth>1</bitWidth>
          </field>
          <field>
            <name>WAKE</name>
            <bitOffset>11</bitOffset>
            <bitWidth>1</bitWidth>
          </field>
          <field>
            <name>M</name>
            <bitOffset>12</bitOffset>
            <bitWidth>1</bitWidth>
          </field>
          <field>
            <name>UE</name>
            <bitOffset>13</bitOffset>
            <bitWidth>1</bitWidth>
          </field>
          <field>
            <name>OVER8</name>
            <bitOffset>15</bitOffset>
            <bitWidth>1</bitWidth>
          </field>
        </fields>
      </register>
      <register>
        <name>CR2</name>
        <addressOffset>0x10</addressOffset>
        <size>0x20</size>
        <fields>
          <field>
            <name>ADD</name>
            <bitOffset>0</bitOffset>
            <bitWidth>4</bitWidth>
          </field>
          <field>
            <name>LBDL</name>
            <bitOffset>5</bitOffset>
            <bitWidth>1</bitWidth>
          </field>
          <field>
            <name>LBDIE</name>
            <bitOffset>6</bitOffset>
            <bitWidth>1</bitWidth>
          </field>
          <field>
            <name>LBCL</name>
            <bitOffset>8</bitOffset>
            <bitWidth>1</bitWidth>
          </field>
          <field>
            <name>CPHA</name>
            <bitOffset>9</bitOffset>
            <bitWidth>1</bitWidth>
          </field>
          <field>
            <name>CPOL</name>
            <bitOffset>10</bitOffset>
            <bitWidth>1</bitWidth>
          </field>
          <field>
            <name>CLKEN</name>
            <bitOffset>11</bitOffset>
            <bitWidth>1</bitWidth>
          </field>
          <field>
            <name>STOP</name>
            <bitOffset>12</bitOffset>
            <bitWidth>2</bitWidth>
          </field>
          <field>
            <name>LINEN</name>
            <bitOffset>14</bitOffset>
            <bitWidth>1</bitWidth>
          </field>
        </fields>
      </register>
      <register>
        <name>CR3</name>
        <addressOffset>0x14</addressOffset>
        <size>0x20</size>
        <fields>
          <field>
            <name>EIE</name>
            <bitOffset>0</bitOffset>
            <bitWidth>1</bitWidth>
          </field>
          <field>
            <name>IREN</name>
            <bitOffset>1</bitOffset>
            <bitWidth>1</bitWidth>
          </field>
          <field>
            <name>IRLP</name>
            <bitOffset>2</bitOffset>
            <bitWidth>1</bitWidth>
          </field>
          <field>
            <name>HDSEL</name>
            <bitOffset>3</bitOffset>
            <bitWidth>1</bitWidth>
          </field>
          <field>
            <name>NACK</name>
            <bitOffset>4</bitOffset>
            <bitWidth>1</bitWidth>
          </field>
          <field>
            <name>SCEN</name>
            <bitOffset>5</bitOffset>
            <bitWidth>1</bitWidth>
          </field>
          <field>
            <name>DMAR</name>
            <bitOffset>6</bitOffset>
            <bitWidth>1</bitWidth>
          </field>
          <field>
            <name>DMAT</name>
            <bitOffset>7</bitOffset>
            <bitWidth>1</bitWidth>
          </field>
          <field>
            <name>RTSE</name>
            <bitOffset>8</bitOffset>
            <bitWidth>1</bitWidth>
          </field>
          <field>
            <name>CTSE</name>
            <bitOffset>9</bitOffset>
            <bitWidth>1</bitWidth>
          </field>
          <field>
            <name>CTSIE</name>
            <bitOffset>10</bitOffset>
            <bitWidth>1</bitWidth>
          </field>
          <field>
            <name>ONEBIT</name>
            <bitOffset>11</bitOffset>
            <bitWidth>1</bitWidth>
          </field>
        </fields>
      </register>
      <register>
        <name>GTPR</name>
        <addressOffset>0x18</addressOffset>
        <size>0x20</size>
        <fields>
          <field>
            <name>PSC</name>
            <bitOffset>0</bitOffset>
            <bitWidth>8</bitWidth>
          </field>
          <field>
            <name>GT</name>
            <bitOffset>8</bitOffset>
            <bitWidth>8</bitWidth>
          </field>
        </fields>
      </register>
    </peripheral>
    <peripheral>
      <name>ADC1</name>
      <baseAddress>0x40012000</baseAddress>
      <register>
        <name>SR</name>
        <addressOffset>0x0</addressOffset>
        <size>0x20</size>
        <fields>
          <field>
            <name>AWD</name>
            <bitOffset>0</bitOffset>
            <bitWidth>1</bitWidth>
          </field>
          <field>
            <name>EOC</name>
            <bitOffset>1</bitOffset>
            <bitWidth>1</bitWidth>
          </field>
          <field>
            <name>JEOC</name>
            <bitOffset>2</bitOffset>
            <bitWidth>1</bitWidth>
          </field>
          <field>
            <name>JSTRT</name>
            <bitOffset>3</bitOffset>
            <bitWidth>1</bitWidth>
          </field>
          <field>
            <name>STRT</name>
            <bitOffset>4</bitOffset>
            <bitWidth>1</bitWidth>
          </field>
          <field>
            <name>OVR</name>
            <bitOffset>5</bitOffset>
            <bitWidth>1</bitWidth>
          </field>
        </fields>
      </register>
      <register>
        <name>CR1</name>
        <addressOffset>0x4</addressOffset>
        <size>0x20</size>
        <fields>
          <field>
            <name>AWDCH</name>
            <bitOffset>0</bitOffset>
            <bitWidth>5</bitWidth>
          </field>
          <field>
            <name>EOCIE</name>
            <bitOffset>5</bitOffset>
            <bitWidth>1</bitWidth>
          </field>
          <field>
            <name>AWDIE</name>
            <bitOffset>6</bitOffset>
            <bitWidth>1</bitWidth>
          </field>
          <field>
            <name>JEOCIE</name>
            <bitOffset>7</bitOffset>
            <bitWidth>1</bitWidth>
          </field>
          <field>
            <name>SCAN</name>
            <bitOffset>8</bitOffset>
            <bitWidth>1</bitWidth>
          </field>
          <field>
            <name>AWDSGL</name>
            <bitOffset>9</bitOffset>
            <bitWidth>1</bitWidth>
          </field>
          <field>
            <name>JAUTO</name>
            <bitOffset>10</bitOffset>
            <bitWidth>1</bitWidth>
          </field>
          <field>
            <name>DISCEN</name>
            <bitOffset>11</bitOffset>
            <bitWidth>1</bitWidth>
          </field>
          <field>
            <name>JDISCEN</name>
            <bitOffset>12</bitOffset>
            <bitWidth>1</bitWidth>
          </field>
          <field>
            <name>DISCNUM</name>
            <bitOffset>13</bitOffset>
            <bitWidth>3</bitWidth>
          </field>
          <field>
            <name>JAWDEN</name>
            <bitOffset>22</bitOffset>
            <bitWidth>1</bitWidth>
          </field>
          <field>
            <name>AWDEN</name>
            <bitOffset>23</bitOffset>
            <bitWidth>1</bitWidth>
          </field>
          <field>
            <name>RES</name>
            <bitOffset>24</bitOffset>
            <bitWidth>2</bitWidth>
          </field>
          <field>
            <name>OVRIE</name>
            <bitOffset>26</bitOffset>
            <bitWidth>1</bitWidth>
          </field>
        </fields>
      </register>
      <register>
        <name>CR2</name>
        <addressOffset>0x8</addressOffset>
        <size>0x20</size>
        <fields>
          <field>
            <name>ADON</name>
            <bitOffset>0</bitOffset>
            <bitWidth>1</bitWidth>
          </field>
          <field>
            <name>CONT</name>
            <bitOffset>1</bitOffset>
            <bitWidth>1</bitWidth>
          </field>
          <field>
            <name>DMA</name>
            <bitOffset>8</bitOffset>
            <bitWidth>1</bitWidth>
          </field>
          <field>
            <name>DDS</name>
            <bitOffset>9</bitOffset>
            <bitWidth>1</bitWidth>
          </field>
          <field>
            <name>EOCS</name>
            <bitOffset>10</bitOffset>
            <bitWidth>1</bitWidth>
          </field>
          <field>
            <name>ALIGN</name>
            <bitOffset>11</bitOffset>
            <bitWidth>1</bitWidth>
          </field>
          <field>
            <name>JEXTSEL</name>
            <bitOffset>16</bitOffset>
            <bitWidth>4</bitWidth>
          </field>
          <field>
            <name>JEXTEN</name>
            <bitOffset>20</bitOffset>
            <bitWidth>2</bitWidth>
          </field>
          <field>
            <name>JSWSTART</name>
            <bitOffset>22</bitOffset>
            <bitWidth>1</bitWidth>
          </field>
          <field>
            <name>EXTSEL</name>
            <bitOffset>24</bitOffset>
            <bitWidth>4</bitWidth>
          </field>
          <field>
            <name>EXTEN</name>
            <bitOffset>28</bitOffset>
            <bitWidth>2</bitWidth>
          </field>
          <field>
            <name>SWSTART</name>
            <bitOffset>30</bitOffset>
            <bitWidth>1</bitWidth>
          </field>
        </fields>
      </register>
      <register>
        <name>SMPR1</name>
        <addressOffset>0xc</addressOffset>
        <size>0x20</size>
        <fields>
          <field>
            <name>SMP10</name>
            <bitOffset>0</bitOffset>
            <bitWidth>3</bitWidth>
          </field>
          <field>
            <name>SMP11</name>
            <bitOffset>3</bitOffset>
            <bitWidth>3</bitWidth>
          </field>
          <field>
            <name>SMP12</name>
            <bitOffset>6</bitOffset>
            <bitWidth>3</bitWidth>
          </field>
          <field>
            <name>SMP13</name>
            <bitOffset>9</bitOffset>
            <bitWidth>3</bitWidth>
          </field>
          <field>
            <name>SMP14</name>
            <bitOffset>12</bitOffset>
            <bitWidth>3</bitWidth>
          </field>
          <field>
            <name>SMP15</name>
            <bitOffset>15</bitOffset>
            <bitWidth>3</bitWidth>
          </field>
          <field>
            <name>SMP16</name>
            <bitOffset>18</bitOffset>
            <bitWidth>3</bitWidth>
          </field>
          <field>
            <name>SMP17</name>
            <bitOffset>21</bitOffset>
            <bitWidth>3</bitWidth>
          </field>
          <field>
            <name>SMP18</name>
            <bitOffset>24</bitOffset>
            <bitWidth>3</bitWidth>
          </field>
        </fields>
      </register>
      <register>
        <name>SMPR2</name>
        <addressOffset>0x10</addressOffset>
        <size>0x20</size>
        <fields>
          <field>
            <name>SMP0</name>
            <bitOffset>0</bitOffset>
            <bitWidth>3</bitWidth>
          </field>
          <field>
            <name>SMP1</name>
            <bitOffset>3</bitOffset>
            <bitWidth>3</bitWidth>
          </field>
          <field>
            <name>SMP2</name>
            <bitOffset>6</bitOffset>
            <bitWidth>3</bitWidth>
          </field>
          <field>
            <name>SMP3</name>
            <bitOffset>9</bitOffset>
            <bitWidth>3</bitWidth>
          </field>
          <field>
            <name>SMP4</name>
            <bitOffset>12</bitOffset>
            <bitWidth>3</bitWidth>
          </field>
          <field>
            <name>SMP5</name>
            <bitOffset>15</bitOffset>
            <bitWidth>3</bitWidth>
          </field>
          <field>
            <name>SMP6</name>
            <bitOffset>18</bitOffset>
            <bitWidth>3</bitWidth>
          </field>
          <field>
            <name>SMP7</name>
            <bitOffset>21</bitOffset>
            <bitWidth>3</bitWidth>
          </field>
          <field>
            <name>SMP8</name>
            <bitOffset>24</bitOffset>
            <bitWidth>3</bitWidth>
          </field>
          <field>
            <name>SMP9</name>
            <bitOffset>27</bitOffset>
            <bitWidth>3</bitWidth>
          </field>
        </fields>
      </register>
      <register>
        <name>JOFR1</name>
        <addressOffset>0x14</addressOffset>
        <size>0x20</size>
        <fields>
          <field>
            <name>JOFFSET1</name>
            <bitOffset>0</bitOffset>
            <bitWidth>12</bitWidth>
          </field>
        </fields>
      </register>
      <register>
        <name>JOFR2</name>
        <addressOffset>0x18</addressOffset>
        <size>0x20</size>
        <fields>
          <field>
            <name>JOFFSET2</name>
            <bitOffset>0</bitOffset>
            <bitWidth>12</bitWidth>
          </field>
        </fields>
      </register>
      <register>
        <name>JOFR3</name>
        <addressOffset>0x1c</addressOffset>
        <size>0x20</size>
        <fields>
          <field>
            <name>JOFFSET3</name>
            <bitOffset>0</bitOffset>
            <bitWidth>12</bitWidth>
          </field>
        </fields>
      </register>
      <register>
        <name>JOFR4</name>
        <addressOffset>0x20</addressOffset>
        <size>0x20</size>
        <fields>
          <field>
            <name>JOFFSET4</name>
            <bitOffset>0</bitOffset>
            <bitWidth>12</bitWidth>
          </field>
        </fields>
      </register>
      <register>
        <name>HTR</name>
        <addressOffset>0x24</addressOffset>
        <size>0x20</size>
        <fields>
          <field>
            <name>HT</name>
            <bitOffset>0</bitOffset>
            <bitWidth>12</bitWidth>
          </field>
        </fields>
      </register>
      <register>
        <name>LTR</name>
        <addressOffset>0x28</addressOffset>
        <size>0x20</size>
        <fields>
          <field>
            <name>LT</name>
            <bitOffset>0</bitOffset>
            <bitWidth>12</bitWidth>
          </field>
        </fields>
      </register>
      <register>
        <name>SQR1</name>
        <addressOffset>0x2c</addressOffset>
        <size>0x20</size>
        <fields>
          <field>
            <name>SQ13</name>
            <bitOffset>0</bitOffset>
            <bitWidth>5</bitWidth>
          </field>
          <field>
            <name>SQ14</name>
            <bitOffset>5</bitOffset>
            <bitWidth>5</bitWidth>
          </field>
          <field>
            <name>SQ15</name>
            <bitOffset>10</bitOffset>
            <bitWidth>5</bitWidth>
          </field>
          <field>
            <name>SQ16</name>
            <bitOffset>15</bitOffset>
            <bitWidth>5</bitWidth>
          </field>
          <field>
            <name>L</name>
            <bitOffset>20</bitOffset>
            <bitWidth>4</bitWidth>
          </field>
        </fields>
      </register>
      <register>
        <name>SQR2</name>
        <addressOffset>0x30</addressOffset>
        <size>0x20</size>
        <fields>
          <field>
            <name>SQ7</name>
            <bitOffset>0</bitOffset>
            <bitWidth>5</bitWidth>
          </field>
          <field>
            <name>SQ8</name>
            <bitOffset>5</bitOffset>
            <bitWidth>5</bitWidth>
          </field>
          <field>
            <name>SQ9</name>
            <bitOffset>10</bitOffset>
            <bitWidth>5</bitWidth>
          </field>
          <field>
            <name>SQ10</name>
            <bitOffset>15</bitOffset>
            <bitWidth>5</bitWidth>
          </field>
          <field>
            <name>SQ11</name>
            <bitOffset>20</bitOffset>
            <bitWidth>5</bitWidth>
          </field>
          <field>
            <name>SQ12</name>
            <bitOffset>25</bitOffset>
            <bitWidth>5</bitWidth>
          </field>
        </fields>
      </register>
      <register>
        <name>SQR3</name>
        <addressOffset>0x34</addressOffset>
        <size>0x20</size>
        <fields>
          <field>
            <name>SQ1</name>
            <bitOffset>0</bitOffset>
            <bitWidth>5</bitWidth>
          </field>
          <field>
            <name>SQ2</name>
            <bitOffset>5</bitOffset>
            <bitWidth>5</bitWidth>
          </field>
          <field>
            <name>SQ3</name>
            <bitOffset>10</bitOffset>
            <bitWidth>5</bitWidth>
          </field>
          <field>
            <name>SQ4</name>
            <bitOffset>15</bitOffset>
            <bitWidth>5</bitWidth>
          </field>
          <field>
            <name>SQ5</name>
            <bitOffset>20</bitOffset>
            <bitWidth>5</bitWidth>
          </field>
          <field>
            <name>SQ6</name>
            <bitOffset>25</bitOffset>
            <bitWidth>5</bitWidth>
          </field>
        </fields>
      </register>
      <register>
        <name>JSQR</name>
        <addressOffset>0x38</addressOffset>
        <size>0x20</size>
        <fields>
          <field>
            <name>JSQ1</name>
            <bitOffset>0</bitOffset>
            <bitWidth>5</bitWidth>
          </field>
          <field>
            <name>JSQ2</name>
            <bitOffset>5</bitOffset>
            <bitWidth>5</bitWidth>
          </field>
          <field>
            <name>JSQ3</name>
            <bitOffset>10</bitOffset>
            <bitWidth>5</bitWidth>
          </field>
          <field>
            <name>JSQ4</name>
            <bitOffset>15</bitOffset>
            <bitWidth>5</bitWidth>
          </field>
          <field>
            <name>JL</name>
            <bitOffset>20</bitOffset>
            <bitWidth>2</bitWidth>
          </field>
        </fields>
      </register>
      <register>
        <name>JDR1</name>
        <addressOffset>0x3c</addressOffset>
        <size>0x20</size>
        <fields>
          <field>
            <name>JDATA</name>
            <bitOffset>0</bitOffset>
            <bitWidth>16</bitWidth>
          </field>
        </fields>
      </register>
      <register>
        <name>JDR2</name>
        <addressOffset>0x40</addressOffset>
        <size>0x20</size>
        <fields>
          <field>
            <name>JDATA</name>
            <bitOffset>0</bitOffset>
            <bitWidth>16</bitWidth>
          </field>
        </fields>
      </register>
      <register>
        <name>JDR3</name>
        <addressOffset>0x44</addressOffset>
        <size>0x20</size>
        <fields>
          <field>
            <name>JDATA</name>
            <bitOffset>0</bitOffset>
            <bitWidth>16</bitWidth>
          </field>
        </fields>
      </register>
      <register>
        <name>JDR4</name>
        <addressOffset>0x48</addressOffset>
        <size>0x20</size>
        <fields>
          <field>
            <name>JDATA</name>
            <bitOffset>0</bitOffset>
            <bitWidth>16</bitWidth>
          </field>
        </fields>
      </register>
      <register>
        <name>DR</name>
        <addressOffset>0x4c</addressOffset>
        <size>0x20</size>
        <fields>
          <field>
            <name>DATA</name>
            <bitOffset>0</bitOffset>
            <bitWidth>16</bitWidth>
          </field>
          <field>
            <name>ADC2DATA</name>
            <bitOffset>16</bitOffset>
            <bitWidth>16</bitWidth>
          </field>
        </fields>
      </register>
    </peripheral>
    <peripheral>
      <name>ADC2</name>
      <baseAddress>0x40012100</baseAddress>
      <register>
        <name>SR</name>
        <addressOffset>0x0</addressOffset>
        <size>0x20</size>
        <fields>
          <field>
            <name>AWD</name>
            <bitOffset>0</bitOffset>
            <bitWidth>1</bitWidth>
          </field>
          <field>
            <name>EOC</name>
            <bitOffset>1</bitOffset>
            <bitWidth>1</bitWidth>
          </field>
          <field>
            <name>JEOC</name>
            <bitOffset>2</bitOffset>
            <bitWidth>1</bitWidth>
          </field>
          <field>
            <name>JSTRT</name>
            <bitOffset>3</bitOffset>
            <bitWidth>1</bitWidth>
          </field>
          <field>
            <name>STRT</name>
            <bitOffset>4</bitOffset>
            <bitWidth>1</bitWidth>
          </field>
          <field>
            <name>OVR</name>
            <bitOffset>5</bitOffset>
            <bitWidth>1</bitWidth>
          </field>
        </fields>
      </register>
      <register>
        <name>CR1</name>
        <addressOffset>0x4</addressOffset>
        <size>0x20</size>
        <fields>
          <field>
            <name>AWDCH</name>
            <bitOffset>0</bitOffset>
            <bitWidth>5</bitWidth>
          </field>
          <field>
            <name>EOCIE</name>
            <bitOffset>5</bitOffset>
            <bitWidth>1</bitWidth>
          </field>
          <field>
            <name>AWDIE</name>
            <bitOffset>6</bitOffset>
            <bitWidth>1</bitWidth>
          </field>
          <field>
            <name>JEOCIE</name>
            <bitOffset>7</bitOffset>
            <bitWidth>1</bitWidth>
          </field>
          <field>
            <name>SCAN</name>
            <bitOffset>8</bitOffset>
            <bitWidth>1</bitWidth>
          </field>
          <field>
            <name>AWDSGL</name>
            <bitOffset>9</bitOffset>
            <bitWidth>1</bitWidth>
          </field>
          <field>
            <name>JAUTO</name>
            <bitOffset>10</bitOffset>
            <bitWidth>1</bitWidth>
          </field>
          <field>
            <name>DISCEN</name>
            <bitOffset>11</bitOffset>
            <bitWidth>1</bitWidth>
          </field>
          <field>
            <name>JDISCEN</name>
            <bitOffset>12</bitOffset>
            <bitWidth>1</bitWidth>
          </field>
          <field>
            <name>DISCNUM</name>
            <bitOffset>13</bitOffset>
            <bitWidth>3</bitWidth>
          </field>
          <field>
            <name>JAWDEN</name>
            <bitOffset>22</bitOffset>
            <bitWidth>1</bitWidth>
          </field>
          <field>
            <name>AWDEN</name>
            <bitOffset>23</bitOffset>
            <bitWidth>1</bitWidth>
          </field>
          <field>
            <name>RES</name>
            <bitOffset>24</bitOffset>
            <bitWidth>2</bitWidth>
          </field>
          <field>
            <name>OVRIE</name>
            <bitOffset>26</bitOffset>
            <bitWidth>1</bitWidth>
          </field>
        </fields>
      </register>
      <register>
        <name>CR2</name>
        <addressOffset>0x8</addressOffset>
        <size>0x20</size>
        <fields>
          <field>
            <name>ADON</name>
            <bitOffset>0</bitOffset>
            <bitWidth>1</bitWidth>
          </field>
          <field>
            <name>CONT</name>
            <bitOffset>1</bitOffset>
            <bitWidth>1</bitWidth>
          </field>
          <field>
            <name>DMA</name>
            <bitOffset>8</bitOffset>
            <bitWidth>1</bitWidth>
          </field>
          <field>
            <name>DDS</name>
            <bitOffset>9</bitOffset>
            <bitWidth>1</bitWidth>
          </field>
          <field>
            <name>EOCS</name>
            <bitOffset>10</bitOffset>
            <bitWidth>1</bitWidth>
          </field>
          <field>
            <name>ALIGN</name>
            <bitOffset>11</bitOffset>
            <bitWidth>1</bitWidth>
          </field>
          <field>
            <name>JEXTSEL</name>
            <bitOffset>16</bitOffset>
            <bitWidth>4</bitWidth>
          </field>
          <field>
            <name>JEXTEN</name>
            <bitOffset>20</bitOffset>
            <bitWidth>2</bitWidth>
          </field>
          <field>
            <name>JSWSTART</name>
            <bitOffset>22</bitOffset>
            <bitWidth>1</bitWidth>
          </field>
          <field>
            <name>EXTSEL</name>
            <bitOffset>24</bitOffset>
            <bitWidth>4</bitWidth>
          </field>
          <field>
            <name>EXTEN</name>
            <bitOffset>28</bitOffset>
            <bitWidth>2</bitWidth>
          </field>
          <field>
            <name>SWSTART</name>
            <bitOffset>30</bitOffset>
            <bitWidth>1</bitWidth>
          </field>
        </fields>
      </register>
      <register>
        <name>SMPR1</name>
        <addressOffset>0xc</addressOffset>
        <size>0x20</size>
        <fields>
          <field>
            <name>SMP10</name>
            <bitOffset>0</bitOffset>
            <bitWidth>3</bitWidth>
          </field>
          <field>
            <name>SMP11</name>
            <bitOffset>3</bitOffset>
            <bitWidth>3</bitWidth>
          </field>
          <field>
            <name>SMP12</name>
            <bitOffset>6</bitOffset>
            <bitWidth>3</bitWidth>
          </field>
          <field>
            <name>SMP13</name>
            <bitOffset>9</bitOffset>
            <bitWidth>3</bitWidth>
          </field>
          <field>
            <name>SMP14</name>
            <bitOffset>12</bitOffset>
            <bitWidth>3</bitWidth>
          </field>
          <field>
            <name>SMP15</name>
            <bitOffset>15</bitOffset>
            <bitWidth>3</bitWidth>
          </field>
          <field>
            <name>SMP16</name>
            <bitOffset>18</bitOffset>
            <bitWidth>3</bitWidth>
          </field>
          <field>
            <name>SMP17</name>
            <bitOffset>21</bitOffset>
            <bitWidth>3</bitWidth>
          </field>
          <field>
            <name>SMP18</name>
            <bitOffset>24</bitOffset>
            <bitWidth>3</bitWidth>
          </field>
        </fields>
      </register>
      <register>
        <name>SMPR2</name>
        <addressOffset>0x10</addressOffset>
        <size>0x20</size>
        <fields>
          <field>
            <name>SMP0</name>
            <bitOffset>0</bitOffset>
            <bitWidth>3</bitWidth>
          </field>
          <field>
            <name>SMP1</name>
            <bitOffset>3</bitOffset>
            <bitWidth>3</bitWidth>
          </field>
          <field>
            <name>SMP2</name>
            <bitOffset>6</bitOffset>
            <bitWidth>3</bitWidth>
          </field>
          <field>
            <name>SMP3</name>
            <bitOffset>9</bitOffset>
            <bitWidth>3</bitWidth>
          </field>
          <field>
            <name>SMP4</name>
            <bitOffset>12</bitOffset>
            <bitWidth>3</bitWidth>
          </field>
          <field>
            <name>SMP5</name>
            <bitOffset>15</bitOffset>
            <bitWidth>3</bitWidth>
          </field>
          <field>
            <name>SMP6</name>
            <bitOffset>18</bitOffset>
            <bitWidth>3</bitWidth>
          </field>
          <field>
            <name>SMP7</name>
            <bitOffset>21</bitOffset>
            <bitWidth>3</bitWidth>
          </field>
          <field>
            <name>SMP8</name>
            <bitOffset>24</bitOffset>
            <bitWidth>3</bitWidth>
          </field>
          <field>
            <name>SMP9</name>
            <bitOffset>27</bitOffset>
            <bitWidth>3</bitWidth>
          </field>
        </fields>
      </register>
      <register>
        <name>JOFR1</name>
        <addressOffset>0x14</addressOffset>
        <size>0x20</size>
        <fields>
          <field>
            <name>JOFFSET1</name>
            <bitOffset>0</bitOffset>
            <bitWidth>12</bitWidth>
          </field>
        </fields>
      </register>
      <register>
        <name>JOFR2</name>
        <addressOffset>0x18</addressOffset>
        <size>0x20</size>
        <fields>
          <field>
            <name>JOFFSET2</name>
            <bitOffset>0</bitOffset>
            <bitWidth>12</bitWidth>
          </field>
        </fields>
      </register>
      <register>
        <name>JOFR3</name>
        <addressOffset>0x1c</addressOffset>
        <size>0x20</size>
        <fields>
          <field>
            <name>JOFFSET3</name>
            <bitOffset>0</bitOffset>
            <bitWidth>12</bitWidth>
          </field>
        </fields>
      </register>
      <register>
        <name>JOFR4</name>
        <addressOffset>0x20</addressOffset>
        <size>0x20</size>
        <fields>
          <field>
            <name>JOFFSET4</name>
            <bitOffset>0</bitOffset>
            <bitWidth>12</bitWidth>
          </field>
        </fields>
      </register>
      <register>
        <name>HTR</name>
        <addressOffset>0x24</addressOffset>
        <size>0x20</size>
        <fields>
          <field>
            <name>HT</name>
            <bitOffset>0</bitOffset>
            <bitWidth>12</bitWidth>
          </field>
        </fields>
      </register>
      <register>
        <name>LTR</name>
        <addressOffset>0x28</addressOffset>
        <size>0x20</size>
        <fields>
          <field>
            <name>LT</name>
            <bitOffset>0</bitOffset>
            <bitWidth>12</bitWidth>
          </field>
        </fields>
      </register>
      <register>
        <name>SQR1</name>
        <addressOffset>0x2c</addressOffset>
        <size>0x20</size>
        <fields>
          <field>
            <name>SQ13</name>
            <bitOffset>0</bitOffset>
            <bitWidth>5</bitWidth>
          </field>
          <field>
            <name>SQ14</name>
            <bitOffset>5</bitOffset>
            <bitWidth>5</bitWidth>
          </field>
          <field>
            <name>SQ15</name>
            <bitOffset>10</bitOffset>
            <bitWidth>5</bitWidth>
          </field>
          <field>
            <name>SQ16</name>
            <bitOffset>15</bitOffset>
            <bitWidth>5</bitWidth>
          </field>
          <field>
            <name>L</name>
            <bitOffset>20</bitOffset>
            <bitWidth>4</bitWidth>
          </field>
        </fields>
      </register>
      <register>
        <name>SQR2</name>
        <addressOffset>0x30</addressOffset>
        <size>0x20</size>
        <fields>
          <field>
            <name>SQ7</name>
            <bitOffset>0</bitOffset>
            <bitWidth>5</bitWidth>
          </field>
          <field>
            <name>SQ8</name>
            <bitOffset>5</bitOffset>
            <bitWidth>5</bitWidth>
          </field>
          <field>
            <name>SQ9</name>
            <bitOffset>10</bitOffset>
            <bitWidth>5</bitWidth>
          </field>
          <field>
            <name>SQ10</name>
            <bitOffset>15</bitOffset>
            <bitWidth>5</bitWidth>
          </field>
          <field>
            <name>SQ11</name>
            <bitOffset>20</bitOffset>
            <bitWidth>5</bitWidth>
          </field>
          <field>
            <name>SQ12</name>
            <bitOffset>25</bitOffset>
            <bitWidth>5</bitWidth>
          </field>
        </fields>
      </register>
      <register>
        <name>SQR3</name>
        <addressOffset>0x34</addressOffset>
        <size>0x20</size>
        <fields>
          <field>
            <name>SQ1</name>
            <bitOffset>0</bitOffset>
            <bitWidth>5</bitWidth>
          </field>
          <field>
            <name>SQ2</name>
            <bitOffset>5</bitOffset>
            <bitWidth>5</bitWidth>
          </field>
          <field>
            <name>SQ3</name>
            <bitOffset>10</bitOffset>
            <bitWidth>5</bitWidth>
          </field>
          <field>
            <name>SQ4</name>
            <bitOffset>15</bitOffset>
            <bitWidth>5</bitWidth>
          </field>
          <field>
            <name>SQ5</name>
            <bitOffset>20</bitOffset>
            <bitWidth>5</bitWidth>
          </field>
          <field>
            <name>SQ6</name>
            <bitOffset>25</bitOffset>
            <bitWidth>5</bitWidth>
          </field>
        </fields>
      </register>
      <register>
        <name>JSQR</name>
        <addressOffset>0x38</addressOffset>
        <size>0x20</size>
        <fields>
          <field>
            <name>JSQ1</name>
            <bitOffset>0</bitOffset>
            <bitWidth>5</bitWidth>
          </field>
          <field>
            <name>JSQ2</name>
            <bitOffset>5</bitOffset>
            <bitWidth>5</bitWidth>
          </field>
          <field>
            <name>JSQ3</name>
            <bitOffset>10</bitOffset>
            <bitWidth>5</bitWidth>
          </field>
          <field>
            <name>JSQ4</name>
            <bitOffset>15</bitOffset>
            <bitWidth>5</bitWidth>
          </field>
          <field>
            <name>JL</name>
            <bitOffset>20</bitOffset>
            <bitWidth>2</bitWidth>
          </field>
        </fields>
      </register>
      <register>
        <name>JDR1</name>
        <addressOffset>0x3c</addressOffset>
        <size>0x20</size>
        <fields>
          <field>
            <name>JDATA</name>
            <bitOffset>0</bitOffset>
            <bitWidth>16</bitWidth>
          </field>
        </fields>
      </register>
      <register>
        <name>JDR2</name>
        <addressOffset>0x40</addressOffset>
        <size>0x20</size>
        <fields>
          <field>
            <name>JDATA</name>
            <bitOffset>0</bitOffset>
            <bitWidth>16</bitWidth>
          </field>
        </fields>
      </register>
      <register>
        <name>JDR3</name>
        <addressOffset>0x44</addressOffset>
        <size>0x20</size>
        <fields>
          <field>
            <name>JDATA</name>
            <bitOffset>0</bitOffset>
            <bitWidth>16</bitWidth>
          </field>
        </fields>
      </register>
      <register>
        <name>JDR4</name>
        <addressOffset>0x48</addressOffset>
        <size>0x20</size>
        <fields>
          <field>
            <name>JDATA</name>
            <bitOffset>0</bitOffset>
            <bitWidth>16</bitWidth>
          </field>
        </fields>
      </register>
      <register>
        <name>DR</name>
        <addressOffset>0x4c</addressOffset>
        <size>0x20</size>
        <fields>
          <field>
            <name>DATA</name>
            <bitOffset>0</bitOffset>
            <bitWidth>16</bitWidth>
          </field>
          <field>
            <name>ADC2DATA</name>
            <bitOffset>16</bitOffset>
            <bitWidth>16</bitWidth>
          </field>
        </fields>
      </register>
    </peripheral>
    <peripheral>
      <name>ADC3</name>
      <baseAddress>0x40012200</baseAddress>
      <register>
        <name>SR</name>
        <addressOffset>0x0</addressOffset>
        <size>0x20</size>
        <fields>
          <field>
            <name>AWD</name>
            <bitOffset>0</bitOffset>
            <bitWidth>1</bitWidth>
          </field>
          <field>
            <name>EOC</name>
            <bitOffset>1</bitOffset>
            <bitWidth>1</bitWidth>
          </field>
          <field>
            <name>JEOC</name>
            <bitOffset>2</bitOffset>
            <bitWidth>1</bitWidth>
          </field>
          <field>
            <name>JSTRT</name>
            <bitOffset>3</bitOffset>
            <bitWidth>1</bitWidth>
          </field>
          <field>
            <name>STRT</name>
            <bitOffset>4</bitOffset>
            <bitWidth>1</bitWidth>
          </field>
          <field>
            <name>OVR</name>
            <bitOffset>5</bitOffset>
            <bitWidth>1</bitWidth>
          </field>
        </fields>
      </register>
      <register>
        <name>CR1</name>
        <addressOffset>0x4</addressOffset>
        <size>0x20</size>
        <fields>
          <field>
            <name>AWDCH</name>
            <bitOffset>0</bitOffset>
            <bitWidth>5</bitWidth>
          </field>
          <field>
            <name>EOCIE</name>
            <bitOffset>5</bitOffset>
            <bitWidth>1</bitWidth>
          </field>
          <field>
            <name>AWDIE</name>
            <bitOffset>6</bitOffset>
            <bitWidth>1</bitWidth>
          </field>
          <field>
            <name>JEOCIE</name>
            <bitOffset>7</bitOffset>
            <bitWidth>1</bitWidth>
          </field>
          <field>
            <name>SCAN</name>
            <bitOffset>8</bitOffset>
            <bitWidth>1</bitWidth>
          </field>
          <field>
            <name>AWDSGL</name>
            <bitOffset>9</bitOffset>
            <bitWidth>1</bitWidth>
          </field>
          <field>
            <name>JAUTO</name>
            <bitOffset>10</bitOffset>
            <bitWidth>1</bitWidth>
          </field>
          <field>
            <name>DISCEN</name>
            <bitOffset>11</bitOffset>
            <bitWidth>1</bitWidth>
          </field>
          <field>
            <name>JDISCEN</name>
            <bitOffset>12</bitOffset>
            <bitWidth>1</bitWidth>
          </field>
          <field>
            <name>DISCNUM</name>
            <bitOffset>13</bitOffset>
            <bitWidth>3</bitWidth>
          </field>
          <field>
            <name>JAWDEN</name>
            <bitOffset>22</bitOffset>
            <bitWidth>1</bitWidth>
          </field>
          <field>
            <name>AWDEN</name>
            <bitOffset>23</bitOffset>
            <bitWidth>1</bitWidth>
          </field>
          <field>
            <name>RES</name>
            <bitOffset>24</bitOffset>
            <bitWidth>2</bitWidth>
          </field>
          <field>
            <name>OVRIE</name>
            <bitOffset>26</bitOffset>
            <bitWidth>1</bitWidth>
          </field>
        </fields>
      </register>
      <register>
        <name>CR2</name>
        <addressOffset>0x8</addressOffset>
        <size>0x20</size>
        <fields>
          <field>
            <name>ADON</name>
            <bitOffset>0</bitOffset>
            <bitWidth>1</bitWidth>
          </field>
          <field>
            <name>CONT</name>
            <bitOffset>1</bitOffset>
            <bitWidth>1</bitWidth>
          </field>
          <field>
            <name>DMA</name>
            <bitOffset>8</bitOffset>
            <bitWidth>1</bitWidth>
          </field>
          <field>
            <name>DDS</name>
            <bitOffset>9</bitOffset>
            <bitWidth>1</bitWidth>
          </field>
          <field>
            <name>EOCS</name>
            <bitOffset>10</bitOffset>
            <bitWidth>1</bitWidth>
          </field>
          <field>
            <name>ALIGN</name>
            <bitOffset>11</bitOffset>
            <bitWidth>1</bitWidth>
          </field>
          <field>
            <name>JEXTSEL</name>
            <bitOffset>16</bitOffset>
            <bitWidth>4</bitWidth>
          </field>
          <field>
            <name>JEXTEN</name>
            <bitOffset>20</bitOffset>
            <bitWidth>2</bitWidth>
          </field>
          <field>
            <name>JSWSTART</name>
            <bitOffset>22</bitOffset>
            <bitWidth>1</bitWidth>
          </field>
          <field>
            <name>EXTSEL</name>
            <bitOffset>24</bitOffset>
            <bitWidth>4</bitWidth>
          </field>
          <field>
            <name>EXTEN</name>
            <bitOffset>28</bitOffset>
            <bitWidth>2</bitWidth>
          </field>
          <field>
            <name>SWSTART</name>
            <bitOffset>30</bitOffset>
            <bitWidth>1</bitWidth>
          </field>
        </fields>
      </register>
      <register>
        <name>SMPR1</name>
        <addressOffset>0xc</addressOffset>
        <size>0x20</size>
        <fields>
          <field>
            <name>SMP10</name>
            <bitOffset>0</bitOffset>
            <bitWidth>3</bitWidth>
          </field>
          <field>
            <name>SMP11</name>
            <bitOffset>3</bitOffset>
            <bitWidth>3</bitWidth>
          </field>
          <field>
            <name>SMP12</name>
            <bitOffset>6</bitOffset>
            <bitWidth>3</bitWidth>
          </field>
          <field>
            <name>SMP13</name>
            <bitOffset>9</bitOffset>
            <bitWidth>3</bitWidth>
          </field>
          <field>
            <name>SMP14</name>
            <bitOffset>12</bitOffset>
            <bitWidth>3</bitWidth>
          </field>
          <field>
            <name>SMP15</name>
            <bitOffset>15</bitOffset>
            <bitWidth>3</bitWidth>
          </field>
          <field>
            <name>SMP16</name>
            <bitOffset>18</bitOffset>
            <bitWidth>3</bitWidth>
          </field>
          <field>
            <name>SMP17</name>
            <bitOffset>21</bitOffset>
            <bitWidth>3</bitWidth>
          </field>
          <field>
            <name>SMP18</name>
            <bitOffset>24</bitOffset>
            <bitWidth>3</bitWidth>
          </field>
        </fields>
      </register>
      <register>
        <name>SMPR2</name>
        <addressOffset>0x10</addressOffset>
        <size>0x20</size>
        <fields>
          <field>
            <name>SMP0</name>
            <bitOffset>0</bitOffset>
            <bitWidth>3</bitWidth>
          </field>
          <field>
            <name>SMP1</name>
            <bitOffset>3</bitOffset>
            <bitWidth>3</bitWidth>
          </field>
          <field>
            <name>SMP2</name>
            <bitOffset>6</bitOffset>
            <bitWidth>3</bitWidth>
          </field>
          <field>
            <name>SMP3</name>
            <bitOffset>9</bitOffset>
            <bitWidth>3</bitWidth>
          </field>
          <field>
            <name>SMP4</name>
            <bitOffset>12</bitOffset>
            <bitWidth>3</bitWidth>
          </field>
          <field>
            <name>SMP5</name>
            <bitOffset>15</bitOffset>
            <bitWidth>3</bitWidth>
          </field>
          <field>
            <name>SMP6</name>
            <bitOffset>18</bitOffset>
            <bitWidth>3</bitWidth>
          </field>
          <field>
            <name>SMP7</name>
            <bitOffset>21</bitOffset>
            <bitWidth>3</bitWidth>
          </field>
          <field>
            <name>SMP8</name>
            <bitOffset>24</bitOffset>
            <bitWidth>3</bitWidth>
          </field>
          <field>
            <name>SMP9</name>
            <bitOffset>27</bitOffset>
            <bitWidth>3</bitWidth>
          </field>
        </fields>
      </register>
      <register>
        <name>JOFR1</name>
        <addressOffset>0x14</addressOffset>
        <size>0x20</size>
        <fields>
          <field>
            <name>JOFFSET1</name>
            <bitOffset>0</bitOffset>
            <bitWidth>12</bitWidth>
          </field>
        </fields>
      </register>
      <register>
        <name>JOFR2</name>
        <addressOffset>0x18</addressOffset>
        <size>0x20</size>
        <fields>
          <field>
            <name>JOFFSET2</name>
            <bitOffset>0</bitOffset>
            <bitWidth>12</bitWidth>
          </field>
        </fields>
      </register>
      <register>
        <name>JOFR3</name>
        <addressOffset>0x1c</addressOffset>
        <size>0x20</size>
        <fields>
          <field>
            <name>JOFFSET3</name>
            <bitOffset>0</bitOffset>
            <bitWidth>12</bitWidth>
          </field>
        </fields>
      </register>
      <register>
        <name>JOFR4</name>
        <addressOffset>0x20</addressOffset>
        <size>0x20</size>
        <fields>
          <field>
            <name>JOFFSET4</name>
            <bitOffset>0</bitOffset>
            <bitWidth>12</bitWidth>
          </field>
        </fields>
      </register>
      <register>
        <name>HTR</name>
        <addressOffset>0x24</addressOffset>
        <size>0x20</size>
        <fields>
          <field>
            <name>HT</name>
            <bitOffset>0</bitOffset>
            <bitWidth>12</bitWidth>
          </field>
        </fields>
      </register>
      <register>
        <name>LTR</name>
        <addressOffset>0x28</addressOffset>
        <size>0x20</size>
        <fields>
          <field>
            <name>LT</name>
            <bitOffset>0</bitOffset>
            <bitWidth>12</bitWidth>
          </field>
        </fields>
      </register>
      <register>
        <name>SQR1</name>
        <addressOffset>0x2c</addressOffset>
        <size>0x20</size>
        <fields>
          <field>
            <name>SQ13</name>
            <bitOffset>0</bitOffset>
            <bitWidth>5</bitWidth>
          </field>
          <field>
            <name>SQ14</name>
            <bitOffset>5</bitOffset>
            <bitWidth>5</bitWidth>
          </field>
          <field>
            <name>SQ15</name>
            <bitOffset>10</bitOffset>
            <bitWidth>5</bitWidth>
          </field>
          <field>
            <name>SQ16</name>
            <bitOffset>15</bitOffset>
            <bitWidth>5</bitWidth>
          </field>
          <field>
            <name>L</name>
            <bitOffset>20</bitOffset>
            <bitWidth>4</bitWidth>
          </field>
        </fields>
      </register>
      <register>
        <name>SQR2</name>
        <addressOffset>0x30</addressOffset>
        <size>0x20</size>
        <fields>
          <field>
            <name>SQ7</name>
            <bitOffset>0</bitOffset>
            <bitWidth>5</bitWidth>
          </field>
          <field>
            <name>SQ8</name>
            <bitOffset>5</bitOffset>
            <bitWidth>5</bitWidth>
          </field>
          <field>
            <name>SQ9</name>
            <bitOffset>10</bitOffset>
            <bitWidth>5</bitWidth>
          </field>
          <field>
            <name>SQ10</name>
            <bitOffset>15</bitOffset>
            <bitWidth>5</bitWidth>
          </field>
          <field>
            <name>SQ11</name>
            <bitOffset>20</bitOffset>
            <bitWidth>5</bitWidth>
          </field>
          <field>
            <name>SQ12</name>
            <bitOffset>25</bitOffset>
            <bitWidth>5</bitWidth>
          </field>
        </fields>
      </register>
      <register>
        <name>SQR3</name>
        <addressOffset>0x34</addressOffset>
        <size>0x20</size>
        <fields>
          <field>
            <name>SQ1</name>
            <bitOffset>0</bitOffset>
            <bitWidth>5</bitWidth>
          </field>
          <field>
            <name>SQ2</name>
            <bitOffset>5</bitOffset>
            <bitWidth>5</bitWidth>
          </field>
          <field>
            <name>SQ3</name>
            <bitOffset>10</bitOffset>
            <bitWidth>5</bitWidth>
          </field>
          <field>
            <name>SQ4</name>
            <bitOffset>15</bitOffset>
            <bitWidth>5</bitWidth>
          </field>
          <field>
            <name>SQ5</name>
            <bitOffset>20</bitOffset>
            <bitWidth>5</bitWidth>
          </field>
          <field>
            <name>SQ6</name>
            <bitOffset>25</bitOffset>
            <bitWidth>5</bitWidth>
          </field>
        </fields>
      </register>
      <register>
        <name>JSQR</name>
        <addressOffset>0x38</addressOffset>
        <size>0x20</size>
        <fields>
          <field>
            <name>JSQ1</name>
            <bitOffset>0</bitOffset>
            <bitWidth>5</bitWidth>
          </field>
          <field>
            <name>JSQ2</name>
            <bitOffset>5</bitOffset>
            <bitWidth>5</bitWidth>
          </field>
          <field>
            <name>JSQ3</name>
            <bitOffset>10</bitOffset>
            <bitWidth>5</bitWidth>
          </field>
          <field>
            <name>JSQ4</name>
            <bitOffset>15</bitOffset>
            <bitWidth>5</bitWidth>
          </field>
          <field>
            <name>JL</name>
            <bitOffset>20</bitOffset>
            <bitWidth>2</bitWidth>
          </field>
        </fields>
      </register>
      <register>
        <name>JDR1</name>
        <addressOffset>0x3c</addressOffset>
        <size>0x20</size>
        <fields>
          <field>
            <name>JDATA</name>
            <bitOffset>0</bitOffset>
            <bitWidth>16</bitWidth>
          </field>
        </fields>
      </register>
      <register>
        <name>JDR2</name>
        <addressOffset>0x40</addressOffset>
        <size>0x20</size>
        <fields>
          <field>
            <name>JDATA</name>
            <bitOffset>0</bitOffset>
            <bitWidth>16</bitWidth>
          </field>
        </fields>
      </register>
      <register>
        <name>JDR3</name>
        <addressOffset>0x44</addressOffset>
        <size>0x20</size>
        <fields>
          <field>
            <name>JDATA</name>
            <bitOffset>0</bitOffset>
            <bitWidth>16</bitWidth>
          </field>
        </fields>
      </register>
      <register>
        <name>JDR4</name>
        <addressOffset>0x48</addressOffset>
        <size>0x20</size>
        <fields>
          <field>
            <name>JDATA</name>
            <bitOffset>0</bitOffset>
            <bitWidth>16</bitWidth>
          </field>
        </fields>
      </register>
      <register>
        <name>DR</name>
        <addressOffset>0x4c</addressOffset>
        <size>0x20</size>
        <fields>
          <field>
            <name>DATA</name>
            <bitOffset>0</bitOffset>
            <bitWidth>16</bitWidth>
          </field>
          <field>
            <name>ADC2DATA</name>
            <bitOffset>16</bitOffset>
            <bitWidth>16</bitWidth>
          </field>
        </fields>
      </register>
    </peripheral>
    <peripheral>
      <name>ADC123_COMMON</name>
      <baseAddress>0x40012300</baseAddress>
      <register>
        <name>CSR</name>
        <addressOffset>0x0</addressOffset>
        <size>0x20</size>
        <fields>
          <field>
            <name>AWD1</name>
            <bitOffset>0</bitOffset>
            <bitWidth>1</bitWidth>
          </field>
          <field>
            <name>EOC1</name>
            <bitOffset>1</bitOffset>
            <bitWidth>1</bitWidth>
          </field>
          <field>
            <name>JEOC1</name>
            <bitOffset>2</bitOffset>
            <bitWidth>1</bitWidth>
          </field>
          <field>
            <name>JSTRT1</name>
            <bitOffset>3</bitOffset>
            <bitWidth>1</bitWidth>
          </field>
          <field>
            <name>STRT1</name>
            <bitOffset>4</bitOffset>
            <bitWidth>1</bitWidth>
          </field>
          <field>
            <name>OVR1</name>
            <bitOffset>5</bitOffset>
            <bitWidth>1</bitWidth>
          </field>
          <field>
            <name>AWD2</name>
            <bitOffset>8</bitOffset>
            <bitWidth>1</bitWidth>
          </field>
          <field>
            <name>EOC2</name>
            <bitOffset>9</bitOffset>
            <bitWidth>1</bitWidth>
          </field>
          <field>
            <name>JEOC2</name>
            <bitOffset>10</bitOffset>
            <bitWidth>1</bitWidth>
          </field>
          <field>
            <name>JSTRT2</name>
            <bitOffset>11</bitOffset>
            <bitWidth>1</bitWidth>
          </field>
          <field>
            <name>STRT2</name>
            <bitOffset>12</bitOffset>
            <bitWidth>1</bitWidth>
          </field>
          <field>
            <name>OVR2</name>
            <bitOffset>13</bitOffset>
            <bitWidth>1</bitWidth>
          </field>
          <field>
            <name>AWD3</name>
            <bitOffset>16</bitOffset>
            <bitWidth>1</bitWidth>
          </field>
          <field>
            <name>EOC3</name>
            <bitOffset>17</bitOffset>
            <bitWidth>1</bitWidth>
          </field>
          <field>
            <name>JEOC3</name>
            <bitOffset>18</bitOffset>
            <bitWidth>1</bitWidth>
          </field>
          <field>
            <name>JSTRT3</name>
            <bitOffset>19</bitOffset>
            <bitWidth>1</bitWidth>
          </field>
          <field>
            <name>STRT3</name>
            <bitOffset>20</bitOffset>
            <bitWidth>1</bitWidth>
          </field>
          <field>
            <name>OVR3</name>
            <bitOffset>21</bitOffset>
            <bitWidth>1</bitWidth>
          </field>
        </fields>
      </register>
      <register>
        <name>CCR</name>
        <addressOffset>0x4</addressOffset>
        <size>0x20</size>
        <fields>
          <field>
            <name>MULTI</name>
            <bitOffset>0</bitOffset>
            <bitWidth>5</bitWidth>
          </field>
          <field>
            <name>DELAY</name>
            <bitOffset>8</bitOffset>
            <bitWidth>4</bitWidth>
          </field>
          <field>
            <name>DDS</name>
            <bitOffset>13</bitOffset>
            <bitWidth>1</bitWidth>
          </field>
          <field>
            <name>DMA</name>
            <bitOffset>14</bitOffset>
            <bitWidth>2</bitWidth>
          </field>
          <field>
            <name>ADCPRE</name>
            <bitOffset>16</bitOffset>
            <bitWidth>2</bitWidth>
          </field>
          <field>
            <name>VBATE</name>
            <bitOffset>22</bitOffset>
            <bitWidth>1</bitWidth>
          </field>
          <field>
            <name>TSVREFE</name>
            <bitOffset>23</bitOffset>
            <bitWidth>1</bitWidth>
          </field>
        </fields>
      </register>
      <register>
        <name>CDR</name>
        <addressOffset>0x8</addressOffset>
        <size>0x20</size>
        <fields>
          <field>
            <name>DATA1</name>
            <bitOffset>0</bitOffset>
            <bitWidth>16</bitWidth>
          </field>
          <field>
            <name>DATA2</name>
            <bitOffset>16</bitOffset>
            <bitWidth>16</bitWidth>
          </field>
        </fields>
      </register>
    </peripheral>
    <peripheral>
      <name>SDIO</name>
      <baseAddress>0x40012c00</baseAddress>
      <register>
        <name>POWER</name>
        <addressOffset>0x0</addressOffset>
        <size>0x20</size>
        <fields>
          <field>
            <name>PWRCTRL</name>
            <bitOffset>0</bitOffset>
            <bitWidth>2</bitWidth>
          </field>
        </fields>
      </register>
      <register>
        <name>CLKCR</name>
        <addressOffset>0x4</addressOffset>
        <size>0x20</size>
        <fields>
          <field>
            <name>CLKDIV</name>
            <bitOffset>0</bitOffset>
            <bitWidth>8</bitWidth>
          </field>
          <field>
            <name>CLKEN</name>
            <bitOffset>8</bitOffset>
            <bitWidth>1</bitWidth>
          </field>
          <field>
            <name>PWRSAV</name>
            <bitOffset>9</bitOffset>
            <bitWidth>1</bitWidth>
          </field>
          <field>
            <name>BYPASS</name>
            <bitOffset>10</bitOffset>
            <bitWidth>1</bitWidth>
          </field>
          <field>
            <name>WIDBUS</name>
            <bitOffset>11</bitOffset>
            <bitWidth>2</bitWidth>
          </field>
          <field>
            <name>NEGEDGE</name>
            <bitOffset>13</bitOffset>
            <bitWidth>1</bitWidth>
          </field>
          <field>
            <name>HWFC_EN</name>
            <bitOffset>14</bitOffset>
            <bitWidth>1</bitWidth>
          </field>
        </fields>
      </register>
      <register>
        <name>ARG</name>
        <addressOffset>0x8</addressOffset>
        <size>0x20</size>
        <fields>
          <field>
            <name>CMDARG</name>
            <bitOffset>0</bitOffset>
            <bitWidth>32</bitWidth>
          </field>
        </fields>
      </register>
      <register>
        <name>CMD</name>
        <addressOffset>0xc</addressOffset>
        <size>0x20</size>
        <fields>
          <field>
            <name>CMDINDEX</name>
            <bitOffset>0</bitOffset>
            <bitWidth>6</bitWidth>
          </field>
          <field>
            <name>WAITRESP</name>
            <bitOffset>6</bitOffset>
            <bitWidth>2</bitWidth>
          </field>
          <field>
            <name>WAITINT</name>
            <bitOffset>8</bitOffset>
            <bitWidth>1</bitWidth>
          </field>
          <field>
            <name>WAITPEND</name>
            <bitOffset>9</bitOffset>
            <bitWidth>1</bitWidth>
          </field>
          <field>
            <name>CPSMEN</name>
            <bitOffset>10</bitOffset>
            <bitWidth>1</bitWidth>
          </field>
          <field>
            <name>SDIOSUSPEND</name>
            <bitOffset>11</bitOffset>
            <bitWidth>1</bitWidth>
          </field>
          <field>
            <name>ENCMDCOMPL</name>
            <bitOffset>12</bitOffset>
            <bitWidth>1</bitWidth>
          </field>
          <field>
            <name>NIEN</name>
            <bitOffset>13</bitOffset>
            <bitWidth>1</bitWidth>
          </field>
          <field>
            <name>CEATACMD</name>
            <bitOffset>14</bitOffset>
            <bitWidth>1</bitWidth>
          </field>
        </fields>
      </register>
      <register>
        <name>RESPCMD</name>
        <addressOffset>0x10</addressOffset>
        <size>0x20</size>
        <fields>
          <field>
            <name>RESPCMD</name>
            <bitOffset>0</bitOffset>
            <bitWidth>6</bitWidth>
          </field>
        </fields>
      </register>
      <register>
        <name>RESP1</name>
        <addressOffset>0x14</addressOffset>
        <size>0x20</size>
        <fields>
          <field>
            <name>CARDSTATUS1</name>
            <bitOffset>0</bitOffset>
            <bitWidth>32</bitWidth>
          </field>
        </fields>
      </register>
      <register>
        <name>RESP2</name>
        <addressOffset>0x18</addressOffset>
        <size>0x20</size>
        <fields>
          <field>
            <name>CARDSTATUS2</name>
            <bitOffset>0</bitOffset>
            <bitWidth>32</bitWidth>
          </field>
        </fields>
      </register>
      <register>
        <name>RESP3</name>
        <addressOffset>0x1c</addressOffset>
        <size>0x20</size>
        <fields>
          <field>
            <name>CARDSTATUS3</name>
            <bitOffset>0</bitOffset>
            <bitWidth>32</bitWidth>
          </field>
        </fields>
      </register>
      <register>
        <name>RESP4</name>
        <addressOffset>0x20</addressOffset>
        <size>0x20</size>
        <fields>
          <field>
            <name>CARDSTATUS4</name>
            <bitOffset>0</bitOffset>
            <bitWidth>32</bitWidth>
          </field>
        </fields>
      </register>
      <register>
        <name>DTIMER</name>
        <addressOffset>0x24</addressOffset>
        <size>0x20</size>
        <fields>
          <field>
            <name>DATATIME</name>
            <bitOffset>0</bitOffset>
            <bitWidth>32</bitWidth>
          </field>
        </fields>
      </register>
      <register>
        <name>DLEN</name>
        <addressOffset>0x28</addressOffset>
        <size>0x20</size>
        <fields>
          <field>
            <name>DATALENGTH</name>
            <bitOffset>0</bitOffset>
            <bitWidth>25</bitWidth>
          </field>
        </fields>
      </register>
      <register>
        <name>DCTRL</name>
        <addressOffset>0x2c</addressOffset>
        <size>0x20</size>
        <fields>
          <field>
            <name>DTEN</name>
            <bitOffset>0</bitOffset>
            <bitWidth>1</bitWidth>
          </field>
          <field>
            <name>DTDIR</name>
            <bitOffset>1</bitOffset>
            <bitWidth>1</bitWidth>
          </field>
          <field>
            <name>DTMODE</name>
            <bitOffset>2</bitOffset>
            <bitWidth>1</bitWidth>
          </field>
          <field>
            <name>DMAEN</name>
            <bitOffset>3</bitOffset>
            <bitWidth>1</bitWidth>
          </field>
          <field>
            <name>DBLOCKSIZE</name>
            <bitOffset>4</bitOffset>
            <bitWidth>4</bitWidth>
          </field>
          <field>
            <name>RWSTART</name>
            <bitOffset>8</bitOffset>
            <bitWidth>1</bitWidth>
          </field>
          <field>
            <name>RWSTOP</name>
            <bitOffset>9</bitOffset>
            <bitWidth>1</bitWidth>
          </field>
          <field>
            <name>RWMOD</name>
            <bitOffset>10</bitOffset>
            <bitWidth>1</bitWidth>
          </field>
          <field>
            <name>SDIOEN</name>
            <bitOffset>11</bitOffset>
            <bitWidth>1</bitWidth>
          </field>
        </fields>
      </register>
      <register>
        <name>DCOUNT</name>
        <addressOffset>0x30</addressOffset>
        <size>0x20</size>
        <fields>
          <field>
            <name>DATACOUNT</name>
            <bitOffset>0</bitOffset>
            <bitWidth>25</bitWidth>
          </field>
        </fields>
      </register>
      <register>
        <name>STA</name>
        <addressOffset>0x34</addressOffset>
        <size>0x20</size>
        <fields>
          <field>
            <name>CCRCFAIL</name>
            <bitOffset>0</bitOffset>
            <bitWidth>1</bitWidth>
          </field>
          <field>
            <name>DCRCFAIL</name>
            <bitOffset>1</bitOffset>
            <bitWidth>1</bitWidth>
          </field>
          <field>
            <name>CTIMEOUT</name>
            <bitOffset>2</bitOffset>
            <bitWidth>1</bitWidth>
          </field>
          <field>
            <name>DTIMEOUT</name>
            <bitOffset>3</bitOffset>
            <bitWidth>1</bitWidth>
          </field>
          <field>
            <name>TXUNDERR</name>
            <bitOffset>4</bitOffset>
            <bitWidth>1</bitWidth>
          </field>
          <field>
            <name>RXOVERR</name>
            <bitOffset>5</bitOffset>
            <bitWidth>1</bitWidth>
          </field>
          <field>
            <name>CMDREND</name>
            <bitOffset>6</bitOffset>
            <bitWidth>1</bitWidth>
          </field>
          <field>
            <name>CMDSENT</name>
            <bitOffset>7</bitOffset>
            <bitWidth>1</bitWidth>
          </field>
          <field>
            <name>DATAEND</name>
            <bitOffset>8</bitOffset>
            <bitWidth>1</bitWidth>
          </field>
          <field>
            <name>STBITERR</name>
            <bitOffset>9</bitOffset>
            <bitWidth>1</bitWidth>
          </field>
          <field>
            <name>DBCKEND</name>
            <bitOffset>10</bitOffset>
            <bitWidth>1</bitWidth>
          </field>
          <field>
            <name>CMDACT</name>
            <bitOffset>11</bitOffset>
            <bitWidth>1</bitWidth>
          </field>
          <field>
            <name>TXACT</name>
            <bitOffset>12</bitOffset>
            <bitWidth>1</bitWidth>
          </field>
          <field>
            <name>RXACT</name>
            <bitOffset>13</bitOffset>
            <bitWidth>1</bitWidth>
          </field>
          <field>
            <name>TXFIFOHE</name>
            <bitOffset>14</bitOffset>
            <bitWidth>1</bitWidth>
          </field>
          <field>
            <name>RXFIFOHF</name>
            <bitOffset>15</bitOffset>
            <bitWidth>1</bitWidth>
          </field>
          <field>
            <name>TXFIFOF</name>
            <bitOffset>16</bitOffset>
            <bitWidth>1</bitWidth>
          </field>
          <field>
            <name>RXFIFOF</name>
            <bitOffset>17</bitOffset>
            <bitWidth>1</bitWidth>
          </field>
          <field>
            <name>TXFIFOE</name>
            <bitOffset>18</bitOffset>
            <bitWidth>1</bitWidth>
          </field>
          <field>
            <name>RXFIFOE</name>
            <bitOffset>19</bitOffset>
            <bitWidth>1</bitWidth>
          </field>
          <field>
            <name>TXDAVL</name>
            <bitOffset>20</bitOffset>
            <bitWidth>1</bitWidth>
          </field>
          <field>
            <name>RXDAVL</name>
            <bitOffset>21</bitOffset>
            <bitWidth>1</bitWidth>
          </field>
          <field>
            <name>SDIOIT</name>
            <bitOffset>22</bitOffset>
            <bitWidth>1</bitWidth>
          </field>
          <field>
            <name>CEATAEND</name>
            <bitOffset>23</bitOffset>
            <bitWidth>1</bitWidth>
          </field>
        </fields>
      </register>
      <register>
        <name>ICR</name>
        <addressOffset>0x38</addressOffset>
        <size>0x20</size>
        <fields>
          <field>
            <name>CCRCFAILC</name>
            <bitOffset>0</bitOffset>
            <bitWidth>1</bitWidth>
          </field>
          <field>
            <name>DCRCFAILC</name>
            <bitOffset>1</bitOffset>
            <bitWidth>1</bitWidth>
          </field>
          <field>
            <name>CTIMEOUTC</name>
            <bitOffset>2</bitOffset>
            <bitWidth>1</bitWidth>
          </field>
          <field>
            <name>DTIMEOUTC</name>
            <bitOffset>3</bitOffset>
            <bitWidth>1</bitWidth>
          </field>
          <field>
            <name>TXUNDERRC</name>
            <bitOffset>4</bitOffset>
            <bitWidth>1</bitWidth>
          </field>
          <field>
            <name>RXOVERRC</name>
            <bitOffset>5</bitOffset>
            <bitWidth>1</bitWidth>
          </field>
          <field>
            <name>CMDRENDC</name>
            <bitOffset>6</bitOffset>
            <bitWidth>1</bitWidth>
          </field>
          <field>
            <name>CMDSENTC</name>
            <bitOffset>7</bitOffset>
            <bitWidth>1</bitWidth>
          </field>
          <field>
            <name>DATAENDC</name>
            <bitOffset>8</bitOffset>
            <bitWidth>1</bitWidth>
          </field>
          <field>
            <name>STBITERRC</name>
            <bitOffset>9</bitOffset>
            <bitWidth>1</bitWidth>
          </field>
          <field>
            <name>DBCKENDC</name>
            <bitOffset>10</bitOffset>
            <bitWidth>1</bitWidth>
          </field>
          <field>
            <name>SDIOITC</name>
            <bitOffset>22</bitOffset>
            <bitWidth>1</bitWidth>
          </field>
          <field>
            <name>CEATAENDC</name>
            <bitOffset>23</bitOffset>
            <bitWidth>1</bitWidth>
          </field>
        </fields>
      </register>
      <register>
        <name>MASK</name>
        <addressOffset>0x3c</addressOffset>
        <size>0x20</size>
        <fields>
          <field>
            <name>CCRCFAILIE</name>
            <bitOffset>0</bitOffset>
            <bitWidth>1</bitWidth>
          </field>
          <field>
            <name>DCRCFAILIE</name>
            <bitOffset>1</bitOffset>
            <bitWidth>1</bitWidth>
          </field>
          <field>
            <name>CTIMEOUTIE</name>
            <bitOffset>2</bitOffset>
            <bitWidth>1</bitWidth>
          </field>
          <field>
            <name>DTIMEOUTIE</name>
            <bitOffset>3</bitOffset>
            <bitWidth>1</bitWidth>
          </field>
          <field>
            <name>TXUNDERRIE</name>
            <bitOffset>4</bitOffset>
            <bitWidth>1</bitWidth>
          </field>
          <field>
            <name>RXOVERRIE</name>
            <bitOffset>5</bitOffset>
            <bitWidth>1</bitWidth>
          </field>
          <field>
            <name>CMDRENDIE</name>
            <bitOffset>6</bitOffset>
            <bitWidth>1</bitWidth>
          </field>
          <field>
            <name>CMDSENTIE</name>
            <bitOffset>7</bitOffset>
            <bitWidth>1</bitWidth>
          </field>
          <field>
            <name>DATAENDIE</name>
            <bitOffset>8</bitOffset>
            <bitWidth>1</bitWidth>
          </field>
          <field>
            <name>STBITERRIE</name>
            <bitOffset>9</bitOffset>
            <bitWidth>1</bitWidth>
          </field>
          <field>
            <name>DBCKENDIE</name>
            <bitOffset>10</bitOffset>
            <bitWidth>1</bitWidth>
          </field>
          <field>
            <name>CMDACTIE</name>
            <bitOffset>11</bitOffset>
            <bitWidth>1</bitWidth>
          </field>
          <field>
            <name>TXACTIE</name>
            <bitOffset>12</bitOffset>
            <bitWidth>1</bitWidth>
          </field>
          <field>
            <name>RXACTIE</name>
            <bitOffset>13</bitOffset>
            <bitWidth>1</bitWidth>
          </field>
          <field>
            <name>TXFIFOHEIE</name>
            <bitOffset>14</bitOffset>
            <bitWidth>1</bitWidth>
          </field>
          <field>
            <name>RXFIFOHFIE</name>
            <bitOffset>15</bitOffset>
            <bitWidth>1</bitWidth>
          </field>
          <field>
            <name>TXFIFOFIE</name>
            <bitOffset>16</bitOffset>
            <bitWidth>1</bitWidth>
          </field>
          <field>
            <name>RXFIFOFIE</name>
            <bitOffset>17</bitOffset>
            <bitWidth>1</bitWidth>
          </field>
          <field>
            <name>TXFIFOEIE</name>
            <bitOffset>18</bitOffset>
            <bitWidth>1</bitWidth>
          </field>
          <field>
            <name>RXFIFOEIE</name>
            <bitOffset>19</bitOffset>
            <bitWidth>1</bitWidth>
          </field>
          <field>
            <name>TXDAVLIE</name>
            <bitOffset>20</bitOffset>
            <bitWidth>1</bitWidth>
          </field>
          <field>
            <name>RXDAVLIE</name>
            <bitOffset>21</bitOffset>
            <bitWidth>1</bitWidth>
          </field>
          <field>
            <name>SDIOITIE</name>
            <bitOffset>22</bitOffset>
            <bitWidth>1</bitWidth>
          </field>
          <field>
            <name>CEATAENDIE</name>
            <bitOffset>23</bitOffset>
            <bitWidth>1</bitWidth>
          </field>
        </fields>
      </register>
      <register>
        <name>FIFOCNT</name>
        <addressOffset>0x48</addressOffset>
        <size>0x20</size>
        <fields>
          <field>
            <name>FIFOCOUNT</name>
            <bitOffset>0</bitOffset>
            <bitWidth>24</bitWidth>
          </field>
        </fields>
      </register>
      <register>
        <name>FIFO</name>
        <addressOffset>0x80</addressOffset>
        <size>0x20</size>
        <fields>
          <field>
            <name>FIFODATA</name>
            <bitOffset>0</bitOffset>
            <bitWidth>32</bitWidth>
          </field>
        </fields>
      </register>
    </peripheral>
    <peripheral>
      <name>SPI1</name>
      <baseAddress>0x40013000</baseAddress>
      <register>
        <name>CR1</name>
        <addressOffset>0x0</addressOffset>
        <size>0x20</size>
        <fields>
          <field>
            <name>CPHA</name>
            <bitOffset>0</bitOffset>
            <bitWidth>1</bitWidth>
          </field>
          <field>
            <name>CPOL</name>
            <bitOffset>1</bitOffset>
            <bitWidth>1</bitWidth>
          </field>
          <field>
            <name>MSTR</name>
            <bitOffset>2</bitOffset>
            <bitWidth>1</bitWidth>
          </field>
          <field>
            <name>BR</name>
            <bitOffset>3</bitOffset>
            <bitWidth>3</bitWidth>
          </field>
          <field>
            <name>SPE</name>
            <bitOffset>6</bitOffset>
            <bitWidth>1</bitWidth>
          </field>
          <field>
            <name>LSBFIRST</name>
            <bitOffset>7</bitOffset>
            <bitWidth>1</bitWidth>
          </field>
          <field>
            <name>SSI</name>
            <bitOffset>8</bitOffset>
            <bitWidth>1</bitWidth>
          </field>
          <field>
            <name>SSM</name>
            <bitOffset>9</bitOffset>
            <bitWidth>1</bitWidth>
          </field>
          <field>
            <name>RXONLY</name>
            <bitOffset>10</bitOffset>
            <bitWidth>1</bitWidth>
          </field>
          <field>
            <name>DFF</name>
            <bitOffset>11</bitOffset>
            <bitWidth>1</bitWidth>
          </field>
          <field>
            <name>CRCNEXT</name>
            <bitOffset>12</bitOffset>
            <bitWidth>1</bitWidth>
          </field>
          <field>
            <name>CRCEN</name>
            <bitOffset>13</bitOffset>
            <bitWidth>1</bitWidth>
          </field>
          <field>
            <name>BIDIOE</name>
            <bitOffset>14</bitOffset>
            <bitWidth>1</bitWidth>
          </field>
          <field>
            <name>BIDIMODE</name>
            <bitOffset>15</bitOffset>
            <bitWidth>1</bitWidth>
          </field>
        </fields>
      </register>
      <register>
        <name>CR2</name>
        <addressOffset>0x4</addressOffset>
        <size>0x20</size>
        <fields>
          <field>
            <name>RXDMAEN</name>
            <bitOffset>0</bitOffset>
            <bitWidth>1</bitWidth>
          </field>
          <field>
            <name>TXDMAEN</name>
            <bitOffset>1</bitOffset>
            <bitWidth>1</bitWidth>
          </field>
          <field>
            <name>SSOE</name>
            <bitOffset>2</bitOffset>
            <bitWidth>1</bitWidth>
          </field>
          <field>
            <name>FRF</name>
            <bitOffset>4</bitOffset>
            <bitWidth>1</bitWidth>
          </field>
          <field>
            <name>ERRIE</name>
            <bitOffset>5</bitOffset>
            <bitWidth>1</bitWidth>
          </field>
          <field>
            <name>RXNEIE</name>
            <bitOffset>6</bitOffset>
            <bitWidth>1</bitWidth>
          </field>
          <field>
            <name>TXEIE</name>
            <bitOffset>7</bitOffset>
            <bitWidth>1</bitWidth>
          </field>
        </fields>
      </register>
      <register>
        <name>SR</name>
        <addressOffset>0x8</addressOffset>
        <size>0x20</size>
        <fields>
          <field>
            <name>RXNE</name>
            <bitOffset>0</bitOffset>
            <bitWidth>1</bitWidth>
          </field>
          <field>
            <name>TXE</name>
            <bitOffset>1</bitOffset>
            <bitWidth>1</bitWidth>
          </field>
          <field>
            <name>CHSIDE</name>
            <bitOffset>2</bitOffset>
            <bitWidth>1</bitWidth>
          </field>
          <field>
            <name>UDR</name>
            <bitOffset>3</bitOffset>
            <bitWidth>1</bitWidth>
          </field>
          <field>
            <name>CRCERR</name>
            <bitOffset>4</bitOffset>
            <bitWidth>1</bitWidth>
          </field>
          <field>
            <name>MODF</name>
            <bitOffset>5</bitOffset>
            <bitWidth>1</bitWidth>
          </field>
          <field>
            <name>OVR</name>
            <bitOffset>6</bitOffset>
            <bitWidth>1</bitWidth>
          </field>
          <field>
            <name>BSY</name>
            <bitOffset>7</bitOffset>
            <bitWidth>1</bitWidth>
          </field>
          <field>
            <name>FRE</name>
            <bitOffset>8</bitOffset>
            <bitWidth>1</bitWidth>
          </field>
        </fields>
      </register>
      <register>
        <name>DR</name>
        <addressOffset>0xc</addressOffset>
        <size>0x20</size>
        <fields>
          <field>
            <name>DR</name>
            <bitOffset>0</bitOffset>
            <bitWidth>16</bitWidth>
          </field>
        </fields>
      </register>
      <register>
        <name>CRCPR</name>
        <addressOffset>0x10</addressOffset>
        <size>0x20</size>
        <fields>
          <field>
            <name>CRCPOLY</name>
            <bitOffset>0</bitOffset>
            <bitWidth>16</bitWidth>
          </field>
        </fields>
      </register>
      <register>
        <name>RXCRCR</name>
        <addressOffset>0x14</addressOffset>
        <size>0x20</size>
        <fields>
          <field>
            <name>RXCRC</name>
            <bitOffset>0</bitOffset>
            <bitWidth>16</bitWidth>
          </field>
        </fields>
      </register>
      <register>
        <name>TXCRCR</name>
        <addressOffset>0x18</addressOffset>
        <size>0x20</size>
        <fields>
          <field>
            <name>TXCRC</name>
            <bitOffset>0</bitOffset>
            <bitWidth>16</bitWidth>
          </field>
        </fields>
      </register>
      <register>
        <name>I2SCFGR</name>
        <addressOffset>0x1c</addressOffset>
        <size>0x20</size>
        <fields>
          <field>
            <name>CHLEN</name>
            <bitOffset>0</bitOffset>
            <bitWidth>1</bitWidth>
          </field>
          <field>
            <name>DATLEN</name>
            <bitOffset>1</bitOffset>
            <bitWidth>2</bitWidth>
          </field>
          <field>
            <name>CKPOL</name>
            <bitOffset>3</bitOffset>
            <bitWidth>1</bitWidth>
          </field>
          <field>
            <name>I2SSTD</name>
            <bitOffset>4</bitOffset>
            <bitWidth>2</bitWidth>
          </field>
          <field>
            <name>PCMSYNC</name>
            <bitOffset>7</bitOffset>
            <bitWidth>1</bitWidth>
          </field>
          <field>
            <name>I2SCFG</name>
            <bitOffset>8</bitOffset>
            <bitWidth>2</bitWidth>
          </field>
          <field>
            <name>I2SE</name>
            <bitOffset>10</bitOffset>
            <bitWidth>1</bitWidth>
          </field>
          <field>
            <name>I2SMOD</name>
            <bitOffset>11</bitOffset>
            <bitWidth>1</bitWidth>
          </field>
        </fields>
      </register>
      <register>
        <name>I2SPR</name>
        <addressOffset>0x20</addressOffset>
        <size>0x20</size>
        <fields>
          <field>
            <name>I2SDIV</name>
            <bitOffset>0</bitOffset>
            <bitWidth>8</bitWidth>
          </field>
          <field>
            <name>ODD</name>
            <bitOffset>8</bitOffset>
            <bitWidth>1</bitWidth>
          </field>
          <field>
            <name>MCKOE</name>
            <bitOffset>9</bitOffset>
            <bitWidth>1</bitWidth>
          </field>
        </fields>
      </register>
    </peripheral>
    <peripheral>
      <name>SPI4</name>
      <baseAddress>0x40013400</baseAddress>
      <register>
        <name>CR1</name>
        <addressOffset>0x0</addressOffset>
        <size>0x20</size>
        <fields>
          <field>
            <name>CPHA</name>
            <bitOffset>0</bitOffset>
            <bitWidth>1</bitWidth>
          </field>
          <field>
            <name>CPOL</name>
            <bitOffset>1</bitOffset>
            <bitWidth>1</bitWidth>
          </field>
          <field>
            <name>MSTR</name>
            <bitOffset>2</bitOffset>
            <bitWidth>1</bitWidth>
          </field>
          <field>
            <name>BR</name>
            <bitOffset>3</bitOffset>
            <bitWidth>3</bitWidth>
          </field>
          <field>
            <name>SPE</name>
            <bitOffset>6</bitOffset>
            <bitWidth>1</bitWidth>
          </field>
          <field>
            <name>LSBFIRST</name>
            <bitOffset>7</bitOffset>
            <bitWidth>1</bitWidth>
          </field>
          <field>
            <name>SSI</name>
            <bitOffset>8</bitOffset>
            <bitWidth>1</bitWidth>
          </field>
          <field>
            <name>SSM</name>
            <bitOffset>9</bitOffset>
            <bitWidth>1</bitWidth>
          </field>
          <field>
            <name>RXONLY</name>
            <bitOffset>10</bitOffset>
            <bitWidth>1</bitWidth>
          </field>
          <field>
            <name>DFF</name>
            <bitOffset>11</bitOffset>
            <bitWidth>1</bitWidth>
          </field>
          <field>
            <name>CRCNEXT</name>
            <bitOffset>12</bitOffset>
            <bitWidth>1</bitWidth>
          </field>
          <field>
            <name>CRCEN</name>
            <bitOffset>13</bitOffset>
            <bitWidth>1</bitWidth>
          </field>
          <field>
            <name>BIDIOE</name>
            <bitOffset>14</bitOffset>
            <bitWidth>1</bitWidth>
          </field>
          <field>
            <name>BIDIMODE</name>
            <bitOffset>15</bitOffset>
            <bitWidth>1</bitWidth>
          </field>
        </fields>
      </register>
      <register>
        <name>CR2</name>
        <addressOffset>0x4</addressOffset>
        <size>0x20</size>
        <fields>
          <field>
            <name>RXDMAEN</name>
            <bitOffset>0</bitOffset>
            <bitWidth>1</bitWidth>
          </field>
          <field>
            <name>TXDMAEN</name>
            <bitOffset>1</bitOffset>
            <bitWidth>1</bitWidth>
          </field>
          <field>
            <name>SSOE</name>
            <bitOffset>2</bitOffset>
            <bitWidth>1</bitWidth>
          </field>
          <field>
            <name>FRF</name>
            <bitOffset>4</bitOffset>
            <bitWidth>1</bitWidth>
          </field>
          <field>
            <name>ERRIE</name>
            <bitOffset>5</bitOffset>
            <bitWidth>1</bitWidth>
          </field>
          <field>
            <name>RXNEIE</name>
            <bitOffset>6</bitOffset>
            <bitWidth>1</bitWidth>
          </field>
          <field>
            <name>TXEIE</name>
            <bitOffset>7</bitOffset>
            <bitWidth>1</bitWidth>
          </field>
        </fields>
      </register>
      <register>
        <name>SR</name>
        <addressOffset>0x8</addressOffset>
        <size>0x20</size>
        <fields>
          <field>
            <name>RXNE</name>
            <bitOffset>0</bitOffset>
            <bitWidth>1</bitWidth>
          </field>
          <field>
            <name>TXE</name>
            <bitOffset>1</bitOffset>
            <bitWidth>1</bitWidth>
          </field>
          <field>
            <name>CHSIDE</name>
            <bitOffset>2</bitOffset>
            <bitWidth>1</bitWidth>
          </field>
          <field>
            <name>UDR</name>
            <bitOffset>3</bitOffset>
            <bitWidth>1</bitWidth>
          </field>
          <field>
            <name>CRCERR</name>
            <bitOffset>4</bitOffset>
            <bitWidth>1</bitWidth>
          </field>
          <field>
            <name>MODF</name>
            <bitOffset>5</bitOffset>
            <bitWidth>1</bitWidth>
          </field>
          <field>
            <name>OVR</name>
            <bitOffset>6</bitOffset>
            <bitWidth>1</bitWidth>
          </field>
          <field>
            <name>BSY</name>
            <bitOffset>7</bitOffset>
            <bitWidth>1</bitWidth>
          </field>
          <field>
            <name>FRE</name>
            <bitOffset>8</bitOffset>
            <bitWidth>1</bitWidth>
          </field>
        </fields>
      </register>
      <register>
        <name>DR</name>
        <addressOffset>0xc</addressOffset>
        <size>0x20</size>
        <fields>
          <field>
            <name>DR</name>
            <bitOffset>0</bitOffset>
            <bitWidth>16</bitWidth>
          </field>
        </fields>
      </register>
      <register>
        <name>CRCPR</name>
        <addressOffset>0x10</addressOffset>
        <size>0x20</size>
        <fields>
          <field>
            <name>CRCPOLY</name>
            <bitOffset>0</bitOffset>
            <bitWidth>16</bitWidth>
          </field>
        </fields>
      </register>
      <register>
        <name>RXCRCR</name>
        <addressOffset>0x14</addressOffset>
        <size>0x20</size>
        <fields>
          <field>
            <name>RXCRC</name>
            <bitOffset>0</bitOffset>
            <bitWidth>16</bitWidth>
          </field>
        </fields>
      </register>
      <register>
        <name>TXCRCR</name>
        <addressOffset>0x18</addressOffset>
        <size>0x20</size>
        <fields>
          <field>
            <name>TXCRC</name>
            <bitOffset>0</bitOffset>
            <bitWidth>16</bitWidth>
          </field>
        </fields>
      </register>
      <register>
        <name>I2SCFGR</name>
        <addressOffset>0x1c</addressOffset>
        <size>0x20</size>
        <fields>
          <field>
            <name>CHLEN</name>
            <bitOffset>0</bitOffset>
            <bitWidth>1</bitWidth>
          </field>
          <field>
            <name>DATLEN</name>
            <bitOffset>1</bitOffset>
            <bitWidth>2</bitWidth>
          </field>
          <field>
            <name>CKPOL</name>
            <bitOffset>3</bitOffset>
            <bitWidth>1</bitWidth>
          </field>
          <field>
            <name>I2SSTD</name>
            <bitOffset>4</bitOffset>
            <bitWidth>2</bitWidth>
          </field>
          <field>
            <name>PCMSYNC</name>
            <bitOffset>7</bitOffset>
            <bitWidth>1</bitWidth>
          </field>
          <field>
            <name>I2SCFG</name>
            <bitOffset>8</bitOffset>
            <bitWidth>2</bitWidth>
          </field>
          <field>
            <name>I2SE</name>
            <bitOffset>10</bitOffset>
            <bitWidth>1</bitWidth>
          </field>
          <field>
            <name>I2SMOD</name>
            <bitOffset>11</bitOffset>
            <bitWidth>1</bitWidth>
          </field>
        </fields>
      </register>
      <register>
        <name>I2SPR</name>
        <addressOffset>0x20</addressOffset>
        <size>0x20</size>
        <fields>
          <field>
            <name>I2SDIV</name>
            <bitOffset>0</bitOffset>
            <bitWidth>8</bitWidth>
          </field>
          <field>
            <name>ODD</name>
            <bitOffset>8</bitOffset>
            <bitWidth>1</bitWidth>
          </field>
          <field>
            <name>MCKOE</name>
            <bitOffset>9</bitOffset>
            <bitWidth>1</bitWidth>
          </field>
        </fields>
      </register>
    </peripheral>
    <peripheral>
      <name>SYSCFG</name>
      <baseAddress>0x40013800</baseAddress>
      <register>
        <name>MEMRMP</name>
        <addressOffset>0x0</addressOffset>
        <size>0x20</size>
        <fields>
          <field>
            <name>MEM_MODE</name>
            <bitOffset>0</bitOffset>
            <bitWidth>3</bitWidth>
          </field>
          <field>
            <name>UFB_MODE</name>
            <bitOffset>8</bitOffset>
            <bitWidth>1</bitWidth>
          </field>
          <field>
            <name>SWP_FMC</name>
            <bitOffset>10</bitOffset>
            <bitWidth>2</bitWidth>
          </field>
        </fields>
      </register>
      <register>
        <name>PMC</name>
        <addressOffset>0x4</addressOffset>
        <size>0x20</size>
        <fields>
          <field>
            <name>ADCxDC2</name>
            <bitOffset>16</bitOffset>
            <bitWidth>3</bitWidth>
          </field>
          <field>
            <name>ADC2DC2</name>
            <bitOffset>17</bitOffset>
            <bitWidth>1</bitWidth>
          </field>
          <field>
            <name>ADC3DC2</name>
            <bitOffset>18</bitOffset>
            <bitWidth>1</bitWidth>
          </field>
          <field>
            <name>MII_RMII_SEL</name>
            <bitOffset>23</bitOffset>
            <bitWidth>1</bitWidth>
          </field>
        </fields>
      </register>
      <register>
        <name>EXTICR.0</name>
        <addressOffset>0x8</addressOffset>
        <size>0x20</size>
        <fields>
          <field>
            <name>EXTI0</name>
            <bitOffset>0</bitOffset>
            <bitWidth>4</bitWidth>
          </field>
          <field>
            <name>EXTI1</name>
            <bitOffset>4</bitOffset>
            <bitWidth>4</bitWidth>
          </field>
          <field>
            <name>EXTI2</name>
            <bitOffset>8</bitOffset>
            <bitWidth>4</bitWidth>
          </field>
          <field>
            <name>EXTI3</name>
            <bitOffset>12</bitOffset>
            <bitWidth>4</bitWidth>
          </field>
        </fields>
      </register>
      <register>
        <name>EXTICR.1</name>
        <addressOffset>0xc</addressOffset>
        <size>0x20</size>
        <fields>
          <field>
            <name>EXTI4</name>
            <bitOffset>0</bitOffset>
            <bitWidth>4</bitWidth>
          </field>
          <field>
            <name>EXTI5</name>
            <bitOffset>4</bitOffset>
            <bitWidth>4</bitWidth>
          </field>
          <field>
            <name>EXTI6</name>
            <bitOffset>8</bitOffset>
            <bitWidth>4</bitWidth>
          </field>
          <field>
            <name>EXTI7</name>
            <bitOffset>12</bitOffset>
            <bitWidth>4</bitWidth>
          </field>
        </fields>
      </register>
      <register>
        <name>EXTICR.2</name>
        <addressOffset>0x10</addressOffset>
        <size>0x20</size>
        <fields>
          <field>
            <name>EXTI8</name>
            <bitOffset>0</bitOffset>
            <bitWidth>4</bitWidth>
          </field>
          <field>
            <name>EXTI9</name>
            <bitOffset>4</bitOffset>
            <bitWidth>4</bitWidth>
          </field>
          <field>
            <name>EXTI10</name>
            <bitOffset>8</bitOffset>
            <bitWidth>4</bitWidth>
          </field>
          <field>
            <name>EXTI11</name>
            <bitOffset>12</bitOffset>
            <bitWidth>4</bitWidth>
          </field>
        </fields>
      </register>
      <register>
        <name>EXTICR.3</name>
        <addressOffset>0x14</addressOffset>
        <size>0x20</size>
        <fields>
          <field>
            <name>EXTI12</name>
            <bitOffset>0</bitOffset>
            <bitWidth>4</bitWidth>
          </field>
          <field>
            <name>EXTI13</name>
            <bitOffset>4</bitOffset>
            <bitWidth>4</bitWidth>
          </field>
          <field>
            <name>EXTI14</name>
            <bitOffset>8</bitOffset>
            <bitWidth>4</bitWidth>
          </field>
          <field>
            <name>EXTI15</name>
            <bitOffset>12</bitOffset>
            <bitWidth>4</bitWidth>
          </field>
        </fields>
      </register>
      <register>
        <name>CMPCR</name>
        <addressOffset>0x20</addressOffset>
        <size>0x20</size>
        <fields>
          <field>
            <name>CMP_PD</name>
            <bitOffset>0</bitOffset>
            <bitWidth>1</bitWidth>
          </field>
          <field>
            <name>READY</name>
            <bitOffset>8</bitOffset>
            <bitWidth>1</bitWidth>
          </field>
        </fields>
      </register>
    </peripheral>
    <peripheral>
      <name>EXTI</name>
      <baseAddress>0x40013c00</baseAddress>
      <register>
        <name>IMR</name>
        <addressOffset>0x0</addressOffset>
        <size>0x20</size>
        <fields>
          <field>
            <name>MR0</name>
            <bitOffset>0</bitOffset>
            <bitWidth>1</bitWidth>
          </field>
          <field>
            <name>MR1</name>
            <bitOffset>1</bitOffset>
            <bitWidth>1</bitWidth>
          </field>
          <field>
            <name>MR2</name>
            <bitOffset>2</bitOffset>
            <bitWidth>1</bitWidth>
          </field>
          <field>
            <name>MR3</name>
            <bitOffset>3</bitOffset>
            <bitWidth>1</bitWidth>
          </field>
          <field>
            <name>MR4</name>
            <bitOffset>4</bitOffset>
            <bitWidth>1</bitWidth>
          </field>
          <field>
            <name>MR5</name>
            <bitOffset>5</bitOffset>
            <bitWidth>1</bitWidth>
          </field>
          <field>
            <name>MR6</name>
            <bitOffset>6</bitOffset>
            <bitWidth>1</bitWidth>
          </field>
          <field>
            <name>MR7</name>
            <bitOffset>7</bitOffset>
            <bitWidth>1</bitWidth>
          </field>
          <field>
            <name>MR8</name>
            <bitOffset>8</bitOffset>
            <bitWidth>1</bitWidth>
          </field>
          <field>
            <name>MR9</name>
            <bitOffset>9</bitOffset>
            <bitWidth>1</bitWidth>
          </field>
          <field>
            <name>MR10</name>
            <bitOffset>10</bitOffset>
            <bitWidth>1</bitWidth>
          </field>
          <field>
            <name>MR11</name>
            <bitOffset>11</bitOffset>
            <bitWidth>1</bitWidth>
          </field>
          <field>
            <name>MR12</name>
            <bitOffset>12</bitOffset>
            <bitWidth>1</bitWidth>
          </field>
          <field>
            <name>MR13</name>
            <bitOffset>13</bitOffset>
            <bitWidth>1</bitWidth>
          </field>
          <field>
            <name>MR14</name>
            <bitOffset>14</bitOffset>
            <bitWidth>1</bitWidth>
          </field>
          <field>
            <name>MR15</name>
            <bitOffset>15</bitOffset>
            <bitWidth>1</bitWidth>
          </field>
          <field>
            <name>MR16</name>
            <bitOffset>16</bitOffset>
            <bitWidth>1</bitWidth>
          </field>
          <field>
            <name>MR17</name>
            <bitOffset>17</bitOffset>
            <bitWidth>1</bitWidth>
          </field>
          <field>
            <name>MR18</name>
            <bitOffset>18</bitOffset>
            <bitWidth>1</bitWidth>
          </field>
          <field>
            <name>MR19</name>
            <bitOffset>19</bitOffset>
            <bitWidth>1</bitWidth>
          </field>
          <field>
            <name>MR20</name>
            <bitOffset>20</bitOffset>
            <bitWidth>1</bitWidth>
          </field>
          <field>
            <name>MR21</name>
            <bitOffset>21</bitOffset>
            <bitWidth>1</bitWidth>
          </field>
          <field>
            <name>MR22</name>
            <bitOffset>22</bitOffset>
            <bitWidth>1</bitWidth>
          </field>
        </fields>
      </register>
      <register>
        <name>EMR</name>
        <addressOffset>0x4</addressOffset>
        <size>0x20</size>
        <fields>
          <field>
            <name>MR0</name>
            <bitOffset>0</bitOffset>
            <bitWidth>1</bitWidth>
          </field>
          <field>
            <name>MR1</name>
            <bitOffset>1</bitOffset>
            <bitWidth>1</bitWidth>
          </field>
          <field>
            <name>MR2</name>
            <bitOffset>2</bitOffset>
            <bitWidth>1</bitWidth>
          </field>
          <field>
            <name>MR3</name>
            <bitOffset>3</bitOffset>
            <bitWidth>1</bitWidth>
          </field>
          <field>
            <name>MR4</name>
            <bitOffset>4</bitOffset>
            <bitWidth>1</bitWidth>
          </field>
          <field>
            <name>MR5</name>
            <bitOffset>5</bitOffset>
            <bitWidth>1</bitWidth>
          </field>
          <field>
            <name>MR6</name>
            <bitOffset>6</bitOffset>
            <bitWidth>1</bitWidth>
          </field>
          <field>
            <name>MR7</name>
            <bitOffset>7</bitOffset>
            <bitWidth>1</bitWidth>
          </field>
          <field>
            <name>MR8</name>
            <bitOffset>8</bitOffset>
            <bitWidth>1</bitWidth>
          </field>
          <field>
            <name>MR9</name>
            <bitOffset>9</bitOffset>
            <bitWidth>1</bitWidth>
          </field>
          <field>
            <name>MR10</name>
            <bitOffset>10</bitOffset>
            <bitWidth>1</bitWidth>
          </field>
          <field>
            <name>MR11</name>
            <bitOffset>11</bitOffset>
            <bitWidth>1</bitWidth>
          </field>
          <field>
            <name>MR12</name>
            <bitOffset>12</bitOffset>
            <bitWidth>1</bitWidth>
          </field>
          <field>
            <name>MR13</name>
            <bitOffset>13</bitOffset>
            <bitWidth>1</bitWidth>
          </field>
          <field>
            <name>MR14</name>
            <bitOffset>14</bitOffset>
            <bitWidth>1</bitWidth>
          </field>
          <field>
            <name>MR15</name>
            <bitOffset>15</bitOffset>
            <bitWidth>1</bitWidth>
          </field>
          <field>
            <name>MR16</name>
            <bitOffset>16</bitOffset>
            <bitWidth>1</bitWidth>
          </field>
          <field>
            <name>MR17</name>
            <bitOffset>17</bitOffset>
            <bitWidth>1</bitWidth>
          </field>
          <field>
            <name>MR18</name>
            <bitOffset>18</bitOffset>
            <bitWidth>1</bitWidth>
          </field>
          <field>
            <name>MR19</name>
            <bitOffset>19</bitOffset>
            <bitWidth>1</bitWidth>
          </field>
          <field>
            <name>MR20</name>
            <bitOffset>20</bitOffset>
            <bitWidth>1</bitWidth>
          </field>
          <field>
            <name>MR21</name>
            <bitOffset>21</bitOffset>
            <bitWidth>1</bitWidth>
          </field>
          <field>
            <name>MR22</name>
            <bitOffset>22</bitOffset>
            <bitWidth>1</bitWidth>
          </field>
        </fields>
      </register>
      <register>
        <name>RTSR</name>
        <addressOffset>0x8</addressOffset>
        <size>0x20</size>
        <fields>
          <field>
            <name>TR0</name>
            <bitOffset>0</bitOffset>
            <bitWidth>1</bitWidth>
          </field>
          <field>
            <name>TR1</name>
            <bitOffset>1</bitOffset>
            <bitWidth>1</bitWidth>
          </field>
          <field>
            <name>TR2</name>
            <bitOffset>2</bitOffset>
            <bitWidth>1</bitWidth>
          </field>
          <field>
            <name>TR3</name>
            <bitOffset>3</bitOffset>
            <bitWidth>1</bitWidth>
          </field>
          <field>
            <name>TR4</name>
            <bitOffset>4</bitOffset>
            <bitWidth>1</bitWidth>
          </field>
          <field>
            <name>TR5</name>
            <bitOffset>5</bitOffset>
            <bitWidth>1</bitWidth>
          </field>
          <field>
            <name>TR6</name>
            <bitOffset>6</bitOffset>
            <bitWidth>1</bitWidth>
          </field>
          <field>
            <name>TR7</name>
            <bitOffset>7</bitOffset>
            <bitWidth>1</bitWidth>
          </field>
          <field>
            <name>TR8</name>
            <bitOffset>8</bitOffset>
            <bitWidth>1</bitWidth>
          </field>
          <field>
            <name>TR9</name>
            <bitOffset>9</bitOffset>
            <bitWidth>1</bitWidth>
          </field>
          <field>
            <name>TR10</name>
            <bitOffset>10</bitOffset>
            <bitWidth>1</bitWidth>
          </field>
          <field>
            <name>TR11</name>
            <bitOffset>11</bitOffset>
            <bitWidth>1</bitWidth>
          </field>
          <field>
            <name>TR12</name>
            <bitOffset>12</bitOffset>
            <bitWidth>1</bitWidth>
          </field>
          <field>
            <name>TR13</name>
            <bitOffset>13</bitOffset>
            <bitWidth>1</bitWidth>
          </field>
          <field>
            <name>TR14</name>
            <bitOffset>14</bitOffset>
            <bitWidth>1</bitWidth>
          </field>
          <field>
            <name>TR15</name>
            <bitOffset>15</bitOffset>
            <bitWidth>1</bitWidth>
          </field>
          <field>
            <name>TR16</name>
            <bitOffset>16</bitOffset>
            <bitWidth>1</bitWidth>
          </field>
          <field>
            <name>TR17</name>
            <bitOffset>17</bitOffset>
            <bitWidth>1</bitWidth>
          </field>
          <field>
            <name>TR18</name>
            <bitOffset>18</bitOffset>
            <bitWidth>1</bitWidth>
          </field>
          <field>
            <name>TR19</name>
            <bitOffset>19</bitOffset>
            <bitWidth>1</bitWidth>
          </field>
          <field>
            <name>TR20</name>
            <bitOffset>20</bitOffset>
            <bitWidth>1</bitWidth>
          </field>
          <field>
            <name>TR21</name>
            <bitOffset>21</bitOffset>
            <bitWidth>1</bitWidth>
          </field>
          <field>
            <name>TR22</name>
            <bitOffset>22</bitOffset>
            <bitWidth>1</bitWidth>
          </field>
        </fields>
      </register>
      <register>
        <name>FTSR</name>
        <addressOffset>0xc</addressOffset>
        <size>0x20</size>
        <fields>
          <field>
            <name>TR0</name>
            <bitOffset>0</bitOffset>
            <bitWidth>1</bitWidth>
          </field>
          <field>
            <name>TR1</name>
            <bitOffset>1</bitOffset>
            <bitWidth>1</bitWidth>
          </field>
          <field>
            <name>TR2</name>
            <bitOffset>2</bitOffset>
            <bitWidth>1</bitWidth>
          </field>
          <field>
            <name>TR3</name>
            <bitOffset>3</bitOffset>
            <bitWidth>1</bitWidth>
          </field>
          <field>
            <name>TR4</name>
            <bitOffset>4</bitOffset>
            <bitWidth>1</bitWidth>
          </field>
          <field>
            <name>TR5</name>
            <bitOffset>5</bitOffset>
            <bitWidth>1</bitWidth>
          </field>
          <field>
            <name>TR6</name>
            <bitOffset>6</bitOffset>
            <bitWidth>1</bitWidth>
          </field>
          <field>
            <name>TR7</name>
            <bitOffset>7</bitOffset>
            <bitWidth>1</bitWidth>
          </field>
          <field>
            <name>TR8</name>
            <bitOffset>8</bitOffset>
            <bitWidth>1</bitWidth>
          </field>
          <field>
            <name>TR9</name>
            <bitOffset>9</bitOffset>
            <bitWidth>1</bitWidth>
          </field>
          <field>
            <name>TR10</name>
            <bitOffset>10</bitOffset>
            <bitWidth>1</bitWidth>
          </field>
          <field>
            <name>TR11</name>
            <bitOffset>11</bitOffset>
            <bitWidth>1</bitWidth>
          </field>
          <field>
            <name>TR12</name>
            <bitOffset>12</bitOffset>
            <bitWidth>1</bitWidth>
          </field>
          <field>
            <name>TR13</name>
            <bitOffset>13</bitOffset>
            <bitWidth>1</bitWidth>
          </field>
          <field>
            <name>TR14</name>
            <bitOffset>14</bitOffset>
            <bitWidth>1</bitWidth>
          </field>
          <field>
            <name>TR15</name>
            <bitOffset>15</bitOffset>
            <bitWidth>1</bitWidth>
          </field>
          <field>
            <name>TR16</name>
            <bitOffset>16</bitOffset>
            <bitWidth>1</bitWidth>
          </field>
          <field>
            <name>TR17</name>
            <bitOffset>17</bitOffset>
            <bitWidth>1</bitWidth>
          </field>
          <field>
            <name>TR18</name>
            <bitOffset>18</bitOffset>
            <bitWidth>1</bitWidth>
          </field>
          <field>
            <name>TR19</name>
            <bitOffset>19</bitOffset>
            <bitWidth>1</bitWidth>
          </field>
          <field>
            <name>TR20</name>
            <bitOffset>20</bitOffset>
            <bitWidth>1</bitWidth>
          </field>
          <field>
            <name>TR21</name>
            <bitOffset>21</bitOffset>
            <bitWidth>1</bitWidth>
          </field>
          <field>
            <name>TR22</name>
            <bitOffset>22</bitOffset>
            <bitWidth>1</bitWidth>
          </field>
        </fields>
      </register>
      <register>
        <name>SWIER</name>
        <addressOffset>0x10</addressOffset>
        <size>0x20</size>
        <fields>
          <field>
            <name>SWIER0</name>
            <bitOffset>0</bitOffset>
            <bitWidth>1</bitWidth>
          </field>
          <field>
            <name>SWIER1</name>
            <bitOffset>1</bitOffset>
            <bitWidth>1</bitWidth>
          </field>
          <field>
            <name>SWIER2</name>
            <bitOffset>2</bitOffset>
            <bitWidth>1</bitWidth>
          </field>
          <field>
            <name>SWIER3</name>
            <bitOffset>3</bitOffset>
            <bitWidth>1</bitWidth>
          </field>
          <field>
            <name>SWIER4</name>
            <bitOffset>4</bitOffset>
            <bitWidth>1</bitWidth>
          </field>
          <field>
            <name>SWIER5</name>
            <bitOffset>5</bitOffset>
            <bitWidth>1</bitWidth>
          </field>
          <field>
            <name>SWIER6</name>
            <bitOffset>6</bitOffset>
            <bitWidth>1</bitWidth>
          </field>
          <field>
            <name>SWIER7</name>
            <bitOffset>7</bitOffset>
            <bitWidth>1</bitWidth>
          </field>
          <field>
            <name>SWIER8</name>
            <bitOffset>8</bitOffset>
            <bitWidth>1</bitWidth>
          </field>
          <field>
            <name>SWIER9</name>
            <bitOffset>9</bitOffset>
            <bitWidth>1</bitWidth>
          </field>
          <field>
            <name>SWIER10</name>
            <bitOffset>10</bitOffset>
            <bitWidth>1</bitWidth>
          </field>
          <field>
            <name>SWIER11</name>
            <bitOffset>11</bitOffset>
            <bitWidth>1</bitWidth>
          </field>
          <field>
            <name>SWIER12</name>
            <bitOffset>12</bitOffset>
            <bitWidth>1</bitWidth>
          </field>
          <field>
            <name>SWIER13</name>
            <bitOffset>13</bitOffset>
            <bitWidth>1</bitWidth>
          </field>
          <field>
            <name>SWIER14</name>
            <bitOffset>14</bitOffset>
            <bitWidth>1</bitWidth>
          </field>
          <field>
            <name>SWIER15</name>
            <bitOffset>15</bitOffset>
            <bitWidth>1</bitWidth>
          </field>
          <field>
            <name>SWIER16</name>
            <bitOffset>16</bitOffset>
            <bitWidth>1</bitWidth>
          </field>
          <field>
            <name>SWIER17</name>
            <bitOffset>17</bitOffset>
            <bitWidth>1</bitWidth>
          </field>
          <field>
            <name>SWIER18</name>
            <bitOffset>18</bitOffset>
            <bitWidth>1</bitWidth>
          </field>
          <field>
            <name>SWIER19</name>
            <bitOffset>19</bitOffset>
            <bitWidth>1</bitWidth>
          </field>
          <field>
            <name>SWIER20</name>
            <bitOffset>20</bitOffset>
            <bitWidth>1</bitWidth>
          </field>
          <field>
            <name>SWIER21</name>
            <bitOffset>21</bitOffset>
            <bitWidth>1</bitWidth>
          </field>
          <field>
            <name>SWIER22</name>
            <bitOffset>22</bitOffset>
            <bitWidth>1</bitWidth>
          </field>
        </fields>
      </register>
      <register>
        <name>PR</name>
        <addressOffset>0x14</addressOffset>
        <size>0x20</size>
        <fields>
          <field>
            <name>PR0</name>
            <bitOffset>0</bitOffset>
            <bitWidth>1</bitWidth>
          </field>
          <field>
            <name>PR1</name>
            <bitOffset>1</bitOffset>
            <bitWidth>1</bitWidth>
          </field>
          <field>
            <name>PR2</name>
            <bitOffset>2</bitOffset>
            <bitWidth>1</bitWidth>
          </field>
          <field>
            <name>PR3</name>
            <bitOffset>3</bitOffset>
            <bitWidth>1</bitWidth>
          </field>
          <field>
            <name>PR4</name>
            <bitOffset>4</bitOffset>
            <bitWidth>1</bitWidth>
          </field>
          <field>
            <name>PR5</name>
            <bitOffset>5</bitOffset>
            <bitWidth>1</bitWidth>
          </field>
          <field>
            <name>PR6</name>
            <bitOffset>6</bitOffset>
            <bitWidth>1</bitWidth>
          </field>
          <field>
            <name>PR7</name>
            <bitOffset>7</bitOffset>
            <bitWidth>1</bitWidth>
          </field>
          <field>
            <name>PR8</name>
            <bitOffset>8</bitOffset>
            <bitWidth>1</bitWidth>
          </field>
          <field>
            <name>PR9</name>
            <bitOffset>9</bitOffset>
            <bitWidth>1</bitWidth>
          </field>
          <field>
            <name>PR10</name>
            <bitOffset>10</bitOffset>
            <bitWidth>1</bitWidth>
          </field>
          <field>
            <name>PR11</name>
            <bitOffset>11</bitOffset>
            <bitWidth>1</bitWidth>
          </field>
          <field>
            <name>PR12</name>
            <bitOffset>12</bitOffset>
            <bitWidth>1</bitWidth>
          </field>
          <field>
            <name>PR13</name>
            <bitOffset>13</bitOffset>
            <bitWidth>1</bitWidth>
          </field>
          <field>
            <name>PR14</name>
            <bitOffset>14</bitOffset>
            <bitWidth>1</bitWidth>
          </field>
          <field>
            <name>PR15</name>
            <bitOffset>15</bitOffset>
            <bitWidth>1</bitWidth>
          </field>
          <field>
            <name>PR16</name>
            <bitOffset>16</bitOffset>
            <bitWidth>1</bitWidth>
          </field>
          <field>
            <name>PR17</name>
            <bitOffset>17</bitOffset>
            <bitWidth>1</bitWidth>
          </field>
          <field>
            <name>PR18</name>
            <bitOffset>18</bitOffset>
            <bitWidth>1</bitWidth>
          </field>
          <field>
            <name>PR19</name>
            <bitOffset>19</bitOffset>
            <bitWidth>1</bitWidth>
          </field>
          <field>
            <name>PR20</name>
            <bitOffset>20</bitOffset>
            <bitWidth>1</bitWidth>
          </field>
          <field>
            <name>PR21</name>
            <bitOffset>21</bitOffset>
            <bitWidth>1</bitWidth>
          </field>
          <field>
            <name>PR22</name>
            <bitOffset>22</bitOffset>
            <bitWidth>1</bitWidth>
          </field>
        </fields>
      </register>
    </peripheral>
    <peripheral>
      <name>TIM9</name>
      <baseAddress>0x40014000</baseAddress>
      <register>
        <name>CR1</name>
        <addressOffset>0x0</addressOffset>
        <size>0x20</size>
        <fields>
          <field>
            <name>CEN</name>
            <bitOffset>0</bitOffset>
            <bitWidth>1</bitWidth>
          </field>
          <field>
            <name>UDIS</name>
            <bitOffset>1</bitOffset>
            <bitWidth>1</bitWidth>
          </field>
          <field>
            <name>URS</name>
            <bitOffset>2</bitOffset>
            <bitWidth>1</bitWidth>
          </field>
          <field>
            <name>OPM</name>
            <bitOffset>3</bitOffset>
            <bitWidth>1</bitWidth>
          </field>
          <field>
            <name>DIR</name>
            <bitOffset>4</bitOffset>
            <bitWidth>1</bitWidth>
          </field>
          <field>
            <name>CMS</name>
            <bitOffset>5</bitOffset>
            <bitWidth>2</bitWidth>
          </field>
          <field>
            <name>ARPE</name>
            <bitOffset>7</bitOffset>
            <bitWidth>1</bitWidth>
          </field>
          <field>
            <name>CKD</name>
            <bitOffset>8</bitOffset>
            <bitWidth>2</bitWidth>
          </field>
        </fields>
      </register>
      <register>
        <name>CR2</name>
        <addressOffset>0x4</addressOffset>
        <size>0x20</size>
        <fields>
          <field>
            <name>CCPC</name>
            <bitOffset>0</bitOffset>
            <bitWidth>1</bitWidth>
          </field>
          <field>
            <name>CCUS</name>
            <bitOffset>2</bitOffset>
            <bitWidth>1</bitWidth>
          </field>
          <field>
            <name>CCDS</name>
            <bitOffset>3</bitOffset>
            <bitWidth>1</bitWidth>
          </field>
          <field>
            <name>MMS</name>
            <bitOffset>4</bitOffset>
            <bitWidth>3</bitWidth>
          </field>
          <field>
            <name>TI1S</name>
            <bitOffset>7</bitOffset>
            <bitWidth>1</bitWidth>
          </field>
          <field>
            <name>OIS1</name>
            <bitOffset>8</bitOffset>
            <bitWidth>1</bitWidth>
          </field>
          <field>
            <name>OIS1N</name>
            <bitOffset>9</bitOffset>
            <bitWidth>1</bitWidth>
          </field>
          <field>
            <name>OIS2</name>
            <bitOffset>10</bitOffset>
            <bitWidth>1</bitWidth>
          </field>
          <field>
            <name>OIS2N</name>
            <bitOffset>11</bitOffset>
            <bitWidth>1</bitWidth>
          </field>
          <field>
            <name>OIS3</name>
            <bitOffset>12</bitOffset>
            <bitWidth>1</bitWidth>
          </field>
          <field>
            <name>OIS3N</name>
            <bitOffset>13</bitOffset>
            <bitWidth>1</bitWidth>
          </field>
          <field>
            <name>OIS4</name>
            <bitOffset>14</bitOffset>
            <bitWidth>1</bitWidth>
          </field>
        </fields>
      </register>
      <register>
        <name>SMCR</name>
        <addressOffset>0x8</addressOffset>
        <size>0x20</size>
        <fields>
          <field>
            <name>SMS</name>
            <bitOffset>0</bitOffset>
            <bitWidth>3</bitWidth>
          </field>
          <field>
            <name>TS</name>
            <bitOffset>4</bitOffset>
            <bitWidth>3</bitWidth>
          </field>
          <field>
            <name>MSM</name>
            <bitOffset>7</bitOffset>
            <bitWidth>1</bitWidth>
          </field>
          <field>
            <name>ETF</name>
            <bitOffset>8</bitOffset>
            <bitWidth>4</bitWidth>
          </field>
          <field>
            <name>ETPS</name>
            <bitOffset>12</bitOffset>
            <bitWidth>2</bitWidth>
          </field>
          <field>
            <name>ECE</name>
            <bitOffset>14</bitOffset>
            <bitWidth>1</bitWidth>
          </field>
          <field>
            <name>ETP</name>
            <bitOffset>15</bitOffset>
            <bitWidth>1</bitWidth>
          </field>
        </fields>
      </register>
      <register>
        <name>DIER</name>
        <addressOffset>0xc</addressOffset>
        <size>0x20</size>
        <fields>
          <field>
            <name>UIE</name>
            <bitOffset>0</bitOffset>
            <bitWidth>1</bitWidth>
          </field>
          <field>
            <name>CC1IE</name>
            <bitOffset>1</bitOffset>
            <bitWidth>1</bitWidth>
          </field>
          <field>
            <name>CC2IE</name>
            <bitOffset>2</bitOffset>
            <bitWidth>1</bitWidth>
          </field>
          <field>
            <name>CC3IE</name>
            <bitOffset>3</bitOffset>
            <bitWidth>1</bitWidth>
          </field>
          <field>
            <name>CC4IE</name>
            <bitOffset>4</bitOffset>
            <bitWidth>1</bitWidth>
          </field>
          <field>
            <name>COMIE</name>
            <bitOffset>5</bitOffset>
            <bitWidth>1</bitWidth>
          </field>
          <field>
            <name>TIE</name>
            <bitOffset>6</bitOffset>
            <bitWidth>1</bitWidth>
          </field>
          <field>
            <name>BIE</name>
            <bitOffset>7</bitOffset>
            <bitWidth>1</bitWidth>
          </field>
          <field>
            <name>UDE</name>
            <bitOffset>8</bitOffset>
            <bitWidth>1</bitWidth>
          </field>
          <field>
            <name>CC1DE</name>
            <bitOffset>9</bitOffset>
            <bitWidth>1</bitWidth>
          </field>
          <field>
            <name>CC2DE</name>
            <bitOffset>10</bitOffset>
            <bitWidth>1</bitWidth>
          </field>
          <field>
            <name>CC3DE</name>
            <bitOffset>11</bitOffset>
            <bitWidth>1</bitWidth>
          </field>
          <field>
            <name>CC4DE</name>
            <bitOffset>12</bitOffset>
            <bitWidth>1</bitWidth>
          </field>
          <field>
            <name>COMDE</name>
            <bitOffset>13</bitOffset>
            <bitWidth>1</bitWidth>
          </field>
          <field>
            <name>TDE</name>
            <bitOffset>14</bitOffset>
            <bitWidth>1</bitWidth>
          </field>
        </fields>
      </register>
      <register>
        <name>SR</name>
        <addressOffset>0x10</addressOffset>
        <size>0x20</size>
        <fields>
          <field>
            <name>UIF</name>
            <bitOffset>0</bitOffset>
            <bitWidth>1</bitWidth>
          </field>
          <field>
            <name>CC1IF</name>
            <bitOffset>1</bitOffset>
            <bitWidth>1</bitWidth>
          </field>
          <field>
            <name>CC2IF</name>
            <bitOffset>2</bitOffset>
            <bitWidth>1</bitWidth>
          </field>
          <field>
            <name>CC3IF</name>
            <bitOffset>3</bitOffset>
            <bitWidth>1</bitWidth>
          </field>
          <field>
            <name>CC4IF</name>
            <bitOffset>4</bitOffset>
            <bitWidth>1</bitWidth>
          </field>
          <field>
            <name>COMIF</name>
            <bitOffset>5</bitOffset>
            <bitWidth>1</bitWidth>
          </field>
          <field>
            <name>TIF</name>
            <bitOffset>6</bitOffset>
            <bitWidth>1</bitWidth>
          </field>
          <field>
            <name>BIF</name>
            <bitOffset>7</bitOffset>
            <bitWidth>1</bitWidth>
          </field>
          <field>
            <name>CC1OF</name>
            <bitOffset>9</bitOffset>
            <bitWidth>1</bitWidth>
          </field>
          <field>
            <name>CC2OF</name>
            <bitOffset>10</bitOffset>
            <bitWidth>1</bitWidth>
          </field>
          <field>
            <name>CC3OF</name>
            <bitOffset>11</bitOffset>
            <bitWidth>1</bitWidth>
          </field>
          <field>
            <name>CC4OF</name>
            <bitOffset>12</bitOffset>
            <bitWidth>1</bitWidth>
          </field>
        </fields>
      </register>
      <register>
        <name>EGR</name>
        <addressOffset>0x14</addressOffset>
        <size>0x20</size>
        <fields>
          <field>
            <name>UG</name>
            <bitOffset>0</bitOffset>
            <bitWidth>1</bitWidth>
          </field>
          <field>
            <name>CC1G</name>
            <bitOffset>1</bitOffset>
            <bitWidth>1</bitWidth>
          </field>
          <field>
            <name>CC2G</name>
            <bitOffset>2</bitOffset>
            <bitWidth>1</bitWidth>
          </field>
          <field>
            <name>CC3G</name>
            <bitOffset>3</bitOffset>
            <bitWidth>1</bitWidth>
          </field>
          <field>
            <name>CC4G</name>
            <bitOffset>4</bitOffset>
            <bitWidth>1</bitWidth>
          </field>
          <field>
            <name>COMG</name>
            <bitOffset>5</bitOffset>
            <bitWidth>1</bitWidth>
          </field>
          <field>
            <name>TG</name>
            <bitOffset>6</bitOffset>
            <bitWidth>1</bitWidth>
          </field>
          <field>
            <name>BG</name>
            <bitOffset>7</bitOffset>
            <bitWidth>1</bitWidth>
          </field>
        </fields>
      </register>
      <register>
        <name>CCMR1</name>
        <addressOffset>0x18</addressOffset>
        <size>0x20</size>
        <fields>
          <field>
            <name>CC1S</name>
            <bitOffset>0</bitOffset>
            <bitWidth>2</bitWidth>
          </field>
          <field>
            <name>OC1FE</name>
            <bitOffset>2</bitOffset>
            <bitWidth>1</bitWidth>
          </field>
          <field>
            <name>OC1PE</name>
            <bitOffset>3</bitOffset>
            <bitWidth>1</bitWidth>
          </field>
          <field>
            <name>OC1M</name>
            <bitOffset>4</bitOffset>
            <bitWidth>3</bitWidth>
          </field>
          <field>
            <name>OC1CE</name>
            <bitOffset>7</bitOffset>
            <bitWidth>1</bitWidth>
          </field>
          <field>
            <name>CC2S</name>
            <bitOffset>8</bitOffset>
            <bitWidth>2</bitWidth>
          </field>
          <field>
            <name>OC2FE</name>
            <bitOffset>10</bitOffset>
            <bitWidth>1</bitWidth>
          </field>
          <field>
            <name>OC2PE</name>
            <bitOffset>11</bitOffset>
            <bitWidth>1</bitWidth>
          </field>
          <field>
            <name>OC2M</name>
            <bitOffset>12</bitOffset>
            <bitWidth>3</bitWidth>
          </field>
          <field>
            <name>OC2CE</name>
            <bitOffset>15</bitOffset>
            <bitWidth>1</bitWidth>
          </field>
        </fields>
      </register>
      <register>
        <name>CCMR2</name>
        <addressOffset>0x1c</addressOffset>
        <size>0x20</size>
        <fields>
          <field>
            <name>CC3S</name>
            <bitOffset>0</bitOffset>
            <bitWidth>2</bitWidth>
          </field>
          <field>
            <name>OC3FE</name>
            <bitOffset>2</bitOffset>
            <bitWidth>1</bitWidth>
          </field>
          <field>
            <name>OC3PE</name>
            <bitOffset>3</bitOffset>
            <bitWidth>1</bitWidth>
          </field>
          <field>
            <name>OC3M</name>
            <bitOffset>4</bitOffset>
            <bitWidth>3</bitWidth>
          </field>
          <field>
            <name>OC3CE</name>
            <bitOffset>7</bitOffset>
            <bitWidth>1</bitWidth>
          </field>
          <field>
            <name>CC4S</name>
            <bitOffset>8</bitOffset>
            <bitWidth>2</bitWidth>
          </field>
          <field>
            <name>OC4FE</name>
            <bitOffset>10</bitOffset>
            <bitWidth>1</bitWidth>
          </field>
          <field>
            <name>OC4PE</name>
            <bitOffset>11</bitOffset>
            <bitWidth>1</bitWidth>
          </field>
          <field>
            <name>OC4M</name>
            <bitOffset>12</bitOffset>
            <bitWidth>3</bitWidth>
          </field>
          <field>
            <name>OC4CE</name>
            <bitOffset>15</bitOffset>
            <bitWidth>1</bitWidth>
          </field>
        </fields>
      </register>
      <register>
        <name>CCER</name>
        <addressOffset>0x20</addressOffset>
        <size>0x20</size>
        <fields>
          <field>
            <name>CC1E</name>
            <bitOffset>0</bitOffset>
            <bitWidth>1</bitWidth>
          </field>
          <field>
            <name>CC1P</name>
            <bitOffset>1</bitOffset>
            <bitWidth>1</bitWidth>
          </field>
          <field>
            <name>CC1NE</name>
            <bitOffset>2</bitOffset>
            <bitWidth>1</bitWidth>
          </field>
          <field>
            <name>CC1NP</name>
            <bitOffset>3</bitOffset>
            <bitWidth>1</bitWidth>
          </field>
          <field>
            <name>CC2E</name>
            <bitOffset>4</bitOffset>
            <bitWidth>1</bitWidth>
          </field>
          <field>
            <name>CC2P</name>
            <bitOffset>5</bitOffset>
            <bitWidth>1</bitWidth>
          </field>
          <field>
            <name>CC2NE</name>
            <bitOffset>6</bitOffset>
            <bitWidth>1</bitWidth>
          </field>
          <field>
            <name>CC2NP</name>
            <bitOffset>7</bitOffset>
            <bitWidth>1</bitWidth>
          </field>
          <field>
            <name>CC3E</name>
            <bitOffset>8</bitOffset>
            <bitWidth>1</bitWidth>
          </field>
          <field>
            <name>CC3P</name>
            <bitOffset>9</bitOffset>
            <bitWidth>1</bitWidth>
          </field>
          <field>
            <name>CC3NE</name>
            <bitOffset>10</bitOffset>
            <bitWidth>1</bitWidth>
          </field>
          <field>
            <name>CC3NP</name>
            <bitOffset>11</bitOffset>
            <bitWidth>1</bitWidth>
          </field>
          <field>
            <name>CC4E</name>
            <bitOffset>12</bitOffset>
            <bitWidth>1</bitWidth>
          </field>
          <field>
            <name>CC4P</name>
            <bitOffset>13</bitOffset>
            <bitWidth>1</bitWidth>
          </field>
          <field>
            <name>CC4NP</name>
            <bitOffset>15</bitOffset>
            <bitWidth>1</bitWidth>
          </field>
        </fields>
      </register>
      <register>
        <name>CNT</name>
        <addressOffset>0x24</addressOffset>
        <size>0x20</size>
        <fields>
          <field>
            <name>CNT</name>
            <bitOffset>0</bitOffset>
            <bitWidth>32</bitWidth>
          </field>
        </fields>
      </register>
      <register>
        <name>PSC</name>
        <addressOffset>0x28</addressOffset>
        <size>0x20</size>
        <fields>
          <field>
            <name>PSC</name>
            <bitOffset>0</bitOffset>
            <bitWidth>16</bitWidth>
          </field>
        </fields>
      </register>
      <register>
        <name>ARR</name>
        <addressOffset>0x2c</addressOffset>
        <size>0x20</size>
        <fields>
          <field>
            <name>ARR</name>
            <bitOffset>0</bitOffset>
            <bitWidth>32</bitWidth>
          </field>
        </fields>
      </register>
      <register>
        <name>RCR</name>
        <addressOffset>0x30</addressOffset>
        <size>0x20</size>
        <fields>
          <field>
            <name>REP</name>
            <bitOffset>0</bitOffset>
            <bitWidth>8</bitWidth>
          </field>
        </fields>
      </register>
      <register>
        <name>CCR1</name>
        <addressOffset>0x34</addressOffset>
        <size>0x20</size>
        <fields>
          <field>
            <name>CCR1</name>
            <bitOffset>0</bitOffset>
            <bitWidth>16</bitWidth>
          </field>
        </fields>
      </register>
      <register>
        <name>CCR2</name>
        <addressOffset>0x38</addressOffset>
        <size>0x20</size>
        <fields>
          <field>
            <name>CCR2</name>
            <bitOffset>0</bitOffset>
            <bitWidth>16</bitWidth>
          </field>
        </fields>
      </register>
      <register>
        <name>CCR3</name>
        <addressOffset>0x3c</addressOffset>
        <size>0x20</size>
        <fields>
          <field>
            <name>CCR3</name>
            <bitOffset>0</bitOffset>
            <bitWidth>16</bitWidth>
          </field>
        </fields>
      </register>
      <register>
        <name>CCR4</name>
        <addressOffset>0x40</addressOffset>
        <size>0x20</size>
        <fields>
          <field>
            <name>CCR4</name>
            <bitOffset>0</bitOffset>
            <bitWidth>16</bitWidth>
          </field>
        </fields>
      </register>
      <register>
        <name>BDTR</name>
        <addressOffset>0x44</addressOffset>
        <size>0x20</size>
        <fields>
          <field>
            <name>DTG</name>
            <bitOffset>0</bitOffset>
            <bitWidth>8</bitWidth>
          </field>
          <field>
            <name>LOCK</name>
            <bitOffset>8</bitOffset>
            <bitWidth>2</bitWidth>
          </field>
          <field>
            <name>OSSI</name>
            <bitOffset>10</bitOffset>
            <bitWidth>1</bitWidth>
          </field>
          <field>
            <name>OSSR</name>
            <bitOffset>11</bitOffset>
            <bitWidth>1</bitWidth>
          </field>
          <field>
            <name>BKE</name>
            <bitOffset>12</bitOffset>
            <bitWidth>1</bitWidth>
          </field>
          <field>
            <name>BKP</name>
            <bitOffset>13</bitOffset>
            <bitWidth>1</bitWidth>
          </field>
          <field>
            <name>AOE</name>
            <bitOffset>14</bitOffset>
            <bitWidth>1</bitWidth>
          </field>
          <field>
            <name>MOE</name>
            <bitOffset>15</bitOffset>
            <bitWidth>1</bitWidth>
          </field>
        </fields>
      </register>
      <register>
        <name>DCR</name>
        <addressOffset>0x48</addressOffset>
        <size>0x20</size>
        <fields>
          <field>
            <name>DBA</name>
            <bitOffset>0</bitOffset>
            <bitWidth>5</bitWidth>
          </field>
          <field>
            <name>DBL</name>
            <bitOffset>8</bitOffset>
            <bitWidth>5</bitWidth>
          </field>
        </fields>
      </register>
      <register>
        <name>DMAR</name>
        <addressOffset>0x4c</addressOffset>
        <size>0x20</size>
        <fields>
          <field>
            <name>DMAB</name>
            <bitOffset>0</bitOffset>
            <bitWidth>16</bitWidth>
          </field>
        </fields>
      </register>
      <register>
        <name>OR</name>
        <addressOffset>0x50</addressOffset>
        <size>0x20</size>
        <fields>
          <field>
            <name>TI1_RMP</name>
            <bitOffset>0</bitOffset>
            <bitWidth>2</bitWidth>
          </field>
          <field>
            <name>TI4_RMP</name>
            <bitOffset>6</bitOffset>
            <bitWidth>2</bitWidth>
          </field>
          <field>
            <name>ITR1_RMP</name>
            <bitOffset>10</bitOffset>
            <bitWidth>2</bitWidth>
          </field>
        </fields>
      </register>
    </peripheral>
    <peripheral>
      <name>TIM10</name>
      <baseAddress>0x40014400</baseAddress>
      <register>
        <name>CR1</name>
        <addressOffset>0x0</addressOffset>
        <size>0x20</size>
        <fields>
          <field>
            <name>CEN</name>
            <bitOffset>0</bitOffset>
            <bitWidth>1</bitWidth>
          </field>
          <field>
            <name>UDIS</name>
            <bitOffset>1</bitOffset>
            <bitWidth>1</bitWidth>
          </field>
          <field>
            <name>URS</name>
            <bitOffset>2</bitOffset>
            <bitWidth>1</bitWidth>
          </field>
          <field>
            <name>OPM</name>
            <bitOffset>3</bitOffset>
            <bitWidth>1</bitWidth>
          </field>
          <field>
            <name>DIR</name>
            <bitOffset>4</bitOffset>
            <bitWidth>1</bitWidth>
          </field>
          <field>
            <name>CMS</name>
            <bitOffset>5</bitOffset>
            <bitWidth>2</bitWidth>
          </field>
          <field>
            <name>ARPE</name>
            <bitOffset>7</bitOffset>
            <bitWidth>1</bitWidth>
          </field>
          <field>
            <name>CKD</name>
            <bitOffset>8</bitOffset>
            <bitWidth>2</bitWidth>
          </field>
        </fields>
      </register>
      <register>
        <name>CR2</name>
        <addressOffset>0x4</addressOffset>
        <size>0x20</size>
        <fields>
          <field>
            <name>CCPC</name>
            <bitOffset>0</bitOffset>
            <bitWidth>1</bitWidth>
          </field>
          <field>
            <name>CCUS</name>
            <bitOffset>2</bitOffset>
            <bitWidth>1</bitWidth>
          </field>
          <field>
            <name>CCDS</name>
            <bitOffset>3</bitOffset>
            <bitWidth>1</bitWidth>
          </field>
          <field>
            <name>MMS</name>
            <bitOffset>4</bitOffset>
            <bitWidth>3</bitWidth>
          </field>
          <field>
            <name>TI1S</name>
            <bitOffset>7</bitOffset>
            <bitWidth>1</bitWidth>
          </field>
          <field>
            <name>OIS1</name>
            <bitOffset>8</bitOffset>
            <bitWidth>1</bitWidth>
          </field>
          <field>
            <name>OIS1N</name>
            <bitOffset>9</bitOffset>
            <bitWidth>1</bitWidth>
          </field>
          <field>
            <name>OIS2</name>
            <bitOffset>10</bitOffset>
            <bitWidth>1</bitWidth>
          </field>
          <field>
            <name>OIS2N</name>
            <bitOffset>11</bitOffset>
            <bitWidth>1</bitWidth>
          </field>
          <field>
            <name>OIS3</name>
            <bitOffset>12</bitOffset>
            <bitWidth>1</bitWidth>
          </field>
          <field>
            <name>OIS3N</name>
            <bitOffset>13</bitOffset>
            <bitWidth>1</bitWidth>
          </field>
          <field>
            <name>OIS4</name>
            <bitOffset>14</bitOffset>
            <bitWidth>1</bitWidth>
          </field>
        </fields>
      </register>
      <register>
        <name>SMCR</name>
        <addressOffset>0x8</addressOffset>
        <size>0x20</size>
        <fields>
          <field>
            <name>SMS</name>
            <bitOffset>0</bitOffset>
            <bitWidth>3</bitWidth>
          </field>
          <field>
            <name>TS</name>
            <bitOffset>4</bitOffset>
            <bitWidth>3</bitWidth>
          </field>
          <field>
            <name>MSM</name>
            <bitOffset>7</bitOffset>
            <bitWidth>1</bitWidth>
          </field>
          <field>
            <name>ETF</name>
            <bitOffset>8</bitOffset>
            <bitWidth>4</bitWidth>
          </field>
          <field>
            <name>ETPS</name>
            <bitOffset>12</bitOffset>
            <bitWidth>2</bitWidth>
          </field>
          <field>
            <name>ECE</name>
            <bitOffset>14</bitOffset>
            <bitWidth>1</bitWidth>
          </field>
          <field>
            <name>ETP</name>
            <bitOffset>15</bitOffset>
            <bitWidth>1</bitWidth>
          </field>
        </fields>
      </register>
      <register>
        <name>DIER</name>
        <addressOffset>0xc</addressOffset>
        <size>0x20</size>
        <fields>
          <field>
            <name>UIE</name>
            <bitOffset>0</bitOffset>
            <bitWidth>1</bitWidth>
          </field>
          <field>
            <name>CC1IE</name>
            <bitOffset>1</bitOffset>
            <bitWidth>1</bitWidth>
          </field>
          <field>
            <name>CC2IE</name>
            <bitOffset>2</bitOffset>
            <bitWidth>1</bitWidth>
          </field>
          <field>
            <name>CC3IE</name>
            <bitOffset>3</bitOffset>
            <bitWidth>1</bitWidth>
          </field>
          <field>
            <name>CC4IE</name>
            <bitOffset>4</bitOffset>
            <bitWidth>1</bitWidth>
          </field>
          <field>
            <name>COMIE</name>
            <bitOffset>5</bitOffset>
            <bitWidth>1</bitWidth>
          </field>
          <field>
            <name>TIE</name>
            <bitOffset>6</bitOffset>
            <bitWidth>1</bitWidth>
          </field>
          <field>
            <name>BIE</name>
            <bitOffset>7</bitOffset>
            <bitWidth>1</bitWidth>
          </field>
          <field>
            <name>UDE</name>
            <bitOffset>8</bitOffset>
            <bitWidth>1</bitWidth>
          </field>
          <field>
            <name>CC1DE</name>
            <bitOffset>9</bitOffset>
            <bitWidth>1</bitWidth>
          </field>
          <field>
            <name>CC2DE</name>
            <bitOffset>10</bitOffset>
            <bitWidth>1</bitWidth>
          </field>
          <field>
            <name>CC3DE</name>
            <bitOffset>11</bitOffset>
            <bitWidth>1</bitWidth>
          </field>
          <field>
            <name>CC4DE</name>
            <bitOffset>12</bitOffset>
            <bitWidth>1</bitWidth>
          </field>
          <field>
            <name>COMDE</name>
            <bitOffset>13</bitOffset>
            <bitWidth>1</bitWidth>
          </field>
          <field>
            <name>TDE</name>
            <bitOffset>14</bitOffset>
            <bitWidth>1</bitWidth>
          </field>
        </fields>
      </register>
      <register>
        <name>SR</name>
        <addressOffset>0x10</addressOffset>
        <size>0x20</size>
        <fields>
          <field>
            <name>UIF</name>
            <bitOffset>0</bitOffset>
            <bitWidth>1</bitWidth>
          </field>
          <field>
            <name>CC1IF</name>
            <bitOffset>1</bitOffset>
            <bitWidth>1</bitWidth>
          </field>
          <field>
            <name>CC2IF</name>
            <bitOffset>2</bitOffset>
            <bitWidth>1</bitWidth>
          </field>
          <field>
            <name>CC3IF</name>
            <bitOffset>3</bitOffset>
            <bitWidth>1</bitWidth>
          </field>
          <field>
            <name>CC4IF</name>
            <bitOffset>4</bitOffset>
            <bitWidth>1</bitWidth>
          </field>
          <field>
            <name>COMIF</name>
            <bitOffset>5</bitOffset>
            <bitWidth>1</bitWidth>
          </field>
          <field>
            <name>TIF</name>
            <bitOffset>6</bitOffset>
            <bitWidth>1</bitWidth>
          </field>
          <field>
            <name>BIF</name>
            <bitOffset>7</bitOffset>
            <bitWidth>1</bitWidth>
          </field>
          <field>
            <name>CC1OF</name>
            <bitOffset>9</bitOffset>
            <bitWidth>1</bitWidth>
          </field>
          <field>
            <name>CC2OF</name>
            <bitOffset>10</bitOffset>
            <bitWidth>1</bitWidth>
          </field>
          <field>
            <name>CC3OF</name>
            <bitOffset>11</bitOffset>
            <bitWidth>1</bitWidth>
          </field>
          <field>
            <name>CC4OF</name>
            <bitOffset>12</bitOffset>
            <bitWidth>1</bitWidth>
          </field>
        </fields>
      </register>
      <register>
        <name>EGR</name>
        <addressOffset>0x14</addressOffset>
        <size>0x20</size>
        <fields>
          <field>
            <name>UG</name>
            <bitOffset>0</bitOffset>
            <bitWidth>1</bitWidth>
          </field>
          <field>
            <name>CC1G</name>
            <bitOffset>1</bitOffset>
            <bitWidth>1</bitWidth>
          </field>
          <field>
            <name>CC2G</name>
            <bitOffset>2</bitOffset>
            <bitWidth>1</bitWidth>
          </field>
          <field>
            <name>CC3G</name>
            <bitOffset>3</bitOffset>
            <bitWidth>1</bitWidth>
          </field>
          <field>
            <name>CC4G</name>
            <bitOffset>4</bitOffset>
            <bitWidth>1</bitWidth>
          </field>
          <field>
            <name>COMG</name>
            <bitOffset>5</bitOffset>
            <bitWidth>1</bitWidth>
          </field>
          <field>
            <name>TG</name>
            <bitOffset>6</bitOffset>
            <bitWidth>1</bitWidth>
          </field>
          <field>
            <name>BG</name>
            <bitOffset>7</bitOffset>
            <bitWidth>1</bitWidth>
          </field>
        </fields>
      </register>
      <register>
        <name>CCMR1</name>
        <addressOffset>0x18</addressOffset>
        <size>0x20</size>
        <fields>
          <field>
            <name>CC1S</name>
            <bitOffset>0</bitOffset>
            <bitWidth>2</bitWidth>
          </field>
          <field>
            <name>OC1FE</name>
            <bitOffset>2</bitOffset>
            <bitWidth>1</bitWidth>
          </field>
          <field>
            <name>OC1PE</name>
            <bitOffset>3</bitOffset>
            <bitWidth>1</bitWidth>
          </field>
          <field>
            <name>OC1M</name>
            <bitOffset>4</bitOffset>
            <bitWidth>3</bitWidth>
          </field>
          <field>
            <name>OC1CE</name>
            <bitOffset>7</bitOffset>
            <bitWidth>1</bitWidth>
          </field>
          <field>
            <name>CC2S</name>
            <bitOffset>8</bitOffset>
            <bitWidth>2</bitWidth>
          </field>
          <field>
            <name>OC2FE</name>
            <bitOffset>10</bitOffset>
            <bitWidth>1</bitWidth>
          </field>
          <field>
            <name>OC2PE</name>
            <bitOffset>11</bitOffset>
            <bitWidth>1</bitWidth>
          </field>
          <field>
            <name>OC2M</name>
            <bitOffset>12</bitOffset>
            <bitWidth>3</bitWidth>
          </field>
          <field>
            <name>OC2CE</name>
            <bitOffset>15</bitOffset>
            <bitWidth>1</bitWidth>
          </field>
        </fields>
      </register>
      <register>
        <name>CCMR2</name>
        <addressOffset>0x1c</addressOffset>
        <size>0x20</size>
        <fields>
          <field>
            <name>CC3S</name>
            <bitOffset>0</bitOffset>
            <bitWidth>2</bitWidth>
          </field>
          <field>
            <name>OC3FE</name>
            <bitOffset>2</bitOffset>
            <bitWidth>1</bitWidth>
          </field>
          <field>
            <name>OC3PE</name>
            <bitOffset>3</bitOffset>
            <bitWidth>1</bitWidth>
          </field>
          <field>
            <name>OC3M</name>
            <bitOffset>4</bitOffset>
            <bitWidth>3</bitWidth>
          </field>
          <field>
            <name>OC3CE</name>
            <bitOffset>7</bitOffset>
            <bitWidth>1</bitWidth>
          </field>
          <field>
            <name>CC4S</name>
            <bitOffset>8</bitOffset>
            <bitWidth>2</bitWidth>
          </field>
          <field>
            <name>OC4FE</name>
            <bitOffset>10</bitOffset>
            <bitWidth>1</bitWidth>
          </field>
          <field>
            <name>OC4PE</name>
            <bitOffset>11</bitOffset>
            <bitWidth>1</bitWidth>
          </field>
          <field>
            <name>OC4M</name>
            <bitOffset>12</bitOffset>
            <bitWidth>3</bitWidth>
          </field>
          <field>
            <name>OC4CE</name>
            <bitOffset>15</bitOffset>
            <bitWidth>1</bitWidth>
          </field>
        </fields>
      </register>
      <register>
        <name>CCER</name>
        <addressOffset>0x20</addressOffset>
        <size>0x20</size>
        <fields>
          <field>
            <name>CC1E</name>
            <bitOffset>0</bitOffset>
            <bitWidth>1</bitWidth>
          </field>
          <field>
            <name>CC1P</name>
            <bitOffset>1</bitOffset>
            <bitWidth>1</bitWidth>
          </field>
          <field>
            <name>CC1NE</name>
            <bitOffset>2</bitOffset>
            <bitWidth>1</bitWidth>
          </field>
          <field>
            <name>CC1NP</name>
            <bitOffset>3</bitOffset>
            <bitWidth>1</bitWidth>
          </field>
          <field>
            <name>CC2E</name>
            <bitOffset>4</bitOffset>
            <bitWidth>1</bitWidth>
          </field>
          <field>
            <name>CC2P</name>
            <bitOffset>5</bitOffset>
            <bitWidth>1</bitWidth>
          </field>
          <field>
            <name>CC2NE</name>
            <bitOffset>6</bitOffset>
            <bitWidth>1</bitWidth>
          </field>
          <field>
            <name>CC2NP</name>
            <bitOffset>7</bitOffset>
            <bitWidth>1</bitWidth>
          </field>
          <field>
            <name>CC3E</name>
            <bitOffset>8</bitOffset>
            <bitWidth>1</bitWidth>
          </field>
          <field>
            <name>CC3P</name>
            <bitOffset>9</bitOffset>
            <bitWidth>1</bitWidth>
          </field>
          <field>
            <name>CC3NE</name>
            <bitOffset>10</bitOffset>
            <bitWidth>1</bitWidth>
          </field>
          <field>
            <name>CC3NP</name>
            <bitOffset>11</bitOffset>
            <bitWidth>1</bitWidth>
          </field>
          <field>
            <name>CC4E</name>
            <bitOffset>12</bitOffset>
            <bitWidth>1</bitWidth>
          </field>
          <field>
            <name>CC4P</name>
            <bitOffset>13</bitOffset>
            <bitWidth>1</bitWidth>
          </field>
          <field>
            <name>CC4NP</name>
            <bitOffset>15</bitOffset>
            <bitWidth>1</bitWidth>
          </field>
        </fields>
      </register>
      <register>
        <name>CNT</name>
        <addressOffset>0x24</addressOffset>
        <size>0x20</size>
        <fields>
          <field>
            <name>CNT</name>
            <bitOffset>0</bitOffset>
            <bitWidth>32</bitWidth>
          </field>
        </fields>
      </register>
      <register>
        <name>PSC</name>
        <addressOffset>0x28</addressOffset>
        <size>0x20</size>
        <fields>
          <field>
            <name>PSC</name>
            <bitOffset>0</bitOffset>
            <bitWidth>16</bitWidth>
          </field>
        </fields>
      </register>
      <register>
        <name>ARR</name>
        <addressOffset>0x2c</addressOffset>
        <size>0x20</size>
        <fields>
          <field>
            <name>ARR</name>
            <bitOffset>0</bitOffset>
            <bitWidth>32</bitWidth>
          </field>
        </fields>
      </register>
      <register>
        <name>RCR</name>
        <addressOffset>0x30</addressOffset>
        <size>0x20</size>
        <fields>
          <field>
            <name>REP</name>
            <bitOffset>0</bitOffset>
            <bitWidth>8</bitWidth>
          </field>
        </fields>
      </register>
      <register>
        <name>CCR1</name>
        <addressOffset>0x34</addressOffset>
        <size>0x20</size>
        <fields>
          <field>
            <name>CCR1</name>
            <bitOffset>0</bitOffset>
            <bitWidth>16</bitWidth>
          </field>
        </fields>
      </register>
      <register>
        <name>CCR2</name>
        <addressOffset>0x38</addressOffset>
        <size>0x20</size>
        <fields>
          <field>
            <name>CCR2</name>
            <bitOffset>0</bitOffset>
            <bitWidth>16</bitWidth>
          </field>
        </fields>
      </register>
      <register>
        <name>CCR3</name>
        <addressOffset>0x3c</addressOffset>
        <size>0x20</size>
        <fields>
          <field>
            <name>CCR3</name>
            <bitOffset>0</bitOffset>
            <bitWidth>16</bitWidth>
          </field>
        </fields>
      </register>
      <register>
        <name>CCR4</name>
        <addressOffset>0x40</addressOffset>
        <size>0x20</size>
        <fields>
          <field>
            <name>CCR4</name>
            <bitOffset>0</bitOffset>
            <bitWidth>16</bitWidth>
          </field>
        </fields>
      </register>
      <register>
        <name>BDTR</name>
        <addressOffset>0x44</addressOffset>
        <size>0x20</size>
        <fields>
          <field>
            <name>DTG</name>
            <bitOffset>0</bitOffset>
            <bitWidth>8</bitWidth>
          </field>
          <field>
            <name>LOCK</name>
            <bitOffset>8</bitOffset>
            <bitWidth>2</bitWidth>
          </field>
          <field>
            <name>OSSI</name>
            <bitOffset>10</bitOffset>
            <bitWidth>1</bitWidth>
          </field>
          <field>
            <name>OSSR</name>
            <bitOffset>11</bitOffset>
            <bitWidth>1</bitWidth>
          </field>
          <field>
            <name>BKE</name>
            <bitOffset>12</bitOffset>
            <bitWidth>1</bitWidth>
          </field>
          <field>
            <name>BKP</name>
            <bitOffset>13</bitOffset>
            <bitWidth>1</bitWidth>
          </field>
          <field>
            <name>AOE</name>
            <bitOffset>14</bitOffset>
            <bitWidth>1</bitWidth>
          </field>
          <field>
            <name>MOE</name>
            <bitOffset>15</bitOffset>
            <bitWidth>1</bitWidth>
          </field>
        </fields>
      </register>
      <register>
        <name>DCR</name>
        <addressOffset>0x48</addressOffset>
        <size>0x20</size>
        <fields>
          <field>
            <name>DBA</name>
            <bitOffset>0</bitOffset>
            <bitWidth>5</bitWidth>
          </field>
          <field>
            <name>DBL</name>
            <bitOffset>8</bitOffset>
            <bitWidth>5</bitWidth>
          </field>
        </fields>
      </register>
      <register>
        <name>DMAR</name>
        <addressOffset>0x4c</addressOffset>
        <size>0x20</size>
        <fields>
          <field>
            <name>DMAB</name>
            <bitOffset>0</bitOffset>
            <bitWidth>16</bitWidth>
          </field>
        </fields>
      </register>
      <register>
        <name>OR</name>
        <addressOffset>0x50</addressOffset>
        <size>0x20</size>
        <fields>
          <field>
            <name>TI1_RMP</name>
            <bitOffset>0</bitOffset>
            <bitWidth>2</bitWidth>
          </field>
          <field>
            <name>TI4_RMP</name>
            <bitOffset>6</bitOffset>
            <bitWidth>2</bitWidth>
          </field>
          <field>
            <name>ITR1_RMP</name>
            <bitOffset>10</bitOffset>
            <bitWidth>2</bitWidth>
          </field>
        </fields>
      </register>
    </peripheral>
    <peripheral>
      <name>TIM11</name>
      <baseAddress>0x40014800</baseAddress>
      <register>
        <name>CR1</name>
        <addressOffset>0x0</addressOffset>
        <size>0x20</size>
        <fields>
          <field>
            <name>CEN</name>
            <bitOffset>0</bitOffset>
            <bitWidth>1</bitWidth>
          </field>
          <field>
            <name>UDIS</name>
            <bitOffset>1</bitOffset>
            <bitWidth>1</bitWidth>
          </field>
          <field>
            <name>URS</name>
            <bitOffset>2</bitOffset>
            <bitWidth>1</bitWidth>
          </field>
          <field>
            <name>OPM</name>
            <bitOffset>3</bitOffset>
            <bitWidth>1</bitWidth>
          </field>
          <field>
            <name>DIR</name>
            <bitOffset>4</bitOffset>
            <bitWidth>1</bitWidth>
          </field>
          <field>
            <name>CMS</name>
            <bitOffset>5</bitOffset>
            <bitWidth>2</bitWidth>
          </field>
          <field>
            <name>ARPE</name>
            <bitOffset>7</bitOffset>
            <bitWidth>1</bitWidth>
          </field>
          <field>
            <name>CKD</name>
            <bitOffset>8</bitOffset>
            <bitWidth>2</bitWidth>
          </field>
        </fields>
      </register>
      <register>
        <name>CR2</name>
        <addressOffset>0x4</addressOffset>
        <size>0x20</size>
        <fields>
          <field>
            <name>CCPC</name>
            <bitOffset>0</bitOffset>
            <bitWidth>1</bitWidth>
          </field>
          <field>
            <name>CCUS</name>
            <bitOffset>2</bitOffset>
            <bitWidth>1</bitWidth>
          </field>
          <field>
            <name>CCDS</name>
            <bitOffset>3</bitOffset>
            <bitWidth>1</bitWidth>
          </field>
          <field>
            <name>MMS</name>
            <bitOffset>4</bitOffset>
            <bitWidth>3</bitWidth>
          </field>
          <field>
            <name>TI1S</name>
            <bitOffset>7</bitOffset>
            <bitWidth>1</bitWidth>
          </field>
          <field>
            <name>OIS1</name>
            <bitOffset>8</bitOffset>
            <bitWidth>1</bitWidth>
          </field>
          <field>
            <name>OIS1N</name>
            <bitOffset>9</bitOffset>
            <bitWidth>1</bitWidth>
          </field>
          <field>
            <name>OIS2</name>
            <bitOffset>10</bitOffset>
            <bitWidth>1</bitWidth>
          </field>
          <field>
            <name>OIS2N</name>
            <bitOffset>11</bitOffset>
            <bitWidth>1</bitWidth>
          </field>
          <field>
            <name>OIS3</name>
            <bitOffset>12</bitOffset>
            <bitWidth>1</bitWidth>
          </field>
          <field>
            <name>OIS3N</name>
            <bitOffset>13</bitOffset>
            <bitWidth>1</bitWidth>
          </field>
          <field>
            <name>OIS4</name>
            <bitOffset>14</bitOffset>
            <bitWidth>1</bitWidth>
          </field>
        </fields>
      </register>
      <register>
        <name>SMCR</name>
        <addressOffset>0x8</addressOffset>
        <size>0x20</size>
        <fields>
          <field>
            <name>SMS</name>
            <bitOffset>0</bitOffset>
            <bitWidth>3</bitWidth>
          </field>
          <field>
            <name>TS</name>
            <bitOffset>4</bitOffset>
            <bitWidth>3</bitWidth>
          </field>
          <field>
            <name>MSM</name>
            <bitOffset>7</bitOffset>
            <bitWidth>1</bitWidth>
          </field>
          <field>
            <name>ETF</name>
            <bitOffset>8</bitOffset>
            <bitWidth>4</bitWidth>
          </field>
          <field>
            <name>ETPS</name>
            <bitOffset>12</bitOffset>
            <bitWidth>2</bitWidth>
          </field>
          <field>
            <name>ECE</name>
            <bitOffset>14</bitOffset>
            <bitWidth>1</bitWidth>
          </field>
          <field>
            <name>ETP</name>
            <bitOffset>15</bitOffset>
            <bitWidth>1</bitWidth>
          </field>
        </fields>
      </register>
      <register>
        <name>DIER</name>
        <addressOffset>0xc</addressOffset>
        <size>0x20</size>
        <fields>
          <field>
            <name>UIE</name>
            <bitOffset>0</bitOffset>
            <bitWidth>1</bitWidth>
          </field>
          <field>
            <name>CC1IE</name>
            <bitOffset>1</bitOffset>
            <bitWidth>1</bitWidth>
          </field>
          <field>
            <name>CC2IE</name>
            <bitOffset>2</bitOffset>
            <bitWidth>1</bitWidth>
          </field>
          <field>
            <name>CC3IE</name>
            <bitOffset>3</bitOffset>
            <bitWidth>1</bitWidth>
          </field>
          <field>
            <name>CC4IE</name>
            <bitOffset>4</bitOffset>
            <bitWidth>1</bitWidth>
          </field>
          <field>
            <name>COMIE</name>
            <bitOffset>5</bitOffset>
            <bitWidth>1</bitWidth>
          </field>
          <field>
            <name>TIE</name>
            <bitOffset>6</bitOffset>
            <bitWidth>1</bitWidth>
          </field>
          <field>
            <name>BIE</name>
            <bitOffset>7</bitOffset>
            <bitWidth>1</bitWidth>
          </field>
          <field>
            <name>UDE</name>
            <bitOffset>8</bitOffset>
            <bitWidth>1</bitWidth>
          </field>
          <field>
            <name>CC1DE</name>
            <bitOffset>9</bitOffset>
            <bitWidth>1</bitWidth>
          </field>
          <field>
            <name>CC2DE</name>
            <bitOffset>10</bitOffset>
            <bitWidth>1</bitWidth>
          </field>
          <field>
            <name>CC3DE</name>
            <bitOffset>11</bitOffset>
            <bitWidth>1</bitWidth>
          </field>
          <field>
            <name>CC4DE</name>
            <bitOffset>12</bitOffset>
            <bitWidth>1</bitWidth>
          </field>
          <field>
            <name>COMDE</name>
            <bitOffset>13</bitOffset>
            <bitWidth>1</bitWidth>
          </field>
          <field>
            <name>TDE</name>
            <bitOffset>14</bitOffset>
            <bitWidth>1</bitWidth>
          </field>
        </fields>
      </register>
      <register>
        <name>SR</name>
        <addressOffset>0x10</addressOffset>
        <size>0x20</size>
        <fields>
          <field>
            <name>UIF</name>
            <bitOffset>0</bitOffset>
            <bitWidth>1</bitWidth>
          </field>
          <field>
            <name>CC1IF</name>
            <bitOffset>1</bitOffset>
            <bitWidth>1</bitWidth>
          </field>
          <field>
            <name>CC2IF</name>
            <bitOffset>2</bitOffset>
            <bitWidth>1</bitWidth>
          </field>
          <field>
            <name>CC3IF</name>
            <bitOffset>3</bitOffset>
            <bitWidth>1</bitWidth>
          </field>
          <field>
            <name>CC4IF</name>
            <bitOffset>4</bitOffset>
            <bitWidth>1</bitWidth>
          </field>
          <field>
            <name>COMIF</name>
            <bitOffset>5</bitOffset>
            <bitWidth>1</bitWidth>
          </field>
          <field>
            <name>TIF</name>
            <bitOffset>6</bitOffset>
            <bitWidth>1</bitWidth>
          </field>
          <field>
            <name>BIF</name>
            <bitOffset>7</bitOffset>
            <bitWidth>1</bitWidth>
          </field>
          <field>
            <name>CC1OF</name>
            <bitOffset>9</bitOffset>
            <bitWidth>1</bitWidth>
          </field>
          <field>
            <name>CC2OF</name>
            <bitOffset>10</bitOffset>
            <bitWidth>1</bitWidth>
          </field>
          <field>
            <name>CC3OF</name>
            <bitOffset>11</bitOffset>
            <bitWidth>1</bitWidth>
          </field>
          <field>
            <name>CC4OF</name>
            <bitOffset>12</bitOffset>
            <bitWidth>1</bitWidth>
          </field>
        </fields>
      </register>
      <register>
        <name>EGR</name>
        <addressOffset>0x14</addressOffset>
        <size>0x20</size>
        <fields>
          <field>
            <name>UG</name>
            <bitOffset>0</bitOffset>
            <bitWidth>1</bitWidth>
          </field>
          <field>
            <name>CC1G</name>
            <bitOffset>1</bitOffset>
            <bitWidth>1</bitWidth>
          </field>
          <field>
            <name>CC2G</name>
            <bitOffset>2</bitOffset>
            <bitWidth>1</bitWidth>
          </field>
          <field>
            <name>CC3G</name>
            <bitOffset>3</bitOffset>
            <bitWidth>1</bitWidth>
          </field>
          <field>
            <name>CC4G</name>
            <bitOffset>4</bitOffset>
            <bitWidth>1</bitWidth>
          </field>
          <field>
            <name>COMG</name>
            <bitOffset>5</bitOffset>
            <bitWidth>1</bitWidth>
          </field>
          <field>
            <name>TG</name>
            <bitOffset>6</bitOffset>
            <bitWidth>1</bitWidth>
          </field>
          <field>
            <name>BG</name>
            <bitOffset>7</bitOffset>
            <bitWidth>1</bitWidth>
          </field>
        </fields>
      </register>
      <register>
        <name>CCMR1</name>
        <addressOffset>0x18</addressOffset>
        <size>0x20</size>
        <fields>
          <field>
            <name>CC1S</name>
            <bitOffset>0</bitOffset>
            <bitWidth>2</bitWidth>
          </field>
          <field>
            <name>OC1FE</name>
            <bitOffset>2</bitOffset>
            <bitWidth>1</bitWidth>
          </field>
          <field>
            <name>OC1PE</name>
            <bitOffset>3</bitOffset>
            <bitWidth>1</bitWidth>
          </field>
          <field>
            <name>OC1M</name>
            <bitOffset>4</bitOffset>
            <bitWidth>3</bitWidth>
          </field>
          <field>
            <name>OC1CE</name>
            <bitOffset>7</bitOffset>
            <bitWidth>1</bitWidth>
          </field>
          <field>
            <name>CC2S</name>
            <bitOffset>8</bitOffset>
            <bitWidth>2</bitWidth>
          </field>
          <field>
            <name>OC2FE</name>
            <bitOffset>10</bitOffset>
            <bitWidth>1</bitWidth>
          </field>
          <field>
            <name>OC2PE</name>
            <bitOffset>11</bitOffset>
            <bitWidth>1</bitWidth>
          </field>
          <field>
            <name>OC2M</name>
            <bitOffset>12</bitOffset>
            <bitWidth>3</bitWidth>
          </field>
          <field>
            <name>OC2CE</name>
            <bitOffset>15</bitOffset>
            <bitWidth>1</bitWidth>
          </field>
        </fields>
      </register>
      <register>
        <name>CCMR2</name>
        <addressOffset>0x1c</addressOffset>
        <size>0x20</size>
        <fields>
          <field>
            <name>CC3S</name>
            <bitOffset>0</bitOffset>
            <bitWidth>2</bitWidth>
          </field>
          <field>
            <name>OC3FE</name>
            <bitOffset>2</bitOffset>
            <bitWidth>1</bitWidth>
          </field>
          <field>
            <name>OC3PE</name>
            <bitOffset>3</bitOffset>
            <bitWidth>1</bitWidth>
          </field>
          <field>
            <name>OC3M</name>
            <bitOffset>4</bitOffset>
            <bitWidth>3</bitWidth>
          </field>
          <field>
            <name>OC3CE</name>
            <bitOffset>7</bitOffset>
            <bitWidth>1</bitWidth>
          </field>
          <field>
            <name>CC4S</name>
            <bitOffset>8</bitOffset>
            <bitWidth>2</bitWidth>
          </field>
          <field>
            <name>OC4FE</name>
            <bitOffset>10</bitOffset>
            <bitWidth>1</bitWidth>
          </field>
          <field>
            <name>OC4PE</name>
            <bitOffset>11</bitOffset>
            <bitWidth>1</bitWidth>
          </field>
          <field>
            <name>OC4M</name>
            <bitOffset>12</bitOffset>
            <bitWidth>3</bitWidth>
          </field>
          <field>
            <name>OC4CE</name>
            <bitOffset>15</bitOffset>
            <bitWidth>1</bitWidth>
          </field>
        </fields>
      </register>
      <register>
        <name>CCER</name>
        <addressOffset>0x20</addressOffset>
        <size>0x20</size>
        <fields>
          <field>
            <name>CC1E</name>
            <bitOffset>0</bitOffset>
            <bitWidth>1</bitWidth>
          </field>
          <field>
            <name>CC1P</name>
            <bitOffset>1</bitOffset>
            <bitWidth>1</bitWidth>
          </field>
          <field>
            <name>CC1NE</name>
            <bitOffset>2</bitOffset>
            <bitWidth>1</bitWidth>
          </field>
          <field>
            <name>CC1NP</name>
            <bitOffset>3</bitOffset>
            <bitWidth>1</bitWidth>
          </field>
          <field>
            <name>CC2E</name>
            <bitOffset>4</bitOffset>
            <bitWidth>1</bitWidth>
          </field>
          <field>
            <name>CC2P</name>
            <bitOffset>5</bitOffset>
            <bitWidth>1</bitWidth>
          </field>
          <field>
            <name>CC2NE</name>
            <bitOffset>6</bitOffset>
            <bitWidth>1</bitWidth>
          </field>
          <field>
            <name>CC2NP</name>
            <bitOffset>7</bitOffset>
            <bitWidth>1</bitWidth>
          </field>
          <field>
            <name>CC3E</name>
            <bitOffset>8</bitOffset>
            <bitWidth>1</bitWidth>
          </field>
          <field>
            <name>CC3P</name>
            <bitOffset>9</bitOffset>
            <bitWidth>1</bitWidth>
          </field>
          <field>
            <name>CC3NE</name>
            <bitOffset>10</bitOffset>
            <bitWidth>1</bitWidth>
          </field>
          <field>
            <name>CC3NP</name>
            <bitOffset>11</bitOffset>
            <bitWidth>1</bitWidth>
          </field>
          <field>
            <name>CC4E</name>
            <bitOffset>12</bitOffset>
            <bitWidth>1</bitWidth>
          </field>
          <field>
            <name>CC4P</name>
            <bitOffset>13</bitOffset>
            <bitWidth>1</bitWidth>
          </field>
          <field>
            <name>CC4NP</name>
            <bitOffset>15</bitOffset>
            <bitWidth>1</bitWidth>
          </field>
        </fields>
      </register>
      <register>
        <name>CNT</name>
        <addressOffset>0x24</addressOffset>
        <size>0x20</size>
        <fields>
          <field>
            <name>CNT</name>
            <bitOffset>0</bitOffset>
            <bitWidth>32</bitWidth>
          </field>
        </fields>
      </register>
      <register>
        <name>PSC</name>
        <addressOffset>0x28</addressOffset>
        <size>0x20</size>
        <fields>
          <field>
            <name>PSC</name>
            <bitOffset>0</bitOffset>
            <bitWidth>16</bitWidth>
          </field>
        </fields>
      </register>
      <register>
        <name>ARR</name>
        <addressOffset>0x2c</addressOffset>
        <size>0x20</size>
        <fields>
          <field>
            <name>ARR</name>
            <bitOffset>0</bitOffset>
            <bitWidth>32</bitWidth>
          </field>
        </fields>
      </register>
      <register>
        <name>RCR</name>
        <addressOffset>0x30</addressOffset>
        <size>0x20</size>
        <fields>
          <field>
            <name>REP</name>
            <bitOffset>0</bitOffset>
            <bitWidth>8</bitWidth>
          </field>
        </fields>
      </register>
      <register>
        <name>CCR1</name>
        <addressOffset>0x34</addressOffset>
        <size>0x20</size>
        <fields>
          <field>
            <name>CCR1</name>
            <bitOffset>0</bitOffset>
            <bitWidth>16</bitWidth>
          </field>
        </fields>
      </register>
      <register>
        <name>CCR2</name>
        <addressOffset>0x38</addressOffset>
        <size>0x20</size>
        <fields>
          <field>
            <name>CCR2</name>
            <bitOffset>0</bitOffset>
            <bitWidth>16</bitWidth>
          </field>
        </fields>
      </register>
      <register>
        <name>CCR3</name>
        <addressOffset>0x3c</addressOffset>
        <size>0x20</size>
        <fields>
          <field>
            <name>CCR3</name>
            <bitOffset>0</bitOffset>
            <bitWidth>16</bitWidth>
          </field>
        </fields>
      </register>
      <register>
        <name>CCR4</name>
        <addressOffset>0x40</addressOffset>
        <size>0x20</size>
        <fields>
          <field>
            <name>CCR4</name>
            <bitOffset>0</bitOffset>
            <bitWidth>16</bitWidth>
          </field>
        </fields>
      </register>
      <register>
        <name>BDTR</name>
        <addressOffset>0x44</addressOffset>
        <size>0x20</size>
        <fields>
          <field>
            <name>DTG</name>
            <bitOffset>0</bitOffset>
            <bitWidth>8</bitWidth>
          </field>
          <field>
            <name>LOCK</name>
            <bitOffset>8</bitOffset>
            <bitWidth>2</bitWidth>
          </field>
          <field>
            <name>OSSI</name>
            <bitOffset>10</bitOffset>
            <bitWidth>1</bitWidth>
          </field>
          <field>
            <name>OSSR</name>
            <bitOffset>11</bitOffset>
            <bitWidth>1</bitWidth>
          </field>
          <field>
            <name>BKE</name>
            <bitOffset>12</bitOffset>
            <bitWidth>1</bitWidth>
          </field>
          <field>
            <name>BKP</name>
            <bitOffset>13</bitOffset>
            <bitWidth>1</bitWidth>
          </field>
          <field>
            <name>AOE</name>
            <bitOffset>14</bitOffset>
            <bitWidth>1</bitWidth>
          </field>
          <field>
            <name>MOE</name>
            <bitOffset>15</bitOffset>
            <bitWidth>1</bitWidth>
          </field>
        </fields>
      </register>
      <register>
        <name>DCR</name>
        <addressOffset>0x48</addressOffset>
        <size>0x20</size>
        <fields>
          <field>
            <name>DBA</name>
            <bitOffset>0</bitOffset>
            <bitWidth>5</bitWidth>
          </field>
          <field>
            <name>DBL</name>
            <bitOffset>8</bitOffset>
            <bitWidth>5</bitWidth>
          </field>
        </fields>
      </register>
      <register>
        <name>DMAR</name>
        <addressOffset>0x4c</addressOffset>
        <size>0x20</size>
        <fields>
          <field>
            <name>DMAB</name>
            <bitOffset>0</bitOffset>
            <bitWidth>16</bitWidth>
          </field>
        </fields>
      </register>
      <register>
        <name>OR</name>
        <addressOffset>0x50</addressOffset>
        <size>0x20</size>
        <fields>
          <field>
            <name>TI1_RMP</name>
            <bitOffset>0</bitOffset>
            <bitWidth>2</bitWidth>
          </field>
          <field>
            <name>TI4_RMP</name>
            <bitOffset>6</bitOffset>
            <bitWidth>2</bitWidth>
          </field>
          <field>
            <name>ITR1_RMP</name>
            <bitOffset>10</bitOffset>
            <bitWidth>2</bitWidth>
          </field>
        </fields>
      </register>
    </peripheral>
    <peripheral>
      <name>SPI5</name>
      <baseAddress>0x40015000</baseAddress>
      <register>
        <name>CR1</name>
        <addressOffset>0x0</addressOffset>
        <size>0x20</size>
        <fields>
          <field>
            <name>CPHA</name>
            <bitOffset>0</bitOffset>
            <bitWidth>1</bitWidth>
          </field>
          <field>
            <name>CPOL</name>
            <bitOffset>1</bitOffset>
            <bitWidth>1</bitWidth>
          </field>
          <field>
            <name>MSTR</name>
            <bitOffset>2</bitOffset>
            <bitWidth>1</bitWidth>
          </field>
          <field>
            <name>BR</name>
            <bitOffset>3</bitOffset>
            <bitWidth>3</bitWidth>
          </field>
          <field>
            <name>SPE</name>
            <bitOffset>6</bitOffset>
            <bitWidth>1</bitWidth>
          </field>
          <field>
            <name>LSBFIRST</name>
            <bitOffset>7</bitOffset>
            <bitWidth>1</bitWidth>
          </field>
          <field>
            <name>SSI</name>
            <bitOffset>8</bitOffset>
            <bitWidth>1</bitWidth>
          </field>
          <field>
            <name>SSM</name>
            <bitOffset>9</bitOffset>
            <bitWidth>1</bitWidth>
          </field>
          <field>
            <name>RXONLY</name>
            <bitOffset>10</bitOffset>
            <bitWidth>1</bitWidth>
          </field>
          <field>
            <name>DFF</name>
            <bitOffset>11</bitOffset>
            <bitWidth>1</bitWidth>
          </field>
          <field>
            <name>CRCNEXT</name>
            <bitOffset>12</bitOffset>
            <bitWidth>1</bitWidth>
          </field>
          <field>
            <name>CRCEN</name>
            <bitOffset>13</bitOffset>
            <bitWidth>1</bitWidth>
          </field>
          <field>
            <name>BIDIOE</name>
            <bitOffset>14</bitOffset>
            <bitWidth>1</bitWidth>
          </field>
          <field>
            <name>BIDIMODE</name>
            <bitOffset>15</bitOffset>
            <bitWidth>1</bitWidth>
          </field>
        </fields>
      </register>
      <register>
        <name>CR2</name>
        <addressOffset>0x4</addressOffset>
        <size>0x20</size>
        <fields>
          <field>
            <name>RXDMAEN</name>
            <bitOffset>0</bitOffset>
            <bitWidth>1</bitWidth>
          </field>
          <field>
            <name>TXDMAEN</name>
            <bitOffset>1</bitOffset>
            <bitWidth>1</bitWidth>
          </field>
          <field>
            <name>SSOE</name>
            <bitOffset>2</bitOffset>
            <bitWidth>1</bitWidth>
          </field>
          <field>
            <name>FRF</name>
            <bitOffset>4</bitOffset>
            <bitWidth>1</bitWidth>
          </field>
          <field>
            <name>ERRIE</name>
            <bitOffset>5</bitOffset>
            <bitWidth>1</bitWidth>
          </field>
          <field>
            <name>RXNEIE</name>
            <bitOffset>6</bitOffset>
            <bitWidth>1</bitWidth>
          </field>
          <field>
            <name>TXEIE</name>
            <bitOffset>7</bitOffset>
            <bitWidth>1</bitWidth>
          </field>
        </fields>
      </register>
      <register>
        <name>SR</name>
        <addressOffset>0x8</addressOffset>
        <size>0x20</size>
        <fields>
          <field>
            <name>RXNE</name>
            <bitOffset>0</bitOffset>
            <bitWidth>1</bitWidth>
          </field>
          <field>
            <name>TXE</name>
            <bitOffset>1</bitOffset>
            <bitWidth>1</bitWidth>
          </field>
          <field>
            <name>CHSIDE</name>
            <bitOffset>2</bitOffset>
            <bitWidth>1</bitWidth>
          </field>
          <field>
            <name>UDR</name>
            <bitOffset>3</bitOffset>
            <bitWidth>1</bitWidth>
          </field>
          <field>
            <name>CRCERR</name>
            <bitOffset>4</bitOffset>
            <bitWidth>1</bitWidth>
          </field>
          <field>
            <name>MODF</name>
            <bitOffset>5</bitOffset>
            <bitWidth>1</bitWidth>
          </field>
          <field>
            <name>OVR</name>
            <bitOffset>6</bitOffset>
            <bitWidth>1</bitWidth>
          </field>
          <field>
            <name>BSY</name>
            <bitOffset>7</bitOffset>
            <bitWidth>1</bitWidth>
          </field>
          <field>
            <name>FRE</name>
            <bitOffset>8</bitOffset>
            <bitWidth>1</bitWidth>
          </field>
        </fields>
      </register>
      <register>
        <name>DR</name>
        <addressOffset>0xc</addressOffset>
        <size>0x20</size>
        <fields>
          <field>
            <name>DR</name>
            <bitOffset>0</bitOffset>
            <bitWidth>16</bitWidth>
          </field>
        </fields>
      </register>
      <register>
        <name>CRCPR</name>
        <addressOffset>0x10</addressOffset>
        <size>0x20</size>
        <fields>
          <field>
            <name>CRCPOLY</name>
            <bitOffset>0</bitOffset>
            <bitWidth>16</bitWidth>
          </field>
        </fields>
      </register>
      <register>
        <name>RXCRCR</name>
        <addressOffset>0x14</addressOffset>
        <size>0x20</size>
        <fields>
          <field>
            <name>RXCRC</name>
            <bitOffset>0</bitOffset>
            <bitWidth>16</bitWidth>
          </field>
        </fields>
      </register>
      <register>
        <name>TXCRCR</name>
        <addressOffset>0x18</addressOffset>
        <size>0x20</size>
        <fields>
          <field>
            <name>TXCRC</name>
            <bitOffset>0</bitOffset>
            <bitWidth>16</bitWidth>
          </field>
        </fields>
      </register>
      <register>
        <name>I2SCFGR</name>
        <addressOffset>0x1c</addressOffset>
        <size>0x20</size>
        <fields>
          <field>
            <name>CHLEN</name>
            <bitOffset>0</bitOffset>
            <bitWidth>1</bitWidth>
          </field>
          <field>
            <name>DATLEN</name>
            <bitOffset>1</bitOffset>
            <bitWidth>2</bitWidth>
          </field>
          <field>
            <name>CKPOL</name>
            <bitOffset>3</bitOffset>
            <bitWidth>1</bitWidth>
          </field>
          <field>
            <name>I2SSTD</name>
            <bitOffset>4</bitOffset>
            <bitWidth>2</bitWidth>
          </field>
          <field>
            <name>PCMSYNC</name>
            <bitOffset>7</bitOffset>
            <bitWidth>1</bitWidth>
          </field>
          <field>
            <name>I2SCFG</name>
            <bitOffset>8</bitOffset>
            <bitWidth>2</bitWidth>
          </field>
          <field>
            <name>I2SE</name>
            <bitOffset>10</bitOffset>
            <bitWidth>1</bitWidth>
          </field>
          <field>
            <name>I2SMOD</name>
            <bitOffset>11</bitOffset>
            <bitWidth>1</bitWidth>
          </field>
        </fields>
      </register>
      <register>
        <name>I2SPR</name>
        <addressOffset>0x20</addressOffset>
        <size>0x20</size>
        <fields>
          <field>
            <name>I2SDIV</name>
            <bitOffset>0</bitOffset>
            <bitWidth>8</bitWidth>
          </field>
          <field>
            <name>ODD</name>
            <bitOffset>8</bitOffset>
            <bitWidth>1</bitWidth>
          </field>
          <field>
            <name>MCKOE</name>
            <bitOffset>9</bitOffset>
            <bitWidth>1</bitWidth>
          </field>
        </fields>
      </register>
    </peripheral>
    <peripheral>
      <name>SPI6</name>
      <baseAddress>0x40015400</baseAddress>
      <register>
        <name>CR1</name>
        <addressOffset>0x0</addressOffset>
        <size>0x20</size>
        <fields>
          <field>
            <name>CPHA</name>
            <bitOffset>0</bitOffset>
            <bitWidth>1</bitWidth>
          </field>
          <field>
            <name>CPOL</name>
            <bitOffset>1</bitOffset>
            <bitWidth>1</bitWidth>
          </field>
          <field>
            <name>MSTR</name>
            <bitOffset>2</bitOffset>
            <bitWidth>1</bitWidth>
          </field>
          <field>
            <name>BR</name>
            <bitOffset>3</bitOffset>
            <bitWidth>3</bitWidth>
          </field>
          <field>
            <name>SPE</name>
            <bitOffset>6</bitOffset>
            <bitWidth>1</bitWidth>
          </field>
          <field>
            <name>LSBFIRST</name>
            <bitOffset>7</bitOffset>
            <bitWidth>1</bitWidth>
          </field>
          <field>
            <name>SSI</name>
            <bitOffset>8</bitOffset>
            <bitWidth>1</bitWidth>
          </field>
          <field>
            <name>SSM</name>
            <bitOffset>9</bitOffset>
            <bitWidth>1</bitWidth>
          </field>
          <field>
            <name>RXONLY</name>
            <bitOffset>10</bitOffset>
            <bitWidth>1</bitWidth>
          </field>
          <field>
            <name>DFF</name>
            <bitOffset>11</bitOffset>
            <bitWidth>1</bitWidth>
          </field>
          <field>
            <name>CRCNEXT</name>
            <bitOffset>12</bitOffset>
            <bitWidth>1</bitWidth>
          </field>
          <field>
            <name>CRCEN</name>
            <bitOffset>13</bitOffset>
            <bitWidth>1</bitWidth>
          </field>
          <field>
            <name>BIDIOE</name>
            <bitOffset>14</bitOffset>
            <bitWidth>1</bitWidth>
          </field>
          <field>
            <name>BIDIMODE</name>
            <bitOffset>15</bitOffset>
            <bitWidth>1</bitWidth>
          </field>
        </fields>
      </register>
      <register>
        <name>CR2</name>
        <addressOffset>0x4</addressOffset>
        <size>0x20</size>
        <fields>
          <field>
            <name>RXDMAEN</name>
            <bitOffset>0</bitOffset>
            <bitWidth>1</bitWidth>
          </field>
          <field>
            <name>TXDMAEN</name>
            <bitOffset>1</bitOffset>
            <bitWidth>1</bitWidth>
          </field>
          <field>
            <name>SSOE</name>
            <bitOffset>2</bitOffset>
            <bitWidth>1</bitWidth>
          </field>
          <field>
            <name>FRF</name>
            <bitOffset>4</bitOffset>
            <bitWidth>1</bitWidth>
          </field>
          <field>
            <name>ERRIE</name>
            <bitOffset>5</bitOffset>
            <bitWidth>1</bitWidth>
          </field>
          <field>
            <name>RXNEIE</name>
            <bitOffset>6</bitOffset>
            <bitWidth>1</bitWidth>
          </field>
          <field>
            <name>TXEIE</name>
            <bitOffset>7</bitOffset>
            <bitWidth>1</bitWidth>
          </field>
        </fields>
      </register>
      <register>
        <name>SR</name>
        <addressOffset>0x8</addressOffset>
        <size>0x20</size>
        <fields>
          <field>
            <name>RXNE</name>
            <bitOffset>0</bitOffset>
            <bitWidth>1</bitWidth>
          </field>
          <field>
            <name>TXE</name>
            <bitOffset>1</bitOffset>
            <bitWidth>1</bitWidth>
          </field>
          <field>
            <name>CHSIDE</name>
            <bitOffset>2</bitOffset>
            <bitWidth>1</bitWidth>
          </field>
          <field>
            <name>UDR</name>
            <bitOffset>3</bitOffset>
            <bitWidth>1</bitWidth>
          </field>
          <field>
            <name>CRCERR</name>
            <bitOffset>4</bitOffset>
            <bitWidth>1</bitWidth>
          </field>
          <field>
            <name>MODF</name>
            <bitOffset>5</bitOffset>
            <bitWidth>1</bitWidth>
          </field>
          <field>
            <name>OVR</name>
            <bitOffset>6</bitOffset>
            <bitWidth>1</bitWidth>
          </field>
          <field>
            <name>BSY</name>
            <bitOffset>7</bitOffset>
            <bitWidth>1</bitWidth>
          </field>
          <field>
            <name>FRE</name>
            <bitOffset>8</bitOffset>
            <bitWidth>1</bitWidth>
          </field>
        </fields>
      </register>
      <register>
        <name>DR</name>
        <addressOffset>0xc</addressOffset>
        <size>0x20</size>
        <fields>
          <field>
            <name>DR</name>
            <bitOffset>0</bitOffset>
            <bitWidth>16</bitWidth>
          </field>
        </fields>
      </register>
      <register>
        <name>CRCPR</name>
        <addressOffset>0x10</addressOffset>
        <size>0x20</size>
        <fields>
          <field>
            <name>CRCPOLY</name>
            <bitOffset>0</bitOffset>
            <bitWidth>16</bitWidth>
          </field>
        </fields>
      </register>
      <register>
        <name>RXCRCR</name>
        <addressOffset>0x14</addressOffset>
        <size>0x20</size>
        <fields>
          <field>
            <name>RXCRC</name>
            <bitOffset>0</bitOffset>
            <bitWidth>16</bitWidth>
          </field>
        </fields>
      </register>
      <register>
        <name>TXCRCR</name>
        <addressOffset>0x18</addressOffset>
        <size>0x20</size>
        <fields>
          <field>
            <name>TXCRC</name>
            <bitOffset>0</bitOffset>
            <bitWidth>16</bitWidth>
          </field>
        </fields>
      </register>
      <register>
        <name>I2SCFGR</name>
        <addressOffset>0x1c</addressOffset>
        <size>0x20</size>
        <fields>
          <field>
            <name>CHLEN</name>
            <bitOffset>0</bitOffset>
            <bitWidth>1</bitWidth>
          </field>
          <field>
            <name>DATLEN</name>
            <bitOffset>1</bitOffset>
            <bitWidth>2</bitWidth>
          </field>
          <field>
            <name>CKPOL</name>
            <bitOffset>3</bitOffset>
            <bitWidth>1</bitWidth>
          </field>
          <field>
            <name>I2SSTD</name>
            <bitOffset>4</bitOffset>
            <bitWidth>2</bitWidth>
          </field>
          <field>
            <name>PCMSYNC</name>
            <bitOffset>7</bitOffset>
            <bitWidth>1</bitWidth>
          </field>
          <field>
            <name>I2SCFG</name>
            <bitOffset>8</bitOffset>
            <bitWidth>2</bitWidth>
          </field>
          <field>
            <name>I2SE</name>
            <bitOffset>10</bitOffset>
            <bitWidth>1</bitWidth>
          </field>
          <field>
            <name>I2SMOD</name>
            <bitOffset>11</bitOffset>
            <bitWidth>1</bitWidth>
          </field>
        </fields>
      </register>
      <register>
        <name>I2SPR</name>
        <addressOffset>0x20</addressOffset>
        <size>0x20</size>
        <fields>
          <field>
            <name>I2SDIV</name>
            <bitOffset>0</bitOffset>
            <bitWidth>8</bitWidth>
          </field>
          <field>
            <name>ODD</name>
            <bitOffset>8</bitOffset>
            <bitWidth>1</bitWidth>
          </field>
          <field>
            <name>MCKOE</name>
            <bitOffset>9</bitOffset>
            <bitWidth>1</bitWidth>
          </field>
        </fields>
      </register>
    </peripheral>
    <peripheral>
      <name>SAI1</name>
      <baseAddress>0x40015800</baseAddress>
      <register>
        <name>GCR</name>
        <addressOffset>0x0</addressOffset>
        <size>0x20</size>
        <fields>
          <field>
            <name>SYNCIN</name>
            <bitOffset>0</bitOffset>
            <bitWidth>2</bitWidth>
          </field>
          <field>
            <name>SYNCOUT</name>
            <bitOffset>4</bitOffset>
            <bitWidth>2</bitWidth>
          </field>
        </fields>
      </register>
      <register>
        <name>CR1A</name>
        <addressOffset>0x4</addressOffset>
        <size>0x20</size>
      </register>
      <register>
        <name>CR2A</name>
        <addressOffset>0x8</addressOffset>
        <size>0x20</size>
      </register>
      <register>
        <name>FRCRA</name>
        <addressOffset>0x10</addressOffset>
        <size>0x20</size>
      </register>
      <register>
        <name>SLOTRA</name>
        <addressOffset>0x1c</addressOffset>
        <size>0x20</size>
      </register>
      <register>
        <name>CR1B</name>
        <addressOffset>0x24</addressOffset>
        <size>0x20</size>
      </register>
      <register>
        <name>CR2B</name>
        <addressOffset>0x28</addressOffset>
        <size>0x20</size>
      </register>
      <register>
        <name>IMRA</name>
        <addressOffset>0x2c</addressOffset>
        <size>0x20</size>
      </register>
      <register>
        <name>FRCRB</name>
        <addressOffset>0x30</addressOffset>
        <size>0x20</size>
      </register>
      <register>
        <name>SLOTRB</name>
        <addressOffset>0x3c</addressOffset>
        <size>0x20</size>
      </register>
      <register>
        <name>SRA</name>
        <addressOffset>0x40</addressOffset>
        <size>0x20</size>
      </register>
      <register>
        <name>IMRB</name>
        <addressOffset>0x4c</addressOffset>
        <size>0x20</size>
      </register>
      <register>
        <name>CLRFRA</name>
        <addressOffset>0x58</addressOffset>
        <size>0x20</size>
      </register>
      <register>
        <name>SRB</name>
        <addressOffset>0x60</addressOffset>
        <size>0x20</size>
      </register>
      <register>
        <name>DRA</name>
        <addressOffset>0x74</addressOffset>
        <size>0x20</size>
      </register>
      <register>
        <name>CLRFRB</name>
        <addressOffset>0x78</addressOffset>
        <size>0x20</size>
      </register>
      <register>
        <name>DRB</name>
        <addressOffset>0x94</addressOffset>
        <size>0x20</size>
      </register>
    </peripheral>
    <peripheral>
      <name>GPIOA</name>
      <baseAddress>0x40020000</baseAddress>
      <register>
        <name>MODER</name>
        <addressOffset>0x0</addressOffset>
        <size>0x20</size>
        <fields>
          <field>
            <name>MODER0</name>
            <bitOffset>0</bitOffset>
            <bitWidth>2</bitWidth>
          </field>
          <field>
            <name>MODER1</name>
            <bitOffset>2</bitOffset>
            <bitWidth>2</bitWidth>
          </field>
          <field>
            <name>MODER2</name>
            <bitOffset>4</bitOffset>
            <bitWidth>2</bitWidth>
          </field>
          <field>
            <name>MODER3</name>
            <bitOffset>6</bitOffset>
            <bitWidth>2</bitWidth>
          </field>
          <field>
            <name>MODER4</name>
            <bitOffset>8</bitOffset>
            <bitWidth>2</bitWidth>
          </field>
          <field>
            <name>MODER5</name>
            <bitOffset>10</bitOffset>
            <bitWidth>2</bitWidth>
          </field>
          <field>
            <name>MODER6</name>
            <bitOffset>12</bitOffset>
            <bitWidth>2</bitWidth>
          </field>
          <field>
            <name>MODER7</name>
            <bitOffset>14</bitOffset>
            <bitWidth>2</bitWidth>
          </field>
          <field>
            <name>MODER8</name>
            <bitOffset>16</bitOffset>
            <bitWidth>2</bitWidth>
          </field>
          <field>
            <name>MODER9</name>
            <bitOffset>18</bitOffset>
            <bitWidth>2</bitWidth>
          </field>
          <field>
            <name>MODER10</name>
            <bitOffset>20</bitOffset>
            <bitWidth>2</bitWidth>
          </field>
          <field>
            <name>MODER11</name>
            <bitOffset>22</bitOffset>
            <bitWidth>2</bitWidth>
          </field>
          <field>
            <name>MODER12</name>
            <bitOffset>24</bitOffset>
            <bitWidth>2</bitWidth>
          </field>
          <field>
            <name>MODER13</name>
            <bitOffset>26</bitOffset>
            <bitWidth>2</bitWidth>
          </field>
          <field>
            <name>MODER14</name>
            <bitOffset>28</bitOffset>
            <bitWidth>2</bitWidth>
          </field>
          <field>
            <name>MODER15</name>
            <bitOffset>30</bitOffset>
            <bitWidth>2</bitWidth>
          </field>
        </fields>
      </register>
      <register>
        <name>OTYPER</name>
        <addressOffset>0x4</addressOffset>
        <size>0x20</size>
        <fields>
          <field>
            <name>OT0</name>
            <bitOffset>0</bitOffset>
            <bitWidth>1</bitWidth>
          </field>
          <field>
            <name>OT1</name>
            <bitOffset>1</bitOffset>
            <bitWidth>1</bitWidth>
          </field>
          <field>
            <name>OT2</name>
            <bitOffset>2</bitOffset>
            <bitWidth>1</bitWidth>
          </field>
          <field>
            <name>OT3</name>
            <bitOffset>3</bitOffset>
            <bitWidth>1</bitWidth>
          </field>
          <field>
            <name>OT4</name>
            <bitOffset>4</bitOffset>
            <bitWidth>1</bitWidth>
          </field>
          <field>
            <name>OT5</name>
            <bitOffset>5</bitOffset>
            <bitWidth>1</bitWidth>
          </field>
          <field>
            <name>OT6</name>
            <bitOffset>6</bitOffset>
            <bitWidth>1</bitWidth>
          </field>
          <field>
            <name>OT7</name>
            <bitOffset>7</bitOffset>
            <bitWidth>1</bitWidth>
          </field>
          <field>
            <name>OT8</name>
            <bitOffset>8</bitOffset>
            <bitWidth>1</bitWidth>
          </field>
          <field>
            <name>OT9</name>
            <bitOffset>9</bitOffset>
            <bitWidth>1</bitWidth>
          </field>
          <field>
            <name>OT10</name>
            <bitOffset>10</bitOffset>
            <bitWidth>1</bitWidth>
          </field>
          <field>
            <name>OT11</name>
            <bitOffset>11</bitOffset>
            <bitWidth>1</bitWidth>
          </field>
          <field>
            <name>OT12</name>
            <bitOffset>12</bitOffset>
            <bitWidth>1</bitWidth>
          </field>
          <field>
            <name>OT13</name>
            <bitOffset>13</bitOffset>
            <bitWidth>1</bitWidth>
          </field>
          <field>
            <name>OT14</name>
            <bitOffset>14</bitOffset>
            <bitWidth>1</bitWidth>
          </field>
          <field>
            <name>OT15</name>
            <bitOffset>15</bitOffset>
            <bitWidth>1</bitWidth>
          </field>
        </fields>
      </register>
      <register>
        <name>OSPEEDR</name>
        <addressOffset>0x8</addressOffset>
        <size>0x20</size>
        <fields>
          <field>
            <name>OSPEED0</name>
            <bitOffset>0</bitOffset>
            <bitWidth>2</bitWidth>
          </field>
          <field>
            <name>OSPEED1</name>
            <bitOffset>2</bitOffset>
            <bitWidth>2</bitWidth>
          </field>
          <field>
            <name>OSPEED2</name>
            <bitOffset>4</bitOffset>
            <bitWidth>2</bitWidth>
          </field>
          <field>
            <name>OSPEED3</name>
            <bitOffset>6</bitOffset>
            <bitWidth>2</bitWidth>
          </field>
          <field>
            <name>OSPEED4</name>
            <bitOffset>8</bitOffset>
            <bitWidth>2</bitWidth>
          </field>
          <field>
            <name>OSPEED5</name>
            <bitOffset>10</bitOffset>
            <bitWidth>2</bitWidth>
          </field>
          <field>
            <name>OSPEED6</name>
            <bitOffset>12</bitOffset>
            <bitWidth>2</bitWidth>
          </field>
          <field>
            <name>OSPEED7</name>
            <bitOffset>14</bitOffset>
            <bitWidth>2</bitWidth>
          </field>
          <field>
            <name>OSPEED8</name>
            <bitOffset>16</bitOffset>
            <bitWidth>2</bitWidth>
          </field>
          <field>
            <name>OSPEED9</name>
            <bitOffset>18</bitOffset>
            <bitWidth>2</bitWidth>
          </field>
          <field>
            <name>OSPEED10</name>
            <bitOffset>20</bitOffset>
            <bitWidth>2</bitWidth>
          </field>
          <field>
            <name>OSPEED11</name>
            <bitOffset>22</bitOffset>
            <bitWidth>2</bitWidth>
          </field>
          <field>
            <name>OSPEED12</name>
            <bitOffset>24</bitOffset>
            <bitWidth>2</bitWidth>
          </field>
          <field>
            <name>OSPEED13</name>
            <bitOffset>26</bitOffset>
            <bitWidth>2</bitWidth>
          </field>
          <field>
            <name>OSPEED14</name>
            <bitOffset>28</bitOffset>
            <bitWidth>2</bitWidth>
          </field>
          <field>
            <name>OSPEED15</name>
            <bitOffset>30</bitOffset>
            <bitWidth>2</bitWidth>
          </field>
        </fields>
      </register>
      <register>
        <name>PUPDR</name>
        <addressOffset>0xc</addressOffset>
        <size>0x20</size>
        <fields>
          <field>
            <name>PUPD0</name>
            <bitOffset>0</bitOffset>
            <bitWidth>2</bitWidth>
          </field>
          <field>
            <name>PUPD1</name>
            <bitOffset>2</bitOffset>
            <bitWidth>2</bitWidth>
          </field>
          <field>
            <name>PUPD2</name>
            <bitOffset>4</bitOffset>
            <bitWidth>2</bitWidth>
          </field>
          <field>
            <name>PUPD3</name>
            <bitOffset>6</bitOffset>
            <bitWidth>2</bitWidth>
          </field>
          <field>
            <name>PUPD4</name>
            <bitOffset>8</bitOffset>
            <bitWidth>2</bitWidth>
          </field>
          <field>
            <name>PUPD5</name>
            <bitOffset>10</bitOffset>
            <bitWidth>2</bitWidth>
          </field>
          <field>
            <name>PUPD6</name>
            <bitOffset>12</bitOffset>
            <bitWidth>2</bitWidth>
          </field>
          <field>
            <name>PUPD7</name>
            <bitOffset>14</bitOffset>
            <bitWidth>2</bitWidth>
          </field>
          <field>
            <name>PUPD8</name>
            <bitOffset>16</bitOffset>
            <bitWidth>2</bitWidth>
          </field>
          <field>
            <name>PUPD9</name>
            <bitOffset>18</bitOffset>
            <bitWidth>2</bitWidth>
          </field>
          <field>
            <name>PUPD10</name>
            <bitOffset>20</bitOffset>
            <bitWidth>2</bitWidth>
          </field>
          <field>
            <name>PUPD11</name>
            <bitOffset>22</bitOffset>
            <bitWidth>2</bitWidth>
          </field>
          <field>
            <name>PUPD12</name>
            <bitOffset>24</bitOffset>
            <bitWidth>2</bitWidth>
          </field>
          <field>
            <name>PUPD13</name>
            <bitOffset>26</bitOffset>
            <bitWidth>2</bitWidth>
          </field>
          <field>
            <name>PUPD14</name>
            <bitOffset>28</bitOffset>
            <bitWidth>2</bitWidth>
          </field>
          <field>
            <name>PUPD15</name>
            <bitOffset>30</bitOffset>
            <bitWidth>2</bitWidth>
          </field>
        </fields>
      </register>
      <register>
        <name>IDR</name>
        <addressOffset>0x10</addressOffset>
        <size>0x20</size>
        <fields>
          <field>
            <name>ID0</name>
            <bitOffset>0</bitOffset>
            <bitWidth>1</bitWidth>
          </field>
          <field>
            <name>ID1</name>
            <bitOffset>1</bitOffset>
            <bitWidth>1</bitWidth>
          </field>
          <field>
            <name>ID2</name>
            <bitOffset>2</bitOffset>
            <bitWidth>1</bitWidth>
          </field>
          <field>
            <name>ID3</name>
            <bitOffset>3</bitOffset>
            <bitWidth>1</bitWidth>
          </field>
          <field>
            <name>ID4</name>
            <bitOffset>4</bitOffset>
            <bitWidth>1</bitWidth>
          </field>
          <field>
            <name>ID5</name>
            <bitOffset>5</bitOffset>
            <bitWidth>1</bitWidth>
          </field>
          <field>
            <name>ID6</name>
            <bitOffset>6</bitOffset>
            <bitWidth>1</bitWidth>
          </field>
          <field>
            <name>ID7</name>
            <bitOffset>7</bitOffset>
            <bitWidth>1</bitWidth>
          </field>
          <field>
            <name>ID8</name>
            <bitOffset>8</bitOffset>
            <bitWidth>1</bitWidth>
          </field>
          <field>
            <name>ID9</name>
            <bitOffset>9</bitOffset>
            <bitWidth>1</bitWidth>
          </field>
          <field>
            <name>ID10</name>
            <bitOffset>10</bitOffset>
            <bitWidth>1</bitWidth>
          </field>
          <field>
            <name>ID11</name>
            <bitOffset>11</bitOffset>
            <bitWidth>1</bitWidth>
          </field>
          <field>
            <name>ID12</name>
            <bitOffset>12</bitOffset>
            <bitWidth>1</bitWidth>
          </field>
          <field>
            <name>ID13</name>
            <bitOffset>13</bitOffset>
            <bitWidth>1</bitWidth>
          </field>
          <field>
            <name>ID14</name>
            <bitOffset>14</bitOffset>
            <bitWidth>1</bitWidth>
          </field>
          <field>
            <name>ID15</name>
            <bitOffset>15</bitOffset>
            <bitWidth>1</bitWidth>
          </field>
        </fields>
      </register>
      <register>
        <name>ODR</name>
        <addressOffset>0x14</addressOffset>
        <size>0x20</size>
        <fields>
          <field>
            <name>OD0</name>
            <bitOffset>0</bitOffset>
            <bitWidth>1</bitWidth>
          </field>
          <field>
            <name>OD1</name>
            <bitOffset>1</bitOffset>
            <bitWidth>1</bitWidth>
          </field>
          <field>
            <name>OD2</name>
            <bitOffset>2</bitOffset>
            <bitWidth>1</bitWidth>
          </field>
          <field>
            <name>OD3</name>
            <bitOffset>3</bitOffset>
            <bitWidth>1</bitWidth>
          </field>
          <field>
            <name>OD4</name>
            <bitOffset>4</bitOffset>
            <bitWidth>1</bitWidth>
          </field>
          <field>
            <name>OD5</name>
            <bitOffset>5</bitOffset>
            <bitWidth>1</bitWidth>
          </field>
          <field>
            <name>OD6</name>
            <bitOffset>6</bitOffset>
            <bitWidth>1</bitWidth>
          </field>
          <field>
            <name>OD7</name>
            <bitOffset>7</bitOffset>
            <bitWidth>1</bitWidth>
          </field>
          <field>
            <name>OD8</name>
            <bitOffset>8</bitOffset>
            <bitWidth>1</bitWidth>
          </field>
          <field>
            <name>OD9</name>
            <bitOffset>9</bitOffset>
            <bitWidth>1</bitWidth>
          </field>
          <field>
            <name>OD10</name>
            <bitOffset>10</bitOffset>
            <bitWidth>1</bitWidth>
          </field>
          <field>
            <name>OD11</name>
            <bitOffset>11</bitOffset>
            <bitWidth>1</bitWidth>
          </field>
          <field>
            <name>OD12</name>
            <bitOffset>12</bitOffset>
            <bitWidth>1</bitWidth>
          </field>
          <field>
            <name>OD13</name>
            <bitOffset>13</bitOffset>
            <bitWidth>1</bitWidth>
          </field>
          <field>
            <name>OD14</name>
            <bitOffset>14</bitOffset>
            <bitWidth>1</bitWidth>
          </field>
          <field>
            <name>OD15</name>
            <bitOffset>15</bitOffset>
            <bitWidth>1</bitWidth>
          </field>
        </fields>
      </register>
      <register>
        <name>BSRR</name>
        <addressOffset>0x18</addressOffset>
        <size>0x20</size>
        <fields>
          <field>
            <name>BS0</name>
            <bitOffset>0</bitOffset>
            <bitWidth>1</bitWidth>
          </field>
          <field>
            <name>BS1</name>
            <bitOffset>1</bitOffset>
            <bitWidth>1</bitWidth>
          </field>
          <field>
            <name>BS2</name>
            <bitOffset>2</bitOffset>
            <bitWidth>1</bitWidth>
          </field>
          <field>
            <name>BS3</name>
            <bitOffset>3</bitOffset>
            <bitWidth>1</bitWidth>
          </field>
          <field>
            <name>BS4</name>
            <bitOffset>4</bitOffset>
            <bitWidth>1</bitWidth>
          </field>
          <field>
            <name>BS5</name>
            <bitOffset>5</bitOffset>
            <bitWidth>1</bitWidth>
          </field>
          <field>
            <name>BS6</name>
            <bitOffset>6</bitOffset>
            <bitWidth>1</bitWidth>
          </field>
          <field>
            <name>BS7</name>
            <bitOffset>7</bitOffset>
            <bitWidth>1</bitWidth>
          </field>
          <field>
            <name>BS8</name>
            <bitOffset>8</bitOffset>
            <bitWidth>1</bitWidth>
          </field>
          <field>
            <name>BS9</name>
            <bitOffset>9</bitOffset>
            <bitWidth>1</bitWidth>
          </field>
          <field>
            <name>BS10</name>
            <bitOffset>10</bitOffset>
            <bitWidth>1</bitWidth>
          </field>
          <field>
            <name>BS11</name>
            <bitOffset>11</bitOffset>
            <bitWidth>1</bitWidth>
          </field>
          <field>
            <name>BS12</name>
            <bitOffset>12</bitOffset>
            <bitWidth>1</bitWidth>
          </field>
          <field>
            <name>BS13</name>
            <bitOffset>13</bitOffset>
            <bitWidth>1</bitWidth>
          </field>
          <field>
            <name>BS14</name>
            <bitOffset>14</bitOffset>
            <bitWidth>1</bitWidth>
          </field>
          <field>
            <name>BS15</name>
            <bitOffset>15</bitOffset>
            <bitWidth>1</bitWidth>
          </field>
          <field>
            <name>BR0</name>
            <bitOffset>16</bitOffset>
            <bitWidth>1</bitWidth>
          </field>
          <field>
            <name>BR1</name>
            <bitOffset>17</bitOffset>
            <bitWidth>1</bitWidth>
          </field>
          <field>
            <name>BR2</name>
            <bitOffset>18</bitOffset>
            <bitWidth>1</bitWidth>
          </field>
          <field>
            <name>BR3</name>
            <bitOffset>19</bitOffset>
            <bitWidth>1</bitWidth>
          </field>
          <field>
            <name>BR4</name>
            <bitOffset>20</bitOffset>
            <bitWidth>1</bitWidth>
          </field>
          <field>
            <name>BR5</name>
            <bitOffset>21</bitOffset>
            <bitWidth>1</bitWidth>
          </field>
          <field>
            <name>BR6</name>
            <bitOffset>22</bitOffset>
            <bitWidth>1</bitWidth>
          </field>
          <field>
            <name>BR7</name>
            <bitOffset>23</bitOffset>
            <bitWidth>1</bitWidth>
          </field>
          <field>
            <name>BR8</name>
            <bitOffset>24</bitOffset>
            <bitWidth>1</bitWidth>
          </field>
          <field>
            <name>BR9</name>
            <bitOffset>25</bitOffset>
            <bitWidth>1</bitWidth>
          </field>
          <field>
            <name>BR10</name>
            <bitOffset>26</bitOffset>
            <bitWidth>1</bitWidth>
          </field>
          <field>
            <name>BR11</name>
            <bitOffset>27</bitOffset>
            <bitWidth>1</bitWidth>
          </field>
          <field>
            <name>BR12</name>
            <bitOffset>28</bitOffset>
            <bitWidth>1</bitWidth>
          </field>
          <field>
            <name>BR13</name>
            <bitOffset>29</bitOffset>
            <bitWidth>1</bitWidth>
          </field>
          <field>
            <name>BR14</name>
            <bitOffset>30</bitOffset>
            <bitWidth>1</bitWidth>
          </field>
          <field>
            <name>BR15</name>
            <bitOffset>31</bitOffset>
            <bitWidth>1</bitWidth>
          </field>
        </fields>
      </register>
      <register>
        <name>LCKR</name>
        <addressOffset>0x1c</addressOffset>
        <size>0x20</size>
      </register>
      <register>
        <name>AFR.0</name>
        <addressOffset>0x20</addressOffset>
        <size>0x20</size>
      </register>
      <register>
        <name>AFR.1</name>
        <addressOffset>0x24</addressOffset>
        <size>0x20</size>
        <fields>
          <field>
            <name>AFSEL8</name>
            <bitOffset>0</bitOffset>
            <bitWidth>4</bitWidth>
          </field>
          <field>
            <name>AFSEL9</name>
            <bitOffset>4</bitOffset>
            <bitWidth>4</bitWidth>
          </field>
          <field>
            <name>AFSEL10</name>
            <bitOffset>8</bitOffset>
            <bitWidth>4</bitWidth>
          </field>
          <field>
            <name>AFSEL11</name>
            <bitOffset>12</bitOffset>
            <bitWidth>4</bitWidth>
          </field>
          <field>
            <name>AFSEL12</name>
            <bitOffset>16</bitOffset>
            <bitWidth>4</bitWidth>
          </field>
          <field>
            <name>AFSEL13</name>
            <bitOffset>20</bitOffset>
            <bitWidth>4</bitWidth>
          </field>
          <field>
            <name>AFSEL14</name>
            <bitOffset>24</bitOffset>
            <bitWidth>4</bitWidth>
          </field>
          <field>
            <name>AFSEL15</name>
            <bitOffset>28</bitOffset>
            <bitWidth>4</bitWidth>
          </field>
        </fields>
      </register>
    </peripheral>
    <peripheral>
      <name>GPIOB</name>
      <baseAddress>0x40020400</baseAddress>
      <register>
        <name>MODER</name>
        <addressOffset>0x0</addressOffset>
        <size>0x20</size>
        <fields>
          <field>
            <name>MODER0</name>
            <bitOffset>0</bitOffset>
            <bitWidth>2</bitWidth>
          </field>
          <field>
            <name>MODER1</name>
            <bitOffset>2</bitOffset>
            <bitWidth>2</bitWidth>
          </field>
          <field>
            <name>MODER2</name>
            <bitOffset>4</bitOffset>
            <bitWidth>2</bitWidth>
          </field>
          <field>
            <name>MODER3</name>
            <bitOffset>6</bitOffset>
            <bitWidth>2</bitWidth>
          </field>
          <field>
            <name>MODER4</name>
            <bitOffset>8</bitOffset>
            <bitWidth>2</bitWidth>
          </field>
          <field>
            <name>MODER5</name>
            <bitOffset>10</bitOffset>
            <bitWidth>2</bitWidth>
          </field>
          <field>
            <name>MODER6</name>
            <bitOffset>12</bitOffset>
            <bitWidth>2</bitWidth>
          </field>
          <field>
            <name>MODER7</name>
            <bitOffset>14</bitOffset>
            <bitWidth>2</bitWidth>
          </field>
          <field>
            <name>MODER8</name>
            <bitOffset>16</bitOffset>
            <bitWidth>2</bitWidth>
          </field>
          <field>
            <name>MODER9</name>
            <bitOffset>18</bitOffset>
            <bitWidth>2</bitWidth>
          </field>
          <field>
            <name>MODER10</name>
            <bitOffset>20</bitOffset>
            <bitWidth>2</bitWidth>
          </field>
          <field>
            <name>MODER11</name>
            <bitOffset>22</bitOffset>
            <bitWidth>2</bitWidth>
          </field>
          <field>
            <name>MODER12</name>
            <bitOffset>24</bitOffset>
            <bitWidth>2</bitWidth>
          </field>
          <field>
            <name>MODER13</name>
            <bitOffset>26</bitOffset>
            <bitWidth>2</bitWidth>
          </field>
          <field>
            <name>MODER14</name>
            <bitOffset>28</bitOffset>
            <bitWidth>2</bitWidth>
          </field>
          <field>
            <name>MODER15</name>
            <bitOffset>30</bitOffset>
            <bitWidth>2</bitWidth>
          </field>
        </fields>
      </register>
      <register>
        <name>OTYPER</name>
        <addressOffset>0x4</addressOffset>
        <size>0x20</size>
        <fields>
          <field>
            <name>OT0</name>
            <bitOffset>0</bitOffset>
            <bitWidth>1</bitWidth>
          </field>
          <field>
            <name>OT1</name>
            <bitOffset>1</bitOffset>
            <bitWidth>1</bitWidth>
          </field>
          <field>
            <name>OT2</name>
            <bitOffset>2</bitOffset>
            <bitWidth>1</bitWidth>
          </field>
          <field>
            <name>OT3</name>
            <bitOffset>3</bitOffset>
            <bitWidth>1</bitWidth>
          </field>
          <field>
            <name>OT4</name>
            <bitOffset>4</bitOffset>
            <bitWidth>1</bitWidth>
          </field>
          <field>
            <name>OT5</name>
            <bitOffset>5</bitOffset>
            <bitWidth>1</bitWidth>
          </field>
          <field>
            <name>OT6</name>
            <bitOffset>6</bitOffset>
            <bitWidth>1</bitWidth>
          </field>
          <field>
            <name>OT7</name>
            <bitOffset>7</bitOffset>
            <bitWidth>1</bitWidth>
          </field>
          <field>
            <name>OT8</name>
            <bitOffset>8</bitOffset>
            <bitWidth>1</bitWidth>
          </field>
          <field>
            <name>OT9</name>
            <bitOffset>9</bitOffset>
            <bitWidth>1</bitWidth>
          </field>
          <field>
            <name>OT10</name>
            <bitOffset>10</bitOffset>
            <bitWidth>1</bitWidth>
          </field>
          <field>
            <name>OT11</name>
            <bitOffset>11</bitOffset>
            <bitWidth>1</bitWidth>
          </field>
          <field>
            <name>OT12</name>
            <bitOffset>12</bitOffset>
            <bitWidth>1</bitWidth>
          </field>
          <field>
            <name>OT13</name>
            <bitOffset>13</bitOffset>
            <bitWidth>1</bitWidth>
          </field>
          <field>
            <name>OT14</name>
            <bitOffset>14</bitOffset>
            <bitWidth>1</bitWidth>
          </field>
          <field>
            <name>OT15</name>
            <bitOffset>15</bitOffset>
            <bitWidth>1</bitWidth>
          </field>
        </fields>
      </register>
      <register>
        <name>OSPEEDR</name>
        <addressOffset>0x8</addressOffset>
        <size>0x20</size>
        <fields>
          <field>
            <name>OSPEED0</name>
            <bitOffset>0</bitOffset>
            <bitWidth>2</bitWidth>
          </field>
          <field>
            <name>OSPEED1</name>
            <bitOffset>2</bitOffset>
            <bitWidth>2</bitWidth>
          </field>
          <field>
            <name>OSPEED2</name>
            <bitOffset>4</bitOffset>
            <bitWidth>2</bitWidth>
          </field>
          <field>
            <name>OSPEED3</name>
            <bitOffset>6</bitOffset>
            <bitWidth>2</bitWidth>
          </field>
          <field>
            <name>OSPEED4</name>
            <bitOffset>8</bitOffset>
            <bitWidth>2</bitWidth>
          </field>
          <field>
            <name>OSPEED5</name>
            <bitOffset>10</bitOffset>
            <bitWidth>2</bitWidth>
          </field>
          <field>
            <name>OSPEED6</name>
            <bitOffset>12</bitOffset>
            <bitWidth>2</bitWidth>
          </field>
          <field>
            <name>OSPEED7</name>
            <bitOffset>14</bitOffset>
            <bitWidth>2</bitWidth>
          </field>
          <field>
            <name>OSPEED8</name>
            <bitOffset>16</bitOffset>
            <bitWidth>2</bitWidth>
          </field>
          <field>
            <name>OSPEED9</name>
            <bitOffset>18</bitOffset>
            <bitWidth>2</bitWidth>
          </field>
          <field>
            <name>OSPEED10</name>
            <bitOffset>20</bitOffset>
            <bitWidth>2</bitWidth>
          </field>
          <field>
            <name>OSPEED11</name>
            <bitOffset>22</bitOffset>
            <bitWidth>2</bitWidth>
          </field>
          <field>
            <name>OSPEED12</name>
            <bitOffset>24</bitOffset>
            <bitWidth>2</bitWidth>
          </field>
          <field>
            <name>OSPEED13</name>
            <bitOffset>26</bitOffset>
            <bitWidth>2</bitWidth>
          </field>
          <field>
            <name>OSPEED14</name>
            <bitOffset>28</bitOffset>
            <bitWidth>2</bitWidth>
          </field>
          <field>
            <name>OSPEED15</name>
            <bitOffset>30</bitOffset>
            <bitWidth>2</bitWidth>
          </field>
        </fields>
      </register>
      <register>
        <name>PUPDR</name>
        <addressOffset>0xc</addressOffset>
        <size>0x20</size>
        <fields>
          <field>
            <name>PUPD0</name>
            <bitOffset>0</bitOffset>
            <bitWidth>2</bitWidth>
          </field>
          <field>
            <name>PUPD1</name>
            <bitOffset>2</bitOffset>
            <bitWidth>2</bitWidth>
          </field>
          <field>
            <name>PUPD2</name>
            <bitOffset>4</bitOffset>
            <bitWidth>2</bitWidth>
          </field>
          <field>
            <name>PUPD3</name>
            <bitOffset>6</bitOffset>
            <bitWidth>2</bitWidth>
          </field>
          <field>
            <name>PUPD4</name>
            <bitOffset>8</bitOffset>
            <bitWidth>2</bitWidth>
          </field>
          <field>
            <name>PUPD5</name>
            <bitOffset>10</bitOffset>
            <bitWidth>2</bitWidth>
          </field>
          <field>
            <name>PUPD6</name>
            <bitOffset>12</bitOffset>
            <bitWidth>2</bitWidth>
          </field>
          <field>
            <name>PUPD7</name>
            <bitOffset>14</bitOffset>
            <bitWidth>2</bitWidth>
          </field>
          <field>
            <name>PUPD8</name>
            <bitOffset>16</bitOffset>
            <bitWidth>2</bitWidth>
          </field>
          <field>
            <name>PUPD9</name>
            <bitOffset>18</bitOffset>
            <bitWidth>2</bitWidth>
          </field>
          <field>
            <name>PUPD10</name>
            <bitOffset>20</bitOffset>
            <bitWidth>2</bitWidth>
          </field>
          <field>
            <name>PUPD11</name>
            <bitOffset>22</bitOffset>
            <bitWidth>2</bitWidth>
          </field>
          <field>
            <name>PUPD12</name>
            <bitOffset>24</bitOffset>
            <bitWidth>2</bitWidth>
          </field>
          <field>
            <name>PUPD13</name>
            <bitOffset>26</bitOffset>
            <bitWidth>2</bitWidth>
          </field>
          <field>
            <name>PUPD14</name>
            <bitOffset>28</bitOffset>
            <bitWidth>2</bitWidth>
          </field>
          <field>
            <name>PUPD15</name>
            <bitOffset>30</bitOffset>
            <bitWidth>2</bitWidth>
          </field>
        </fields>
      </register>
      <register>
        <name>IDR</name>
        <addressOffset>0x10</addressOffset>
        <size>0x20</size>
        <fields>
          <field>
            <name>ID0</name>
            <bitOffset>0</bitOffset>
            <bitWidth>1</bitWidth>
          </field>
          <field>
            <name>ID1</name>
            <bitOffset>1</bitOffset>
            <bitWidth>1</bitWidth>
          </field>
          <field>
            <name>ID2</name>
            <bitOffset>2</bitOffset>
            <bitWidth>1</bitWidth>
          </field>
          <field>
            <name>ID3</name>
            <bitOffset>3</bitOffset>
            <bitWidth>1</bitWidth>
          </field>
          <field>
            <name>ID4</name>
            <bitOffset>4</bitOffset>
            <bitWidth>1</bitWidth>
          </field>
          <field>
            <name>ID5</name>
            <bitOffset>5</bitOffset>
            <bitWidth>1</bitWidth>
          </field>
          <field>
            <name>ID6</name>
            <bitOffset>6</bitOffset>
            <bitWidth>1</bitWidth>
          </field>
          <field>
            <name>ID7</name>
            <bitOffset>7</bitOffset>
            <bitWidth>1</bitWidth>
          </field>
          <field>
            <name>ID8</name>
            <bitOffset>8</bitOffset>
            <bitWidth>1</bitWidth>
          </field>
          <field>
            <name>ID9</name>
            <bitOffset>9</bitOffset>
            <bitWidth>1</bitWidth>
          </field>
          <field>
            <name>ID10</name>
            <bitOffset>10</bitOffset>
            <bitWidth>1</bitWidth>
          </field>
          <field>
            <name>ID11</name>
            <bitOffset>11</bitOffset>
            <bitWidth>1</bitWidth>
          </field>
          <field>
            <name>ID12</name>
            <bitOffset>12</bitOffset>
            <bitWidth>1</bitWidth>
          </field>
          <field>
            <name>ID13</name>
            <bitOffset>13</bitOffset>
            <bitWidth>1</bitWidth>
          </field>
          <field>
            <name>ID14</name>
            <bitOffset>14</bitOffset>
            <bitWidth>1</bitWidth>
          </field>
          <field>
            <name>ID15</name>
            <bitOffset>15</bitOffset>
            <bitWidth>1</bitWidth>
          </field>
        </fields>
      </register>
      <register>
        <name>ODR</name>
        <addressOffset>0x14</addressOffset>
        <size>0x20</size>
        <fields>
          <field>
            <name>OD0</name>
            <bitOffset>0</bitOffset>
            <bitWidth>1</bitWidth>
          </field>
          <field>
            <name>OD1</name>
            <bitOffset>1</bitOffset>
            <bitWidth>1</bitWidth>
          </field>
          <field>
            <name>OD2</name>
            <bitOffset>2</bitOffset>
            <bitWidth>1</bitWidth>
          </field>
          <field>
            <name>OD3</name>
            <bitOffset>3</bitOffset>
            <bitWidth>1</bitWidth>
          </field>
          <field>
            <name>OD4</name>
            <bitOffset>4</bitOffset>
            <bitWidth>1</bitWidth>
          </field>
          <field>
            <name>OD5</name>
            <bitOffset>5</bitOffset>
            <bitWidth>1</bitWidth>
          </field>
          <field>
            <name>OD6</name>
            <bitOffset>6</bitOffset>
            <bitWidth>1</bitWidth>
          </field>
          <field>
            <name>OD7</name>
            <bitOffset>7</bitOffset>
            <bitWidth>1</bitWidth>
          </field>
          <field>
            <name>OD8</name>
            <bitOffset>8</bitOffset>
            <bitWidth>1</bitWidth>
          </field>
          <field>
            <name>OD9</name>
            <bitOffset>9</bitOffset>
            <bitWidth>1</bitWidth>
          </field>
          <field>
            <name>OD10</name>
            <bitOffset>10</bitOffset>
            <bitWidth>1</bitWidth>
          </field>
          <field>
            <name>OD11</name>
            <bitOffset>11</bitOffset>
            <bitWidth>1</bitWidth>
          </field>
          <field>
            <name>OD12</name>
            <bitOffset>12</bitOffset>
            <bitWidth>1</bitWidth>
          </field>
          <field>
            <name>OD13</name>
            <bitOffset>13</bitOffset>
            <bitWidth>1</bitWidth>
          </field>
          <field>
            <name>OD14</name>
            <bitOffset>14</bitOffset>
            <bitWidth>1</bitWidth>
          </field>
          <field>
            <name>OD15</name>
            <bitOffset>15</bitOffset>
            <bitWidth>1</bitWidth>
          </field>
        </fields>
      </register>
      <register>
        <name>BSRR</name>
        <addressOffset>0x18</addressOffset>
        <size>0x20</size>
        <fields>
          <field>
            <name>BS0</name>
            <bitOffset>0</bitOffset>
            <bitWidth>1</bitWidth>
          </field>
          <field>
            <name>BS1</name>
            <bitOffset>1</bitOffset>
            <bitWidth>1</bitWidth>
          </field>
          <field>
            <name>BS2</name>
            <bitOffset>2</bitOffset>
            <bitWidth>1</bitWidth>
          </field>
          <field>
            <name>BS3</name>
            <bitOffset>3</bitOffset>
            <bitWidth>1</bitWidth>
          </field>
          <field>
            <name>BS4</name>
            <bitOffset>4</bitOffset>
            <bitWidth>1</bitWidth>
          </field>
          <field>
            <name>BS5</name>
            <bitOffset>5</bitOffset>
            <bitWidth>1</bitWidth>
          </field>
          <field>
            <name>BS6</name>
            <bitOffset>6</bitOffset>
            <bitWidth>1</bitWidth>
          </field>
          <field>
            <name>BS7</name>
            <bitOffset>7</bitOffset>
            <bitWidth>1</bitWidth>
          </field>
          <field>
            <name>BS8</name>
            <bitOffset>8</bitOffset>
            <bitWidth>1</bitWidth>
          </field>
          <field>
            <name>BS9</name>
            <bitOffset>9</bitOffset>
            <bitWidth>1</bitWidth>
          </field>
          <field>
            <name>BS10</name>
            <bitOffset>10</bitOffset>
            <bitWidth>1</bitWidth>
          </field>
          <field>
            <name>BS11</name>
            <bitOffset>11</bitOffset>
            <bitWidth>1</bitWidth>
          </field>
          <field>
            <name>BS12</name>
            <bitOffset>12</bitOffset>
            <bitWidth>1</bitWidth>
          </field>
          <field>
            <name>BS13</name>
            <bitOffset>13</bitOffset>
            <bitWidth>1</bitWidth>
          </field>
          <field>
            <name>BS14</name>
            <bitOffset>14</bitOffset>
            <bitWidth>1</bitWidth>
          </field>
          <field>
            <name>BS15</name>
            <bitOffset>15</bitOffset>
            <bitWidth>1</bitWidth>
          </field>
          <field>
            <name>BR0</name>
            <bitOffset>16</bitOffset>
            <bitWidth>1</bitWidth>
          </field>
          <field>
            <name>BR1</name>
            <bitOffset>17</bitOffset>
            <bitWidth>1</bitWidth>
          </field>
          <field>
            <name>BR2</name>
            <bitOffset>18</bitOffset>
            <bitWidth>1</bitWidth>
          </field>
          <field>
            <name>BR3</name>
            <bitOffset>19</bitOffset>
            <bitWidth>1</bitWidth>
          </field>
          <field>
            <name>BR4</name>
            <bitOffset>20</bitOffset>
            <bitWidth>1</bitWidth>
          </field>
          <field>
            <name>BR5</name>
            <bitOffset>21</bitOffset>
            <bitWidth>1</bitWidth>
          </field>
          <field>
            <name>BR6</name>
            <bitOffset>22</bitOffset>
            <bitWidth>1</bitWidth>
          </field>
          <field>
            <name>BR7</name>
            <bitOffset>23</bitOffset>
            <bitWidth>1</bitWidth>
          </field>
          <field>
            <name>BR8</name>
            <bitOffset>24</bitOffset>
            <bitWidth>1</bitWidth>
          </field>
          <field>
            <name>BR9</name>
            <bitOffset>25</bitOffset>
            <bitWidth>1</bitWidth>
          </field>
          <field>
            <name>BR10</name>
            <bitOffset>26</bitOffset>
            <bitWidth>1</bitWidth>
          </field>
          <field>
            <name>BR11</name>
            <bitOffset>27</bitOffset>
            <bitWidth>1</bitWidth>
          </field>
          <field>
            <name>BR12</name>
            <bitOffset>28</bitOffset>
            <bitWidth>1</bitWidth>
          </field>
          <field>
            <name>BR13</name>
            <bitOffset>29</bitOffset>
            <bitWidth>1</bitWidth>
          </field>
          <field>
            <name>BR14</name>
            <bitOffset>30</bitOffset>
            <bitWidth>1</bitWidth>
          </field>
          <field>
            <name>BR15</name>
            <bitOffset>31</bitOffset>
            <bitWidth>1</bitWidth>
          </field>
        </fields>
      </register>
      <register>
        <name>LCKR</name>
        <addressOffset>0x1c</addressOffset>
        <size>0x20</size>
      </register>
      <register>
        <name>AFR.0</name>
        <addressOffset>0x20</addressOffset>
        <size>0x20</size>
      </register>
      <register>
        <name>AFR.1</name>
        <addressOffset>0x24</addressOffset>
        <size>0x20</size>
        <fields>
          <field>
            <name>AFSEL8</name>
            <bitOffset>0</bitOffset>
            <bitWidth>4</bitWidth>
          </field>
          <field>
            <name>AFSEL9</name>
            <bitOffset>4</bitOffset>
            <bitWidth>4</bitWidth>
          </field>
          <field>
            <name>AFSEL10</name>
            <bitOffset>8</bitOffset>
            <bitWidth>4</bitWidth>
          </field>
          <field>
            <name>AFSEL11</name>
            <bitOffset>12</bitOffset>
            <bitWidth>4</bitWidth>
          </field>
          <field>
            <name>AFSEL12</name>
            <bitOffset>16</bitOffset>
            <bitWidth>4</bitWidth>
          </field>
          <field>
            <name>AFSEL13</name>
            <bitOffset>20</bitOffset>
            <bitWidth>4</bitWidth>
          </field>
          <field>
            <name>AFSEL14</name>
            <bitOffset>24</bitOffset>
            <bitWidth>4</bitWidth>
          </field>
          <field>
            <name>AFSEL15</name>
            <bitOffset>28</bitOffset>
            <bitWidth>4</bitWidth>
          </field>
        </fields>
      </register>
    </peripheral>
    <peripheral>
      <name>GPIOC</name>
      <baseAddress>0x40020800</baseAddress>
      <register>
        <name>MODER</name>
        <addressOffset>0x0</addressOffset>
        <size>0x20</size>
        <fields>
          <field>
            <name>MODER0</name>
            <bitOffset>0</bitOffset>
            <bitWidth>2</bitWidth>
          </field>
          <field>
            <name>MODER1</name>
            <bitOffset>2</bitOffset>
            <bitWidth>2</bitWidth>
          </field>
          <field>
            <name>MODER2</name>
            <bitOffset>4</bitOffset>
            <bitWidth>2</bitWidth>
          </field>
          <field>
            <name>MODER3</name>
            <bitOffset>6</bitOffset>
            <bitWidth>2</bitWidth>
          </field>
          <field>
            <name>MODER4</name>
            <bitOffset>8</bitOffset>
            <bitWidth>2</bitWidth>
          </field>
          <field>
            <name>MODER5</name>
            <bitOffset>10</bitOffset>
            <bitWidth>2</bitWidth>
          </field>
          <field>
            <name>MODER6</name>
            <bitOffset>12</bitOffset>
            <bitWidth>2</bitWidth>
          </field>
          <field>
            <name>MODER7</name>
            <bitOffset>14</bitOffset>
            <bitWidth>2</bitWidth>
          </field>
          <field>
            <name>MODER8</name>
            <bitOffset>16</bitOffset>
            <bitWidth>2</bitWidth>
          </field>
          <field>
            <name>MODER9</name>
            <bitOffset>18</bitOffset>
            <bitWidth>2</bitWidth>
          </field>
          <field>
            <name>MODER10</name>
            <bitOffset>20</bitOffset>
            <bitWidth>2</bitWidth>
          </field>
          <field>
            <name>MODER11</name>
            <bitOffset>22</bitOffset>
            <bitWidth>2</bitWidth>
          </field>
          <field>
            <name>MODER12</name>
            <bitOffset>24</bitOffset>
            <bitWidth>2</bitWidth>
          </field>
          <field>
            <name>MODER13</name>
            <bitOffset>26</bitOffset>
            <bitWidth>2</bitWidth>
          </field>
          <field>
            <name>MODER14</name>
            <bitOffset>28</bitOffset>
            <bitWidth>2</bitWidth>
          </field>
          <field>
            <name>MODER15</name>
            <bitOffset>30</bitOffset>
            <bitWidth>2</bitWidth>
          </field>
        </fields>
      </register>
      <register>
        <name>OTYPER</name>
        <addressOffset>0x4</addressOffset>
        <size>0x20</size>
        <fields>
          <field>
            <name>OT0</name>
            <bitOffset>0</bitOffset>
            <bitWidth>1</bitWidth>
          </field>
          <field>
            <name>OT1</name>
            <bitOffset>1</bitOffset>
            <bitWidth>1</bitWidth>
          </field>
          <field>
            <name>OT2</name>
            <bitOffset>2</bitOffset>
            <bitWidth>1</bitWidth>
          </field>
          <field>
            <name>OT3</name>
            <bitOffset>3</bitOffset>
            <bitWidth>1</bitWidth>
          </field>
          <field>
            <name>OT4</name>
            <bitOffset>4</bitOffset>
            <bitWidth>1</bitWidth>
          </field>
          <field>
            <name>OT5</name>
            <bitOffset>5</bitOffset>
            <bitWidth>1</bitWidth>
          </field>
          <field>
            <name>OT6</name>
            <bitOffset>6</bitOffset>
            <bitWidth>1</bitWidth>
          </field>
          <field>
            <name>OT7</name>
            <bitOffset>7</bitOffset>
            <bitWidth>1</bitWidth>
          </field>
          <field>
            <name>OT8</name>
            <bitOffset>8</bitOffset>
            <bitWidth>1</bitWidth>
          </field>
          <field>
            <name>OT9</name>
            <bitOffset>9</bitOffset>
            <bitWidth>1</bitWidth>
          </field>
          <field>
            <name>OT10</name>
            <bitOffset>10</bitOffset>
            <bitWidth>1</bitWidth>
          </field>
          <field>
            <name>OT11</name>
            <bitOffset>11</bitOffset>
            <bitWidth>1</bitWidth>
          </field>
          <field>
            <name>OT12</name>
            <bitOffset>12</bitOffset>
            <bitWidth>1</bitWidth>
          </field>
          <field>
            <name>OT13</name>
            <bitOffset>13</bitOffset>
            <bitWidth>1</bitWidth>
          </field>
          <field>
            <name>OT14</name>
            <bitOffset>14</bitOffset>
            <bitWidth>1</bitWidth>
          </field>
          <field>
            <name>OT15</name>
            <bitOffset>15</bitOffset>
            <bitWidth>1</bitWidth>
          </field>
        </fields>
      </register>
      <register>
        <name>OSPEEDR</name>
        <addressOffset>0x8</addressOffset>
        <size>0x20</size>
        <fields>
          <field>
            <name>OSPEED0</name>
            <bitOffset>0</bitOffset>
            <bitWidth>2</bitWidth>
          </field>
          <field>
            <name>OSPEED1</name>
            <bitOffset>2</bitOffset>
            <bitWidth>2</bitWidth>
          </field>
          <field>
            <name>OSPEED2</name>
            <bitOffset>4</bitOffset>
            <bitWidth>2</bitWidth>
          </field>
          <field>
            <name>OSPEED3</name>
            <bitOffset>6</bitOffset>
            <bitWidth>2</bitWidth>
          </field>
          <field>
            <name>OSPEED4</name>
            <bitOffset>8</bitOffset>
            <bitWidth>2</bitWidth>
          </field>
          <field>
            <name>OSPEED5</name>
            <bitOffset>10</bitOffset>
            <bitWidth>2</bitWidth>
          </field>
          <field>
            <name>OSPEED6</name>
            <bitOffset>12</bitOffset>
            <bitWidth>2</bitWidth>
          </field>
          <field>
            <name>OSPEED7</name>
            <bitOffset>14</bitOffset>
            <bitWidth>2</bitWidth>
          </field>
          <field>
            <name>OSPEED8</name>
            <bitOffset>16</bitOffset>
            <bitWidth>2</bitWidth>
          </field>
          <field>
            <name>OSPEED9</name>
            <bitOffset>18</bitOffset>
            <bitWidth>2</bitWidth>
          </field>
          <field>
            <name>OSPEED10</name>
            <bitOffset>20</bitOffset>
            <bitWidth>2</bitWidth>
          </field>
          <field>
            <name>OSPEED11</name>
            <bitOffset>22</bitOffset>
            <bitWidth>2</bitWidth>
          </field>
          <field>
            <name>OSPEED12</name>
            <bitOffset>24</bitOffset>
            <bitWidth>2</bitWidth>
          </field>
          <field>
            <name>OSPEED13</name>
            <bitOffset>26</bitOffset>
            <bitWidth>2</bitWidth>
          </field>
          <field>
            <name>OSPEED14</name>
            <bitOffset>28</bitOffset>
            <bitWidth>2</bitWidth>
          </field>
          <field>
            <name>OSPEED15</name>
            <bitOffset>30</bitOffset>
            <bitWidth>2</bitWidth>
          </field>
        </fields>
      </register>
      <register>
        <name>PUPDR</name>
        <addressOffset>0xc</addressOffset>
        <size>0x20</size>
        <fields>
          <field>
            <name>PUPD0</name>
            <bitOffset>0</bitOffset>
            <bitWidth>2</bitWidth>
          </field>
          <field>
            <name>PUPD1</name>
            <bitOffset>2</bitOffset>
            <bitWidth>2</bitWidth>
          </field>
          <field>
            <name>PUPD2</name>
            <bitOffset>4</bitOffset>
            <bitWidth>2</bitWidth>
          </field>
          <field>
            <name>PUPD3</name>
            <bitOffset>6</bitOffset>
            <bitWidth>2</bitWidth>
          </field>
          <field>
            <name>PUPD4</name>
            <bitOffset>8</bitOffset>
            <bitWidth>2</bitWidth>
          </field>
          <field>
            <name>PUPD5</name>
            <bitOffset>10</bitOffset>
            <bitWidth>2</bitWidth>
          </field>
          <field>
            <name>PUPD6</name>
            <bitOffset>12</bitOffset>
            <bitWidth>2</bitWidth>
          </field>
          <field>
            <name>PUPD7</name>
            <bitOffset>14</bitOffset>
            <bitWidth>2</bitWidth>
          </field>
          <field>
            <name>PUPD8</name>
            <bitOffset>16</bitOffset>
            <bitWidth>2</bitWidth>
          </field>
          <field>
            <name>PUPD9</name>
            <bitOffset>18</bitOffset>
            <bitWidth>2</bitWidth>
          </field>
          <field>
            <name>PUPD10</name>
            <bitOffset>20</bitOffset>
            <bitWidth>2</bitWidth>
          </field>
          <field>
            <name>PUPD11</name>
            <bitOffset>22</bitOffset>
            <bitWidth>2</bitWidth>
          </field>
          <field>
            <name>PUPD12</name>
            <bitOffset>24</bitOffset>
            <bitWidth>2</bitWidth>
          </field>
          <field>
            <name>PUPD13</name>
            <bitOffset>26</bitOffset>
            <bitWidth>2</bitWidth>
          </field>
          <field>
            <name>PUPD14</name>
            <bitOffset>28</bitOffset>
            <bitWidth>2</bitWidth>
          </field>
          <field>
            <name>PUPD15</name>
            <bitOffset>30</bitOffset>
            <bitWidth>2</bitWidth>
          </field>
        </fields>
      </register>
      <register>
        <name>IDR</name>
        <addressOffset>0x10</addressOffset>
        <size>0x20</size>
        <fields>
          <field>
            <name>ID0</name>
            <bitOffset>0</bitOffset>
            <bitWidth>1</bitWidth>
          </field>
          <field>
            <name>ID1</name>
            <bitOffset>1</bitOffset>
            <bitWidth>1</bitWidth>
          </field>
          <field>
            <name>ID2</name>
            <bitOffset>2</bitOffset>
            <bitWidth>1</bitWidth>
          </field>
          <field>
            <name>ID3</name>
            <bitOffset>3</bitOffset>
            <bitWidth>1</bitWidth>
          </field>
          <field>
            <name>ID4</name>
            <bitOffset>4</bitOffset>
            <bitWidth>1</bitWidth>
          </field>
          <field>
            <name>ID5</name>
            <bitOffset>5</bitOffset>
            <bitWidth>1</bitWidth>
          </field>
          <field>
            <name>ID6</name>
            <bitOffset>6</bitOffset>
            <bitWidth>1</bitWidth>
          </field>
          <field>
            <name>ID7</name>
            <bitOffset>7</bitOffset>
            <bitWidth>1</bitWidth>
          </field>
          <field>
            <name>ID8</name>
            <bitOffset>8</bitOffset>
            <bitWidth>1</bitWidth>
          </field>
          <field>
            <name>ID9</name>
            <bitOffset>9</bitOffset>
            <bitWidth>1</bitWidth>
          </field>
          <field>
            <name>ID10</name>
            <bitOffset>10</bitOffset>
            <bitWidth>1</bitWidth>
          </field>
          <field>
            <name>ID11</name>
            <bitOffset>11</bitOffset>
            <bitWidth>1</bitWidth>
          </field>
          <field>
            <name>ID12</name>
            <bitOffset>12</bitOffset>
            <bitWidth>1</bitWidth>
          </field>
          <field>
            <name>ID13</name>
            <bitOffset>13</bitOffset>
            <bitWidth>1</bitWidth>
          </field>
          <field>
            <name>ID14</name>
            <bitOffset>14</bitOffset>
            <bitWidth>1</bitWidth>
          </field>
          <field>
            <name>ID15</name>
            <bitOffset>15</bitOffset>
            <bitWidth>1</bitWidth>
          </field>
        </fields>
      </register>
      <register>
        <name>ODR</name>
        <addressOffset>0x14</addressOffset>
        <size>0x20</size>
        <fields>
          <field>
            <name>OD0</name>
            <bitOffset>0</bitOffset>
            <bitWidth>1</bitWidth>
          </field>
          <field>
            <name>OD1</name>
            <bitOffset>1</bitOffset>
            <bitWidth>1</bitWidth>
          </field>
          <field>
            <name>OD2</name>
            <bitOffset>2</bitOffset>
            <bitWidth>1</bitWidth>
          </field>
          <field>
            <name>OD3</name>
            <bitOffset>3</bitOffset>
            <bitWidth>1</bitWidth>
          </field>
          <field>
            <name>OD4</name>
            <bitOffset>4</bitOffset>
            <bitWidth>1</bitWidth>
          </field>
          <field>
            <name>OD5</name>
            <bitOffset>5</bitOffset>
            <bitWidth>1</bitWidth>
          </field>
          <field>
            <name>OD6</name>
            <bitOffset>6</bitOffset>
            <bitWidth>1</bitWidth>
          </field>
          <field>
            <name>OD7</name>
            <bitOffset>7</bitOffset>
            <bitWidth>1</bitWidth>
          </field>
          <field>
            <name>OD8</name>
            <bitOffset>8</bitOffset>
            <bitWidth>1</bitWidth>
          </field>
          <field>
            <name>OD9</name>
            <bitOffset>9</bitOffset>
            <bitWidth>1</bitWidth>
          </field>
          <field>
            <name>OD10</name>
            <bitOffset>10</bitOffset>
            <bitWidth>1</bitWidth>
          </field>
          <field>
            <name>OD11</name>
            <bitOffset>11</bitOffset>
            <bitWidth>1</bitWidth>
          </field>
          <field>
            <name>OD12</name>
            <bitOffset>12</bitOffset>
            <bitWidth>1</bitWidth>
          </field>
          <field>
            <name>OD13</name>
            <bitOffset>13</bitOffset>
            <bitWidth>1</bitWidth>
          </field>
          <field>
            <name>OD14</name>
            <bitOffset>14</bitOffset>
            <bitWidth>1</bitWidth>
          </field>
          <field>
            <name>OD15</name>
            <bitOffset>15</bitOffset>
            <bitWidth>1</bitWidth>
          </field>
        </fields>
      </register>
      <register>
        <name>BSRR</name>
        <addressOffset>0x18</addressOffset>
        <size>0x20</size>
        <fields>
          <field>
            <name>BS0</name>
            <bitOffset>0</bitOffset>
            <bitWidth>1</bitWidth>
          </field>
          <field>
            <name>BS1</name>
            <bitOffset>1</bitOffset>
            <bitWidth>1</bitWidth>
          </field>
          <field>
            <name>BS2</name>
            <bitOffset>2</bitOffset>
            <bitWidth>1</bitWidth>
          </field>
          <field>
            <name>BS3</name>
            <bitOffset>3</bitOffset>
            <bitWidth>1</bitWidth>
          </field>
          <field>
            <name>BS4</name>
            <bitOffset>4</bitOffset>
            <bitWidth>1</bitWidth>
          </field>
          <field>
            <name>BS5</name>
            <bitOffset>5</bitOffset>
            <bitWidth>1</bitWidth>
          </field>
          <field>
            <name>BS6</name>
            <bitOffset>6</bitOffset>
            <bitWidth>1</bitWidth>
          </field>
          <field>
            <name>BS7</name>
            <bitOffset>7</bitOffset>
            <bitWidth>1</bitWidth>
          </field>
          <field>
            <name>BS8</name>
            <bitOffset>8</bitOffset>
            <bitWidth>1</bitWidth>
          </field>
          <field>
            <name>BS9</name>
            <bitOffset>9</bitOffset>
            <bitWidth>1</bitWidth>
          </field>
          <field>
            <name>BS10</name>
            <bitOffset>10</bitOffset>
            <bitWidth>1</bitWidth>
          </field>
          <field>
            <name>BS11</name>
            <bitOffset>11</bitOffset>
            <bitWidth>1</bitWidth>
          </field>
          <field>
            <name>BS12</name>
            <bitOffset>12</bitOffset>
            <bitWidth>1</bitWidth>
          </field>
          <field>
            <name>BS13</name>
            <bitOffset>13</bitOffset>
            <bitWidth>1</bitWidth>
          </field>
          <field>
            <name>BS14</name>
            <bitOffset>14</bitOffset>
            <bitWidth>1</bitWidth>
          </field>
          <field>
            <name>BS15</name>
            <bitOffset>15</bitOffset>
            <bitWidth>1</bitWidth>
          </field>
          <field>
            <name>BR0</name>
            <bitOffset>16</bitOffset>
            <bitWidth>1</bitWidth>
          </field>
          <field>
            <name>BR1</name>
            <bitOffset>17</bitOffset>
            <bitWidth>1</bitWidth>
          </field>
          <field>
            <name>BR2</name>
            <bitOffset>18</bitOffset>
            <bitWidth>1</bitWidth>
          </field>
          <field>
            <name>BR3</name>
            <bitOffset>19</bitOffset>
            <bitWidth>1</bitWidth>
          </field>
          <field>
            <name>BR4</name>
            <bitOffset>20</bitOffset>
            <bitWidth>1</bitWidth>
          </field>
          <field>
            <name>BR5</name>
            <bitOffset>21</bitOffset>
            <bitWidth>1</bitWidth>
          </field>
          <field>
            <name>BR6</name>
            <bitOffset>22</bitOffset>
            <bitWidth>1</bitWidth>
          </field>
          <field>
            <name>BR7</name>
            <bitOffset>23</bitOffset>
            <bitWidth>1</bitWidth>
          </field>
          <field>
            <name>BR8</name>
            <bitOffset>24</bitOffset>
            <bitWidth>1</bitWidth>
          </field>
          <field>
            <name>BR9</name>
            <bitOffset>25</bitOffset>
            <bitWidth>1</bitWidth>
          </field>
          <field>
            <name>BR10</name>
            <bitOffset>26</bitOffset>
            <bitWidth>1</bitWidth>
          </field>
          <field>
            <name>BR11</name>
            <bitOffset>27</bitOffset>
            <bitWidth>1</bitWidth>
          </field>
          <field>
            <name>BR12</name>
            <bitOffset>28</bitOffset>
            <bitWidth>1</bitWidth>
          </field>
          <field>
            <name>BR13</name>
            <bitOffset>29</bitOffset>
            <bitWidth>1</bitWidth>
          </field>
          <field>
            <name>BR14</name>
            <bitOffset>30</bitOffset>
            <bitWidth>1</bitWidth>
          </field>
          <field>
            <name>BR15</name>
            <bitOffset>31</bitOffset>
            <bitWidth>1</bitWidth>
          </field>
        </fields>
      </register>
      <register>
        <name>LCKR</name>
        <addressOffset>0x1c</addressOffset>
        <size>0x20</size>
      </register>
      <register>
        <name>AFR.0</name>
        <addressOffset>0x20</addressOffset>
        <size>0x20</size>
      </register>
      <register>
        <name>AFR.1</name>
        <addressOffset>0x24</addressOffset>
        <size>0x20</size>
        <fields>
          <field>
            <name>AFSEL8</name>
            <bitOffset>0</bitOffset>
            <bitWidth>4</bitWidth>
          </field>
          <field>
            <name>AFSEL9</name>
            <bitOffset>4</bitOffset>
            <bitWidth>4</bitWidth>
          </field>
          <field>
            <name>AFSEL10</name>
            <bitOffset>8</bitOffset>
            <bitWidth>4</bitWidth>
          </field>
          <field>
            <name>AFSEL11</name>
            <bitOffset>12</bitOffset>
            <bitWidth>4</bitWidth>
          </field>
          <field>
            <name>AFSEL12</name>
            <bitOffset>16</bitOffset>
            <bitWidth>4</bitWidth>
          </field>
          <field>
            <name>AFSEL13</name>
            <bitOffset>20</bitOffset>
            <bitWidth>4</bitWidth>
          </field>
          <field>
            <name>AFSEL14</name>
            <bitOffset>24</bitOffset>
            <bitWidth>4</bitWidth>
          </field>
          <field>
            <name>AFSEL15</name>
            <bitOffset>28</bitOffset>
            <bitWidth>4</bitWidth>
          </field>
        </fields>
      </register>
    </peripheral>
    <peripheral>
      <name>GPIOD</name>
      <baseAddress>0x40020c00</baseAddress>
      <register>
        <name>MODER</name>
        <addressOffset>0x0</addressOffset>
        <size>0x20</size>
        <fields>
          <field>
            <name>MODER0</name>
            <bitOffset>0</bitOffset>
            <bitWidth>2</bitWidth>
          </field>
          <field>
            <name>MODER1</name>
            <bitOffset>2</bitOffset>
            <bitWidth>2</bitWidth>
          </field>
          <field>
            <name>MODER2</name>
            <bitOffset>4</bitOffset>
            <bitWidth>2</bitWidth>
          </field>
          <field>
            <name>MODER3</name>
            <bitOffset>6</bitOffset>
            <bitWidth>2</bitWidth>
          </field>
          <field>
            <name>MODER4</name>
            <bitOffset>8</bitOffset>
            <bitWidth>2</bitWidth>
          </field>
          <field>
            <name>MODER5</name>
            <bitOffset>10</bitOffset>
            <bitWidth>2</bitWidth>
          </field>
          <field>
            <name>MODER6</name>
            <bitOffset>12</bitOffset>
            <bitWidth>2</bitWidth>
          </field>
          <field>
            <name>MODER7</name>
            <bitOffset>14</bitOffset>
            <bitWidth>2</bitWidth>
          </field>
          <field>
            <name>MODER8</name>
            <bitOffset>16</bitOffset>
            <bitWidth>2</bitWidth>
          </field>
          <field>
            <name>MODER9</name>
            <bitOffset>18</bitOffset>
            <bitWidth>2</bitWidth>
          </field>
          <field>
            <name>MODER10</name>
            <bitOffset>20</bitOffset>
            <bitWidth>2</bitWidth>
          </field>
          <field>
            <name>MODER11</name>
            <bitOffset>22</bitOffset>
            <bitWidth>2</bitWidth>
          </field>
          <field>
            <name>MODER12</name>
            <bitOffset>24</bitOffset>
            <bitWidth>2</bitWidth>
          </field>
          <field>
            <name>MODER13</name>
            <bitOffset>26</bitOffset>
            <bitWidth>2</bitWidth>
          </field>
          <field>
            <name>MODER14</name>
            <bitOffset>28</bitOffset>
            <bitWidth>2</bitWidth>
          </field>
          <field>
            <name>MODER15</name>
            <bitOffset>30</bitOffset>
            <bitWidth>2</bitWidth>
          </field>
        </fields>
      </register>
      <register>
        <name>OTYPER</name>
        <addressOffset>0x4</addressOffset>
        <size>0x20</size>
        <fields>
          <field>
            <name>OT0</name>
            <bitOffset>0</bitOffset>
            <bitWidth>1</bitWidth>
          </field>
          <field>
            <name>OT1</name>
            <bitOffset>1</bitOffset>
            <bitWidth>1</bitWidth>
          </field>
          <field>
            <name>OT2</name>
            <bitOffset>2</bitOffset>
            <bitWidth>1</bitWidth>
          </field>
          <field>
            <name>OT3</name>
            <bitOffset>3</bitOffset>
            <bitWidth>1</bitWidth>
          </field>
          <field>
            <name>OT4</name>
            <bitOffset>4</bitOffset>
            <bitWidth>1</bitWidth>
          </field>
          <field>
            <name>OT5</name>
            <bitOffset>5</bitOffset>
            <bitWidth>1</bitWidth>
          </field>
          <field>
            <name>OT6</name>
            <bitOffset>6</bitOffset>
            <bitWidth>1</bitWidth>
          </field>
          <field>
            <name>OT7</name>
            <bitOffset>7</bitOffset>
            <bitWidth>1</bitWidth>
          </field>
          <field>
            <name>OT8</name>
            <bitOffset>8</bitOffset>
            <bitWidth>1</bitWidth>
          </field>
          <field>
            <name>OT9</name>
            <bitOffset>9</bitOffset>
            <bitWidth>1</bitWidth>
          </field>
          <field>
            <name>OT10</name>
            <bitOffset>10</bitOffset>
            <bitWidth>1</bitWidth>
          </field>
          <field>
            <name>OT11</name>
            <bitOffset>11</bitOffset>
            <bitWidth>1</bitWidth>
          </field>
          <field>
            <name>OT12</name>
            <bitOffset>12</bitOffset>
            <bitWidth>1</bitWidth>
          </field>
          <field>
            <name>OT13</name>
            <bitOffset>13</bitOffset>
            <bitWidth>1</bitWidth>
          </field>
          <field>
            <name>OT14</name>
            <bitOffset>14</bitOffset>
            <bitWidth>1</bitWidth>
          </field>
          <field>
            <name>OT15</name>
            <bitOffset>15</bitOffset>
            <bitWidth>1</bitWidth>
          </field>
        </fields>
      </register>
      <register>
        <name>OSPEEDR</name>
        <addressOffset>0x8</addressOffset>
        <size>0x20</size>
        <fields>
          <field>
            <name>OSPEED0</name>
            <bitOffset>0</bitOffset>
            <bitWidth>2</bitWidth>
          </field>
          <field>
            <name>OSPEED1</name>
            <bitOffset>2</bitOffset>
            <bitWidth>2</bitWidth>
          </field>
          <field>
            <name>OSPEED2</name>
            <bitOffset>4</bitOffset>
            <bitWidth>2</bitWidth>
          </field>
          <field>
            <name>OSPEED3</name>
            <bitOffset>6</bitOffset>
            <bitWidth>2</bitWidth>
          </field>
          <field>
            <name>OSPEED4</name>
            <bitOffset>8</bitOffset>
            <bitWidth>2</bitWidth>
          </field>
          <field>
            <name>OSPEED5</name>
            <bitOffset>10</bitOffset>
            <bitWidth>2</bitWidth>
          </field>
          <field>
            <name>OSPEED6</name>
            <bitOffset>12</bitOffset>
            <bitWidth>2</bitWidth>
          </field>
